              <bitWidth>12</bitWidth>
            </field>
            <field>
              <name>DACC2DHR</name>
              <bitOffset>16</bitOffset>
              <bitWidth>12</bitWidth>
            </field>
          </fields>
        </register>
        <register>
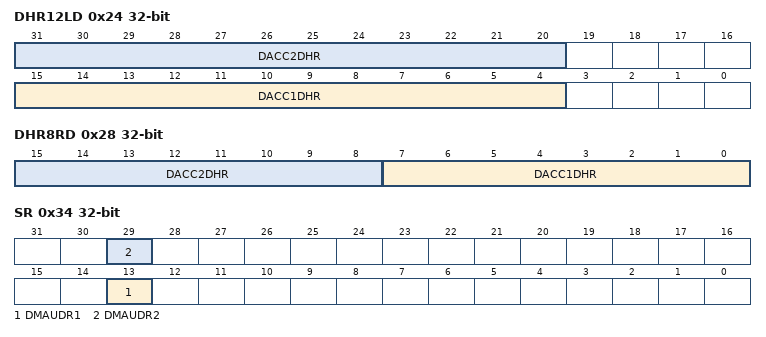
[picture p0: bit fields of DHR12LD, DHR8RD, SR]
          <name>DHR12LD</name>
          <addressOffset>0x24</addressOffset>
          <size>0x20</size>
          <fields>
            <field>
              <name>DACC1DHR</name>
              <bitOffset>4</bitOffset>
              <bitWidth>12</bitWidth>
            </field>
            <field>
              <name>DACC2DHR</name>
              <bitOffset>20</bitOffset>
              <bitWidth>12</bitWidth>
            </field>
          </fields>
        </register>
        <register>
          <name>DHR8RD</name>
          <addressOffset>0x28</addressOffset>
          <size>0x20</size>
          <fields>
            <field>
              <name>DACC1DHR</name>
              <bitOffset>0</bitOffset>
              <bitWidth>8</bitWidth>
            </field>
            <field>
              <name>DACC2DHR</name>
              <bitOffset>8</bitOffset>
              <bitWidth>8</bitWidth>
            </field>
          </fields>
        </register>
        <register>
          <name>DOR1</name>
          <addressOffset>0x2c</addressOffset>
          <size>0x20</size>
          <fields>
            <field>
              <name>DACC1DOR</name>
              <bitOffset>0</bitOffset>
              <bitWidth>12</bitWidth>
            </field>
          </fields>
        </register>
        <register>
          <name>DOR2</name>
          <addressOffset>0x30</addressOffset>
          <size>0x20</size>
          <fields>
            <field>
              <name>DACC2DOR</name>
              <bitOffset>0</bitOffset>
              <bitWidth>12</bitWidth>
            </field>
          </fields>
        </register>
        <register>
          <name>SR</name>
          <addressOffset>0x34</addressOffset>
          <size>0x20</size>
          <fields>
            <field>
              <name>DMAUDR1</name>
              <bitOffset>13</bitOffset>
              <bitWidth>1</bitWidth>
            </field>
            <field>
              <name>DMAUDR2</name>
              <bitOffset>29</bitOffset>
              <bitWidth>1</bitWidth>
            </field>
          </fields>
        </register>
      </registers>
    </peripheral>
    <peripheral>
      <name>UART7</name>
      <baseAddress>0x40007800</baseAddress>
      <registers>
        <register>
          <name>CR1</name>
          <addressOffset>0x0</addressOffset>
          <size>0x20</size>
          <fields>
            <field>
              <name>UE</name>
              <bitOffset>0</bitOffset>
              <bitWidth>1</bitWidth>
            </field>
            <field>
              <name>UESM</name>
              <bitOffset>1</bitOffset>
              <bitWidth>1</bitWidth>
            </field>
            <field>
              <name>RE</name>
              <bitOffset>2</bitOffset>
              <bitWidth>1</bitWidth>
            </field>
            <field>
              <name>TE</name>
              <bitOffset>3</bitOffset>
              <bitWidth>1</bitWidth>
            </field>
            <field>
              <name>IDLEIE</name>
              <bitOffset>4</bitOffset>
              <bitWidth>1</bitWidth>
            </field>
            <field>
              <name>RXNEIE</name>
              <bitOffset>5</bitOffset>
              <bitWidth>1</bitWidth>
            </field>
            <field>
              <name>TCIE</name>
              <bitOffset>6</bitOffset>
              <bitWidth>1</bitWidth>
            </field>
            <field>
              <name>TXEIE</name>
              <bitOffset>7</bitOffset>
              <bitWidth>1</bitWidth>
            </field>
            <field>
              <name>PEIE</name>
              <bitOffset>8</bitOffset>
              <bitWidth>1</bitWidth>
            </field>
            <field>
              <name>PS</name>
              <bitOffset>9</bitOffset>
              <bitWidth>1</bitWidth>
            </field>
            <field>
              <name>PCE</name>
              <bitOffset>10</bitOffset>
              <bitWidth>1</bitWidth>
            </field>
            <field>
              <name>WAKE</name>
              <bitOffset>11</bitOffset>
              <bitWidth>1</bitWidth>
            </field>
            <field>
              <name>M</name>
              <bitOffset>12</bitOffset>
              <bitWidth>17</bitWidth>
            </field>
            <field>
              <name>MME</name>
              <bitOffset>13</bitOffset>
              <bitWidth>1</bitWidth>
            </field>
            <field>
              <name>CMIE</name>
              <bitOffset>14</bitOffset>
              <bitWidth>1</bitWidth>
            </field>
            <field>
              <name>OVER8</name>
              <bitOffset>15</bitOffset>
              <bitWidth>1</bitWidth>
            </field>
            <field>
              <name>DEDT</name>
              <bitOffset>16</bitOffset>
              <bitWidth>5</bitWidth>
            </field>
            <field>
              <name>DEAT</name>
              <bitOffset>21</bitOffset>
              <bitWidth>5</bitWidth>
            </field>
            <field>
              <name>RTOIE</name>
              <bitOffset>26</bitOffset>
              <bitWidth>1</bitWidth>
            </field>
            <field>
              <name>EOBIE</name>
              <bitOffset>27</bitOffset>
              <bitWidth>1</bitWidth>
            </field>
          </fields>
        </register>
        <register>
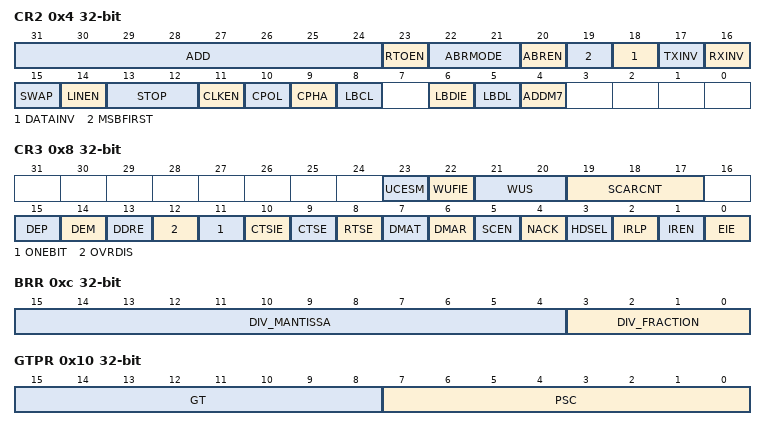
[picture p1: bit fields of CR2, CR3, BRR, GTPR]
          <name>CR2</name>
          <addressOffset>0x4</addressOffset>
          <size>0x20</size>
          <fields>
            <field>
              <name>ADDM7</name>
              <bitOffset>4</bitOffset>
              <bitWidth>1</bitWidth>
            </field>
            <field>
              <name>LBDL</name>
              <bitOffset>5</bitOffset>
              <bitWidth>1</bitWidth>
            </field>
            <field>
              <name>LBDIE</name>
              <bitOffset>6</bitOffset>
              <bitWidth>1</bitWidth>
            </field>
            <field>
              <name>LBCL</name>
              <bitOffset>8</bitOffset>
              <bitWidth>1</bitWidth>
            </field>
            <field>
              <name>CPHA</name>
              <bitOffset>9</bitOffset>
              <bitWidth>1</bitWidth>
            </field>
            <field>
              <name>CPOL</name>
              <bitOffset>10</bitOffset>
              <bitWidth>1</bitWidth>
            </field>
            <field>
              <name>CLKEN</name>
              <bitOffset>11</bitOffset>
              <bitWidth>1</bitWidth>
            </field>
            <field>
              <name>STOP</name>
              <bitOffset>12</bitOffset>
              <bitWidth>2</bitWidth>
            </field>
            <field>
              <name>LINEN</name>
              <bitOffset>14</bitOffset>
              <bitWidth>1</bitWidth>
            </field>
            <field>
              <name>SWAP</name>
              <bitOffset>15</bitOffset>
              <bitWidth>1</bitWidth>
            </field>
            <field>
              <name>RXINV</name>
              <bitOffset>16</bitOffset>
              <bitWidth>1</bitWidth>
            </field>
            <field>
              <name>TXINV</name>
              <bitOffset>17</bitOffset>
              <bitWidth>1</bitWidth>
            </field>
            <field>
              <name>DATAINV</name>
              <bitOffset>18</bitOffset>
              <bitWidth>1</bitWidth>
            </field>
            <field>
              <name>MSBFIRST</name>
              <bitOffset>19</bitOffset>
              <bitWidth>1</bitWidth>
            </field>
            <field>
              <name>ABREN</name>
              <bitOffset>20</bitOffset>
              <bitWidth>1</bitWidth>
            </field>
            <field>
              <name>ABRMODE</name>
              <bitOffset>21</bitOffset>
              <bitWidth>2</bitWidth>
            </field>
            <field>
              <name>RTOEN</name>
              <bitOffset>23</bitOffset>
              <bitWidth>1</bitWidth>
            </field>
            <field>
              <name>ADD</name>
              <bitOffset>24</bitOffset>
              <bitWidth>8</bitWidth>
            </field>
          </fields>
        </register>
        <register>
          <name>CR3</name>
          <addressOffset>0x8</addressOffset>
          <size>0x20</size>
          <fields>
            <field>
              <name>EIE</name>
              <bitOffset>0</bitOffset>
              <bitWidth>1</bitWidth>
            </field>
            <field>
              <name>IREN</name>
              <bitOffset>1</bitOffset>
              <bitWidth>1</bitWidth>
            </field>
            <field>
              <name>IRLP</name>
              <bitOffset>2</bitOffset>
              <bitWidth>1</bitWidth>
            </field>
            <field>
              <name>HDSEL</name>
              <bitOffset>3</bitOffset>
              <bitWidth>1</bitWidth>
            </field>
            <field>
              <name>NACK</name>
              <bitOffset>4</bitOffset>
              <bitWidth>1</bitWidth>
            </field>
            <field>
              <name>SCEN</name>
              <bitOffset>5</bitOffset>
              <bitWidth>1</bitWidth>
            </field>
            <field>
              <name>DMAR</name>
              <bitOffset>6</bitOffset>
              <bitWidth>1</bitWidth>
            </field>
            <field>
              <name>DMAT</name>
              <bitOffset>7</bitOffset>
              <bitWidth>1</bitWidth>
            </field>
            <field>
              <name>RTSE</name>
              <bitOffset>8</bitOffset>
              <bitWidth>1</bitWidth>
            </field>
            <field>
              <name>CTSE</name>
              <bitOffset>9</bitOffset>
              <bitWidth>1</bitWidth>
            </field>
            <field>
              <name>CTSIE</name>
              <bitOffset>10</bitOffset>
              <bitWidth>1</bitWidth>
            </field>
            <field>
              <name>ONEBIT</name>
              <bitOffset>11</bitOffset>
              <bitWidth>1</bitWidth>
            </field>
            <field>
              <name>OVRDIS</name>
              <bitOffset>12</bitOffset>
              <bitWidth>1</bitWidth>
            </field>
            <field>
              <name>DDRE</name>
              <bitOffset>13</bitOffset>
              <bitWidth>1</bitWidth>
            </field>
            <field>
              <name>DEM</name>
              <bitOffset>14</bitOffset>
              <bitWidth>1</bitWidth>
            </field>
            <field>
              <name>DEP</name>
              <bitOffset>15</bitOffset>
              <bitWidth>1</bitWidth>
            </field>
            <field>
              <name>SCARCNT</name>
              <bitOffset>17</bitOffset>
              <bitWidth>3</bitWidth>
            </field>
            <field>
              <name>WUS</name>
              <bitOffset>20</bitOffset>
              <bitWidth>2</bitWidth>
            </field>
            <field>
              <name>WUFIE</name>
              <bitOffset>22</bitOffset>
              <bitWidth>1</bitWidth>
            </field>
            <field>
              <name>UCESM</name>
              <bitOffset>23</bitOffset>
              <bitWidth>1</bitWidth>
            </field>
          </fields>
        </register>
        <register>
          <name>BRR</name>
          <addressOffset>0xc</addressOffset>
          <size>0x20</size>
          <fields>
            <field>
              <name>DIV_FRACTION</name>
              <bitOffset>0</bitOffset>
              <bitWidth>4</bitWidth>
            </field>
            <field>
              <name>DIV_MANTISSA</name>
              <bitOffset>4</bitOffset>
              <bitWidth>12</bitWidth>
            </field>
          </fields>
        </register>
        <register>
          <name>GTPR</name>
          <addressOffset>0x10</addressOffset>
          <size>0x20</size>
          <fields>
            <field>
              <name>PSC</name>
              <bitOffset>0</bitOffset>
              <bitWidth>8</bitWidth>
            </field>
            <field>
              <name>GT</name>
              <bitOffset>8</bitOffset>
              <bitWidth>8</bitWidth>
            </field>
          </fields>
        </register>
        <register>
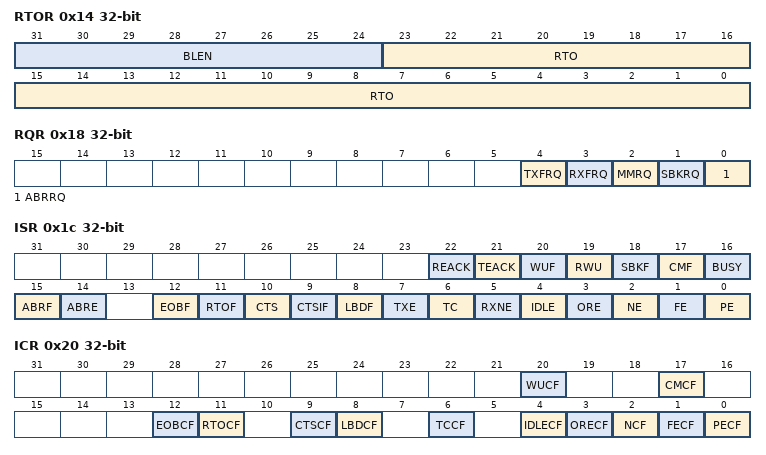
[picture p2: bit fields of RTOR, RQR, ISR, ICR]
          <name>RTOR</name>
          <addressOffset>0x14</addressOffset>
          <size>0x20</size>
          <fields>
            <field>
              <name>RTO</name>
              <bitOffset>0</bitOffset>
              <bitWidth>24</bitWidth>
            </field>
            <field>
              <name>BLEN</name>
              <bitOffset>24</bitOffset>
              <bitWidth>8</bitWidth>
            </field>
          </fields>
        </register>
        <register>
          <name>RQR</name>
          <addressOffset>0x18</addressOffset>
          <size>0x20</size>
          <fields>
            <field>
              <name>ABRRQ</name>
              <bitOffset>0</bitOffset>
              <bitWidth>1</bitWidth>
            </field>
            <field>
              <name>SBKRQ</name>
              <bitOffset>1</bitOffset>
              <bitWidth>1</bitWidth>
            </field>
            <field>
              <name>MMRQ</name>
              <bitOffset>2</bitOffset>
              <bitWidth>1</bitWidth>
            </field>
            <field>
              <name>RXFRQ</name>
              <bitOffset>3</bitOffset>
              <bitWidth>1</bitWidth>
            </field>
            <field>
              <name>TXFRQ</name>
              <bitOffset>4</bitOffset>
              <bitWidth>1</bitWidth>
            </field>
          </fields>
        </register>
        <register>
          <name>ISR</name>
          <addressOffset>0x1c</addressOffset>
          <size>0x20</size>
          <fields>
            <field>
              <name>PE</name>
              <bitOffset>0</bitOffset>
              <bitWidth>1</bitWidth>
            </field>
            <field>
              <name>FE</name>
              <bitOffset>1</bitOffset>
              <bitWidth>1</bitWidth>
            </field>
            <field>
              <name>NE</name>
              <bitOffset>2</bitOffset>
              <bitWidth>1</bitWidth>
            </field>
            <field>
              <name>ORE</name>
              <bitOffset>3</bitOffset>
              <bitWidth>1</bitWidth>
            </field>
            <field>
              <name>IDLE</name>
              <bitOffset>4</bitOffset>
              <bitWidth>1</bitWidth>
            </field>
            <field>
              <name>RXNE</name>
              <bitOffset>5</bitOffset>
              <bitWidth>1</bitWidth>
            </field>
            <field>
              <name>TC</name>
              <bitOffset>6</bitOffset>
              <bitWidth>1</bitWidth>
            </field>
            <field>
              <name>TXE</name>
              <bitOffset>7</bitOffset>
              <bitWidth>1</bitWidth>
            </field>
            <field>
              <name>LBDF</name>
              <bitOffset>8</bitOffset>
              <bitWidth>1</bitWidth>
            </field>
            <field>
              <name>CTSIF</name>
              <bitOffset>9</bitOffset>
              <bitWidth>1</bitWidth>
            </field>
            <field>
              <name>CTS</name>
              <bitOffset>10</bitOffset>
              <bitWidth>1</bitWidth>
            </field>
            <field>
              <name>RTOF</name>
              <bitOffset>11</bitOffset>
              <bitWidth>1</bitWidth>
            </field>
            <field>
              <name>EOBF</name>
              <bitOffset>12</bitOffset>
              <bitWidth>1</bitWidth>
            </field>
            <field>
              <name>ABRE</name>
              <bitOffset>14</bitOffset>
              <bitWidth>1</bitWidth>
            </field>
            <field>
              <name>ABRF</name>
              <bitOffset>15</bitOffset>
              <bitWidth>1</bitWidth>
            </field>
            <field>
              <name>BUSY</name>
              <bitOffset>16</bitOffset>
              <bitWidth>1</bitWidth>
            </field>
            <field>
              <name>CMF</name>
              <bitOffset>17</bitOffset>
              <bitWidth>1</bitWidth>
            </field>
            <field>
              <name>SBKF</name>
              <bitOffset>18</bitOffset>
              <bitWidth>1</bitWidth>
            </field>
            <field>
              <name>RWU</name>
              <bitOffset>19</bitOffset>
              <bitWidth>1</bitWidth>
            </field>
            <field>
              <name>WUF</name>
              <bitOffset>20</bitOffset>
              <bitWidth>1</bitWidth>
            </field>
            <field>
              <name>TEACK</name>
              <bitOffset>21</bitOffset>
              <bitWidth>1</bitWidth>
            </field>
            <field>
              <name>REACK</name>
              <bitOffset>22</bitOffset>
              <bitWidth>1</bitWidth>
            </field>
          </fields>
        </register>
        <register>
          <name>ICR</name>
          <addressOffset>0x20</addressOffset>
          <size>0x20</size>
          <fields>
            <field>
              <name>PECF</name>
              <bitOffset>0</bitOffset>
              <bitWidth>1</bitWidth>
            </field>
            <field>
              <name>FECF</name>
              <bitOffset>1</bitOffset>
              <bitWidth>1</bitWidth>
            </field>
            <field>
              <name>NCF</name>
              <bitOffset>2</bitOffset>
              <bitWidth>1</bitWidth>
            </field>
            <field>
              <name>ORECF</name>
              <bitOffset>3</bitOffset>
              <bitWidth>1</bitWidth>
            </field>
            <field>
              <name>IDLECF</name>
              <bitOffset>4</bitOffset>
              <bitWidth>1</bitWidth>
            </field>
            <field>
              <name>TCCF</name>
              <bitOffset>6</bitOffset>
              <bitWidth>1</bitWidth>
            </field>
            <field>
              <name>LBDCF</name>
              <bitOffset>8</bitOffset>
              <bitWidth>1</bitWidth>
            </field>
            <field>
              <name>CTSCF</name>
              <bitOffset>9</bitOffset>
              <bitWidth>1</bitWidth>
            </field>
            <field>
              <name>RTOCF</name>
              <bitOffset>11</bitOffset>
              <bitWidth>1</bitWidth>
            </field>
            <field>
              <name>EOBCF</name>
              <bitOffset>12</bitOffset>
              <bitWidth>1</bitWidth>
            </field>
            <field>
              <name>CMCF</name>
              <bitOffset>17</bitOffset>
              <bitWidth>1</bitWidth>
            </field>
            <field>
              <name>WUCF</name>
              <bitOffset>20</bitOffset>
              <bitWidth>1</bitWidth>
            </field>
          </fields>
        </register>
        <register>
          <name>RDR</name>
          <addressOffset>0x24</addressOffset>
          <size>0x20</size>
          <fields>
            <field>
              <name>RDR</name>
              <bitOffset>0</bitOffset>
              <bitWidth>9</bitWidth>
            </field>
          </fields>
        </register>
        <register>
          <name>TDR</name>
          <addressOffset>0x28</addressOffset>
          <size>0x20</size>
          <fields>
            <field>
              <name>TDR</name>
              <bitOffset>0</bitOffset>
              <bitWidth>9</bitWidth>
            </field>
          </fields>
        </register>
      </registers>
    </peripheral>
    <peripheral>
      <name>UART8</name>
      <baseAddress>0x40007c00</baseAddress>
      <registers>
        <register>
          <name>CR1</name>
          <addressOffset>0x0</addressOffset>
          <size>0x20</size>
          <fields>
            <field>
              <name>UE</name>
              <bitOffset>0</bitOffset>
              <bitWidth>1</bitWidth>
            </field>
            <field>
              <name>UESM</name>
              <bitOffset>1</bitOffset>
              <bitWidth>1</bitWidth>
            </field>
            <field>
              <name>RE</name>
              <bitOffset>2</bitOffset>
              <bitWidth>1</bitWidth>
            </field>
            <field>
              <name>TE</name>
              <bitOffset>3</bitOffset>
              <bitWidth>1</bitWidth>
            </field>
            <field>
              <name>IDLEIE</name>
              <bitOffset>4</bitOffset>
              <bitWidth>1</bitWidth>
            </field>
            <field>
              <name>RXNEIE</name>
              <bitOffset>5</bitOffset>
              <bitWidth>1</bitWidth>
            </field>
            <field>
              <name>TCIE</name>
              <bitOffset>6</bitOffset>
              <bitWidth>1</bitWidth>
            </field>
            <field>
              <name>TXEIE</name>
              <bitOffset>7</bitOffset>
              <bitWidth>1</bitWidth>
            </field>
            <field>
              <name>PEIE</name>
              <bitOffset>8</bitOffset>
              <bitWidth>1</bitWidth>
            </field>
            <field>
              <name>PS</name>
              <bitOffset>9</bitOffset>
              <bitWidth>1</bitWidth>
            </field>
            <field>
              <name>PCE</name>
              <bitOffset>10</bitOffset>
              <bitWidth>1</bitWidth>
            </field>
            <field>
              <name>WAKE</name>
              <bitOffset>11</bitOffset>
              <bitWidth>1</bitWidth>
            </field>
            <field>
              <name>M</name>
              <bitOffset>12</bitOffset>
              <bitWidth>17</bitWidth>
            </field>
            <field>
              <name>MME</name>
              <bitOffset>13</bitOffset>
              <bitWidth>1</bitWidth>
            </field>
            <field>
              <name>CMIE</name>
              <bitOffset>14</bitOffset>
              <bitWidth>1</bitWidth>
            </field>
            <field>
              <name>OVER8</name>
              <bitOffset>15</bitOffset>
              <bitWidth>1</bitWidth>
            </field>
            <field>
              <name>DEDT</name>
              <bitOffset>16</bitOffset>
              <bitWidth>5</bitWidth>
            </field>
            <field>
              <name>DEAT</name>
              <bitOffset>21</bitOffset>
              <bitWidth>5</bitWidth>
            </field>
            <field>
              <name>RTOIE</name>
              <bitOffset>26</bitOffset>
              <bitWidth>1</bitWidth>
            </field>
            <field>
              <name>EOBIE</name>
              <bitOffset>27</bitOffset>
              <bitWidth>1</bitWidth>
            </field>
          </fields>
        </register>
        <register>
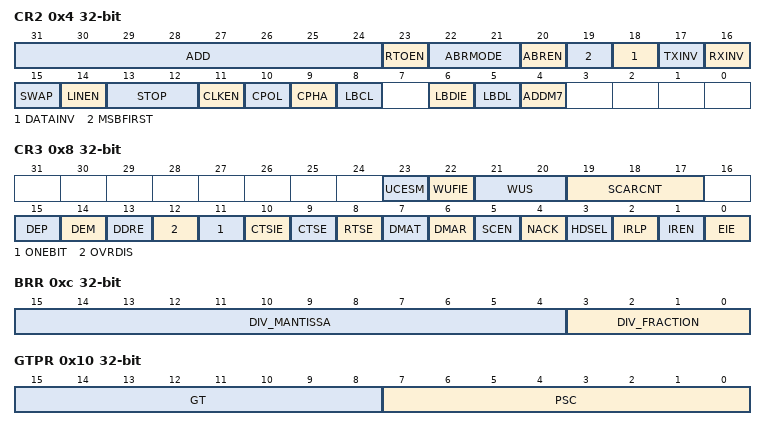
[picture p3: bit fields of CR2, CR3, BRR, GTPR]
          <name>CR2</name>
          <addressOffset>0x4</addressOffset>
          <size>0x20</size>
          <fields>
            <field>
              <name>ADDM7</name>
              <bitOffset>4</bitOffset>
              <bitWidth>1</bitWidth>
            </field>
            <field>
              <name>LBDL</name>
              <bitOffset>5</bitOffset>
              <bitWidth>1</bitWidth>
            </field>
            <field>
              <name>LBDIE</name>
              <bitOffset>6</bitOffset>
              <bitWidth>1</bitWidth>
            </field>
            <field>
              <name>LBCL</name>
              <bitOffset>8</bitOffset>
              <bitWidth>1</bitWidth>
            </field>
            <field>
              <name>CPHA</name>
              <bitOffset>9</bitOffset>
              <bitWidth>1</bitWidth>
            </field>
            <field>
              <name>CPOL</name>
              <bitOffset>10</bitOffset>
              <bitWidth>1</bitWidth>
            </field>
            <field>
              <name>CLKEN</name>
              <bitOffset>11</bitOffset>
              <bitWidth>1</bitWidth>
            </field>
            <field>
              <name>STOP</name>
              <bitOffset>12</bitOffset>
              <bitWidth>2</bitWidth>
            </field>
            <field>
              <name>LINEN</name>
              <bitOffset>14</bitOffset>
              <bitWidth>1</bitWidth>
            </field>
            <field>
              <name>SWAP</name>
              <bitOffset>15</bitOffset>
              <bitWidth>1</bitWidth>
            </field>
            <field>
              <name>RXINV</name>
              <bitOffset>16</bitOffset>
              <bitWidth>1</bitWidth>
            </field>
            <field>
              <name>TXINV</name>
              <bitOffset>17</bitOffset>
              <bitWidth>1</bitWidth>
            </field>
            <field>
              <name>DATAINV</name>
              <bitOffset>18</bitOffset>
              <bitWidth>1</bitWidth>
            </field>
            <field>
              <name>MSBFIRST</name>
              <bitOffset>19</bitOffset>
              <bitWidth>1</bitWidth>
            </field>
            <field>
              <name>ABREN</name>
              <bitOffset>20</bitOffset>
              <bitWidth>1</bitWidth>
            </field>
            <field>
              <name>ABRMODE</name>
              <bitOffset>21</bitOffset>
              <bitWidth>2</bitWidth>
            </field>
            <field>
              <name>RTOEN</name>
              <bitOffset>23</bitOffset>
              <bitWidth>1</bitWidth>
            </field>
            <field>
              <name>ADD</name>
              <bitOffset>24</bitOffset>
              <bitWidth>8</bitWidth>
            </field>
          </fields>
        </register>
        <register>
          <name>CR3</name>
          <addressOffset>0x8</addressOffset>
          <size>0x20</size>
          <fields>
            <field>
              <name>EIE</name>
              <bitOffset>0</bitOffset>
              <bitWidth>1</bitWidth>
            </field>
            <field>
              <name>IREN</name>
              <bitOffset>1</bitOffset>
              <bitWidth>1</bitWidth>
            </field>
            <field>
              <name>IRLP</name>
              <bitOffset>2</bitOffset>
              <bitWidth>1</bitWidth>
            </field>
            <field>
              <name>HDSEL</name>
              <bitOffset>3</bitOffset>
              <bitWidth>1</bitWidth>
            </field>
            <field>
              <name>NACK</name>
              <bitOffset>4</bitOffset>
              <bitWidth>1</bitWidth>
            </field>
            <field>
              <name>SCEN</name>
              <bitOffset>5</bitOffset>
              <bitWidth>1</bitWidth>
            </field>
            <field>
              <name>DMAR</name>
              <bitOffset>6</bitOffset>
              <bitWidth>1</bitWidth>
            </field>
            <field>
              <name>DMAT</name>
              <bitOffset>7</bitOffset>
              <bitWidth>1</bitWidth>
            </field>
            <field>
              <name>RTSE</name>
              <bitOffset>8</bitOffset>
              <bitWidth>1</bitWidth>
            </field>
            <field>
              <name>CTSE</name>
              <bitOffset>9</bitOffset>
              <bitWidth>1</bitWidth>
            </field>
            <field>
              <name>CTSIE</name>
              <bitOffset>10</bitOffset>
              <bitWidth>1</bitWidth>
            </field>
            <field>
              <name>ONEBIT</name>
              <bitOffset>11</bitOffset>
              <bitWidth>1</bitWidth>
            </field>
            <field>
              <name>OVRDIS</name>
              <bitOffset>12</bitOffset>
              <bitWidth>1</bitWidth>
            </field>
            <field>
              <name>DDRE</name>
              <bitOffset>13</bitOffset>
              <bitWidth>1</bitWidth>
            </field>
            <field>
              <name>DEM</name>
              <bitOffset>14</bitOffset>
              <bitWidth>1</bitWidth>
            </field>
            <field>
              <name>DEP</name>
              <bitOffset>15</bitOffset>
              <bitWidth>1</bitWidth>
            </field>
            <field>
              <name>SCARCNT</name>
              <bitOffset>17</bitOffset>
              <bitWidth>3</bitWidth>
            </field>
            <field>
              <name>WUS</name>
              <bitOffset>20</bitOffset>
              <bitWidth>2</bitWidth>
            </field>
            <field>
              <name>WUFIE</name>
              <bitOffset>22</bitOffset>
              <bitWidth>1</bitWidth>
            </field>
            <field>
              <name>UCESM</name>
              <bitOffset>23</bitOffset>
              <bitWidth>1</bitWidth>
            </field>
          </fields>
        </register>
        <register>
          <name>BRR</name>
          <addressOffset>0xc</addressOffset>
          <size>0x20</size>
          <fields>
            <field>
              <name>DIV_FRACTION</name>
              <bitOffset>0</bitOffset>
              <bitWidth>4</bitWidth>
            </field>
            <field>
              <name>DIV_MANTISSA</name>
              <bitOffset>4</bitOffset>
              <bitWidth>12</bitWidth>
            </field>
          </fields>
        </register>
        <register>
          <name>GTPR</name>
          <addressOffset>0x10</addressOffset>
          <size>0x20</size>
          <fields>
            <field>
              <name>PSC</name>
              <bitOffset>0</bitOffset>
              <bitWidth>8</bitWidth>
            </field>
            <field>
              <name>GT</name>
              <bitOffset>8</bitOffset>
              <bitWidth>8</bitWidth>
            </field>
          </fields>
        </register>
        <register>
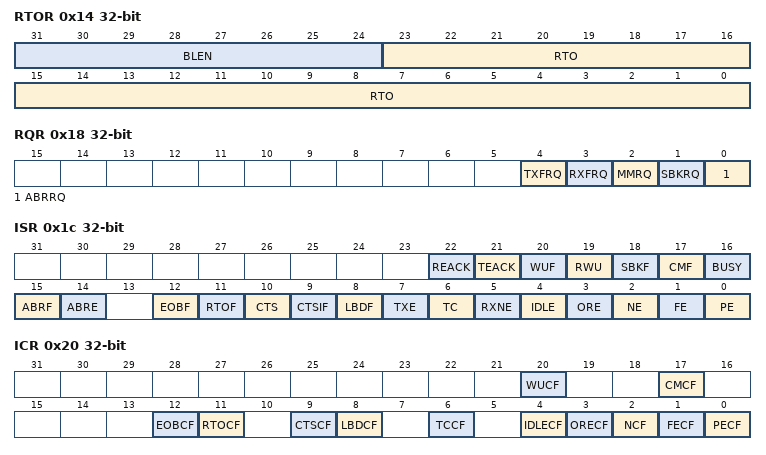
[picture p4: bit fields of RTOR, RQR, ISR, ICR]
          <name>RTOR</name>
          <addressOffset>0x14</addressOffset>
          <size>0x20</size>
          <fields>
            <field>
              <name>RTO</name>
              <bitOffset>0</bitOffset>
              <bitWidth>24</bitWidth>
            </field>
            <field>
              <name>BLEN</name>
              <bitOffset>24</bitOffset>
              <bitWidth>8</bitWidth>
            </field>
          </fields>
        </register>
        <register>
          <name>RQR</name>
          <addressOffset>0x18</addressOffset>
          <size>0x20</size>
          <fields>
            <field>
              <name>ABRRQ</name>
              <bitOffset>0</bitOffset>
              <bitWidth>1</bitWidth>
            </field>
            <field>
              <name>SBKRQ</name>
              <bitOffset>1</bitOffset>
              <bitWidth>1</bitWidth>
            </field>
            <field>
              <name>MMRQ</name>
              <bitOffset>2</bitOffset>
              <bitWidth>1</bitWidth>
            </field>
            <field>
              <name>RXFRQ</name>
              <bitOffset>3</bitOffset>
              <bitWidth>1</bitWidth>
            </field>
            <field>
              <name>TXFRQ</name>
              <bitOffset>4</bitOffset>
              <bitWidth>1</bitWidth>
            </field>
          </fields>
        </register>
        <register>
          <name>ISR</name>
          <addressOffset>0x1c</addressOffset>
          <size>0x20</size>
          <fields>
            <field>
              <name>PE</name>
              <bitOffset>0</bitOffset>
              <bitWidth>1</bitWidth>
            </field>
            <field>
              <name>FE</name>
              <bitOffset>1</bitOffset>
              <bitWidth>1</bitWidth>
            </field>
            <field>
              <name>NE</name>
              <bitOffset>2</bitOffset>
              <bitWidth>1</bitWidth>
            </field>
            <field>
              <name>ORE</name>
              <bitOffset>3</bitOffset>
              <bitWidth>1</bitWidth>
            </field>
            <field>
              <name>IDLE</name>
              <bitOffset>4</bitOffset>
              <bitWidth>1</bitWidth>
            </field>
            <field>
              <name>RXNE</name>
              <bitOffset>5</bitOffset>
              <bitWidth>1</bitWidth>
            </field>
            <field>
              <name>TC</name>
              <bitOffset>6</bitOffset>
              <bitWidth>1</bitWidth>
            </field>
            <field>
              <name>TXE</name>
              <bitOffset>7</bitOffset>
              <bitWidth>1</bitWidth>
            </field>
            <field>
              <name>LBDF</name>
              <bitOffset>8</bitOffset>
              <bitWidth>1</bitWidth>
            </field>
            <field>
              <name>CTSIF</name>
              <bitOffset>9</bitOffset>
              <bitWidth>1</bitWidth>
            </field>
            <field>
              <name>CTS</name>
              <bitOffset>10</bitOffset>
              <bitWidth>1</bitWidth>
            </field>
            <field>
              <name>RTOF</name>
              <bitOffset>11</bitOffset>
              <bitWidth>1</bitWidth>
            </field>
            <field>
              <name>EOBF</name>
              <bitOffset>12</bitOffset>
              <bitWidth>1</bitWidth>
            </field>
            <field>
              <name>ABRE</name>
              <bitOffset>14</bitOffset>
              <bitWidth>1</bitWidth>
            </field>
            <field>
              <name>ABRF</name>
              <bitOffset>15</bitOffset>
              <bitWidth>1</bitWidth>
            </field>
            <field>
              <name>BUSY</name>
              <bitOffset>16</bitOffset>
              <bitWidth>1</bitWidth>
            </field>
            <field>
              <name>CMF</name>
              <bitOffset>17</bitOffset>
              <bitWidth>1</bitWidth>
            </field>
            <field>
              <name>SBKF</name>
              <bitOffset>18</bitOffset>
              <bitWidth>1</bitWidth>
            </field>
            <field>
              <name>RWU</name>
              <bitOffset>19</bitOffset>
              <bitWidth>1</bitWidth>
            </field>
            <field>
              <name>WUF</name>
              <bitOffset>20</bitOffset>
              <bitWidth>1</bitWidth>
            </field>
            <field>
              <name>TEACK</name>
              <bitOffset>21</bitOffset>
              <bitWidth>1</bitWidth>
            </field>
            <field>
              <name>REACK</name>
              <bitOffset>22</bitOffset>
              <bitWidth>1</bitWidth>
            </field>
          </fields>
        </register>
        <register>
          <name>ICR</name>
          <addressOffset>0x20</addressOffset>
          <size>0x20</size>
          <fields>
            <field>
              <name>PECF</name>
              <bitOffset>0</bitOffset>
              <bitWidth>1</bitWidth>
            </field>
            <field>
              <name>FECF</name>
              <bitOffset>1</bitOffset>
              <bitWidth>1</bitWidth>
            </field>
            <field>
              <name>NCF</name>
              <bitOffset>2</bitOffset>
              <bitWidth>1</bitWidth>
            </field>
            <field>
              <name>ORECF</name>
              <bitOffset>3</bitOffset>
              <bitWidth>1</bitWidth>
            </field>
            <field>
              <name>IDLECF</name>
              <bitOffset>4</bitOffset>
              <bitWidth>1</bitWidth>
            </field>
            <field>
              <name>TCCF</name>
              <bitOffset>6</bitOffset>
              <bitWidth>1</bitWidth>
            </field>
            <field>
              <name>LBDCF</name>
              <bitOffset>8</bitOffset>
              <bitWidth>1</bitWidth>
            </field>
            <field>
              <name>CTSCF</name>
              <bitOffset>9</bitOffset>
              <bitWidth>1</bitWidth>
            </field>
            <field>
              <name>RTOCF</name>
              <bitOffset>11</bitOffset>
              <bitWidth>1</bitWidth>
            </field>
            <field>
              <name>EOBCF</name>
              <bitOffset>12</bitOffset>
              <bitWidth>1</bitWidth>
            </field>
            <field>
              <name>CMCF</name>
              <bitOffset>17</bitOffset>
              <bitWidth>1</bitWidth>
            </field>
            <field>
              <name>WUCF</name>
              <bitOffset>20</bitOffset>
              <bitWidth>1</bitWidth>
            </field>
          </fields>
        </register>
        <register>
          <name>RDR</name>
          <addressOffset>0x24</addressOffset>
          <size>0x20</size>
          <fields>
            <field>
              <name>RDR</name>
              <bitOffset>0</bitOffset>
              <bitWidth>9</bitWidth>
            </field>
          </fields>
        </register>
        <register>
          <name>TDR</name>
          <addressOffset>0x28</addressOffset>
          <size>0x20</size>
          <fields>
            <field>
              <name>TDR</name>
              <bitOffset>0</bitOffset>
              <bitWidth>9</bitWidth>
            </field>
          </fields>
        </register>
      </registers>
    </peripheral>
    <peripheral>
      <name>TIM1</name>
      <baseAddress>0x40010000</baseAddress>
      <registers>
        <register>
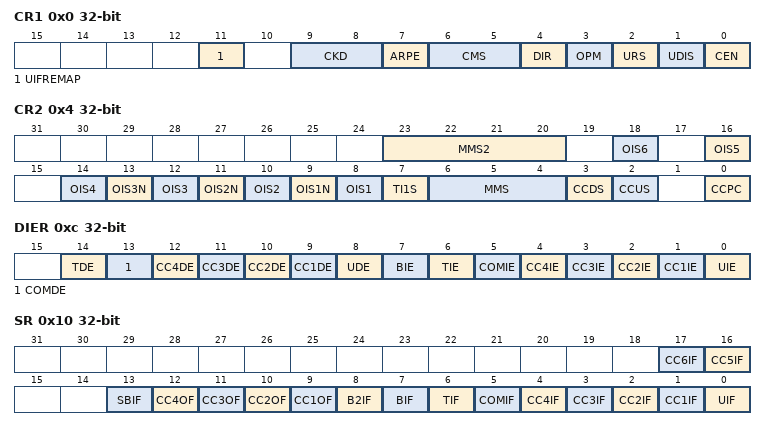
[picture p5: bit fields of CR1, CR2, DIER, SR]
          <name>CR1</name>
          <addressOffset>0x0</addressOffset>
          <size>0x20</size>
          <fields>
            <field>
              <name>CEN</name>
              <bitOffset>0</bitOffset>
              <bitWidth>1</bitWidth>
            </field>
            <field>
              <name>UDIS</name>
              <bitOffset>1</bitOffset>
              <bitWidth>1</bitWidth>
            </field>
            <field>
              <name>URS</name>
              <bitOffset>2</bitOffset>
              <bitWidth>1</bitWidth>
            </field>
            <field>
              <name>OPM</name>
              <bitOffset>3</bitOffset>
              <bitWidth>1</bitWidth>
            </field>
            <field>
              <name>DIR</name>
              <bitOffset>4</bitOffset>
              <bitWidth>1</bitWidth>
            </field>
            <field>
              <name>CMS</name>
              <bitOffset>5</bitOffset>
              <bitWidth>2</bitWidth>
            </field>
            <field>
              <name>ARPE</name>
              <bitOffset>7</bitOffset>
              <bitWidth>1</bitWidth>
            </field>
            <field>
              <name>CKD</name>
              <bitOffset>8</bitOffset>
              <bitWidth>2</bitWidth>
            </field>
            <field>
              <name>UIFREMAP</name>
              <bitOffset>11</bitOffset>
              <bitWidth>1</bitWidth>
            </field>
          </fields>
        </register>
        <register>
          <name>CR2</name>
          <addressOffset>0x4</addressOffset>
          <size>0x20</size>
          <fields>
            <field>
              <name>CCPC</name>
              <bitOffset>0</bitOffset>
              <bitWidth>1</bitWidth>
            </field>
            <field>
              <name>CCUS</name>
              <bitOffset>2</bitOffset>
              <bitWidth>1</bitWidth>
            </field>
            <field>
              <name>CCDS</name>
              <bitOffset>3</bitOffset>
              <bitWidth>1</bitWidth>
            </field>
            <field>
              <name>MMS</name>
              <bitOffset>4</bitOffset>
              <bitWidth>3</bitWidth>
            </field>
            <field>
              <name>TI1S</name>
              <bitOffset>7</bitOffset>
              <bitWidth>1</bitWidth>
            </field>
            <field>
              <name>OIS1</name>
              <bitOffset>8</bitOffset>
              <bitWidth>1</bitWidth>
            </field>
            <field>
              <name>OIS1N</name>
              <bitOffset>9</bitOffset>
              <bitWidth>1</bitWidth>
            </field>
            <field>
              <name>OIS2</name>
              <bitOffset>10</bitOffset>
              <bitWidth>1</bitWidth>
            </field>
            <field>
              <name>OIS2N</name>
              <bitOffset>11</bitOffset>
              <bitWidth>1</bitWidth>
            </field>
            <field>
              <name>OIS3</name>
              <bitOffset>12</bitOffset>
              <bitWidth>1</bitWidth>
            </field>
            <field>
              <name>OIS3N</name>
              <bitOffset>13</bitOffset>
              <bitWidth>1</bitWidth>
            </field>
            <field>
              <name>OIS4</name>
              <bitOffset>14</bitOffset>
              <bitWidth>1</bitWidth>
            </field>
            <field>
              <name>OIS5</name>
              <bitOffset>16</bitOffset>
              <bitWidth>1</bitWidth>
            </field>
            <field>
              <name>OIS6</name>
              <bitOffset>18</bitOffset>
              <bitWidth>1</bitWidth>
            </field>
            <field>
              <name>MMS2</name>
              <bitOffset>20</bitOffset>
              <bitWidth>4</bitWidth>
            </field>
          </fields>
        </register>
        <register>
          <name>SMCR</name>
          <addressOffset>0x8</addressOffset>
          <size>0x20</size>
          <fields>
            <field>
              <name>SMS</name>
              <bitOffset>0</bitOffset>
              <bitWidth>17</bitWidth>
            </field>
            <field>
              <name>TS</name>
              <bitOffset>4</bitOffset>
              <bitWidth>3</bitWidth>
            </field>
            <field>
              <name>MSM</name>
              <bitOffset>7</bitOffset>
              <bitWidth>1</bitWidth>
            </field>
            <field>
              <name>ETF</name>
              <bitOffset>8</bitOffset>
              <bitWidth>4</bitWidth>
            </field>
            <field>
              <name>ETPS</name>
              <bitOffset>12</bitOffset>
              <bitWidth>2</bitWidth>
            </field>
            <field>
              <name>ECE</name>
              <bitOffset>14</bitOffset>
              <bitWidth>1</bitWidth>
            </field>
            <field>
              <name>ETP</name>
              <bitOffset>15</bitOffset>
              <bitWidth>1</bitWidth>
            </field>
          </fields>
        </register>
        <register>
          <name>DIER</name>
          <addressOffset>0xc</addressOffset>
          <size>0x20</size>
          <fields>
            <field>
              <name>UIE</name>
              <bitOffset>0</bitOffset>
              <bitWidth>1</bitWidth>
            </field>
            <field>
              <name>CC1IE</name>
              <bitOffset>1</bitOffset>
              <bitWidth>1</bitWidth>
            </field>
            <field>
              <name>CC2IE</name>
              <bitOffset>2</bitOffset>
              <bitWidth>1</bitWidth>
            </field>
            <field>
              <name>CC3IE</name>
              <bitOffset>3</bitOffset>
              <bitWidth>1</bitWidth>
            </field>
            <field>
              <name>CC4IE</name>
              <bitOffset>4</bitOffset>
              <bitWidth>1</bitWidth>
            </field>
            <field>
              <name>COMIE</name>
              <bitOffset>5</bitOffset>
              <bitWidth>1</bitWidth>
            </field>
            <field>
              <name>TIE</name>
              <bitOffset>6</bitOffset>
              <bitWidth>1</bitWidth>
            </field>
            <field>
              <name>BIE</name>
              <bitOffset>7</bitOffset>
              <bitWidth>1</bitWidth>
            </field>
            <field>
              <name>UDE</name>
              <bitOffset>8</bitOffset>
              <bitWidth>1</bitWidth>
            </field>
            <field>
              <name>CC1DE</name>
              <bitOffset>9</bitOffset>
              <bitWidth>1</bitWidth>
            </field>
            <field>
              <name>CC2DE</name>
              <bitOffset>10</bitOffset>
              <bitWidth>1</bitWidth>
            </field>
            <field>
              <name>CC3DE</name>
              <bitOffset>11</bitOffset>
              <bitWidth>1</bitWidth>
            </field>
            <field>
              <name>CC4DE</name>
              <bitOffset>12</bitOffset>
              <bitWidth>1</bitWidth>
            </field>
            <field>
              <name>COMDE</name>
              <bitOffset>13</bitOffset>
              <bitWidth>1</bitWidth>
            </field>
            <field>
              <name>TDE</name>
              <bitOffset>14</bitOffset>
              <bitWidth>1</bitWidth>
            </field>
          </fields>
        </register>
        <register>
          <name>SR</name>
          <addressOffset>0x10</addressOffset>
          <size>0x20</size>
          <fields>
            <field>
              <name>UIF</name>
              <bitOffset>0</bitOffset>
              <bitWidth>1</bitWidth>
            </field>
            <field>
              <name>CC1IF</name>
              <bitOffset>1</bitOffset>
              <bitWidth>1</bitWidth>
            </field>
            <field>
              <name>CC2IF</name>
              <bitOffset>2</bitOffset>
              <bitWidth>1</bitWidth>
            </field>
            <field>
              <name>CC3IF</name>
              <bitOffset>3</bitOffset>
              <bitWidth>1</bitWidth>
            </field>
            <field>
              <name>CC4IF</name>
              <bitOffset>4</bitOffset>
              <bitWidth>1</bitWidth>
            </field>
            <field>
              <name>COMIF</name>
              <bitOffset>5</bitOffset>
              <bitWidth>1</bitWidth>
            </field>
            <field>
              <name>TIF</name>
              <bitOffset>6</bitOffset>
              <bitWidth>1</bitWidth>
            </field>
            <field>
              <name>BIF</name>
              <bitOffset>7</bitOffset>
              <bitWidth>1</bitWidth>
            </field>
            <field>
              <name>B2IF</name>
              <bitOffset>8</bitOffset>
              <bitWidth>1</bitWidth>
            </field>
            <field>
              <name>CC1OF</name>
              <bitOffset>9</bitOffset>
              <bitWidth>1</bitWidth>
            </field>
            <field>
              <name>CC2OF</name>
              <bitOffset>10</bitOffset>
              <bitWidth>1</bitWidth>
            </field>
            <field>
              <name>CC3OF</name>
              <bitOffset>11</bitOffset>
              <bitWidth>1</bitWidth>
            </field>
            <field>
              <name>CC4OF</name>
              <bitOffset>12</bitOffset>
              <bitWidth>1</bitWidth>
            </field>
            <field>
              <name>SBIF</name>
              <bitOffset>13</bitOffset>
              <bitWidth>1</bitWidth>
            </field>
            <field>
              <name>CC5IF</name>
              <bitOffset>16</bitOffset>
              <bitWidth>1</bitWidth>
            </field>
            <field>
              <name>CC6IF</name>
              <bitOffset>17</bitOffset>
              <bitWidth>1</bitWidth>
            </field>
          </fields>
        </register>
        <register>
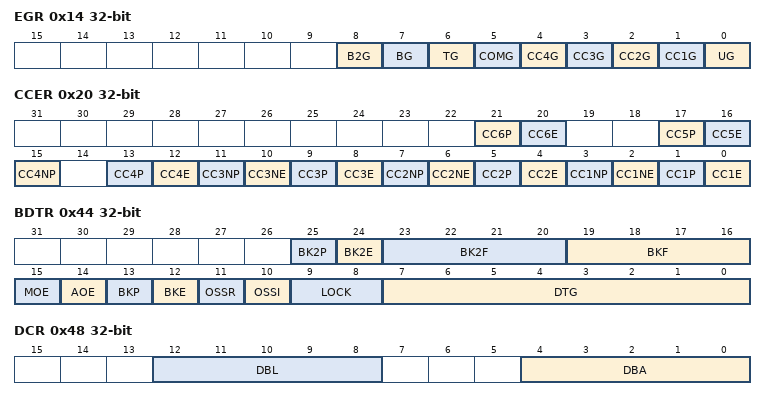
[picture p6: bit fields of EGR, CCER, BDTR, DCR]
          <name>EGR</name>
          <addressOffset>0x14</addressOffset>
          <size>0x20</size>
          <fields>
            <field>
              <name>UG</name>
              <bitOffset>0</bitOffset>
              <bitWidth>1</bitWidth>
            </field>
            <field>
              <name>CC1G</name>
              <bitOffset>1</bitOffset>
              <bitWidth>1</bitWidth>
            </field>
            <field>
              <name>CC2G</name>
              <bitOffset>2</bitOffset>
              <bitWidth>1</bitWidth>
            </field>
            <field>
              <name>CC3G</name>
              <bitOffset>3</bitOffset>
              <bitWidth>1</bitWidth>
            </field>
            <field>
              <name>CC4G</name>
              <bitOffset>4</bitOffset>
              <bitWidth>1</bitWidth>
            </field>
            <field>
              <name>COMG</name>
              <bitOffset>5</bitOffset>
              <bitWidth>1</bitWidth>
            </field>
            <field>
              <name>TG</name>
              <bitOffset>6</bitOffset>
              <bitWidth>1</bitWidth>
            </field>
            <field>
              <name>BG</name>
              <bitOffset>7</bitOffset>
              <bitWidth>1</bitWidth>
            </field>
            <field>
              <name>B2G</name>
              <bitOffset>8</bitOffset>
              <bitWidth>1</bitWidth>
            </field>
          </fields>
        </register>
        <register>
          <name>CCMR1</name>
          <addressOffset>0x18</addressOffset>
          <size>0x20</size>
          <fields>
            <field>
              <name>CC1S</name>
              <bitOffset>0</bitOffset>
              <bitWidth>2</bitWidth>
            </field>
            <field>
              <name>OC1FE</name>
              <bitOffset>2</bitOffset>
              <bitWidth>1</bitWidth>
            </field>
            <field>
              <name>OC1PE</name>
              <bitOffset>3</bitOffset>
              <bitWidth>1</bitWidth>
            </field>
            <field>
              <name>OC1M</name>
              <bitOffset>4</bitOffset>
              <bitWidth>13</bitWidth>
            </field>
            <field>
              <name>OC1CE</name>
              <bitOffset>7</bitOffset>
              <bitWidth>1</bitWidth>
            </field>
            <field>
              <name>CC2S</name>
              <bitOffset>8</bitOffset>
              <bitWidth>2</bitWidth>
            </field>
            <field>
              <name>OC2FE</name>
              <bitOffset>10</bitOffset>
              <bitWidth>1</bitWidth>
            </field>
            <field>
              <name>OC2PE</name>
              <bitOffset>11</bitOffset>
              <bitWidth>1</bitWidth>
            </field>
            <field>
              <name>OC2M</name>
              <bitOffset>12</bitOffset>
              <bitWidth>13</bitWidth>
            </field>
            <field>
              <name>OC2CE</name>
              <bitOffset>15</bitOffset>
              <bitWidth>1</bitWidth>
            </field>
          </fields>
        </register>
        <register>
          <name>CCMR2</name>
          <addressOffset>0x1c</addressOffset>
          <size>0x20</size>
          <fields>
            <field>
              <name>CC3S</name>
              <bitOffset>0</bitOffset>
              <bitWidth>2</bitWidth>
            </field>
            <field>
              <name>OC3FE</name>
              <bitOffset>2</bitOffset>
              <bitWidth>1</bitWidth>
            </field>
            <field>
              <name>OC3PE</name>
              <bitOffset>3</bitOffset>
              <bitWidth>1</bitWidth>
            </field>
            <field>
              <name>OC3M</name>
              <bitOffset>4</bitOffset>
              <bitWidth>13</bitWidth>
            </field>
            <field>
              <name>OC3CE</name>
              <bitOffset>7</bitOffset>
              <bitWidth>1</bitWidth>
            </field>
            <field>
              <name>CC4S</name>
              <bitOffset>8</bitOffset>
              <bitWidth>2</bitWidth>
            </field>
            <field>
              <name>OC4FE</name>
              <bitOffset>10</bitOffset>
              <bitWidth>1</bitWidth>
            </field>
            <field>
              <name>OC4PE</name>
              <bitOffset>11</bitOffset>
              <bitWidth>1</bitWidth>
            </field>
            <field>
              <name>OC4M</name>
              <bitOffset>12</bitOffset>
              <bitWidth>13</bitWidth>
            </field>
            <field>
              <name>OC4CE</name>
              <bitOffset>15</bitOffset>
              <bitWidth>1</bitWidth>
            </field>
          </fields>
        </register>
        <register>
          <name>CCER</name>
          <addressOffset>0x20</addressOffset>
          <size>0x20</size>
          <fields>
            <field>
              <name>CC1E</name>
              <bitOffset>0</bitOffset>
              <bitWidth>1</bitWidth>
            </field>
            <field>
              <name>CC1P</name>
              <bitOffset>1</bitOffset>
              <bitWidth>1</bitWidth>
            </field>
            <field>
              <name>CC1NE</name>
              <bitOffset>2</bitOffset>
              <bitWidth>1</bitWidth>
            </field>
            <field>
              <name>CC1NP</name>
              <bitOffset>3</bitOffset>
              <bitWidth>1</bitWidth>
            </field>
            <field>
              <name>CC2E</name>
              <bitOffset>4</bitOffset>
              <bitWidth>1</bitWidth>
            </field>
            <field>
              <name>CC2P</name>
              <bitOffset>5</bitOffset>
              <bitWidth>1</bitWidth>
            </field>
            <field>
              <name>CC2NE</name>
              <bitOffset>6</bitOffset>
              <bitWidth>1</bitWidth>
            </field>
            <field>
              <name>CC2NP</name>
              <bitOffset>7</bitOffset>
              <bitWidth>1</bitWidth>
            </field>
            <field>
              <name>CC3E</name>
              <bitOffset>8</bitOffset>
              <bitWidth>1</bitWidth>
            </field>
            <field>
              <name>CC3P</name>
              <bitOffset>9</bitOffset>
              <bitWidth>1</bitWidth>
            </field>
            <field>
              <name>CC3NE</name>
              <bitOffset>10</bitOffset>
              <bitWidth>1</bitWidth>
            </field>
            <field>
              <name>CC3NP</name>
              <bitOffset>11</bitOffset>
              <bitWidth>1</bitWidth>
            </field>
            <field>
              <name>CC4E</name>
              <bitOffset>12</bitOffset>
              <bitWidth>1</bitWidth>
            </field>
            <field>
              <name>CC4P</name>
              <bitOffset>13</bitOffset>
              <bitWidth>1</bitWidth>
            </field>
            <field>
              <name>CC4NP</name>
              <bitOffset>15</bitOffset>
              <bitWidth>1</bitWidth>
            </field>
            <field>
              <name>CC5E</name>
              <bitOffset>16</bitOffset>
              <bitWidth>1</bitWidth>
            </field>
            <field>
              <name>CC5P</name>
              <bitOffset>17</bitOffset>
              <bitWidth>1</bitWidth>
            </field>
            <field>
              <name>CC6E</name>
              <bitOffset>20</bitOffset>
              <bitWidth>1</bitWidth>
            </field>
            <field>
              <name>CC6P</name>
              <bitOffset>21</bitOffset>
              <bitWidth>1</bitWidth>
            </field>
          </fields>
        </register>
        <register>
          <name>CNT</name>
          <addressOffset>0x24</addressOffset>
          <size>0x20</size>
          <fields>
            <field>
              <name>CNT</name>
              <bitOffset>0</bitOffset>
              <bitWidth>32</bitWidth>
            </field>
            <field>
              <name>UIFCPY</name>
              <bitOffset>31</bitOffset>
              <bitWidth>1</bitWidth>
            </field>
          </fields>
        </register>
        <register>
          <name>PSC</name>
          <addressOffset>0x28</addressOffset>
          <size>0x20</size>
          <fields>
            <field>
              <name>PSC</name>
              <bitOffset>0</bitOffset>
              <bitWidth>16</bitWidth>
            </field>
          </fields>
        </register>
        <register>
          <name>ARR</name>
          <addressOffset>0x2c</addressOffset>
          <size>0x20</size>
          <fields>
            <field>
              <name>ARR</name>
              <bitOffset>0</bitOffset>
              <bitWidth>32</bitWidth>
            </field>
          </fields>
        </register>
        <register>
          <name>RCR</name>
          <addressOffset>0x30</addressOffset>
          <size>0x20</size>
          <fields>
            <field>
              <name>REP</name>
              <bitOffset>0</bitOffset>
              <bitWidth>16</bitWidth>
            </field>
          </fields>
        </register>
        <register>
          <name>CCR1</name>
          <addressOffset>0x34</addressOffset>
          <size>0x20</size>
          <fields>
            <field>
              <name>CCR1</name>
              <bitOffset>0</bitOffset>
              <bitWidth>16</bitWidth>
            </field>
          </fields>
        </register>
        <register>
          <name>CCR2</name>
          <addressOffset>0x38</addressOffset>
          <size>0x20</size>
          <fields>
            <field>
              <name>CCR2</name>
              <bitOffset>0</bitOffset>
              <bitWidth>16</bitWidth>
            </field>
          </fields>
        </register>
        <register>
          <name>CCR3</name>
          <addressOffset>0x3c</addressOffset>
          <size>0x20</size>
          <fields>
            <field>
              <name>CCR3</name>
              <bitOffset>0</bitOffset>
              <bitWidth>16</bitWidth>
            </field>
          </fields>
        </register>
        <register>
          <name>CCR4</name>
          <addressOffset>0x40</addressOffset>
          <size>0x20</size>
          <fields>
            <field>
              <name>CCR4</name>
              <bitOffset>0</bitOffset>
              <bitWidth>16</bitWidth>
            </field>
          </fields>
        </register>
        <register>
          <name>BDTR</name>
          <addressOffset>0x44</addressOffset>
          <size>0x20</size>
          <fields>
            <field>
              <name>DTG</name>
              <bitOffset>0</bitOffset>
              <bitWidth>8</bitWidth>
            </field>
            <field>
              <name>LOCK</name>
              <bitOffset>8</bitOffset>
              <bitWidth>2</bitWidth>
            </field>
            <field>
              <name>OSSI</name>
              <bitOffset>10</bitOffset>
              <bitWidth>1</bitWidth>
            </field>
            <field>
              <name>OSSR</name>
              <bitOffset>11</bitOffset>
              <bitWidth>1</bitWidth>
            </field>
            <field>
              <name>BKE</name>
              <bitOffset>12</bitOffset>
              <bitWidth>1</bitWidth>
            </field>
            <field>
              <name>BKP</name>
              <bitOffset>13</bitOffset>
              <bitWidth>1</bitWidth>
            </field>
            <field>
              <name>AOE</name>
              <bitOffset>14</bitOffset>
              <bitWidth>1</bitWidth>
            </field>
            <field>
              <name>MOE</name>
              <bitOffset>15</bitOffset>
              <bitWidth>1</bitWidth>
            </field>
            <field>
              <name>BKF</name>
              <bitOffset>16</bitOffset>
              <bitWidth>4</bitWidth>
            </field>
            <field>
              <name>BK2F</name>
              <bitOffset>20</bitOffset>
              <bitWidth>4</bitWidth>
            </field>
            <field>
              <name>BK2E</name>
              <bitOffset>24</bitOffset>
              <bitWidth>1</bitWidth>
            </field>
            <field>
              <name>BK2P</name>
              <bitOffset>25</bitOffset>
              <bitWidth>1</bitWidth>
            </field>
          </fields>
        </register>
        <register>
          <name>DCR</name>
          <addressOffset>0x48</addressOffset>
          <size>0x20</size>
          <fields>
            <field>
              <name>DBA</name>
              <bitOffset>0</bitOffset>
              <bitWidth>5</bitWidth>
            </field>
            <field>
              <name>DBL</name>
              <bitOffset>8</bitOffset>
              <bitWidth>5</bitWidth>
            </field>
          </fields>
        </register>
        <register>
          <name>DMAR</name>
          <addressOffset>0x4c</addressOffset>
          <size>0x20</size>
          <fields>
            <field>
              <name>DMAB</name>
              <bitOffset>0</bitOffset>
              <bitWidth>16</bitWidth>
            </field>
          </fields>
        </register>
        <register>
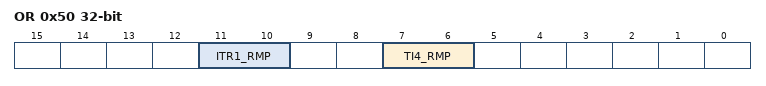
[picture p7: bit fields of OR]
          <name>OR</name>
          <addressOffset>0x50</addressOffset>
          <size>0x20</size>
          <fields>
            <field>
              <name>TI4_RMP</name>
              <bitOffset>6</bitOffset>
              <bitWidth>2</bitWidth>
            </field>
            <field>
              <name>ITR1_RMP</name>
              <bitOffset>10</bitOffset>
              <bitWidth>2</bitWidth>
            </field>
          </fields>
        </register>
        <register>
          <name>CCMR3</name>
          <addressOffset>0x54</addressOffset>
          <size>0x20</size>
          <fields>
            <field>
              <name>OC5FE</name>
              <bitOffset>2</bitOffset>
              <bitWidth>1</bitWidth>
            </field>
            <field>
              <name>OC5PE</name>
              <bitOffset>3</bitOffset>
              <bitWidth>1</bitWidth>
            </field>
            <field>
              <name>OC5M</name>
              <bitOffset>4</bitOffset>
              <bitWidth>13</bitWidth>
            </field>
            <field>
              <name>OC5CE</name>
              <bitOffset>7</bitOffset>
              <bitWidth>1</bitWidth>
            </field>
            <field>
              <name>OC6FE</name>
              <bitOffset>10</bitOffset>
              <bitWidth>1</bitWidth>
            </field>
            <field>
              <name>OC6PE</name>
              <bitOffset>11</bitOffset>
              <bitWidth>1</bitWidth>
            </field>
            <field>
              <name>OC6M</name>
              <bitOffset>12</bitOffset>
              <bitWidth>13</bitWidth>
            </field>
            <field>
              <name>OC6CE</name>
              <bitOffset>15</bitOffset>
              <bitWidth>1</bitWidth>
            </field>
          </fields>
        </register>
        <register>
          <name>CCR5</name>
          <addressOffset>0x58</addressOffset>
          <size>0x20</size>
          <fields>
            <field>
              <name>CCR5</name>
              <bitOffset>0</bitOffset>
              <bitWidth>32</bitWidth>
            </field>
            <field>
              <name>GC5C1</name>
              <bitOffset>29</bitOffset>
              <bitWidth>1</bitWidth>
            </field>
            <field>
              <name>GC5C2</name>
              <bitOffset>30</bitOffset>
              <bitWidth>1</bitWidth>
            </field>
            <field>
              <name>GC5C3</name>
              <bitOffset>31</bitOffset>
              <bitWidth>1</bitWidth>
            </field>
          </fields>
        </register>
        <register>
          <name>CCR6</name>
          <addressOffset>0x5c</addressOffset>
          <size>0x20</size>
        </register>
        <register>
          <name>AF1</name>
          <addressOffset>0x60</addressOffset>
          <size>0x20</size>
        </register>
        <register>
          <name>AF2</name>
          <addressOffset>0x64</addressOffset>
          <size>0x20</size>
        </register>
      </registers>
    </peripheral>
    <peripheral>
      <name>TIM8</name>
      <baseAddress>0x40010400</baseAddress>
      <registers>
        <register>
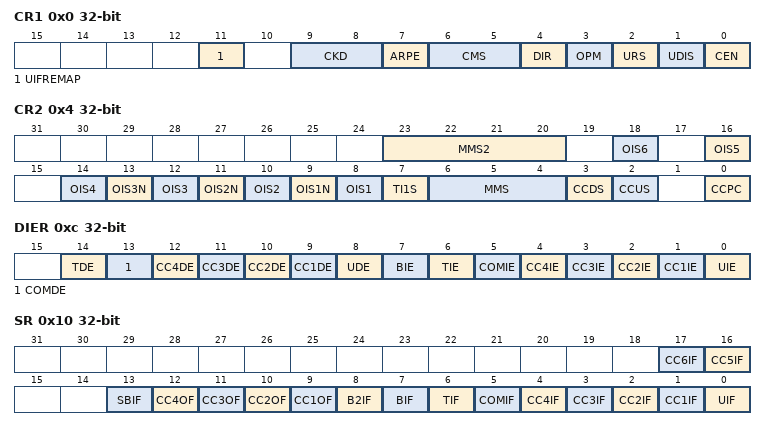
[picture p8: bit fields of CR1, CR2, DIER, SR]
          <name>CR1</name>
          <addressOffset>0x0</addressOffset>
          <size>0x20</size>
          <fields>
            <field>
              <name>CEN</name>
              <bitOffset>0</bitOffset>
              <bitWidth>1</bitWidth>
            </field>
            <field>
              <name>UDIS</name>
              <bitOffset>1</bitOffset>
              <bitWidth>1</bitWidth>
            </field>
            <field>
              <name>URS</name>
              <bitOffset>2</bitOffset>
              <bitWidth>1</bitWidth>
            </field>
            <field>
              <name>OPM</name>
              <bitOffset>3</bitOffset>
              <bitWidth>1</bitWidth>
            </field>
            <field>
              <name>DIR</name>
              <bitOffset>4</bitOffset>
              <bitWidth>1</bitWidth>
            </field>
            <field>
              <name>CMS</name>
              <bitOffset>5</bitOffset>
              <bitWidth>2</bitWidth>
            </field>
            <field>
              <name>ARPE</name>
              <bitOffset>7</bitOffset>
              <bitWidth>1</bitWidth>
            </field>
            <field>
              <name>CKD</name>
              <bitOffset>8</bitOffset>
              <bitWidth>2</bitWidth>
            </field>
            <field>
              <name>UIFREMAP</name>
              <bitOffset>11</bitOffset>
              <bitWidth>1</bitWidth>
            </field>
          </fields>
        </register>
        <register>
          <name>CR2</name>
          <addressOffset>0x4</addressOffset>
          <size>0x20</size>
          <fields>
            <field>
              <name>CCPC</name>
              <bitOffset>0</bitOffset>
              <bitWidth>1</bitWidth>
            </field>
            <field>
              <name>CCUS</name>
              <bitOffset>2</bitOffset>
              <bitWidth>1</bitWidth>
            </field>
            <field>
              <name>CCDS</name>
              <bitOffset>3</bitOffset>
              <bitWidth>1</bitWidth>
            </field>
            <field>
              <name>MMS</name>
              <bitOffset>4</bitOffset>
              <bitWidth>3</bitWidth>
            </field>
            <field>
              <name>TI1S</name>
              <bitOffset>7</bitOffset>
              <bitWidth>1</bitWidth>
            </field>
            <field>
              <name>OIS1</name>
              <bitOffset>8</bitOffset>
              <bitWidth>1</bitWidth>
            </field>
            <field>
              <name>OIS1N</name>
              <bitOffset>9</bitOffset>
              <bitWidth>1</bitWidth>
            </field>
            <field>
              <name>OIS2</name>
              <bitOffset>10</bitOffset>
              <bitWidth>1</bitWidth>
            </field>
            <field>
              <name>OIS2N</name>
              <bitOffset>11</bitOffset>
              <bitWidth>1</bitWidth>
            </field>
            <field>
              <name>OIS3</name>
              <bitOffset>12</bitOffset>
              <bitWidth>1</bitWidth>
            </field>
            <field>
              <name>OIS3N</name>
              <bitOffset>13</bitOffset>
              <bitWidth>1</bitWidth>
            </field>
            <field>
              <name>OIS4</name>
              <bitOffset>14</bitOffset>
              <bitWidth>1</bitWidth>
            </field>
            <field>
              <name>OIS5</name>
              <bitOffset>16</bitOffset>
              <bitWidth>1</bitWidth>
            </field>
            <field>
              <name>OIS6</name>
              <bitOffset>18</bitOffset>
              <bitWidth>1</bitWidth>
            </field>
            <field>
              <name>MMS2</name>
              <bitOffset>20</bitOffset>
              <bitWidth>4</bitWidth>
            </field>
          </fields>
        </register>
        <register>
          <name>SMCR</name>
          <addressOffset>0x8</addressOffset>
          <size>0x20</size>
          <fields>
            <field>
              <name>SMS</name>
              <bitOffset>0</bitOffset>
              <bitWidth>17</bitWidth>
            </field>
            <field>
              <name>TS</name>
              <bitOffset>4</bitOffset>
              <bitWidth>3</bitWidth>
            </field>
            <field>
              <name>MSM</name>
              <bitOffset>7</bitOffset>
              <bitWidth>1</bitWidth>
            </field>
            <field>
              <name>ETF</name>
              <bitOffset>8</bitOffset>
              <bitWidth>4</bitWidth>
            </field>
            <field>
              <name>ETPS</name>
              <bitOffset>12</bitOffset>
              <bitWidth>2</bitWidth>
            </field>
            <field>
              <name>ECE</name>
              <bitOffset>14</bitOffset>
              <bitWidth>1</bitWidth>
            </field>
            <field>
              <name>ETP</name>
              <bitOffset>15</bitOffset>
              <bitWidth>1</bitWidth>
            </field>
          </fields>
        </register>
        <register>
          <name>DIER</name>
          <addressOffset>0xc</addressOffset>
          <size>0x20</size>
          <fields>
            <field>
              <name>UIE</name>
              <bitOffset>0</bitOffset>
              <bitWidth>1</bitWidth>
            </field>
            <field>
              <name>CC1IE</name>
              <bitOffset>1</bitOffset>
              <bitWidth>1</bitWidth>
            </field>
            <field>
              <name>CC2IE</name>
              <bitOffset>2</bitOffset>
              <bitWidth>1</bitWidth>
            </field>
            <field>
              <name>CC3IE</name>
              <bitOffset>3</bitOffset>
              <bitWidth>1</bitWidth>
            </field>
            <field>
              <name>CC4IE</name>
              <bitOffset>4</bitOffset>
              <bitWidth>1</bitWidth>
            </field>
            <field>
              <name>COMIE</name>
              <bitOffset>5</bitOffset>
              <bitWidth>1</bitWidth>
            </field>
            <field>
              <name>TIE</name>
              <bitOffset>6</bitOffset>
              <bitWidth>1</bitWidth>
            </field>
            <field>
              <name>BIE</name>
              <bitOffset>7</bitOffset>
              <bitWidth>1</bitWidth>
            </field>
            <field>
              <name>UDE</name>
              <bitOffset>8</bitOffset>
              <bitWidth>1</bitWidth>
            </field>
            <field>
              <name>CC1DE</name>
              <bitOffset>9</bitOffset>
              <bitWidth>1</bitWidth>
            </field>
            <field>
              <name>CC2DE</name>
              <bitOffset>10</bitOffset>
              <bitWidth>1</bitWidth>
            </field>
            <field>
              <name>CC3DE</name>
              <bitOffset>11</bitOffset>
              <bitWidth>1</bitWidth>
            </field>
            <field>
              <name>CC4DE</name>
              <bitOffset>12</bitOffset>
              <bitWidth>1</bitWidth>
            </field>
            <field>
              <name>COMDE</name>
              <bitOffset>13</bitOffset>
              <bitWidth>1</bitWidth>
            </field>
            <field>
              <name>TDE</name>
              <bitOffset>14</bitOffset>
              <bitWidth>1</bitWidth>
            </field>
          </fields>
        </register>
        <register>
          <name>SR</name>
          <addressOffset>0x10</addressOffset>
          <size>0x20</size>
          <fields>
            <field>
              <name>UIF</name>
              <bitOffset>0</bitOffset>
              <bitWidth>1</bitWidth>
            </field>
            <field>
              <name>CC1IF</name>
              <bitOffset>1</bitOffset>
              <bitWidth>1</bitWidth>
            </field>
            <field>
              <name>CC2IF</name>
              <bitOffset>2</bitOffset>
              <bitWidth>1</bitWidth>
            </field>
            <field>
              <name>CC3IF</name>
              <bitOffset>3</bitOffset>
              <bitWidth>1</bitWidth>
            </field>
            <field>
              <name>CC4IF</name>
              <bitOffset>4</bitOffset>
              <bitWidth>1</bitWidth>
            </field>
            <field>
              <name>COMIF</name>
              <bitOffset>5</bitOffset>
              <bitWidth>1</bitWidth>
            </field>
            <field>
              <name>TIF</name>
              <bitOffset>6</bitOffset>
              <bitWidth>1</bitWidth>
            </field>
            <field>
              <name>BIF</name>
              <bitOffset>7</bitOffset>
              <bitWidth>1</bitWidth>
            </field>
            <field>
              <name>B2IF</name>
              <bitOffset>8</bitOffset>
              <bitWidth>1</bitWidth>
            </field>
            <field>
              <name>CC1OF</name>
              <bitOffset>9</bitOffset>
              <bitWidth>1</bitWidth>
            </field>
            <field>
              <name>CC2OF</name>
              <bitOffset>10</bitOffset>
              <bitWidth>1</bitWidth>
            </field>
            <field>
              <name>CC3OF</name>
              <bitOffset>11</bitOffset>
              <bitWidth>1</bitWidth>
            </field>
            <field>
              <name>CC4OF</name>
              <bitOffset>12</bitOffset>
              <bitWidth>1</bitWidth>
            </field>
            <field>
              <name>SBIF</name>
              <bitOffset>13</bitOffset>
              <bitWidth>1</bitWidth>
            </field>
            <field>
              <name>CC5IF</name>
              <bitOffset>16</bitOffset>
              <bitWidth>1</bitWidth>
            </field>
            <field>
              <name>CC6IF</name>
              <bitOffset>17</bitOffset>
              <bitWidth>1</bitWidth>
            </field>
          </fields>
        </register>
        <register>
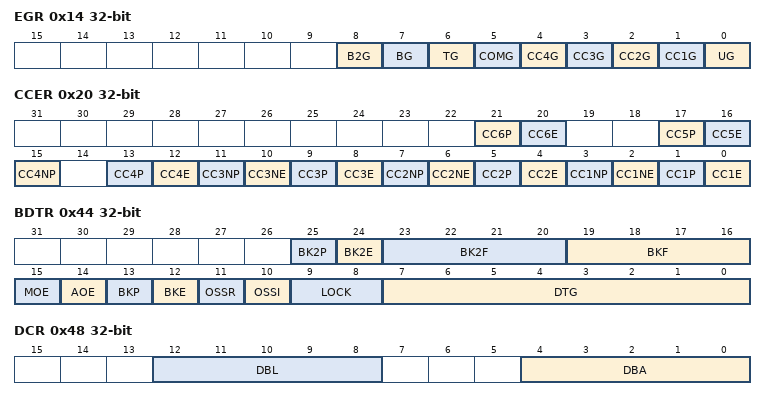
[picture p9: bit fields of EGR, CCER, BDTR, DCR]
          <name>EGR</name>
          <addressOffset>0x14</addressOffset>
          <size>0x20</size>
          <fields>
            <field>
              <name>UG</name>
              <bitOffset>0</bitOffset>
              <bitWidth>1</bitWidth>
            </field>
            <field>
              <name>CC1G</name>
              <bitOffset>1</bitOffset>
              <bitWidth>1</bitWidth>
            </field>
            <field>
              <name>CC2G</name>
              <bitOffset>2</bitOffset>
              <bitWidth>1</bitWidth>
            </field>
            <field>
              <name>CC3G</name>
              <bitOffset>3</bitOffset>
              <bitWidth>1</bitWidth>
            </field>
            <field>
              <name>CC4G</name>
              <bitOffset>4</bitOffset>
              <bitWidth>1</bitWidth>
            </field>
            <field>
              <name>COMG</name>
              <bitOffset>5</bitOffset>
              <bitWidth>1</bitWidth>
            </field>
            <field>
              <name>TG</name>
              <bitOffset>6</bitOffset>
              <bitWidth>1</bitWidth>
            </field>
            <field>
              <name>BG</name>
              <bitOffset>7</bitOffset>
              <bitWidth>1</bitWidth>
            </field>
            <field>
              <name>B2G</name>
              <bitOffset>8</bitOffset>
              <bitWidth>1</bitWidth>
            </field>
          </fields>
        </register>
        <register>
          <name>CCMR1</name>
          <addressOffset>0x18</addressOffset>
          <size>0x20</size>
          <fields>
            <field>
              <name>CC1S</name>
              <bitOffset>0</bitOffset>
              <bitWidth>2</bitWidth>
            </field>
            <field>
              <name>OC1FE</name>
              <bitOffset>2</bitOffset>
              <bitWidth>1</bitWidth>
            </field>
            <field>
              <name>OC1PE</name>
              <bitOffset>3</bitOffset>
              <bitWidth>1</bitWidth>
            </field>
            <field>
              <name>OC1M</name>
              <bitOffset>4</bitOffset>
              <bitWidth>13</bitWidth>
            </field>
            <field>
              <name>OC1CE</name>
              <bitOffset>7</bitOffset>
              <bitWidth>1</bitWidth>
            </field>
            <field>
              <name>CC2S</name>
              <bitOffset>8</bitOffset>
              <bitWidth>2</bitWidth>
            </field>
            <field>
              <name>OC2FE</name>
              <bitOffset>10</bitOffset>
              <bitWidth>1</bitWidth>
            </field>
            <field>
              <name>OC2PE</name>
              <bitOffset>11</bitOffset>
              <bitWidth>1</bitWidth>
            </field>
            <field>
              <name>OC2M</name>
              <bitOffset>12</bitOffset>
              <bitWidth>13</bitWidth>
            </field>
            <field>
              <name>OC2CE</name>
              <bitOffset>15</bitOffset>
              <bitWidth>1</bitWidth>
            </field>
          </fields>
        </register>
        <register>
          <name>CCMR2</name>
          <addressOffset>0x1c</addressOffset>
          <size>0x20</size>
          <fields>
            <field>
              <name>CC3S</name>
              <bitOffset>0</bitOffset>
              <bitWidth>2</bitWidth>
            </field>
            <field>
              <name>OC3FE</name>
              <bitOffset>2</bitOffset>
              <bitWidth>1</bitWidth>
            </field>
            <field>
              <name>OC3PE</name>
              <bitOffset>3</bitOffset>
              <bitWidth>1</bitWidth>
            </field>
            <field>
              <name>OC3M</name>
              <bitOffset>4</bitOffset>
              <bitWidth>13</bitWidth>
            </field>
            <field>
              <name>OC3CE</name>
              <bitOffset>7</bitOffset>
              <bitWidth>1</bitWidth>
            </field>
            <field>
              <name>CC4S</name>
              <bitOffset>8</bitOffset>
              <bitWidth>2</bitWidth>
            </field>
            <field>
              <name>OC4FE</name>
              <bitOffset>10</bitOffset>
              <bitWidth>1</bitWidth>
            </field>
            <field>
              <name>OC4PE</name>
              <bitOffset>11</bitOffset>
              <bitWidth>1</bitWidth>
            </field>
            <field>
              <name>OC4M</name>
              <bitOffset>12</bitOffset>
              <bitWidth>13</bitWidth>
            </field>
            <field>
              <name>OC4CE</name>
              <bitOffset>15</bitOffset>
              <bitWidth>1</bitWidth>
            </field>
          </fields>
        </register>
        <register>
          <name>CCER</name>
          <addressOffset>0x20</addressOffset>
          <size>0x20</size>
          <fields>
            <field>
              <name>CC1E</name>
              <bitOffset>0</bitOffset>
              <bitWidth>1</bitWidth>
            </field>
            <field>
              <name>CC1P</name>
              <bitOffset>1</bitOffset>
              <bitWidth>1</bitWidth>
            </field>
            <field>
              <name>CC1NE</name>
              <bitOffset>2</bitOffset>
              <bitWidth>1</bitWidth>
            </field>
            <field>
              <name>CC1NP</name>
              <bitOffset>3</bitOffset>
              <bitWidth>1</bitWidth>
            </field>
            <field>
              <name>CC2E</name>
              <bitOffset>4</bitOffset>
              <bitWidth>1</bitWidth>
            </field>
            <field>
              <name>CC2P</name>
              <bitOffset>5</bitOffset>
              <bitWidth>1</bitWidth>
            </field>
            <field>
              <name>CC2NE</name>
              <bitOffset>6</bitOffset>
              <bitWidth>1</bitWidth>
            </field>
            <field>
              <name>CC2NP</name>
              <bitOffset>7</bitOffset>
              <bitWidth>1</bitWidth>
            </field>
            <field>
              <name>CC3E</name>
              <bitOffset>8</bitOffset>
              <bitWidth>1</bitWidth>
            </field>
            <field>
              <name>CC3P</name>
              <bitOffset>9</bitOffset>
              <bitWidth>1</bitWidth>
            </field>
            <field>
              <name>CC3NE</name>
              <bitOffset>10</bitOffset>
              <bitWidth>1</bitWidth>
            </field>
            <field>
              <name>CC3NP</name>
              <bitOffset>11</bitOffset>
              <bitWidth>1</bitWidth>
            </field>
            <field>
              <name>CC4E</name>
              <bitOffset>12</bitOffset>
              <bitWidth>1</bitWidth>
            </field>
            <field>
              <name>CC4P</name>
              <bitOffset>13</bitOffset>
              <bitWidth>1</bitWidth>
            </field>
            <field>
              <name>CC4NP</name>
              <bitOffset>15</bitOffset>
              <bitWidth>1</bitWidth>
            </field>
            <field>
              <name>CC5E</name>
              <bitOffset>16</bitOffset>
              <bitWidth>1</bitWidth>
            </field>
            <field>
              <name>CC5P</name>
              <bitOffset>17</bitOffset>
              <bitWidth>1</bitWidth>
            </field>
            <field>
              <name>CC6E</name>
              <bitOffset>20</bitOffset>
              <bitWidth>1</bitWidth>
            </field>
            <field>
              <name>CC6P</name>
              <bitOffset>21</bitOffset>
              <bitWidth>1</bitWidth>
            </field>
          </fields>
        </register>
        <register>
          <name>CNT</name>
          <addressOffset>0x24</addressOffset>
          <size>0x20</size>
          <fields>
            <field>
              <name>CNT</name>
              <bitOffset>0</bitOffset>
              <bitWidth>32</bitWidth>
            </field>
            <field>
              <name>UIFCPY</name>
              <bitOffset>31</bitOffset>
              <bitWidth>1</bitWidth>
            </field>
          </fields>
        </register>
        <register>
          <name>PSC</name>
          <addressOffset>0x28</addressOffset>
          <size>0x20</size>
          <fields>
            <field>
              <name>PSC</name>
              <bitOffset>0</bitOffset>
              <bitWidth>16</bitWidth>
            </field>
          </fields>
        </register>
        <register>
          <name>ARR</name>
          <addressOffset>0x2c</addressOffset>
          <size>0x20</size>
          <fields>
            <field>
              <name>ARR</name>
              <bitOffset>0</bitOffset>
              <bitWidth>32</bitWidth>
            </field>
          </fields>
        </register>
        <register>
          <name>RCR</name>
          <addressOffset>0x30</addressOffset>
          <size>0x20</size>
          <fields>
            <field>
              <name>REP</name>
              <bitOffset>0</bitOffset>
              <bitWidth>16</bitWidth>
            </field>
          </fields>
        </register>
        <register>
          <name>CCR1</name>
          <addressOffset>0x34</addressOffset>
          <size>0x20</size>
          <fields>
            <field>
              <name>CCR1</name>
              <bitOffset>0</bitOffset>
              <bitWidth>16</bitWidth>
            </field>
          </fields>
        </register>
        <register>
          <name>CCR2</name>
          <addressOffset>0x38</addressOffset>
          <size>0x20</size>
          <fields>
            <field>
              <name>CCR2</name>
              <bitOffset>0</bitOffset>
              <bitWidth>16</bitWidth>
            </field>
          </fields>
        </register>
        <register>
          <name>CCR3</name>
          <addressOffset>0x3c</addressOffset>
          <size>0x20</size>
          <fields>
            <field>
              <name>CCR3</name>
              <bitOffset>0</bitOffset>
              <bitWidth>16</bitWidth>
            </field>
          </fields>
        </register>
        <register>
          <name>CCR4</name>
          <addressOffset>0x40</addressOffset>
          <size>0x20</size>
          <fields>
            <field>
              <name>CCR4</name>
              <bitOffset>0</bitOffset>
              <bitWidth>16</bitWidth>
            </field>
          </fields>
        </register>
        <register>
          <name>BDTR</name>
          <addressOffset>0x44</addressOffset>
          <size>0x20</size>
          <fields>
            <field>
              <name>DTG</name>
              <bitOffset>0</bitOffset>
              <bitWidth>8</bitWidth>
            </field>
            <field>
              <name>LOCK</name>
              <bitOffset>8</bitOffset>
              <bitWidth>2</bitWidth>
            </field>
            <field>
              <name>OSSI</name>
              <bitOffset>10</bitOffset>
              <bitWidth>1</bitWidth>
            </field>
            <field>
              <name>OSSR</name>
              <bitOffset>11</bitOffset>
              <bitWidth>1</bitWidth>
            </field>
            <field>
              <name>BKE</name>
              <bitOffset>12</bitOffset>
              <bitWidth>1</bitWidth>
            </field>
            <field>
              <name>BKP</name>
              <bitOffset>13</bitOffset>
              <bitWidth>1</bitWidth>
            </field>
            <field>
              <name>AOE</name>
              <bitOffset>14</bitOffset>
              <bitWidth>1</bitWidth>
            </field>
            <field>
              <name>MOE</name>
              <bitOffset>15</bitOffset>
              <bitWidth>1</bitWidth>
            </field>
            <field>
              <name>BKF</name>
              <bitOffset>16</bitOffset>
              <bitWidth>4</bitWidth>
            </field>
            <field>
              <name>BK2F</name>
              <bitOffset>20</bitOffset>
              <bitWidth>4</bitWidth>
            </field>
            <field>
              <name>BK2E</name>
              <bitOffset>24</bitOffset>
              <bitWidth>1</bitWidth>
            </field>
            <field>
              <name>BK2P</name>
              <bitOffset>25</bitOffset>
              <bitWidth>1</bitWidth>
            </field>
          </fields>
        </register>
        <register>
          <name>DCR</name>
          <addressOffset>0x48</addressOffset>
          <size>0x20</size>
          <fields>
            <field>
              <name>DBA</name>
              <bitOffset>0</bitOffset>
              <bitWidth>5</bitWidth>
            </field>
            <field>
              <name>DBL</name>
              <bitOffset>8</bitOffset>
              <bitWidth>5</bitWidth>
            </field>
          </fields>
        </register>
        <register>
          <name>DMAR</name>
          <addressOffset>0x4c</addressOffset>
          <size>0x20</size>
          <fields>
            <field>
              <name>DMAB</name>
              <bitOffset>0</bitOffset>
              <bitWidth>16</bitWidth>
            </field>
          </fields>
        </register>
        <register>
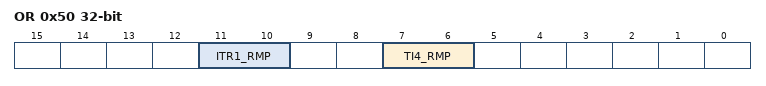
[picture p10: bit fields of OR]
          <name>OR</name>
          <addressOffset>0x50</addressOffset>
          <size>0x20</size>
          <fields>
            <field>
              <name>TI4_RMP</name>
              <bitOffset>6</bitOffset>
              <bitWidth>2</bitWidth>
            </field>
            <field>
              <name>ITR1_RMP</name>
              <bitOffset>10</bitOffset>
              <bitWidth>2</bitWidth>
            </field>
          </fields>
        </register>
        <register>
          <name>CCMR3</name>
          <addressOffset>0x54</addressOffset>
          <size>0x20</size>
          <fields>
            <field>
              <name>OC5FE</name>
              <bitOffset>2</bitOffset>
              <bitWidth>1</bitWidth>
            </field>
            <field>
              <name>OC5PE</name>
              <bitOffset>3</bitOffset>
              <bitWidth>1</bitWidth>
            </field>
            <field>
              <name>OC5M</name>
              <bitOffset>4</bitOffset>
              <bitWidth>13</bitWidth>
            </field>
            <field>
              <name>OC5CE</name>
              <bitOffset>7</bitOffset>
              <bitWidth>1</bitWidth>
            </field>
            <field>
              <name>OC6FE</name>
              <bitOffset>10</bitOffset>
              <bitWidth>1</bitWidth>
            </field>
            <field>
              <name>OC6PE</name>
              <bitOffset>11</bitOffset>
              <bitWidth>1</bitWidth>
            </field>
            <field>
              <name>OC6M</name>
              <bitOffset>12</bitOffset>
              <bitWidth>13</bitWidth>
            </field>
            <field>
              <name>OC6CE</name>
              <bitOffset>15</bitOffset>
              <bitWidth>1</bitWidth>
            </field>
          </fields>
        </register>
        <register>
          <name>CCR5</name>
          <addressOffset>0x58</addressOffset>
          <size>0x20</size>
          <fields>
            <field>
              <name>CCR5</name>
              <bitOffset>0</bitOffset>
              <bitWidth>32</bitWidth>
            </field>
            <field>
              <name>GC5C1</name>
              <bitOffset>29</bitOffset>
              <bitWidth>1</bitWidth>
            </field>
            <field>
              <name>GC5C2</name>
              <bitOffset>30</bitOffset>
              <bitWidth>1</bitWidth>
            </field>
            <field>
              <name>GC5C3</name>
              <bitOffset>31</bitOffset>
              <bitWidth>1</bitWidth>
            </field>
          </fields>
        </register>
        <register>
          <name>CCR6</name>
          <addressOffset>0x5c</addressOffset>
          <size>0x20</size>
        </register>
        <register>
          <name>AF1</name>
          <addressOffset>0x60</addressOffset>
          <size>0x20</size>
        </register>
        <register>
          <name>AF2</name>
          <addressOffset>0x64</addressOffset>
          <size>0x20</size>
        </register>
      </registers>
    </peripheral>
    <peripheral>
      <name>USART1</name>
      <baseAddress>0x40011000</baseAddress>
      <registers>
        <register>
          <name>CR1</name>
          <addressOffset>0x0</addressOffset>
          <size>0x20</size>
          <fields>
            <field>
              <name>UE</name>
              <bitOffset>0</bitOffset>
              <bitWidth>1</bitWidth>
            </field>
            <field>
              <name>UESM</name>
              <bitOffset>1</bitOffset>
              <bitWidth>1</bitWidth>
            </field>
            <field>
              <name>RE</name>
              <bitOffset>2</bitOffset>
              <bitWidth>1</bitWidth>
            </field>
            <field>
              <name>TE</name>
              <bitOffset>3</bitOffset>
              <bitWidth>1</bitWidth>
            </field>
            <field>
              <name>IDLEIE</name>
              <bitOffset>4</bitOffset>
              <bitWidth>1</bitWidth>
            </field>
            <field>
              <name>RXNEIE</name>
              <bitOffset>5</bitOffset>
              <bitWidth>1</bitWidth>
            </field>
            <field>
              <name>TCIE</name>
              <bitOffset>6</bitOffset>
              <bitWidth>1</bitWidth>
            </field>
            <field>
              <name>TXEIE</name>
              <bitOffset>7</bitOffset>
              <bitWidth>1</bitWidth>
            </field>
            <field>
              <name>PEIE</name>
              <bitOffset>8</bitOffset>
              <bitWidth>1</bitWidth>
            </field>
            <field>
              <name>PS</name>
              <bitOffset>9</bitOffset>
              <bitWidth>1</bitWidth>
            </field>
            <field>
              <name>PCE</name>
              <bitOffset>10</bitOffset>
              <bitWidth>1</bitWidth>
            </field>
            <field>
              <name>WAKE</name>
              <bitOffset>11</bitOffset>
              <bitWidth>1</bitWidth>
            </field>
            <field>
              <name>M</name>
              <bitOffset>12</bitOffset>
              <bitWidth>17</bitWidth>
            </field>
            <field>
              <name>MME</name>
              <bitOffset>13</bitOffset>
              <bitWidth>1</bitWidth>
            </field>
            <field>
              <name>CMIE</name>
              <bitOffset>14</bitOffset>
              <bitWidth>1</bitWidth>
            </field>
            <field>
              <name>OVER8</name>
              <bitOffset>15</bitOffset>
              <bitWidth>1</bitWidth>
            </field>
            <field>
              <name>DEDT</name>
              <bitOffset>16</bitOffset>
              <bitWidth>5</bitWidth>
            </field>
            <field>
              <name>DEAT</name>
              <bitOffset>21</bitOffset>
              <bitWidth>5</bitWidth>
            </field>
            <field>
              <name>RTOIE</name>
              <bitOffset>26</bitOffset>
              <bitWidth>1</bitWidth>
            </field>
            <field>
              <name>EOBIE</name>
              <bitOffset>27</bitOffset>
              <bitWidth>1</bitWidth>
            </field>
          </fields>
        </register>
        <register>
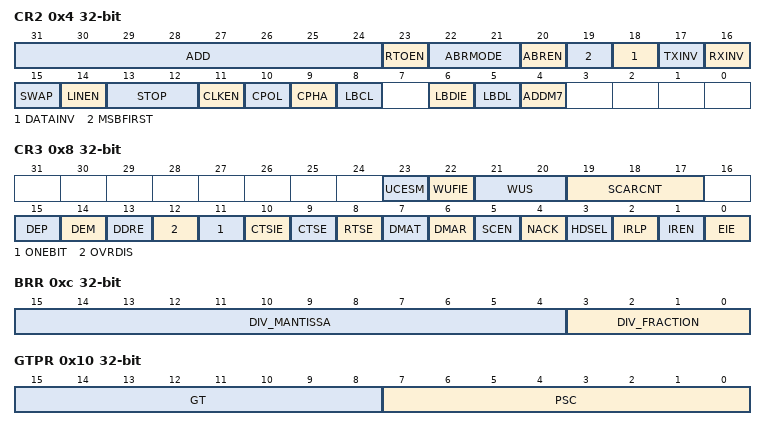
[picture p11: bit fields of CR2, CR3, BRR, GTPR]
          <name>CR2</name>
          <addressOffset>0x4</addressOffset>
          <size>0x20</size>
          <fields>
            <field>
              <name>ADDM7</name>
              <bitOffset>4</bitOffset>
              <bitWidth>1</bitWidth>
            </field>
            <field>
              <name>LBDL</name>
              <bitOffset>5</bitOffset>
              <bitWidth>1</bitWidth>
            </field>
            <field>
              <name>LBDIE</name>
              <bitOffset>6</bitOffset>
              <bitWidth>1</bitWidth>
            </field>
            <field>
              <name>LBCL</name>
              <bitOffset>8</bitOffset>
              <bitWidth>1</bitWidth>
            </field>
            <field>
              <name>CPHA</name>
              <bitOffset>9</bitOffset>
              <bitWidth>1</bitWidth>
            </field>
            <field>
              <name>CPOL</name>
              <bitOffset>10</bitOffset>
              <bitWidth>1</bitWidth>
            </field>
            <field>
              <name>CLKEN</name>
              <bitOffset>11</bitOffset>
              <bitWidth>1</bitWidth>
            </field>
            <field>
              <name>STOP</name>
              <bitOffset>12</bitOffset>
              <bitWidth>2</bitWidth>
            </field>
            <field>
              <name>LINEN</name>
              <bitOffset>14</bitOffset>
              <bitWidth>1</bitWidth>
            </field>
            <field>
              <name>SWAP</name>
              <bitOffset>15</bitOffset>
              <bitWidth>1</bitWidth>
            </field>
            <field>
              <name>RXINV</name>
              <bitOffset>16</bitOffset>
              <bitWidth>1</bitWidth>
            </field>
            <field>
              <name>TXINV</name>
              <bitOffset>17</bitOffset>
              <bitWidth>1</bitWidth>
            </field>
            <field>
              <name>DATAINV</name>
              <bitOffset>18</bitOffset>
              <bitWidth>1</bitWidth>
            </field>
            <field>
              <name>MSBFIRST</name>
              <bitOffset>19</bitOffset>
              <bitWidth>1</bitWidth>
            </field>
            <field>
              <name>ABREN</name>
              <bitOffset>20</bitOffset>
              <bitWidth>1</bitWidth>
            </field>
            <field>
              <name>ABRMODE</name>
              <bitOffset>21</bitOffset>
              <bitWidth>2</bitWidth>
            </field>
            <field>
              <name>RTOEN</name>
              <bitOffset>23</bitOffset>
              <bitWidth>1</bitWidth>
            </field>
            <field>
              <name>ADD</name>
              <bitOffset>24</bitOffset>
              <bitWidth>8</bitWidth>
            </field>
          </fields>
        </register>
        <register>
          <name>CR3</name>
          <addressOffset>0x8</addressOffset>
          <size>0x20</size>
          <fields>
            <field>
              <name>EIE</name>
              <bitOffset>0</bitOffset>
              <bitWidth>1</bitWidth>
            </field>
            <field>
              <name>IREN</name>
              <bitOffset>1</bitOffset>
              <bitWidth>1</bitWidth>
            </field>
            <field>
              <name>IRLP</name>
              <bitOffset>2</bitOffset>
              <bitWidth>1</bitWidth>
            </field>
            <field>
              <name>HDSEL</name>
              <bitOffset>3</bitOffset>
              <bitWidth>1</bitWidth>
            </field>
            <field>
              <name>NACK</name>
              <bitOffset>4</bitOffset>
              <bitWidth>1</bitWidth>
            </field>
            <field>
              <name>SCEN</name>
              <bitOffset>5</bitOffset>
              <bitWidth>1</bitWidth>
            </field>
            <field>
              <name>DMAR</name>
              <bitOffset>6</bitOffset>
              <bitWidth>1</bitWidth>
            </field>
            <field>
              <name>DMAT</name>
              <bitOffset>7</bitOffset>
              <bitWidth>1</bitWidth>
            </field>
            <field>
              <name>RTSE</name>
              <bitOffset>8</bitOffset>
              <bitWidth>1</bitWidth>
            </field>
            <field>
              <name>CTSE</name>
              <bitOffset>9</bitOffset>
              <bitWidth>1</bitWidth>
            </field>
            <field>
              <name>CTSIE</name>
              <bitOffset>10</bitOffset>
              <bitWidth>1</bitWidth>
            </field>
            <field>
              <name>ONEBIT</name>
              <bitOffset>11</bitOffset>
              <bitWidth>1</bitWidth>
            </field>
            <field>
              <name>OVRDIS</name>
              <bitOffset>12</bitOffset>
              <bitWidth>1</bitWidth>
            </field>
            <field>
              <name>DDRE</name>
              <bitOffset>13</bitOffset>
              <bitWidth>1</bitWidth>
            </field>
            <field>
              <name>DEM</name>
              <bitOffset>14</bitOffset>
              <bitWidth>1</bitWidth>
            </field>
            <field>
              <name>DEP</name>
              <bitOffset>15</bitOffset>
              <bitWidth>1</bitWidth>
            </field>
            <field>
              <name>SCARCNT</name>
              <bitOffset>17</bitOffset>
              <bitWidth>3</bitWidth>
            </field>
            <field>
              <name>WUS</name>
              <bitOffset>20</bitOffset>
              <bitWidth>2</bitWidth>
            </field>
            <field>
              <name>WUFIE</name>
              <bitOffset>22</bitOffset>
              <bitWidth>1</bitWidth>
            </field>
            <field>
              <name>UCESM</name>
              <bitOffset>23</bitOffset>
              <bitWidth>1</bitWidth>
            </field>
          </fields>
        </register>
        <register>
          <name>BRR</name>
          <addressOffset>0xc</addressOffset>
          <size>0x20</size>
          <fields>
            <field>
              <name>DIV_FRACTION</name>
              <bitOffset>0</bitOffset>
              <bitWidth>4</bitWidth>
            </field>
            <field>
              <name>DIV_MANTISSA</name>
              <bitOffset>4</bitOffset>
              <bitWidth>12</bitWidth>
            </field>
          </fields>
        </register>
        <register>
          <name>GTPR</name>
          <addressOffset>0x10</addressOffset>
          <size>0x20</size>
          <fields>
            <field>
              <name>PSC</name>
              <bitOffset>0</bitOffset>
              <bitWidth>8</bitWidth>
            </field>
            <field>
              <name>GT</name>
              <bitOffset>8</bitOffset>
              <bitWidth>8</bitWidth>
            </field>
          </fields>
        </register>
        <register>
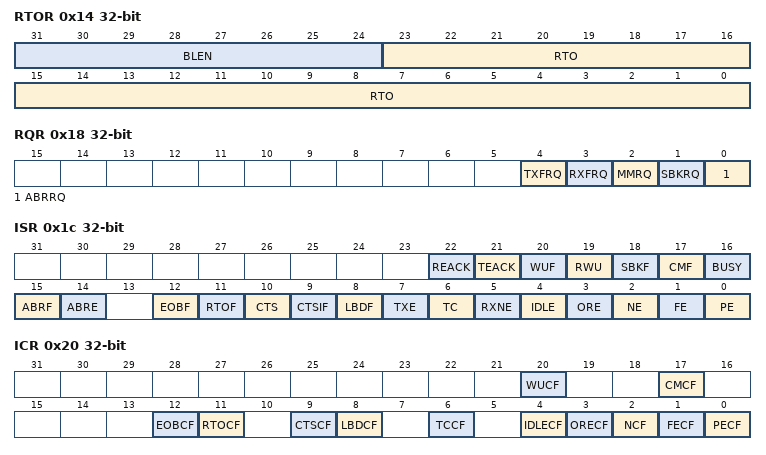
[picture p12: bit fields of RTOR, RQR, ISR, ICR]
          <name>RTOR</name>
          <addressOffset>0x14</addressOffset>
          <size>0x20</size>
          <fields>
            <field>
              <name>RTO</name>
              <bitOffset>0</bitOffset>
              <bitWidth>24</bitWidth>
            </field>
            <field>
              <name>BLEN</name>
              <bitOffset>24</bitOffset>
              <bitWidth>8</bitWidth>
            </field>
          </fields>
        </register>
        <register>
          <name>RQR</name>
          <addressOffset>0x18</addressOffset>
          <size>0x20</size>
          <fields>
            <field>
              <name>ABRRQ</name>
              <bitOffset>0</bitOffset>
              <bitWidth>1</bitWidth>
            </field>
            <field>
              <name>SBKRQ</name>
              <bitOffset>1</bitOffset>
              <bitWidth>1</bitWidth>
            </field>
            <field>
              <name>MMRQ</name>
              <bitOffset>2</bitOffset>
              <bitWidth>1</bitWidth>
            </field>
            <field>
              <name>RXFRQ</name>
              <bitOffset>3</bitOffset>
              <bitWidth>1</bitWidth>
            </field>
            <field>
              <name>TXFRQ</name>
              <bitOffset>4</bitOffset>
              <bitWidth>1</bitWidth>
            </field>
          </fields>
        </register>
        <register>
          <name>ISR</name>
          <addressOffset>0x1c</addressOffset>
          <size>0x20</size>
          <fields>
            <field>
              <name>PE</name>
              <bitOffset>0</bitOffset>
              <bitWidth>1</bitWidth>
            </field>
            <field>
              <name>FE</name>
              <bitOffset>1</bitOffset>
              <bitWidth>1</bitWidth>
            </field>
            <field>
              <name>NE</name>
              <bitOffset>2</bitOffset>
              <bitWidth>1</bitWidth>
            </field>
            <field>
              <name>ORE</name>
              <bitOffset>3</bitOffset>
              <bitWidth>1</bitWidth>
            </field>
            <field>
              <name>IDLE</name>
              <bitOffset>4</bitOffset>
              <bitWidth>1</bitWidth>
            </field>
            <field>
              <name>RXNE</name>
              <bitOffset>5</bitOffset>
              <bitWidth>1</bitWidth>
            </field>
            <field>
              <name>TC</name>
              <bitOffset>6</bitOffset>
              <bitWidth>1</bitWidth>
            </field>
            <field>
              <name>TXE</name>
              <bitOffset>7</bitOffset>
              <bitWidth>1</bitWidth>
            </field>
            <field>
              <name>LBDF</name>
              <bitOffset>8</bitOffset>
              <bitWidth>1</bitWidth>
            </field>
            <field>
              <name>CTSIF</name>
              <bitOffset>9</bitOffset>
              <bitWidth>1</bitWidth>
            </field>
            <field>
              <name>CTS</name>
              <bitOffset>10</bitOffset>
              <bitWidth>1</bitWidth>
            </field>
            <field>
              <name>RTOF</name>
              <bitOffset>11</bitOffset>
              <bitWidth>1</bitWidth>
            </field>
            <field>
              <name>EOBF</name>
              <bitOffset>12</bitOffset>
              <bitWidth>1</bitWidth>
            </field>
            <field>
              <name>ABRE</name>
              <bitOffset>14</bitOffset>
              <bitWidth>1</bitWidth>
            </field>
            <field>
              <name>ABRF</name>
              <bitOffset>15</bitOffset>
              <bitWidth>1</bitWidth>
            </field>
            <field>
              <name>BUSY</name>
              <bitOffset>16</bitOffset>
              <bitWidth>1</bitWidth>
            </field>
            <field>
              <name>CMF</name>
              <bitOffset>17</bitOffset>
              <bitWidth>1</bitWidth>
            </field>
            <field>
              <name>SBKF</name>
              <bitOffset>18</bitOffset>
              <bitWidth>1</bitWidth>
            </field>
            <field>
              <name>RWU</name>
              <bitOffset>19</bitOffset>
              <bitWidth>1</bitWidth>
            </field>
            <field>
              <name>WUF</name>
              <bitOffset>20</bitOffset>
              <bitWidth>1</bitWidth>
            </field>
            <field>
              <name>TEACK</name>
              <bitOffset>21</bitOffset>
              <bitWidth>1</bitWidth>
            </field>
            <field>
              <name>REACK</name>
              <bitOffset>22</bitOffset>
              <bitWidth>1</bitWidth>
            </field>
          </fields>
        </register>
        <register>
          <name>ICR</name>
          <addressOffset>0x20</addressOffset>
          <size>0x20</size>
          <fields>
            <field>
              <name>PECF</name>
              <bitOffset>0</bitOffset>
              <bitWidth>1</bitWidth>
            </field>
            <field>
              <name>FECF</name>
              <bitOffset>1</bitOffset>
              <bitWidth>1</bitWidth>
            </field>
            <field>
              <name>NCF</name>
              <bitOffset>2</bitOffset>
              <bitWidth>1</bitWidth>
            </field>
            <field>
              <name>ORECF</name>
              <bitOffset>3</bitOffset>
              <bitWidth>1</bitWidth>
            </field>
            <field>
              <name>IDLECF</name>
              <bitOffset>4</bitOffset>
              <bitWidth>1</bitWidth>
            </field>
            <field>
              <name>TCCF</name>
              <bitOffset>6</bitOffset>
              <bitWidth>1</bitWidth>
            </field>
            <field>
              <name>LBDCF</name>
              <bitOffset>8</bitOffset>
              <bitWidth>1</bitWidth>
            </field>
            <field>
              <name>CTSCF</name>
              <bitOffset>9</bitOffset>
              <bitWidth>1</bitWidth>
            </field>
            <field>
              <name>RTOCF</name>
              <bitOffset>11</bitOffset>
              <bitWidth>1</bitWidth>
            </field>
            <field>
              <name>EOBCF</name>
              <bitOffset>12</bitOffset>
              <bitWidth>1</bitWidth>
            </field>
            <field>
              <name>CMCF</name>
              <bitOffset>17</bitOffset>
              <bitWidth>1</bitWidth>
            </field>
            <field>
              <name>WUCF</name>
              <bitOffset>20</bitOffset>
              <bitWidth>1</bitWidth>
            </field>
          </fields>
        </register>
        <register>
          <name>RDR</name>
          <addressOffset>0x24</addressOffset>
          <size>0x20</size>
          <fields>
            <field>
              <name>RDR</name>
              <bitOffset>0</bitOffset>
              <bitWidth>9</bitWidth>
            </field>
          </fields>
        </register>
        <register>
          <name>TDR</name>
          <addressOffset>0x28</addressOffset>
          <size>0x20</size>
          <fields>
            <field>
              <name>TDR</name>
              <bitOffset>0</bitOffset>
              <bitWidth>9</bitWidth>
            </field>
          </fields>
        </register>
      </registers>
    </peripheral>
    <peripheral>
      <name>USART6</name>
      <baseAddress>0x40011400</baseAddress>
      <registers>
        <register>
          <name>CR1</name>
          <addressOffset>0x0</addressOffset>
          <size>0x20</size>
          <fields>
            <field>
              <name>UE</name>
              <bitOffset>0</bitOffset>
              <bitWidth>1</bitWidth>
            </field>
            <field>
              <name>UESM</name>
              <bitOffset>1</bitOffset>
              <bitWidth>1</bitWidth>
            </field>
            <field>
              <name>RE</name>
              <bitOffset>2</bitOffset>
              <bitWidth>1</bitWidth>
            </field>
            <field>
              <name>TE</name>
              <bitOffset>3</bitOffset>
              <bitWidth>1</bitWidth>
            </field>
            <field>
              <name>IDLEIE</name>
              <bitOffset>4</bitOffset>
              <bitWidth>1</bitWidth>
            </field>
            <field>
              <name>RXNEIE</name>
              <bitOffset>5</bitOffset>
              <bitWidth>1</bitWidth>
            </field>
            <field>
              <name>TCIE</name>
              <bitOffset>6</bitOffset>
              <bitWidth>1</bitWidth>
            </field>
            <field>
              <name>TXEIE</name>
              <bitOffset>7</bitOffset>
              <bitWidth>1</bitWidth>
            </field>
            <field>
              <name>PEIE</name>
              <bitOffset>8</bitOffset>
              <bitWidth>1</bitWidth>
            </field>
            <field>
              <name>PS</name>
              <bitOffset>9</bitOffset>
              <bitWidth>1</bitWidth>
            </field>
            <field>
              <name>PCE</name>
              <bitOffset>10</bitOffset>
              <bitWidth>1</bitWidth>
            </field>
            <field>
              <name>WAKE</name>
              <bitOffset>11</bitOffset>
              <bitWidth>1</bitWidth>
            </field>
            <field>
              <name>M</name>
              <bitOffset>12</bitOffset>
              <bitWidth>17</bitWidth>
            </field>
            <field>
              <name>MME</name>
              <bitOffset>13</bitOffset>
              <bitWidth>1</bitWidth>
            </field>
            <field>
              <name>CMIE</name>
              <bitOffset>14</bitOffset>
              <bitWidth>1</bitWidth>
            </field>
            <field>
              <name>OVER8</name>
              <bitOffset>15</bitOffset>
              <bitWidth>1</bitWidth>
            </field>
            <field>
              <name>DEDT</name>
              <bitOffset>16</bitOffset>
              <bitWidth>5</bitWidth>
            </field>
            <field>
              <name>DEAT</name>
              <bitOffset>21</bitOffset>
              <bitWidth>5</bitWidth>
            </field>
            <field>
              <name>RTOIE</name>
              <bitOffset>26</bitOffset>
              <bitWidth>1</bitWidth>
            </field>
            <field>
              <name>EOBIE</name>
              <bitOffset>27</bitOffset>
              <bitWidth>1</bitWidth>
            </field>
          </fields>
        </register>
        <register>
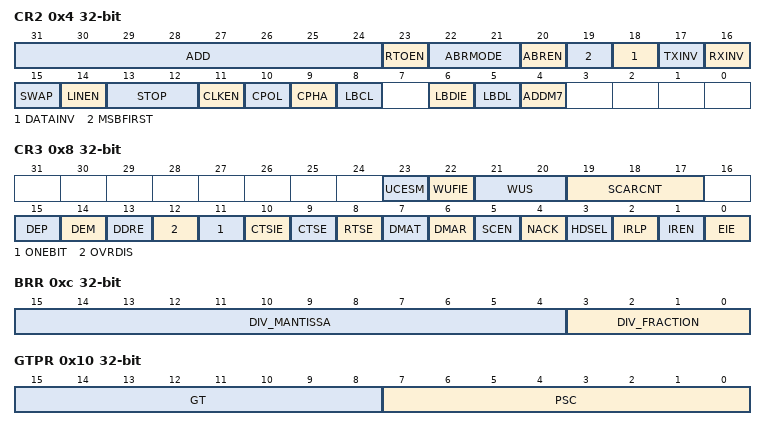
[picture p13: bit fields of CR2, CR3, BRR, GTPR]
          <name>CR2</name>
          <addressOffset>0x4</addressOffset>
          <size>0x20</size>
          <fields>
            <field>
              <name>ADDM7</name>
              <bitOffset>4</bitOffset>
              <bitWidth>1</bitWidth>
            </field>
            <field>
              <name>LBDL</name>
              <bitOffset>5</bitOffset>
              <bitWidth>1</bitWidth>
            </field>
            <field>
              <name>LBDIE</name>
              <bitOffset>6</bitOffset>
              <bitWidth>1</bitWidth>
            </field>
            <field>
              <name>LBCL</name>
              <bitOffset>8</bitOffset>
              <bitWidth>1</bitWidth>
            </field>
            <field>
              <name>CPHA</name>
              <bitOffset>9</bitOffset>
              <bitWidth>1</bitWidth>
            </field>
            <field>
              <name>CPOL</name>
              <bitOffset>10</bitOffset>
              <bitWidth>1</bitWidth>
            </field>
            <field>
              <name>CLKEN</name>
              <bitOffset>11</bitOffset>
              <bitWidth>1</bitWidth>
            </field>
            <field>
              <name>STOP</name>
              <bitOffset>12</bitOffset>
              <bitWidth>2</bitWidth>
            </field>
            <field>
              <name>LINEN</name>
              <bitOffset>14</bitOffset>
              <bitWidth>1</bitWidth>
            </field>
            <field>
              <name>SWAP</name>
              <bitOffset>15</bitOffset>
              <bitWidth>1</bitWidth>
            </field>
            <field>
              <name>RXINV</name>
              <bitOffset>16</bitOffset>
              <bitWidth>1</bitWidth>
            </field>
            <field>
              <name>TXINV</name>
              <bitOffset>17</bitOffset>
              <bitWidth>1</bitWidth>
            </field>
            <field>
              <name>DATAINV</name>
              <bitOffset>18</bitOffset>
              <bitWidth>1</bitWidth>
            </field>
            <field>
              <name>MSBFIRST</name>
              <bitOffset>19</bitOffset>
              <bitWidth>1</bitWidth>
            </field>
            <field>
              <name>ABREN</name>
              <bitOffset>20</bitOffset>
              <bitWidth>1</bitWidth>
            </field>
            <field>
              <name>ABRMODE</name>
              <bitOffset>21</bitOffset>
              <bitWidth>2</bitWidth>
            </field>
            <field>
              <name>RTOEN</name>
              <bitOffset>23</bitOffset>
              <bitWidth>1</bitWidth>
            </field>
            <field>
              <name>ADD</name>
              <bitOffset>24</bitOffset>
              <bitWidth>8</bitWidth>
            </field>
          </fields>
        </register>
        <register>
          <name>CR3</name>
          <addressOffset>0x8</addressOffset>
          <size>0x20</size>
          <fields>
            <field>
              <name>EIE</name>
              <bitOffset>0</bitOffset>
              <bitWidth>1</bitWidth>
            </field>
            <field>
              <name>IREN</name>
              <bitOffset>1</bitOffset>
              <bitWidth>1</bitWidth>
            </field>
            <field>
              <name>IRLP</name>
              <bitOffset>2</bitOffset>
              <bitWidth>1</bitWidth>
            </field>
            <field>
              <name>HDSEL</name>
              <bitOffset>3</bitOffset>
              <bitWidth>1</bitWidth>
            </field>
            <field>
              <name>NACK</name>
              <bitOffset>4</bitOffset>
              <bitWidth>1</bitWidth>
            </field>
            <field>
              <name>SCEN</name>
              <bitOffset>5</bitOffset>
              <bitWidth>1</bitWidth>
            </field>
            <field>
              <name>DMAR</name>
              <bitOffset>6</bitOffset>
              <bitWidth>1</bitWidth>
            </field>
            <field>
              <name>DMAT</name>
              <bitOffset>7</bitOffset>
              <bitWidth>1</bitWidth>
            </field>
            <field>
              <name>RTSE</name>
              <bitOffset>8</bitOffset>
              <bitWidth>1</bitWidth>
            </field>
            <field>
              <name>CTSE</name>
              <bitOffset>9</bitOffset>
              <bitWidth>1</bitWidth>
            </field>
            <field>
              <name>CTSIE</name>
              <bitOffset>10</bitOffset>
              <bitWidth>1</bitWidth>
            </field>
            <field>
              <name>ONEBIT</name>
              <bitOffset>11</bitOffset>
              <bitWidth>1</bitWidth>
            </field>
            <field>
              <name>OVRDIS</name>
              <bitOffset>12</bitOffset>
              <bitWidth>1</bitWidth>
            </field>
            <field>
              <name>DDRE</name>
              <bitOffset>13</bitOffset>
              <bitWidth>1</bitWidth>
            </field>
            <field>
              <name>DEM</name>
              <bitOffset>14</bitOffset>
              <bitWidth>1</bitWidth>
            </field>
            <field>
              <name>DEP</name>
              <bitOffset>15</bitOffset>
              <bitWidth>1</bitWidth>
            </field>
            <field>
              <name>SCARCNT</name>
              <bitOffset>17</bitOffset>
              <bitWidth>3</bitWidth>
            </field>
            <field>
              <name>WUS</name>
              <bitOffset>20</bitOffset>
              <bitWidth>2</bitWidth>
            </field>
            <field>
              <name>WUFIE</name>
              <bitOffset>22</bitOffset>
              <bitWidth>1</bitWidth>
            </field>
            <field>
              <name>UCESM</name>
              <bitOffset>23</bitOffset>
              <bitWidth>1</bitWidth>
            </field>
          </fields>
        </register>
        <register>
          <name>BRR</name>
          <addressOffset>0xc</addressOffset>
          <size>0x20</size>
          <fields>
            <field>
              <name>DIV_FRACTION</name>
              <bitOffset>0</bitOffset>
              <bitWidth>4</bitWidth>
            </field>
            <field>
              <name>DIV_MANTISSA</name>
              <bitOffset>4</bitOffset>
              <bitWidth>12</bitWidth>
            </field>
          </fields>
        </register>
        <register>
          <name>GTPR</name>
          <addressOffset>0x10</addressOffset>
          <size>0x20</size>
          <fields>
            <field>
              <name>PSC</name>
              <bitOffset>0</bitOffset>
              <bitWidth>8</bitWidth>
            </field>
            <field>
              <name>GT</name>
              <bitOffset>8</bitOffset>
              <bitWidth>8</bitWidth>
            </field>
          </fields>
        </register>
        <register>
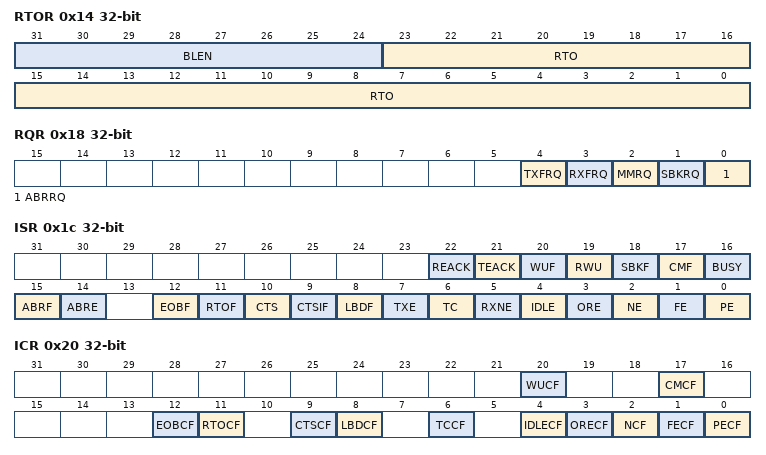
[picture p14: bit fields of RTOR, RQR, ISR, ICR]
          <name>RTOR</name>
          <addressOffset>0x14</addressOffset>
          <size>0x20</size>
          <fields>
            <field>
              <name>RTO</name>
              <bitOffset>0</bitOffset>
              <bitWidth>24</bitWidth>
            </field>
            <field>
              <name>BLEN</name>
              <bitOffset>24</bitOffset>
              <bitWidth>8</bitWidth>
            </field>
          </fields>
        </register>
        <register>
          <name>RQR</name>
          <addressOffset>0x18</addressOffset>
          <size>0x20</size>
          <fields>
            <field>
              <name>ABRRQ</name>
              <bitOffset>0</bitOffset>
              <bitWidth>1</bitWidth>
            </field>
            <field>
              <name>SBKRQ</name>
              <bitOffset>1</bitOffset>
              <bitWidth>1</bitWidth>
            </field>
            <field>
              <name>MMRQ</name>
              <bitOffset>2</bitOffset>
              <bitWidth>1</bitWidth>
            </field>
            <field>
              <name>RXFRQ</name>
              <bitOffset>3</bitOffset>
              <bitWidth>1</bitWidth>
            </field>
            <field>
              <name>TXFRQ</name>
              <bitOffset>4</bitOffset>
              <bitWidth>1</bitWidth>
            </field>
          </fields>
        </register>
        <register>
          <name>ISR</name>
          <addressOffset>0x1c</addressOffset>
          <size>0x20</size>
          <fields>
            <field>
              <name>PE</name>
              <bitOffset>0</bitOffset>
              <bitWidth>1</bitWidth>
            </field>
            <field>
              <name>FE</name>
              <bitOffset>1</bitOffset>
              <bitWidth>1</bitWidth>
            </field>
            <field>
              <name>NE</name>
              <bitOffset>2</bitOffset>
              <bitWidth>1</bitWidth>
            </field>
            <field>
              <name>ORE</name>
              <bitOffset>3</bitOffset>
              <bitWidth>1</bitWidth>
            </field>
            <field>
              <name>IDLE</name>
              <bitOffset>4</bitOffset>
              <bitWidth>1</bitWidth>
            </field>
            <field>
              <name>RXNE</name>
              <bitOffset>5</bitOffset>
              <bitWidth>1</bitWidth>
            </field>
            <field>
              <name>TC</name>
              <bitOffset>6</bitOffset>
              <bitWidth>1</bitWidth>
            </field>
            <field>
              <name>TXE</name>
              <bitOffset>7</bitOffset>
              <bitWidth>1</bitWidth>
            </field>
            <field>
              <name>LBDF</name>
              <bitOffset>8</bitOffset>
              <bitWidth>1</bitWidth>
            </field>
            <field>
              <name>CTSIF</name>
              <bitOffset>9</bitOffset>
              <bitWidth>1</bitWidth>
            </field>
            <field>
              <name>CTS</name>
              <bitOffset>10</bitOffset>
              <bitWidth>1</bitWidth>
            </field>
            <field>
              <name>RTOF</name>
              <bitOffset>11</bitOffset>
              <bitWidth>1</bitWidth>
            </field>
            <field>
              <name>EOBF</name>
              <bitOffset>12</bitOffset>
              <bitWidth>1</bitWidth>
            </field>
            <field>
              <name>ABRE</name>
              <bitOffset>14</bitOffset>
              <bitWidth>1</bitWidth>
            </field>
            <field>
              <name>ABRF</name>
              <bitOffset>15</bitOffset>
              <bitWidth>1</bitWidth>
            </field>
            <field>
              <name>BUSY</name>
              <bitOffset>16</bitOffset>
              <bitWidth>1</bitWidth>
            </field>
            <field>
              <name>CMF</name>
              <bitOffset>17</bitOffset>
              <bitWidth>1</bitWidth>
            </field>
            <field>
              <name>SBKF</name>
              <bitOffset>18</bitOffset>
              <bitWidth>1</bitWidth>
            </field>
            <field>
              <name>RWU</name>
              <bitOffset>19</bitOffset>
              <bitWidth>1</bitWidth>
            </field>
            <field>
              <name>WUF</name>
              <bitOffset>20</bitOffset>
              <bitWidth>1</bitWidth>
            </field>
            <field>
              <name>TEACK</name>
              <bitOffset>21</bitOffset>
              <bitWidth>1</bitWidth>
            </field>
            <field>
              <name>REACK</name>
              <bitOffset>22</bitOffset>
              <bitWidth>1</bitWidth>
            </field>
          </fields>
        </register>
        <register>
          <name>ICR</name>
          <addressOffset>0x20</addressOffset>
          <size>0x20</size>
          <fields>
            <field>
              <name>PECF</name>
              <bitOffset>0</bitOffset>
              <bitWidth>1</bitWidth>
            </field>
            <field>
              <name>FECF</name>
              <bitOffset>1</bitOffset>
              <bitWidth>1</bitWidth>
            </field>
            <field>
              <name>NCF</name>
              <bitOffset>2</bitOffset>
              <bitWidth>1</bitWidth>
            </field>
            <field>
              <name>ORECF</name>
              <bitOffset>3</bitOffset>
              <bitWidth>1</bitWidth>
            </field>
            <field>
              <name>IDLECF</name>
              <bitOffset>4</bitOffset>
              <bitWidth>1</bitWidth>
            </field>
            <field>
              <name>TCCF</name>
              <bitOffset>6</bitOffset>
              <bitWidth>1</bitWidth>
            </field>
            <field>
              <name>LBDCF</name>
              <bitOffset>8</bitOffset>
              <bitWidth>1</bitWidth>
            </field>
            <field>
              <name>CTSCF</name>
              <bitOffset>9</bitOffset>
              <bitWidth>1</bitWidth>
            </field>
            <field>
              <name>RTOCF</name>
              <bitOffset>11</bitOffset>
              <bitWidth>1</bitWidth>
            </field>
            <field>
              <name>EOBCF</name>
              <bitOffset>12</bitOffset>
              <bitWidth>1</bitWidth>
            </field>
            <field>
              <name>CMCF</name>
              <bitOffset>17</bitOffset>
              <bitWidth>1</bitWidth>
            </field>
            <field>
              <name>WUCF</name>
              <bitOffset>20</bitOffset>
              <bitWidth>1</bitWidth>
            </field>
          </fields>
        </register>
        <register>
          <name>RDR</name>
          <addressOffset>0x24</addressOffset>
          <size>0x20</size>
          <fields>
            <field>
              <name>RDR</name>
              <bitOffset>0</bitOffset>
              <bitWidth>9</bitWidth>
            </field>
          </fields>
        </register>
        <register>
          <name>TDR</name>
          <addressOffset>0x28</addressOffset>
          <size>0x20</size>
          <fields>
            <field>
              <name>TDR</name>
              <bitOffset>0</bitOffset>
              <bitWidth>9</bitWidth>
            </field>
          </fields>
        </register>
      </registers>
    </peripheral>
    <peripheral>
      <name>SDMMC2</name>
      <baseAddress>0x40011c00</baseAddress>
      <registers>
        <register>
          <name>POWER</name>
          <addressOffset>0x0</addressOffset>
          <size>0x20</size>
          <fields>
            <field>
              <name>PWRCTRL</name>
              <bitOffset>0</bitOffset>
              <bitWidth>2</bitWidth>
            </field>
          </fields>
        </register>
        <register>
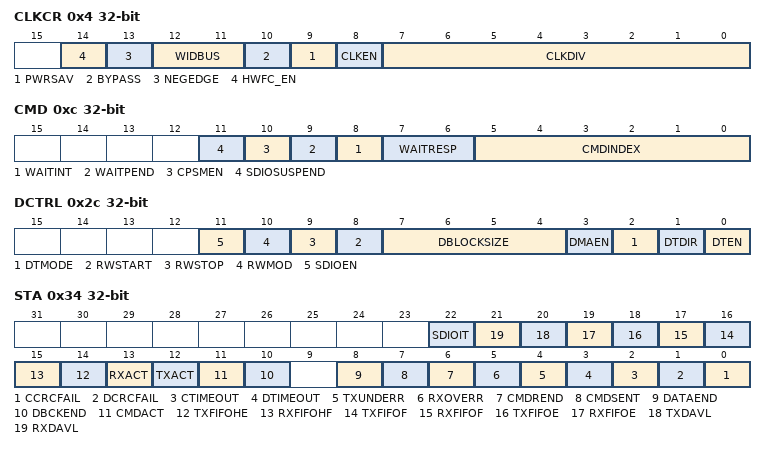
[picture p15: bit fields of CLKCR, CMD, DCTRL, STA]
          <name>CLKCR</name>
          <addressOffset>0x4</addressOffset>
          <size>0x20</size>
          <fields>
            <field>
              <name>CLKDIV</name>
              <bitOffset>0</bitOffset>
              <bitWidth>8</bitWidth>
            </field>
            <field>
              <name>CLKEN</name>
              <bitOffset>8</bitOffset>
              <bitWidth>1</bitWidth>
            </field>
            <field>
              <name>PWRSAV</name>
              <bitOffset>9</bitOffset>
              <bitWidth>1</bitWidth>
            </field>
            <field>
              <name>BYPASS</name>
              <bitOffset>10</bitOffset>
              <bitWidth>1</bitWidth>
            </field>
            <field>
              <name>WIDBUS</name>
              <bitOffset>11</bitOffset>
              <bitWidth>2</bitWidth>
            </field>
            <field>
              <name>NEGEDGE</name>
              <bitOffset>13</bitOffset>
              <bitWidth>1</bitWidth>
            </field>
            <field>
              <name>HWFC_EN</name>
              <bitOffset>14</bitOffset>
              <bitWidth>1</bitWidth>
            </field>
          </fields>
        </register>
        <register>
          <name>ARG</name>
          <addressOffset>0x8</addressOffset>
          <size>0x20</size>
          <fields>
            <field>
              <name>CMDARG</name>
              <bitOffset>0</bitOffset>
              <bitWidth>32</bitWidth>
            </field>
          </fields>
        </register>
        <register>
          <name>CMD</name>
          <addressOffset>0xc</addressOffset>
          <size>0x20</size>
          <fields>
            <field>
              <name>CMDINDEX</name>
              <bitOffset>0</bitOffset>
              <bitWidth>6</bitWidth>
            </field>
            <field>
              <name>WAITRESP</name>
              <bitOffset>6</bitOffset>
              <bitWidth>2</bitWidth>
            </field>
            <field>
              <name>WAITINT</name>
              <bitOffset>8</bitOffset>
              <bitWidth>1</bitWidth>
            </field>
            <field>
              <name>WAITPEND</name>
              <bitOffset>9</bitOffset>
              <bitWidth>1</bitWidth>
            </field>
            <field>
              <name>CPSMEN</name>
              <bitOffset>10</bitOffset>
              <bitWidth>1</bitWidth>
            </field>
            <field>
              <name>SDIOSUSPEND</name>
              <bitOffset>11</bitOffset>
              <bitWidth>1</bitWidth>
            </field>
          </fields>
        </register>
        <register>
          <name>RESPCMD</name>
          <addressOffset>0x10</addressOffset>
          <size>0x20</size>
          <fields>
            <field>
              <name>RESPCMD</name>
              <bitOffset>0</bitOffset>
              <bitWidth>6</bitWidth>
            </field>
          </fields>
        </register>
        <register>
          <name>RESP1</name>
          <addressOffset>0x14</addressOffset>
          <size>0x20</size>
          <fields>
            <field>
              <name>CARDSTATUS1</name>
              <bitOffset>0</bitOffset>
              <bitWidth>32</bitWidth>
            </field>
          </fields>
        </register>
        <register>
          <name>RESP2</name>
          <addressOffset>0x18</addressOffset>
          <size>0x20</size>
          <fields>
            <field>
              <name>CARDSTATUS2</name>
              <bitOffset>0</bitOffset>
              <bitWidth>32</bitWidth>
            </field>
          </fields>
        </register>
        <register>
          <name>RESP3</name>
          <addressOffset>0x1c</addressOffset>
          <size>0x20</size>
          <fields>
            <field>
              <name>CARDSTATUS3</name>
              <bitOffset>0</bitOffset>
              <bitWidth>32</bitWidth>
            </field>
          </fields>
        </register>
        <register>
          <name>RESP4</name>
          <addressOffset>0x20</addressOffset>
          <size>0x20</size>
          <fields>
            <field>
              <name>CARDSTATUS4</name>
              <bitOffset>0</bitOffset>
              <bitWidth>32</bitWidth>
            </field>
          </fields>
        </register>
        <register>
          <name>DTIMER</name>
          <addressOffset>0x24</addressOffset>
          <size>0x20</size>
          <fields>
            <field>
              <name>DATATIME</name>
              <bitOffset>0</bitOffset>
              <bitWidth>32</bitWidth>
            </field>
          </fields>
        </register>
        <register>
          <name>DLEN</name>
          <addressOffset>0x28</addressOffset>
          <size>0x20</size>
          <fields>
            <field>
              <name>DATALENGTH</name>
              <bitOffset>0</bitOffset>
              <bitWidth>25</bitWidth>
            </field>
          </fields>
        </register>
        <register>
          <name>DCTRL</name>
          <addressOffset>0x2c</addressOffset>
          <size>0x20</size>
          <fields>
            <field>
              <name>DTEN</name>
              <bitOffset>0</bitOffset>
              <bitWidth>1</bitWidth>
            </field>
            <field>
              <name>DTDIR</name>
              <bitOffset>1</bitOffset>
              <bitWidth>1</bitWidth>
            </field>
            <field>
              <name>DTMODE</name>
              <bitOffset>2</bitOffset>
              <bitWidth>1</bitWidth>
            </field>
            <field>
              <name>DMAEN</name>
              <bitOffset>3</bitOffset>
              <bitWidth>1</bitWidth>
            </field>
            <field>
              <name>DBLOCKSIZE</name>
              <bitOffset>4</bitOffset>
              <bitWidth>4</bitWidth>
            </field>
            <field>
              <name>RWSTART</name>
              <bitOffset>8</bitOffset>
              <bitWidth>1</bitWidth>
            </field>
            <field>
              <name>RWSTOP</name>
              <bitOffset>9</bitOffset>
              <bitWidth>1</bitWidth>
            </field>
            <field>
              <name>RWMOD</name>
              <bitOffset>10</bitOffset>
              <bitWidth>1</bitWidth>
            </field>
            <field>
              <name>SDIOEN</name>
              <bitOffset>11</bitOffset>
              <bitWidth>1</bitWidth>
            </field>
          </fields>
        </register>
        <register>
          <name>DCOUNT</name>
          <addressOffset>0x30</addressOffset>
          <size>0x20</size>
          <fields>
            <field>
              <name>DATACOUNT</name>
              <bitOffset>0</bitOffset>
              <bitWidth>25</bitWidth>
            </field>
          </fields>
        </register>
        <register>
          <name>STA</name>
          <addressOffset>0x34</addressOffset>
          <size>0x20</size>
          <fields>
            <field>
              <name>CCRCFAIL</name>
              <bitOffset>0</bitOffset>
              <bitWidth>1</bitWidth>
            </field>
            <field>
              <name>DCRCFAIL</name>
              <bitOffset>1</bitOffset>
              <bitWidth>1</bitWidth>
            </field>
            <field>
              <name>CTIMEOUT</name>
              <bitOffset>2</bitOffset>
              <bitWidth>1</bitWidth>
            </field>
            <field>
              <name>DTIMEOUT</name>
              <bitOffset>3</bitOffset>
              <bitWidth>1</bitWidth>
            </field>
            <field>
              <name>TXUNDERR</name>
              <bitOffset>4</bitOffset>
              <bitWidth>1</bitWidth>
            </field>
            <field>
              <name>RXOVERR</name>
              <bitOffset>5</bitOffset>
              <bitWidth>1</bitWidth>
            </field>
            <field>
              <name>CMDREND</name>
              <bitOffset>6</bitOffset>
              <bitWidth>1</bitWidth>
            </field>
            <field>
              <name>CMDSENT</name>
              <bitOffset>7</bitOffset>
              <bitWidth>1</bitWidth>
            </field>
            <field>
              <name>DATAEND</name>
              <bitOffset>8</bitOffset>
              <bitWidth>1</bitWidth>
            </field>
            <field>
              <name>DBCKEND</name>
              <bitOffset>10</bitOffset>
              <bitWidth>1</bitWidth>
            </field>
            <field>
              <name>CMDACT</name>
              <bitOffset>11</bitOffset>
              <bitWidth>1</bitWidth>
            </field>
            <field>
              <name>TXACT</name>
              <bitOffset>12</bitOffset>
              <bitWidth>1</bitWidth>
            </field>
            <field>
              <name>RXACT</name>
              <bitOffset>13</bitOffset>
              <bitWidth>1</bitWidth>
            </field>
            <field>
              <name>TXFIFOHE</name>
              <bitOffset>14</bitOffset>
              <bitWidth>1</bitWidth>
            </field>
            <field>
              <name>RXFIFOHF</name>
              <bitOffset>15</bitOffset>
              <bitWidth>1</bitWidth>
            </field>
            <field>
              <name>TXFIFOF</name>
              <bitOffset>16</bitOffset>
              <bitWidth>1</bitWidth>
            </field>
            <field>
              <name>RXFIFOF</name>
              <bitOffset>17</bitOffset>
              <bitWidth>1</bitWidth>
            </field>
            <field>
              <name>TXFIFOE</name>
              <bitOffset>18</bitOffset>
              <bitWidth>1</bitWidth>
            </field>
            <field>
              <name>RXFIFOE</name>
              <bitOffset>19</bitOffset>
              <bitWidth>1</bitWidth>
            </field>
            <field>
              <name>TXDAVL</name>
              <bitOffset>20</bitOffset>
              <bitWidth>1</bitWidth>
            </field>
            <field>
              <name>RXDAVL</name>
              <bitOffset>21</bitOffset>
              <bitWidth>1</bitWidth>
            </field>
            <field>
              <name>SDIOIT</name>
              <bitOffset>22</bitOffset>
              <bitWidth>1</bitWidth>
            </field>
          </fields>
        </register>
        <register>
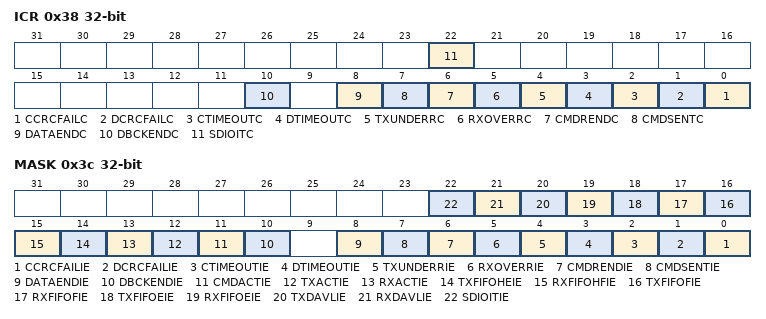
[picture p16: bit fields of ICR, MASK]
          <name>ICR</name>
          <addressOffset>0x38</addressOffset>
          <size>0x20</size>
          <fields>
            <field>
              <name>CCRCFAILC</name>
              <bitOffset>0</bitOffset>
              <bitWidth>1</bitWidth>
            </field>
            <field>
              <name>DCRCFAILC</name>
              <bitOffset>1</bitOffset>
              <bitWidth>1</bitWidth>
            </field>
            <field>
              <name>CTIMEOUTC</name>
              <bitOffset>2</bitOffset>
              <bitWidth>1</bitWidth>
            </field>
            <field>
              <name>DTIMEOUTC</name>
              <bitOffset>3</bitOffset>
              <bitWidth>1</bitWidth>
            </field>
            <field>
              <name>TXUNDERRC</name>
              <bitOffset>4</bitOffset>
              <bitWidth>1</bitWidth>
            </field>
            <field>
              <name>RXOVERRC</name>
              <bitOffset>5</bitOffset>
              <bitWidth>1</bitWidth>
            </field>
            <field>
              <name>CMDRENDC</name>
              <bitOffset>6</bitOffset>
              <bitWidth>1</bitWidth>
            </field>
            <field>
              <name>CMDSENTC</name>
              <bitOffset>7</bitOffset>
              <bitWidth>1</bitWidth>
            </field>
            <field>
              <name>DATAENDC</name>
              <bitOffset>8</bitOffset>
              <bitWidth>1</bitWidth>
            </field>
            <field>
              <name>DBCKENDC</name>
              <bitOffset>10</bitOffset>
              <bitWidth>1</bitWidth>
            </field>
            <field>
              <name>SDIOITC</name>
              <bitOffset>22</bitOffset>
              <bitWidth>1</bitWidth>
            </field>
          </fields>
        </register>
        <register>
          <name>MASK</name>
          <addressOffset>0x3c</addressOffset>
          <size>0x20</size>
          <fields>
            <field>
              <name>CCRCFAILIE</name>
              <bitOffset>0</bitOffset>
              <bitWidth>1</bitWidth>
            </field>
            <field>
              <name>DCRCFAILIE</name>
              <bitOffset>1</bitOffset>
              <bitWidth>1</bitWidth>
            </field>
            <field>
              <name>CTIMEOUTIE</name>
              <bitOffset>2</bitOffset>
              <bitWidth>1</bitWidth>
            </field>
            <field>
              <name>DTIMEOUTIE</name>
              <bitOffset>3</bitOffset>
              <bitWidth>1</bitWidth>
            </field>
            <field>
              <name>TXUNDERRIE</name>
              <bitOffset>4</bitOffset>
              <bitWidth>1</bitWidth>
            </field>
            <field>
              <name>RXOVERRIE</name>
              <bitOffset>5</bitOffset>
              <bitWidth>1</bitWidth>
            </field>
            <field>
              <name>CMDRENDIE</name>
              <bitOffset>6</bitOffset>
              <bitWidth>1</bitWidth>
            </field>
            <field>
              <name>CMDSENTIE</name>
              <bitOffset>7</bitOffset>
              <bitWidth>1</bitWidth>
            </field>
            <field>
              <name>DATAENDIE</name>
              <bitOffset>8</bitOffset>
              <bitWidth>1</bitWidth>
            </field>
            <field>
              <name>DBCKENDIE</name>
              <bitOffset>10</bitOffset>
              <bitWidth>1</bitWidth>
            </field>
            <field>
              <name>CMDACTIE</name>
              <bitOffset>11</bitOffset>
              <bitWidth>1</bitWidth>
            </field>
            <field>
              <name>TXACTIE</name>
              <bitOffset>12</bitOffset>
              <bitWidth>1</bitWidth>
            </field>
            <field>
              <name>RXACTIE</name>
              <bitOffset>13</bitOffset>
              <bitWidth>1</bitWidth>
            </field>
            <field>
              <name>TXFIFOHEIE</name>
              <bitOffset>14</bitOffset>
              <bitWidth>1</bitWidth>
            </field>
            <field>
              <name>RXFIFOHFIE</name>
              <bitOffset>15</bitOffset>
              <bitWidth>1</bitWidth>
            </field>
            <field>
              <name>TXFIFOFIE</name>
              <bitOffset>16</bitOffset>
              <bitWidth>1</bitWidth>
            </field>
            <field>
              <name>RXFIFOFIE</name>
              <bitOffset>17</bitOffset>
              <bitWidth>1</bitWidth>
            </field>
            <field>
              <name>TXFIFOEIE</name>
              <bitOffset>18</bitOffset>
              <bitWidth>1</bitWidth>
            </field>
            <field>
              <name>RXFIFOEIE</name>
              <bitOffset>19</bitOffset>
              <bitWidth>1</bitWidth>
            </field>
            <field>
              <name>TXDAVLIE</name>
              <bitOffset>20</bitOffset>
              <bitWidth>1</bitWidth>
            </field>
            <field>
              <name>RXDAVLIE</name>
              <bitOffset>21</bitOffset>
              <bitWidth>1</bitWidth>
            </field>
            <field>
              <name>SDIOITIE</name>
              <bitOffset>22</bitOffset>
              <bitWidth>1</bitWidth>
            </field>
          </fields>
        </register>
        <register>
          <name>FIFOCNT</name>
          <addressOffset>0x48</addressOffset>
          <size>0x20</size>
          <fields>
            <field>
              <name>FIFOCOUNT</name>
              <bitOffset>0</bitOffset>
              <bitWidth>24</bitWidth>
            </field>
          </fields>
        </register>
        <register>
          <name>FIFO</name>
          <addressOffset>0x80</addressOffset>
          <size>0x20</size>
          <fields>
            <field>
              <name>FIFODATA</name>
              <bitOffset>0</bitOffset>
              <bitWidth>32</bitWidth>
            </field>
          </fields>
        </register>
      </registers>
    </peripheral>
    <peripheral>
      <name>ADC1</name>
      <baseAddress>0x40012000</baseAddress>
      <registers>
        <register>
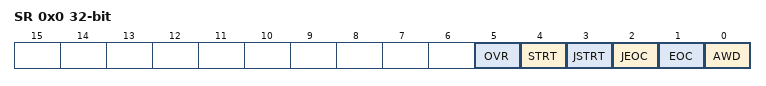
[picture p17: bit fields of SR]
          <name>SR</name>
          <addressOffset>0x0</addressOffset>
          <size>0x20</size>
          <fields>
            <field>
              <name>AWD</name>
              <bitOffset>0</bitOffset>
              <bitWidth>1</bitWidth>
            </field>
            <field>
              <name>EOC</name>
              <bitOffset>1</bitOffset>
              <bitWidth>1</bitWidth>
            </field>
            <field>
              <name>JEOC</name>
              <bitOffset>2</bitOffset>
              <bitWidth>1</bitWidth>
            </field>
            <field>
              <name>JSTRT</name>
              <bitOffset>3</bitOffset>
              <bitWidth>1</bitWidth>
            </field>
            <field>
              <name>STRT</name>
              <bitOffset>4</bitOffset>
              <bitWidth>1</bitWidth>
            </field>
            <field>
              <name>OVR</name>
              <bitOffset>5</bitOffset>
              <bitWidth>1</bitWidth>
            </field>
          </fields>
        </register>
        <register>
          <name>CR1</name>
          <addressOffset>0x4</addressOffset>
          <size>0x20</size>
          <fields>
            <field>
              <name>AWDCH</name>
              <bitOffset>0</bitOffset>
              <bitWidth>5</bitWidth>
            </field>
            <field>
              <name>EOCIE</name>
              <bitOffset>5</bitOffset>
              <bitWidth>1</bitWidth>
            </field>
            <field>
              <name>AWDIE</name>
              <bitOffset>6</bitOffset>
              <bitWidth>1</bitWidth>
            </field>
            <field>
              <name>JEOCIE</name>
              <bitOffset>7</bitOffset>
              <bitWidth>1</bitWidth>
            </field>
            <field>
              <name>SCAN</name>
              <bitOffset>8</bitOffset>
              <bitWidth>1</bitWidth>
            </field>
            <field>
              <name>AWDSGL</name>
              <bitOffset>9</bitOffset>
              <bitWidth>1</bitWidth>
            </field>
            <field>
              <name>JAUTO</name>
              <bitOffset>10</bitOffset>
              <bitWidth>1</bitWidth>
            </field>
            <field>
              <name>DISCEN</name>
              <bitOffset>11</bitOffset>
              <bitWidth>1</bitWidth>
            </field>
            <field>
              <name>JDISCEN</name>
              <bitOffset>12</bitOffset>
              <bitWidth>1</bitWidth>
            </field>
            <field>
              <name>DISCNUM</name>
              <bitOffset>13</bitOffset>
              <bitWidth>3</bitWidth>
            </field>
            <field>
              <name>JAWDEN</name>
              <bitOffset>22</bitOffset>
              <bitWidth>1</bitWidth>
            </field>
            <field>
              <name>AWDEN</name>
              <bitOffset>23</bitOffset>
              <bitWidth>1</bitWidth>
            </field>
            <field>
              <name>RES</name>
              <bitOffset>24</bitOffset>
              <bitWidth>2</bitWidth>
            </field>
            <field>
              <name>OVRIE</name>
              <bitOffset>26</bitOffset>
              <bitWidth>1</bitWidth>
            </field>
          </fields>
        </register>
        <register>
          <name>CR2</name>
          <addressOffset>0x8</addressOffset>
          <size>0x20</size>
          <fields>
            <field>
              <name>ADON</name>
              <bitOffset>0</bitOffset>
              <bitWidth>1</bitWidth>
            </field>
            <field>
              <name>CONT</name>
              <bitOffset>1</bitOffset>
              <bitWidth>1</bitWidth>
            </field>
            <field>
              <name>DMA</name>
              <bitOffset>8</bitOffset>
              <bitWidth>1</bitWidth>
            </field>
            <field>
              <name>DDS</name>
              <bitOffset>9</bitOffset>
              <bitWidth>1</bitWidth>
            </field>
            <field>
              <name>EOCS</name>
              <bitOffset>10</bitOffset>
              <bitWidth>1</bitWidth>
            </field>
            <field>
              <name>ALIGN</name>
              <bitOffset>11</bitOffset>
              <bitWidth>1</bitWidth>
            </field>
            <field>
              <name>JEXTSEL</name>
              <bitOffset>16</bitOffset>
              <bitWidth>4</bitWidth>
            </field>
            <field>
              <name>JEXTEN</name>
              <bitOffset>20</bitOffset>
              <bitWidth>2</bitWidth>
            </field>
            <field>
              <name>JSWSTART</name>
              <bitOffset>22</bitOffset>
              <bitWidth>1</bitWidth>
            </field>
            <field>
              <name>EXTSEL</name>
              <bitOffset>24</bitOffset>
              <bitWidth>4</bitWidth>
            </field>
            <field>
              <name>EXTEN</name>
              <bitOffset>28</bitOffset>
              <bitWidth>2</bitWidth>
            </field>
            <field>
              <name>SWSTART</name>
              <bitOffset>30</bitOffset>
              <bitWidth>1</bitWidth>
            </field>
          </fields>
        </register>
        <register>
          <name>SMPR1</name>
          <addressOffset>0xc</addressOffset>
          <size>0x20</size>
          <fields>
            <field>
              <name>SMP10</name>
              <bitOffset>0</bitOffset>
              <bitWidth>3</bitWidth>
            </field>
            <field>
              <name>SMP11</name>
              <bitOffset>3</bitOffset>
              <bitWidth>3</bitWidth>
            </field>
            <field>
              <name>SMP12</name>
              <bitOffset>6</bitOffset>
              <bitWidth>3</bitWidth>
            </field>
            <field>
              <name>SMP13</name>
              <bitOffset>9</bitOffset>
              <bitWidth>3</bitWidth>
            </field>
            <field>
              <name>SMP14</name>
              <bitOffset>12</bitOffset>
              <bitWidth>3</bitWidth>
            </field>
            <field>
              <name>SMP15</name>
              <bitOffset>15</bitOffset>
              <bitWidth>3</bitWidth>
            </field>
            <field>
              <name>SMP16</name>
              <bitOffset>18</bitOffset>
              <bitWidth>3</bitWidth>
            </field>
            <field>
              <name>SMP17</name>
              <bitOffset>21</bitOffset>
              <bitWidth>3</bitWidth>
            </field>
            <field>
              <name>SMP18</name>
              <bitOffset>24</bitOffset>
              <bitWidth>3</bitWidth>
            </field>
          </fields>
        </register>
        <register>
          <name>SMPR2</name>
          <addressOffset>0x10</addressOffset>
          <size>0x20</size>
          <fields>
            <field>
              <name>SMP0</name>
              <bitOffset>0</bitOffset>
              <bitWidth>3</bitWidth>
            </field>
            <field>
              <name>SMP1</name>
              <bitOffset>3</bitOffset>
              <bitWidth>3</bitWidth>
            </field>
            <field>
              <name>SMP2</name>
              <bitOffset>6</bitOffset>
              <bitWidth>3</bitWidth>
            </field>
            <field>
              <name>SMP3</name>
              <bitOffset>9</bitOffset>
              <bitWidth>3</bitWidth>
            </field>
            <field>
              <name>SMP4</name>
              <bitOffset>12</bitOffset>
              <bitWidth>3</bitWidth>
            </field>
            <field>
              <name>SMP5</name>
              <bitOffset>15</bitOffset>
              <bitWidth>3</bitWidth>
            </field>
            <field>
              <name>SMP6</name>
              <bitOffset>18</bitOffset>
              <bitWidth>3</bitWidth>
            </field>
            <field>
              <name>SMP7</name>
              <bitOffset>21</bitOffset>
              <bitWidth>3</bitWidth>
            </field>
            <field>
              <name>SMP8</name>
              <bitOffset>24</bitOffset>
              <bitWidth>3</bitWidth>
            </field>
            <field>
              <name>SMP9</name>
              <bitOffset>27</bitOffset>
              <bitWidth>3</bitWidth>
            </field>
          </fields>
        </register>
        <register>
          <name>JOFR1</name>
          <addressOffset>0x14</addressOffset>
          <size>0x20</size>
          <fields>
            <field>
              <name>JOFFSET1</name>
              <bitOffset>0</bitOffset>
              <bitWidth>12</bitWidth>
            </field>
          </fields>
        </register>
        <register>
          <name>JOFR2</name>
          <addressOffset>0x18</addressOffset>
          <size>0x20</size>
          <fields>
            <field>
              <name>JOFFSET2</name>
              <bitOffset>0</bitOffset>
              <bitWidth>12</bitWidth>
            </field>
          </fields>
        </register>
        <register>
          <name>JOFR3</name>
          <addressOffset>0x1c</addressOffset>
          <size>0x20</size>
          <fields>
            <field>
              <name>JOFFSET3</name>
              <bitOffset>0</bitOffset>
              <bitWidth>12</bitWidth>
            </field>
          </fields>
        </register>
        <register>
          <name>JOFR4</name>
          <addressOffset>0x20</addressOffset>
          <size>0x20</size>
          <fields>
            <field>
              <name>JOFFSET4</name>
              <bitOffset>0</bitOffset>
              <bitWidth>12</bitWidth>
            </field>
          </fields>
        </register>
        <register>
          <name>HTR</name>
          <addressOffset>0x24</addressOffset>
          <size>0x20</size>
          <fields>
            <field>
              <name>HT</name>
              <bitOffset>0</bitOffset>
              <bitWidth>12</bitWidth>
            </field>
          </fields>
        </register>
        <register>
          <name>LTR</name>
          <addressOffset>0x28</addressOffset>
          <size>0x20</size>
          <fields>
            <field>
              <name>LT</name>
              <bitOffset>0</bitOffset>
              <bitWidth>12</bitWidth>
            </field>
          </fields>
        </register>
        <register>
          <name>SQR1</name>
          <addressOffset>0x2c</addressOffset>
          <size>0x20</size>
          <fields>
            <field>
              <name>SQ13</name>
              <bitOffset>0</bitOffset>
              <bitWidth>5</bitWidth>
            </field>
            <field>
              <name>SQ14</name>
              <bitOffset>5</bitOffset>
              <bitWidth>5</bitWidth>
            </field>
            <field>
              <name>SQ15</name>
              <bitOffset>10</bitOffset>
              <bitWidth>5</bitWidth>
            </field>
            <field>
              <name>SQ16</name>
              <bitOffset>15</bitOffset>
              <bitWidth>5</bitWidth>
            </field>
            <field>
              <name>L</name>
              <bitOffset>20</bitOffset>
              <bitWidth>4</bitWidth>
            </field>
          </fields>
        </register>
        <register>
          <name>SQR2</name>
          <addressOffset>0x30</addressOffset>
          <size>0x20</size>
          <fields>
            <field>
              <name>SQ7</name>
              <bitOffset>0</bitOffset>
              <bitWidth>5</bitWidth>
            </field>
            <field>
              <name>SQ8</name>
              <bitOffset>5</bitOffset>
              <bitWidth>5</bitWidth>
            </field>
            <field>
              <name>SQ9</name>
              <bitOffset>10</bitOffset>
              <bitWidth>5</bitWidth>
            </field>
            <field>
              <name>SQ10</name>
              <bitOffset>15</bitOffset>
              <bitWidth>5</bitWidth>
            </field>
            <field>
              <name>SQ11</name>
              <bitOffset>20</bitOffset>
              <bitWidth>5</bitWidth>
            </field>
            <field>
              <name>SQ12</name>
              <bitOffset>25</bitOffset>
              <bitWidth>5</bitWidth>
            </field>
          </fields>
        </register>
        <register>
          <name>SQR3</name>
          <addressOffset>0x34</addressOffset>
          <size>0x20</size>
          <fields>
            <field>
              <name>SQ1</name>
              <bitOffset>0</bitOffset>
              <bitWidth>5</bitWidth>
            </field>
            <field>
              <name>SQ2</name>
              <bitOffset>5</bitOffset>
              <bitWidth>5</bitWidth>
            </field>
            <field>
              <name>SQ3</name>
              <bitOffset>10</bitOffset>
              <bitWidth>5</bitWidth>
            </field>
            <field>
              <name>SQ4</name>
              <bitOffset>15</bitOffset>
              <bitWidth>5</bitWidth>
            </field>
            <field>
              <name>SQ5</name>
              <bitOffset>20</bitOffset>
              <bitWidth>5</bitWidth>
            </field>
            <field>
              <name>SQ6</name>
              <bitOffset>25</bitOffset>
              <bitWidth>5</bitWidth>
            </field>
          </fields>
        </register>
        <register>
          <name>JSQR</name>
          <addressOffset>0x38</addressOffset>
          <size>0x20</size>
          <fields>
            <field>
              <name>JSQ1</name>
              <bitOffset>0</bitOffset>
              <bitWidth>5</bitWidth>
            </field>
            <field>
              <name>JSQ2</name>
              <bitOffset>5</bitOffset>
              <bitWidth>5</bitWidth>
            </field>
            <field>
              <name>JSQ3</name>
              <bitOffset>10</bitOffset>
              <bitWidth>5</bitWidth>
            </field>
            <field>
              <name>JSQ4</name>
              <bitOffset>15</bitOffset>
              <bitWidth>5</bitWidth>
            </field>
            <field>
              <name>JL</name>
              <bitOffset>20</bitOffset>
              <bitWidth>2</bitWidth>
            </field>
          </fields>
        </register>
        <register>
          <name>JDR1</name>
          <addressOffset>0x3c</addressOffset>
          <size>0x20</size>
        </register>
        <register>
          <name>JDR2</name>
          <addressOffset>0x40</addressOffset>
          <size>0x20</size>
        </register>
        <register>
          <name>JDR3</name>
          <addressOffset>0x44</addressOffset>
          <size>0x20</size>
        </register>
        <register>
          <name>JDR4</name>
          <addressOffset>0x48</addressOffset>
          <size>0x20</size>
        </register>
        <register>
          <name>DR</name>
          <addressOffset>0x4c</addressOffset>
          <size>0x20</size>
          <fields>
            <field>
              <name>DATA</name>
              <bitOffset>0</bitOffset>
              <bitWidth>16</bitWidth>
            </field>
            <field>
              <name>ADC2DATA</name>
              <bitOffset>16</bitOffset>
              <bitWidth>16</bitWidth>
            </field>
          </fields>
        </register>
      </registers>
    </peripheral>
    <peripheral>
      <name>ADC2</name>
      <baseAddress>0x40012100</baseAddress>
      <registers>
        <register>
          <name>SR</name>
          <addressOffset>0x0</addressOffset>
          <size>0x20</size>
          <fields>
            <field>
              <name>AWD</name>
              <bitOffset>0</bitOffset>
              <bitWidth>1</bitWidth>
            </field>
            <field>
              <name>EOC</name>
              <bitOffset>1</bitOffset>
              <bitWidth>1</bitWidth>
            </field>
            <field>
              <name>JEOC</name>
              <bitOffset>2</bitOffset>
              <bitWidth>1</bitWidth>
            </field>
            <field>
              <name>JSTRT</name>
              <bitOffset>3</bitOffset>
              <bitWidth>1</bitWidth>
            </field>
            <field>
              <name>STRT</name>
              <bitOffset>4</bitOffset>
              <bitWidth>1</bitWidth>
            </field>
            <field>
              <name>OVR</name>
              <bitOffset>5</bitOffset>
              <bitWidth>1</bitWidth>
            </field>
          </fields>
        </register>
        <register>
          <name>CR1</name>
          <addressOffset>0x4</addressOffset>
          <size>0x20</size>
          <fields>
            <field>
              <name>AWDCH</name>
              <bitOffset>0</bitOffset>
              <bitWidth>5</bitWidth>
            </field>
            <field>
              <name>EOCIE</name>
              <bitOffset>5</bitOffset>
              <bitWidth>1</bitWidth>
            </field>
            <field>
              <name>AWDIE</name>
              <bitOffset>6</bitOffset>
              <bitWidth>1</bitWidth>
            </field>
            <field>
              <name>JEOCIE</name>
              <bitOffset>7</bitOffset>
              <bitWidth>1</bitWidth>
            </field>
            <field>
              <name>SCAN</name>
              <bitOffset>8</bitOffset>
              <bitWidth>1</bitWidth>
            </field>
            <field>
              <name>AWDSGL</name>
              <bitOffset>9</bitOffset>
              <bitWidth>1</bitWidth>
            </field>
            <field>
              <name>JAUTO</name>
              <bitOffset>10</bitOffset>
              <bitWidth>1</bitWidth>
            </field>
            <field>
              <name>DISCEN</name>
              <bitOffset>11</bitOffset>
              <bitWidth>1</bitWidth>
            </field>
            <field>
              <name>JDISCEN</name>
              <bitOffset>12</bitOffset>
              <bitWidth>1</bitWidth>
            </field>
            <field>
              <name>DISCNUM</name>
              <bitOffset>13</bitOffset>
              <bitWidth>3</bitWidth>
            </field>
            <field>
              <name>JAWDEN</name>
              <bitOffset>22</bitOffset>
              <bitWidth>1</bitWidth>
            </field>
            <field>
              <name>AWDEN</name>
              <bitOffset>23</bitOffset>
              <bitWidth>1</bitWidth>
            </field>
            <field>
              <name>RES</name>
              <bitOffset>24</bitOffset>
              <bitWidth>2</bitWidth>
            </field>
            <field>
              <name>OVRIE</name>
              <bitOffset>26</bitOffset>
              <bitWidth>1</bitWidth>
            </field>
          </fields>
        </register>
        <register>
          <name>CR2</name>
          <addressOffset>0x8</addressOffset>
          <size>0x20</size>
          <fields>
            <field>
              <name>ADON</name>
              <bitOffset>0</bitOffset>
              <bitWidth>1</bitWidth>
            </field>
            <field>
              <name>CONT</name>
              <bitOffset>1</bitOffset>
              <bitWidth>1</bitWidth>
            </field>
            <field>
              <name>DMA</name>
              <bitOffset>8</bitOffset>
              <bitWidth>1</bitWidth>
            </field>
            <field>
              <name>DDS</name>
              <bitOffset>9</bitOffset>
              <bitWidth>1</bitWidth>
            </field>
            <field>
              <name>EOCS</name>
              <bitOffset>10</bitOffset>
              <bitWidth>1</bitWidth>
            </field>
            <field>
              <name>ALIGN</name>
              <bitOffset>11</bitOffset>
              <bitWidth>1</bitWidth>
            </field>
            <field>
              <name>JEXTSEL</name>
              <bitOffset>16</bitOffset>
              <bitWidth>4</bitWidth>
            </field>
            <field>
              <name>JEXTEN</name>
              <bitOffset>20</bitOffset>
              <bitWidth>2</bitWidth>
            </field>
            <field>
              <name>JSWSTART</name>
              <bitOffset>22</bitOffset>
              <bitWidth>1</bitWidth>
            </field>
            <field>
              <name>EXTSEL</name>
              <bitOffset>24</bitOffset>
              <bitWidth>4</bitWidth>
            </field>
            <field>
              <name>EXTEN</name>
              <bitOffset>28</bitOffset>
              <bitWidth>2</bitWidth>
            </field>
            <field>
              <name>SWSTART</name>
              <bitOffset>30</bitOffset>
              <bitWidth>1</bitWidth>
            </field>
          </fields>
        </register>
        <register>
          <name>SMPR1</name>
          <addressOffset>0xc</addressOffset>
          <size>0x20</size>
          <fields>
            <field>
              <name>SMP10</name>
              <bitOffset>0</bitOffset>
              <bitWidth>3</bitWidth>
            </field>
            <field>
              <name>SMP11</name>
              <bitOffset>3</bitOffset>
              <bitWidth>3</bitWidth>
            </field>
            <field>
              <name>SMP12</name>
              <bitOffset>6</bitOffset>
              <bitWidth>3</bitWidth>
            </field>
            <field>
              <name>SMP13</name>
              <bitOffset>9</bitOffset>
              <bitWidth>3</bitWidth>
            </field>
            <field>
              <name>SMP14</name>
              <bitOffset>12</bitOffset>
              <bitWidth>3</bitWidth>
            </field>
            <field>
              <name>SMP15</name>
              <bitOffset>15</bitOffset>
              <bitWidth>3</bitWidth>
            </field>
            <field>
              <name>SMP16</name>
              <bitOffset>18</bitOffset>
              <bitWidth>3</bitWidth>
            </field>
            <field>
              <name>SMP17</name>
              <bitOffset>21</bitOffset>
              <bitWidth>3</bitWidth>
            </field>
            <field>
              <name>SMP18</name>
              <bitOffset>24</bitOffset>
              <bitWidth>3</bitWidth>
            </field>
          </fields>
        </register>
        <register>
          <name>SMPR2</name>
          <addressOffset>0x10</addressOffset>
          <size>0x20</size>
          <fields>
            <field>
              <name>SMP0</name>
              <bitOffset>0</bitOffset>
              <bitWidth>3</bitWidth>
            </field>
            <field>
              <name>SMP1</name>
              <bitOffset>3</bitOffset>
              <bitWidth>3</bitWidth>
            </field>
            <field>
              <name>SMP2</name>
              <bitOffset>6</bitOffset>
              <bitWidth>3</bitWidth>
            </field>
            <field>
              <name>SMP3</name>
              <bitOffset>9</bitOffset>
              <bitWidth>3</bitWidth>
            </field>
            <field>
              <name>SMP4</name>
              <bitOffset>12</bitOffset>
              <bitWidth>3</bitWidth>
            </field>
            <field>
              <name>SMP5</name>
              <bitOffset>15</bitOffset>
              <bitWidth>3</bitWidth>
            </field>
            <field>
              <name>SMP6</name>
              <bitOffset>18</bitOffset>
              <bitWidth>3</bitWidth>
            </field>
            <field>
              <name>SMP7</name>
              <bitOffset>21</bitOffset>
              <bitWidth>3</bitWidth>
            </field>
            <field>
              <name>SMP8</name>
              <bitOffset>24</bitOffset>
              <bitWidth>3</bitWidth>
            </field>
            <field>
              <name>SMP9</name>
              <bitOffset>27</bitOffset>
              <bitWidth>3</bitWidth>
            </field>
          </fields>
        </register>
        <register>
          <name>JOFR1</name>
          <addressOffset>0x14</addressOffset>
          <size>0x20</size>
          <fields>
            <field>
              <name>JOFFSET1</name>
              <bitOffset>0</bitOffset>
              <bitWidth>12</bitWidth>
            </field>
          </fields>
        </register>
        <register>
          <name>JOFR2</name>
          <addressOffset>0x18</addressOffset>
          <size>0x20</size>
          <fields>
            <field>
              <name>JOFFSET2</name>
              <bitOffset>0</bitOffset>
              <bitWidth>12</bitWidth>
            </field>
          </fields>
        </register>
        <register>
          <name>JOFR3</name>
          <addressOffset>0x1c</addressOffset>
          <size>0x20</size>
          <fields>
            <field>
              <name>JOFFSET3</name>
              <bitOffset>0</bitOffset>
              <bitWidth>12</bitWidth>
            </field>
          </fields>
        </register>
        <register>
          <name>JOFR4</name>
          <addressOffset>0x20</addressOffset>
          <size>0x20</size>
          <fields>
            <field>
              <name>JOFFSET4</name>
              <bitOffset>0</bitOffset>
              <bitWidth>12</bitWidth>
            </field>
          </fields>
        </register>
        <register>
          <name>HTR</name>
          <addressOffset>0x24</addressOffset>
          <size>0x20</size>
          <fields>
            <field>
              <name>HT</name>
              <bitOffset>0</bitOffset>
              <bitWidth>12</bitWidth>
            </field>
          </fields>
        </register>
        <register>
          <name>LTR</name>
          <addressOffset>0x28</addressOffset>
          <size>0x20</size>
          <fields>
            <field>
              <name>LT</name>
              <bitOffset>0</bitOffset>
              <bitWidth>12</bitWidth>
            </field>
          </fields>
        </register>
        <register>
          <name>SQR1</name>
          <addressOffset>0x2c</addressOffset>
          <size>0x20</size>
          <fields>
            <field>
              <name>SQ13</name>
              <bitOffset>0</bitOffset>
              <bitWidth>5</bitWidth>
            </field>
            <field>
              <name>SQ14</name>
              <bitOffset>5</bitOffset>
              <bitWidth>5</bitWidth>
            </field>
            <field>
              <name>SQ15</name>
              <bitOffset>10</bitOffset>
              <bitWidth>5</bitWidth>
            </field>
            <field>
              <name>SQ16</name>
              <bitOffset>15</bitOffset>
              <bitWidth>5</bitWidth>
            </field>
            <field>
              <name>L</name>
              <bitOffset>20</bitOffset>
              <bitWidth>4</bitWidth>
            </field>
          </fields>
        </register>
        <register>
          <name>SQR2</name>
          <addressOffset>0x30</addressOffset>
          <size>0x20</size>
          <fields>
            <field>
              <name>SQ7</name>
              <bitOffset>0</bitOffset>
              <bitWidth>5</bitWidth>
            </field>
            <field>
              <name>SQ8</name>
              <bitOffset>5</bitOffset>
              <bitWidth>5</bitWidth>
            </field>
            <field>
              <name>SQ9</name>
              <bitOffset>10</bitOffset>
              <bitWidth>5</bitWidth>
            </field>
            <field>
              <name>SQ10</name>
              <bitOffset>15</bitOffset>
              <bitWidth>5</bitWidth>
            </field>
            <field>
              <name>SQ11</name>
              <bitOffset>20</bitOffset>
              <bitWidth>5</bitWidth>
            </field>
            <field>
              <name>SQ12</name>
              <bitOffset>25</bitOffset>
              <bitWidth>5</bitWidth>
            </field>
          </fields>
        </register>
        <register>
          <name>SQR3</name>
          <addressOffset>0x34</addressOffset>
          <size>0x20</size>
          <fields>
            <field>
              <name>SQ1</name>
              <bitOffset>0</bitOffset>
              <bitWidth>5</bitWidth>
            </field>
            <field>
              <name>SQ2</name>
              <bitOffset>5</bitOffset>
              <bitWidth>5</bitWidth>
            </field>
            <field>
              <name>SQ3</name>
              <bitOffset>10</bitOffset>
              <bitWidth>5</bitWidth>
            </field>
            <field>
              <name>SQ4</name>
              <bitOffset>15</bitOffset>
              <bitWidth>5</bitWidth>
            </field>
            <field>
              <name>SQ5</name>
              <bitOffset>20</bitOffset>
              <bitWidth>5</bitWidth>
            </field>
            <field>
              <name>SQ6</name>
              <bitOffset>25</bitOffset>
              <bitWidth>5</bitWidth>
            </field>
          </fields>
        </register>
        <register>
          <name>JSQR</name>
          <addressOffset>0x38</addressOffset>
          <size>0x20</size>
          <fields>
            <field>
              <name>JSQ1</name>
              <bitOffset>0</bitOffset>
              <bitWidth>5</bitWidth>
            </field>
            <field>
              <name>JSQ2</name>
              <bitOffset>5</bitOffset>
              <bitWidth>5</bitWidth>
            </field>
            <field>
              <name>JSQ3</name>
              <bitOffset>10</bitOffset>
              <bitWidth>5</bitWidth>
            </field>
            <field>
              <name>JSQ4</name>
              <bitOffset>15</bitOffset>
              <bitWidth>5</bitWidth>
            </field>
            <field>
              <name>JL</name>
              <bitOffset>20</bitOffset>
              <bitWidth>2</bitWidth>
            </field>
          </fields>
        </register>
        <register>
          <name>JDR1</name>
          <addressOffset>0x3c</addressOffset>
          <size>0x20</size>
        </register>
        <register>
          <name>JDR2</name>
          <addressOffset>0x40</addressOffset>
          <size>0x20</size>
        </register>
        <register>
          <name>JDR3</name>
          <addressOffset>0x44</addressOffset>
          <size>0x20</size>
        </register>
        <register>
          <name>JDR4</name>
          <addressOffset>0x48</addressOffset>
          <size>0x20</size>
        </register>
        <register>
          <name>DR</name>
          <addressOffset>0x4c</addressOffset>
          <size>0x20</size>
          <fields>
            <field>
              <name>DATA</name>
              <bitOffset>0</bitOffset>
              <bitWidth>16</bitWidth>
            </field>
            <field>
              <name>ADC2DATA</name>
              <bitOffset>16</bitOffset>
              <bitWidth>16</bitWidth>
            </field>
          </fields>
        </register>
      </registers>
    </peripheral>
    <peripheral>
      <name>ADC3</name>
      <baseAddress>0x40012200</baseAddress>
      <registers>
        <register>
          <name>SR</name>
          <addressOffset>0x0</addressOffset>
          <size>0x20</size>
          <fields>
            <field>
              <name>AWD</name>
              <bitOffset>0</bitOffset>
              <bitWidth>1</bitWidth>
            </field>
            <field>
              <name>EOC</name>
              <bitOffset>1</bitOffset>
              <bitWidth>1</bitWidth>
            </field>
            <field>
              <name>JEOC</name>
              <bitOffset>2</bitOffset>
              <bitWidth>1</bitWidth>
            </field>
            <field>
              <name>JSTRT</name>
              <bitOffset>3</bitOffset>
              <bitWidth>1</bitWidth>
            </field>
            <field>
              <name>STRT</name>
              <bitOffset>4</bitOffset>
              <bitWidth>1</bitWidth>
            </field>
            <field>
              <name>OVR</name>
              <bitOffset>5</bitOffset>
              <bitWidth>1</bitWidth>
            </field>
          </fields>
        </register>
        <register>
          <name>CR1</name>
          <addressOffset>0x4</addressOffset>
          <size>0x20</size>
          <fields>
            <field>
              <name>AWDCH</name>
              <bitOffset>0</bitOffset>
              <bitWidth>5</bitWidth>
            </field>
            <field>
              <name>EOCIE</name>
              <bitOffset>5</bitOffset>
              <bitWidth>1</bitWidth>
            </field>
            <field>
              <name>AWDIE</name>
              <bitOffset>6</bitOffset>
              <bitWidth>1</bitWidth>
            </field>
            <field>
              <name>JEOCIE</name>
              <bitOffset>7</bitOffset>
              <bitWidth>1</bitWidth>
            </field>
            <field>
              <name>SCAN</name>
              <bitOffset>8</bitOffset>
              <bitWidth>1</bitWidth>
            </field>
            <field>
              <name>AWDSGL</name>
              <bitOffset>9</bitOffset>
              <bitWidth>1</bitWidth>
            </field>
            <field>
              <name>JAUTO</name>
              <bitOffset>10</bitOffset>
              <bitWidth>1</bitWidth>
            </field>
            <field>
              <name>DISCEN</name>
              <bitOffset>11</bitOffset>
              <bitWidth>1</bitWidth>
            </field>
            <field>
              <name>JDISCEN</name>
              <bitOffset>12</bitOffset>
              <bitWidth>1</bitWidth>
            </field>
            <field>
              <name>DISCNUM</name>
              <bitOffset>13</bitOffset>
              <bitWidth>3</bitWidth>
            </field>
            <field>
              <name>JAWDEN</name>
              <bitOffset>22</bitOffset>
              <bitWidth>1</bitWidth>
            </field>
            <field>
              <name>AWDEN</name>
              <bitOffset>23</bitOffset>
              <bitWidth>1</bitWidth>
            </field>
            <field>
              <name>RES</name>
              <bitOffset>24</bitOffset>
              <bitWidth>2</bitWidth>
            </field>
            <field>
              <name>OVRIE</name>
              <bitOffset>26</bitOffset>
              <bitWidth>1</bitWidth>
            </field>
          </fields>
        </register>
        <register>
          <name>CR2</name>
          <addressOffset>0x8</addressOffset>
          <size>0x20</size>
          <fields>
            <field>
              <name>ADON</name>
              <bitOffset>0</bitOffset>
              <bitWidth>1</bitWidth>
            </field>
            <field>
              <name>CONT</name>
              <bitOffset>1</bitOffset>
              <bitWidth>1</bitWidth>
            </field>
            <field>
              <name>DMA</name>
              <bitOffset>8</bitOffset>
              <bitWidth>1</bitWidth>
            </field>
            <field>
              <name>DDS</name>
              <bitOffset>9</bitOffset>
              <bitWidth>1</bitWidth>
            </field>
            <field>
              <name>EOCS</name>
              <bitOffset>10</bitOffset>
              <bitWidth>1</bitWidth>
            </field>
            <field>
              <name>ALIGN</name>
              <bitOffset>11</bitOffset>
              <bitWidth>1</bitWidth>
            </field>
            <field>
              <name>JEXTSEL</name>
              <bitOffset>16</bitOffset>
              <bitWidth>4</bitWidth>
            </field>
            <field>
              <name>JEXTEN</name>
              <bitOffset>20</bitOffset>
              <bitWidth>2</bitWidth>
            </field>
            <field>
              <name>JSWSTART</name>
              <bitOffset>22</bitOffset>
              <bitWidth>1</bitWidth>
            </field>
            <field>
              <name>EXTSEL</name>
              <bitOffset>24</bitOffset>
              <bitWidth>4</bitWidth>
            </field>
            <field>
              <name>EXTEN</name>
              <bitOffset>28</bitOffset>
              <bitWidth>2</bitWidth>
            </field>
            <field>
              <name>SWSTART</name>
              <bitOffset>30</bitOffset>
              <bitWidth>1</bitWidth>
            </field>
          </fields>
        </register>
        <register>
          <name>SMPR1</name>
          <addressOffset>0xc</addressOffset>
          <size>0x20</size>
          <fields>
            <field>
              <name>SMP10</name>
              <bitOffset>0</bitOffset>
              <bitWidth>3</bitWidth>
            </field>
            <field>
              <name>SMP11</name>
              <bitOffset>3</bitOffset>
              <bitWidth>3</bitWidth>
            </field>
            <field>
              <name>SMP12</name>
              <bitOffset>6</bitOffset>
              <bitWidth>3</bitWidth>
            </field>
            <field>
              <name>SMP13</name>
              <bitOffset>9</bitOffset>
              <bitWidth>3</bitWidth>
            </field>
            <field>
              <name>SMP14</name>
              <bitOffset>12</bitOffset>
              <bitWidth>3</bitWidth>
            </field>
            <field>
              <name>SMP15</name>
              <bitOffset>15</bitOffset>
              <bitWidth>3</bitWidth>
            </field>
            <field>
              <name>SMP16</name>
              <bitOffset>18</bitOffset>
              <bitWidth>3</bitWidth>
            </field>
            <field>
              <name>SMP17</name>
              <bitOffset>21</bitOffset>
              <bitWidth>3</bitWidth>
            </field>
            <field>
              <name>SMP18</name>
              <bitOffset>24</bitOffset>
              <bitWidth>3</bitWidth>
            </field>
          </fields>
        </register>
        <register>
          <name>SMPR2</name>
          <addressOffset>0x10</addressOffset>
          <size>0x20</size>
          <fields>
            <field>
              <name>SMP0</name>
              <bitOffset>0</bitOffset>
              <bitWidth>3</bitWidth>
            </field>
            <field>
              <name>SMP1</name>
              <bitOffset>3</bitOffset>
              <bitWidth>3</bitWidth>
            </field>
            <field>
              <name>SMP2</name>
              <bitOffset>6</bitOffset>
              <bitWidth>3</bitWidth>
            </field>
            <field>
              <name>SMP3</name>
              <bitOffset>9</bitOffset>
              <bitWidth>3</bitWidth>
            </field>
            <field>
              <name>SMP4</name>
              <bitOffset>12</bitOffset>
              <bitWidth>3</bitWidth>
            </field>
            <field>
              <name>SMP5</name>
              <bitOffset>15</bitOffset>
              <bitWidth>3</bitWidth>
            </field>
            <field>
              <name>SMP6</name>
              <bitOffset>18</bitOffset>
              <bitWidth>3</bitWidth>
            </field>
            <field>
              <name>SMP7</name>
              <bitOffset>21</bitOffset>
              <bitWidth>3</bitWidth>
            </field>
            <field>
              <name>SMP8</name>
              <bitOffset>24</bitOffset>
              <bitWidth>3</bitWidth>
            </field>
            <field>
              <name>SMP9</name>
              <bitOffset>27</bitOffset>
              <bitWidth>3</bitWidth>
            </field>
          </fields>
        </register>
        <register>
          <name>JOFR1</name>
          <addressOffset>0x14</addressOffset>
          <size>0x20</size>
          <fields>
            <field>
              <name>JOFFSET1</name>
              <bitOffset>0</bitOffset>
              <bitWidth>12</bitWidth>
            </field>
          </fields>
        </register>
        <register>
          <name>JOFR2</name>
          <addressOffset>0x18</addressOffset>
          <size>0x20</size>
          <fields>
            <field>
              <name>JOFFSET2</name>
              <bitOffset>0</bitOffset>
              <bitWidth>12</bitWidth>
            </field>
          </fields>
        </register>
        <register>
          <name>JOFR3</name>
          <addressOffset>0x1c</addressOffset>
          <size>0x20</size>
          <fields>
            <field>
              <name>JOFFSET3</name>
              <bitOffset>0</bitOffset>
              <bitWidth>12</bitWidth>
            </field>
          </fields>
        </register>
        <register>
          <name>JOFR4</name>
          <addressOffset>0x20</addressOffset>
          <size>0x20</size>
          <fields>
            <field>
              <name>JOFFSET4</name>
              <bitOffset>0</bitOffset>
              <bitWidth>12</bitWidth>
            </field>
          </fields>
        </register>
        <register>
          <name>HTR</name>
          <addressOffset>0x24</addressOffset>
          <size>0x20</size>
          <fields>
            <field>
              <name>HT</name>
              <bitOffset>0</bitOffset>
              <bitWidth>12</bitWidth>
            </field>
          </fields>
        </register>
        <register>
          <name>LTR</name>
          <addressOffset>0x28</addressOffset>
          <size>0x20</size>
          <fields>
            <field>
              <name>LT</name>
              <bitOffset>0</bitOffset>
              <bitWidth>12</bitWidth>
            </field>
          </fields>
        </register>
        <register>
          <name>SQR1</name>
          <addressOffset>0x2c</addressOffset>
          <size>0x20</size>
          <fields>
            <field>
              <name>SQ13</name>
              <bitOffset>0</bitOffset>
              <bitWidth>5</bitWidth>
            </field>
            <field>
              <name>SQ14</name>
              <bitOffset>5</bitOffset>
              <bitWidth>5</bitWidth>
            </field>
            <field>
              <name>SQ15</name>
              <bitOffset>10</bitOffset>
              <bitWidth>5</bitWidth>
            </field>
            <field>
              <name>SQ16</name>
              <bitOffset>15</bitOffset>
              <bitWidth>5</bitWidth>
            </field>
            <field>
              <name>L</name>
              <bitOffset>20</bitOffset>
              <bitWidth>4</bitWidth>
            </field>
          </fields>
        </register>
        <register>
          <name>SQR2</name>
          <addressOffset>0x30</addressOffset>
          <size>0x20</size>
          <fields>
            <field>
              <name>SQ7</name>
              <bitOffset>0</bitOffset>
              <bitWidth>5</bitWidth>
            </field>
            <field>
              <name>SQ8</name>
              <bitOffset>5</bitOffset>
              <bitWidth>5</bitWidth>
            </field>
            <field>
              <name>SQ9</name>
              <bitOffset>10</bitOffset>
              <bitWidth>5</bitWidth>
            </field>
            <field>
              <name>SQ10</name>
              <bitOffset>15</bitOffset>
              <bitWidth>5</bitWidth>
            </field>
            <field>
              <name>SQ11</name>
              <bitOffset>20</bitOffset>
              <bitWidth>5</bitWidth>
            </field>
            <field>
              <name>SQ12</name>
              <bitOffset>25</bitOffset>
              <bitWidth>5</bitWidth>
            </field>
          </fields>
        </register>
        <register>
          <name>SQR3</name>
          <addressOffset>0x34</addressOffset>
          <size>0x20</size>
          <fields>
            <field>
              <name>SQ1</name>
              <bitOffset>0</bitOffset>
              <bitWidth>5</bitWidth>
            </field>
            <field>
              <name>SQ2</name>
              <bitOffset>5</bitOffset>
              <bitWidth>5</bitWidth>
            </field>
            <field>
              <name>SQ3</name>
              <bitOffset>10</bitOffset>
              <bitWidth>5</bitWidth>
            </field>
            <field>
              <name>SQ4</name>
              <bitOffset>15</bitOffset>
              <bitWidth>5</bitWidth>
            </field>
            <field>
              <name>SQ5</name>
              <bitOffset>20</bitOffset>
              <bitWidth>5</bitWidth>
            </field>
            <field>
              <name>SQ6</name>
              <bitOffset>25</bitOffset>
              <bitWidth>5</bitWidth>
            </field>
          </fields>
        </register>
        <register>
          <name>JSQR</name>
          <addressOffset>0x38</addressOffset>
          <size>0x20</size>
          <fields>
            <field>
              <name>JSQ1</name>
              <bitOffset>0</bitOffset>
              <bitWidth>5</bitWidth>
            </field>
            <field>
              <name>JSQ2</name>
              <bitOffset>5</bitOffset>
              <bitWidth>5</bitWidth>
            </field>
            <field>
              <name>JSQ3</name>
              <bitOffset>10</bitOffset>
              <bitWidth>5</bitWidth>
            </field>
            <field>
              <name>JSQ4</name>
              <bitOffset>15</bitOffset>
              <bitWidth>5</bitWidth>
            </field>
            <field>
              <name>JL</name>
              <bitOffset>20</bitOffset>
              <bitWidth>2</bitWidth>
            </field>
          </fields>
        </register>
        <register>
          <name>JDR1</name>
          <addressOffset>0x3c</addressOffset>
          <size>0x20</size>
        </register>
        <register>
          <name>JDR2</name>
          <addressOffset>0x40</addressOffset>
          <size>0x20</size>
        </register>
        <register>
          <name>JDR3</name>
          <addressOffset>0x44</addressOffset>
          <size>0x20</size>
        </register>
        <register>
          <name>JDR4</name>
          <addressOffset>0x48</addressOffset>
          <size>0x20</size>
        </register>
        <register>
          <name>DR</name>
          <addressOffset>0x4c</addressOffset>
          <size>0x20</size>
          <fields>
            <field>
              <name>DATA</name>
              <bitOffset>0</bitOffset>
              <bitWidth>16</bitWidth>
            </field>
            <field>
              <name>ADC2DATA</name>
              <bitOffset>16</bitOffset>
              <bitWidth>16</bitWidth>
            </field>
          </fields>
        </register>
      </registers>
    </peripheral>
    <peripheral>
      <name>ADC</name>
      <baseAddress>0x40012300</baseAddress>
      <registers>
        <register>
          <name>CSR</name>
          <addressOffset>0x0</addressOffset>
          <size>0x20</size>
          <fields>
            <field>
              <name>AWD1</name>
              <bitOffset>0</bitOffset>
              <bitWidth>1</bitWidth>
            </field>
            <field>
              <name>EOC1</name>
              <bitOffset>1</bitOffset>
              <bitWidth>1</bitWidth>
            </field>
            <field>
              <name>JEOC1</name>
              <bitOffset>2</bitOffset>
              <bitWidth>1</bitWidth>
            </field>
            <field>
              <name>JSTRT1</name>
              <bitOffset>3</bitOffset>
              <bitWidth>1</bitWidth>
            </field>
            <field>
              <name>STRT1</name>
              <bitOffset>4</bitOffset>
              <bitWidth>1</bitWidth>
            </field>
            <field>
              <name>OVR1</name>
              <bitOffset>5</bitOffset>
              <bitWidth>1</bitWidth>
            </field>
            <field>
              <name>AWD2</name>
              <bitOffset>8</bitOffset>
              <bitWidth>1</bitWidth>
            </field>
            <field>
              <name>EOC2</name>
              <bitOffset>9</bitOffset>
              <bitWidth>1</bitWidth>
            </field>
            <field>
              <name>JEOC2</name>
              <bitOffset>10</bitOffset>
              <bitWidth>1</bitWidth>
            </field>
            <field>
              <name>JSTRT2</name>
              <bitOffset>11</bitOffset>
              <bitWidth>1</bitWidth>
            </field>
            <field>
              <name>STRT2</name>
              <bitOffset>12</bitOffset>
              <bitWidth>1</bitWidth>
            </field>
            <field>
              <name>OVR2</name>
              <bitOffset>13</bitOffset>
              <bitWidth>1</bitWidth>
            </field>
            <field>
              <name>AWD3</name>
              <bitOffset>16</bitOffset>
              <bitWidth>1</bitWidth>
            </field>
            <field>
              <name>EOC3</name>
              <bitOffset>17</bitOffset>
              <bitWidth>1</bitWidth>
            </field>
            <field>
              <name>JEOC3</name>
              <bitOffset>18</bitOffset>
              <bitWidth>1</bitWidth>
            </field>
            <field>
              <name>JSTRT3</name>
              <bitOffset>19</bitOffset>
              <bitWidth>1</bitWidth>
            </field>
            <field>
              <name>STRT3</name>
              <bitOffset>20</bitOffset>
              <bitWidth>1</bitWidth>
            </field>
            <field>
              <name>OVR3</name>
              <bitOffset>21</bitOffset>
              <bitWidth>1</bitWidth>
            </field>
          </fields>
        </register>
        <register>
          <name>CCR</name>
          <addressOffset>0x4</addressOffset>
          <size>0x20</size>
          <fields>
            <field>
              <name>MULTI</name>
              <bitOffset>0</bitOffset>
              <bitWidth>5</bitWidth>
            </field>
            <field>
              <name>DELAY</name>
              <bitOffset>8</bitOffset>
              <bitWidth>4</bitWidth>
            </field>
            <field>
              <name>DDS</name>
              <bitOffset>13</bitOffset>
              <bitWidth>1</bitWidth>
            </field>
            <field>
              <name>DMA</name>
              <bitOffset>14</bitOffset>
              <bitWidth>2</bitWidth>
            </field>
            <field>
              <name>ADCPRE</name>
              <bitOffset>16</bitOffset>
              <bitWidth>2</bitWidth>
            </field>
            <field>
              <name>VBATE</name>
              <bitOffset>22</bitOffset>
              <bitWidth>1</bitWidth>
            </field>
            <field>
              <name>TSVREFE</name>
              <bitOffset>23</bitOffset>
              <bitWidth>1</bitWidth>
            </field>
          </fields>
        </register>
        <register>
          <name>CDR</name>
          <addressOffset>0x8</addressOffset>
          <size>0x20</size>
          <fields>
            <field>
              <name>DATA1</name>
              <bitOffset>0</bitOffset>
              <bitWidth>16</bitWidth>
            </field>
            <field>
              <name>DATA2</name>
              <bitOffset>16</bitOffset>
              <bitWidth>16</bitWidth>
            </field>
          </fields>
        </register>
      </registers>
    </peripheral>
    <peripheral>
      <name>ADC123_COMMON</name>
      <baseAddress>0x40012300</baseAddress>
      <registers>
        <register>
          <name>CSR</name>
          <addressOffset>0x0</addressOffset>
          <size>0x20</size>
          <fields>
            <field>
              <name>AWD1</name>
              <bitOffset>0</bitOffset>
              <bitWidth>1</bitWidth>
            </field>
            <field>
              <name>EOC1</name>
              <bitOffset>1</bitOffset>
              <bitWidth>1</bitWidth>
            </field>
            <field>
              <name>JEOC1</name>
              <bitOffset>2</bitOffset>
              <bitWidth>1</bitWidth>
            </field>
            <field>
              <name>JSTRT1</name>
              <bitOffset>3</bitOffset>
              <bitWidth>1</bitWidth>
            </field>
            <field>
              <name>STRT1</name>
              <bitOffset>4</bitOffset>
              <bitWidth>1</bitWidth>
            </field>
            <field>
              <name>OVR1</name>
              <bitOffset>5</bitOffset>
              <bitWidth>1</bitWidth>
            </field>
            <field>
              <name>AWD2</name>
              <bitOffset>8</bitOffset>
              <bitWidth>1</bitWidth>
            </field>
            <field>
              <name>EOC2</name>
              <bitOffset>9</bitOffset>
              <bitWidth>1</bitWidth>
            </field>
            <field>
              <name>JEOC2</name>
              <bitOffset>10</bitOffset>
              <bitWidth>1</bitWidth>
            </field>
            <field>
              <name>JSTRT2</name>
              <bitOffset>11</bitOffset>
              <bitWidth>1</bitWidth>
            </field>
            <field>
              <name>STRT2</name>
              <bitOffset>12</bitOffset>
              <bitWidth>1</bitWidth>
            </field>
            <field>
              <name>OVR2</name>
              <bitOffset>13</bitOffset>
              <bitWidth>1</bitWidth>
            </field>
            <field>
              <name>AWD3</name>
              <bitOffset>16</bitOffset>
              <bitWidth>1</bitWidth>
            </field>
            <field>
              <name>EOC3</name>
              <bitOffset>17</bitOffset>
              <bitWidth>1</bitWidth>
            </field>
            <field>
              <name>JEOC3</name>
              <bitOffset>18</bitOffset>
              <bitWidth>1</bitWidth>
            </field>
            <field>
              <name>JSTRT3</name>
              <bitOffset>19</bitOffset>
              <bitWidth>1</bitWidth>
            </field>
            <field>
              <name>STRT3</name>
              <bitOffset>20</bitOffset>
              <bitWidth>1</bitWidth>
            </field>
            <field>
              <name>OVR3</name>
              <bitOffset>21</bitOffset>
              <bitWidth>1</bitWidth>
            </field>
          </fields>
        </register>
        <register>
          <name>CCR</name>
          <addressOffset>0x4</addressOffset>
          <size>0x20</size>
          <fields>
            <field>
              <name>MULTI</name>
              <bitOffset>0</bitOffset>
              <bitWidth>5</bitWidth>
            </field>
            <field>
              <name>DELAY</name>
              <bitOffset>8</bitOffset>
              <bitWidth>4</bitWidth>
            </field>
            <field>
              <name>DDS</name>
              <bitOffset>13</bitOffset>
              <bitWidth>1</bitWidth>
            </field>
            <field>
              <name>DMA</name>
              <bitOffset>14</bitOffset>
              <bitWidth>2</bitWidth>
            </field>
            <field>
              <name>ADCPRE</name>
              <bitOffset>16</bitOffset>
              <bitWidth>2</bitWidth>
            </field>
            <field>
              <name>VBATE</name>
              <bitOffset>22</bitOffset>
              <bitWidth>1</bitWidth>
            </field>
            <field>
              <name>TSVREFE</name>
              <bitOffset>23</bitOffset>
              <bitWidth>1</bitWidth>
            </field>
          </fields>
        </register>
        <register>
          <name>CDR</name>
          <addressOffset>0x8</addressOffset>
          <size>0x20</size>
          <fields>
            <field>
              <name>DATA1</name>
              <bitOffset>0</bitOffset>
              <bitWidth>16</bitWidth>
            </field>
            <field>
              <name>DATA2</name>
              <bitOffset>16</bitOffset>
              <bitWidth>16</bitWidth>
            </field>
          </fields>
        </register>
      </registers>
    </peripheral>
    <peripheral>
      <name>SDMMC1</name>
      <baseAddress>0x40012c00</baseAddress>
      <registers>
        <register>
          <name>POWER</name>
          <addressOffset>0x0</addressOffset>
          <size>0x20</size>
          <fields>
            <field>
              <name>PWRCTRL</name>
              <bitOffset>0</bitOffset>
              <bitWidth>2</bitWidth>
            </field>
          </fields>
        </register>
        <register>
          <name>CLKCR</name>
          <addressOffset>0x4</addressOffset>
          <size>0x20</size>
          <fields>
            <field>
              <name>CLKDIV</name>
              <bitOffset>0</bitOffset>
              <bitWidth>8</bitWidth>
            </field>
            <field>
              <name>CLKEN</name>
              <bitOffset>8</bitOffset>
              <bitWidth>1</bitWidth>
            </field>
            <field>
              <name>PWRSAV</name>
              <bitOffset>9</bitOffset>
              <bitWidth>1</bitWidth>
            </field>
            <field>
              <name>BYPASS</name>
              <bitOffset>10</bitOffset>
              <bitWidth>1</bitWidth>
            </field>
            <field>
              <name>WIDBUS</name>
              <bitOffset>11</bitOffset>
              <bitWidth>2</bitWidth>
            </field>
            <field>
              <name>NEGEDGE</name>
              <bitOffset>13</bitOffset>
              <bitWidth>1</bitWidth>
            </field>
            <field>
              <name>HWFC_EN</name>
              <bitOffset>14</bitOffset>
              <bitWidth>1</bitWidth>
            </field>
          </fields>
        </register>
        <register>
          <name>ARG</name>
          <addressOffset>0x8</addressOffset>
          <size>0x20</size>
          <fields>
            <field>
              <name>CMDARG</name>
              <bitOffset>0</bitOffset>
              <bitWidth>32</bitWidth>
            </field>
          </fields>
        </register>
        <register>
          <name>CMD</name>
          <addressOffset>0xc</addressOffset>
          <size>0x20</size>
          <fields>
            <field>
              <name>CMDINDEX</name>
              <bitOffset>0</bitOffset>
              <bitWidth>6</bitWidth>
            </field>
            <field>
              <name>WAITRESP</name>
              <bitOffset>6</bitOffset>
              <bitWidth>2</bitWidth>
            </field>
            <field>
              <name>WAITINT</name>
              <bitOffset>8</bitOffset>
              <bitWidth>1</bitWidth>
            </field>
            <field>
              <name>WAITPEND</name>
              <bitOffset>9</bitOffset>
              <bitWidth>1</bitWidth>
            </field>
            <field>
              <name>CPSMEN</name>
              <bitOffset>10</bitOffset>
              <bitWidth>1</bitWidth>
            </field>
            <field>
              <name>SDIOSUSPEND</name>
              <bitOffset>11</bitOffset>
              <bitWidth>1</bitWidth>
            </field>
          </fields>
        </register>
        <register>
          <name>RESPCMD</name>
          <addressOffset>0x10</addressOffset>
          <size>0x20</size>
          <fields>
            <field>
              <name>RESPCMD</name>
              <bitOffset>0</bitOffset>
              <bitWidth>6</bitWidth>
            </field>
          </fields>
        </register>
        <register>
          <name>RESP1</name>
          <addressOffset>0x14</addressOffset>
          <size>0x20</size>
          <fields>
            <field>
              <name>CARDSTATUS1</name>
              <bitOffset>0</bitOffset>
              <bitWidth>32</bitWidth>
            </field>
          </fields>
        </register>
        <register>
          <name>RESP2</name>
          <addressOffset>0x18</addressOffset>
          <size>0x20</size>
          <fields>
            <field>
              <name>CARDSTATUS2</name>
              <bitOffset>0</bitOffset>
              <bitWidth>32</bitWidth>
            </field>
          </fields>
        </register>
        <register>
          <name>RESP3</name>
          <addressOffset>0x1c</addressOffset>
          <size>0x20</size>
          <fields>
            <field>
              <name>CARDSTATUS3</name>
              <bitOffset>0</bitOffset>
              <bitWidth>32</bitWidth>
            </field>
          </fields>
        </register>
        <register>
          <name>RESP4</name>
          <addressOffset>0x20</addressOffset>
          <size>0x20</size>
          <fields>
            <field>
              <name>CARDSTATUS4</name>
              <bitOffset>0</bitOffset>
              <bitWidth>32</bitWidth>
            </field>
          </fields>
        </register>
        <register>
          <name>DTIMER</name>
          <addressOffset>0x24</addressOffset>
          <size>0x20</size>
          <fields>
            <field>
              <name>DATATIME</name>
              <bitOffset>0</bitOffset>
              <bitWidth>32</bitWidth>
            </field>
          </fields>
        </register>
        <register>
          <name>DLEN</name>
          <addressOffset>0x28</addressOffset>
          <size>0x20</size>
          <fields>
            <field>
              <name>DATALENGTH</name>
              <bitOffset>0</bitOffset>
              <bitWidth>25</bitWidth>
            </field>
          </fields>
        </register>
        <register>
          <name>DCTRL</name>
          <addressOffset>0x2c</addressOffset>
          <size>0x20</size>
          <fields>
            <field>
              <name>DTEN</name>
              <bitOffset>0</bitOffset>
              <bitWidth>1</bitWidth>
            </field>
            <field>
              <name>DTDIR</name>
              <bitOffset>1</bitOffset>
              <bitWidth>1</bitWidth>
            </field>
            <field>
              <name>DTMODE</name>
              <bitOffset>2</bitOffset>
              <bitWidth>1</bitWidth>
            </field>
            <field>
              <name>DMAEN</name>
              <bitOffset>3</bitOffset>
              <bitWidth>1</bitWidth>
            </field>
            <field>
              <name>DBLOCKSIZE</name>
              <bitOffset>4</bitOffset>
              <bitWidth>4</bitWidth>
            </field>
            <field>
              <name>RWSTART</name>
              <bitOffset>8</bitOffset>
              <bitWidth>1</bitWidth>
            </field>
            <field>
              <name>RWSTOP</name>
              <bitOffset>9</bitOffset>
              <bitWidth>1</bitWidth>
            </field>
            <field>
              <name>RWMOD</name>
              <bitOffset>10</bitOffset>
              <bitWidth>1</bitWidth>
            </field>
            <field>
              <name>SDIOEN</name>
              <bitOffset>11</bitOffset>
              <bitWidth>1</bitWidth>
            </field>
          </fields>
        </register>
        <register>
          <name>DCOUNT</name>
          <addressOffset>0x30</addressOffset>
          <size>0x20</size>
          <fields>
            <field>
              <name>DATACOUNT</name>
              <bitOffset>0</bitOffset>
              <bitWidth>25</bitWidth>
            </field>
          </fields>
        </register>
        <register>
          <name>STA</name>
          <addressOffset>0x34</addressOffset>
          <size>0x20</size>
          <fields>
            <field>
              <name>CCRCFAIL</name>
              <bitOffset>0</bitOffset>
              <bitWidth>1</bitWidth>
            </field>
            <field>
              <name>DCRCFAIL</name>
              <bitOffset>1</bitOffset>
              <bitWidth>1</bitWidth>
            </field>
            <field>
              <name>CTIMEOUT</name>
              <bitOffset>2</bitOffset>
              <bitWidth>1</bitWidth>
            </field>
            <field>
              <name>DTIMEOUT</name>
              <bitOffset>3</bitOffset>
              <bitWidth>1</bitWidth>
            </field>
            <field>
              <name>TXUNDERR</name>
              <bitOffset>4</bitOffset>
              <bitWidth>1</bitWidth>
            </field>
            <field>
              <name>RXOVERR</name>
              <bitOffset>5</bitOffset>
              <bitWidth>1</bitWidth>
            </field>
            <field>
              <name>CMDREND</name>
              <bitOffset>6</bitOffset>
              <bitWidth>1</bitWidth>
            </field>
            <field>
              <name>CMDSENT</name>
              <bitOffset>7</bitOffset>
              <bitWidth>1</bitWidth>
            </field>
            <field>
              <name>DATAEND</name>
              <bitOffset>8</bitOffset>
              <bitWidth>1</bitWidth>
            </field>
            <field>
              <name>DBCKEND</name>
              <bitOffset>10</bitOffset>
              <bitWidth>1</bitWidth>
            </field>
            <field>
              <name>CMDACT</name>
              <bitOffset>11</bitOffset>
              <bitWidth>1</bitWidth>
            </field>
            <field>
              <name>TXACT</name>
              <bitOffset>12</bitOffset>
              <bitWidth>1</bitWidth>
            </field>
            <field>
              <name>RXACT</name>
              <bitOffset>13</bitOffset>
              <bitWidth>1</bitWidth>
            </field>
            <field>
              <name>TXFIFOHE</name>
              <bitOffset>14</bitOffset>
              <bitWidth>1</bitWidth>
            </field>
            <field>
              <name>RXFIFOHF</name>
              <bitOffset>15</bitOffset>
              <bitWidth>1</bitWidth>
            </field>
            <field>
              <name>TXFIFOF</name>
              <bitOffset>16</bitOffset>
              <bitWidth>1</bitWidth>
            </field>
            <field>
              <name>RXFIFOF</name>
              <bitOffset>17</bitOffset>
              <bitWidth>1</bitWidth>
            </field>
            <field>
              <name>TXFIFOE</name>
              <bitOffset>18</bitOffset>
              <bitWidth>1</bitWidth>
            </field>
            <field>
              <name>RXFIFOE</name>
              <bitOffset>19</bitOffset>
              <bitWidth>1</bitWidth>
            </field>
            <field>
              <name>TXDAVL</name>
              <bitOffset>20</bitOffset>
              <bitWidth>1</bitWidth>
            </field>
            <field>
              <name>RXDAVL</name>
              <bitOffset>21</bitOffset>
              <bitWidth>1</bitWidth>
            </field>
            <field>
              <name>SDIOIT</name>
              <bitOffset>22</bitOffset>
              <bitWidth>1</bitWidth>
            </field>
          </fields>
        </register>
        <register>
          <name>ICR</name>
          <addressOffset>0x38</addressOffset>
          <size>0x20</size>
          <fields>
            <field>
              <name>CCRCFAILC</name>
              <bitOffset>0</bitOffset>
              <bitWidth>1</bitWidth>
            </field>
            <field>
              <name>DCRCFAILC</name>
              <bitOffset>1</bitOffset>
              <bitWidth>1</bitWidth>
            </field>
            <field>
              <name>CTIMEOUTC</name>
              <bitOffset>2</bitOffset>
              <bitWidth>1</bitWidth>
            </field>
            <field>
              <name>DTIMEOUTC</name>
              <bitOffset>3</bitOffset>
              <bitWidth>1</bitWidth>
            </field>
            <field>
              <name>TXUNDERRC</name>
              <bitOffset>4</bitOffset>
              <bitWidth>1</bitWidth>
            </field>
            <field>
              <name>RXOVERRC</name>
              <bitOffset>5</bitOffset>
              <bitWidth>1</bitWidth>
            </field>
            <field>
              <name>CMDRENDC</name>
              <bitOffset>6</bitOffset>
              <bitWidth>1</bitWidth>
            </field>
            <field>
              <name>CMDSENTC</name>
              <bitOffset>7</bitOffset>
              <bitWidth>1</bitWidth>
            </field>
            <field>
              <name>DATAENDC</name>
              <bitOffset>8</bitOffset>
              <bitWidth>1</bitWidth>
            </field>
            <field>
              <name>DBCKENDC</name>
              <bitOffset>10</bitOffset>
              <bitWidth>1</bitWidth>
            </field>
            <field>
              <name>SDIOITC</name>
              <bitOffset>22</bitOffset>
              <bitWidth>1</bitWidth>
            </field>
          </fields>
        </register>
        <register>
          <name>MASK</name>
          <addressOffset>0x3c</addressOffset>
          <size>0x20</size>
          <fields>
            <field>
              <name>CCRCFAILIE</name>
              <bitOffset>0</bitOffset>
              <bitWidth>1</bitWidth>
            </field>
            <field>
              <name>DCRCFAILIE</name>
              <bitOffset>1</bitOffset>
              <bitWidth>1</bitWidth>
            </field>
            <field>
              <name>CTIMEOUTIE</name>
              <bitOffset>2</bitOffset>
              <bitWidth>1</bitWidth>
            </field>
            <field>
              <name>DTIMEOUTIE</name>
              <bitOffset>3</bitOffset>
              <bitWidth>1</bitWidth>
            </field>
            <field>
              <name>TXUNDERRIE</name>
              <bitOffset>4</bitOffset>
              <bitWidth>1</bitWidth>
            </field>
            <field>
              <name>RXOVERRIE</name>
              <bitOffset>5</bitOffset>
              <bitWidth>1</bitWidth>
            </field>
            <field>
              <name>CMDRENDIE</name>
              <bitOffset>6</bitOffset>
              <bitWidth>1</bitWidth>
            </field>
            <field>
              <name>CMDSENTIE</name>
              <bitOffset>7</bitOffset>
              <bitWidth>1</bitWidth>
            </field>
            <field>
              <name>DATAENDIE</name>
              <bitOffset>8</bitOffset>
              <bitWidth>1</bitWidth>
            </field>
            <field>
              <name>DBCKENDIE</name>
              <bitOffset>10</bitOffset>
              <bitWidth>1</bitWidth>
            </field>
            <field>
              <name>CMDACTIE</name>
              <bitOffset>11</bitOffset>
              <bitWidth>1</bitWidth>
            </field>
            <field>
              <name>TXACTIE</name>
              <bitOffset>12</bitOffset>
              <bitWidth>1</bitWidth>
            </field>
            <field>
              <name>RXACTIE</name>
              <bitOffset>13</bitOffset>
              <bitWidth>1</bitWidth>
            </field>
            <field>
              <name>TXFIFOHEIE</name>
              <bitOffset>14</bitOffset>
              <bitWidth>1</bitWidth>
            </field>
            <field>
              <name>RXFIFOHFIE</name>
              <bitOffset>15</bitOffset>
              <bitWidth>1</bitWidth>
            </field>
            <field>
              <name>TXFIFOFIE</name>
              <bitOffset>16</bitOffset>
              <bitWidth>1</bitWidth>
            </field>
            <field>
              <name>RXFIFOFIE</name>
              <bitOffset>17</bitOffset>
              <bitWidth>1</bitWidth>
            </field>
            <field>
              <name>TXFIFOEIE</name>
              <bitOffset>18</bitOffset>
              <bitWidth>1</bitWidth>
            </field>
            <field>
              <name>RXFIFOEIE</name>
              <bitOffset>19</bitOffset>
              <bitWidth>1</bitWidth>
            </field>
            <field>
              <name>TXDAVLIE</name>
              <bitOffset>20</bitOffset>
              <bitWidth>1</bitWidth>
            </field>
            <field>
              <name>RXDAVLIE</name>
              <bitOffset>21</bitOffset>
              <bitWidth>1</bitWidth>
            </field>
            <field>
              <name>SDIOITIE</name>
              <bitOffset>22</bitOffset>
              <bitWidth>1</bitWidth>
            </field>
          </fields>
        </register>
        <register>
          <name>FIFOCNT</name>
          <addressOffset>0x48</addressOffset>
          <size>0x20</size>
          <fields>
            <field>
              <name>FIFOCOUNT</name>
              <bitOffset>0</bitOffset>
              <bitWidth>24</bitWidth>
            </field>
          </fields>
        </register>
        <register>
          <name>FIFO</name>
          <addressOffset>0x80</addressOffset>
          <size>0x20</size>
          <fields>
            <field>
              <name>FIFODATA</name>
              <bitOffset>0</bitOffset>
              <bitWidth>32</bitWidth>
            </field>
          </fields>
        </register>
      </registers>
    </peripheral>
    <peripheral>
      <name>SPI1</name>
      <baseAddress>0x40013000</baseAddress>
      <registers>
        <register>
          <name>CR1</name>
          <addressOffset>0x0</addressOffset>
          <size>0x20</size>
          <fields>
            <field>
              <name>CPHA</name>
              <bitOffset>0</bitOffset>
              <bitWidth>1</bitWidth>
            </field>
            <field>
              <name>CPOL</name>
              <bitOffset>1</bitOffset>
              <bitWidth>1</bitWidth>
            </field>
            <field>
              <name>MSTR</name>
              <bitOffset>2</bitOffset>
              <bitWidth>1</bitWidth>
            </field>
            <field>
              <name>BR</name>
              <bitOffset>3</bitOffset>
              <bitWidth>3</bitWidth>
            </field>
            <field>
              <name>SPE</name>
              <bitOffset>6</bitOffset>
              <bitWidth>1</bitWidth>
            </field>
            <field>
              <name>LSBFIRST</name>
              <bitOffset>7</bitOffset>
              <bitWidth>1</bitWidth>
            </field>
            <field>
              <name>SSI</name>
              <bitOffset>8</bitOffset>
              <bitWidth>1</bitWidth>
            </field>
            <field>
              <name>SSM</name>
              <bitOffset>9</bitOffset>
              <bitWidth>1</bitWidth>
            </field>
            <field>
              <name>RXONLY</name>
              <bitOffset>10</bitOffset>
              <bitWidth>1</bitWidth>
            </field>
            <field>
              <name>CRCL</name>
              <bitOffset>11</bitOffset>
              <bitWidth>1</bitWidth>
            </field>
            <field>
              <name>CRCNEXT</name>
              <bitOffset>12</bitOffset>
              <bitWidth>1</bitWidth>
            </field>
            <field>
              <name>CRCEN</name>
              <bitOffset>13</bitOffset>
              <bitWidth>1</bitWidth>
            </field>
            <field>
              <name>BIDIOE</name>
              <bitOffset>14</bitOffset>
              <bitWidth>1</bitWidth>
            </field>
            <field>
              <name>BIDIMODE</name>
              <bitOffset>15</bitOffset>
              <bitWidth>1</bitWidth>
            </field>
          </fields>
        </register>
        <register>
          <name>CR2</name>
          <addressOffset>0x4</addressOffset>
          <size>0x20</size>
          <fields>
            <field>
              <name>RXDMAEN</name>
              <bitOffset>0</bitOffset>
              <bitWidth>1</bitWidth>
            </field>
            <field>
              <name>TXDMAEN</name>
              <bitOffset>1</bitOffset>
              <bitWidth>1</bitWidth>
            </field>
            <field>
              <name>SSOE</name>
              <bitOffset>2</bitOffset>
              <bitWidth>1</bitWidth>
            </field>
            <field>
              <name>NSSP</name>
              <bitOffset>3</bitOffset>
              <bitWidth>1</bitWidth>
            </field>
            <field>
              <name>FRF</name>
              <bitOffset>4</bitOffset>
              <bitWidth>1</bitWidth>
            </field>
            <field>
              <name>ERRIE</name>
              <bitOffset>5</bitOffset>
              <bitWidth>1</bitWidth>
            </field>
            <field>
              <name>RXNEIE</name>
              <bitOffset>6</bitOffset>
              <bitWidth>1</bitWidth>
            </field>
            <field>
              <name>TXEIE</name>
              <bitOffset>7</bitOffset>
              <bitWidth>1</bitWidth>
            </field>
            <field>
              <name>DS</name>
              <bitOffset>8</bitOffset>
              <bitWidth>4</bitWidth>
            </field>
            <field>
              <name>FRXTH</name>
              <bitOffset>12</bitOffset>
              <bitWidth>1</bitWidth>
            </field>
            <field>
              <name>LDMARX</name>
              <bitOffset>13</bitOffset>
              <bitWidth>1</bitWidth>
            </field>
            <field>
              <name>LDMATX</name>
              <bitOffset>14</bitOffset>
              <bitWidth>1</bitWidth>
            </field>
          </fields>
        </register>
        <register>
          <name>SR</name>
          <addressOffset>0x8</addressOffset>
          <size>0x20</size>
          <fields>
            <field>
              <name>RXNE</name>
              <bitOffset>0</bitOffset>
              <bitWidth>1</bitWidth>
            </field>
            <field>
              <name>TXE</name>
              <bitOffset>1</bitOffset>
              <bitWidth>1</bitWidth>
            </field>
            <field>
              <name>CHSIDE</name>
              <bitOffset>2</bitOffset>
              <bitWidth>1</bitWidth>
            </field>
            <field>
              <name>UDR</name>
              <bitOffset>3</bitOffset>
              <bitWidth>1</bitWidth>
            </field>
            <field>
              <name>CRCERR</name>
              <bitOffset>4</bitOffset>
              <bitWidth>1</bitWidth>
            </field>
            <field>
              <name>MODF</name>
              <bitOffset>5</bitOffset>
              <bitWidth>1</bitWidth>
            </field>
            <field>
              <name>OVR</name>
              <bitOffset>6</bitOffset>
              <bitWidth>1</bitWidth>
            </field>
            <field>
              <name>BSY</name>
              <bitOffset>7</bitOffset>
              <bitWidth>1</bitWidth>
            </field>
            <field>
              <name>FRE</name>
              <bitOffset>8</bitOffset>
              <bitWidth>1</bitWidth>
            </field>
            <field>
              <name>FRLVL</name>
              <bitOffset>9</bitOffset>
              <bitWidth>2</bitWidth>
            </field>
            <field>
              <name>FTLVL</name>
              <bitOffset>11</bitOffset>
              <bitWidth>2</bitWidth>
            </field>
          </fields>
        </register>
        <register>
          <name>DR</name>
          <addressOffset>0xc</addressOffset>
          <size>0x20</size>
          <fields>
            <field>
              <name>DR</name>
              <bitOffset>0</bitOffset>
              <bitWidth>16</bitWidth>
            </field>
          </fields>
        </register>
        <register>
          <name>CRCPR</name>
          <addressOffset>0x10</addressOffset>
          <size>0x20</size>
          <fields>
            <field>
              <name>CRCPOLY</name>
              <bitOffset>0</bitOffset>
              <bitWidth>16</bitWidth>
            </field>
          </fields>
        </register>
        <register>
          <name>RXCRCR</name>
          <addressOffset>0x14</addressOffset>
          <size>0x20</size>
          <fields>
            <field>
              <name>RXCRC</name>
              <bitOffset>0</bitOffset>
              <bitWidth>16</bitWidth>
            </field>
          </fields>
        </register>
        <register>
          <name>TXCRCR</name>
          <addressOffset>0x18</addressOffset>
          <size>0x20</size>
          <fields>
            <field>
              <name>TXCRC</name>
              <bitOffset>0</bitOffset>
              <bitWidth>16</bitWidth>
            </field>
          </fields>
        </register>
        <register>
          <name>I2SCFGR</name>
          <addressOffset>0x1c</addressOffset>
          <size>0x20</size>
          <fields>
            <field>
              <name>CHLEN</name>
              <bitOffset>0</bitOffset>
              <bitWidth>1</bitWidth>
            </field>
            <field>
              <name>DATLEN</name>
              <bitOffset>1</bitOffset>
              <bitWidth>2</bitWidth>
            </field>
            <field>
              <name>CKPOL</name>
              <bitOffset>3</bitOffset>
              <bitWidth>1</bitWidth>
            </field>
            <field>
              <name>I2SSTD</name>
              <bitOffset>4</bitOffset>
              <bitWidth>2</bitWidth>
            </field>
            <field>
              <name>PCMSYNC</name>
              <bitOffset>7</bitOffset>
              <bitWidth>1</bitWidth>
            </field>
            <field>
              <name>I2SCFG</name>
              <bitOffset>8</bitOffset>
              <bitWidth>2</bitWidth>
            </field>
            <field>
              <name>I2SE</name>
              <bitOffset>10</bitOffset>
              <bitWidth>1</bitWidth>
            </field>
            <field>
              <name>I2SMOD</name>
              <bitOffset>11</bitOffset>
              <bitWidth>1</bitWidth>
            </field>
            <field>
              <name>ASTRTEN</name>
              <bitOffset>12</bitOffset>
              <bitWidth>1</bitWidth>
            </field>
          </fields>
        </register>
        <register>
          <name>I2SPR</name>
          <addressOffset>0x20</addressOffset>
          <size>0x20</size>
          <fields>
            <field>
              <name>I2SDIV</name>
              <bitOffset>0</bitOffset>
              <bitWidth>8</bitWidth>
            </field>
            <field>
              <name>ODD</name>
              <bitOffset>8</bitOffset>
              <bitWidth>1</bitWidth>
            </field>
            <field>
              <name>MCKOE</name>
              <bitOffset>9</bitOffset>
              <bitWidth>1</bitWidth>
            </field>
          </fields>
        </register>
      </registers>
    </peripheral>
    <peripheral>
      <name>SPI4</name>
      <baseAddress>0x40013400</baseAddress>
      <registers>
        <register>
          <name>CR1</name>
          <addressOffset>0x0</addressOffset>
          <size>0x20</size>
          <fields>
            <field>
              <name>CPHA</name>
              <bitOffset>0</bitOffset>
              <bitWidth>1</bitWidth>
            </field>
            <field>
              <name>CPOL</name>
              <bitOffset>1</bitOffset>
              <bitWidth>1</bitWidth>
            </field>
            <field>
              <name>MSTR</name>
              <bitOffset>2</bitOffset>
              <bitWidth>1</bitWidth>
            </field>
            <field>
              <name>BR</name>
              <bitOffset>3</bitOffset>
              <bitWidth>3</bitWidth>
            </field>
            <field>
              <name>SPE</name>
              <bitOffset>6</bitOffset>
              <bitWidth>1</bitWidth>
            </field>
            <field>
              <name>LSBFIRST</name>
              <bitOffset>7</bitOffset>
              <bitWidth>1</bitWidth>
            </field>
            <field>
              <name>SSI</name>
              <bitOffset>8</bitOffset>
              <bitWidth>1</bitWidth>
            </field>
            <field>
              <name>SSM</name>
              <bitOffset>9</bitOffset>
              <bitWidth>1</bitWidth>
            </field>
            <field>
              <name>RXONLY</name>
              <bitOffset>10</bitOffset>
              <bitWidth>1</bitWidth>
            </field>
            <field>
              <name>CRCL</name>
              <bitOffset>11</bitOffset>
              <bitWidth>1</bitWidth>
            </field>
            <field>
              <name>CRCNEXT</name>
              <bitOffset>12</bitOffset>
              <bitWidth>1</bitWidth>
            </field>
            <field>
              <name>CRCEN</name>
              <bitOffset>13</bitOffset>
              <bitWidth>1</bitWidth>
            </field>
            <field>
              <name>BIDIOE</name>
              <bitOffset>14</bitOffset>
              <bitWidth>1</bitWidth>
            </field>
            <field>
              <name>BIDIMODE</name>
              <bitOffset>15</bitOffset>
              <bitWidth>1</bitWidth>
            </field>
          </fields>
        </register>
        <register>
          <name>CR2</name>
          <addressOffset>0x4</addressOffset>
          <size>0x20</size>
          <fields>
            <field>
              <name>RXDMAEN</name>
              <bitOffset>0</bitOffset>
              <bitWidth>1</bitWidth>
            </field>
            <field>
              <name>TXDMAEN</name>
              <bitOffset>1</bitOffset>
              <bitWidth>1</bitWidth>
            </field>
            <field>
              <name>SSOE</name>
              <bitOffset>2</bitOffset>
              <bitWidth>1</bitWidth>
            </field>
            <field>
              <name>NSSP</name>
              <bitOffset>3</bitOffset>
              <bitWidth>1</bitWidth>
            </field>
            <field>
              <name>FRF</name>
              <bitOffset>4</bitOffset>
              <bitWidth>1</bitWidth>
            </field>
            <field>
              <name>ERRIE</name>
              <bitOffset>5</bitOffset>
              <bitWidth>1</bitWidth>
            </field>
            <field>
              <name>RXNEIE</name>
              <bitOffset>6</bitOffset>
              <bitWidth>1</bitWidth>
            </field>
            <field>
              <name>TXEIE</name>
              <bitOffset>7</bitOffset>
              <bitWidth>1</bitWidth>
            </field>
            <field>
              <name>DS</name>
              <bitOffset>8</bitOffset>
              <bitWidth>4</bitWidth>
            </field>
            <field>
              <name>FRXTH</name>
              <bitOffset>12</bitOffset>
              <bitWidth>1</bitWidth>
            </field>
            <field>
              <name>LDMARX</name>
              <bitOffset>13</bitOffset>
              <bitWidth>1</bitWidth>
            </field>
            <field>
              <name>LDMATX</name>
              <bitOffset>14</bitOffset>
              <bitWidth>1</bitWidth>
            </field>
          </fields>
        </register>
        <register>
          <name>SR</name>
          <addressOffset>0x8</addressOffset>
          <size>0x20</size>
          <fields>
            <field>
              <name>RXNE</name>
              <bitOffset>0</bitOffset>
              <bitWidth>1</bitWidth>
            </field>
            <field>
              <name>TXE</name>
              <bitOffset>1</bitOffset>
              <bitWidth>1</bitWidth>
            </field>
            <field>
              <name>CHSIDE</name>
              <bitOffset>2</bitOffset>
              <bitWidth>1</bitWidth>
            </field>
            <field>
              <name>UDR</name>
              <bitOffset>3</bitOffset>
              <bitWidth>1</bitWidth>
            </field>
            <field>
              <name>CRCERR</name>
              <bitOffset>4</bitOffset>
              <bitWidth>1</bitWidth>
            </field>
            <field>
              <name>MODF</name>
              <bitOffset>5</bitOffset>
              <bitWidth>1</bitWidth>
            </field>
            <field>
              <name>OVR</name>
              <bitOffset>6</bitOffset>
              <bitWidth>1</bitWidth>
            </field>
            <field>
              <name>BSY</name>
              <bitOffset>7</bitOffset>
              <bitWidth>1</bitWidth>
            </field>
            <field>
              <name>FRE</name>
              <bitOffset>8</bitOffset>
              <bitWidth>1</bitWidth>
            </field>
            <field>
              <name>FRLVL</name>
              <bitOffset>9</bitOffset>
              <bitWidth>2</bitWidth>
            </field>
            <field>
              <name>FTLVL</name>
              <bitOffset>11</bitOffset>
              <bitWidth>2</bitWidth>
            </field>
          </fields>
        </register>
        <register>
          <name>DR</name>
          <addressOffset>0xc</addressOffset>
          <size>0x20</size>
          <fields>
            <field>
              <name>DR</name>
              <bitOffset>0</bitOffset>
              <bitWidth>16</bitWidth>
            </field>
          </fields>
        </register>
        <register>
          <name>CRCPR</name>
          <addressOffset>0x10</addressOffset>
          <size>0x20</size>
          <fields>
            <field>
              <name>CRCPOLY</name>
              <bitOffset>0</bitOffset>
              <bitWidth>16</bitWidth>
            </field>
          </fields>
        </register>
        <register>
          <name>RXCRCR</name>
          <addressOffset>0x14</addressOffset>
          <size>0x20</size>
          <fields>
            <field>
              <name>RXCRC</name>
              <bitOffset>0</bitOffset>
              <bitWidth>16</bitWidth>
            </field>
          </fields>
        </register>
        <register>
          <name>TXCRCR</name>
          <addressOffset>0x18</addressOffset>
          <size>0x20</size>
          <fields>
            <field>
              <name>TXCRC</name>
              <bitOffset>0</bitOffset>
              <bitWidth>16</bitWidth>
            </field>
          </fields>
        </register>
        <register>
          <name>I2SCFGR</name>
          <addressOffset>0x1c</addressOffset>
          <size>0x20</size>
          <fields>
            <field>
              <name>CHLEN</name>
              <bitOffset>0</bitOffset>
              <bitWidth>1</bitWidth>
            </field>
            <field>
              <name>DATLEN</name>
              <bitOffset>1</bitOffset>
              <bitWidth>2</bitWidth>
            </field>
            <field>
              <name>CKPOL</name>
              <bitOffset>3</bitOffset>
              <bitWidth>1</bitWidth>
            </field>
            <field>
              <name>I2SSTD</name>
              <bitOffset>4</bitOffset>
              <bitWidth>2</bitWidth>
            </field>
            <field>
              <name>PCMSYNC</name>
              <bitOffset>7</bitOffset>
              <bitWidth>1</bitWidth>
            </field>
            <field>
              <name>I2SCFG</name>
              <bitOffset>8</bitOffset>
              <bitWidth>2</bitWidth>
            </field>
            <field>
              <name>I2SE</name>
              <bitOffset>10</bitOffset>
              <bitWidth>1</bitWidth>
            </field>
            <field>
              <name>I2SMOD</name>
              <bitOffset>11</bitOffset>
              <bitWidth>1</bitWidth>
            </field>
            <field>
              <name>ASTRTEN</name>
              <bitOffset>12</bitOffset>
              <bitWidth>1</bitWidth>
            </field>
          </fields>
        </register>
        <register>
          <name>I2SPR</name>
          <addressOffset>0x20</addressOffset>
          <size>0x20</size>
          <fields>
            <field>
              <name>I2SDIV</name>
              <bitOffset>0</bitOffset>
              <bitWidth>8</bitWidth>
            </field>
            <field>
              <name>ODD</name>
              <bitOffset>8</bitOffset>
              <bitWidth>1</bitWidth>
            </field>
            <field>
              <name>MCKOE</name>
              <bitOffset>9</bitOffset>
              <bitWidth>1</bitWidth>
            </field>
          </fields>
        </register>
      </registers>
    </peripheral>
    <peripheral>
      <name>SYSCFG</name>
      <baseAddress>0x40013800</baseAddress>
      <registers>
        <register>
          <name>MEMRMP</name>
          <addressOffset>0x0</addressOffset>
          <size>0x20</size>
          <fields>
            <field>
              <name>MEM_BOOT</name>
              <bitOffset>0</bitOffset>
              <bitWidth>1</bitWidth>
            </field>
            <field>
              <name>SWP_FB</name>
              <bitOffset>8</bitOffset>
              <bitWidth>1</bitWidth>
            </field>
            <field>
              <name>SWP_FMC</name>
              <bitOffset>10</bitOffset>
              <bitWidth>2</bitWidth>
            </field>
          </fields>
        </register>
        <register>
          <name>PMC</name>
          <addressOffset>0x4</addressOffset>
          <size>0x20</size>
          <fields>
            <field>
              <name>I2C1_FMP</name>
              <bitOffset>0</bitOffset>
              <bitWidth>1</bitWidth>
            </field>
            <field>
              <name>I2C2_FMP</name>
              <bitOffset>1</bitOffset>
              <bitWidth>1</bitWidth>
            </field>
            <field>
              <name>I2C3_FMP</name>
              <bitOffset>2</bitOffset>
              <bitWidth>1</bitWidth>
            </field>
            <field>
              <name>I2C4_FMP</name>
              <bitOffset>3</bitOffset>
              <bitWidth>1</bitWidth>
            </field>
            <field>
              <name>I2C_PB6_FMP</name>
              <bitOffset>4</bitOffset>
              <bitWidth>1</bitWidth>
            </field>
            <field>
              <name>I2C_PB7_FMP</name>
              <bitOffset>5</bitOffset>
              <bitWidth>1</bitWidth>
            </field>
            <field>
              <name>I2C_PB8_FMP</name>
              <bitOffset>6</bitOffset>
              <bitWidth>1</bitWidth>
            </field>
            <field>
              <name>I2C_PB9_FMP</name>
              <bitOffset>7</bitOffset>
              <bitWidth>1</bitWidth>
            </field>
            <field>
              <name>ADCxDC2</name>
              <bitOffset>16</bitOffset>
              <bitWidth>3</bitWidth>
            </field>
            <field>
              <name>ADC2DC2</name>
              <bitOffset>17</bitOffset>
              <bitWidth>1</bitWidth>
            </field>
            <field>
              <name>ADC3DC2</name>
              <bitOffset>18</bitOffset>
              <bitWidth>1</bitWidth>
            </field>
            <field>
              <name>MII_RMII_SEL</name>
              <bitOffset>23</bitOffset>
              <bitWidth>1</bitWidth>
            </field>
          </fields>
        </register>
        <register>
          <name>EXTICR.0</name>
          <addressOffset>0x8</addressOffset>
          <size>0x20</size>
          <fields>
            <field>
              <name>EXTI0</name>
              <bitOffset>0</bitOffset>
              <bitWidth>4</bitWidth>
            </field>
            <field>
              <name>EXTI1</name>
              <bitOffset>4</bitOffset>
              <bitWidth>4</bitWidth>
            </field>
            <field>
              <name>EXTI2</name>
              <bitOffset>8</bitOffset>
              <bitWidth>4</bitWidth>
            </field>
            <field>
              <name>EXTI3</name>
              <bitOffset>12</bitOffset>
              <bitWidth>4</bitWidth>
            </field>
          </fields>
        </register>
        <register>
          <name>EXTICR.1</name>
          <addressOffset>0xc</addressOffset>
          <size>0x20</size>
          <fields>
            <field>
              <name>EXTI4</name>
              <bitOffset>0</bitOffset>
              <bitWidth>4</bitWidth>
            </field>
            <field>
              <name>EXTI5</name>
              <bitOffset>4</bitOffset>
              <bitWidth>4</bitWidth>
            </field>
            <field>
              <name>EXTI6</name>
              <bitOffset>8</bitOffset>
              <bitWidth>4</bitWidth>
            </field>
            <field>
              <name>EXTI7</name>
              <bitOffset>12</bitOffset>
              <bitWidth>4</bitWidth>
            </field>
          </fields>
        </register>
        <register>
          <name>EXTICR.2</name>
          <addressOffset>0x10</addressOffset>
          <size>0x20</size>
          <fields>
            <field>
              <name>EXTI8</name>
              <bitOffset>0</bitOffset>
              <bitWidth>4</bitWidth>
            </field>
            <field>
              <name>EXTI9</name>
              <bitOffset>4</bitOffset>
              <bitWidth>4</bitWidth>
            </field>
            <field>
              <name>EXTI10</name>
              <bitOffset>8</bitOffset>
              <bitWidth>4</bitWidth>
            </field>
            <field>
              <name>EXTI11</name>
              <bitOffset>12</bitOffset>
              <bitWidth>4</bitWidth>
            </field>
          </fields>
        </register>
        <register>
          <name>EXTICR.3</name>
          <addressOffset>0x14</addressOffset>
          <size>0x20</size>
          <fields>
            <field>
              <name>EXTI12</name>
              <bitOffset>0</bitOffset>
              <bitWidth>4</bitWidth>
            </field>
            <field>
              <name>EXTI13</name>
              <bitOffset>4</bitOffset>
              <bitWidth>4</bitWidth>
            </field>
            <field>
              <name>EXTI14</name>
              <bitOffset>8</bitOffset>
              <bitWidth>4</bitWidth>
            </field>
            <field>
              <name>EXTI15</name>
              <bitOffset>12</bitOffset>
              <bitWidth>4</bitWidth>
            </field>
          </fields>
        </register>
        <register>
          <name>CBR</name>
          <addressOffset>0x1c</addressOffset>
          <size>0x20</size>
          <fields>
            <field>
              <name>CLL</name>
              <bitOffset>0</bitOffset>
              <bitWidth>1</bitWidth>
            </field>
            <field>
              <name>PVDL</name>
              <bitOffset>2</bitOffset>
              <bitWidth>1</bitWidth>
            </field>
          </fields>
        </register>
        <register>
          <name>CMPCR</name>
          <addressOffset>0x20</addressOffset>
          <size>0x20</size>
          <fields>
            <field>
              <name>CMP_PD</name>
              <bitOffset>0</bitOffset>
              <bitWidth>1</bitWidth>
            </field>
            <field>
              <name>READY</name>
              <bitOffset>8</bitOffset>
              <bitWidth>1</bitWidth>
            </field>
          </fields>
        </register>
      </registers>
    </peripheral>
    <peripheral>
      <name>EXTI</name>
      <baseAddress>0x40013c00</baseAddress>
      <registers>
        <register>
          <name>IMR</name>
          <addressOffset>0x0</addressOffset>
          <size>0x20</size>
          <fields>
            <field>
              <name>MR0</name>
              <bitOffset>0</bitOffset>
              <bitWidth>1</bitWidth>
            </field>
            <field>
              <name>MR1</name>
              <bitOffset>1</bitOffset>
              <bitWidth>1</bitWidth>
            </field>
            <field>
              <name>MR2</name>
              <bitOffset>2</bitOffset>
              <bitWidth>1</bitWidth>
            </field>
            <field>
              <name>MR3</name>
              <bitOffset>3</bitOffset>
              <bitWidth>1</bitWidth>
            </field>
            <field>
              <name>MR4</name>
              <bitOffset>4</bitOffset>
              <bitWidth>1</bitWidth>
            </field>
            <field>
              <name>MR5</name>
              <bitOffset>5</bitOffset>
              <bitWidth>1</bitWidth>
            </field>
            <field>
              <name>MR6</name>
              <bitOffset>6</bitOffset>
              <bitWidth>1</bitWidth>
            </field>
            <field>
              <name>MR7</name>
              <bitOffset>7</bitOffset>
              <bitWidth>1</bitWidth>
            </field>
            <field>
              <name>MR8</name>
              <bitOffset>8</bitOffset>
              <bitWidth>1</bitWidth>
            </field>
            <field>
              <name>MR9</name>
              <bitOffset>9</bitOffset>
              <bitWidth>1</bitWidth>
            </field>
            <field>
              <name>MR10</name>
              <bitOffset>10</bitOffset>
              <bitWidth>1</bitWidth>
            </field>
            <field>
              <name>MR11</name>
              <bitOffset>11</bitOffset>
              <bitWidth>1</bitWidth>
            </field>
            <field>
              <name>MR12</name>
              <bitOffset>12</bitOffset>
              <bitWidth>1</bitWidth>
            </field>
            <field>
              <name>MR13</name>
              <bitOffset>13</bitOffset>
              <bitWidth>1</bitWidth>
            </field>
            <field>
              <name>MR14</name>
              <bitOffset>14</bitOffset>
              <bitWidth>1</bitWidth>
            </field>
            <field>
              <name>MR15</name>
              <bitOffset>15</bitOffset>
              <bitWidth>1</bitWidth>
            </field>
            <field>
              <name>MR16</name>
              <bitOffset>16</bitOffset>
              <bitWidth>1</bitWidth>
            </field>
            <field>
              <name>MR17</name>
              <bitOffset>17</bitOffset>
              <bitWidth>1</bitWidth>
            </field>
            <field>
              <name>MR18</name>
              <bitOffset>18</bitOffset>
              <bitWidth>1</bitWidth>
            </field>
            <field>
              <name>MR19</name>
              <bitOffset>19</bitOffset>
              <bitWidth>1</bitWidth>
            </field>
            <field>
              <name>MR20</name>
              <bitOffset>20</bitOffset>
              <bitWidth>1</bitWidth>
            </field>
            <field>
              <name>MR21</name>
              <bitOffset>21</bitOffset>
              <bitWidth>1</bitWidth>
            </field>
            <field>
              <name>MR22</name>
              <bitOffset>22</bitOffset>
              <bitWidth>1</bitWidth>
            </field>
            <field>
              <name>MR23</name>
              <bitOffset>23</bitOffset>
              <bitWidth>1</bitWidth>
            </field>
            <field>
              <name>MR24</name>
              <bitOffset>24</bitOffset>
              <bitWidth>1</bitWidth>
            </field>
          </fields>
        </register>
        <register>
          <name>EMR</name>
          <addressOffset>0x4</addressOffset>
          <size>0x20</size>
          <fields>
            <field>
              <name>MR0</name>
              <bitOffset>0</bitOffset>
              <bitWidth>1</bitWidth>
            </field>
            <field>
              <name>MR1</name>
              <bitOffset>1</bitOffset>
              <bitWidth>1</bitWidth>
            </field>
            <field>
              <name>MR2</name>
              <bitOffset>2</bitOffset>
              <bitWidth>1</bitWidth>
            </field>
            <field>
              <name>MR3</name>
              <bitOffset>3</bitOffset>
              <bitWidth>1</bitWidth>
            </field>
            <field>
              <name>MR4</name>
              <bitOffset>4</bitOffset>
              <bitWidth>1</bitWidth>
            </field>
            <field>
              <name>MR5</name>
              <bitOffset>5</bitOffset>
              <bitWidth>1</bitWidth>
            </field>
            <field>
              <name>MR6</name>
              <bitOffset>6</bitOffset>
              <bitWidth>1</bitWidth>
            </field>
            <field>
              <name>MR7</name>
              <bitOffset>7</bitOffset>
              <bitWidth>1</bitWidth>
            </field>
            <field>
              <name>MR8</name>
              <bitOffset>8</bitOffset>
              <bitWidth>1</bitWidth>
            </field>
            <field>
              <name>MR9</name>
              <bitOffset>9</bitOffset>
              <bitWidth>1</bitWidth>
            </field>
            <field>
              <name>MR10</name>
              <bitOffset>10</bitOffset>
              <bitWidth>1</bitWidth>
            </field>
            <field>
              <name>MR11</name>
              <bitOffset>11</bitOffset>
              <bitWidth>1</bitWidth>
            </field>
            <field>
              <name>MR12</name>
              <bitOffset>12</bitOffset>
              <bitWidth>1</bitWidth>
            </field>
            <field>
              <name>MR13</name>
              <bitOffset>13</bitOffset>
              <bitWidth>1</bitWidth>
            </field>
            <field>
              <name>MR14</name>
              <bitOffset>14</bitOffset>
              <bitWidth>1</bitWidth>
            </field>
            <field>
              <name>MR15</name>
              <bitOffset>15</bitOffset>
              <bitWidth>1</bitWidth>
            </field>
            <field>
              <name>MR16</name>
              <bitOffset>16</bitOffset>
              <bitWidth>1</bitWidth>
            </field>
            <field>
              <name>MR17</name>
              <bitOffset>17</bitOffset>
              <bitWidth>1</bitWidth>
            </field>
            <field>
              <name>MR18</name>
              <bitOffset>18</bitOffset>
              <bitWidth>1</bitWidth>
            </field>
            <field>
              <name>MR19</name>
              <bitOffset>19</bitOffset>
              <bitWidth>1</bitWidth>
            </field>
            <field>
              <name>MR20</name>
              <bitOffset>20</bitOffset>
              <bitWidth>1</bitWidth>
            </field>
            <field>
              <name>MR21</name>
              <bitOffset>21</bitOffset>
              <bitWidth>1</bitWidth>
            </field>
            <field>
              <name>MR22</name>
              <bitOffset>22</bitOffset>
              <bitWidth>1</bitWidth>
            </field>
            <field>
              <name>MR23</name>
              <bitOffset>23</bitOffset>
              <bitWidth>1</bitWidth>
            </field>
            <field>
              <name>MR24</name>
              <bitOffset>24</bitOffset>
              <bitWidth>1</bitWidth>
            </field>
          </fields>
        </register>
        <register>
          <name>RTSR</name>
          <addressOffset>0x8</addressOffset>
          <size>0x20</size>
          <fields>
            <field>
              <name>TR0</name>
              <bitOffset>0</bitOffset>
              <bitWidth>1</bitWidth>
            </field>
            <field>
              <name>TR1</name>
              <bitOffset>1</bitOffset>
              <bitWidth>1</bitWidth>
            </field>
            <field>
              <name>TR2</name>
              <bitOffset>2</bitOffset>
              <bitWidth>1</bitWidth>
            </field>
            <field>
              <name>TR3</name>
              <bitOffset>3</bitOffset>
              <bitWidth>1</bitWidth>
            </field>
            <field>
              <name>TR4</name>
              <bitOffset>4</bitOffset>
              <bitWidth>1</bitWidth>
            </field>
            <field>
              <name>TR5</name>
              <bitOffset>5</bitOffset>
              <bitWidth>1</bitWidth>
            </field>
            <field>
              <name>TR6</name>
              <bitOffset>6</bitOffset>
              <bitWidth>1</bitWidth>
            </field>
            <field>
              <name>TR7</name>
              <bitOffset>7</bitOffset>
              <bitWidth>1</bitWidth>
            </field>
            <field>
              <name>TR8</name>
              <bitOffset>8</bitOffset>
              <bitWidth>1</bitWidth>
            </field>
            <field>
              <name>TR9</name>
              <bitOffset>9</bitOffset>
              <bitWidth>1</bitWidth>
            </field>
            <field>
              <name>TR10</name>
              <bitOffset>10</bitOffset>
              <bitWidth>1</bitWidth>
            </field>
            <field>
              <name>TR11</name>
              <bitOffset>11</bitOffset>
              <bitWidth>1</bitWidth>
            </field>
            <field>
              <name>TR12</name>
              <bitOffset>12</bitOffset>
              <bitWidth>1</bitWidth>
            </field>
            <field>
              <name>TR13</name>
              <bitOffset>13</bitOffset>
              <bitWidth>1</bitWidth>
            </field>
            <field>
              <name>TR14</name>
              <bitOffset>14</bitOffset>
              <bitWidth>1</bitWidth>
            </field>
            <field>
              <name>TR15</name>
              <bitOffset>15</bitOffset>
              <bitWidth>1</bitWidth>
            </field>
            <field>
              <name>TR16</name>
              <bitOffset>16</bitOffset>
              <bitWidth>1</bitWidth>
            </field>
            <field>
              <name>TR17</name>
              <bitOffset>17</bitOffset>
              <bitWidth>1</bitWidth>
            </field>
            <field>
              <name>TR18</name>
              <bitOffset>18</bitOffset>
              <bitWidth>1</bitWidth>
            </field>
            <field>
              <name>TR19</name>
              <bitOffset>19</bitOffset>
              <bitWidth>1</bitWidth>
            </field>
            <field>
              <name>TR20</name>
              <bitOffset>20</bitOffset>
              <bitWidth>1</bitWidth>
            </field>
            <field>
              <name>TR21</name>
              <bitOffset>21</bitOffset>
              <bitWidth>1</bitWidth>
            </field>
            <field>
              <name>TR22</name>
              <bitOffset>22</bitOffset>
              <bitWidth>1</bitWidth>
            </field>
            <field>
              <name>TR23</name>
              <bitOffset>23</bitOffset>
              <bitWidth>1</bitWidth>
            </field>
            <field>
              <name>TR24</name>
              <bitOffset>24</bitOffset>
              <bitWidth>1</bitWidth>
            </field>
          </fields>
        </register>
        <register>
          <name>FTSR</name>
          <addressOffset>0xc</addressOffset>
          <size>0x20</size>
          <fields>
            <field>
              <name>TR0</name>
              <bitOffset>0</bitOffset>
              <bitWidth>1</bitWidth>
            </field>
            <field>
              <name>TR1</name>
              <bitOffset>1</bitOffset>
              <bitWidth>1</bitWidth>
            </field>
            <field>
              <name>TR2</name>
              <bitOffset>2</bitOffset>
              <bitWidth>1</bitWidth>
            </field>
            <field>
              <name>TR3</name>
              <bitOffset>3</bitOffset>
              <bitWidth>1</bitWidth>
            </field>
            <field>
              <name>TR4</name>
              <bitOffset>4</bitOffset>
              <bitWidth>1</bitWidth>
            </field>
            <field>
              <name>TR5</name>
              <bitOffset>5</bitOffset>
              <bitWidth>1</bitWidth>
            </field>
            <field>
              <name>TR6</name>
              <bitOffset>6</bitOffset>
              <bitWidth>1</bitWidth>
            </field>
            <field>
              <name>TR7</name>
              <bitOffset>7</bitOffset>
              <bitWidth>1</bitWidth>
            </field>
            <field>
              <name>TR8</name>
              <bitOffset>8</bitOffset>
              <bitWidth>1</bitWidth>
            </field>
            <field>
              <name>TR9</name>
              <bitOffset>9</bitOffset>
              <bitWidth>1</bitWidth>
            </field>
            <field>
              <name>TR10</name>
              <bitOffset>10</bitOffset>
              <bitWidth>1</bitWidth>
            </field>
            <field>
              <name>TR11</name>
              <bitOffset>11</bitOffset>
              <bitWidth>1</bitWidth>
            </field>
            <field>
              <name>TR12</name>
              <bitOffset>12</bitOffset>
              <bitWidth>1</bitWidth>
            </field>
            <field>
              <name>TR13</name>
              <bitOffset>13</bitOffset>
              <bitWidth>1</bitWidth>
            </field>
            <field>
              <name>TR14</name>
              <bitOffset>14</bitOffset>
              <bitWidth>1</bitWidth>
            </field>
            <field>
              <name>TR15</name>
              <bitOffset>15</bitOffset>
              <bitWidth>1</bitWidth>
            </field>
            <field>
              <name>TR16</name>
              <bitOffset>16</bitOffset>
              <bitWidth>1</bitWidth>
            </field>
            <field>
              <name>TR17</name>
              <bitOffset>17</bitOffset>
              <bitWidth>1</bitWidth>
            </field>
            <field>
              <name>TR18</name>
              <bitOffset>18</bitOffset>
              <bitWidth>1</bitWidth>
            </field>
            <field>
              <name>TR19</name>
              <bitOffset>19</bitOffset>
              <bitWidth>1</bitWidth>
            </field>
            <field>
              <name>TR20</name>
              <bitOffset>20</bitOffset>
              <bitWidth>1</bitWidth>
            </field>
            <field>
              <name>TR21</name>
              <bitOffset>21</bitOffset>
              <bitWidth>1</bitWidth>
            </field>
            <field>
              <name>TR22</name>
              <bitOffset>22</bitOffset>
              <bitWidth>1</bitWidth>
            </field>
            <field>
              <name>TR23</name>
              <bitOffset>23</bitOffset>
              <bitWidth>1</bitWidth>
            </field>
            <field>
              <name>TR24</name>
              <bitOffset>24</bitOffset>
              <bitWidth>1</bitWidth>
            </field>
          </fields>
        </register>
        <register>
          <name>SWIER</name>
          <addressOffset>0x10</addressOffset>
          <size>0x20</size>
          <fields>
            <field>
              <name>SWIER0</name>
              <bitOffset>0</bitOffset>
              <bitWidth>1</bitWidth>
            </field>
            <field>
              <name>SWIER1</name>
              <bitOffset>1</bitOffset>
              <bitWidth>1</bitWidth>
            </field>
            <field>
              <name>SWIER2</name>
              <bitOffset>2</bitOffset>
              <bitWidth>1</bitWidth>
            </field>
            <field>
              <name>SWIER3</name>
              <bitOffset>3</bitOffset>
              <bitWidth>1</bitWidth>
            </field>
            <field>
              <name>SWIER4</name>
              <bitOffset>4</bitOffset>
              <bitWidth>1</bitWidth>
            </field>
            <field>
              <name>SWIER5</name>
              <bitOffset>5</bitOffset>
              <bitWidth>1</bitWidth>
            </field>
            <field>
              <name>SWIER6</name>
              <bitOffset>6</bitOffset>
              <bitWidth>1</bitWidth>
            </field>
            <field>
              <name>SWIER7</name>
              <bitOffset>7</bitOffset>
              <bitWidth>1</bitWidth>
            </field>
            <field>
              <name>SWIER8</name>
              <bitOffset>8</bitOffset>
              <bitWidth>1</bitWidth>
            </field>
            <field>
              <name>SWIER9</name>
              <bitOffset>9</bitOffset>
              <bitWidth>1</bitWidth>
            </field>
            <field>
              <name>SWIER10</name>
              <bitOffset>10</bitOffset>
              <bitWidth>1</bitWidth>
            </field>
            <field>
              <name>SWIER11</name>
              <bitOffset>11</bitOffset>
              <bitWidth>1</bitWidth>
            </field>
            <field>
              <name>SWIER12</name>
              <bitOffset>12</bitOffset>
              <bitWidth>1</bitWidth>
            </field>
            <field>
              <name>SWIER13</name>
              <bitOffset>13</bitOffset>
              <bitWidth>1</bitWidth>
            </field>
            <field>
              <name>SWIER14</name>
              <bitOffset>14</bitOffset>
              <bitWidth>1</bitWidth>
            </field>
            <field>
              <name>SWIER15</name>
              <bitOffset>15</bitOffset>
              <bitWidth>1</bitWidth>
            </field>
            <field>
              <name>SWIER16</name>
              <bitOffset>16</bitOffset>
              <bitWidth>1</bitWidth>
            </field>
            <field>
              <name>SWIER17</name>
              <bitOffset>17</bitOffset>
              <bitWidth>1</bitWidth>
            </field>
            <field>
              <name>SWIER18</name>
              <bitOffset>18</bitOffset>
              <bitWidth>1</bitWidth>
            </field>
            <field>
              <name>SWIER19</name>
              <bitOffset>19</bitOffset>
              <bitWidth>1</bitWidth>
            </field>
            <field>
              <name>SWIER20</name>
              <bitOffset>20</bitOffset>
              <bitWidth>1</bitWidth>
            </field>
            <field>
              <name>SWIER21</name>
              <bitOffset>21</bitOffset>
              <bitWidth>1</bitWidth>
            </field>
            <field>
              <name>SWIER22</name>
              <bitOffset>22</bitOffset>
              <bitWidth>1</bitWidth>
            </field>
            <field>
              <name>SWIER23</name>
              <bitOffset>23</bitOffset>
              <bitWidth>1</bitWidth>
            </field>
            <field>
              <name>SWIER24</name>
              <bitOffset>24</bitOffset>
              <bitWidth>1</bitWidth>
            </field>
          </fields>
        </register>
        <register>
          <name>PR</name>
          <addressOffset>0x14</addressOffset>
          <size>0x20</size>
          <fields>
            <field>
              <name>PR0</name>
              <bitOffset>0</bitOffset>
              <bitWidth>1</bitWidth>
            </field>
            <field>
              <name>PR1</name>
              <bitOffset>1</bitOffset>
              <bitWidth>1</bitWidth>
            </field>
            <field>
              <name>PR2</name>
              <bitOffset>2</bitOffset>
              <bitWidth>1</bitWidth>
            </field>
            <field>
              <name>PR3</name>
              <bitOffset>3</bitOffset>
              <bitWidth>1</bitWidth>
            </field>
            <field>
              <name>PR4</name>
              <bitOffset>4</bitOffset>
              <bitWidth>1</bitWidth>
            </field>
            <field>
              <name>PR5</name>
              <bitOffset>5</bitOffset>
              <bitWidth>1</bitWidth>
            </field>
            <field>
              <name>PR6</name>
              <bitOffset>6</bitOffset>
              <bitWidth>1</bitWidth>
            </field>
            <field>
              <name>PR7</name>
              <bitOffset>7</bitOffset>
              <bitWidth>1</bitWidth>
            </field>
            <field>
              <name>PR8</name>
              <bitOffset>8</bitOffset>
              <bitWidth>1</bitWidth>
            </field>
            <field>
              <name>PR9</name>
              <bitOffset>9</bitOffset>
              <bitWidth>1</bitWidth>
            </field>
            <field>
              <name>PR10</name>
              <bitOffset>10</bitOffset>
              <bitWidth>1</bitWidth>
            </field>
            <field>
              <name>PR11</name>
              <bitOffset>11</bitOffset>
              <bitWidth>1</bitWidth>
            </field>
            <field>
              <name>PR12</name>
              <bitOffset>12</bitOffset>
              <bitWidth>1</bitWidth>
            </field>
            <field>
              <name>PR13</name>
              <bitOffset>13</bitOffset>
              <bitWidth>1</bitWidth>
            </field>
            <field>
              <name>PR14</name>
              <bitOffset>14</bitOffset>
              <bitWidth>1</bitWidth>
            </field>
            <field>
              <name>PR15</name>
              <bitOffset>15</bitOffset>
              <bitWidth>1</bitWidth>
            </field>
            <field>
              <name>PR16</name>
              <bitOffset>16</bitOffset>
              <bitWidth>1</bitWidth>
            </field>
            <field>
              <name>PR17</name>
              <bitOffset>17</bitOffset>
              <bitWidth>1</bitWidth>
            </field>
            <field>
              <name>PR18</name>
              <bitOffset>18</bitOffset>
              <bitWidth>1</bitWidth>
            </field>
            <field>
              <name>PR19</name>
              <bitOffset>19</bitOffset>
              <bitWidth>1</bitWidth>
            </field>
            <field>
              <name>PR20</name>
              <bitOffset>20</bitOffset>
              <bitWidth>1</bitWidth>
            </field>
            <field>
              <name>PR21</name>
              <bitOffset>21</bitOffset>
              <bitWidth>1</bitWidth>
            </field>
            <field>
              <name>PR22</name>
              <bitOffset>22</bitOffset>
              <bitWidth>1</bitWidth>
            </field>
            <field>
              <name>PR23</name>
              <bitOffset>23</bitOffset>
              <bitWidth>1</bitWidth>
            </field>
            <field>
              <name>PR24</name>
              <bitOffset>24</bitOffset>
              <bitWidth>1</bitWidth>
            </field>
          </fields>
        </register>
      </registers>
    </peripheral>
    <peripheral>
      <name>TIM9</name>
      <baseAddress>0x40014000</baseAddress>
      <registers>
        <register>
          <name>CR1</name>
          <addressOffset>0x0</addressOffset>
          <size>0x20</size>
          <fields>
            <field>
              <name>CEN</name>
              <bitOffset>0</bitOffset>
              <bitWidth>1</bitWidth>
            </field>
            <field>
              <name>UDIS</name>
              <bitOffset>1</bitOffset>
              <bitWidth>1</bitWidth>
            </field>
            <field>
              <name>URS</name>
              <bitOffset>2</bitOffset>
              <bitWidth>1</bitWidth>
            </field>
            <field>
              <name>OPM</name>
              <bitOffset>3</bitOffset>
              <bitWidth>1</bitWidth>
            </field>
            <field>
              <name>DIR</name>
              <bitOffset>4</bitOffset>
              <bitWidth>1</bitWidth>
            </field>
            <field>
              <name>CMS</name>
              <bitOffset>5</bitOffset>
              <bitWidth>2</bitWidth>
            </field>
            <field>
              <name>ARPE</name>
              <bitOffset>7</bitOffset>
              <bitWidth>1</bitWidth>
            </field>
            <field>
              <name>CKD</name>
              <bitOffset>8</bitOffset>
              <bitWidth>2</bitWidth>
            </field>
            <field>
              <name>UIFREMAP</name>
              <bitOffset>11</bitOffset>
              <bitWidth>1</bitWidth>
            </field>
          </fields>
        </register>
        <register>
          <name>CR2</name>
          <addressOffset>0x4</addressOffset>
          <size>0x20</size>
          <fields>
            <field>
              <name>CCPC</name>
              <bitOffset>0</bitOffset>
              <bitWidth>1</bitWidth>
            </field>
            <field>
              <name>CCUS</name>
              <bitOffset>2</bitOffset>
              <bitWidth>1</bitWidth>
            </field>
            <field>
              <name>CCDS</name>
              <bitOffset>3</bitOffset>
              <bitWidth>1</bitWidth>
            </field>
            <field>
              <name>MMS</name>
              <bitOffset>4</bitOffset>
              <bitWidth>3</bitWidth>
            </field>
            <field>
              <name>TI1S</name>
              <bitOffset>7</bitOffset>
              <bitWidth>1</bitWidth>
            </field>
            <field>
              <name>OIS1</name>
              <bitOffset>8</bitOffset>
              <bitWidth>1</bitWidth>
            </field>
            <field>
              <name>OIS1N</name>
              <bitOffset>9</bitOffset>
              <bitWidth>1</bitWidth>
            </field>
            <field>
              <name>OIS2</name>
              <bitOffset>10</bitOffset>
              <bitWidth>1</bitWidth>
            </field>
            <field>
              <name>OIS2N</name>
              <bitOffset>11</bitOffset>
              <bitWidth>1</bitWidth>
            </field>
            <field>
              <name>OIS3</name>
              <bitOffset>12</bitOffset>
              <bitWidth>1</bitWidth>
            </field>
            <field>
              <name>OIS3N</name>
              <bitOffset>13</bitOffset>
              <bitWidth>1</bitWidth>
            </field>
            <field>
              <name>OIS4</name>
              <bitOffset>14</bitOffset>
              <bitWidth>1</bitWidth>
            </field>
            <field>
              <name>OIS5</name>
              <bitOffset>16</bitOffset>
              <bitWidth>1</bitWidth>
            </field>
            <field>
              <name>OIS6</name>
              <bitOffset>18</bitOffset>
              <bitWidth>1</bitWidth>
            </field>
            <field>
              <name>MMS2</name>
              <bitOffset>20</bitOffset>
              <bitWidth>4</bitWidth>
            </field>
          </fields>
        </register>
        <register>
          <name>SMCR</name>
          <addressOffset>0x8</addressOffset>
          <size>0x20</size>
          <fields>
            <field>
              <name>SMS</name>
              <bitOffset>0</bitOffset>
              <bitWidth>17</bitWidth>
            </field>
            <field>
              <name>TS</name>
              <bitOffset>4</bitOffset>
              <bitWidth>3</bitWidth>
            </field>
            <field>
              <name>MSM</name>
              <bitOffset>7</bitOffset>
              <bitWidth>1</bitWidth>
            </field>
            <field>
              <name>ETF</name>
              <bitOffset>8</bitOffset>
              <bitWidth>4</bitWidth>
            </field>
            <field>
              <name>ETPS</name>
              <bitOffset>12</bitOffset>
              <bitWidth>2</bitWidth>
            </field>
            <field>
              <name>ECE</name>
              <bitOffset>14</bitOffset>
              <bitWidth>1</bitWidth>
            </field>
            <field>
              <name>ETP</name>
              <bitOffset>15</bitOffset>
              <bitWidth>1</bitWidth>
            </field>
          </fields>
        </register>
        <register>
          <name>DIER</name>
          <addressOffset>0xc</addressOffset>
          <size>0x20</size>
          <fields>
            <field>
              <name>UIE</name>
              <bitOffset>0</bitOffset>
              <bitWidth>1</bitWidth>
            </field>
            <field>
              <name>CC1IE</name>
              <bitOffset>1</bitOffset>
              <bitWidth>1</bitWidth>
            </field>
            <field>
              <name>CC2IE</name>
              <bitOffset>2</bitOffset>
              <bitWidth>1</bitWidth>
            </field>
            <field>
              <name>CC3IE</name>
              <bitOffset>3</bitOffset>
              <bitWidth>1</bitWidth>
            </field>
            <field>
              <name>CC4IE</name>
              <bitOffset>4</bitOffset>
              <bitWidth>1</bitWidth>
            </field>
            <field>
              <name>COMIE</name>
              <bitOffset>5</bitOffset>
              <bitWidth>1</bitWidth>
            </field>
            <field>
              <name>TIE</name>
              <bitOffset>6</bitOffset>
              <bitWidth>1</bitWidth>
            </field>
            <field>
              <name>BIE</name>
              <bitOffset>7</bitOffset>
              <bitWidth>1</bitWidth>
            </field>
            <field>
              <name>UDE</name>
              <bitOffset>8</bitOffset>
              <bitWidth>1</bitWidth>
            </field>
            <field>
              <name>CC1DE</name>
              <bitOffset>9</bitOffset>
              <bitWidth>1</bitWidth>
            </field>
            <field>
              <name>CC2DE</name>
              <bitOffset>10</bitOffset>
              <bitWidth>1</bitWidth>
            </field>
            <field>
              <name>CC3DE</name>
              <bitOffset>11</bitOffset>
              <bitWidth>1</bitWidth>
            </field>
            <field>
              <name>CC4DE</name>
              <bitOffset>12</bitOffset>
              <bitWidth>1</bitWidth>
            </field>
            <field>
              <name>COMDE</name>
              <bitOffset>13</bitOffset>
              <bitWidth>1</bitWidth>
            </field>
            <field>
              <name>TDE</name>
              <bitOffset>14</bitOffset>
              <bitWidth>1</bitWidth>
            </field>
          </fields>
        </register>
        <register>
          <name>SR</name>
          <addressOffset>0x10</addressOffset>
          <size>0x20</size>
          <fields>
            <field>
              <name>UIF</name>
              <bitOffset>0</bitOffset>
              <bitWidth>1</bitWidth>
            </field>
            <field>
              <name>CC1IF</name>
              <bitOffset>1</bitOffset>
              <bitWidth>1</bitWidth>
            </field>
            <field>
              <name>CC2IF</name>
              <bitOffset>2</bitOffset>
              <bitWidth>1</bitWidth>
            </field>
            <field>
              <name>CC3IF</name>
              <bitOffset>3</bitOffset>
              <bitWidth>1</bitWidth>
            </field>
            <field>
              <name>CC4IF</name>
              <bitOffset>4</bitOffset>
              <bitWidth>1</bitWidth>
            </field>
            <field>
              <name>COMIF</name>
              <bitOffset>5</bitOffset>
              <bitWidth>1</bitWidth>
            </field>
            <field>
              <name>TIF</name>
              <bitOffset>6</bitOffset>
              <bitWidth>1</bitWidth>
            </field>
            <field>
              <name>BIF</name>
              <bitOffset>7</bitOffset>
              <bitWidth>1</bitWidth>
            </field>
            <field>
              <name>B2IF</name>
              <bitOffset>8</bitOffset>
              <bitWidth>1</bitWidth>
            </field>
            <field>
              <name>CC1OF</name>
              <bitOffset>9</bitOffset>
              <bitWidth>1</bitWidth>
            </field>
            <field>
              <name>CC2OF</name>
              <bitOffset>10</bitOffset>
              <bitWidth>1</bitWidth>
            </field>
            <field>
              <name>CC3OF</name>
              <bitOffset>11</bitOffset>
              <bitWidth>1</bitWidth>
            </field>
            <field>
              <name>CC4OF</name>
              <bitOffset>12</bitOffset>
              <bitWidth>1</bitWidth>
            </field>
            <field>
              <name>SBIF</name>
              <bitOffset>13</bitOffset>
              <bitWidth>1</bitWidth>
            </field>
            <field>
              <name>CC5IF</name>
              <bitOffset>16</bitOffset>
              <bitWidth>1</bitWidth>
            </field>
            <field>
              <name>CC6IF</name>
              <bitOffset>17</bitOffset>
              <bitWidth>1</bitWidth>
            </field>
          </fields>
        </register>
        <register>
          <name>EGR</name>
          <addressOffset>0x14</addressOffset>
          <size>0x20</size>
          <fields>
            <field>
              <name>UG</name>
              <bitOffset>0</bitOffset>
              <bitWidth>1</bitWidth>
            </field>
            <field>
              <name>CC1G</name>
              <bitOffset>1</bitOffset>
              <bitWidth>1</bitWidth>
            </field>
            <field>
              <name>CC2G</name>
              <bitOffset>2</bitOffset>
              <bitWidth>1</bitWidth>
            </field>
            <field>
              <name>CC3G</name>
              <bitOffset>3</bitOffset>
              <bitWidth>1</bitWidth>
            </field>
            <field>
              <name>CC4G</name>
              <bitOffset>4</bitOffset>
              <bitWidth>1</bitWidth>
            </field>
            <field>
              <name>COMG</name>
              <bitOffset>5</bitOffset>
              <bitWidth>1</bitWidth>
            </field>
            <field>
              <name>TG</name>
              <bitOffset>6</bitOffset>
              <bitWidth>1</bitWidth>
            </field>
            <field>
              <name>BG</name>
              <bitOffset>7</bitOffset>
              <bitWidth>1</bitWidth>
            </field>
            <field>
              <name>B2G</name>
              <bitOffset>8</bitOffset>
              <bitWidth>1</bitWidth>
            </field>
          </fields>
        </register>
        <register>
          <name>CCMR1</name>
          <addressOffset>0x18</addressOffset>
          <size>0x20</size>
          <fields>
            <field>
              <name>CC1S</name>
              <bitOffset>0</bitOffset>
              <bitWidth>2</bitWidth>
            </field>
            <field>
              <name>OC1FE</name>
              <bitOffset>2</bitOffset>
              <bitWidth>1</bitWidth>
            </field>
            <field>
              <name>OC1PE</name>
              <bitOffset>3</bitOffset>
              <bitWidth>1</bitWidth>
            </field>
            <field>
              <name>OC1M</name>
              <bitOffset>4</bitOffset>
              <bitWidth>13</bitWidth>
            </field>
            <field>
              <name>OC1CE</name>
              <bitOffset>7</bitOffset>
              <bitWidth>1</bitWidth>
            </field>
            <field>
              <name>CC2S</name>
              <bitOffset>8</bitOffset>
              <bitWidth>2</bitWidth>
            </field>
            <field>
              <name>OC2FE</name>
              <bitOffset>10</bitOffset>
              <bitWidth>1</bitWidth>
            </field>
            <field>
              <name>OC2PE</name>
              <bitOffset>11</bitOffset>
              <bitWidth>1</bitWidth>
            </field>
            <field>
              <name>OC2M</name>
              <bitOffset>12</bitOffset>
              <bitWidth>13</bitWidth>
            </field>
            <field>
              <name>OC2CE</name>
              <bitOffset>15</bitOffset>
              <bitWidth>1</bitWidth>
            </field>
          </fields>
        </register>
        <register>
          <name>CCMR2</name>
          <addressOffset>0x1c</addressOffset>
          <size>0x20</size>
          <fields>
            <field>
              <name>CC3S</name>
              <bitOffset>0</bitOffset>
              <bitWidth>2</bitWidth>
            </field>
            <field>
              <name>OC3FE</name>
              <bitOffset>2</bitOffset>
              <bitWidth>1</bitWidth>
            </field>
            <field>
              <name>OC3PE</name>
              <bitOffset>3</bitOffset>
              <bitWidth>1</bitWidth>
            </field>
            <field>
              <name>OC3M</name>
              <bitOffset>4</bitOffset>
              <bitWidth>13</bitWidth>
            </field>
            <field>
              <name>OC3CE</name>
              <bitOffset>7</bitOffset>
              <bitWidth>1</bitWidth>
            </field>
            <field>
              <name>CC4S</name>
              <bitOffset>8</bitOffset>
              <bitWidth>2</bitWidth>
            </field>
            <field>
              <name>OC4FE</name>
              <bitOffset>10</bitOffset>
              <bitWidth>1</bitWidth>
            </field>
            <field>
              <name>OC4PE</name>
              <bitOffset>11</bitOffset>
              <bitWidth>1</bitWidth>
            </field>
            <field>
              <name>OC4M</name>
              <bitOffset>12</bitOffset>
              <bitWidth>13</bitWidth>
            </field>
            <field>
              <name>OC4CE</name>
              <bitOffset>15</bitOffset>
              <bitWidth>1</bitWidth>
            </field>
          </fields>
        </register>
        <register>
          <name>CCER</name>
          <addressOffset>0x20</addressOffset>
          <size>0x20</size>
          <fields>
            <field>
              <name>CC1E</name>
              <bitOffset>0</bitOffset>
              <bitWidth>1</bitWidth>
            </field>
            <field>
              <name>CC1P</name>
              <bitOffset>1</bitOffset>
              <bitWidth>1</bitWidth>
            </field>
            <field>
              <name>CC1NE</name>
              <bitOffset>2</bitOffset>
              <bitWidth>1</bitWidth>
            </field>
            <field>
              <name>CC1NP</name>
              <bitOffset>3</bitOffset>
              <bitWidth>1</bitWidth>
            </field>
            <field>
              <name>CC2E</name>
              <bitOffset>4</bitOffset>
              <bitWidth>1</bitWidth>
            </field>
            <field>
              <name>CC2P</name>
              <bitOffset>5</bitOffset>
              <bitWidth>1</bitWidth>
            </field>
            <field>
              <name>CC2NE</name>
              <bitOffset>6</bitOffset>
              <bitWidth>1</bitWidth>
            </field>
            <field>
              <name>CC2NP</name>
              <bitOffset>7</bitOffset>
              <bitWidth>1</bitWidth>
            </field>
            <field>
              <name>CC3E</name>
              <bitOffset>8</bitOffset>
              <bitWidth>1</bitWidth>
            </field>
            <field>
              <name>CC3P</name>
              <bitOffset>9</bitOffset>
              <bitWidth>1</bitWidth>
            </field>
            <field>
              <name>CC3NE</name>
              <bitOffset>10</bitOffset>
              <bitWidth>1</bitWidth>
            </field>
            <field>
              <name>CC3NP</name>
              <bitOffset>11</bitOffset>
              <bitWidth>1</bitWidth>
            </field>
            <field>
              <name>CC4E</name>
              <bitOffset>12</bitOffset>
              <bitWidth>1</bitWidth>
            </field>
            <field>
              <name>CC4P</name>
              <bitOffset>13</bitOffset>
              <bitWidth>1</bitWidth>
            </field>
            <field>
              <name>CC4NP</name>
              <bitOffset>15</bitOffset>
              <bitWidth>1</bitWidth>
            </field>
            <field>
              <name>CC5E</name>
              <bitOffset>16</bitOffset>
              <bitWidth>1</bitWidth>
            </field>
            <field>
              <name>CC5P</name>
              <bitOffset>17</bitOffset>
              <bitWidth>1</bitWidth>
            </field>
            <field>
              <name>CC6E</name>
              <bitOffset>20</bitOffset>
              <bitWidth>1</bitWidth>
            </field>
            <field>
              <name>CC6P</name>
              <bitOffset>21</bitOffset>
              <bitWidth>1</bitWidth>
            </field>
          </fields>
        </register>
        <register>
          <name>CNT</name>
          <addressOffset>0x24</addressOffset>
          <size>0x20</size>
          <fields>
            <field>
              <name>CNT</name>
              <bitOffset>0</bitOffset>
              <bitWidth>32</bitWidth>
            </field>
            <field>
              <name>UIFCPY</name>
              <bitOffset>31</bitOffset>
              <bitWidth>1</bitWidth>
            </field>
          </fields>
        </register>
        <register>
          <name>PSC</name>
          <addressOffset>0x28</addressOffset>
          <size>0x20</size>
          <fields>
            <field>
              <name>PSC</name>
              <bitOffset>0</bitOffset>
              <bitWidth>16</bitWidth>
            </field>
          </fields>
        </register>
        <register>
          <name>ARR</name>
          <addressOffset>0x2c</addressOffset>
          <size>0x20</size>
          <fields>
            <field>
              <name>ARR</name>
              <bitOffset>0</bitOffset>
              <bitWidth>32</bitWidth>
            </field>
          </fields>
        </register>
        <register>
          <name>RCR</name>
          <addressOffset>0x30</addressOffset>
          <size>0x20</size>
          <fields>
            <field>
              <name>REP</name>
              <bitOffset>0</bitOffset>
              <bitWidth>16</bitWidth>
            </field>
          </fields>
        </register>
        <register>
          <name>CCR1</name>
          <addressOffset>0x34</addressOffset>
          <size>0x20</size>
          <fields>
            <field>
              <name>CCR1</name>
              <bitOffset>0</bitOffset>
              <bitWidth>16</bitWidth>
            </field>
          </fields>
        </register>
        <register>
          <name>CCR2</name>
          <addressOffset>0x38</addressOffset>
          <size>0x20</size>
          <fields>
            <field>
              <name>CCR2</name>
              <bitOffset>0</bitOffset>
              <bitWidth>16</bitWidth>
            </field>
          </fields>
        </register>
        <register>
          <name>CCR3</name>
          <addressOffset>0x3c</addressOffset>
          <size>0x20</size>
          <fields>
            <field>
              <name>CCR3</name>
              <bitOffset>0</bitOffset>
              <bitWidth>16</bitWidth>
            </field>
          </fields>
        </register>
        <register>
          <name>CCR4</name>
          <addressOffset>0x40</addressOffset>
          <size>0x20</size>
          <fields>
            <field>
              <name>CCR4</name>
              <bitOffset>0</bitOffset>
              <bitWidth>16</bitWidth>
            </field>
          </fields>
        </register>
        <register>
          <name>BDTR</name>
          <addressOffset>0x44</addressOffset>
          <size>0x20</size>
          <fields>
            <field>
              <name>DTG</name>
              <bitOffset>0</bitOffset>
              <bitWidth>8</bitWidth>
            </field>
            <field>
              <name>LOCK</name>
              <bitOffset>8</bitOffset>
              <bitWidth>2</bitWidth>
            </field>
            <field>
              <name>OSSI</name>
              <bitOffset>10</bitOffset>
              <bitWidth>1</bitWidth>
            </field>
            <field>
              <name>OSSR</name>
              <bitOffset>11</bitOffset>
              <bitWidth>1</bitWidth>
            </field>
            <field>
              <name>BKE</name>
              <bitOffset>12</bitOffset>
              <bitWidth>1</bitWidth>
            </field>
            <field>
              <name>BKP</name>
              <bitOffset>13</bitOffset>
              <bitWidth>1</bitWidth>
            </field>
            <field>
              <name>AOE</name>
              <bitOffset>14</bitOffset>
              <bitWidth>1</bitWidth>
            </field>
            <field>
              <name>MOE</name>
              <bitOffset>15</bitOffset>
              <bitWidth>1</bitWidth>
            </field>
            <field>
              <name>BKF</name>
              <bitOffset>16</bitOffset>
              <bitWidth>4</bitWidth>
            </field>
            <field>
              <name>BK2F</name>
              <bitOffset>20</bitOffset>
              <bitWidth>4</bitWidth>
            </field>
            <field>
              <name>BK2E</name>
              <bitOffset>24</bitOffset>
              <bitWidth>1</bitWidth>
            </field>
            <field>
              <name>BK2P</name>
              <bitOffset>25</bitOffset>
              <bitWidth>1</bitWidth>
            </field>
          </fields>
        </register>
        <register>
          <name>DCR</name>
          <addressOffset>0x48</addressOffset>
          <size>0x20</size>
          <fields>
            <field>
              <name>DBA</name>
              <bitOffset>0</bitOffset>
              <bitWidth>5</bitWidth>
            </field>
            <field>
              <name>DBL</name>
              <bitOffset>8</bitOffset>
              <bitWidth>5</bitWidth>
            </field>
          </fields>
        </register>
        <register>
          <name>DMAR</name>
          <addressOffset>0x4c</addressOffset>
          <size>0x20</size>
          <fields>
            <field>
              <name>DMAB</name>
              <bitOffset>0</bitOffset>
              <bitWidth>16</bitWidth>
            </field>
          </fields>
        </register>
        <register>
          <name>OR</name>
          <addressOffset>0x50</addressOffset>
          <size>0x20</size>
          <fields>
            <field>
              <name>TI4_RMP</name>
              <bitOffset>6</bitOffset>
              <bitWidth>2</bitWidth>
            </field>
            <field>
              <name>ITR1_RMP</name>
              <bitOffset>10</bitOffset>
              <bitWidth>2</bitWidth>
            </field>
          </fields>
        </register>
        <register>
          <name>CCMR3</name>
          <addressOffset>0x54</addressOffset>
          <size>0x20</size>
          <fields>
            <field>
              <name>OC5FE</name>
              <bitOffset>2</bitOffset>
              <bitWidth>1</bitWidth>
            </field>
            <field>
              <name>OC5PE</name>
              <bitOffset>3</bitOffset>
              <bitWidth>1</bitWidth>
            </field>
            <field>
              <name>OC5M</name>
              <bitOffset>4</bitOffset>
              <bitWidth>13</bitWidth>
            </field>
            <field>
              <name>OC5CE</name>
              <bitOffset>7</bitOffset>
              <bitWidth>1</bitWidth>
            </field>
            <field>
              <name>OC6FE</name>
              <bitOffset>10</bitOffset>
              <bitWidth>1</bitWidth>
            </field>
            <field>
              <name>OC6PE</name>
              <bitOffset>11</bitOffset>
              <bitWidth>1</bitWidth>
            </field>
            <field>
              <name>OC6M</name>
              <bitOffset>12</bitOffset>
              <bitWidth>13</bitWidth>
            </field>
            <field>
              <name>OC6CE</name>
              <bitOffset>15</bitOffset>
              <bitWidth>1</bitWidth>
            </field>
          </fields>
        </register>
        <register>
          <name>CCR5</name>
          <addressOffset>0x58</addressOffset>
          <size>0x20</size>
          <fields>
            <field>
              <name>CCR5</name>
              <bitOffset>0</bitOffset>
              <bitWidth>32</bitWidth>
            </field>
            <field>
              <name>GC5C1</name>
              <bitOffset>29</bitOffset>
              <bitWidth>1</bitWidth>
            </field>
            <field>
              <name>GC5C2</name>
              <bitOffset>30</bitOffset>
              <bitWidth>1</bitWidth>
            </field>
            <field>
              <name>GC5C3</name>
              <bitOffset>31</bitOffset>
              <bitWidth>1</bitWidth>
            </field>
          </fields>
        </register>
        <register>
          <name>CCR6</name>
          <addressOffset>0x5c</addressOffset>
          <size>0x20</size>
        </register>
        <register>
          <name>AF1</name>
          <addressOffset>0x60</addressOffset>
          <size>0x20</size>
        </register>
        <register>
          <name>AF2</name>
          <addressOffset>0x64</addressOffset>
          <size>0x20</size>
        </register>
      </registers>
    </peripheral>
    <peripheral>
      <name>TIM10</name>
      <baseAddress>0x40014400</baseAddress>
      <registers>
        <register>
          <name>CR1</name>
          <addressOffset>0x0</addressOffset>
          <size>0x20</size>
          <fields>
            <field>
              <name>CEN</name>
              <bitOffset>0</bitOffset>
              <bitWidth>1</bitWidth>
            </field>
            <field>
              <name>UDIS</name>
              <bitOffset>1</bitOffset>
              <bitWidth>1</bitWidth>
            </field>
            <field>
              <name>URS</name>
              <bitOffset>2</bitOffset>
              <bitWidth>1</bitWidth>
            </field>
            <field>
              <name>OPM</name>
              <bitOffset>3</bitOffset>
              <bitWidth>1</bitWidth>
            </field>
            <field>
              <name>DIR</name>
              <bitOffset>4</bitOffset>
              <bitWidth>1</bitWidth>
            </field>
            <field>
              <name>CMS</name>
              <bitOffset>5</bitOffset>
              <bitWidth>2</bitWidth>
            </field>
            <field>
              <name>ARPE</name>
              <bitOffset>7</bitOffset>
              <bitWidth>1</bitWidth>
            </field>
            <field>
              <name>CKD</name>
              <bitOffset>8</bitOffset>
              <bitWidth>2</bitWidth>
            </field>
            <field>
              <name>UIFREMAP</name>
              <bitOffset>11</bitOffset>
              <bitWidth>1</bitWidth>
            </field>
          </fields>
        </register>
        <register>
          <name>CR2</name>
          <addressOffset>0x4</addressOffset>
          <size>0x20</size>
          <fields>
            <field>
              <name>CCPC</name>
              <bitOffset>0</bitOffset>
              <bitWidth>1</bitWidth>
            </field>
            <field>
              <name>CCUS</name>
              <bitOffset>2</bitOffset>
              <bitWidth>1</bitWidth>
            </field>
            <field>
              <name>CCDS</name>
              <bitOffset>3</bitOffset>
              <bitWidth>1</bitWidth>
            </field>
            <field>
              <name>MMS</name>
              <bitOffset>4</bitOffset>
              <bitWidth>3</bitWidth>
            </field>
            <field>
              <name>TI1S</name>
              <bitOffset>7</bitOffset>
              <bitWidth>1</bitWidth>
            </field>
            <field>
              <name>OIS1</name>
              <bitOffset>8</bitOffset>
              <bitWidth>1</bitWidth>
            </field>
            <field>
              <name>OIS1N</name>
              <bitOffset>9</bitOffset>
              <bitWidth>1</bitWidth>
            </field>
            <field>
              <name>OIS2</name>
              <bitOffset>10</bitOffset>
              <bitWidth>1</bitWidth>
            </field>
            <field>
              <name>OIS2N</name>
              <bitOffset>11</bitOffset>
              <bitWidth>1</bitWidth>
            </field>
            <field>
              <name>OIS3</name>
              <bitOffset>12</bitOffset>
              <bitWidth>1</bitWidth>
            </field>
            <field>
              <name>OIS3N</name>
              <bitOffset>13</bitOffset>
              <bitWidth>1</bitWidth>
            </field>
            <field>
              <name>OIS4</name>
              <bitOffset>14</bitOffset>
              <bitWidth>1</bitWidth>
            </field>
            <field>
              <name>OIS5</name>
              <bitOffset>16</bitOffset>
              <bitWidth>1</bitWidth>
            </field>
            <field>
              <name>OIS6</name>
              <bitOffset>18</bitOffset>
              <bitWidth>1</bitWidth>
            </field>
            <field>
              <name>MMS2</name>
              <bitOffset>20</bitOffset>
              <bitWidth>4</bitWidth>
            </field>
          </fields>
        </register>
        <register>
          <name>SMCR</name>
          <addressOffset>0x8</addressOffset>
          <size>0x20</size>
          <fields>
            <field>
              <name>SMS</name>
              <bitOffset>0</bitOffset>
              <bitWidth>17</bitWidth>
            </field>
            <field>
              <name>TS</name>
              <bitOffset>4</bitOffset>
              <bitWidth>3</bitWidth>
            </field>
            <field>
              <name>MSM</name>
              <bitOffset>7</bitOffset>
              <bitWidth>1</bitWidth>
            </field>
            <field>
              <name>ETF</name>
              <bitOffset>8</bitOffset>
              <bitWidth>4</bitWidth>
            </field>
            <field>
              <name>ETPS</name>
              <bitOffset>12</bitOffset>
              <bitWidth>2</bitWidth>
            </field>
            <field>
              <name>ECE</name>
              <bitOffset>14</bitOffset>
              <bitWidth>1</bitWidth>
            </field>
            <field>
              <name>ETP</name>
              <bitOffset>15</bitOffset>
              <bitWidth>1</bitWidth>
            </field>
          </fields>
        </register>
        <register>
          <name>DIER</name>
          <addressOffset>0xc</addressOffset>
          <size>0x20</size>
          <fields>
            <field>
              <name>UIE</name>
              <bitOffset>0</bitOffset>
              <bitWidth>1</bitWidth>
            </field>
            <field>
              <name>CC1IE</name>
              <bitOffset>1</bitOffset>
              <bitWidth>1</bitWidth>
            </field>
            <field>
              <name>CC2IE</name>
              <bitOffset>2</bitOffset>
              <bitWidth>1</bitWidth>
            </field>
            <field>
              <name>CC3IE</name>
              <bitOffset>3</bitOffset>
              <bitWidth>1</bitWidth>
            </field>
            <field>
              <name>CC4IE</name>
              <bitOffset>4</bitOffset>
              <bitWidth>1</bitWidth>
            </field>
            <field>
              <name>COMIE</name>
              <bitOffset>5</bitOffset>
              <bitWidth>1</bitWidth>
            </field>
            <field>
              <name>TIE</name>
              <bitOffset>6</bitOffset>
              <bitWidth>1</bitWidth>
            </field>
            <field>
              <name>BIE</name>
              <bitOffset>7</bitOffset>
              <bitWidth>1</bitWidth>
            </field>
            <field>
              <name>UDE</name>
              <bitOffset>8</bitOffset>
              <bitWidth>1</bitWidth>
            </field>
            <field>
              <name>CC1DE</name>
              <bitOffset>9</bitOffset>
              <bitWidth>1</bitWidth>
            </field>
            <field>
              <name>CC2DE</name>
              <bitOffset>10</bitOffset>
              <bitWidth>1</bitWidth>
            </field>
            <field>
              <name>CC3DE</name>
              <bitOffset>11</bitOffset>
              <bitWidth>1</bitWidth>
            </field>
            <field>
              <name>CC4DE</name>
              <bitOffset>12</bitOffset>
              <bitWidth>1</bitWidth>
            </field>
            <field>
              <name>COMDE</name>
              <bitOffset>13</bitOffset>
              <bitWidth>1</bitWidth>
            </field>
            <field>
              <name>TDE</name>
              <bitOffset>14</bitOffset>
              <bitWidth>1</bitWidth>
            </field>
          </fields>
        </register>
        <register>
          <name>SR</name>
          <addressOffset>0x10</addressOffset>
          <size>0x20</size>
          <fields>
            <field>
              <name>UIF</name>
              <bitOffset>0</bitOffset>
              <bitWidth>1</bitWidth>
            </field>
            <field>
              <name>CC1IF</name>
              <bitOffset>1</bitOffset>
              <bitWidth>1</bitWidth>
            </field>
            <field>
              <name>CC2IF</name>
              <bitOffset>2</bitOffset>
              <bitWidth>1</bitWidth>
            </field>
            <field>
              <name>CC3IF</name>
              <bitOffset>3</bitOffset>
              <bitWidth>1</bitWidth>
            </field>
            <field>
              <name>CC4IF</name>
              <bitOffset>4</bitOffset>
              <bitWidth>1</bitWidth>
            </field>
            <field>
              <name>COMIF</name>
              <bitOffset>5</bitOffset>
              <bitWidth>1</bitWidth>
            </field>
            <field>
              <name>TIF</name>
              <bitOffset>6</bitOffset>
              <bitWidth>1</bitWidth>
            </field>
            <field>
              <name>BIF</name>
              <bitOffset>7</bitOffset>
              <bitWidth>1</bitWidth>
            </field>
            <field>
              <name>B2IF</name>
              <bitOffset>8</bitOffset>
              <bitWidth>1</bitWidth>
            </field>
            <field>
              <name>CC1OF</name>
              <bitOffset>9</bitOffset>
              <bitWidth>1</bitWidth>
            </field>
            <field>
              <name>CC2OF</name>
              <bitOffset>10</bitOffset>
              <bitWidth>1</bitWidth>
            </field>
            <field>
              <name>CC3OF</name>
              <bitOffset>11</bitOffset>
              <bitWidth>1</bitWidth>
            </field>
            <field>
              <name>CC4OF</name>
              <bitOffset>12</bitOffset>
              <bitWidth>1</bitWidth>
            </field>
            <field>
              <name>SBIF</name>
              <bitOffset>13</bitOffset>
              <bitWidth>1</bitWidth>
            </field>
            <field>
              <name>CC5IF</name>
              <bitOffset>16</bitOffset>
              <bitWidth>1</bitWidth>
            </field>
            <field>
              <name>CC6IF</name>
              <bitOffset>17</bitOffset>
              <bitWidth>1</bitWidth>
            </field>
          </fields>
        </register>
        <register>
          <name>EGR</name>
          <addressOffset>0x14</addressOffset>
          <size>0x20</size>
          <fields>
            <field>
              <name>UG</name>
              <bitOffset>0</bitOffset>
              <bitWidth>1</bitWidth>
            </field>
            <field>
              <name>CC1G</name>
              <bitOffset>1</bitOffset>
              <bitWidth>1</bitWidth>
            </field>
            <field>
              <name>CC2G</name>
              <bitOffset>2</bitOffset>
              <bitWidth>1</bitWidth>
            </field>
            <field>
              <name>CC3G</name>
              <bitOffset>3</bitOffset>
              <bitWidth>1</bitWidth>
            </field>
            <field>
              <name>CC4G</name>
              <bitOffset>4</bitOffset>
              <bitWidth>1</bitWidth>
            </field>
            <field>
              <name>COMG</name>
              <bitOffset>5</bitOffset>
              <bitWidth>1</bitWidth>
            </field>
            <field>
              <name>TG</name>
              <bitOffset>6</bitOffset>
              <bitWidth>1</bitWidth>
            </field>
            <field>
              <name>BG</name>
              <bitOffset>7</bitOffset>
              <bitWidth>1</bitWidth>
            </field>
            <field>
              <name>B2G</name>
              <bitOffset>8</bitOffset>
              <bitWidth>1</bitWidth>
            </field>
          </fields>
        </register>
        <register>
          <name>CCMR1</name>
          <addressOffset>0x18</addressOffset>
          <size>0x20</size>
          <fields>
            <field>
              <name>CC1S</name>
              <bitOffset>0</bitOffset>
              <bitWidth>2</bitWidth>
            </field>
            <field>
              <name>OC1FE</name>
              <bitOffset>2</bitOffset>
              <bitWidth>1</bitWidth>
            </field>
            <field>
              <name>OC1PE</name>
              <bitOffset>3</bitOffset>
              <bitWidth>1</bitWidth>
            </field>
            <field>
              <name>OC1M</name>
              <bitOffset>4</bitOffset>
              <bitWidth>13</bitWidth>
            </field>
            <field>
              <name>OC1CE</name>
              <bitOffset>7</bitOffset>
              <bitWidth>1</bitWidth>
            </field>
            <field>
              <name>CC2S</name>
              <bitOffset>8</bitOffset>
              <bitWidth>2</bitWidth>
            </field>
            <field>
              <name>OC2FE</name>
              <bitOffset>10</bitOffset>
              <bitWidth>1</bitWidth>
            </field>
            <field>
              <name>OC2PE</name>
              <bitOffset>11</bitOffset>
              <bitWidth>1</bitWidth>
            </field>
            <field>
              <name>OC2M</name>
              <bitOffset>12</bitOffset>
              <bitWidth>13</bitWidth>
            </field>
            <field>
              <name>OC2CE</name>
              <bitOffset>15</bitOffset>
              <bitWidth>1</bitWidth>
            </field>
          </fields>
        </register>
        <register>
          <name>CCMR2</name>
          <addressOffset>0x1c</addressOffset>
          <size>0x20</size>
          <fields>
            <field>
              <name>CC3S</name>
              <bitOffset>0</bitOffset>
              <bitWidth>2</bitWidth>
            </field>
            <field>
              <name>OC3FE</name>
              <bitOffset>2</bitOffset>
              <bitWidth>1</bitWidth>
            </field>
            <field>
              <name>OC3PE</name>
              <bitOffset>3</bitOffset>
              <bitWidth>1</bitWidth>
            </field>
            <field>
              <name>OC3M</name>
              <bitOffset>4</bitOffset>
              <bitWidth>13</bitWidth>
            </field>
            <field>
              <name>OC3CE</name>
              <bitOffset>7</bitOffset>
              <bitWidth>1</bitWidth>
            </field>
            <field>
              <name>CC4S</name>
              <bitOffset>8</bitOffset>
              <bitWidth>2</bitWidth>
            </field>
            <field>
              <name>OC4FE</name>
              <bitOffset>10</bitOffset>
              <bitWidth>1</bitWidth>
            </field>
            <field>
              <name>OC4PE</name>
              <bitOffset>11</bitOffset>
              <bitWidth>1</bitWidth>
            </field>
            <field>
              <name>OC4M</name>
              <bitOffset>12</bitOffset>
              <bitWidth>13</bitWidth>
            </field>
            <field>
              <name>OC4CE</name>
              <bitOffset>15</bitOffset>
              <bitWidth>1</bitWidth>
            </field>
          </fields>
        </register>
        <register>
          <name>CCER</name>
          <addressOffset>0x20</addressOffset>
          <size>0x20</size>
          <fields>
            <field>
              <name>CC1E</name>
              <bitOffset>0</bitOffset>
              <bitWidth>1</bitWidth>
            </field>
            <field>
              <name>CC1P</name>
              <bitOffset>1</bitOffset>
              <bitWidth>1</bitWidth>
            </field>
            <field>
              <name>CC1NE</name>
              <bitOffset>2</bitOffset>
              <bitWidth>1</bitWidth>
            </field>
            <field>
              <name>CC1NP</name>
              <bitOffset>3</bitOffset>
              <bitWidth>1</bitWidth>
            </field>
            <field>
              <name>CC2E</name>
              <bitOffset>4</bitOffset>
              <bitWidth>1</bitWidth>
            </field>
            <field>
              <name>CC2P</name>
              <bitOffset>5</bitOffset>
              <bitWidth>1</bitWidth>
            </field>
            <field>
              <name>CC2NE</name>
              <bitOffset>6</bitOffset>
              <bitWidth>1</bitWidth>
            </field>
            <field>
              <name>CC2NP</name>
              <bitOffset>7</bitOffset>
              <bitWidth>1</bitWidth>
            </field>
            <field>
              <name>CC3E</name>
              <bitOffset>8</bitOffset>
              <bitWidth>1</bitWidth>
            </field>
            <field>
              <name>CC3P</name>
              <bitOffset>9</bitOffset>
              <bitWidth>1</bitWidth>
            </field>
            <field>
              <name>CC3NE</name>
              <bitOffset>10</bitOffset>
              <bitWidth>1</bitWidth>
            </field>
            <field>
              <name>CC3NP</name>
              <bitOffset>11</bitOffset>
              <bitWidth>1</bitWidth>
            </field>
            <field>
              <name>CC4E</name>
              <bitOffset>12</bitOffset>
              <bitWidth>1</bitWidth>
            </field>
            <field>
              <name>CC4P</name>
              <bitOffset>13</bitOffset>
              <bitWidth>1</bitWidth>
            </field>
            <field>
              <name>CC4NP</name>
              <bitOffset>15</bitOffset>
              <bitWidth>1</bitWidth>
            </field>
            <field>
              <name>CC5E</name>
              <bitOffset>16</bitOffset>
              <bitWidth>1</bitWidth>
            </field>
            <field>
              <name>CC5P</name>
              <bitOffset>17</bitOffset>
              <bitWidth>1</bitWidth>
            </field>
            <field>
              <name>CC6E</name>
              <bitOffset>20</bitOffset>
              <bitWidth>1</bitWidth>
            </field>
            <field>
              <name>CC6P</name>
              <bitOffset>21</bitOffset>
              <bitWidth>1</bitWidth>
            </field>
          </fields>
        </register>
        <register>
          <name>CNT</name>
          <addressOffset>0x24</addressOffset>
          <size>0x20</size>
          <fields>
            <field>
              <name>CNT</name>
              <bitOffset>0</bitOffset>
              <bitWidth>32</bitWidth>
            </field>
            <field>
              <name>UIFCPY</name>
              <bitOffset>31</bitOffset>
              <bitWidth>1</bitWidth>
            </field>
          </fields>
        </register>
        <register>
          <name>PSC</name>
          <addressOffset>0x28</addressOffset>
          <size>0x20</size>
          <fields>
            <field>
              <name>PSC</name>
              <bitOffset>0</bitOffset>
              <bitWidth>16</bitWidth>
            </field>
          </fields>
        </register>
        <register>
          <name>ARR</name>
          <addressOffset>0x2c</addressOffset>
          <size>0x20</size>
          <fields>
            <field>
              <name>ARR</name>
              <bitOffset>0</bitOffset>
              <bitWidth>32</bitWidth>
            </field>
          </fields>
        </register>
        <register>
          <name>RCR</name>
          <addressOffset>0x30</addressOffset>
          <size>0x20</size>
          <fields>
            <field>
              <name>REP</name>
              <bitOffset>0</bitOffset>
              <bitWidth>16</bitWidth>
            </field>
          </fields>
        </register>
        <register>
          <name>CCR1</name>
          <addressOffset>0x34</addressOffset>
          <size>0x20</size>
          <fields>
            <field>
              <name>CCR1</name>
              <bitOffset>0</bitOffset>
              <bitWidth>16</bitWidth>
            </field>
          </fields>
        </register>
        <register>
          <name>CCR2</name>
          <addressOffset>0x38</addressOffset>
          <size>0x20</size>
          <fields>
            <field>
              <name>CCR2</name>
              <bitOffset>0</bitOffset>
              <bitWidth>16</bitWidth>
            </field>
          </fields>
        </register>
        <register>
          <name>CCR3</name>
          <addressOffset>0x3c</addressOffset>
          <size>0x20</size>
          <fields>
            <field>
              <name>CCR3</name>
              <bitOffset>0</bitOffset>
              <bitWidth>16</bitWidth>
            </field>
          </fields>
        </register>
        <register>
          <name>CCR4</name>
          <addressOffset>0x40</addressOffset>
          <size>0x20</size>
          <fields>
            <field>
              <name>CCR4</name>
              <bitOffset>0</bitOffset>
              <bitWidth>16</bitWidth>
            </field>
          </fields>
        </register>
        <register>
          <name>BDTR</name>
          <addressOffset>0x44</addressOffset>
          <size>0x20</size>
          <fields>
            <field>
              <name>DTG</name>
              <bitOffset>0</bitOffset>
              <bitWidth>8</bitWidth>
            </field>
            <field>
              <name>LOCK</name>
              <bitOffset>8</bitOffset>
              <bitWidth>2</bitWidth>
            </field>
            <field>
              <name>OSSI</name>
              <bitOffset>10</bitOffset>
              <bitWidth>1</bitWidth>
            </field>
            <field>
              <name>OSSR</name>
              <bitOffset>11</bitOffset>
              <bitWidth>1</bitWidth>
            </field>
            <field>
              <name>BKE</name>
              <bitOffset>12</bitOffset>
              <bitWidth>1</bitWidth>
            </field>
            <field>
              <name>BKP</name>
              <bitOffset>13</bitOffset>
              <bitWidth>1</bitWidth>
            </field>
            <field>
              <name>AOE</name>
              <bitOffset>14</bitOffset>
              <bitWidth>1</bitWidth>
            </field>
            <field>
              <name>MOE</name>
              <bitOffset>15</bitOffset>
              <bitWidth>1</bitWidth>
            </field>
            <field>
              <name>BKF</name>
              <bitOffset>16</bitOffset>
              <bitWidth>4</bitWidth>
            </field>
            <field>
              <name>BK2F</name>
              <bitOffset>20</bitOffset>
              <bitWidth>4</bitWidth>
            </field>
            <field>
              <name>BK2E</name>
              <bitOffset>24</bitOffset>
              <bitWidth>1</bitWidth>
            </field>
            <field>
              <name>BK2P</name>
              <bitOffset>25</bitOffset>
              <bitWidth>1</bitWidth>
            </field>
          </fields>
        </register>
        <register>
          <name>DCR</name>
          <addressOffset>0x48</addressOffset>
          <size>0x20</size>
          <fields>
            <field>
              <name>DBA</name>
              <bitOffset>0</bitOffset>
              <bitWidth>5</bitWidth>
            </field>
            <field>
              <name>DBL</name>
              <bitOffset>8</bitOffset>
              <bitWidth>5</bitWidth>
            </field>
          </fields>
        </register>
        <register>
          <name>DMAR</name>
          <addressOffset>0x4c</addressOffset>
          <size>0x20</size>
          <fields>
            <field>
              <name>DMAB</name>
              <bitOffset>0</bitOffset>
              <bitWidth>16</bitWidth>
            </field>
          </fields>
        </register>
        <register>
          <name>OR</name>
          <addressOffset>0x50</addressOffset>
          <size>0x20</size>
          <fields>
            <field>
              <name>TI4_RMP</name>
              <bitOffset>6</bitOffset>
              <bitWidth>2</bitWidth>
            </field>
            <field>
              <name>ITR1_RMP</name>
              <bitOffset>10</bitOffset>
              <bitWidth>2</bitWidth>
            </field>
          </fields>
        </register>
        <register>
          <name>CCMR3</name>
          <addressOffset>0x54</addressOffset>
          <size>0x20</size>
          <fields>
            <field>
              <name>OC5FE</name>
              <bitOffset>2</bitOffset>
              <bitWidth>1</bitWidth>
            </field>
            <field>
              <name>OC5PE</name>
              <bitOffset>3</bitOffset>
              <bitWidth>1</bitWidth>
            </field>
            <field>
              <name>OC5M</name>
              <bitOffset>4</bitOffset>
              <bitWidth>13</bitWidth>
            </field>
            <field>
              <name>OC5CE</name>
              <bitOffset>7</bitOffset>
              <bitWidth>1</bitWidth>
            </field>
            <field>
              <name>OC6FE</name>
              <bitOffset>10</bitOffset>
              <bitWidth>1</bitWidth>
            </field>
            <field>
              <name>OC6PE</name>
              <bitOffset>11</bitOffset>
              <bitWidth>1</bitWidth>
            </field>
            <field>
              <name>OC6M</name>
              <bitOffset>12</bitOffset>
              <bitWidth>13</bitWidth>
            </field>
            <field>
              <name>OC6CE</name>
              <bitOffset>15</bitOffset>
              <bitWidth>1</bitWidth>
            </field>
          </fields>
        </register>
        <register>
          <name>CCR5</name>
          <addressOffset>0x58</addressOffset>
          <size>0x20</size>
          <fields>
            <field>
              <name>CCR5</name>
              <bitOffset>0</bitOffset>
              <bitWidth>32</bitWidth>
            </field>
            <field>
              <name>GC5C1</name>
              <bitOffset>29</bitOffset>
              <bitWidth>1</bitWidth>
            </field>
            <field>
              <name>GC5C2</name>
              <bitOffset>30</bitOffset>
              <bitWidth>1</bitWidth>
            </field>
            <field>
              <name>GC5C3</name>
              <bitOffset>31</bitOffset>
              <bitWidth>1</bitWidth>
            </field>
          </fields>
        </register>
        <register>
          <name>CCR6</name>
          <addressOffset>0x5c</addressOffset>
          <size>0x20</size>
        </register>
        <register>
          <name>AF1</name>
          <addressOffset>0x60</addressOffset>
          <size>0x20</size>
        </register>
        <register>
          <name>AF2</name>
          <addressOffset>0x64</addressOffset>
          <size>0x20</size>
        </register>
      </registers>
    </peripheral>
    <peripheral>
      <name>TIM11</name>
      <baseAddress>0x40014800</baseAddress>
      <registers>
        <register>
          <name>CR1</name>
          <addressOffset>0x0</addressOffset>
          <size>0x20</size>
          <fields>
            <field>
              <name>CEN</name>
              <bitOffset>0</bitOffset>
              <bitWidth>1</bitWidth>
            </field>
            <field>
              <name>UDIS</name>
              <bitOffset>1</bitOffset>
              <bitWidth>1</bitWidth>
            </field>
            <field>
              <name>URS</name>
              <bitOffset>2</bitOffset>
              <bitWidth>1</bitWidth>
            </field>
            <field>
              <name>OPM</name>
              <bitOffset>3</bitOffset>
              <bitWidth>1</bitWidth>
            </field>
            <field>
              <name>DIR</name>
              <bitOffset>4</bitOffset>
              <bitWidth>1</bitWidth>
            </field>
            <field>
              <name>CMS</name>
              <bitOffset>5</bitOffset>
              <bitWidth>2</bitWidth>
            </field>
            <field>
              <name>ARPE</name>
              <bitOffset>7</bitOffset>
              <bitWidth>1</bitWidth>
            </field>
            <field>
              <name>CKD</name>
              <bitOffset>8</bitOffset>
              <bitWidth>2</bitWidth>
            </field>
            <field>
              <name>UIFREMAP</name>
              <bitOffset>11</bitOffset>
              <bitWidth>1</bitWidth>
            </field>
          </fields>
        </register>
        <register>
          <name>CR2</name>
          <addressOffset>0x4</addressOffset>
          <size>0x20</size>
          <fields>
            <field>
              <name>CCPC</name>
              <bitOffset>0</bitOffset>
              <bitWidth>1</bitWidth>
            </field>
            <field>
              <name>CCUS</name>
              <bitOffset>2</bitOffset>
              <bitWidth>1</bitWidth>
            </field>
            <field>
              <name>CCDS</name>
              <bitOffset>3</bitOffset>
              <bitWidth>1</bitWidth>
            </field>
            <field>
              <name>MMS</name>
              <bitOffset>4</bitOffset>
              <bitWidth>3</bitWidth>
            </field>
            <field>
              <name>TI1S</name>
              <bitOffset>7</bitOffset>
              <bitWidth>1</bitWidth>
            </field>
            <field>
              <name>OIS1</name>
              <bitOffset>8</bitOffset>
              <bitWidth>1</bitWidth>
            </field>
            <field>
              <name>OIS1N</name>
              <bitOffset>9</bitOffset>
              <bitWidth>1</bitWidth>
            </field>
            <field>
              <name>OIS2</name>
              <bitOffset>10</bitOffset>
              <bitWidth>1</bitWidth>
            </field>
            <field>
              <name>OIS2N</name>
              <bitOffset>11</bitOffset>
              <bitWidth>1</bitWidth>
            </field>
            <field>
              <name>OIS3</name>
              <bitOffset>12</bitOffset>
              <bitWidth>1</bitWidth>
            </field>
            <field>
              <name>OIS3N</name>
              <bitOffset>13</bitOffset>
              <bitWidth>1</bitWidth>
            </field>
            <field>
              <name>OIS4</name>
              <bitOffset>14</bitOffset>
              <bitWidth>1</bitWidth>
            </field>
            <field>
              <name>OIS5</name>
              <bitOffset>16</bitOffset>
              <bitWidth>1</bitWidth>
            </field>
            <field>
              <name>OIS6</name>
              <bitOffset>18</bitOffset>
              <bitWidth>1</bitWidth>
            </field>
            <field>
              <name>MMS2</name>
              <bitOffset>20</bitOffset>
              <bitWidth>4</bitWidth>
            </field>
          </fields>
        </register>
        <register>
          <name>SMCR</name>
          <addressOffset>0x8</addressOffset>
          <size>0x20</size>
          <fields>
            <field>
              <name>SMS</name>
              <bitOffset>0</bitOffset>
              <bitWidth>17</bitWidth>
            </field>
            <field>
              <name>TS</name>
              <bitOffset>4</bitOffset>
              <bitWidth>3</bitWidth>
            </field>
            <field>
              <name>MSM</name>
              <bitOffset>7</bitOffset>
              <bitWidth>1</bitWidth>
            </field>
            <field>
              <name>ETF</name>
              <bitOffset>8</bitOffset>
              <bitWidth>4</bitWidth>
            </field>
            <field>
              <name>ETPS</name>
              <bitOffset>12</bitOffset>
              <bitWidth>2</bitWidth>
            </field>
            <field>
              <name>ECE</name>
              <bitOffset>14</bitOffset>
              <bitWidth>1</bitWidth>
            </field>
            <field>
              <name>ETP</name>
              <bitOffset>15</bitOffset>
              <bitWidth>1</bitWidth>
            </field>
          </fields>
        </register>
        <register>
          <name>DIER</name>
          <addressOffset>0xc</addressOffset>
          <size>0x20</size>
          <fields>
            <field>
              <name>UIE</name>
              <bitOffset>0</bitOffset>
              <bitWidth>1</bitWidth>
            </field>
            <field>
              <name>CC1IE</name>
              <bitOffset>1</bitOffset>
              <bitWidth>1</bitWidth>
            </field>
            <field>
              <name>CC2IE</name>
              <bitOffset>2</bitOffset>
              <bitWidth>1</bitWidth>
            </field>
            <field>
              <name>CC3IE</name>
              <bitOffset>3</bitOffset>
              <bitWidth>1</bitWidth>
            </field>
            <field>
              <name>CC4IE</name>
              <bitOffset>4</bitOffset>
              <bitWidth>1</bitWidth>
            </field>
            <field>
              <name>COMIE</name>
              <bitOffset>5</bitOffset>
              <bitWidth>1</bitWidth>
            </field>
            <field>
              <name>TIE</name>
              <bitOffset>6</bitOffset>
              <bitWidth>1</bitWidth>
            </field>
            <field>
              <name>BIE</name>
              <bitOffset>7</bitOffset>
              <bitWidth>1</bitWidth>
            </field>
            <field>
              <name>UDE</name>
              <bitOffset>8</bitOffset>
              <bitWidth>1</bitWidth>
            </field>
            <field>
              <name>CC1DE</name>
              <bitOffset>9</bitOffset>
              <bitWidth>1</bitWidth>
            </field>
            <field>
              <name>CC2DE</name>
              <bitOffset>10</bitOffset>
              <bitWidth>1</bitWidth>
            </field>
            <field>
              <name>CC3DE</name>
              <bitOffset>11</bitOffset>
              <bitWidth>1</bitWidth>
            </field>
            <field>
              <name>CC4DE</name>
              <bitOffset>12</bitOffset>
              <bitWidth>1</bitWidth>
            </field>
            <field>
              <name>COMDE</name>
              <bitOffset>13</bitOffset>
              <bitWidth>1</bitWidth>
            </field>
            <field>
              <name>TDE</name>
              <bitOffset>14</bitOffset>
              <bitWidth>1</bitWidth>
            </field>
          </fields>
        </register>
        <register>
          <name>SR</name>
          <addressOffset>0x10</addressOffset>
          <size>0x20</size>
          <fields>
            <field>
              <name>UIF</name>
              <bitOffset>0</bitOffset>
              <bitWidth>1</bitWidth>
            </field>
            <field>
              <name>CC1IF</name>
              <bitOffset>1</bitOffset>
              <bitWidth>1</bitWidth>
            </field>
            <field>
              <name>CC2IF</name>
              <bitOffset>2</bitOffset>
              <bitWidth>1</bitWidth>
            </field>
            <field>
              <name>CC3IF</name>
              <bitOffset>3</bitOffset>
              <bitWidth>1</bitWidth>
            </field>
            <field>
              <name>CC4IF</name>
              <bitOffset>4</bitOffset>
              <bitWidth>1</bitWidth>
            </field>
            <field>
              <name>COMIF</name>
              <bitOffset>5</bitOffset>
              <bitWidth>1</bitWidth>
            </field>
            <field>
              <name>TIF</name>
              <bitOffset>6</bitOffset>
              <bitWidth>1</bitWidth>
            </field>
            <field>
              <name>BIF</name>
              <bitOffset>7</bitOffset>
              <bitWidth>1</bitWidth>
            </field>
            <field>
              <name>B2IF</name>
              <bitOffset>8</bitOffset>
              <bitWidth>1</bitWidth>
            </field>
            <field>
              <name>CC1OF</name>
              <bitOffset>9</bitOffset>
              <bitWidth>1</bitWidth>
            </field>
            <field>
              <name>CC2OF</name>
              <bitOffset>10</bitOffset>
              <bitWidth>1</bitWidth>
            </field>
            <field>
              <name>CC3OF</name>
              <bitOffset>11</bitOffset>
              <bitWidth>1</bitWidth>
            </field>
            <field>
              <name>CC4OF</name>
              <bitOffset>12</bitOffset>
              <bitWidth>1</bitWidth>
            </field>
            <field>
              <name>SBIF</name>
              <bitOffset>13</bitOffset>
              <bitWidth>1</bitWidth>
            </field>
            <field>
              <name>CC5IF</name>
              <bitOffset>16</bitOffset>
              <bitWidth>1</bitWidth>
            </field>
            <field>
              <name>CC6IF</name>
              <bitOffset>17</bitOffset>
              <bitWidth>1</bitWidth>
            </field>
          </fields>
        </register>
        <register>
          <name>EGR</name>
          <addressOffset>0x14</addressOffset>
          <size>0x20</size>
          <fields>
            <field>
              <name>UG</name>
              <bitOffset>0</bitOffset>
              <bitWidth>1</bitWidth>
            </field>
            <field>
              <name>CC1G</name>
              <bitOffset>1</bitOffset>
              <bitWidth>1</bitWidth>
            </field>
            <field>
              <name>CC2G</name>
              <bitOffset>2</bitOffset>
              <bitWidth>1</bitWidth>
            </field>
            <field>
              <name>CC3G</name>
              <bitOffset>3</bitOffset>
              <bitWidth>1</bitWidth>
            </field>
            <field>
              <name>CC4G</name>
              <bitOffset>4</bitOffset>
              <bitWidth>1</bitWidth>
            </field>
            <field>
              <name>COMG</name>
              <bitOffset>5</bitOffset>
              <bitWidth>1</bitWidth>
            </field>
            <field>
              <name>TG</name>
              <bitOffset>6</bitOffset>
              <bitWidth>1</bitWidth>
            </field>
            <field>
              <name>BG</name>
              <bitOffset>7</bitOffset>
              <bitWidth>1</bitWidth>
            </field>
            <field>
              <name>B2G</name>
              <bitOffset>8</bitOffset>
              <bitWidth>1</bitWidth>
            </field>
          </fields>
        </register>
        <register>
          <name>CCMR1</name>
          <addressOffset>0x18</addressOffset>
          <size>0x20</size>
          <fields>
            <field>
              <name>CC1S</name>
              <bitOffset>0</bitOffset>
              <bitWidth>2</bitWidth>
            </field>
            <field>
              <name>OC1FE</name>
              <bitOffset>2</bitOffset>
              <bitWidth>1</bitWidth>
            </field>
            <field>
              <name>OC1PE</name>
              <bitOffset>3</bitOffset>
              <bitWidth>1</bitWidth>
            </field>
            <field>
              <name>OC1M</name>
              <bitOffset>4</bitOffset>
              <bitWidth>13</bitWidth>
            </field>
            <field>
              <name>OC1CE</name>
              <bitOffset>7</bitOffset>
              <bitWidth>1</bitWidth>
            </field>
            <field>
              <name>CC2S</name>
              <bitOffset>8</bitOffset>
              <bitWidth>2</bitWidth>
            </field>
            <field>
              <name>OC2FE</name>
              <bitOffset>10</bitOffset>
              <bitWidth>1</bitWidth>
            </field>
            <field>
              <name>OC2PE</name>
              <bitOffset>11</bitOffset>
              <bitWidth>1</bitWidth>
            </field>
            <field>
              <name>OC2M</name>
              <bitOffset>12</bitOffset>
              <bitWidth>13</bitWidth>
            </field>
            <field>
              <name>OC2CE</name>
              <bitOffset>15</bitOffset>
              <bitWidth>1</bitWidth>
            </field>
          </fields>
        </register>
        <register>
          <name>CCMR2</name>
          <addressOffset>0x1c</addressOffset>
          <size>0x20</size>
          <fields>
            <field>
              <name>CC3S</name>
              <bitOffset>0</bitOffset>
              <bitWidth>2</bitWidth>
            </field>
            <field>
              <name>OC3FE</name>
              <bitOffset>2</bitOffset>
              <bitWidth>1</bitWidth>
            </field>
            <field>
              <name>OC3PE</name>
              <bitOffset>3</bitOffset>
              <bitWidth>1</bitWidth>
            </field>
            <field>
              <name>OC3M</name>
              <bitOffset>4</bitOffset>
              <bitWidth>13</bitWidth>
            </field>
            <field>
              <name>OC3CE</name>
              <bitOffset>7</bitOffset>
              <bitWidth>1</bitWidth>
            </field>
            <field>
              <name>CC4S</name>
              <bitOffset>8</bitOffset>
              <bitWidth>2</bitWidth>
            </field>
            <field>
              <name>OC4FE</name>
              <bitOffset>10</bitOffset>
              <bitWidth>1</bitWidth>
            </field>
            <field>
              <name>OC4PE</name>
              <bitOffset>11</bitOffset>
              <bitWidth>1</bitWidth>
            </field>
            <field>
              <name>OC4M</name>
              <bitOffset>12</bitOffset>
              <bitWidth>13</bitWidth>
            </field>
            <field>
              <name>OC4CE</name>
              <bitOffset>15</bitOffset>
              <bitWidth>1</bitWidth>
            </field>
          </fields>
        </register>
        <register>
          <name>CCER</name>
          <addressOffset>0x20</addressOffset>
          <size>0x20</size>
          <fields>
            <field>
              <name>CC1E</name>
              <bitOffset>0</bitOffset>
              <bitWidth>1</bitWidth>
            </field>
            <field>
              <name>CC1P</name>
              <bitOffset>1</bitOffset>
              <bitWidth>1</bitWidth>
            </field>
            <field>
              <name>CC1NE</name>
              <bitOffset>2</bitOffset>
              <bitWidth>1</bitWidth>
            </field>
            <field>
              <name>CC1NP</name>
              <bitOffset>3</bitOffset>
              <bitWidth>1</bitWidth>
            </field>
            <field>
              <name>CC2E</name>
              <bitOffset>4</bitOffset>
              <bitWidth>1</bitWidth>
            </field>
            <field>
              <name>CC2P</name>
              <bitOffset>5</bitOffset>
              <bitWidth>1</bitWidth>
            </field>
            <field>
              <name>CC2NE</name>
              <bitOffset>6</bitOffset>
              <bitWidth>1</bitWidth>
            </field>
            <field>
              <name>CC2NP</name>
              <bitOffset>7</bitOffset>
              <bitWidth>1</bitWidth>
            </field>
            <field>
              <name>CC3E</name>
              <bitOffset>8</bitOffset>
              <bitWidth>1</bitWidth>
            </field>
            <field>
              <name>CC3P</name>
              <bitOffset>9</bitOffset>
              <bitWidth>1</bitWidth>
            </field>
            <field>
              <name>CC3NE</name>
              <bitOffset>10</bitOffset>
              <bitWidth>1</bitWidth>
            </field>
            <field>
              <name>CC3NP</name>
              <bitOffset>11</bitOffset>
              <bitWidth>1</bitWidth>
            </field>
            <field>
              <name>CC4E</name>
              <bitOffset>12</bitOffset>
              <bitWidth>1</bitWidth>
            </field>
            <field>
              <name>CC4P</name>
              <bitOffset>13</bitOffset>
              <bitWidth>1</bitWidth>
            </field>
            <field>
              <name>CC4NP</name>
              <bitOffset>15</bitOffset>
              <bitWidth>1</bitWidth>
            </field>
            <field>
              <name>CC5E</name>
              <bitOffset>16</bitOffset>
              <bitWidth>1</bitWidth>
            </field>
            <field>
              <name>CC5P</name>
              <bitOffset>17</bitOffset>
              <bitWidth>1</bitWidth>
            </field>
            <field>
              <name>CC6E</name>
              <bitOffset>20</bitOffset>
              <bitWidth>1</bitWidth>
            </field>
            <field>
              <name>CC6P</name>
              <bitOffset>21</bitOffset>
              <bitWidth>1</bitWidth>
            </field>
          </fields>
        </register>
        <register>
          <name>CNT</name>
          <addressOffset>0x24</addressOffset>
          <size>0x20</size>
          <fields>
            <field>
              <name>CNT</name>
              <bitOffset>0</bitOffset>
              <bitWidth>32</bitWidth>
            </field>
            <field>
              <name>UIFCPY</name>
              <bitOffset>31</bitOffset>
              <bitWidth>1</bitWidth>
            </field>
          </fields>
        </register>
        <register>
          <name>PSC</name>
          <addressOffset>0x28</addressOffset>
          <size>0x20</size>
          <fields>
            <field>
              <name>PSC</name>
              <bitOffset>0</bitOffset>
              <bitWidth>16</bitWidth>
            </field>
          </fields>
        </register>
        <register>
          <name>ARR</name>
          <addressOffset>0x2c</addressOffset>
          <size>0x20</size>
          <fields>
            <field>
              <name>ARR</name>
              <bitOffset>0</bitOffset>
              <bitWidth>32</bitWidth>
            </field>
          </fields>
        </register>
        <register>
          <name>RCR</name>
          <addressOffset>0x30</addressOffset>
          <size>0x20</size>
          <fields>
            <field>
              <name>REP</name>
              <bitOffset>0</bitOffset>
              <bitWidth>16</bitWidth>
            </field>
          </fields>
        </register>
        <register>
          <name>CCR1</name>
          <addressOffset>0x34</addressOffset>
          <size>0x20</size>
          <fields>
            <field>
              <name>CCR1</name>
              <bitOffset>0</bitOffset>
              <bitWidth>16</bitWidth>
            </field>
          </fields>
        </register>
        <register>
          <name>CCR2</name>
          <addressOffset>0x38</addressOffset>
          <size>0x20</size>
          <fields>
            <field>
              <name>CCR2</name>
              <bitOffset>0</bitOffset>
              <bitWidth>16</bitWidth>
            </field>
          </fields>
        </register>
        <register>
          <name>CCR3</name>
          <addressOffset>0x3c</addressOffset>
          <size>0x20</size>
          <fields>
            <field>
              <name>CCR3</name>
              <bitOffset>0</bitOffset>
              <bitWidth>16</bitWidth>
            </field>
          </fields>
        </register>
        <register>
          <name>CCR4</name>
          <addressOffset>0x40</addressOffset>
          <size>0x20</size>
          <fields>
            <field>
              <name>CCR4</name>
              <bitOffset>0</bitOffset>
              <bitWidth>16</bitWidth>
            </field>
          </fields>
        </register>
        <register>
          <name>BDTR</name>
          <addressOffset>0x44</addressOffset>
          <size>0x20</size>
          <fields>
            <field>
              <name>DTG</name>
              <bitOffset>0</bitOffset>
              <bitWidth>8</bitWidth>
            </field>
            <field>
              <name>LOCK</name>
              <bitOffset>8</bitOffset>
              <bitWidth>2</bitWidth>
            </field>
            <field>
              <name>OSSI</name>
              <bitOffset>10</bitOffset>
              <bitWidth>1</bitWidth>
            </field>
            <field>
              <name>OSSR</name>
              <bitOffset>11</bitOffset>
              <bitWidth>1</bitWidth>
            </field>
            <field>
              <name>BKE</name>
              <bitOffset>12</bitOffset>
              <bitWidth>1</bitWidth>
            </field>
            <field>
              <name>BKP</name>
              <bitOffset>13</bitOffset>
              <bitWidth>1</bitWidth>
            </field>
            <field>
              <name>AOE</name>
              <bitOffset>14</bitOffset>
              <bitWidth>1</bitWidth>
            </field>
            <field>
              <name>MOE</name>
              <bitOffset>15</bitOffset>
              <bitWidth>1</bitWidth>
            </field>
            <field>
              <name>BKF</name>
              <bitOffset>16</bitOffset>
              <bitWidth>4</bitWidth>
            </field>
            <field>
              <name>BK2F</name>
              <bitOffset>20</bitOffset>
              <bitWidth>4</bitWidth>
            </field>
            <field>
              <name>BK2E</name>
              <bitOffset>24</bitOffset>
              <bitWidth>1</bitWidth>
            </field>
            <field>
              <name>BK2P</name>
              <bitOffset>25</bitOffset>
              <bitWidth>1</bitWidth>
            </field>
          </fields>
        </register>
        <register>
          <name>DCR</name>
          <addressOffset>0x48</addressOffset>
          <size>0x20</size>
          <fields>
            <field>
              <name>DBA</name>
              <bitOffset>0</bitOffset>
              <bitWidth>5</bitWidth>
            </field>
            <field>
              <name>DBL</name>
              <bitOffset>8</bitOffset>
              <bitWidth>5</bitWidth>
            </field>
          </fields>
        </register>
        <register>
          <name>DMAR</name>
          <addressOffset>0x4c</addressOffset>
          <size>0x20</size>
          <fields>
            <field>
              <name>DMAB</name>
              <bitOffset>0</bitOffset>
              <bitWidth>16</bitWidth>
            </field>
          </fields>
        </register>
        <register>
          <name>OR</name>
          <addressOffset>0x50</addressOffset>
          <size>0x20</size>
          <fields>
            <field>
              <name>TI4_RMP</name>
              <bitOffset>6</bitOffset>
              <bitWidth>2</bitWidth>
            </field>
            <field>
              <name>ITR1_RMP</name>
              <bitOffset>10</bitOffset>
              <bitWidth>2</bitWidth>
            </field>
          </fields>
        </register>
        <register>
          <name>CCMR3</name>
          <addressOffset>0x54</addressOffset>
          <size>0x20</size>
          <fields>
            <field>
              <name>OC5FE</name>
              <bitOffset>2</bitOffset>
              <bitWidth>1</bitWidth>
            </field>
            <field>
              <name>OC5PE</name>
              <bitOffset>3</bitOffset>
              <bitWidth>1</bitWidth>
            </field>
            <field>
              <name>OC5M</name>
              <bitOffset>4</bitOffset>
              <bitWidth>13</bitWidth>
            </field>
            <field>
              <name>OC5CE</name>
              <bitOffset>7</bitOffset>
              <bitWidth>1</bitWidth>
            </field>
            <field>
              <name>OC6FE</name>
              <bitOffset>10</bitOffset>
              <bitWidth>1</bitWidth>
            </field>
            <field>
              <name>OC6PE</name>
              <bitOffset>11</bitOffset>
              <bitWidth>1</bitWidth>
            </field>
            <field>
              <name>OC6M</name>
              <bitOffset>12</bitOffset>
              <bitWidth>13</bitWidth>
            </field>
            <field>
              <name>OC6CE</name>
              <bitOffset>15</bitOffset>
              <bitWidth>1</bitWidth>
            </field>
          </fields>
        </register>
        <register>
          <name>CCR5</name>
          <addressOffset>0x58</addressOffset>
          <size>0x20</size>
          <fields>
            <field>
              <name>CCR5</name>
              <bitOffset>0</bitOffset>
              <bitWidth>32</bitWidth>
            </field>
            <field>
              <name>GC5C1</name>
              <bitOffset>29</bitOffset>
              <bitWidth>1</bitWidth>
            </field>
            <field>
              <name>GC5C2</name>
              <bitOffset>30</bitOffset>
              <bitWidth>1</bitWidth>
            </field>
            <field>
              <name>GC5C3</name>
              <bitOffset>31</bitOffset>
              <bitWidth>1</bitWidth>
            </field>
          </fields>
        </register>
        <register>
          <name>CCR6</name>
          <addressOffset>0x5c</addressOffset>
          <size>0x20</size>
        </register>
        <register>
          <name>AF1</name>
          <addressOffset>0x60</addressOffset>
          <size>0x20</size>
        </register>
        <register>
          <name>AF2</name>
          <addressOffset>0x64</addressOffset>
          <size>0x20</size>
        </register>
      </registers>
    </peripheral>
    <peripheral>
      <name>SPI5</name>
      <baseAddress>0x40015000</baseAddress>
      <registers>
        <register>
          <name>CR1</name>
          <addressOffset>0x0</addressOffset>
          <size>0x20</size>
          <fields>
            <field>
              <name>CPHA</name>
              <bitOffset>0</bitOffset>
              <bitWidth>1</bitWidth>
            </field>
            <field>
              <name>CPOL</name>
              <bitOffset>1</bitOffset>
              <bitWidth>1</bitWidth>
            </field>
            <field>
              <name>MSTR</name>
              <bitOffset>2</bitOffset>
              <bitWidth>1</bitWidth>
            </field>
            <field>
              <name>BR</name>
              <bitOffset>3</bitOffset>
              <bitWidth>3</bitWidth>
            </field>
            <field>
              <name>SPE</name>
              <bitOffset>6</bitOffset>
              <bitWidth>1</bitWidth>
            </field>
            <field>
              <name>LSBFIRST</name>
              <bitOffset>7</bitOffset>
              <bitWidth>1</bitWidth>
            </field>
            <field>
              <name>SSI</name>
              <bitOffset>8</bitOffset>
              <bitWidth>1</bitWidth>
            </field>
            <field>
              <name>SSM</name>
              <bitOffset>9</bitOffset>
              <bitWidth>1</bitWidth>
            </field>
            <field>
              <name>RXONLY</name>
              <bitOffset>10</bitOffset>
              <bitWidth>1</bitWidth>
            </field>
            <field>
              <name>CRCL</name>
              <bitOffset>11</bitOffset>
              <bitWidth>1</bitWidth>
            </field>
            <field>
              <name>CRCNEXT</name>
              <bitOffset>12</bitOffset>
              <bitWidth>1</bitWidth>
            </field>
            <field>
              <name>CRCEN</name>
              <bitOffset>13</bitOffset>
              <bitWidth>1</bitWidth>
            </field>
            <field>
              <name>BIDIOE</name>
              <bitOffset>14</bitOffset>
              <bitWidth>1</bitWidth>
            </field>
            <field>
              <name>BIDIMODE</name>
              <bitOffset>15</bitOffset>
              <bitWidth>1</bitWidth>
            </field>
          </fields>
        </register>
        <register>
          <name>CR2</name>
          <addressOffset>0x4</addressOffset>
          <size>0x20</size>
          <fields>
            <field>
              <name>RXDMAEN</name>
              <bitOffset>0</bitOffset>
              <bitWidth>1</bitWidth>
            </field>
            <field>
              <name>TXDMAEN</name>
              <bitOffset>1</bitOffset>
              <bitWidth>1</bitWidth>
            </field>
            <field>
              <name>SSOE</name>
              <bitOffset>2</bitOffset>
              <bitWidth>1</bitWidth>
            </field>
            <field>
              <name>NSSP</name>
              <bitOffset>3</bitOffset>
              <bitWidth>1</bitWidth>
            </field>
            <field>
              <name>FRF</name>
              <bitOffset>4</bitOffset>
              <bitWidth>1</bitWidth>
            </field>
            <field>
              <name>ERRIE</name>
              <bitOffset>5</bitOffset>
              <bitWidth>1</bitWidth>
            </field>
            <field>
              <name>RXNEIE</name>
              <bitOffset>6</bitOffset>
              <bitWidth>1</bitWidth>
            </field>
            <field>
              <name>TXEIE</name>
              <bitOffset>7</bitOffset>
              <bitWidth>1</bitWidth>
            </field>
            <field>
              <name>DS</name>
              <bitOffset>8</bitOffset>
              <bitWidth>4</bitWidth>
            </field>
            <field>
              <name>FRXTH</name>
              <bitOffset>12</bitOffset>
              <bitWidth>1</bitWidth>
            </field>
            <field>
              <name>LDMARX</name>
              <bitOffset>13</bitOffset>
              <bitWidth>1</bitWidth>
            </field>
            <field>
              <name>LDMATX</name>
              <bitOffset>14</bitOffset>
              <bitWidth>1</bitWidth>
            </field>
          </fields>
        </register>
        <register>
          <name>SR</name>
          <addressOffset>0x8</addressOffset>
          <size>0x20</size>
          <fields>
            <field>
              <name>RXNE</name>
              <bitOffset>0</bitOffset>
              <bitWidth>1</bitWidth>
            </field>
            <field>
              <name>TXE</name>
              <bitOffset>1</bitOffset>
              <bitWidth>1</bitWidth>
            </field>
            <field>
              <name>CHSIDE</name>
              <bitOffset>2</bitOffset>
              <bitWidth>1</bitWidth>
            </field>
            <field>
              <name>UDR</name>
              <bitOffset>3</bitOffset>
              <bitWidth>1</bitWidth>
            </field>
            <field>
              <name>CRCERR</name>
              <bitOffset>4</bitOffset>
              <bitWidth>1</bitWidth>
            </field>
            <field>
              <name>MODF</name>
              <bitOffset>5</bitOffset>
              <bitWidth>1</bitWidth>
            </field>
            <field>
              <name>OVR</name>
              <bitOffset>6</bitOffset>
              <bitWidth>1</bitWidth>
            </field>
            <field>
              <name>BSY</name>
              <bitOffset>7</bitOffset>
              <bitWidth>1</bitWidth>
            </field>
            <field>
              <name>FRE</name>
              <bitOffset>8</bitOffset>
              <bitWidth>1</bitWidth>
            </field>
            <field>
              <name>FRLVL</name>
              <bitOffset>9</bitOffset>
              <bitWidth>2</bitWidth>
            </field>
            <field>
              <name>FTLVL</name>
              <bitOffset>11</bitOffset>
              <bitWidth>2</bitWidth>
            </field>
          </fields>
        </register>
        <register>
          <name>DR</name>
          <addressOffset>0xc</addressOffset>
          <size>0x20</size>
          <fields>
            <field>
              <name>DR</name>
              <bitOffset>0</bitOffset>
              <bitWidth>16</bitWidth>
            </field>
          </fields>
        </register>
        <register>
          <name>CRCPR</name>
          <addressOffset>0x10</addressOffset>
          <size>0x20</size>
          <fields>
            <field>
              <name>CRCPOLY</name>
              <bitOffset>0</bitOffset>
              <bitWidth>16</bitWidth>
            </field>
          </fields>
        </register>
        <register>
          <name>RXCRCR</name>
          <addressOffset>0x14</addressOffset>
          <size>0x20</size>
          <fields>
            <field>
              <name>RXCRC</name>
              <bitOffset>0</bitOffset>
              <bitWidth>16</bitWidth>
            </field>
          </fields>
        </register>
        <register>
          <name>TXCRCR</name>
          <addressOffset>0x18</addressOffset>
          <size>0x20</size>
          <fields>
            <field>
              <name>TXCRC</name>
              <bitOffset>0</bitOffset>
              <bitWidth>16</bitWidth>
            </field>
          </fields>
        </register>
        <register>
          <name>I2SCFGR</name>
          <addressOffset>0x1c</addressOffset>
          <size>0x20</size>
          <fields>
            <field>
              <name>CHLEN</name>
              <bitOffset>0</bitOffset>
              <bitWidth>1</bitWidth>
            </field>
            <field>
              <name>DATLEN</name>
              <bitOffset>1</bitOffset>
              <bitWidth>2</bitWidth>
            </field>
            <field>
              <name>CKPOL</name>
              <bitOffset>3</bitOffset>
              <bitWidth>1</bitWidth>
            </field>
            <field>
              <name>I2SSTD</name>
              <bitOffset>4</bitOffset>
              <bitWidth>2</bitWidth>
            </field>
            <field>
              <name>PCMSYNC</name>
              <bitOffset>7</bitOffset>
              <bitWidth>1</bitWidth>
            </field>
            <field>
              <name>I2SCFG</name>
              <bitOffset>8</bitOffset>
              <bitWidth>2</bitWidth>
            </field>
            <field>
              <name>I2SE</name>
              <bitOffset>10</bitOffset>
              <bitWidth>1</bitWidth>
            </field>
            <field>
              <name>I2SMOD</name>
              <bitOffset>11</bitOffset>
              <bitWidth>1</bitWidth>
            </field>
            <field>
              <name>ASTRTEN</name>
              <bitOffset>12</bitOffset>
              <bitWidth>1</bitWidth>
            </field>
          </fields>
        </register>
        <register>
          <name>I2SPR</name>
          <addressOffset>0x20</addressOffset>
          <size>0x20</size>
          <fields>
            <field>
              <name>I2SDIV</name>
              <bitOffset>0</bitOffset>
              <bitWidth>8</bitWidth>
            </field>
            <field>
              <name>ODD</name>
              <bitOffset>8</bitOffset>
              <bitWidth>1</bitWidth>
            </field>
            <field>
              <name>MCKOE</name>
              <bitOffset>9</bitOffset>
              <bitWidth>1</bitWidth>
            </field>
          </fields>
        </register>
      </registers>
    </peripheral>
    <peripheral>
      <name>SPI6</name>
      <baseAddress>0x40015400</baseAddress>
      <registers>
        <register>
          <name>CR1</name>
          <addressOffset>0x0</addressOffset>
          <size>0x20</size>
          <fields>
            <field>
              <name>CPHA</name>
              <bitOffset>0</bitOffset>
              <bitWidth>1</bitWidth>
            </field>
            <field>
              <name>CPOL</name>
              <bitOffset>1</bitOffset>
              <bitWidth>1</bitWidth>
            </field>
            <field>
              <name>MSTR</name>
              <bitOffset>2</bitOffset>
              <bitWidth>1</bitWidth>
            </field>
            <field>
              <name>BR</name>
              <bitOffset>3</bitOffset>
              <bitWidth>3</bitWidth>
            </field>
            <field>
              <name>SPE</name>
              <bitOffset>6</bitOffset>
              <bitWidth>1</bitWidth>
            </field>
            <field>
              <name>LSBFIRST</name>
              <bitOffset>7</bitOffset>
              <bitWidth>1</bitWidth>
            </field>
            <field>
              <name>SSI</name>
              <bitOffset>8</bitOffset>
              <bitWidth>1</bitWidth>
            </field>
            <field>
              <name>SSM</name>
              <bitOffset>9</bitOffset>
              <bitWidth>1</bitWidth>
            </field>
            <field>
              <name>RXONLY</name>
              <bitOffset>10</bitOffset>
              <bitWidth>1</bitWidth>
            </field>
            <field>
              <name>CRCL</name>
              <bitOffset>11</bitOffset>
              <bitWidth>1</bitWidth>
            </field>
            <field>
              <name>CRCNEXT</name>
              <bitOffset>12</bitOffset>
              <bitWidth>1</bitWidth>
            </field>
            <field>
              <name>CRCEN</name>
              <bitOffset>13</bitOffset>
              <bitWidth>1</bitWidth>
            </field>
            <field>
              <name>BIDIOE</name>
              <bitOffset>14</bitOffset>
              <bitWidth>1</bitWidth>
            </field>
            <field>
              <name>BIDIMODE</name>
              <bitOffset>15</bitOffset>
              <bitWidth>1</bitWidth>
            </field>
          </fields>
        </register>
        <register>
          <name>CR2</name>
          <addressOffset>0x4</addressOffset>
          <size>0x20</size>
          <fields>
            <field>
              <name>RXDMAEN</name>
              <bitOffset>0</bitOffset>
              <bitWidth>1</bitWidth>
            </field>
            <field>
              <name>TXDMAEN</name>
              <bitOffset>1</bitOffset>
              <bitWidth>1</bitWidth>
            </field>
            <field>
              <name>SSOE</name>
              <bitOffset>2</bitOffset>
              <bitWidth>1</bitWidth>
            </field>
            <field>
              <name>NSSP</name>
              <bitOffset>3</bitOffset>
              <bitWidth>1</bitWidth>
            </field>
            <field>
              <name>FRF</name>
              <bitOffset>4</bitOffset>
              <bitWidth>1</bitWidth>
            </field>
            <field>
              <name>ERRIE</name>
              <bitOffset>5</bitOffset>
              <bitWidth>1</bitWidth>
            </field>
            <field>
              <name>RXNEIE</name>
              <bitOffset>6</bitOffset>
              <bitWidth>1</bitWidth>
            </field>
            <field>
              <name>TXEIE</name>
              <bitOffset>7</bitOffset>
              <bitWidth>1</bitWidth>
            </field>
            <field>
              <name>DS</name>
              <bitOffset>8</bitOffset>
              <bitWidth>4</bitWidth>
            </field>
            <field>
              <name>FRXTH</name>
              <bitOffset>12</bitOffset>
              <bitWidth>1</bitWidth>
            </field>
            <field>
              <name>LDMARX</name>
              <bitOffset>13</bitOffset>
              <bitWidth>1</bitWidth>
            </field>
            <field>
              <name>LDMATX</name>
              <bitOffset>14</bitOffset>
              <bitWidth>1</bitWidth>
            </field>
          </fields>
        </register>
        <register>
          <name>SR</name>
          <addressOffset>0x8</addressOffset>
          <size>0x20</size>
          <fields>
            <field>
              <name>RXNE</name>
              <bitOffset>0</bitOffset>
              <bitWidth>1</bitWidth>
            </field>
            <field>
              <name>TXE</name>
              <bitOffset>1</bitOffset>
              <bitWidth>1</bitWidth>
            </field>
            <field>
              <name>CHSIDE</name>
              <bitOffset>2</bitOffset>
              <bitWidth>1</bitWidth>
            </field>
            <field>
              <name>UDR</name>
              <bitOffset>3</bitOffset>
              <bitWidth>1</bitWidth>
            </field>
            <field>
              <name>CRCERR</name>
              <bitOffset>4</bitOffset>
              <bitWidth>1</bitWidth>
            </field>
            <field>
              <name>MODF</name>
              <bitOffset>5</bitOffset>
              <bitWidth>1</bitWidth>
            </field>
            <field>
              <name>OVR</name>
              <bitOffset>6</bitOffset>
              <bitWidth>1</bitWidth>
            </field>
            <field>
              <name>BSY</name>
              <bitOffset>7</bitOffset>
              <bitWidth>1</bitWidth>
            </field>
            <field>
              <name>FRE</name>
              <bitOffset>8</bitOffset>
              <bitWidth>1</bitWidth>
            </field>
            <field>
              <name>FRLVL</name>
              <bitOffset>9</bitOffset>
              <bitWidth>2</bitWidth>
            </field>
            <field>
              <name>FTLVL</name>
              <bitOffset>11</bitOffset>
              <bitWidth>2</bitWidth>
            </field>
          </fields>
        </register>
        <register>
          <name>DR</name>
          <addressOffset>0xc</addressOffset>
          <size>0x20</size>
          <fields>
            <field>
              <name>DR</name>
              <bitOffset>0</bitOffset>
              <bitWidth>16</bitWidth>
            </field>
          </fields>
        </register>
        <register>
          <name>CRCPR</name>
          <addressOffset>0x10</addressOffset>
          <size>0x20</size>
          <fields>
            <field>
              <name>CRCPOLY</name>
              <bitOffset>0</bitOffset>
              <bitWidth>16</bitWidth>
            </field>
          </fields>
        </register>
        <register>
          <name>RXCRCR</name>
          <addressOffset>0x14</addressOffset>
          <size>0x20</size>
          <fields>
            <field>
              <name>RXCRC</name>
              <bitOffset>0</bitOffset>
              <bitWidth>16</bitWidth>
            </field>
          </fields>
        </register>
        <register>
          <name>TXCRCR</name>
          <addressOffset>0x18</addressOffset>
          <size>0x20</size>
          <fields>
            <field>
              <name>TXCRC</name>
              <bitOffset>0</bitOffset>
              <bitWidth>16</bitWidth>
            </field>
          </fields>
        </register>
        <register>
          <name>I2SCFGR</name>
          <addressOffset>0x1c</addressOffset>
          <size>0x20</size>
          <fields>
            <field>
              <name>CHLEN</name>
              <bitOffset>0</bitOffset>
              <bitWidth>1</bitWidth>
            </field>
            <field>
              <name>DATLEN</name>
              <bitOffset>1</bitOffset>
              <bitWidth>2</bitWidth>
            </field>
            <field>
              <name>CKPOL</name>
              <bitOffset>3</bitOffset>
              <bitWidth>1</bitWidth>
            </field>
            <field>
              <name>I2SSTD</name>
              <bitOffset>4</bitOffset>
              <bitWidth>2</bitWidth>
            </field>
            <field>
              <name>PCMSYNC</name>
              <bitOffset>7</bitOffset>
              <bitWidth>1</bitWidth>
            </field>
            <field>
              <name>I2SCFG</name>
              <bitOffset>8</bitOffset>
              <bitWidth>2</bitWidth>
            </field>
            <field>
              <name>I2SE</name>
              <bitOffset>10</bitOffset>
              <bitWidth>1</bitWidth>
            </field>
            <field>
              <name>I2SMOD</name>
              <bitOffset>11</bitOffset>
              <bitWidth>1</bitWidth>
            </field>
            <field>
              <name>ASTRTEN</name>
              <bitOffset>12</bitOffset>
              <bitWidth>1</bitWidth>
            </field>
          </fields>
        </register>
        <register>
          <name>I2SPR</name>
          <addressOffset>0x20</addressOffset>
          <size>0x20</size>
          <fields>
            <field>
              <name>I2SDIV</name>
              <bitOffset>0</bitOffset>
              <bitWidth>8</bitWidth>
            </field>
            <field>
              <name>ODD</name>
              <bitOffset>8</bitOffset>
              <bitWidth>1</bitWidth>
            </field>
            <field>
              <name>MCKOE</name>
              <bitOffset>9</bitOffset>
              <bitWidth>1</bitWidth>
            </field>
          </fields>
        </register>
      </registers>
    </peripheral>
    <peripheral>
      <name>SAI1</name>
      <baseAddress>0x40015800</baseAddress>
      <registers>
        <register>
          <name>GCR</name>
          <addressOffset>0x0</addressOffset>
          <size>0x20</size>
          <fields>
            <field>
              <name>SYNCIN</name>
              <bitOffset>0</bitOffset>
              <bitWidth>2</bitWidth>
            </field>
            <field>
              <name>SYNCOUT</name>
              <bitOffset>4</bitOffset>
              <bitWidth>2</bitWidth>
            </field>
          </fields>
        </register>
        <register>
          <name>CR1A</name>
          <addressOffset>0x4</addressOffset>
          <size>0x20</size>
          <fields>
            <field>
              <name>MODE</name>
              <bitOffset>0</bitOffset>
              <bitWidth>2</bitWidth>
            </field>
            <field>
              <name>PRTCFG</name>
              <bitOffset>2</bitOffset>
              <bitWidth>2</bitWidth>
            </field>
            <field>
              <name>DS</name>
              <bitOffset>5</bitOffset>
              <bitWidth>3</bitWidth>
            </field>
            <field>
              <name>LSBFIRST</name>
              <bitOffset>8</bitOffset>
              <bitWidth>1</bitWidth>
            </field>
            <field>
              <name>CKSTR</name>
              <bitOffset>9</bitOffset>
              <bitWidth>1</bitWidth>
            </field>
            <field>
              <name>SYNCEN</name>
              <bitOffset>10</bitOffset>
              <bitWidth>2</bitWidth>
            </field>
            <field>
              <name>MONO</name>
              <bitOffset>12</bitOffset>
              <bitWidth>1</bitWidth>
            </field>
            <field>
              <name>OUTDRIV</name>
              <bitOffset>13</bitOffset>
              <bitWidth>1</bitWidth>
            </field>
            <field>
              <name>SAIEN</name>
              <bitOffset>16</bitOffset>
              <bitWidth>1</bitWidth>
            </field>
            <field>
              <name>DMAEN</name>
              <bitOffset>17</bitOffset>
              <bitWidth>1</bitWidth>
            </field>
            <field>
              <name>NODIV</name>
              <bitOffset>19</bitOffset>
              <bitWidth>1</bitWidth>
            </field>
            <field>
              <name>MCKDIV</name>
              <bitOffset>20</bitOffset>
              <bitWidth>4</bitWidth>
            </field>
          </fields>
        </register>
        <register>
          <name>CR1A</name>
          <addressOffset>0x4</addressOffset>
          <size>0x20</size>
          <fields>
            <field>
              <name>MODE</name>
              <bitOffset>0</bitOffset>
              <bitWidth>2</bitWidth>
            </field>
            <field>
              <name>PRTCFG</name>
              <bitOffset>2</bitOffset>
              <bitWidth>2</bitWidth>
            </field>
            <field>
              <name>DS</name>
              <bitOffset>5</bitOffset>
              <bitWidth>3</bitWidth>
            </field>
            <field>
              <name>LSBFIRST</name>
              <bitOffset>8</bitOffset>
              <bitWidth>1</bitWidth>
            </field>
            <field>
              <name>CKSTR</name>
              <bitOffset>9</bitOffset>
              <bitWidth>1</bitWidth>
            </field>
            <field>
              <name>SYNCEN</name>
              <bitOffset>10</bitOffset>
              <bitWidth>2</bitWidth>
            </field>
            <field>
              <name>MONO</name>
              <bitOffset>12</bitOffset>
              <bitWidth>1</bitWidth>
            </field>
            <field>
              <name>OUTDRIV</name>
              <bitOffset>13</bitOffset>
              <bitWidth>1</bitWidth>
            </field>
            <field>
              <name>SAIEN</name>
              <bitOffset>16</bitOffset>
              <bitWidth>1</bitWidth>
            </field>
            <field>
              <name>DMAEN</name>
              <bitOffset>17</bitOffset>
              <bitWidth>1</bitWidth>
            </field>
            <field>
              <name>NODIV</name>
              <bitOffset>19</bitOffset>
              <bitWidth>1</bitWidth>
            </field>
            <field>
              <name>MCKDIV</name>
              <bitOffset>20</bitOffset>
              <bitWidth>4</bitWidth>
            </field>
          </fields>
        </register>
        <register>
          <name>CR2A</name>
          <addressOffset>0x8</addressOffset>
          <size>0x20</size>
          <fields>
            <field>
              <name>FTH</name>
              <bitOffset>0</bitOffset>
              <bitWidth>3</bitWidth>
            </field>
            <field>
              <name>FFLUSH</name>
              <bitOffset>3</bitOffset>
              <bitWidth>1</bitWidth>
            </field>
            <field>
              <name>TRIS</name>
              <bitOffset>4</bitOffset>
              <bitWidth>1</bitWidth>
            </field>
            <field>
              <name>MUTE</name>
              <bitOffset>5</bitOffset>
              <bitWidth>1</bitWidth>
            </field>
            <field>
              <name>MUTEVAL</name>
              <bitOffset>6</bitOffset>
              <bitWidth>1</bitWidth>
            </field>
            <field>
              <name>MUTECNT</name>
              <bitOffset>7</bitOffset>
              <bitWidth>6</bitWidth>
            </field>
            <field>
              <name>CPL</name>
              <bitOffset>13</bitOffset>
              <bitWidth>1</bitWidth>
            </field>
            <field>
              <name>COMP</name>
              <bitOffset>14</bitOffset>
              <bitWidth>2</bitWidth>
            </field>
          </fields>
        </register>
        <register>
          <name>CR2A</name>
          <addressOffset>0x8</addressOffset>
          <size>0x20</size>
          <fields>
            <field>
              <name>FTH</name>
              <bitOffset>0</bitOffset>
              <bitWidth>3</bitWidth>
            </field>
            <field>
              <name>FFLUSH</name>
              <bitOffset>3</bitOffset>
              <bitWidth>1</bitWidth>
            </field>
            <field>
              <name>TRIS</name>
              <bitOffset>4</bitOffset>
              <bitWidth>1</bitWidth>
            </field>
            <field>
              <name>MUTE</name>
              <bitOffset>5</bitOffset>
              <bitWidth>1</bitWidth>
            </field>
            <field>
              <name>MUTEVAL</name>
              <bitOffset>6</bitOffset>
              <bitWidth>1</bitWidth>
            </field>
            <field>
              <name>MUTECNT</name>
              <bitOffset>7</bitOffset>
              <bitWidth>6</bitWidth>
            </field>
            <field>
              <name>CPL</name>
              <bitOffset>13</bitOffset>
              <bitWidth>1</bitWidth>
            </field>
            <field>
              <name>COMP</name>
              <bitOffset>14</bitOffset>
              <bitWidth>2</bitWidth>
            </field>
          </fields>
        </register>
        <register>
          <name>FRCRA</name>
          <addressOffset>0xc</addressOffset>
          <size>0x20</size>
          <fields>
            <field>
              <name>FRL</name>
              <bitOffset>0</bitOffset>
              <bitWidth>8</bitWidth>
            </field>
            <field>
              <name>FSALL</name>
              <bitOffset>8</bitOffset>
              <bitWidth>7</bitWidth>
            </field>
            <field>
              <name>FSDEF</name>
              <bitOffset>16</bitOffset>
              <bitWidth>1</bitWidth>
            </field>
            <field>
              <name>FSPOL</name>
              <bitOffset>17</bitOffset>
              <bitWidth>1</bitWidth>
            </field>
            <field>
              <name>FSOFF</name>
              <bitOffset>18</bitOffset>
              <bitWidth>1</bitWidth>
            </field>
          </fields>
        </register>
        <register>
          <name>FRCRA</name>
          <addressOffset>0xc</addressOffset>
          <size>0x20</size>
          <fields>
            <field>
              <name>FRL</name>
              <bitOffset>0</bitOffset>
              <bitWidth>8</bitWidth>
            </field>
            <field>
              <name>FSALL</name>
              <bitOffset>8</bitOffset>
              <bitWidth>7</bitWidth>
            </field>
            <field>
              <name>FSDEF</name>
              <bitOffset>16</bitOffset>
              <bitWidth>1</bitWidth>
            </field>
            <field>
              <name>FSPOL</name>
              <bitOffset>17</bitOffset>
              <bitWidth>1</bitWidth>
            </field>
            <field>
              <name>FSOFF</name>
              <bitOffset>18</bitOffset>
              <bitWidth>1</bitWidth>
            </field>
          </fields>
        </register>
        <register>
          <name>SLOTRA</name>
          <addressOffset>0x10</addressOffset>
          <size>0x20</size>
          <fields>
            <field>
              <name>FBOFF</name>
              <bitOffset>0</bitOffset>
              <bitWidth>5</bitWidth>
            </field>
            <field>
              <name>SLOTSZ</name>
              <bitOffset>6</bitOffset>
              <bitWidth>2</bitWidth>
            </field>
            <field>
              <name>NBSLOT</name>
              <bitOffset>8</bitOffset>
              <bitWidth>4</bitWidth>
            </field>
            <field>
              <name>SLOTEN</name>
              <bitOffset>16</bitOffset>
              <bitWidth>16</bitWidth>
            </field>
          </fields>
        </register>
        <register>
          <name>SLOTRA</name>
          <addressOffset>0x10</addressOffset>
          <size>0x20</size>
          <fields>
            <field>
              <name>FBOFF</name>
              <bitOffset>0</bitOffset>
              <bitWidth>5</bitWidth>
            </field>
            <field>
              <name>SLOTSZ</name>
              <bitOffset>6</bitOffset>
              <bitWidth>2</bitWidth>
            </field>
            <field>
              <name>NBSLOT</name>
              <bitOffset>8</bitOffset>
              <bitWidth>4</bitWidth>
            </field>
            <field>
              <name>SLOTEN</name>
              <bitOffset>16</bitOffset>
              <bitWidth>16</bitWidth>
            </field>
          </fields>
        </register>
        <register>
          <name>IMRA</name>
          <addressOffset>0x14</addressOffset>
          <size>0x20</size>
          <fields>
            <field>
              <name>OVRUDRIE</name>
              <bitOffset>0</bitOffset>
              <bitWidth>1</bitWidth>
            </field>
            <field>
              <name>MUTEDETIE</name>
              <bitOffset>1</bitOffset>
              <bitWidth>1</bitWidth>
            </field>
            <field>
              <name>WCKCFGIE</name>
              <bitOffset>2</bitOffset>
              <bitWidth>1</bitWidth>
            </field>
            <field>
              <name>FREQIE</name>
              <bitOffset>3</bitOffset>
              <bitWidth>1</bitWidth>
            </field>
            <field>
              <name>CNRDYIE</name>
              <bitOffset>4</bitOffset>
              <bitWidth>1</bitWidth>
            </field>
            <field>
              <name>AFSDETIE</name>
              <bitOffset>5</bitOffset>
              <bitWidth>1</bitWidth>
            </field>
            <field>
              <name>LFSDETIE</name>
              <bitOffset>6</bitOffset>
              <bitWidth>1</bitWidth>
            </field>
          </fields>
        </register>
        <register>
          <name>IMRA</name>
          <addressOffset>0x14</addressOffset>
          <size>0x20</size>
          <fields>
            <field>
              <name>OVRUDRIE</name>
              <bitOffset>0</bitOffset>
              <bitWidth>1</bitWidth>
            </field>
            <field>
              <name>MUTEDETIE</name>
              <bitOffset>1</bitOffset>
              <bitWidth>1</bitWidth>
            </field>
            <field>
              <name>WCKCFGIE</name>
              <bitOffset>2</bitOffset>
              <bitWidth>1</bitWidth>
            </field>
            <field>
              <name>FREQIE</name>
              <bitOffset>3</bitOffset>
              <bitWidth>1</bitWidth>
            </field>
            <field>
              <name>CNRDYIE</name>
              <bitOffset>4</bitOffset>
              <bitWidth>1</bitWidth>
            </field>
            <field>
              <name>AFSDETIE</name>
              <bitOffset>5</bitOffset>
              <bitWidth>1</bitWidth>
            </field>
            <field>
              <name>LFSDETIE</name>
              <bitOffset>6</bitOffset>
              <bitWidth>1</bitWidth>
            </field>
          </fields>
        </register>
        <register>
          <name>SRA</name>
          <addressOffset>0x18</addressOffset>
          <size>0x20</size>
          <fields>
            <field>
              <name>OVRUDR</name>
              <bitOffset>0</bitOffset>
              <bitWidth>1</bitWidth>
            </field>
            <field>
              <name>MUTEDET</name>
              <bitOffset>1</bitOffset>
              <bitWidth>1</bitWidth>
            </field>
            <field>
              <name>WCKCFG</name>
              <bitOffset>2</bitOffset>
              <bitWidth>1</bitWidth>
            </field>
            <field>
              <name>FREQ</name>
              <bitOffset>3</bitOffset>
              <bitWidth>1</bitWidth>
            </field>
            <field>
              <name>CNRDY</name>
              <bitOffset>4</bitOffset>
              <bitWidth>1</bitWidth>
            </field>
            <field>
              <name>AFSDET</name>
              <bitOffset>5</bitOffset>
              <bitWidth>1</bitWidth>
            </field>
            <field>
              <name>LFSDET</name>
              <bitOffset>6</bitOffset>
              <bitWidth>1</bitWidth>
            </field>
            <field>
              <name>FLVL</name>
              <bitOffset>16</bitOffset>
              <bitWidth>3</bitWidth>
            </field>
          </fields>
        </register>
        <register>
          <name>SRA</name>
          <addressOffset>0x18</addressOffset>
          <size>0x20</size>
          <fields>
            <field>
              <name>OVRUDR</name>
              <bitOffset>0</bitOffset>
              <bitWidth>1</bitWidth>
            </field>
            <field>
              <name>MUTEDET</name>
              <bitOffset>1</bitOffset>
              <bitWidth>1</bitWidth>
            </field>
            <field>
              <name>WCKCFG</name>
              <bitOffset>2</bitOffset>
              <bitWidth>1</bitWidth>
            </field>
            <field>
              <name>FREQ</name>
              <bitOffset>3</bitOffset>
              <bitWidth>1</bitWidth>
            </field>
            <field>
              <name>CNRDY</name>
              <bitOffset>4</bitOffset>
              <bitWidth>1</bitWidth>
            </field>
            <field>
              <name>AFSDET</name>
              <bitOffset>5</bitOffset>
              <bitWidth>1</bitWidth>
            </field>
            <field>
              <name>LFSDET</name>
              <bitOffset>6</bitOffset>
              <bitWidth>1</bitWidth>
            </field>
            <field>
              <name>FLVL</name>
              <bitOffset>16</bitOffset>
              <bitWidth>3</bitWidth>
            </field>
          </fields>
        </register>
        <register>
          <name>CLRFRA</name>
          <addressOffset>0x1c</addressOffset>
          <size>0x20</size>
          <fields>
            <field>
              <name>COVRUDR</name>
              <bitOffset>0</bitOffset>
              <bitWidth>1</bitWidth>
            </field>
            <field>
              <name>CMUTEDET</name>
              <bitOffset>1</bitOffset>
              <bitWidth>1</bitWidth>
            </field>
            <field>
              <name>CWCKCFG</name>
              <bitOffset>2</bitOffset>
              <bitWidth>1</bitWidth>
            </field>
            <field>
              <name>CFREQ</name>
              <bitOffset>3</bitOffset>
              <bitWidth>1</bitWidth>
            </field>
            <field>
              <name>CCNRDY</name>
              <bitOffset>4</bitOffset>
              <bitWidth>1</bitWidth>
            </field>
            <field>
              <name>CAFSDET</name>
              <bitOffset>5</bitOffset>
              <bitWidth>1</bitWidth>
            </field>
            <field>
              <name>CLFSDET</name>
              <bitOffset>6</bitOffset>
              <bitWidth>1</bitWidth>
            </field>
          </fields>
        </register>
        <register>
          <name>CLRFRA</name>
          <addressOffset>0x1c</addressOffset>
          <size>0x20</size>
          <fields>
            <field>
              <name>COVRUDR</name>
              <bitOffset>0</bitOffset>
              <bitWidth>1</bitWidth>
            </field>
            <field>
              <name>CMUTEDET</name>
              <bitOffset>1</bitOffset>
              <bitWidth>1</bitWidth>
            </field>
            <field>
              <name>CWCKCFG</name>
              <bitOffset>2</bitOffset>
              <bitWidth>1</bitWidth>
            </field>
            <field>
              <name>CFREQ</name>
              <bitOffset>3</bitOffset>
              <bitWidth>1</bitWidth>
            </field>
            <field>
              <name>CCNRDY</name>
              <bitOffset>4</bitOffset>
              <bitWidth>1</bitWidth>
            </field>
            <field>
              <name>CAFSDET</name>
              <bitOffset>5</bitOffset>
              <bitWidth>1</bitWidth>
            </field>
            <field>
              <name>CLFSDET</name>
              <bitOffset>6</bitOffset>
              <bitWidth>1</bitWidth>
            </field>
          </fields>
        </register>
        <register>
          <name>DRA</name>
          <addressOffset>0x20</addressOffset>
          <size>0x20</size>
          <fields>
            <field>
              <name>DATA</name>
              <bitOffset>0</bitOffset>
              <bitWidth>32</bitWidth>
            </field>
          </fields>
        </register>
        <register>
          <name>DRA</name>
          <addressOffset>0x20</addressOffset>
          <size>0x20</size>
          <fields>
            <field>
              <name>DATA</name>
              <bitOffset>0</bitOffset>
              <bitWidth>32</bitWidth>
            </field>
          </fields>
        </register>
        <register>
          <name>CR1B</name>
          <addressOffset>0x24</addressOffset>
          <size>0x20</size>
          <fields>
            <field>
              <name>MODE</name>
              <bitOffset>0</bitOffset>
              <bitWidth>2</bitWidth>
            </field>
            <field>
              <name>PRTCFG</name>
              <bitOffset>2</bitOffset>
              <bitWidth>2</bitWidth>
            </field>
            <field>
              <name>DS</name>
              <bitOffset>5</bitOffset>
              <bitWidth>3</bitWidth>
            </field>
            <field>
              <name>LSBFIRST</name>
              <bitOffset>8</bitOffset>
              <bitWidth>1</bitWidth>
            </field>
            <field>
              <name>CKSTR</name>
              <bitOffset>9</bitOffset>
              <bitWidth>1</bitWidth>
            </field>
            <field>
              <name>SYNCEN</name>
              <bitOffset>10</bitOffset>
              <bitWidth>2</bitWidth>
            </field>
            <field>
              <name>MONO</name>
              <bitOffset>12</bitOffset>
              <bitWidth>1</bitWidth>
            </field>
            <field>
              <name>OUTDRIV</name>
              <bitOffset>13</bitOffset>
              <bitWidth>1</bitWidth>
            </field>
            <field>
              <name>SAIEN</name>
              <bitOffset>16</bitOffset>
              <bitWidth>1</bitWidth>
            </field>
            <field>
              <name>DMAEN</name>
              <bitOffset>17</bitOffset>
              <bitWidth>1</bitWidth>
            </field>
            <field>
              <name>NODIV</name>
              <bitOffset>19</bitOffset>
              <bitWidth>1</bitWidth>
            </field>
            <field>
              <name>MCKDIV</name>
              <bitOffset>20</bitOffset>
              <bitWidth>4</bitWidth>
            </field>
          </fields>
        </register>
        <register>
          <name>CR1B</name>
          <addressOffset>0x24</addressOffset>
          <size>0x20</size>
          <fields>
            <field>
              <name>MODE</name>
              <bitOffset>0</bitOffset>
              <bitWidth>2</bitWidth>
            </field>
            <field>
              <name>PRTCFG</name>
              <bitOffset>2</bitOffset>
              <bitWidth>2</bitWidth>
            </field>
            <field>
              <name>DS</name>
              <bitOffset>5</bitOffset>
              <bitWidth>3</bitWidth>
            </field>
            <field>
              <name>LSBFIRST</name>
              <bitOffset>8</bitOffset>
              <bitWidth>1</bitWidth>
            </field>
            <field>
              <name>CKSTR</name>
              <bitOffset>9</bitOffset>
              <bitWidth>1</bitWidth>
            </field>
            <field>
              <name>SYNCEN</name>
              <bitOffset>10</bitOffset>
              <bitWidth>2</bitWidth>
            </field>
            <field>
              <name>MONO</name>
              <bitOffset>12</bitOffset>
              <bitWidth>1</bitWidth>
            </field>
            <field>
              <name>OUTDRIV</name>
              <bitOffset>13</bitOffset>
              <bitWidth>1</bitWidth>
            </field>
            <field>
              <name>SAIEN</name>
              <bitOffset>16</bitOffset>
              <bitWidth>1</bitWidth>
            </field>
            <field>
              <name>DMAEN</name>
              <bitOffset>17</bitOffset>
              <bitWidth>1</bitWidth>
            </field>
            <field>
              <name>NODIV</name>
              <bitOffset>19</bitOffset>
              <bitWidth>1</bitWidth>
            </field>
            <field>
              <name>MCKDIV</name>
              <bitOffset>20</bitOffset>
              <bitWidth>4</bitWidth>
            </field>
          </fields>
        </register>
        <register>
          <name>CR2B</name>
          <addressOffset>0x28</addressOffset>
          <size>0x20</size>
          <fields>
            <field>
              <name>FTH</name>
              <bitOffset>0</bitOffset>
              <bitWidth>3</bitWidth>
            </field>
            <field>
              <name>FFLUSH</name>
              <bitOffset>3</bitOffset>
              <bitWidth>1</bitWidth>
            </field>
            <field>
              <name>TRIS</name>
              <bitOffset>4</bitOffset>
              <bitWidth>1</bitWidth>
            </field>
            <field>
              <name>MUTE</name>
              <bitOffset>5</bitOffset>
              <bitWidth>1</bitWidth>
            </field>
            <field>
              <name>MUTEVAL</name>
              <bitOffset>6</bitOffset>
              <bitWidth>1</bitWidth>
            </field>
            <field>
              <name>MUTECNT</name>
              <bitOffset>7</bitOffset>
              <bitWidth>6</bitWidth>
            </field>
            <field>
              <name>CPL</name>
              <bitOffset>13</bitOffset>
              <bitWidth>1</bitWidth>
            </field>
            <field>
              <name>COMP</name>
              <bitOffset>14</bitOffset>
              <bitWidth>2</bitWidth>
            </field>
          </fields>
        </register>
        <register>
          <name>CR2B</name>
          <addressOffset>0x28</addressOffset>
          <size>0x20</size>
          <fields>
            <field>
              <name>FTH</name>
              <bitOffset>0</bitOffset>
              <bitWidth>3</bitWidth>
            </field>
            <field>
              <name>FFLUSH</name>
              <bitOffset>3</bitOffset>
              <bitWidth>1</bitWidth>
            </field>
            <field>
              <name>TRIS</name>
              <bitOffset>4</bitOffset>
              <bitWidth>1</bitWidth>
            </field>
            <field>
              <name>MUTE</name>
              <bitOffset>5</bitOffset>
              <bitWidth>1</bitWidth>
            </field>
            <field>
              <name>MUTEVAL</name>
              <bitOffset>6</bitOffset>
              <bitWidth>1</bitWidth>
            </field>
            <field>
              <name>MUTECNT</name>
              <bitOffset>7</bitOffset>
              <bitWidth>6</bitWidth>
            </field>
            <field>
              <name>CPL</name>
              <bitOffset>13</bitOffset>
              <bitWidth>1</bitWidth>
            </field>
            <field>
              <name>COMP</name>
              <bitOffset>14</bitOffset>
              <bitWidth>2</bitWidth>
            </field>
          </fields>
        </register>
        <register>
          <name>FRCRB</name>
          <addressOffset>0x2c</addressOffset>
          <size>0x20</size>
          <fields>
            <field>
              <name>FRL</name>
              <bitOffset>0</bitOffset>
              <bitWidth>8</bitWidth>
            </field>
            <field>
              <name>FSALL</name>
              <bitOffset>8</bitOffset>
              <bitWidth>7</bitWidth>
            </field>
            <field>
              <name>FSDEF</name>
              <bitOffset>16</bitOffset>
              <bitWidth>1</bitWidth>
            </field>
            <field>
              <name>FSPOL</name>
              <bitOffset>17</bitOffset>
              <bitWidth>1</bitWidth>
            </field>
            <field>
              <name>FSOFF</name>
              <bitOffset>18</bitOffset>
              <bitWidth>1</bitWidth>
            </field>
          </fields>
        </register>
        <register>
          <name>FRCRB</name>
          <addressOffset>0x2c</addressOffset>
          <size>0x20</size>
          <fields>
            <field>
              <name>FRL</name>
              <bitOffset>0</bitOffset>
              <bitWidth>8</bitWidth>
            </field>
            <field>
              <name>FSALL</name>
              <bitOffset>8</bitOffset>
              <bitWidth>7</bitWidth>
            </field>
            <field>
              <name>FSDEF</name>
              <bitOffset>16</bitOffset>
              <bitWidth>1</bitWidth>
            </field>
            <field>
              <name>FSPOL</name>
              <bitOffset>17</bitOffset>
              <bitWidth>1</bitWidth>
            </field>
            <field>
              <name>FSOFF</name>
              <bitOffset>18</bitOffset>
              <bitWidth>1</bitWidth>
            </field>
          </fields>
        </register>
        <register>
          <name>SLOTRB</name>
          <addressOffset>0x30</addressOffset>
          <size>0x20</size>
          <fields>
            <field>
              <name>FBOFF</name>
              <bitOffset>0</bitOffset>
              <bitWidth>5</bitWidth>
            </field>
            <field>
              <name>SLOTSZ</name>
              <bitOffset>6</bitOffset>
              <bitWidth>2</bitWidth>
            </field>
            <field>
              <name>NBSLOT</name>
              <bitOffset>8</bitOffset>
              <bitWidth>4</bitWidth>
            </field>
            <field>
              <name>SLOTEN</name>
              <bitOffset>16</bitOffset>
              <bitWidth>16</bitWidth>
            </field>
          </fields>
        </register>
        <register>
          <name>SLOTRB</name>
          <addressOffset>0x30</addressOffset>
          <size>0x20</size>
          <fields>
            <field>
              <name>FBOFF</name>
              <bitOffset>0</bitOffset>
              <bitWidth>5</bitWidth>
            </field>
            <field>
              <name>SLOTSZ</name>
              <bitOffset>6</bitOffset>
              <bitWidth>2</bitWidth>
            </field>
            <field>
              <name>NBSLOT</name>
              <bitOffset>8</bitOffset>
              <bitWidth>4</bitWidth>
            </field>
            <field>
              <name>SLOTEN</name>
              <bitOffset>16</bitOffset>
              <bitWidth>16</bitWidth>
            </field>
          </fields>
        </register>
        <register>
          <name>IMRB</name>
          <addressOffset>0x34</addressOffset>
          <size>0x20</size>
          <fields>
            <field>
              <name>OVRUDRIE</name>
              <bitOffset>0</bitOffset>
              <bitWidth>1</bitWidth>
            </field>
            <field>
              <name>MUTEDETIE</name>
              <bitOffset>1</bitOffset>
              <bitWidth>1</bitWidth>
            </field>
            <field>
              <name>WCKCFGIE</name>
              <bitOffset>2</bitOffset>
              <bitWidth>1</bitWidth>
            </field>
            <field>
              <name>FREQIE</name>
              <bitOffset>3</bitOffset>
              <bitWidth>1</bitWidth>
            </field>
            <field>
              <name>CNRDYIE</name>
              <bitOffset>4</bitOffset>
              <bitWidth>1</bitWidth>
            </field>
            <field>
              <name>AFSDETIE</name>
              <bitOffset>5</bitOffset>
              <bitWidth>1</bitWidth>
            </field>
            <field>
              <name>LFSDETIE</name>
              <bitOffset>6</bitOffset>
              <bitWidth>1</bitWidth>
            </field>
          </fields>
        </register>
        <register>
          <name>IMRB</name>
          <addressOffset>0x34</addressOffset>
          <size>0x20</size>
          <fields>
            <field>
              <name>OVRUDRIE</name>
              <bitOffset>0</bitOffset>
              <bitWidth>1</bitWidth>
            </field>
            <field>
              <name>MUTEDETIE</name>
              <bitOffset>1</bitOffset>
              <bitWidth>1</bitWidth>
            </field>
            <field>
              <name>WCKCFGIE</name>
              <bitOffset>2</bitOffset>
              <bitWidth>1</bitWidth>
            </field>
            <field>
              <name>FREQIE</name>
              <bitOffset>3</bitOffset>
              <bitWidth>1</bitWidth>
            </field>
            <field>
              <name>CNRDYIE</name>
              <bitOffset>4</bitOffset>
              <bitWidth>1</bitWidth>
            </field>
            <field>
              <name>AFSDETIE</name>
              <bitOffset>5</bitOffset>
              <bitWidth>1</bitWidth>
            </field>
            <field>
              <name>LFSDETIE</name>
              <bitOffset>6</bitOffset>
              <bitWidth>1</bitWidth>
            </field>
          </fields>
        </register>
        <register>
          <name>SRB</name>
          <addressOffset>0x38</addressOffset>
          <size>0x20</size>
          <fields>
            <field>
              <name>OVRUDR</name>
              <bitOffset>0</bitOffset>
              <bitWidth>1</bitWidth>
            </field>
            <field>
              <name>MUTEDET</name>
              <bitOffset>1</bitOffset>
              <bitWidth>1</bitWidth>
            </field>
            <field>
              <name>WCKCFG</name>
              <bitOffset>2</bitOffset>
              <bitWidth>1</bitWidth>
            </field>
            <field>
              <name>FREQ</name>
              <bitOffset>3</bitOffset>
              <bitWidth>1</bitWidth>
            </field>
            <field>
              <name>CNRDY</name>
              <bitOffset>4</bitOffset>
              <bitWidth>1</bitWidth>
            </field>
            <field>
              <name>AFSDET</name>
              <bitOffset>5</bitOffset>
              <bitWidth>1</bitWidth>
            </field>
            <field>
              <name>LFSDET</name>
              <bitOffset>6</bitOffset>
              <bitWidth>1</bitWidth>
            </field>
            <field>
              <name>FLVL</name>
              <bitOffset>16</bitOffset>
              <bitWidth>3</bitWidth>
            </field>
          </fields>
        </register>
        <register>
          <name>SRB</name>
          <addressOffset>0x38</addressOffset>
          <size>0x20</size>
          <fields>
            <field>
              <name>OVRUDR</name>
              <bitOffset>0</bitOffset>
              <bitWidth>1</bitWidth>
            </field>
            <field>
              <name>MUTEDET</name>
              <bitOffset>1</bitOffset>
              <bitWidth>1</bitWidth>
            </field>
            <field>
              <name>WCKCFG</name>
              <bitOffset>2</bitOffset>
              <bitWidth>1</bitWidth>
            </field>
            <field>
              <name>FREQ</name>
              <bitOffset>3</bitOffset>
              <bitWidth>1</bitWidth>
            </field>
            <field>
              <name>CNRDY</name>
              <bitOffset>4</bitOffset>
              <bitWidth>1</bitWidth>
            </field>
            <field>
              <name>AFSDET</name>
              <bitOffset>5</bitOffset>
              <bitWidth>1</bitWidth>
            </field>
            <field>
              <name>LFSDET</name>
              <bitOffset>6</bitOffset>
              <bitWidth>1</bitWidth>
            </field>
            <field>
              <name>FLVL</name>
              <bitOffset>16</bitOffset>
              <bitWidth>3</bitWidth>
            </field>
          </fields>
        </register>
        <register>
          <name>CLRFRB</name>
          <addressOffset>0x3c</addressOffset>
          <size>0x20</size>
          <fields>
            <field>
              <name>COVRUDR</name>
              <bitOffset>0</bitOffset>
              <bitWidth>1</bitWidth>
            </field>
            <field>
              <name>CMUTEDET</name>
              <bitOffset>1</bitOffset>
              <bitWidth>1</bitWidth>
            </field>
            <field>
              <name>CWCKCFG</name>
              <bitOffset>2</bitOffset>
              <bitWidth>1</bitWidth>
            </field>
            <field>
              <name>CFREQ</name>
              <bitOffset>3</bitOffset>
              <bitWidth>1</bitWidth>
            </field>
            <field>
              <name>CCNRDY</name>
              <bitOffset>4</bitOffset>
              <bitWidth>1</bitWidth>
            </field>
            <field>
              <name>CAFSDET</name>
              <bitOffset>5</bitOffset>
              <bitWidth>1</bitWidth>
            </field>
            <field>
              <name>CLFSDET</name>
              <bitOffset>6</bitOffset>
              <bitWidth>1</bitWidth>
            </field>
          </fields>
        </register>
        <register>
          <name>CLRFRB</name>
          <addressOffset>0x3c</addressOffset>
          <size>0x20</size>
          <fields>
            <field>
              <name>COVRUDR</name>
              <bitOffset>0</bitOffset>
              <bitWidth>1</bitWidth>
            </field>
            <field>
              <name>CMUTEDET</name>
              <bitOffset>1</bitOffset>
              <bitWidth>1</bitWidth>
            </field>
            <field>
              <name>CWCKCFG</name>
              <bitOffset>2</bitOffset>
              <bitWidth>1</bitWidth>
            </field>
            <field>
              <name>CFREQ</name>
              <bitOffset>3</bitOffset>
              <bitWidth>1</bitWidth>
            </field>
            <field>
              <name>CCNRDY</name>
              <bitOffset>4</bitOffset>
              <bitWidth>1</bitWidth>
            </field>
            <field>
              <name>CAFSDET</name>
              <bitOffset>5</bitOffset>
              <bitWidth>1</bitWidth>
            </field>
            <field>
              <name>CLFSDET</name>
              <bitOffset>6</bitOffset>
              <bitWidth>1</bitWidth>
            </field>
          </fields>
        </register>
        <register>
          <name>DRB</name>
          <addressOffset>0x40</addressOffset>
          <size>0x20</size>
          <fields>
            <field>
              <name>DATA</name>
              <bitOffset>0</bitOffset>
              <bitWidth>32</bitWidth>
            </field>
          </fields>
        </register>
        <register>
          <name>DRB</name>
          <addressOffset>0x40</addressOffset>
          <size>0x20</size>
          <fields>
            <field>
              <name>DATA</name>
              <bitOffset>0</bitOffset>
              <bitWidth>32</bitWidth>
            </field>
          </fields>
        </register>
      </registers>
    </peripheral>
    <peripheral>
      <name>SAI2</name>
      <baseAddress>0x40015c00</baseAddress>
      <registers>
        <register>
          <name>GCR</name>
          <addressOffset>0x0</addressOffset>
          <size>0x20</size>
          <fields>
            <field>
              <name>SYNCIN</name>
              <bitOffset>0</bitOffset>
              <bitWidth>2</bitWidth>
            </field>
            <field>
              <name>SYNCOUT</name>
              <bitOffset>4</bitOffset>
              <bitWidth>2</bitWidth>
            </field>
          </fields>
        </register>
        <register>
          <name>CR1A</name>
          <addressOffset>0x4</addressOffset>
          <size>0x20</size>
          <fields>
            <field>
              <name>MODE</name>
              <bitOffset>0</bitOffset>
              <bitWidth>2</bitWidth>
            </field>
            <field>
              <name>PRTCFG</name>
              <bitOffset>2</bitOffset>
              <bitWidth>2</bitWidth>
            </field>
            <field>
              <name>DS</name>
              <bitOffset>5</bitOffset>
              <bitWidth>3</bitWidth>
            </field>
            <field>
              <name>LSBFIRST</name>
              <bitOffset>8</bitOffset>
              <bitWidth>1</bitWidth>
            </field>
            <field>
              <name>CKSTR</name>
              <bitOffset>9</bitOffset>
              <bitWidth>1</bitWidth>
            </field>
            <field>
              <name>SYNCEN</name>
              <bitOffset>10</bitOffset>
              <bitWidth>2</bitWidth>
            </field>
            <field>
              <name>MONO</name>
              <bitOffset>12</bitOffset>
              <bitWidth>1</bitWidth>
            </field>
            <field>
              <name>OUTDRIV</name>
              <bitOffset>13</bitOffset>
              <bitWidth>1</bitWidth>
            </field>
            <field>
              <name>SAIEN</name>
              <bitOffset>16</bitOffset>
              <bitWidth>1</bitWidth>
            </field>
            <field>
              <name>DMAEN</name>
              <bitOffset>17</bitOffset>
              <bitWidth>1</bitWidth>
            </field>
            <field>
              <name>NODIV</name>
              <bitOffset>19</bitOffset>
              <bitWidth>1</bitWidth>
            </field>
            <field>
              <name>MCKDIV</name>
              <bitOffset>20</bitOffset>
              <bitWidth>4</bitWidth>
            </field>
          </fields>
        </register>
        <register>
          <name>CR1A</name>
          <addressOffset>0x4</addressOffset>
          <size>0x20</size>
          <fields>
            <field>
              <name>MODE</name>
              <bitOffset>0</bitOffset>
              <bitWidth>2</bitWidth>
            </field>
            <field>
              <name>PRTCFG</name>
              <bitOffset>2</bitOffset>
              <bitWidth>2</bitWidth>
            </field>
            <field>
              <name>DS</name>
              <bitOffset>5</bitOffset>
              <bitWidth>3</bitWidth>
            </field>
            <field>
              <name>LSBFIRST</name>
              <bitOffset>8</bitOffset>
              <bitWidth>1</bitWidth>
            </field>
            <field>
              <name>CKSTR</name>
              <bitOffset>9</bitOffset>
              <bitWidth>1</bitWidth>
            </field>
            <field>
              <name>SYNCEN</name>
              <bitOffset>10</bitOffset>
              <bitWidth>2</bitWidth>
            </field>
            <field>
              <name>MONO</name>
              <bitOffset>12</bitOffset>
              <bitWidth>1</bitWidth>
            </field>
            <field>
              <name>OUTDRIV</name>
              <bitOffset>13</bitOffset>
              <bitWidth>1</bitWidth>
            </field>
            <field>
              <name>SAIEN</name>
              <bitOffset>16</bitOffset>
              <bitWidth>1</bitWidth>
            </field>
            <field>
              <name>DMAEN</name>
              <bitOffset>17</bitOffset>
              <bitWidth>1</bitWidth>
            </field>
            <field>
              <name>NODIV</name>
              <bitOffset>19</bitOffset>
              <bitWidth>1</bitWidth>
            </field>
            <field>
              <name>MCKDIV</name>
              <bitOffset>20</bitOffset>
              <bitWidth>4</bitWidth>
            </field>
          </fields>
        </register>
        <register>
          <name>CR2A</name>
          <addressOffset>0x8</addressOffset>
          <size>0x20</size>
          <fields>
            <field>
              <name>FTH</name>
              <bitOffset>0</bitOffset>
              <bitWidth>3</bitWidth>
            </field>
            <field>
              <name>FFLUSH</name>
              <bitOffset>3</bitOffset>
              <bitWidth>1</bitWidth>
            </field>
            <field>
              <name>TRIS</name>
              <bitOffset>4</bitOffset>
              <bitWidth>1</bitWidth>
            </field>
            <field>
              <name>MUTE</name>
              <bitOffset>5</bitOffset>
              <bitWidth>1</bitWidth>
            </field>
            <field>
              <name>MUTEVAL</name>
              <bitOffset>6</bitOffset>
              <bitWidth>1</bitWidth>
            </field>
            <field>
              <name>MUTECNT</name>
              <bitOffset>7</bitOffset>
              <bitWidth>6</bitWidth>
            </field>
            <field>
              <name>CPL</name>
              <bitOffset>13</bitOffset>
              <bitWidth>1</bitWidth>
            </field>
            <field>
              <name>COMP</name>
              <bitOffset>14</bitOffset>
              <bitWidth>2</bitWidth>
            </field>
          </fields>
        </register>
        <register>
          <name>CR2A</name>
          <addressOffset>0x8</addressOffset>
          <size>0x20</size>
          <fields>
            <field>
              <name>FTH</name>
              <bitOffset>0</bitOffset>
              <bitWidth>3</bitWidth>
            </field>
            <field>
              <name>FFLUSH</name>
              <bitOffset>3</bitOffset>
              <bitWidth>1</bitWidth>
            </field>
            <field>
              <name>TRIS</name>
              <bitOffset>4</bitOffset>
              <bitWidth>1</bitWidth>
            </field>
            <field>
              <name>MUTE</name>
              <bitOffset>5</bitOffset>
              <bitWidth>1</bitWidth>
            </field>
            <field>
              <name>MUTEVAL</name>
              <bitOffset>6</bitOffset>
              <bitWidth>1</bitWidth>
            </field>
            <field>
              <name>MUTECNT</name>
              <bitOffset>7</bitOffset>
              <bitWidth>6</bitWidth>
            </field>
            <field>
              <name>CPL</name>
              <bitOffset>13</bitOffset>
              <bitWidth>1</bitWidth>
            </field>
            <field>
              <name>COMP</name>
              <bitOffset>14</bitOffset>
              <bitWidth>2</bitWidth>
            </field>
          </fields>
        </register>
        <register>
          <name>FRCRA</name>
          <addressOffset>0xc</addressOffset>
          <size>0x20</size>
          <fields>
            <field>
              <name>FRL</name>
              <bitOffset>0</bitOffset>
              <bitWidth>8</bitWidth>
            </field>
            <field>
              <name>FSALL</name>
              <bitOffset>8</bitOffset>
              <bitWidth>7</bitWidth>
            </field>
            <field>
              <name>FSDEF</name>
              <bitOffset>16</bitOffset>
              <bitWidth>1</bitWidth>
            </field>
            <field>
              <name>FSPOL</name>
              <bitOffset>17</bitOffset>
              <bitWidth>1</bitWidth>
            </field>
            <field>
              <name>FSOFF</name>
              <bitOffset>18</bitOffset>
              <bitWidth>1</bitWidth>
            </field>
          </fields>
        </register>
        <register>
          <name>FRCRA</name>
          <addressOffset>0xc</addressOffset>
          <size>0x20</size>
          <fields>
            <field>
              <name>FRL</name>
              <bitOffset>0</bitOffset>
              <bitWidth>8</bitWidth>
            </field>
            <field>
              <name>FSALL</name>
              <bitOffset>8</bitOffset>
              <bitWidth>7</bitWidth>
            </field>
            <field>
              <name>FSDEF</name>
              <bitOffset>16</bitOffset>
              <bitWidth>1</bitWidth>
            </field>
            <field>
              <name>FSPOL</name>
              <bitOffset>17</bitOffset>
              <bitWidth>1</bitWidth>
            </field>
            <field>
              <name>FSOFF</name>
              <bitOffset>18</bitOffset>
              <bitWidth>1</bitWidth>
            </field>
          </fields>
        </register>
        <register>
          <name>SLOTRA</name>
          <addressOffset>0x10</addressOffset>
          <size>0x20</size>
          <fields>
            <field>
              <name>FBOFF</name>
              <bitOffset>0</bitOffset>
              <bitWidth>5</bitWidth>
            </field>
            <field>
              <name>SLOTSZ</name>
              <bitOffset>6</bitOffset>
              <bitWidth>2</bitWidth>
            </field>
            <field>
              <name>NBSLOT</name>
              <bitOffset>8</bitOffset>
              <bitWidth>4</bitWidth>
            </field>
            <field>
              <name>SLOTEN</name>
              <bitOffset>16</bitOffset>
              <bitWidth>16</bitWidth>
            </field>
          </fields>
        </register>
        <register>
          <name>SLOTRA</name>
          <addressOffset>0x10</addressOffset>
          <size>0x20</size>
          <fields>
            <field>
              <name>FBOFF</name>
              <bitOffset>0</bitOffset>
              <bitWidth>5</bitWidth>
            </field>
            <field>
              <name>SLOTSZ</name>
              <bitOffset>6</bitOffset>
              <bitWidth>2</bitWidth>
            </field>
            <field>
              <name>NBSLOT</name>
              <bitOffset>8</bitOffset>
              <bitWidth>4</bitWidth>
            </field>
            <field>
              <name>SLOTEN</name>
              <bitOffset>16</bitOffset>
              <bitWidth>16</bitWidth>
            </field>
          </fields>
        </register>
        <register>
          <name>IMRA</name>
          <addressOffset>0x14</addressOffset>
          <size>0x20</size>
          <fields>
            <field>
              <name>OVRUDRIE</name>
              <bitOffset>0</bitOffset>
              <bitWidth>1</bitWidth>
            </field>
            <field>
              <name>MUTEDETIE</name>
              <bitOffset>1</bitOffset>
              <bitWidth>1</bitWidth>
            </field>
            <field>
              <name>WCKCFGIE</name>
              <bitOffset>2</bitOffset>
              <bitWidth>1</bitWidth>
            </field>
            <field>
              <name>FREQIE</name>
              <bitOffset>3</bitOffset>
              <bitWidth>1</bitWidth>
            </field>
            <field>
              <name>CNRDYIE</name>
              <bitOffset>4</bitOffset>
              <bitWidth>1</bitWidth>
            </field>
            <field>
              <name>AFSDETIE</name>
              <bitOffset>5</bitOffset>
              <bitWidth>1</bitWidth>
            </field>
            <field>
              <name>LFSDETIE</name>
              <bitOffset>6</bitOffset>
              <bitWidth>1</bitWidth>
            </field>
          </fields>
        </register>
        <register>
          <name>IMRA</name>
          <addressOffset>0x14</addressOffset>
          <size>0x20</size>
          <fields>
            <field>
              <name>OVRUDRIE</name>
              <bitOffset>0</bitOffset>
              <bitWidth>1</bitWidth>
            </field>
            <field>
              <name>MUTEDETIE</name>
              <bitOffset>1</bitOffset>
              <bitWidth>1</bitWidth>
            </field>
            <field>
              <name>WCKCFGIE</name>
              <bitOffset>2</bitOffset>
              <bitWidth>1</bitWidth>
            </field>
            <field>
              <name>FREQIE</name>
              <bitOffset>3</bitOffset>
              <bitWidth>1</bitWidth>
            </field>
            <field>
              <name>CNRDYIE</name>
              <bitOffset>4</bitOffset>
              <bitWidth>1</bitWidth>
            </field>
            <field>
              <name>AFSDETIE</name>
              <bitOffset>5</bitOffset>
              <bitWidth>1</bitWidth>
            </field>
            <field>
              <name>LFSDETIE</name>
              <bitOffset>6</bitOffset>
              <bitWidth>1</bitWidth>
            </field>
          </fields>
        </register>
        <register>
          <name>SRA</name>
          <addressOffset>0x18</addressOffset>
          <size>0x20</size>
          <fields>
            <field>
              <name>OVRUDR</name>
              <bitOffset>0</bitOffset>
              <bitWidth>1</bitWidth>
            </field>
            <field>
              <name>MUTEDET</name>
              <bitOffset>1</bitOffset>
              <bitWidth>1</bitWidth>
            </field>
            <field>
              <name>WCKCFG</name>
              <bitOffset>2</bitOffset>
              <bitWidth>1</bitWidth>
            </field>
            <field>
              <name>FREQ</name>
              <bitOffset>3</bitOffset>
              <bitWidth>1</bitWidth>
            </field>
            <field>
              <name>CNRDY</name>
              <bitOffset>4</bitOffset>
              <bitWidth>1</bitWidth>
            </field>
            <field>
              <name>AFSDET</name>
              <bitOffset>5</bitOffset>
              <bitWidth>1</bitWidth>
            </field>
            <field>
              <name>LFSDET</name>
              <bitOffset>6</bitOffset>
              <bitWidth>1</bitWidth>
            </field>
            <field>
              <name>FLVL</name>
              <bitOffset>16</bitOffset>
              <bitWidth>3</bitWidth>
            </field>
          </fields>
        </register>
        <register>
          <name>SRA</name>
          <addressOffset>0x18</addressOffset>
          <size>0x20</size>
          <fields>
            <field>
              <name>OVRUDR</name>
              <bitOffset>0</bitOffset>
              <bitWidth>1</bitWidth>
            </field>
            <field>
              <name>MUTEDET</name>
              <bitOffset>1</bitOffset>
              <bitWidth>1</bitWidth>
            </field>
            <field>
              <name>WCKCFG</name>
              <bitOffset>2</bitOffset>
              <bitWidth>1</bitWidth>
            </field>
            <field>
              <name>FREQ</name>
              <bitOffset>3</bitOffset>
              <bitWidth>1</bitWidth>
            </field>
            <field>
              <name>CNRDY</name>
              <bitOffset>4</bitOffset>
              <bitWidth>1</bitWidth>
            </field>
            <field>
              <name>AFSDET</name>
              <bitOffset>5</bitOffset>
              <bitWidth>1</bitWidth>
            </field>
            <field>
              <name>LFSDET</name>
              <bitOffset>6</bitOffset>
              <bitWidth>1</bitWidth>
            </field>
            <field>
              <name>FLVL</name>
              <bitOffset>16</bitOffset>
              <bitWidth>3</bitWidth>
            </field>
          </fields>
        </register>
        <register>
          <name>CLRFRA</name>
          <addressOffset>0x1c</addressOffset>
          <size>0x20</size>
          <fields>
            <field>
              <name>COVRUDR</name>
              <bitOffset>0</bitOffset>
              <bitWidth>1</bitWidth>
            </field>
            <field>
              <name>CMUTEDET</name>
              <bitOffset>1</bitOffset>
              <bitWidth>1</bitWidth>
            </field>
            <field>
              <name>CWCKCFG</name>
              <bitOffset>2</bitOffset>
              <bitWidth>1</bitWidth>
            </field>
            <field>
              <name>CFREQ</name>
              <bitOffset>3</bitOffset>
              <bitWidth>1</bitWidth>
            </field>
            <field>
              <name>CCNRDY</name>
              <bitOffset>4</bitOffset>
              <bitWidth>1</bitWidth>
            </field>
            <field>
              <name>CAFSDET</name>
              <bitOffset>5</bitOffset>
              <bitWidth>1</bitWidth>
            </field>
            <field>
              <name>CLFSDET</name>
              <bitOffset>6</bitOffset>
              <bitWidth>1</bitWidth>
            </field>
          </fields>
        </register>
        <register>
          <name>CLRFRA</name>
          <addressOffset>0x1c</addressOffset>
          <size>0x20</size>
          <fields>
            <field>
              <name>COVRUDR</name>
              <bitOffset>0</bitOffset>
              <bitWidth>1</bitWidth>
            </field>
            <field>
              <name>CMUTEDET</name>
              <bitOffset>1</bitOffset>
              <bitWidth>1</bitWidth>
            </field>
            <field>
              <name>CWCKCFG</name>
              <bitOffset>2</bitOffset>
              <bitWidth>1</bitWidth>
            </field>
            <field>
              <name>CFREQ</name>
              <bitOffset>3</bitOffset>
              <bitWidth>1</bitWidth>
            </field>
            <field>
              <name>CCNRDY</name>
              <bitOffset>4</bitOffset>
              <bitWidth>1</bitWidth>
            </field>
            <field>
              <name>CAFSDET</name>
              <bitOffset>5</bitOffset>
              <bitWidth>1</bitWidth>
            </field>
            <field>
              <name>CLFSDET</name>
              <bitOffset>6</bitOffset>
              <bitWidth>1</bitWidth>
            </field>
          </fields>
        </register>
        <register>
          <name>DRA</name>
          <addressOffset>0x20</addressOffset>
          <size>0x20</size>
          <fields>
            <field>
              <name>DATA</name>
              <bitOffset>0</bitOffset>
              <bitWidth>32</bitWidth>
            </field>
          </fields>
        </register>
        <register>
          <name>DRA</name>
          <addressOffset>0x20</addressOffset>
          <size>0x20</size>
          <fields>
            <field>
              <name>DATA</name>
              <bitOffset>0</bitOffset>
              <bitWidth>32</bitWidth>
            </field>
          </fields>
        </register>
        <register>
          <name>CR1B</name>
          <addressOffset>0x24</addressOffset>
          <size>0x20</size>
          <fields>
            <field>
              <name>MODE</name>
              <bitOffset>0</bitOffset>
              <bitWidth>2</bitWidth>
            </field>
            <field>
              <name>PRTCFG</name>
              <bitOffset>2</bitOffset>
              <bitWidth>2</bitWidth>
            </field>
            <field>
              <name>DS</name>
              <bitOffset>5</bitOffset>
              <bitWidth>3</bitWidth>
            </field>
            <field>
              <name>LSBFIRST</name>
              <bitOffset>8</bitOffset>
              <bitWidth>1</bitWidth>
            </field>
            <field>
              <name>CKSTR</name>
              <bitOffset>9</bitOffset>
              <bitWidth>1</bitWidth>
            </field>
            <field>
              <name>SYNCEN</name>
              <bitOffset>10</bitOffset>
              <bitWidth>2</bitWidth>
            </field>
            <field>
              <name>MONO</name>
              <bitOffset>12</bitOffset>
              <bitWidth>1</bitWidth>
            </field>
            <field>
              <name>OUTDRIV</name>
              <bitOffset>13</bitOffset>
              <bitWidth>1</bitWidth>
            </field>
            <field>
              <name>SAIEN</name>
              <bitOffset>16</bitOffset>
              <bitWidth>1</bitWidth>
            </field>
            <field>
              <name>DMAEN</name>
              <bitOffset>17</bitOffset>
              <bitWidth>1</bitWidth>
            </field>
            <field>
              <name>NODIV</name>
              <bitOffset>19</bitOffset>
              <bitWidth>1</bitWidth>
            </field>
            <field>
              <name>MCKDIV</name>
              <bitOffset>20</bitOffset>
              <bitWidth>4</bitWidth>
            </field>
          </fields>
        </register>
        <register>
          <name>CR1B</name>
          <addressOffset>0x24</addressOffset>
          <size>0x20</size>
          <fields>
            <field>
              <name>MODE</name>
              <bitOffset>0</bitOffset>
              <bitWidth>2</bitWidth>
            </field>
            <field>
              <name>PRTCFG</name>
              <bitOffset>2</bitOffset>
              <bitWidth>2</bitWidth>
            </field>
            <field>
              <name>DS</name>
              <bitOffset>5</bitOffset>
              <bitWidth>3</bitWidth>
            </field>
            <field>
              <name>LSBFIRST</name>
              <bitOffset>8</bitOffset>
              <bitWidth>1</bitWidth>
            </field>
            <field>
              <name>CKSTR</name>
              <bitOffset>9</bitOffset>
              <bitWidth>1</bitWidth>
            </field>
            <field>
              <name>SYNCEN</name>
              <bitOffset>10</bitOffset>
              <bitWidth>2</bitWidth>
            </field>
            <field>
              <name>MONO</name>
              <bitOffset>12</bitOffset>
              <bitWidth>1</bitWidth>
            </field>
            <field>
              <name>OUTDRIV</name>
              <bitOffset>13</bitOffset>
              <bitWidth>1</bitWidth>
            </field>
            <field>
              <name>SAIEN</name>
              <bitOffset>16</bitOffset>
              <bitWidth>1</bitWidth>
            </field>
            <field>
              <name>DMAEN</name>
              <bitOffset>17</bitOffset>
              <bitWidth>1</bitWidth>
            </field>
            <field>
              <name>NODIV</name>
              <bitOffset>19</bitOffset>
              <bitWidth>1</bitWidth>
            </field>
            <field>
              <name>MCKDIV</name>
              <bitOffset>20</bitOffset>
              <bitWidth>4</bitWidth>
            </field>
          </fields>
        </register>
        <register>
          <name>CR2B</name>
          <addressOffset>0x28</addressOffset>
          <size>0x20</size>
          <fields>
            <field>
              <name>FTH</name>
              <bitOffset>0</bitOffset>
              <bitWidth>3</bitWidth>
            </field>
            <field>
              <name>FFLUSH</name>
              <bitOffset>3</bitOffset>
              <bitWidth>1</bitWidth>
            </field>
            <field>
              <name>TRIS</name>
              <bitOffset>4</bitOffset>
              <bitWidth>1</bitWidth>
            </field>
            <field>
              <name>MUTE</name>
              <bitOffset>5</bitOffset>
              <bitWidth>1</bitWidth>
            </field>
            <field>
              <name>MUTEVAL</name>
              <bitOffset>6</bitOffset>
              <bitWidth>1</bitWidth>
            </field>
            <field>
              <name>MUTECNT</name>
              <bitOffset>7</bitOffset>
              <bitWidth>6</bitWidth>
            </field>
            <field>
              <name>CPL</name>
              <bitOffset>13</bitOffset>
              <bitWidth>1</bitWidth>
            </field>
            <field>
              <name>COMP</name>
              <bitOffset>14</bitOffset>
              <bitWidth>2</bitWidth>
            </field>
          </fields>
        </register>
        <register>
          <name>CR2B</name>
          <addressOffset>0x28</addressOffset>
          <size>0x20</size>
          <fields>
            <field>
              <name>FTH</name>
              <bitOffset>0</bitOffset>
              <bitWidth>3</bitWidth>
            </field>
            <field>
              <name>FFLUSH</name>
              <bitOffset>3</bitOffset>
              <bitWidth>1</bitWidth>
            </field>
            <field>
              <name>TRIS</name>
              <bitOffset>4</bitOffset>
              <bitWidth>1</bitWidth>
            </field>
            <field>
              <name>MUTE</name>
              <bitOffset>5</bitOffset>
              <bitWidth>1</bitWidth>
            </field>
            <field>
              <name>MUTEVAL</name>
              <bitOffset>6</bitOffset>
              <bitWidth>1</bitWidth>
            </field>
            <field>
              <name>MUTECNT</name>
              <bitOffset>7</bitOffset>
              <bitWidth>6</bitWidth>
            </field>
            <field>
              <name>CPL</name>
              <bitOffset>13</bitOffset>
              <bitWidth>1</bitWidth>
            </field>
            <field>
              <name>COMP</name>
              <bitOffset>14</bitOffset>
              <bitWidth>2</bitWidth>
            </field>
          </fields>
        </register>
        <register>
          <name>FRCRB</name>
          <addressOffset>0x2c</addressOffset>
          <size>0x20</size>
          <fields>
            <field>
              <name>FRL</name>
              <bitOffset>0</bitOffset>
              <bitWidth>8</bitWidth>
            </field>
            <field>
              <name>FSALL</name>
              <bitOffset>8</bitOffset>
              <bitWidth>7</bitWidth>
            </field>
            <field>
              <name>FSDEF</name>
              <bitOffset>16</bitOffset>
              <bitWidth>1</bitWidth>
            </field>
            <field>
              <name>FSPOL</name>
              <bitOffset>17</bitOffset>
              <bitWidth>1</bitWidth>
            </field>
            <field>
              <name>FSOFF</name>
              <bitOffset>18</bitOffset>
              <bitWidth>1</bitWidth>
            </field>
          </fields>
        </register>
        <register>
          <name>FRCRB</name>
          <addressOffset>0x2c</addressOffset>
          <size>0x20</size>
          <fields>
            <field>
              <name>FRL</name>
              <bitOffset>0</bitOffset>
              <bitWidth>8</bitWidth>
            </field>
            <field>
              <name>FSALL</name>
              <bitOffset>8</bitOffset>
              <bitWidth>7</bitWidth>
            </field>
            <field>
              <name>FSDEF</name>
              <bitOffset>16</bitOffset>
              <bitWidth>1</bitWidth>
            </field>
            <field>
              <name>FSPOL</name>
              <bitOffset>17</bitOffset>
              <bitWidth>1</bitWidth>
            </field>
            <field>
              <name>FSOFF</name>
              <bitOffset>18</bitOffset>
              <bitWidth>1</bitWidth>
            </field>
          </fields>
        </register>
        <register>
          <name>SLOTRB</name>
          <addressOffset>0x30</addressOffset>
          <size>0x20</size>
          <fields>
            <field>
              <name>FBOFF</name>
              <bitOffset>0</bitOffset>
              <bitWidth>5</bitWidth>
            </field>
            <field>
              <name>SLOTSZ</name>
              <bitOffset>6</bitOffset>
              <bitWidth>2</bitWidth>
            </field>
            <field>
              <name>NBSLOT</name>
              <bitOffset>8</bitOffset>
              <bitWidth>4</bitWidth>
            </field>
            <field>
              <name>SLOTEN</name>
              <bitOffset>16</bitOffset>
              <bitWidth>16</bitWidth>
            </field>
          </fields>
        </register>
        <register>
          <name>SLOTRB</name>
          <addressOffset>0x30</addressOffset>
          <size>0x20</size>
          <fields>
            <field>
              <name>FBOFF</name>
              <bitOffset>0</bitOffset>
              <bitWidth>5</bitWidth>
            </field>
            <field>
              <name>SLOTSZ</name>
              <bitOffset>6</bitOffset>
              <bitWidth>2</bitWidth>
            </field>
            <field>
              <name>NBSLOT</name>
              <bitOffset>8</bitOffset>
              <bitWidth>4</bitWidth>
            </field>
            <field>
              <name>SLOTEN</name>
              <bitOffset>16</bitOffset>
              <bitWidth>16</bitWidth>
            </field>
          </fields>
        </register>
        <register>
          <name>IMRB</name>
          <addressOffset>0x34</addressOffset>
          <size>0x20</size>
          <fields>
            <field>
              <name>OVRUDRIE</name>
              <bitOffset>0</bitOffset>
              <bitWidth>1</bitWidth>
            </field>
            <field>
              <name>MUTEDETIE</name>
              <bitOffset>1</bitOffset>
              <bitWidth>1</bitWidth>
            </field>
            <field>
              <name>WCKCFGIE</name>
              <bitOffset>2</bitOffset>
              <bitWidth>1</bitWidth>
            </field>
            <field>
              <name>FREQIE</name>
              <bitOffset>3</bitOffset>
              <bitWidth>1</bitWidth>
            </field>
            <field>
              <name>CNRDYIE</name>
              <bitOffset>4</bitOffset>
              <bitWidth>1</bitWidth>
            </field>
            <field>
              <name>AFSDETIE</name>
              <bitOffset>5</bitOffset>
              <bitWidth>1</bitWidth>
            </field>
            <field>
              <name>LFSDETIE</name>
              <bitOffset>6</bitOffset>
              <bitWidth>1</bitWidth>
            </field>
          </fields>
        </register>
        <register>
          <name>IMRB</name>
          <addressOffset>0x34</addressOffset>
          <size>0x20</size>
          <fields>
            <field>
              <name>OVRUDRIE</name>
              <bitOffset>0</bitOffset>
              <bitWidth>1</bitWidth>
            </field>
            <field>
              <name>MUTEDETIE</name>
              <bitOffset>1</bitOffset>
              <bitWidth>1</bitWidth>
            </field>
            <field>
              <name>WCKCFGIE</name>
              <bitOffset>2</bitOffset>
              <bitWidth>1</bitWidth>
            </field>
            <field>
              <name>FREQIE</name>
              <bitOffset>3</bitOffset>
              <bitWidth>1</bitWidth>
            </field>
            <field>
              <name>CNRDYIE</name>
              <bitOffset>4</bitOffset>
              <bitWidth>1</bitWidth>
            </field>
            <field>
              <name>AFSDETIE</name>
              <bitOffset>5</bitOffset>
              <bitWidth>1</bitWidth>
            </field>
            <field>
              <name>LFSDETIE</name>
              <bitOffset>6</bitOffset>
              <bitWidth>1</bitWidth>
            </field>
          </fields>
        </register>
        <register>
          <name>SRB</name>
          <addressOffset>0x38</addressOffset>
          <size>0x20</size>
          <fields>
            <field>
              <name>OVRUDR</name>
              <bitOffset>0</bitOffset>
              <bitWidth>1</bitWidth>
            </field>
            <field>
              <name>MUTEDET</name>
              <bitOffset>1</bitOffset>
              <bitWidth>1</bitWidth>
            </field>
            <field>
              <name>WCKCFG</name>
              <bitOffset>2</bitOffset>
              <bitWidth>1</bitWidth>
            </field>
            <field>
              <name>FREQ</name>
              <bitOffset>3</bitOffset>
              <bitWidth>1</bitWidth>
            </field>
            <field>
              <name>CNRDY</name>
              <bitOffset>4</bitOffset>
              <bitWidth>1</bitWidth>
            </field>
            <field>
              <name>AFSDET</name>
              <bitOffset>5</bitOffset>
              <bitWidth>1</bitWidth>
            </field>
            <field>
              <name>LFSDET</name>
              <bitOffset>6</bitOffset>
              <bitWidth>1</bitWidth>
            </field>
            <field>
              <name>FLVL</name>
              <bitOffset>16</bitOffset>
              <bitWidth>3</bitWidth>
            </field>
          </fields>
        </register>
        <register>
          <name>SRB</name>
          <addressOffset>0x38</addressOffset>
          <size>0x20</size>
          <fields>
            <field>
              <name>OVRUDR</name>
              <bitOffset>0</bitOffset>
              <bitWidth>1</bitWidth>
            </field>
            <field>
              <name>MUTEDET</name>
              <bitOffset>1</bitOffset>
              <bitWidth>1</bitWidth>
            </field>
            <field>
              <name>WCKCFG</name>
              <bitOffset>2</bitOffset>
              <bitWidth>1</bitWidth>
            </field>
            <field>
              <name>FREQ</name>
              <bitOffset>3</bitOffset>
              <bitWidth>1</bitWidth>
            </field>
            <field>
              <name>CNRDY</name>
              <bitOffset>4</bitOffset>
              <bitWidth>1</bitWidth>
            </field>
            <field>
              <name>AFSDET</name>
              <bitOffset>5</bitOffset>
              <bitWidth>1</bitWidth>
            </field>
            <field>
              <name>LFSDET</name>
              <bitOffset>6</bitOffset>
              <bitWidth>1</bitWidth>
            </field>
            <field>
              <name>FLVL</name>
              <bitOffset>16</bitOffset>
              <bitWidth>3</bitWidth>
            </field>
          </fields>
        </register>
        <register>
          <name>CLRFRB</name>
          <addressOffset>0x3c</addressOffset>
          <size>0x20</size>
          <fields>
            <field>
              <name>COVRUDR</name>
              <bitOffset>0</bitOffset>
              <bitWidth>1</bitWidth>
            </field>
            <field>
              <name>CMUTEDET</name>
              <bitOffset>1</bitOffset>
              <bitWidth>1</bitWidth>
            </field>
            <field>
              <name>CWCKCFG</name>
              <bitOffset>2</bitOffset>
              <bitWidth>1</bitWidth>
            </field>
            <field>
              <name>CFREQ</name>
              <bitOffset>3</bitOffset>
              <bitWidth>1</bitWidth>
            </field>
            <field>
              <name>CCNRDY</name>
              <bitOffset>4</bitOffset>
              <bitWidth>1</bitWidth>
            </field>
            <field>
              <name>CAFSDET</name>
              <bitOffset>5</bitOffset>
              <bitWidth>1</bitWidth>
            </field>
            <field>
              <name>CLFSDET</name>
              <bitOffset>6</bitOffset>
              <bitWidth>1</bitWidth>
            </field>
          </fields>
        </register>
        <register>
          <name>CLRFRB</name>
          <addressOffset>0x3c</addressOffset>
          <size>0x20</size>
          <fields>
            <field>
              <name>COVRUDR</name>
              <bitOffset>0</bitOffset>
              <bitWidth>1</bitWidth>
            </field>
            <field>
              <name>CMUTEDET</name>
              <bitOffset>1</bitOffset>
              <bitWidth>1</bitWidth>
            </field>
            <field>
              <name>CWCKCFG</name>
              <bitOffset>2</bitOffset>
              <bitWidth>1</bitWidth>
            </field>
            <field>
              <name>CFREQ</name>
              <bitOffset>3</bitOffset>
              <bitWidth>1</bitWidth>
            </field>
            <field>
              <name>CCNRDY</name>
              <bitOffset>4</bitOffset>
              <bitWidth>1</bitWidth>
            </field>
            <field>
              <name>CAFSDET</name>
              <bitOffset>5</bitOffset>
              <bitWidth>1</bitWidth>
            </field>
            <field>
              <name>CLFSDET</name>
              <bitOffset>6</bitOffset>
              <bitWidth>1</bitWidth>
            </field>
          </fields>
        </register>
        <register>
          <name>DRB</name>
          <addressOffset>0x40</addressOffset>
          <size>0x20</size>
          <fields>
            <field>
              <name>DATA</name>
              <bitOffset>0</bitOffset>
              <bitWidth>32</bitWidth>
            </field>
          </fields>
        </register>
        <register>
          <name>DRB</name>
          <addressOffset>0x40</addressOffset>
          <size>0x20</size>
          <fields>
            <field>
              <name>DATA</name>
              <bitOffset>0</bitOffset>
              <bitWidth>32</bitWidth>
            </field>
          </fields>
        </register>
      </registers>
    </peripheral>
    <peripheral>
      <name>LTDC</name>
      <baseAddress>0x40016800</baseAddress>
      <registers>
        <register>
          <name>SSCR</name>
          <addressOffset>0x8</addressOffset>
          <size>0x20</size>
          <fields>
            <field>
              <name>VSH</name>
              <bitOffset>0</bitOffset>
              <bitWidth>11</bitWidth>
            </field>
            <field>
              <name>HSW</name>
              <bitOffset>16</bitOffset>
              <bitWidth>12</bitWidth>
            </field>
          </fields>
        </register>
        <register>
          <name>BPCR</name>
          <addressOffset>0xc</addressOffset>
          <size>0x20</size>
          <fields>
            <field>
              <name>AVBP</name>
              <bitOffset>0</bitOffset>
              <bitWidth>11</bitWidth>
            </field>
            <field>
              <name>AHBP</name>
              <bitOffset>16</bitOffset>
              <bitWidth>12</bitWidth>
            </field>
          </fields>
        </register>
        <register>
          <name>AWCR</name>
          <addressOffset>0x10</addressOffset>
          <size>0x20</size>
          <fields>
            <field>
              <name>AAH</name>
              <bitOffset>0</bitOffset>
              <bitWidth>11</bitWidth>
            </field>
            <field>
              <name>AAW</name>
              <bitOffset>16</bitOffset>
              <bitWidth>12</bitWidth>
            </field>
          </fields>
        </register>
        <register>
          <name>TWCR</name>
          <addressOffset>0x14</addressOffset>
          <size>0x20</size>
          <fields>
            <field>
              <name>TOTALH</name>
              <bitOffset>0</bitOffset>
              <bitWidth>11</bitWidth>
            </field>
            <field>
              <name>TOTALW</name>
              <bitOffset>16</bitOffset>
              <bitWidth>12</bitWidth>
            </field>
          </fields>
        </register>
        <register>
          <name>GCR</name>
          <addressOffset>0x18</addressOffset>
          <size>0x20</size>
          <fields>
            <field>
              <name>LTDCEN</name>
              <bitOffset>0</bitOffset>
              <bitWidth>1</bitWidth>
            </field>
            <field>
              <name>DBW</name>
              <bitOffset>4</bitOffset>
              <bitWidth>3</bitWidth>
            </field>
            <field>
              <name>DGW</name>
              <bitOffset>8</bitOffset>
              <bitWidth>3</bitWidth>
            </field>
            <field>
              <name>DRW</name>
              <bitOffset>12</bitOffset>
              <bitWidth>3</bitWidth>
            </field>
            <field>
              <name>DEN</name>
              <bitOffset>16</bitOffset>
              <bitWidth>1</bitWidth>
            </field>
            <field>
              <name>PCPOL</name>
              <bitOffset>28</bitOffset>
              <bitWidth>1</bitWidth>
            </field>
            <field>
              <name>DEPOL</name>
              <bitOffset>29</bitOffset>
              <bitWidth>1</bitWidth>
            </field>
            <field>
              <name>VSPOL</name>
              <bitOffset>30</bitOffset>
              <bitWidth>1</bitWidth>
            </field>
            <field>
              <name>HSPOL</name>
              <bitOffset>31</bitOffset>
              <bitWidth>1</bitWidth>
            </field>
          </fields>
        </register>
        <register>
          <name>SRCR</name>
          <addressOffset>0x24</addressOffset>
          <size>0x20</size>
          <fields>
            <field>
              <name>IMR</name>
              <bitOffset>0</bitOffset>
              <bitWidth>1</bitWidth>
            </field>
            <field>
              <name>VBR</name>
              <bitOffset>1</bitOffset>
              <bitWidth>1</bitWidth>
            </field>
          </fields>
        </register>
        <register>
          <name>BCCR</name>
          <addressOffset>0x2c</addressOffset>
          <size>0x20</size>
          <fields>
            <field>
              <name>BCBLUE</name>
              <bitOffset>0</bitOffset>
              <bitWidth>8</bitWidth>
            </field>
            <field>
              <name>BCGREEN</name>
              <bitOffset>8</bitOffset>
              <bitWidth>8</bitWidth>
            </field>
            <field>
              <name>BCRED</name>
              <bitOffset>16</bitOffset>
              <bitWidth>8</bitWidth>
            </field>
          </fields>
        </register>
        <register>
          <name>IER</name>
          <addressOffset>0x34</addressOffset>
          <size>0x20</size>
          <fields>
            <field>
              <name>LIE</name>
              <bitOffset>0</bitOffset>
              <bitWidth>1</bitWidth>
            </field>
            <field>
              <name>FUIE</name>
              <bitOffset>1</bitOffset>
              <bitWidth>1</bitWidth>
            </field>
            <field>
              <name>TERRIE</name>
              <bitOffset>2</bitOffset>
              <bitWidth>1</bitWidth>
            </field>
            <field>
              <name>RRIE</name>
              <bitOffset>3</bitOffset>
              <bitWidth>1</bitWidth>
            </field>
          </fields>
        </register>
        <register>
          <name>ISR</name>
          <addressOffset>0x38</addressOffset>
          <size>0x20</size>
          <fields>
            <field>
              <name>LIF</name>
              <bitOffset>0</bitOffset>
              <bitWidth>1</bitWidth>
            </field>
            <field>
              <name>FUIF</name>
              <bitOffset>1</bitOffset>
              <bitWidth>1</bitWidth>
            </field>
            <field>
              <name>TERRIF</name>
              <bitOffset>2</bitOffset>
              <bitWidth>1</bitWidth>
            </field>
            <field>
              <name>RRIF</name>
              <bitOffset>3</bitOffset>
              <bitWidth>1</bitWidth>
            </field>
          </fields>
        </register>
        <register>
          <name>ICR</name>
          <addressOffset>0x3c</addressOffset>
          <size>0x20</size>
          <fields>
            <field>
              <name>CLIF</name>
              <bitOffset>0</bitOffset>
              <bitWidth>1</bitWidth>
            </field>
            <field>
              <name>CFUIF</name>
              <bitOffset>1</bitOffset>
              <bitWidth>1</bitWidth>
            </field>
            <field>
              <name>CTERRIF</name>
              <bitOffset>2</bitOffset>
              <bitWidth>1</bitWidth>
            </field>
            <field>
              <name>CRRIF</name>
              <bitOffset>3</bitOffset>
              <bitWidth>1</bitWidth>
            </field>
          </fields>
        </register>
        <register>
          <name>LIPCR</name>
          <addressOffset>0x40</addressOffset>
          <size>0x20</size>
          <fields>
            <field>
              <name>LIPOS</name>
              <bitOffset>0</bitOffset>
              <bitWidth>11</bitWidth>
            </field>
          </fields>
        </register>
        <register>
          <name>CPSR</name>
          <addressOffset>0x44</addressOffset>
          <size>0x20</size>
          <fields>
            <field>
              <name>CYPOS</name>
              <bitOffset>0</bitOffset>
              <bitWidth>16</bitWidth>
            </field>
            <field>
              <name>CXPOS</name>
              <bitOffset>16</bitOffset>
              <bitWidth>16</bitWidth>
            </field>
          </fields>
        </register>
        <register>
          <name>CDSR</name>
          <addressOffset>0x48</addressOffset>
          <size>0x20</size>
          <fields>
            <field>
              <name>VDES</name>
              <bitOffset>0</bitOffset>
              <bitWidth>1</bitWidth>
            </field>
            <field>
              <name>HDES</name>
              <bitOffset>1</bitOffset>
              <bitWidth>1</bitWidth>
            </field>
            <field>
              <name>VSYNCS</name>
              <bitOffset>2</bitOffset>
              <bitWidth>1</bitWidth>
            </field>
            <field>
              <name>HSYNCS</name>
              <bitOffset>3</bitOffset>
              <bitWidth>1</bitWidth>
            </field>
          </fields>
        </register>
        <register>
          <name>CR1</name>
          <addressOffset>0x84</addressOffset>
          <size>0x20</size>
        </register>
        <register>
          <name>WHPCR1</name>
          <addressOffset>0x88</addressOffset>
          <size>0x20</size>
        </register>
        <register>
          <name>WVPCR1</name>
          <addressOffset>0x8c</addressOffset>
          <size>0x20</size>
        </register>
        <register>
          <name>CKCR1</name>
          <addressOffset>0x90</addressOffset>
          <size>0x20</size>
        </register>
        <register>
          <name>PFCR1</name>
          <addressOffset>0x94</addressOffset>
          <size>0x20</size>
        </register>
        <register>
          <name>CACR1</name>
          <addressOffset>0x98</addressOffset>
          <size>0x20</size>
        </register>
        <register>
          <name>DCCR1</name>
          <addressOffset>0x9c</addressOffset>
          <size>0x20</size>
        </register>
        <register>
          <name>BFCR1</name>
          <addressOffset>0xa0</addressOffset>
          <size>0x20</size>
        </register>
        <register>
          <name>CFBAR1</name>
          <addressOffset>0xac</addressOffset>
          <size>0x20</size>
        </register>
        <register>
          <name>CFBLR1</name>
          <addressOffset>0xb0</addressOffset>
          <size>0x20</size>
        </register>
        <register>
          <name>CFBLNR1</name>
          <addressOffset>0xb4</addressOffset>
          <size>0x20</size>
        </register>
        <register>
          <name>CLUTWR1</name>
          <addressOffset>0xc4</addressOffset>
          <size>0x20</size>
        </register>
        <register>
          <name>CR2</name>
          <addressOffset>0x104</addressOffset>
          <size>0x20</size>
        </register>
        <register>
          <name>WHPCR2</name>
          <addressOffset>0x108</addressOffset>
          <size>0x20</size>
        </register>
        <register>
          <name>WVPCR2</name>
          <addressOffset>0x10c</addressOffset>
          <size>0x20</size>
        </register>
        <register>
          <name>CKCR2</name>
          <addressOffset>0x110</addressOffset>
          <size>0x20</size>
        </register>
        <register>
          <name>PFCR2</name>
          <addressOffset>0x114</addressOffset>
          <size>0x20</size>
        </register>
        <register>
          <name>CACR2</name>
          <addressOffset>0x118</addressOffset>
          <size>0x20</size>
        </register>
        <register>
          <name>DCCR2</name>
          <addressOffset>0x11c</addressOffset>
          <size>0x20</size>
        </register>
        <register>
          <name>BFCR2</name>
          <addressOffset>0x120</addressOffset>
          <size>0x20</size>
        </register>
        <register>
          <name>CFBAR2</name>
          <addressOffset>0x12c</addressOffset>
          <size>0x20</size>
        </register>
        <register>
          <name>CFBLR2</name>
          <addressOffset>0x130</addressOffset>
          <size>0x20</size>
        </register>
        <register>
          <name>CFBLNR2</name>
          <addressOffset>0x134</addressOffset>
          <size>0x20</size>
        </register>
        <register>
          <name>CLUTWR2</name>
          <addressOffset>0x144</addressOffset>
          <size>0x20</size>
        </register>
      </registers>
    </peripheral>
    <peripheral>
      <name>DFSDM1</name>
      <baseAddress>0x40017400</baseAddress>
      <registers>
        <register>
          <name>CHCFGR10</name>
          <addressOffset>0x0</addressOffset>
          <size>0x20</size>
          <fields>
            <field>
              <name>SITP</name>
              <bitOffset>0</bitOffset>
              <bitWidth>2</bitWidth>
            </field>
            <field>
              <name>SPICKSEL</name>
              <bitOffset>2</bitOffset>
              <bitWidth>2</bitWidth>
            </field>
            <field>
              <name>SCDEN</name>
              <bitOffset>5</bitOffset>
              <bitWidth>1</bitWidth>
            </field>
            <field>
              <name>CKABEN</name>
              <bitOffset>6</bitOffset>
              <bitWidth>1</bitWidth>
            </field>
            <field>
              <name>CHEN</name>
              <bitOffset>7</bitOffset>
              <bitWidth>1</bitWidth>
            </field>
            <field>
              <name>CHINSEL</name>
              <bitOffset>8</bitOffset>
              <bitWidth>1</bitWidth>
            </field>
            <field>
              <name>DATMPX</name>
              <bitOffset>12</bitOffset>
              <bitWidth>2</bitWidth>
            </field>
            <field>
              <name>DATPACK</name>
              <bitOffset>14</bitOffset>
              <bitWidth>2</bitWidth>
            </field>
            <field>
              <name>CKOUTDIV</name>
              <bitOffset>16</bitOffset>
              <bitWidth>8</bitWidth>
            </field>
            <field>
              <name>CKOUTSRC</name>
              <bitOffset>30</bitOffset>
              <bitWidth>1</bitWidth>
            </field>
            <field>
              <name>DFSDMEN</name>
              <bitOffset>31</bitOffset>
              <bitWidth>1</bitWidth>
            </field>
          </fields>
        </register>
        <register>
          <name>CHCFGR20</name>
          <addressOffset>0x4</addressOffset>
          <size>0x20</size>
          <fields>
            <field>
              <name>DTRBS</name>
              <bitOffset>3</bitOffset>
              <bitWidth>5</bitWidth>
            </field>
            <field>
              <name>OFFSET</name>
              <bitOffset>8</bitOffset>
              <bitWidth>24</bitWidth>
            </field>
          </fields>
        </register>
        <register>
          <name>CHAWSCDR0</name>
          <addressOffset>0x8</addressOffset>
          <size>0x20</size>
          <fields>
            <field>
              <name>SCDT</name>
              <bitOffset>0</bitOffset>
              <bitWidth>8</bitWidth>
            </field>
            <field>
              <name>BKSCD</name>
              <bitOffset>12</bitOffset>
              <bitWidth>4</bitWidth>
            </field>
            <field>
              <name>AWFOSR</name>
              <bitOffset>16</bitOffset>
              <bitWidth>5</bitWidth>
            </field>
            <field>
              <name>AWFORD</name>
              <bitOffset>22</bitOffset>
              <bitWidth>2</bitWidth>
            </field>
          </fields>
        </register>
        <register>
          <name>CHWDATAR0</name>
          <addressOffset>0xc</addressOffset>
          <size>0x20</size>
        </register>
        <register>
          <name>CHDATINR0</name>
          <addressOffset>0x10</addressOffset>
          <size>0x20</size>
          <fields>
            <field>
              <name>INDAT0</name>
              <bitOffset>0</bitOffset>
              <bitWidth>16</bitWidth>
            </field>
            <field>
              <name>INDAT1</name>
              <bitOffset>16</bitOffset>
              <bitWidth>16</bitWidth>
            </field>
          </fields>
        </register>
        <register>
          <name>CHCFGR11</name>
          <addressOffset>0x20</addressOffset>
          <size>0x20</size>
          <fields>
            <field>
              <name>SITP</name>
              <bitOffset>0</bitOffset>
              <bitWidth>2</bitWidth>
            </field>
            <field>
              <name>SPICKSEL</name>
              <bitOffset>2</bitOffset>
              <bitWidth>2</bitWidth>
            </field>
            <field>
              <name>SCDEN</name>
              <bitOffset>5</bitOffset>
              <bitWidth>1</bitWidth>
            </field>
            <field>
              <name>CKABEN</name>
              <bitOffset>6</bitOffset>
              <bitWidth>1</bitWidth>
            </field>
            <field>
              <name>CHEN</name>
              <bitOffset>7</bitOffset>
              <bitWidth>1</bitWidth>
            </field>
            <field>
              <name>CHINSEL</name>
              <bitOffset>8</bitOffset>
              <bitWidth>1</bitWidth>
            </field>
            <field>
              <name>DATMPX</name>
              <bitOffset>12</bitOffset>
              <bitWidth>2</bitWidth>
            </field>
            <field>
              <name>DATPACK</name>
              <bitOffset>14</bitOffset>
              <bitWidth>2</bitWidth>
            </field>
            <field>
              <name>CKOUTDIV</name>
              <bitOffset>16</bitOffset>
              <bitWidth>8</bitWidth>
            </field>
            <field>
              <name>CKOUTSRC</name>
              <bitOffset>30</bitOffset>
              <bitWidth>1</bitWidth>
            </field>
            <field>
              <name>DFSDMEN</name>
              <bitOffset>31</bitOffset>
              <bitWidth>1</bitWidth>
            </field>
          </fields>
        </register>
        <register>
          <name>CHCFGR21</name>
          <addressOffset>0x24</addressOffset>
          <size>0x20</size>
          <fields>
            <field>
              <name>DTRBS</name>
              <bitOffset>3</bitOffset>
              <bitWidth>5</bitWidth>
            </field>
            <field>
              <name>OFFSET</name>
              <bitOffset>8</bitOffset>
              <bitWidth>24</bitWidth>
            </field>
          </fields>
        </register>
        <register>
          <name>CHAWSCDR1</name>
          <addressOffset>0x28</addressOffset>
          <size>0x20</size>
          <fields>
            <field>
              <name>SCDT</name>
              <bitOffset>0</bitOffset>
              <bitWidth>8</bitWidth>
            </field>
            <field>
              <name>BKSCD</name>
              <bitOffset>12</bitOffset>
              <bitWidth>4</bitWidth>
            </field>
            <field>
              <name>AWFOSR</name>
              <bitOffset>16</bitOffset>
              <bitWidth>5</bitWidth>
            </field>
            <field>
              <name>AWFORD</name>
              <bitOffset>22</bitOffset>
              <bitWidth>2</bitWidth>
            </field>
          </fields>
        </register>
        <register>
          <name>CHWDATAR1</name>
          <addressOffset>0x2c</addressOffset>
          <size>0x20</size>
        </register>
        <register>
          <name>CHDATINR1</name>
          <addressOffset>0x30</addressOffset>
          <size>0x20</size>
          <fields>
            <field>
              <name>INDAT0</name>
              <bitOffset>0</bitOffset>
              <bitWidth>16</bitWidth>
            </field>
            <field>
              <name>INDAT1</name>
              <bitOffset>16</bitOffset>
              <bitWidth>16</bitWidth>
            </field>
          </fields>
        </register>
        <register>
          <name>CHCFGR12</name>
          <addressOffset>0x40</addressOffset>
          <size>0x20</size>
          <fields>
            <field>
              <name>SITP</name>
              <bitOffset>0</bitOffset>
              <bitWidth>2</bitWidth>
            </field>
            <field>
              <name>SPICKSEL</name>
              <bitOffset>2</bitOffset>
              <bitWidth>2</bitWidth>
            </field>
            <field>
              <name>SCDEN</name>
              <bitOffset>5</bitOffset>
              <bitWidth>1</bitWidth>
            </field>
            <field>
              <name>CKABEN</name>
              <bitOffset>6</bitOffset>
              <bitWidth>1</bitWidth>
            </field>
            <field>
              <name>CHEN</name>
              <bitOffset>7</bitOffset>
              <bitWidth>1</bitWidth>
            </field>
            <field>
              <name>CHINSEL</name>
              <bitOffset>8</bitOffset>
              <bitWidth>1</bitWidth>
            </field>
            <field>
              <name>DATMPX</name>
              <bitOffset>12</bitOffset>
              <bitWidth>2</bitWidth>
            </field>
            <field>
              <name>DATPACK</name>
              <bitOffset>14</bitOffset>
              <bitWidth>2</bitWidth>
            </field>
            <field>
              <name>CKOUTDIV</name>
              <bitOffset>16</bitOffset>
              <bitWidth>8</bitWidth>
            </field>
            <field>
              <name>CKOUTSRC</name>
              <bitOffset>30</bitOffset>
              <bitWidth>1</bitWidth>
            </field>
            <field>
              <name>DFSDMEN</name>
              <bitOffset>31</bitOffset>
              <bitWidth>1</bitWidth>
            </field>
          </fields>
        </register>
        <register>
          <name>CHCFGR22</name>
          <addressOffset>0x44</addressOffset>
          <size>0x20</size>
          <fields>
            <field>
              <name>DTRBS</name>
              <bitOffset>3</bitOffset>
              <bitWidth>5</bitWidth>
            </field>
            <field>
              <name>OFFSET</name>
              <bitOffset>8</bitOffset>
              <bitWidth>24</bitWidth>
            </field>
          </fields>
        </register>
        <register>
          <name>CHAWSCDR2</name>
          <addressOffset>0x48</addressOffset>
          <size>0x20</size>
          <fields>
            <field>
              <name>SCDT</name>
              <bitOffset>0</bitOffset>
              <bitWidth>8</bitWidth>
            </field>
            <field>
              <name>BKSCD</name>
              <bitOffset>12</bitOffset>
              <bitWidth>4</bitWidth>
            </field>
            <field>
              <name>AWFOSR</name>
              <bitOffset>16</bitOffset>
              <bitWidth>5</bitWidth>
            </field>
            <field>
              <name>AWFORD</name>
              <bitOffset>22</bitOffset>
              <bitWidth>2</bitWidth>
            </field>
          </fields>
        </register>
        <register>
          <name>CHWDATAR2</name>
          <addressOffset>0x4c</addressOffset>
          <size>0x20</size>
        </register>
        <register>
          <name>CHDATINR2</name>
          <addressOffset>0x50</addressOffset>
          <size>0x20</size>
          <fields>
            <field>
              <name>INDAT0</name>
              <bitOffset>0</bitOffset>
              <bitWidth>16</bitWidth>
            </field>
            <field>
              <name>INDAT1</name>
              <bitOffset>16</bitOffset>
              <bitWidth>16</bitWidth>
            </field>
          </fields>
        </register>
        <register>
          <name>CHCFGR13</name>
          <addressOffset>0x60</addressOffset>
          <size>0x20</size>
          <fields>
            <field>
              <name>SITP</name>
              <bitOffset>0</bitOffset>
              <bitWidth>2</bitWidth>
            </field>
            <field>
              <name>SPICKSEL</name>
              <bitOffset>2</bitOffset>
              <bitWidth>2</bitWidth>
            </field>
            <field>
              <name>SCDEN</name>
              <bitOffset>5</bitOffset>
              <bitWidth>1</bitWidth>
            </field>
            <field>
              <name>CKABEN</name>
              <bitOffset>6</bitOffset>
              <bitWidth>1</bitWidth>
            </field>
            <field>
              <name>CHEN</name>
              <bitOffset>7</bitOffset>
              <bitWidth>1</bitWidth>
            </field>
            <field>
              <name>CHINSEL</name>
              <bitOffset>8</bitOffset>
              <bitWidth>1</bitWidth>
            </field>
            <field>
              <name>DATMPX</name>
              <bitOffset>12</bitOffset>
              <bitWidth>2</bitWidth>
            </field>
            <field>
              <name>DATPACK</name>
              <bitOffset>14</bitOffset>
              <bitWidth>2</bitWidth>
            </field>
            <field>
              <name>CKOUTDIV</name>
              <bitOffset>16</bitOffset>
              <bitWidth>8</bitWidth>
            </field>
            <field>
              <name>CKOUTSRC</name>
              <bitOffset>30</bitOffset>
              <bitWidth>1</bitWidth>
            </field>
            <field>
              <name>DFSDMEN</name>
              <bitOffset>31</bitOffset>
              <bitWidth>1</bitWidth>
            </field>
          </fields>
        </register>
        <register>
          <name>CHCFGR23</name>
          <addressOffset>0x64</addressOffset>
          <size>0x20</size>
          <fields>
            <field>
              <name>DTRBS</name>
              <bitOffset>3</bitOffset>
              <bitWidth>5</bitWidth>
            </field>
            <field>
              <name>OFFSET</name>
              <bitOffset>8</bitOffset>
              <bitWidth>24</bitWidth>
            </field>
          </fields>
        </register>
        <register>
          <name>CHAWSCDR3</name>
          <addressOffset>0x68</addressOffset>
          <size>0x20</size>
          <fields>
            <field>
              <name>SCDT</name>
              <bitOffset>0</bitOffset>
              <bitWidth>8</bitWidth>
            </field>
            <field>
              <name>BKSCD</name>
              <bitOffset>12</bitOffset>
              <bitWidth>4</bitWidth>
            </field>
            <field>
              <name>AWFOSR</name>
              <bitOffset>16</bitOffset>
              <bitWidth>5</bitWidth>
            </field>
            <field>
              <name>AWFORD</name>
              <bitOffset>22</bitOffset>
              <bitWidth>2</bitWidth>
            </field>
          </fields>
        </register>
        <register>
          <name>CHWDATAR3</name>
          <addressOffset>0x6c</addressOffset>
          <size>0x20</size>
        </register>
        <register>
          <name>CHDATINR3</name>
          <addressOffset>0x70</addressOffset>
          <size>0x20</size>
          <fields>
            <field>
              <name>INDAT0</name>
              <bitOffset>0</bitOffset>
              <bitWidth>16</bitWidth>
            </field>
            <field>
              <name>INDAT1</name>
              <bitOffset>16</bitOffset>
              <bitWidth>16</bitWidth>
            </field>
          </fields>
        </register>
        <register>
          <name>CHCFGR14</name>
          <addressOffset>0x80</addressOffset>
          <size>0x20</size>
          <fields>
            <field>
              <name>SITP</name>
              <bitOffset>0</bitOffset>
              <bitWidth>2</bitWidth>
            </field>
            <field>
              <name>SPICKSEL</name>
              <bitOffset>2</bitOffset>
              <bitWidth>2</bitWidth>
            </field>
            <field>
              <name>SCDEN</name>
              <bitOffset>5</bitOffset>
              <bitWidth>1</bitWidth>
            </field>
            <field>
              <name>CKABEN</name>
              <bitOffset>6</bitOffset>
              <bitWidth>1</bitWidth>
            </field>
            <field>
              <name>CHEN</name>
              <bitOffset>7</bitOffset>
              <bitWidth>1</bitWidth>
            </field>
            <field>
              <name>CHINSEL</name>
              <bitOffset>8</bitOffset>
              <bitWidth>1</bitWidth>
            </field>
            <field>
              <name>DATMPX</name>
              <bitOffset>12</bitOffset>
              <bitWidth>2</bitWidth>
            </field>
            <field>
              <name>DATPACK</name>
              <bitOffset>14</bitOffset>
              <bitWidth>2</bitWidth>
            </field>
            <field>
              <name>CKOUTDIV</name>
              <bitOffset>16</bitOffset>
              <bitWidth>8</bitWidth>
            </field>
            <field>
              <name>CKOUTSRC</name>
              <bitOffset>30</bitOffset>
              <bitWidth>1</bitWidth>
            </field>
            <field>
              <name>DFSDMEN</name>
              <bitOffset>31</bitOffset>
              <bitWidth>1</bitWidth>
            </field>
          </fields>
        </register>
        <register>
          <name>CHCFGR24</name>
          <addressOffset>0x84</addressOffset>
          <size>0x20</size>
          <fields>
            <field>
              <name>DTRBS</name>
              <bitOffset>3</bitOffset>
              <bitWidth>5</bitWidth>
            </field>
            <field>
              <name>OFFSET</name>
              <bitOffset>8</bitOffset>
              <bitWidth>24</bitWidth>
            </field>
          </fields>
        </register>
        <register>
          <name>CHAWSCDR4</name>
          <addressOffset>0x88</addressOffset>
          <size>0x20</size>
          <fields>
            <field>
              <name>SCDT</name>
              <bitOffset>0</bitOffset>
              <bitWidth>8</bitWidth>
            </field>
            <field>
              <name>BKSCD</name>
              <bitOffset>12</bitOffset>
              <bitWidth>4</bitWidth>
            </field>
            <field>
              <name>AWFOSR</name>
              <bitOffset>16</bitOffset>
              <bitWidth>5</bitWidth>
            </field>
            <field>
              <name>AWFORD</name>
              <bitOffset>22</bitOffset>
              <bitWidth>2</bitWidth>
            </field>
          </fields>
        </register>
        <register>
          <name>CHWDATAR4</name>
          <addressOffset>0x8c</addressOffset>
          <size>0x20</size>
        </register>
        <register>
          <name>CHDATINR4</name>
          <addressOffset>0x90</addressOffset>
          <size>0x20</size>
          <fields>
            <field>
              <name>INDAT0</name>
              <bitOffset>0</bitOffset>
              <bitWidth>16</bitWidth>
            </field>
            <field>
              <name>INDAT1</name>
              <bitOffset>16</bitOffset>
              <bitWidth>16</bitWidth>
            </field>
          </fields>
        </register>
        <register>
          <name>CHCFGR15</name>
          <addressOffset>0xa0</addressOffset>
          <size>0x20</size>
          <fields>
            <field>
              <name>SITP</name>
              <bitOffset>0</bitOffset>
              <bitWidth>2</bitWidth>
            </field>
            <field>
              <name>SPICKSEL</name>
              <bitOffset>2</bitOffset>
              <bitWidth>2</bitWidth>
            </field>
            <field>
              <name>SCDEN</name>
              <bitOffset>5</bitOffset>
              <bitWidth>1</bitWidth>
            </field>
            <field>
              <name>CKABEN</name>
              <bitOffset>6</bitOffset>
              <bitWidth>1</bitWidth>
            </field>
            <field>
              <name>CHEN</name>
              <bitOffset>7</bitOffset>
              <bitWidth>1</bitWidth>
            </field>
            <field>
              <name>CHINSEL</name>
              <bitOffset>8</bitOffset>
              <bitWidth>1</bitWidth>
            </field>
            <field>
              <name>DATMPX</name>
              <bitOffset>12</bitOffset>
              <bitWidth>2</bitWidth>
            </field>
            <field>
              <name>DATPACK</name>
              <bitOffset>14</bitOffset>
              <bitWidth>2</bitWidth>
            </field>
            <field>
              <name>CKOUTDIV</name>
              <bitOffset>16</bitOffset>
              <bitWidth>8</bitWidth>
            </field>
            <field>
              <name>CKOUTSRC</name>
              <bitOffset>30</bitOffset>
              <bitWidth>1</bitWidth>
            </field>
            <field>
              <name>DFSDMEN</name>
              <bitOffset>31</bitOffset>
              <bitWidth>1</bitWidth>
            </field>
          </fields>
        </register>
        <register>
          <name>CHCFGR25</name>
          <addressOffset>0xa4</addressOffset>
          <size>0x20</size>
          <fields>
            <field>
              <name>DTRBS</name>
              <bitOffset>3</bitOffset>
              <bitWidth>5</bitWidth>
            </field>
            <field>
              <name>OFFSET</name>
              <bitOffset>8</bitOffset>
              <bitWidth>24</bitWidth>
            </field>
          </fields>
        </register>
        <register>
          <name>CHAWSCDR5</name>
          <addressOffset>0xa8</addressOffset>
          <size>0x20</size>
          <fields>
            <field>
              <name>SCDT</name>
              <bitOffset>0</bitOffset>
              <bitWidth>8</bitWidth>
            </field>
            <field>
              <name>BKSCD</name>
              <bitOffset>12</bitOffset>
              <bitWidth>4</bitWidth>
            </field>
            <field>
              <name>AWFOSR</name>
              <bitOffset>16</bitOffset>
              <bitWidth>5</bitWidth>
            </field>
            <field>
              <name>AWFORD</name>
              <bitOffset>22</bitOffset>
              <bitWidth>2</bitWidth>
            </field>
          </fields>
        </register>
        <register>
          <name>CHWDATAR5</name>
          <addressOffset>0xac</addressOffset>
          <size>0x20</size>
        </register>
        <register>
          <name>CHDATINR5</name>
          <addressOffset>0xb0</addressOffset>
          <size>0x20</size>
          <fields>
            <field>
              <name>INDAT0</name>
              <bitOffset>0</bitOffset>
              <bitWidth>16</bitWidth>
            </field>
            <field>
              <name>INDAT1</name>
              <bitOffset>16</bitOffset>
              <bitWidth>16</bitWidth>
            </field>
          </fields>
        </register>
        <register>
          <name>CHCFGR16</name>
          <addressOffset>0xc0</addressOffset>
          <size>0x20</size>
          <fields>
            <field>
              <name>SITP</name>
              <bitOffset>0</bitOffset>
              <bitWidth>2</bitWidth>
            </field>
            <field>
              <name>SPICKSEL</name>
              <bitOffset>2</bitOffset>
              <bitWidth>2</bitWidth>
            </field>
            <field>
              <name>SCDEN</name>
              <bitOffset>5</bitOffset>
              <bitWidth>1</bitWidth>
            </field>
            <field>
              <name>CKABEN</name>
              <bitOffset>6</bitOffset>
              <bitWidth>1</bitWidth>
            </field>
            <field>
              <name>CHEN</name>
              <bitOffset>7</bitOffset>
              <bitWidth>1</bitWidth>
            </field>
            <field>
              <name>CHINSEL</name>
              <bitOffset>8</bitOffset>
              <bitWidth>1</bitWidth>
            </field>
            <field>
              <name>DATMPX</name>
              <bitOffset>12</bitOffset>
              <bitWidth>2</bitWidth>
            </field>
            <field>
              <name>DATPACK</name>
              <bitOffset>14</bitOffset>
              <bitWidth>2</bitWidth>
            </field>
            <field>
              <name>CKOUTDIV</name>
              <bitOffset>16</bitOffset>
              <bitWidth>8</bitWidth>
            </field>
            <field>
              <name>CKOUTSRC</name>
              <bitOffset>30</bitOffset>
              <bitWidth>1</bitWidth>
            </field>
            <field>
              <name>DFSDMEN</name>
              <bitOffset>31</bitOffset>
              <bitWidth>1</bitWidth>
            </field>
          </fields>
        </register>
        <register>
          <name>CHCFGR26</name>
          <addressOffset>0xc4</addressOffset>
          <size>0x20</size>
          <fields>
            <field>
              <name>DTRBS</name>
              <bitOffset>3</bitOffset>
              <bitWidth>5</bitWidth>
            </field>
            <field>
              <name>OFFSET</name>
              <bitOffset>8</bitOffset>
              <bitWidth>24</bitWidth>
            </field>
          </fields>
        </register>
        <register>
          <name>CHAWSCDR6</name>
          <addressOffset>0xc8</addressOffset>
          <size>0x20</size>
          <fields>
            <field>
              <name>SCDT</name>
              <bitOffset>0</bitOffset>
              <bitWidth>8</bitWidth>
            </field>
            <field>
              <name>BKSCD</name>
              <bitOffset>12</bitOffset>
              <bitWidth>4</bitWidth>
            </field>
            <field>
              <name>AWFOSR</name>
              <bitOffset>16</bitOffset>
              <bitWidth>5</bitWidth>
            </field>
            <field>
              <name>AWFORD</name>
              <bitOffset>22</bitOffset>
              <bitWidth>2</bitWidth>
            </field>
          </fields>
        </register>
        <register>
          <name>CHWDATAR6</name>
          <addressOffset>0xcc</addressOffset>
          <size>0x20</size>
        </register>
        <register>
          <name>CHDATINR6</name>
          <addressOffset>0xd0</addressOffset>
          <size>0x20</size>
          <fields>
            <field>
              <name>INDAT0</name>
              <bitOffset>0</bitOffset>
              <bitWidth>16</bitWidth>
            </field>
            <field>
              <name>INDAT1</name>
              <bitOffset>16</bitOffset>
              <bitWidth>16</bitWidth>
            </field>
          </fields>
        </register>
        <register>
          <name>CHCFGR17</name>
          <addressOffset>0xe0</addressOffset>
          <size>0x20</size>
          <fields>
            <field>
              <name>SITP</name>
              <bitOffset>0</bitOffset>
              <bitWidth>2</bitWidth>
            </field>
            <field>
              <name>SPICKSEL</name>
              <bitOffset>2</bitOffset>
              <bitWidth>2</bitWidth>
            </field>
            <field>
              <name>SCDEN</name>
              <bitOffset>5</bitOffset>
              <bitWidth>1</bitWidth>
            </field>
            <field>
              <name>CKABEN</name>
              <bitOffset>6</bitOffset>
              <bitWidth>1</bitWidth>
            </field>
            <field>
              <name>CHEN</name>
              <bitOffset>7</bitOffset>
              <bitWidth>1</bitWidth>
            </field>
            <field>
              <name>CHINSEL</name>
              <bitOffset>8</bitOffset>
              <bitWidth>1</bitWidth>
            </field>
            <field>
              <name>DATMPX</name>
              <bitOffset>12</bitOffset>
              <bitWidth>2</bitWidth>
            </field>
            <field>
              <name>DATPACK</name>
              <bitOffset>14</bitOffset>
              <bitWidth>2</bitWidth>
            </field>
            <field>
              <name>CKOUTDIV</name>
              <bitOffset>16</bitOffset>
              <bitWidth>8</bitWidth>
            </field>
            <field>
              <name>CKOUTSRC</name>
              <bitOffset>30</bitOffset>
              <bitWidth>1</bitWidth>
            </field>
            <field>
              <name>DFSDMEN</name>
              <bitOffset>31</bitOffset>
              <bitWidth>1</bitWidth>
            </field>
          </fields>
        </register>
        <register>
          <name>CHCFGR27</name>
          <addressOffset>0xe4</addressOffset>
          <size>0x20</size>
          <fields>
            <field>
              <name>DTRBS</name>
              <bitOffset>3</bitOffset>
              <bitWidth>5</bitWidth>
            </field>
            <field>
              <name>OFFSET</name>
              <bitOffset>8</bitOffset>
              <bitWidth>24</bitWidth>
            </field>
          </fields>
        </register>
        <register>
          <name>CHAWSCDR7</name>
          <addressOffset>0xe8</addressOffset>
          <size>0x20</size>
          <fields>
            <field>
              <name>SCDT</name>
              <bitOffset>0</bitOffset>
              <bitWidth>8</bitWidth>
            </field>
            <field>
              <name>BKSCD</name>
              <bitOffset>12</bitOffset>
              <bitWidth>4</bitWidth>
            </field>
            <field>
              <name>AWFOSR</name>
              <bitOffset>16</bitOffset>
              <bitWidth>5</bitWidth>
            </field>
            <field>
              <name>AWFORD</name>
              <bitOffset>22</bitOffset>
              <bitWidth>2</bitWidth>
            </field>
          </fields>
        </register>
        <register>
          <name>CHWDATAR7</name>
          <addressOffset>0xec</addressOffset>
          <size>0x20</size>
        </register>
        <register>
          <name>CHDATINR7</name>
          <addressOffset>0xf0</addressOffset>
          <size>0x20</size>
          <fields>
            <field>
              <name>INDAT0</name>
              <bitOffset>0</bitOffset>
              <bitWidth>16</bitWidth>
            </field>
            <field>
              <name>INDAT1</name>
              <bitOffset>16</bitOffset>
              <bitWidth>16</bitWidth>
            </field>
          </fields>
        </register>
        <register>
          <name>CHCFGR10</name>
          <addressOffset>0x100</addressOffset>
          <size>0x20</size>
          <fields>
            <field>
              <name>SITP</name>
              <bitOffset>0</bitOffset>
              <bitWidth>2</bitWidth>
            </field>
            <field>
              <name>SPICKSEL</name>
              <bitOffset>2</bitOffset>
              <bitWidth>2</bitWidth>
            </field>
            <field>
              <name>SCDEN</name>
              <bitOffset>5</bitOffset>
              <bitWidth>1</bitWidth>
            </field>
            <field>
              <name>CKABEN</name>
              <bitOffset>6</bitOffset>
              <bitWidth>1</bitWidth>
            </field>
            <field>
              <name>CHEN</name>
              <bitOffset>7</bitOffset>
              <bitWidth>1</bitWidth>
            </field>
            <field>
              <name>CHINSEL</name>
              <bitOffset>8</bitOffset>
              <bitWidth>1</bitWidth>
            </field>
            <field>
              <name>DATMPX</name>
              <bitOffset>12</bitOffset>
              <bitWidth>2</bitWidth>
            </field>
            <field>
              <name>DATPACK</name>
              <bitOffset>14</bitOffset>
              <bitWidth>2</bitWidth>
            </field>
            <field>
              <name>CKOUTDIV</name>
              <bitOffset>16</bitOffset>
              <bitWidth>8</bitWidth>
            </field>
            <field>
              <name>CKOUTSRC</name>
              <bitOffset>30</bitOffset>
              <bitWidth>1</bitWidth>
            </field>
            <field>
              <name>DFSDMEN</name>
              <bitOffset>31</bitOffset>
              <bitWidth>1</bitWidth>
            </field>
          </fields>
        </register>
        <register>
          <name>CHCFGR20</name>
          <addressOffset>0x104</addressOffset>
          <size>0x20</size>
          <fields>
            <field>
              <name>DTRBS</name>
              <bitOffset>3</bitOffset>
              <bitWidth>5</bitWidth>
            </field>
            <field>
              <name>OFFSET</name>
              <bitOffset>8</bitOffset>
              <bitWidth>24</bitWidth>
            </field>
          </fields>
        </register>
        <register>
          <name>CHAWSCDR0</name>
          <addressOffset>0x108</addressOffset>
          <size>0x20</size>
          <fields>
            <field>
              <name>SCDT</name>
              <bitOffset>0</bitOffset>
              <bitWidth>8</bitWidth>
            </field>
            <field>
              <name>BKSCD</name>
              <bitOffset>12</bitOffset>
              <bitWidth>4</bitWidth>
            </field>
            <field>
              <name>AWFOSR</name>
              <bitOffset>16</bitOffset>
              <bitWidth>5</bitWidth>
            </field>
            <field>
              <name>AWFORD</name>
              <bitOffset>22</bitOffset>
              <bitWidth>2</bitWidth>
            </field>
          </fields>
        </register>
        <register>
          <name>CHWDATAR0</name>
          <addressOffset>0x10c</addressOffset>
          <size>0x20</size>
        </register>
        <register>
          <name>CHDATINR0</name>
          <addressOffset>0x110</addressOffset>
          <size>0x20</size>
          <fields>
            <field>
              <name>INDAT0</name>
              <bitOffset>0</bitOffset>
              <bitWidth>16</bitWidth>
            </field>
            <field>
              <name>INDAT1</name>
              <bitOffset>16</bitOffset>
              <bitWidth>16</bitWidth>
            </field>
          </fields>
        </register>
        <register>
          <name>CHCFGR11</name>
          <addressOffset>0x180</addressOffset>
          <size>0x20</size>
          <fields>
            <field>
              <name>SITP</name>
              <bitOffset>0</bitOffset>
              <bitWidth>2</bitWidth>
            </field>
            <field>
              <name>SPICKSEL</name>
              <bitOffset>2</bitOffset>
              <bitWidth>2</bitWidth>
            </field>
            <field>
              <name>SCDEN</name>
              <bitOffset>5</bitOffset>
              <bitWidth>1</bitWidth>
            </field>
            <field>
              <name>CKABEN</name>
              <bitOffset>6</bitOffset>
              <bitWidth>1</bitWidth>
            </field>
            <field>
              <name>CHEN</name>
              <bitOffset>7</bitOffset>
              <bitWidth>1</bitWidth>
            </field>
            <field>
              <name>CHINSEL</name>
              <bitOffset>8</bitOffset>
              <bitWidth>1</bitWidth>
            </field>
            <field>
              <name>DATMPX</name>
              <bitOffset>12</bitOffset>
              <bitWidth>2</bitWidth>
            </field>
            <field>
              <name>DATPACK</name>
              <bitOffset>14</bitOffset>
              <bitWidth>2</bitWidth>
            </field>
            <field>
              <name>CKOUTDIV</name>
              <bitOffset>16</bitOffset>
              <bitWidth>8</bitWidth>
            </field>
            <field>
              <name>CKOUTSRC</name>
              <bitOffset>30</bitOffset>
              <bitWidth>1</bitWidth>
            </field>
            <field>
              <name>DFSDMEN</name>
              <bitOffset>31</bitOffset>
              <bitWidth>1</bitWidth>
            </field>
          </fields>
        </register>
        <register>
          <name>CHCFGR21</name>
          <addressOffset>0x184</addressOffset>
          <size>0x20</size>
          <fields>
            <field>
              <name>DTRBS</name>
              <bitOffset>3</bitOffset>
              <bitWidth>5</bitWidth>
            </field>
            <field>
              <name>OFFSET</name>
              <bitOffset>8</bitOffset>
              <bitWidth>24</bitWidth>
            </field>
          </fields>
        </register>
        <register>
          <name>CHAWSCDR1</name>
          <addressOffset>0x188</addressOffset>
          <size>0x20</size>
          <fields>
            <field>
              <name>SCDT</name>
              <bitOffset>0</bitOffset>
              <bitWidth>8</bitWidth>
            </field>
            <field>
              <name>BKSCD</name>
              <bitOffset>12</bitOffset>
              <bitWidth>4</bitWidth>
            </field>
            <field>
              <name>AWFOSR</name>
              <bitOffset>16</bitOffset>
              <bitWidth>5</bitWidth>
            </field>
            <field>
              <name>AWFORD</name>
              <bitOffset>22</bitOffset>
              <bitWidth>2</bitWidth>
            </field>
          </fields>
        </register>
        <register>
          <name>CHWDATAR1</name>
          <addressOffset>0x18c</addressOffset>
          <size>0x20</size>
        </register>
        <register>
          <name>CHDATINR1</name>
          <addressOffset>0x190</addressOffset>
          <size>0x20</size>
          <fields>
            <field>
              <name>INDAT0</name>
              <bitOffset>0</bitOffset>
              <bitWidth>16</bitWidth>
            </field>
            <field>
              <name>INDAT1</name>
              <bitOffset>16</bitOffset>
              <bitWidth>16</bitWidth>
            </field>
          </fields>
        </register>
        <register>
          <name>CHCFGR12</name>
          <addressOffset>0x200</addressOffset>
          <size>0x20</size>
          <fields>
            <field>
              <name>SITP</name>
              <bitOffset>0</bitOffset>
              <bitWidth>2</bitWidth>
            </field>
            <field>
              <name>SPICKSEL</name>
              <bitOffset>2</bitOffset>
              <bitWidth>2</bitWidth>
            </field>
            <field>
              <name>SCDEN</name>
              <bitOffset>5</bitOffset>
              <bitWidth>1</bitWidth>
            </field>
            <field>
              <name>CKABEN</name>
              <bitOffset>6</bitOffset>
              <bitWidth>1</bitWidth>
            </field>
            <field>
              <name>CHEN</name>
              <bitOffset>7</bitOffset>
              <bitWidth>1</bitWidth>
            </field>
            <field>
              <name>CHINSEL</name>
              <bitOffset>8</bitOffset>
              <bitWidth>1</bitWidth>
            </field>
            <field>
              <name>DATMPX</name>
              <bitOffset>12</bitOffset>
              <bitWidth>2</bitWidth>
            </field>
            <field>
              <name>DATPACK</name>
              <bitOffset>14</bitOffset>
              <bitWidth>2</bitWidth>
            </field>
            <field>
              <name>CKOUTDIV</name>
              <bitOffset>16</bitOffset>
              <bitWidth>8</bitWidth>
            </field>
            <field>
              <name>CKOUTSRC</name>
              <bitOffset>30</bitOffset>
              <bitWidth>1</bitWidth>
            </field>
            <field>
              <name>DFSDMEN</name>
              <bitOffset>31</bitOffset>
              <bitWidth>1</bitWidth>
            </field>
          </fields>
        </register>
        <register>
          <name>CHCFGR22</name>
          <addressOffset>0x204</addressOffset>
          <size>0x20</size>
          <fields>
            <field>
              <name>DTRBS</name>
              <bitOffset>3</bitOffset>
              <bitWidth>5</bitWidth>
            </field>
            <field>
              <name>OFFSET</name>
              <bitOffset>8</bitOffset>
              <bitWidth>24</bitWidth>
            </field>
          </fields>
        </register>
        <register>
          <name>CHAWSCDR2</name>
          <addressOffset>0x208</addressOffset>
          <size>0x20</size>
          <fields>
            <field>
              <name>SCDT</name>
              <bitOffset>0</bitOffset>
              <bitWidth>8</bitWidth>
            </field>
            <field>
              <name>BKSCD</name>
              <bitOffset>12</bitOffset>
              <bitWidth>4</bitWidth>
            </field>
            <field>
              <name>AWFOSR</name>
              <bitOffset>16</bitOffset>
              <bitWidth>5</bitWidth>
            </field>
            <field>
              <name>AWFORD</name>
              <bitOffset>22</bitOffset>
              <bitWidth>2</bitWidth>
            </field>
          </fields>
        </register>
        <register>
          <name>CHWDATAR2</name>
          <addressOffset>0x20c</addressOffset>
          <size>0x20</size>
        </register>
        <register>
          <name>CHDATINR2</name>
          <addressOffset>0x210</addressOffset>
          <size>0x20</size>
          <fields>
            <field>
              <name>INDAT0</name>
              <bitOffset>0</bitOffset>
              <bitWidth>16</bitWidth>
            </field>
            <field>
              <name>INDAT1</name>
              <bitOffset>16</bitOffset>
              <bitWidth>16</bitWidth>
            </field>
          </fields>
        </register>
        <register>
          <name>CHCFGR13</name>
          <addressOffset>0x280</addressOffset>
          <size>0x20</size>
          <fields>
            <field>
              <name>SITP</name>
              <bitOffset>0</bitOffset>
              <bitWidth>2</bitWidth>
            </field>
            <field>
              <name>SPICKSEL</name>
              <bitOffset>2</bitOffset>
              <bitWidth>2</bitWidth>
            </field>
            <field>
              <name>SCDEN</name>
              <bitOffset>5</bitOffset>
              <bitWidth>1</bitWidth>
            </field>
            <field>
              <name>CKABEN</name>
              <bitOffset>6</bitOffset>
              <bitWidth>1</bitWidth>
            </field>
            <field>
              <name>CHEN</name>
              <bitOffset>7</bitOffset>
              <bitWidth>1</bitWidth>
            </field>
            <field>
              <name>CHINSEL</name>
              <bitOffset>8</bitOffset>
              <bitWidth>1</bitWidth>
            </field>
            <field>
              <name>DATMPX</name>
              <bitOffset>12</bitOffset>
              <bitWidth>2</bitWidth>
            </field>
            <field>
              <name>DATPACK</name>
              <bitOffset>14</bitOffset>
              <bitWidth>2</bitWidth>
            </field>
            <field>
              <name>CKOUTDIV</name>
              <bitOffset>16</bitOffset>
              <bitWidth>8</bitWidth>
            </field>
            <field>
              <name>CKOUTSRC</name>
              <bitOffset>30</bitOffset>
              <bitWidth>1</bitWidth>
            </field>
            <field>
              <name>DFSDMEN</name>
              <bitOffset>31</bitOffset>
              <bitWidth>1</bitWidth>
            </field>
          </fields>
        </register>
        <register>
          <name>CHCFGR23</name>
          <addressOffset>0x284</addressOffset>
          <size>0x20</size>
          <fields>
            <field>
              <name>DTRBS</name>
              <bitOffset>3</bitOffset>
              <bitWidth>5</bitWidth>
            </field>
            <field>
              <name>OFFSET</name>
              <bitOffset>8</bitOffset>
              <bitWidth>24</bitWidth>
            </field>
          </fields>
        </register>
        <register>
          <name>CHAWSCDR3</name>
          <addressOffset>0x288</addressOffset>
          <size>0x20</size>
          <fields>
            <field>
              <name>SCDT</name>
              <bitOffset>0</bitOffset>
              <bitWidth>8</bitWidth>
            </field>
            <field>
              <name>BKSCD</name>
              <bitOffset>12</bitOffset>
              <bitWidth>4</bitWidth>
            </field>
            <field>
              <name>AWFOSR</name>
              <bitOffset>16</bitOffset>
              <bitWidth>5</bitWidth>
            </field>
            <field>
              <name>AWFORD</name>
              <bitOffset>22</bitOffset>
              <bitWidth>2</bitWidth>
            </field>
          </fields>
        </register>
        <register>
          <name>CHWDATAR3</name>
          <addressOffset>0x28c</addressOffset>
          <size>0x20</size>
        </register>
        <register>
          <name>CHDATINR3</name>
          <addressOffset>0x290</addressOffset>
          <size>0x20</size>
          <fields>
            <field>
              <name>INDAT0</name>
              <bitOffset>0</bitOffset>
              <bitWidth>16</bitWidth>
            </field>
            <field>
              <name>INDAT1</name>
              <bitOffset>16</bitOffset>
              <bitWidth>16</bitWidth>
            </field>
          </fields>
        </register>
      </registers>
    </peripheral>
    <peripheral>
      <name>MDIOS</name>
      <baseAddress>0x40017800</baseAddress>
      <registers>
        <register>
          <name>CR</name>
          <addressOffset>0x0</addressOffset>
          <size>0x20</size>
          <fields>
            <field>
              <name>EN</name>
              <bitOffset>0</bitOffset>
              <bitWidth>1</bitWidth>
            </field>
            <field>
              <name>WRIE</name>
              <bitOffset>1</bitOffset>
              <bitWidth>1</bitWidth>
            </field>
            <field>
              <name>RDIE</name>
              <bitOffset>2</bitOffset>
              <bitWidth>1</bitWidth>
            </field>
            <field>
              <name>EIE</name>
              <bitOffset>3</bitOffset>
              <bitWidth>1</bitWidth>
            </field>
            <field>
              <name>DPC</name>
              <bitOffset>7</bitOffset>
              <bitWidth>1</bitWidth>
            </field>
            <field>
              <name>PORT_ADDRESS</name>
              <bitOffset>8</bitOffset>
              <bitWidth>5</bitWidth>
            </field>
          </fields>
        </register>
        <register>
          <name>WRFR</name>
          <addressOffset>0x4</addressOffset>
          <size>0x20</size>
          <fields>
            <field>
              <name>WRF</name>
              <bitOffset>0</bitOffset>
              <bitWidth>32</bitWidth>
            </field>
          </fields>
        </register>
        <register>
          <name>CWRFR</name>
          <addressOffset>0x8</addressOffset>
          <size>0x20</size>
          <fields>
            <field>
              <name>CWRF</name>
              <bitOffset>0</bitOffset>
              <bitWidth>32</bitWidth>
            </field>
          </fields>
        </register>
        <register>
          <name>RDFR</name>
          <addressOffset>0xc</addressOffset>
          <size>0x20</size>
          <fields>
            <field>
              <name>RDF</name>
              <bitOffset>0</bitOffset>
              <bitWidth>32</bitWidth>
            </field>
          </fields>
        </register>
        <register>
          <name>CRDFR</name>
          <addressOffset>0x10</addressOffset>
          <size>0x20</size>
          <fields>
            <field>
              <name>CRDF</name>
              <bitOffset>0</bitOffset>
              <bitWidth>32</bitWidth>
            </field>
          </fields>
        </register>
        <register>
          <name>SR</name>
          <addressOffset>0x14</addressOffset>
          <size>0x20</size>
          <fields>
            <field>
              <name>PERF</name>
              <bitOffset>0</bitOffset>
              <bitWidth>1</bitWidth>
            </field>
            <field>
              <name>SERF</name>
              <bitOffset>1</bitOffset>
              <bitWidth>1</bitWidth>
            </field>
            <field>
              <name>TERF</name>
              <bitOffset>2</bitOffset>
              <bitWidth>1</bitWidth>
            </field>
          </fields>
        </register>
        <register>
          <name>CLRFR</name>
          <addressOffset>0x18</addressOffset>
          <size>0x20</size>
          <fields>
            <field>
              <name>CPERF</name>
              <bitOffset>0</bitOffset>
              <bitWidth>1</bitWidth>
            </field>
            <field>
              <name>CSERF</name>
              <bitOffset>1</bitOffset>
              <bitWidth>1</bitWidth>
            </field>
            <field>
              <name>CTERF</name>
              <bitOffset>2</bitOffset>
              <bitWidth>1</bitWidth>
            </field>
          </fields>
        </register>
        <register>
          <name>DINR0</name>
          <addressOffset>0x100</addressOffset>
          <size>0x20</size>
        </register>
        <register>
          <name>DINR1</name>
          <addressOffset>0x104</addressOffset>
          <size>0x20</size>
        </register>
        <register>
          <name>DINR2</name>
          <addressOffset>0x108</addressOffset>
          <size>0x20</size>
        </register>
        <register>
          <name>DINR3</name>
          <addressOffset>0x10c</addressOffset>
          <size>0x20</size>
        </register>
        <register>
          <name>DINR4</name>
          <addressOffset>0x110</addressOffset>
          <size>0x20</size>
        </register>
        <register>
          <name>DINR5</name>
          <addressOffset>0x114</addressOffset>
          <size>0x20</size>
        </register>
        <register>
          <name>DINR6</name>
          <addressOffset>0x118</addressOffset>
          <size>0x20</size>
        </register>
        <register>
          <name>DINR7</name>
          <addressOffset>0x11c</addressOffset>
          <size>0x20</size>
        </register>
        <register>
          <name>DINR8</name>
          <addressOffset>0x120</addressOffset>
          <size>0x20</size>
        </register>
        <register>
          <name>DINR9</name>
          <addressOffset>0x124</addressOffset>
          <size>0x20</size>
        </register>
        <register>
          <name>DINR10</name>
          <addressOffset>0x128</addressOffset>
          <size>0x20</size>
        </register>
        <register>
          <name>DINR11</name>
          <addressOffset>0x12c</addressOffset>
          <size>0x20</size>
        </register>
        <register>
          <name>DINR12</name>
          <addressOffset>0x130</addressOffset>
          <size>0x20</size>
        </register>
        <register>
          <name>DINR13</name>
          <addressOffset>0x134</addressOffset>
          <size>0x20</size>
        </register>
        <register>
          <name>DINR14</name>
          <addressOffset>0x138</addressOffset>
          <size>0x20</size>
        </register>
        <register>
          <name>DINR15</name>
          <addressOffset>0x13c</addressOffset>
          <size>0x20</size>
        </register>
        <register>
          <name>DINR16</name>
          <addressOffset>0x140</addressOffset>
          <size>0x20</size>
        </register>
        <register>
          <name>DINR17</name>
          <addressOffset>0x144</addressOffset>
          <size>0x20</size>
        </register>
        <register>
          <name>DINR18</name>
          <addressOffset>0x148</addressOffset>
          <size>0x20</size>
        </register>
        <register>
          <name>DINR19</name>
          <addressOffset>0x14c</addressOffset>
          <size>0x20</size>
        </register>
        <register>
          <name>DINR20</name>
          <addressOffset>0x150</addressOffset>
          <size>0x20</size>
        </register>
        <register>
          <name>DINR21</name>
          <addressOffset>0x154</addressOffset>
          <size>0x20</size>
        </register>
        <register>
          <name>DINR22</name>
          <addressOffset>0x158</addressOffset>
          <size>0x20</size>
        </register>
        <register>
          <name>DINR23</name>
          <addressOffset>0x15c</addressOffset>
          <size>0x20</size>
        </register>
        <register>
          <name>DINR24</name>
          <addressOffset>0x160</addressOffset>
          <size>0x20</size>
        </register>
        <register>
          <name>DINR25</name>
          <addressOffset>0x164</addressOffset>
          <size>0x20</size>
        </register>
        <register>
          <name>DINR26</name>
          <addressOffset>0x168</addressOffset>
          <size>0x20</size>
        </register>
        <register>
          <name>DINR27</name>
          <addressOffset>0x16c</addressOffset>
          <size>0x20</size>
        </register>
        <register>
          <name>DINR28</name>
          <addressOffset>0x170</addressOffset>
          <size>0x20</size>
        </register>
        <register>
          <name>DINR29</name>
          <addressOffset>0x174</addressOffset>
          <size>0x20</size>
        </register>
        <register>
          <name>DINR30</name>
          <addressOffset>0x178</addressOffset>
          <size>0x20</size>
        </register>
        <register>
          <name>DINR31</name>
          <addressOffset>0x17c</addressOffset>
          <size>0x20</size>
        </register>
        <register>
          <name>DOUTR0</name>
          <addressOffset>0x180</addressOffset>
          <size>0x20</size>
        </register>
        <register>
          <name>DOUTR1</name>
          <addressOffset>0x184</addressOffset>
          <size>0x20</size>
        </register>
        <register>
          <name>DOUTR2</name>
          <addressOffset>0x188</addressOffset>
          <size>0x20</size>
        </register>
        <register>
          <name>DOUTR3</name>
          <addressOffset>0x18c</addressOffset>
          <size>0x20</size>
        </register>
        <register>
          <name>DOUTR4</name>
          <addressOffset>0x190</addressOffset>
          <size>0x20</size>
        </register>
        <register>
          <name>DOUTR5</name>
          <addressOffset>0x194</addressOffset>
          <size>0x20</size>
        </register>
        <register>
          <name>DOUTR6</name>
          <addressOffset>0x198</addressOffset>
          <size>0x20</size>
        </register>
        <register>
          <name>DOUTR7</name>
          <addressOffset>0x19c</addressOffset>
          <size>0x20</size>
        </register>
        <register>
          <name>DOUTR8</name>
          <addressOffset>0x1a0</addressOffset>
          <size>0x20</size>
        </register>
        <register>
          <name>DOUTR9</name>
          <addressOffset>0x1a4</addressOffset>
          <size>0x20</size>
        </register>
        <register>
          <name>DOUTR10</name>
          <addressOffset>0x1a8</addressOffset>
          <size>0x20</size>
        </register>
        <register>
          <name>DOUTR11</name>
          <addressOffset>0x1ac</addressOffset>
          <size>0x20</size>
        </register>
        <register>
          <name>DOUTR12</name>
          <addressOffset>0x1b0</addressOffset>
          <size>0x20</size>
        </register>
        <register>
          <name>DOUTR13</name>
          <addressOffset>0x1b4</addressOffset>
          <size>0x20</size>
        </register>
        <register>
          <name>DOUTR14</name>
          <addressOffset>0x1b8</addressOffset>
          <size>0x20</size>
        </register>
        <register>
          <name>DOUTR15</name>
          <addressOffset>0x1bc</addressOffset>
          <size>0x20</size>
        </register>
        <register>
          <name>DOUTR16</name>
          <addressOffset>0x1c0</addressOffset>
          <size>0x20</size>
        </register>
        <register>
          <name>DOUTR17</name>
          <addressOffset>0x1c4</addressOffset>
          <size>0x20</size>
        </register>
        <register>
          <name>DOUTR18</name>
          <addressOffset>0x1c8</addressOffset>
          <size>0x20</size>
        </register>
        <register>
          <name>DOUTR19</name>
          <addressOffset>0x1cc</addressOffset>
          <size>0x20</size>
        </register>
        <register>
          <name>DOUTR20</name>
          <addressOffset>0x1d0</addressOffset>
          <size>0x20</size>
        </register>
        <register>
          <name>DOUTR21</name>
          <addressOffset>0x1d4</addressOffset>
          <size>0x20</size>
        </register>
        <register>
          <name>DOUTR22</name>
          <addressOffset>0x1d8</addressOffset>
          <size>0x20</size>
        </register>
        <register>
          <name>DOUTR23</name>
          <addressOffset>0x1dc</addressOffset>
          <size>0x20</size>
        </register>
        <register>
          <name>DOUTR24</name>
          <addressOffset>0x1e0</addressOffset>
          <size>0x20</size>
        </register>
        <register>
          <name>DOUTR25</name>
          <addressOffset>0x1e4</addressOffset>
          <size>0x20</size>
        </register>
        <register>
          <name>DOUTR26</name>
          <addressOffset>0x1e8</addressOffset>
          <size>0x20</size>
        </register>
        <register>
          <name>DOUTR27</name>
          <addressOffset>0x1ec</addressOffset>
          <size>0x20</size>
        </register>
        <register>
          <name>DOUTR28</name>
          <addressOffset>0x1f0</addressOffset>
          <size>0x20</size>
        </register>
        <register>
          <name>DOUTR29</name>
          <addressOffset>0x1f4</addressOffset>
          <size>0x20</size>
        </register>
        <register>
          <name>DOUTR30</name>
          <addressOffset>0x1f8</addressOffset>
          <size>0x20</size>
        </register>
        <register>
          <name>DOUTR31</name>
          <addressOffset>0x1fc</addressOffset>
          <size>0x20</size>
        </register>
      </registers>
    </peripheral>
    <peripheral>
      <name>GPIOA</name>
      <baseAddress>0x40020000</baseAddress>
      <registers>
        <register>
          <name>MODER</name>
          <addressOffset>0x0</addressOffset>
          <size>0x20</size>
          <fields>
            <field>
              <name>MODER0</name>
              <bitOffset>0</bitOffset>
              <bitWidth>2</bitWidth>
            </field>
            <field>
              <name>MODER1</name>
              <bitOffset>2</bitOffset>
              <bitWidth>2</bitWidth>
            </field>
            <field>
              <name>MODER2</name>
              <bitOffset>4</bitOffset>
              <bitWidth>2</bitWidth>
            </field>
            <field>
              <name>MODER3</name>
              <bitOffset>6</bitOffset>
              <bitWidth>2</bitWidth>
            </field>
            <field>
              <name>MODER4</name>
              <bitOffset>8</bitOffset>
              <bitWidth>2</bitWidth>
            </field>
            <field>
              <name>MODER5</name>
              <bitOffset>10</bitOffset>
              <bitWidth>2</bitWidth>
            </field>
            <field>
              <name>MODER6</name>
              <bitOffset>12</bitOffset>
              <bitWidth>2</bitWidth>
            </field>
            <field>
              <name>MODER7</name>
              <bitOffset>14</bitOffset>
              <bitWidth>2</bitWidth>
            </field>
            <field>
              <name>MODER8</name>
              <bitOffset>16</bitOffset>
              <bitWidth>2</bitWidth>
            </field>
            <field>
              <name>MODER9</name>
              <bitOffset>18</bitOffset>
              <bitWidth>2</bitWidth>
            </field>
            <field>
              <name>MODER10</name>
              <bitOffset>20</bitOffset>
              <bitWidth>2</bitWidth>
            </field>
            <field>
              <name>MODER11</name>
              <bitOffset>22</bitOffset>
              <bitWidth>2</bitWidth>
            </field>
            <field>
              <name>MODER12</name>
              <bitOffset>24</bitOffset>
              <bitWidth>2</bitWidth>
            </field>
            <field>
              <name>MODER13</name>
              <bitOffset>26</bitOffset>
              <bitWidth>2</bitWidth>
            </field>
            <field>
              <name>MODER14</name>
              <bitOffset>28</bitOffset>
              <bitWidth>2</bitWidth>
            </field>
            <field>
              <name>MODER15</name>
              <bitOffset>30</bitOffset>
              <bitWidth>2</bitWidth>
            </field>
          </fields>
        </register>
        <register>
          <name>OTYPER</name>
          <addressOffset>0x4</addressOffset>
          <size>0x20</size>
          <fields>
            <field>
              <name>OT0</name>
              <bitOffset>0</bitOffset>
              <bitWidth>1</bitWidth>
            </field>
            <field>
              <name>OT1</name>
              <bitOffset>1</bitOffset>
              <bitWidth>1</bitWidth>
            </field>
            <field>
              <name>OT2</name>
              <bitOffset>2</bitOffset>
              <bitWidth>1</bitWidth>
            </field>
            <field>
              <name>OT3</name>
              <bitOffset>3</bitOffset>
              <bitWidth>1</bitWidth>
            </field>
            <field>
              <name>OT4</name>
              <bitOffset>4</bitOffset>
              <bitWidth>1</bitWidth>
            </field>
            <field>
              <name>OT5</name>
              <bitOffset>5</bitOffset>
              <bitWidth>1</bitWidth>
            </field>
            <field>
              <name>OT6</name>
              <bitOffset>6</bitOffset>
              <bitWidth>1</bitWidth>
            </field>
            <field>
              <name>OT7</name>
              <bitOffset>7</bitOffset>
              <bitWidth>1</bitWidth>
            </field>
            <field>
              <name>OT8</name>
              <bitOffset>8</bitOffset>
              <bitWidth>1</bitWidth>
            </field>
            <field>
              <name>OT9</name>
              <bitOffset>9</bitOffset>
              <bitWidth>1</bitWidth>
            </field>
            <field>
              <name>OT10</name>
              <bitOffset>10</bitOffset>
              <bitWidth>1</bitWidth>
            </field>
            <field>
              <name>OT11</name>
              <bitOffset>11</bitOffset>
              <bitWidth>1</bitWidth>
            </field>
            <field>
              <name>OT12</name>
              <bitOffset>12</bitOffset>
              <bitWidth>1</bitWidth>
            </field>
            <field>
              <name>OT13</name>
              <bitOffset>13</bitOffset>
              <bitWidth>1</bitWidth>
            </field>
            <field>
              <name>OT14</name>
              <bitOffset>14</bitOffset>
              <bitWidth>1</bitWidth>
            </field>
            <field>
              <name>OT15</name>
              <bitOffset>15</bitOffset>
              <bitWidth>1</bitWidth>
            </field>
          </fields>
        </register>
        <register>
          <name>OSPEEDR</name>
          <addressOffset>0x8</addressOffset>
          <size>0x20</size>
          <fields>
            <field>
              <name>OSPEEDR0</name>
              <bitOffset>0</bitOffset>
              <bitWidth>2</bitWidth>
            </field>
            <field>
              <name>OSPEEDR1</name>
              <bitOffset>2</bitOffset>
              <bitWidth>2</bitWidth>
            </field>
            <field>
              <name>OSPEEDR2</name>
              <bitOffset>4</bitOffset>
              <bitWidth>2</bitWidth>
            </field>
            <field>
              <name>OSPEEDR3</name>
              <bitOffset>6</bitOffset>
              <bitWidth>2</bitWidth>
            </field>
            <field>
              <name>OSPEEDR4</name>
              <bitOffset>8</bitOffset>
              <bitWidth>2</bitWidth>
            </field>
            <field>
              <name>OSPEEDR5</name>
              <bitOffset>10</bitOffset>
              <bitWidth>2</bitWidth>
            </field>
            <field>
              <name>OSPEEDR6</name>
              <bitOffset>12</bitOffset>
              <bitWidth>2</bitWidth>
            </field>
            <field>
              <name>OSPEEDR7</name>
              <bitOffset>14</bitOffset>
              <bitWidth>2</bitWidth>
            </field>
            <field>
              <name>OSPEEDR8</name>
              <bitOffset>16</bitOffset>
              <bitWidth>2</bitWidth>
            </field>
            <field>
              <name>OSPEEDR9</name>
              <bitOffset>18</bitOffset>
              <bitWidth>2</bitWidth>
            </field>
            <field>
              <name>OSPEEDR10</name>
              <bitOffset>20</bitOffset>
              <bitWidth>2</bitWidth>
            </field>
            <field>
              <name>OSPEEDR11</name>
              <bitOffset>22</bitOffset>
              <bitWidth>2</bitWidth>
            </field>
            <field>
              <name>OSPEEDR12</name>
              <bitOffset>24</bitOffset>
              <bitWidth>2</bitWidth>
            </field>
            <field>
              <name>OSPEEDR13</name>
              <bitOffset>26</bitOffset>
              <bitWidth>2</bitWidth>
            </field>
            <field>
              <name>OSPEEDR14</name>
              <bitOffset>28</bitOffset>
              <bitWidth>2</bitWidth>
            </field>
            <field>
              <name>OSPEEDR15</name>
              <bitOffset>30</bitOffset>
              <bitWidth>2</bitWidth>
            </field>
          </fields>
        </register>
        <register>
          <name>PUPDR</name>
          <addressOffset>0xc</addressOffset>
          <size>0x20</size>
          <fields>
            <field>
              <name>PUPDR0</name>
              <bitOffset>0</bitOffset>
              <bitWidth>2</bitWidth>
            </field>
            <field>
              <name>PUPDR1</name>
              <bitOffset>2</bitOffset>
              <bitWidth>2</bitWidth>
            </field>
            <field>
              <name>PUPDR2</name>
              <bitOffset>4</bitOffset>
              <bitWidth>2</bitWidth>
            </field>
            <field>
              <name>PUPDR3</name>
              <bitOffset>6</bitOffset>
              <bitWidth>2</bitWidth>
            </field>
            <field>
              <name>PUPDR4</name>
              <bitOffset>8</bitOffset>
              <bitWidth>2</bitWidth>
            </field>
            <field>
              <name>PUPDR5</name>
              <bitOffset>10</bitOffset>
              <bitWidth>2</bitWidth>
            </field>
            <field>
              <name>PUPDR6</name>
              <bitOffset>12</bitOffset>
              <bitWidth>2</bitWidth>
            </field>
            <field>
              <name>PUPDR7</name>
              <bitOffset>14</bitOffset>
              <bitWidth>2</bitWidth>
            </field>
            <field>
              <name>PUPDR8</name>
              <bitOffset>16</bitOffset>
              <bitWidth>2</bitWidth>
            </field>
            <field>
              <name>PUPDR9</name>
              <bitOffset>18</bitOffset>
              <bitWidth>2</bitWidth>
            </field>
            <field>
              <name>PUPDR10</name>
              <bitOffset>20</bitOffset>
              <bitWidth>2</bitWidth>
            </field>
            <field>
              <name>PUPDR11</name>
              <bitOffset>22</bitOffset>
              <bitWidth>2</bitWidth>
            </field>
            <field>
              <name>PUPDR12</name>
              <bitOffset>24</bitOffset>
              <bitWidth>2</bitWidth>
            </field>
            <field>
              <name>PUPDR13</name>
              <bitOffset>26</bitOffset>
              <bitWidth>2</bitWidth>
            </field>
            <field>
              <name>PUPDR14</name>
              <bitOffset>28</bitOffset>
              <bitWidth>2</bitWidth>
            </field>
            <field>
              <name>PUPDR15</name>
              <bitOffset>30</bitOffset>
              <bitWidth>2</bitWidth>
            </field>
          </fields>
        </register>
        <register>
          <name>IDR</name>
          <addressOffset>0x10</addressOffset>
          <size>0x20</size>
          <fields>
            <field>
              <name>ID0</name>
              <bitOffset>0</bitOffset>
              <bitWidth>1</bitWidth>
            </field>
            <field>
              <name>ID1</name>
              <bitOffset>1</bitOffset>
              <bitWidth>1</bitWidth>
            </field>
            <field>
              <name>ID2</name>
              <bitOffset>2</bitOffset>
              <bitWidth>1</bitWidth>
            </field>
            <field>
              <name>ID3</name>
              <bitOffset>3</bitOffset>
              <bitWidth>1</bitWidth>
            </field>
            <field>
              <name>ID4</name>
              <bitOffset>4</bitOffset>
              <bitWidth>1</bitWidth>
            </field>
            <field>
              <name>ID5</name>
              <bitOffset>5</bitOffset>
              <bitWidth>1</bitWidth>
            </field>
            <field>
              <name>ID6</name>
              <bitOffset>6</bitOffset>
              <bitWidth>1</bitWidth>
            </field>
            <field>
              <name>ID7</name>
              <bitOffset>7</bitOffset>
              <bitWidth>1</bitWidth>
            </field>
            <field>
              <name>ID8</name>
              <bitOffset>8</bitOffset>
              <bitWidth>1</bitWidth>
            </field>
            <field>
              <name>ID9</name>
              <bitOffset>9</bitOffset>
              <bitWidth>1</bitWidth>
            </field>
            <field>
              <name>ID10</name>
              <bitOffset>10</bitOffset>
              <bitWidth>1</bitWidth>
            </field>
            <field>
              <name>ID11</name>
              <bitOffset>11</bitOffset>
              <bitWidth>1</bitWidth>
            </field>
            <field>
              <name>ID12</name>
              <bitOffset>12</bitOffset>
              <bitWidth>1</bitWidth>
            </field>
            <field>
              <name>ID13</name>
              <bitOffset>13</bitOffset>
              <bitWidth>1</bitWidth>
            </field>
            <field>
              <name>ID14</name>
              <bitOffset>14</bitOffset>
              <bitWidth>1</bitWidth>
            </field>
            <field>
              <name>ID15</name>
              <bitOffset>15</bitOffset>
              <bitWidth>1</bitWidth>
            </field>
          </fields>
        </register>
        <register>
          <name>ODR</name>
          <addressOffset>0x14</addressOffset>
          <size>0x20</size>
          <fields>
            <field>
              <name>OD0</name>
              <bitOffset>0</bitOffset>
              <bitWidth>1</bitWidth>
            </field>
            <field>
              <name>OD1</name>
              <bitOffset>1</bitOffset>
              <bitWidth>1</bitWidth>
            </field>
            <field>
              <name>OD2</name>
              <bitOffset>2</bitOffset>
              <bitWidth>1</bitWidth>
            </field>
            <field>
              <name>OD3</name>
              <bitOffset>3</bitOffset>
              <bitWidth>1</bitWidth>
            </field>
            <field>
              <name>OD4</name>
              <bitOffset>4</bitOffset>
              <bitWidth>1</bitWidth>
            </field>
            <field>
              <name>OD5</name>
              <bitOffset>5</bitOffset>
              <bitWidth>1</bitWidth>
            </field>
            <field>
              <name>OD6</name>
              <bitOffset>6</bitOffset>
              <bitWidth>1</bitWidth>
            </field>
            <field>
              <name>OD7</name>
              <bitOffset>7</bitOffset>
              <bitWidth>1</bitWidth>
            </field>
            <field>
              <name>OD8</name>
              <bitOffset>8</bitOffset>
              <bitWidth>1</bitWidth>
            </field>
            <field>
              <name>OD9</name>
              <bitOffset>9</bitOffset>
              <bitWidth>1</bitWidth>
            </field>
            <field>
              <name>OD10</name>
              <bitOffset>10</bitOffset>
              <bitWidth>1</bitWidth>
            </field>
            <field>
              <name>OD11</name>
              <bitOffset>11</bitOffset>
              <bitWidth>1</bitWidth>
            </field>
            <field>
              <name>OD12</name>
              <bitOffset>12</bitOffset>
              <bitWidth>1</bitWidth>
            </field>
            <field>
              <name>OD13</name>
              <bitOffset>13</bitOffset>
              <bitWidth>1</bitWidth>
            </field>
            <field>
              <name>OD14</name>
              <bitOffset>14</bitOffset>
              <bitWidth>1</bitWidth>
            </field>
            <field>
              <name>OD15</name>
              <bitOffset>15</bitOffset>
              <bitWidth>1</bitWidth>
            </field>
          </fields>
        </register>
        <register>
          <name>BSRR</name>
          <addressOffset>0x18</addressOffset>
          <size>0x20</size>
          <fields>
            <field>
              <name>BS0</name>
              <bitOffset>0</bitOffset>
              <bitWidth>1</bitWidth>
            </field>
            <field>
              <name>BS1</name>
              <bitOffset>1</bitOffset>
              <bitWidth>1</bitWidth>
            </field>
            <field>
              <name>BS2</name>
              <bitOffset>2</bitOffset>
              <bitWidth>1</bitWidth>
            </field>
            <field>
              <name>BS3</name>
              <bitOffset>3</bitOffset>
              <bitWidth>1</bitWidth>
            </field>
            <field>
              <name>BS4</name>
              <bitOffset>4</bitOffset>
              <bitWidth>1</bitWidth>
            </field>
            <field>
              <name>BS5</name>
              <bitOffset>5</bitOffset>
              <bitWidth>1</bitWidth>
            </field>
            <field>
              <name>BS6</name>
              <bitOffset>6</bitOffset>
              <bitWidth>1</bitWidth>
            </field>
            <field>
              <name>BS7</name>
              <bitOffset>7</bitOffset>
              <bitWidth>1</bitWidth>
            </field>
            <field>
              <name>BS8</name>
              <bitOffset>8</bitOffset>
              <bitWidth>1</bitWidth>
            </field>
            <field>
              <name>BS9</name>
              <bitOffset>9</bitOffset>
              <bitWidth>1</bitWidth>
            </field>
            <field>
              <name>BS10</name>
              <bitOffset>10</bitOffset>
              <bitWidth>1</bitWidth>
            </field>
            <field>
              <name>BS11</name>
              <bitOffset>11</bitOffset>
              <bitWidth>1</bitWidth>
            </field>
            <field>
              <name>BS12</name>
              <bitOffset>12</bitOffset>
              <bitWidth>1</bitWidth>
            </field>
            <field>
              <name>BS13</name>
              <bitOffset>13</bitOffset>
              <bitWidth>1</bitWidth>
            </field>
            <field>
              <name>BS14</name>
              <bitOffset>14</bitOffset>
              <bitWidth>1</bitWidth>
            </field>
            <field>
              <name>BS15</name>
              <bitOffset>15</bitOffset>
              <bitWidth>1</bitWidth>
            </field>
            <field>
              <name>BR0</name>
              <bitOffset>16</bitOffset>
              <bitWidth>1</bitWidth>
            </field>
            <field>
              <name>BR1</name>
              <bitOffset>17</bitOffset>
              <bitWidth>1</bitWidth>
            </field>
            <field>
              <name>BR2</name>
              <bitOffset>18</bitOffset>
              <bitWidth>1</bitWidth>
            </field>
            <field>
              <name>BR3</name>
              <bitOffset>19</bitOffset>
              <bitWidth>1</bitWidth>
            </field>
            <field>
              <name>BR4</name>
              <bitOffset>20</bitOffset>
              <bitWidth>1</bitWidth>
            </field>
            <field>
              <name>BR5</name>
              <bitOffset>21</bitOffset>
              <bitWidth>1</bitWidth>
            </field>
            <field>
              <name>BR6</name>
              <bitOffset>22</bitOffset>
              <bitWidth>1</bitWidth>
            </field>
            <field>
              <name>BR7</name>
              <bitOffset>23</bitOffset>
              <bitWidth>1</bitWidth>
            </field>
            <field>
              <name>BR8</name>
              <bitOffset>24</bitOffset>
              <bitWidth>1</bitWidth>
            </field>
            <field>
              <name>BR9</name>
              <bitOffset>25</bitOffset>
              <bitWidth>1</bitWidth>
            </field>
            <field>
              <name>BR10</name>
              <bitOffset>26</bitOffset>
              <bitWidth>1</bitWidth>
            </field>
            <field>
              <name>BR11</name>
              <bitOffset>27</bitOffset>
              <bitWidth>1</bitWidth>
            </field>
            <field>
              <name>BR12</name>
              <bitOffset>28</bitOffset>
              <bitWidth>1</bitWidth>
            </field>
            <field>
              <name>BR13</name>
              <bitOffset>29</bitOffset>
              <bitWidth>1</bitWidth>
            </field>
            <field>
              <name>BR14</name>
              <bitOffset>30</bitOffset>
              <bitWidth>1</bitWidth>
            </field>
            <field>
              <name>BR15</name>
              <bitOffset>31</bitOffset>
              <bitWidth>1</bitWidth>
            </field>
          </fields>
        </register>
        <register>
          <name>LCKR</name>
          <addressOffset>0x1c</addressOffset>
          <size>0x20</size>
          <fields>
            <field>
              <name>LCK0</name>
              <bitOffset>0</bitOffset>
              <bitWidth>1</bitWidth>
            </field>
            <field>
              <name>LCK1</name>
              <bitOffset>1</bitOffset>
              <bitWidth>1</bitWidth>
            </field>
            <field>
              <name>LCK2</name>
              <bitOffset>2</bitOffset>
              <bitWidth>1</bitWidth>
            </field>
            <field>
              <name>LCK3</name>
              <bitOffset>3</bitOffset>
              <bitWidth>1</bitWidth>
            </field>
            <field>
              <name>LCK4</name>
              <bitOffset>4</bitOffset>
              <bitWidth>1</bitWidth>
            </field>
            <field>
              <name>LCK5</name>
              <bitOffset>5</bitOffset>
              <bitWidth>1</bitWidth>
            </field>
            <field>
              <name>LCK6</name>
              <bitOffset>6</bitOffset>
              <bitWidth>1</bitWidth>
            </field>
            <field>
              <name>LCK7</name>
              <bitOffset>7</bitOffset>
              <bitWidth>1</bitWidth>
            </field>
            <field>
              <name>LCK8</name>
              <bitOffset>8</bitOffset>
              <bitWidth>1</bitWidth>
            </field>
            <field>
              <name>LCK9</name>
              <bitOffset>9</bitOffset>
              <bitWidth>1</bitWidth>
            </field>
            <field>
              <name>LCK10</name>
              <bitOffset>10</bitOffset>
              <bitWidth>1</bitWidth>
            </field>
            <field>
              <name>LCK11</name>
              <bitOffset>11</bitOffset>
              <bitWidth>1</bitWidth>
            </field>
            <field>
              <name>LCK12</name>
              <bitOffset>12</bitOffset>
              <bitWidth>1</bitWidth>
            </field>
            <field>
              <name>LCK13</name>
              <bitOffset>13</bitOffset>
              <bitWidth>1</bitWidth>
            </field>
            <field>
              <name>LCK14</name>
              <bitOffset>14</bitOffset>
              <bitWidth>1</bitWidth>
            </field>
            <field>
              <name>LCK15</name>
              <bitOffset>15</bitOffset>
              <bitWidth>1</bitWidth>
            </field>
            <field>
              <name>LCKK</name>
              <bitOffset>16</bitOffset>
              <bitWidth>1</bitWidth>
            </field>
          </fields>
        </register>
        <register>
          <name>AFR.0</name>
          <addressOffset>0x20</addressOffset>
          <size>0x20</size>
          <fields>
            <field>
              <name>AFRL0</name>
              <bitOffset>0</bitOffset>
              <bitWidth>4</bitWidth>
            </field>
            <field>
              <name>AFRL1</name>
              <bitOffset>4</bitOffset>
              <bitWidth>4</bitWidth>
            </field>
            <field>
              <name>AFRL2</name>
              <bitOffset>8</bitOffset>
              <bitWidth>4</bitWidth>
            </field>
            <field>
              <name>AFRL3</name>
              <bitOffset>12</bitOffset>
              <bitWidth>4</bitWidth>
            </field>
            <field>
              <name>AFRL4</name>
              <bitOffset>16</bitOffset>
              <bitWidth>4</bitWidth>
            </field>
            <field>
              <name>AFRL5</name>
              <bitOffset>20</bitOffset>
              <bitWidth>4</bitWidth>
            </field>
            <field>
              <name>AFRL6</name>
              <bitOffset>24</bitOffset>
              <bitWidth>4</bitWidth>
            </field>
            <field>
              <name>AFRL7</name>
              <bitOffset>28</bitOffset>
              <bitWidth>4</bitWidth>
            </field>
          </fields>
        </register>
        <register>
          <name>AFR.1</name>
          <addressOffset>0x24</addressOffset>
          <size>0x20</size>
          <fields>
            <field>
              <name>AFRH0</name>
              <bitOffset>0</bitOffset>
              <bitWidth>4</bitWidth>
            </field>
            <field>
              <name>AFRH1</name>
              <bitOffset>4</bitOffset>
              <bitWidth>4</bitWidth>
            </field>
            <field>
              <name>AFRH2</name>
              <bitOffset>8</bitOffset>
              <bitWidth>4</bitWidth>
            </field>
            <field>
              <name>AFRH3</name>
              <bitOffset>12</bitOffset>
              <bitWidth>4</bitWidth>
            </field>
            <field>
              <name>AFRH4</name>
              <bitOffset>16</bitOffset>
              <bitWidth>4</bitWidth>
            </field>
            <field>
              <name>AFRH5</name>
              <bitOffset>20</bitOffset>
              <bitWidth>4</bitWidth>
            </field>
            <field>
              <name>AFRH6</name>
              <bitOffset>24</bitOffset>
              <bitWidth>4</bitWidth>
            </field>
            <field>
              <name>AFRH7</name>
              <bitOffset>28</bitOffset>
              <bitWidth>4</bitWidth>
            </field>
          </fields>
        </register>
      </registers>
    </peripheral>
    <peripheral>
      <name>GPIOB</name>
      <baseAddress>0x40020400</baseAddress>
      <registers>
        <register>
          <name>MODER</name>
          <addressOffset>0x0</addressOffset>
          <size>0x20</size>
          <fields>
            <field>
              <name>MODER0</name>
              <bitOffset>0</bitOffset>
              <bitWidth>2</bitWidth>
            </field>
            <field>
              <name>MODER1</name>
              <bitOffset>2</bitOffset>
              <bitWidth>2</bitWidth>
            </field>
            <field>
              <name>MODER2</name>
              <bitOffset>4</bitOffset>
              <bitWidth>2</bitWidth>
            </field>
            <field>
              <name>MODER3</name>
              <bitOffset>6</bitOffset>
              <bitWidth>2</bitWidth>
            </field>
            <field>
              <name>MODER4</name>
              <bitOffset>8</bitOffset>
              <bitWidth>2</bitWidth>
            </field>
            <field>
              <name>MODER5</name>
              <bitOffset>10</bitOffset>
              <bitWidth>2</bitWidth>
            </field>
            <field>
              <name>MODER6</name>
              <bitOffset>12</bitOffset>
              <bitWidth>2</bitWidth>
            </field>
            <field>
              <name>MODER7</name>
              <bitOffset>14</bitOffset>
              <bitWidth>2</bitWidth>
            </field>
            <field>
              <name>MODER8</name>
              <bitOffset>16</bitOffset>
              <bitWidth>2</bitWidth>
            </field>
            <field>
              <name>MODER9</name>
              <bitOffset>18</bitOffset>
              <bitWidth>2</bitWidth>
            </field>
            <field>
              <name>MODER10</name>
              <bitOffset>20</bitOffset>
              <bitWidth>2</bitWidth>
            </field>
            <field>
              <name>MODER11</name>
              <bitOffset>22</bitOffset>
              <bitWidth>2</bitWidth>
            </field>
            <field>
              <name>MODER12</name>
              <bitOffset>24</bitOffset>
              <bitWidth>2</bitWidth>
            </field>
            <field>
              <name>MODER13</name>
              <bitOffset>26</bitOffset>
              <bitWidth>2</bitWidth>
            </field>
            <field>
              <name>MODER14</name>
              <bitOffset>28</bitOffset>
              <bitWidth>2</bitWidth>
            </field>
            <field>
              <name>MODER15</name>
              <bitOffset>30</bitOffset>
              <bitWidth>2</bitWidth>
            </field>
          </fields>
        </register>
        <register>
          <name>OTYPER</name>
          <addressOffset>0x4</addressOffset>
          <size>0x20</size>
          <fields>
            <field>
              <name>OT0</name>
              <bitOffset>0</bitOffset>
              <bitWidth>1</bitWidth>
            </field>
            <field>
              <name>OT1</name>
              <bitOffset>1</bitOffset>
              <bitWidth>1</bitWidth>
            </field>
            <field>
              <name>OT2</name>
              <bitOffset>2</bitOffset>
              <bitWidth>1</bitWidth>
            </field>
            <field>
              <name>OT3</name>
              <bitOffset>3</bitOffset>
              <bitWidth>1</bitWidth>
            </field>
            <field>
              <name>OT4</name>
              <bitOffset>4</bitOffset>
              <bitWidth>1</bitWidth>
            </field>
            <field>
              <name>OT5</name>
              <bitOffset>5</bitOffset>
              <bitWidth>1</bitWidth>
            </field>
            <field>
              <name>OT6</name>
              <bitOffset>6</bitOffset>
              <bitWidth>1</bitWidth>
            </field>
            <field>
              <name>OT7</name>
              <bitOffset>7</bitOffset>
              <bitWidth>1</bitWidth>
            </field>
            <field>
              <name>OT8</name>
              <bitOffset>8</bitOffset>
              <bitWidth>1</bitWidth>
            </field>
            <field>
              <name>OT9</name>
              <bitOffset>9</bitOffset>
              <bitWidth>1</bitWidth>
            </field>
            <field>
              <name>OT10</name>
              <bitOffset>10</bitOffset>
              <bitWidth>1</bitWidth>
            </field>
            <field>
              <name>OT11</name>
              <bitOffset>11</bitOffset>
              <bitWidth>1</bitWidth>
            </field>
            <field>
              <name>OT12</name>
              <bitOffset>12</bitOffset>
              <bitWidth>1</bitWidth>
            </field>
            <field>
              <name>OT13</name>
              <bitOffset>13</bitOffset>
              <bitWidth>1</bitWidth>
            </field>
            <field>
              <name>OT14</name>
              <bitOffset>14</bitOffset>
              <bitWidth>1</bitWidth>
            </field>
            <field>
              <name>OT15</name>
              <bitOffset>15</bitOffset>
              <bitWidth>1</bitWidth>
            </field>
          </fields>
        </register>
        <register>
          <name>OSPEEDR</name>
          <addressOffset>0x8</addressOffset>
          <size>0x20</size>
          <fields>
            <field>
              <name>OSPEEDR0</name>
              <bitOffset>0</bitOffset>
              <bitWidth>2</bitWidth>
            </field>
            <field>
              <name>OSPEEDR1</name>
              <bitOffset>2</bitOffset>
              <bitWidth>2</bitWidth>
            </field>
            <field>
              <name>OSPEEDR2</name>
              <bitOffset>4</bitOffset>
              <bitWidth>2</bitWidth>
            </field>
            <field>
              <name>OSPEEDR3</name>
              <bitOffset>6</bitOffset>
              <bitWidth>2</bitWidth>
            </field>
            <field>
              <name>OSPEEDR4</name>
              <bitOffset>8</bitOffset>
              <bitWidth>2</bitWidth>
            </field>
            <field>
              <name>OSPEEDR5</name>
              <bitOffset>10</bitOffset>
              <bitWidth>2</bitWidth>
            </field>
            <field>
              <name>OSPEEDR6</name>
              <bitOffset>12</bitOffset>
              <bitWidth>2</bitWidth>
            </field>
            <field>
              <name>OSPEEDR7</name>
              <bitOffset>14</bitOffset>
              <bitWidth>2</bitWidth>
            </field>
            <field>
              <name>OSPEEDR8</name>
              <bitOffset>16</bitOffset>
              <bitWidth>2</bitWidth>
            </field>
            <field>
              <name>OSPEEDR9</name>
              <bitOffset>18</bitOffset>
              <bitWidth>2</bitWidth>
            </field>
            <field>
              <name>OSPEEDR10</name>
              <bitOffset>20</bitOffset>
              <bitWidth>2</bitWidth>
            </field>
            <field>
              <name>OSPEEDR11</name>
              <bitOffset>22</bitOffset>
              <bitWidth>2</bitWidth>
            </field>
            <field>
              <name>OSPEEDR12</name>
              <bitOffset>24</bitOffset>
              <bitWidth>2</bitWidth>
            </field>
            <field>
              <name>OSPEEDR13</name>
              <bitOffset>26</bitOffset>
              <bitWidth>2</bitWidth>
            </field>
            <field>
              <name>OSPEEDR14</name>
              <bitOffset>28</bitOffset>
              <bitWidth>2</bitWidth>
            </field>
            <field>
              <name>OSPEEDR15</name>
              <bitOffset>30</bitOffset>
              <bitWidth>2</bitWidth>
            </field>
          </fields>
        </register>
        <register>
          <name>PUPDR</name>
          <addressOffset>0xc</addressOffset>
          <size>0x20</size>
          <fields>
            <field>
              <name>PUPDR0</name>
              <bitOffset>0</bitOffset>
              <bitWidth>2</bitWidth>
            </field>
            <field>
              <name>PUPDR1</name>
              <bitOffset>2</bitOffset>
              <bitWidth>2</bitWidth>
            </field>
            <field>
              <name>PUPDR2</name>
              <bitOffset>4</bitOffset>
              <bitWidth>2</bitWidth>
            </field>
            <field>
              <name>PUPDR3</name>
              <bitOffset>6</bitOffset>
              <bitWidth>2</bitWidth>
            </field>
            <field>
              <name>PUPDR4</name>
              <bitOffset>8</bitOffset>
              <bitWidth>2</bitWidth>
            </field>
            <field>
              <name>PUPDR5</name>
              <bitOffset>10</bitOffset>
              <bitWidth>2</bitWidth>
            </field>
            <field>
              <name>PUPDR6</name>
              <bitOffset>12</bitOffset>
              <bitWidth>2</bitWidth>
            </field>
            <field>
              <name>PUPDR7</name>
              <bitOffset>14</bitOffset>
              <bitWidth>2</bitWidth>
            </field>
            <field>
              <name>PUPDR8</name>
              <bitOffset>16</bitOffset>
              <bitWidth>2</bitWidth>
            </field>
            <field>
              <name>PUPDR9</name>
              <bitOffset>18</bitOffset>
              <bitWidth>2</bitWidth>
            </field>
            <field>
              <name>PUPDR10</name>
              <bitOffset>20</bitOffset>
              <bitWidth>2</bitWidth>
            </field>
            <field>
              <name>PUPDR11</name>
              <bitOffset>22</bitOffset>
              <bitWidth>2</bitWidth>
            </field>
            <field>
              <name>PUPDR12</name>
              <bitOffset>24</bitOffset>
              <bitWidth>2</bitWidth>
            </field>
            <field>
              <name>PUPDR13</name>
              <bitOffset>26</bitOffset>
              <bitWidth>2</bitWidth>
            </field>
            <field>
              <name>PUPDR14</name>
              <bitOffset>28</bitOffset>
              <bitWidth>2</bitWidth>
            </field>
            <field>
              <name>PUPDR15</name>
              <bitOffset>30</bitOffset>
              <bitWidth>2</bitWidth>
            </field>
          </fields>
        </register>
        <register>
          <name>IDR</name>
          <addressOffset>0x10</addressOffset>
          <size>0x20</size>
          <fields>
            <field>
              <name>ID0</name>
              <bitOffset>0</bitOffset>
              <bitWidth>1</bitWidth>
            </field>
            <field>
              <name>ID1</name>
              <bitOffset>1</bitOffset>
              <bitWidth>1</bitWidth>
            </field>
            <field>
              <name>ID2</name>
              <bitOffset>2</bitOffset>
              <bitWidth>1</bitWidth>
            </field>
            <field>
              <name>ID3</name>
              <bitOffset>3</bitOffset>
              <bitWidth>1</bitWidth>
            </field>
            <field>
              <name>ID4</name>
              <bitOffset>4</bitOffset>
              <bitWidth>1</bitWidth>
            </field>
            <field>
              <name>ID5</name>
              <bitOffset>5</bitOffset>
              <bitWidth>1</bitWidth>
            </field>
            <field>
              <name>ID6</name>
              <bitOffset>6</bitOffset>
              <bitWidth>1</bitWidth>
            </field>
            <field>
              <name>ID7</name>
              <bitOffset>7</bitOffset>
              <bitWidth>1</bitWidth>
            </field>
            <field>
              <name>ID8</name>
              <bitOffset>8</bitOffset>
              <bitWidth>1</bitWidth>
            </field>
            <field>
              <name>ID9</name>
              <bitOffset>9</bitOffset>
              <bitWidth>1</bitWidth>
            </field>
            <field>
              <name>ID10</name>
              <bitOffset>10</bitOffset>
              <bitWidth>1</bitWidth>
            </field>
            <field>
              <name>ID11</name>
              <bitOffset>11</bitOffset>
              <bitWidth>1</bitWidth>
            </field>
            <field>
              <name>ID12</name>
              <bitOffset>12</bitOffset>
              <bitWidth>1</bitWidth>
            </field>
            <field>
              <name>ID13</name>
              <bitOffset>13</bitOffset>
              <bitWidth>1</bitWidth>
            </field>
            <field>
              <name>ID14</name>
              <bitOffset>14</bitOffset>
              <bitWidth>1</bitWidth>
            </field>
            <field>
              <name>ID15</name>
              <bitOffset>15</bitOffset>
              <bitWidth>1</bitWidth>
            </field>
          </fields>
        </register>
        <register>
          <name>ODR</name>
          <addressOffset>0x14</addressOffset>
          <size>0x20</size>
          <fields>
            <field>
              <name>OD0</name>
              <bitOffset>0</bitOffset>
              <bitWidth>1</bitWidth>
            </field>
            <field>
              <name>OD1</name>
              <bitOffset>1</bitOffset>
              <bitWidth>1</bitWidth>
            </field>
            <field>
              <name>OD2</name>
              <bitOffset>2</bitOffset>
              <bitWidth>1</bitWidth>
            </field>
            <field>
              <name>OD3</name>
              <bitOffset>3</bitOffset>
              <bitWidth>1</bitWidth>
            </field>
            <field>
              <name>OD4</name>
              <bitOffset>4</bitOffset>
              <bitWidth>1</bitWidth>
            </field>
            <field>
              <name>OD5</name>
              <bitOffset>5</bitOffset>
              <bitWidth>1</bitWidth>
            </field>
            <field>
              <name>OD6</name>
              <bitOffset>6</bitOffset>
              <bitWidth>1</bitWidth>
            </field>
            <field>
              <name>OD7</name>
              <bitOffset>7</bitOffset>
              <bitWidth>1</bitWidth>
            </field>
            <field>
              <name>OD8</name>
              <bitOffset>8</bitOffset>
              <bitWidth>1</bitWidth>
            </field>
            <field>
              <name>OD9</name>
              <bitOffset>9</bitOffset>
              <bitWidth>1</bitWidth>
            </field>
            <field>
              <name>OD10</name>
              <bitOffset>10</bitOffset>
              <bitWidth>1</bitWidth>
            </field>
            <field>
              <name>OD11</name>
              <bitOffset>11</bitOffset>
              <bitWidth>1</bitWidth>
            </field>
            <field>
              <name>OD12</name>
              <bitOffset>12</bitOffset>
              <bitWidth>1</bitWidth>
            </field>
            <field>
              <name>OD13</name>
              <bitOffset>13</bitOffset>
              <bitWidth>1</bitWidth>
            </field>
            <field>
              <name>OD14</name>
              <bitOffset>14</bitOffset>
              <bitWidth>1</bitWidth>
            </field>
            <field>
              <name>OD15</name>
              <bitOffset>15</bitOffset>
              <bitWidth>1</bitWidth>
            </field>
          </fields>
        </register>
        <register>
          <name>BSRR</name>
          <addressOffset>0x18</addressOffset>
          <size>0x20</size>
          <fields>
            <field>
              <name>BS0</name>
              <bitOffset>0</bitOffset>
              <bitWidth>1</bitWidth>
            </field>
            <field>
              <name>BS1</name>
              <bitOffset>1</bitOffset>
              <bitWidth>1</bitWidth>
            </field>
            <field>
              <name>BS2</name>
              <bitOffset>2</bitOffset>
              <bitWidth>1</bitWidth>
            </field>
            <field>
              <name>BS3</name>
              <bitOffset>3</bitOffset>
              <bitWidth>1</bitWidth>
            </field>
            <field>
              <name>BS4</name>
              <bitOffset>4</bitOffset>
              <bitWidth>1</bitWidth>
            </field>
            <field>
              <name>BS5</name>
              <bitOffset>5</bitOffset>
              <bitWidth>1</bitWidth>
            </field>
            <field>
              <name>BS6</name>
              <bitOffset>6</bitOffset>
              <bitWidth>1</bitWidth>
            </field>
            <field>
              <name>BS7</name>
              <bitOffset>7</bitOffset>
              <bitWidth>1</bitWidth>
            </field>
            <field>
              <name>BS8</name>
              <bitOffset>8</bitOffset>
              <bitWidth>1</bitWidth>
            </field>
            <field>
              <name>BS9</name>
              <bitOffset>9</bitOffset>
              <bitWidth>1</bitWidth>
            </field>
            <field>
              <name>BS10</name>
              <bitOffset>10</bitOffset>
              <bitWidth>1</bitWidth>
            </field>
            <field>
              <name>BS11</name>
              <bitOffset>11</bitOffset>
              <bitWidth>1</bitWidth>
            </field>
            <field>
              <name>BS12</name>
              <bitOffset>12</bitOffset>
              <bitWidth>1</bitWidth>
            </field>
            <field>
              <name>BS13</name>
              <bitOffset>13</bitOffset>
              <bitWidth>1</bitWidth>
            </field>
            <field>
              <name>BS14</name>
              <bitOffset>14</bitOffset>
              <bitWidth>1</bitWidth>
            </field>
            <field>
              <name>BS15</name>
              <bitOffset>15</bitOffset>
              <bitWidth>1</bitWidth>
            </field>
            <field>
              <name>BR0</name>
              <bitOffset>16</bitOffset>
              <bitWidth>1</bitWidth>
            </field>
            <field>
              <name>BR1</name>
              <bitOffset>17</bitOffset>
              <bitWidth>1</bitWidth>
            </field>
            <field>
              <name>BR2</name>
              <bitOffset>18</bitOffset>
              <bitWidth>1</bitWidth>
            </field>
            <field>
              <name>BR3</name>
              <bitOffset>19</bitOffset>
              <bitWidth>1</bitWidth>
            </field>
            <field>
              <name>BR4</name>
              <bitOffset>20</bitOffset>
              <bitWidth>1</bitWidth>
            </field>
            <field>
              <name>BR5</name>
              <bitOffset>21</bitOffset>
              <bitWidth>1</bitWidth>
            </field>
            <field>
              <name>BR6</name>
              <bitOffset>22</bitOffset>
              <bitWidth>1</bitWidth>
            </field>
            <field>
              <name>BR7</name>
              <bitOffset>23</bitOffset>
              <bitWidth>1</bitWidth>
            </field>
            <field>
              <name>BR8</name>
              <bitOffset>24</bitOffset>
              <bitWidth>1</bitWidth>
            </field>
            <field>
              <name>BR9</name>
              <bitOffset>25</bitOffset>
              <bitWidth>1</bitWidth>
            </field>
            <field>
              <name>BR10</name>
              <bitOffset>26</bitOffset>
              <bitWidth>1</bitWidth>
            </field>
            <field>
              <name>BR11</name>
              <bitOffset>27</bitOffset>
              <bitWidth>1</bitWidth>
            </field>
            <field>
              <name>BR12</name>
              <bitOffset>28</bitOffset>
              <bitWidth>1</bitWidth>
            </field>
            <field>
              <name>BR13</name>
              <bitOffset>29</bitOffset>
              <bitWidth>1</bitWidth>
            </field>
            <field>
              <name>BR14</name>
              <bitOffset>30</bitOffset>
              <bitWidth>1</bitWidth>
            </field>
            <field>
              <name>BR15</name>
              <bitOffset>31</bitOffset>
              <bitWidth>1</bitWidth>
            </field>
          </fields>
        </register>
        <register>
          <name>LCKR</name>
          <addressOffset>0x1c</addressOffset>
          <size>0x20</size>
          <fields>
            <field>
              <name>LCK0</name>
              <bitOffset>0</bitOffset>
              <bitWidth>1</bitWidth>
            </field>
            <field>
              <name>LCK1</name>
              <bitOffset>1</bitOffset>
              <bitWidth>1</bitWidth>
            </field>
            <field>
              <name>LCK2</name>
              <bitOffset>2</bitOffset>
              <bitWidth>1</bitWidth>
            </field>
            <field>
              <name>LCK3</name>
              <bitOffset>3</bitOffset>
              <bitWidth>1</bitWidth>
            </field>
            <field>
              <name>LCK4</name>
              <bitOffset>4</bitOffset>
              <bitWidth>1</bitWidth>
            </field>
            <field>
              <name>LCK5</name>
              <bitOffset>5</bitOffset>
              <bitWidth>1</bitWidth>
            </field>
            <field>
              <name>LCK6</name>
              <bitOffset>6</bitOffset>
              <bitWidth>1</bitWidth>
            </field>
            <field>
              <name>LCK7</name>
              <bitOffset>7</bitOffset>
              <bitWidth>1</bitWidth>
            </field>
            <field>
              <name>LCK8</name>
              <bitOffset>8</bitOffset>
              <bitWidth>1</bitWidth>
            </field>
            <field>
              <name>LCK9</name>
              <bitOffset>9</bitOffset>
              <bitWidth>1</bitWidth>
            </field>
            <field>
              <name>LCK10</name>
              <bitOffset>10</bitOffset>
              <bitWidth>1</bitWidth>
            </field>
            <field>
              <name>LCK11</name>
              <bitOffset>11</bitOffset>
              <bitWidth>1</bitWidth>
            </field>
            <field>
              <name>LCK12</name>
              <bitOffset>12</bitOffset>
              <bitWidth>1</bitWidth>
            </field>
            <field>
              <name>LCK13</name>
              <bitOffset>13</bitOffset>
              <bitWidth>1</bitWidth>
            </field>
            <field>
              <name>LCK14</name>
              <bitOffset>14</bitOffset>
              <bitWidth>1</bitWidth>
            </field>
            <field>
              <name>LCK15</name>
              <bitOffset>15</bitOffset>
              <bitWidth>1</bitWidth>
            </field>
            <field>
              <name>LCKK</name>
              <bitOffset>16</bitOffset>
              <bitWidth>1</bitWidth>
            </field>
          </fields>
        </register>
        <register>
          <name>AFR.0</name>
          <addressOffset>0x20</addressOffset>
          <size>0x20</size>
          <fields>
            <field>
              <name>AFRL0</name>
              <bitOffset>0</bitOffset>
              <bitWidth>4</bitWidth>
            </field>
            <field>
              <name>AFRL1</name>
              <bitOffset>4</bitOffset>
              <bitWidth>4</bitWidth>
            </field>
            <field>
              <name>AFRL2</name>
              <bitOffset>8</bitOffset>
              <bitWidth>4</bitWidth>
            </field>
            <field>
              <name>AFRL3</name>
              <bitOffset>12</bitOffset>
              <bitWidth>4</bitWidth>
            </field>
            <field>
              <name>AFRL4</name>
              <bitOffset>16</bitOffset>
              <bitWidth>4</bitWidth>
            </field>
            <field>
              <name>AFRL5</name>
              <bitOffset>20</bitOffset>
              <bitWidth>4</bitWidth>
            </field>
            <field>
              <name>AFRL6</name>
              <bitOffset>24</bitOffset>
              <bitWidth>4</bitWidth>
            </field>
            <field>
              <name>AFRL7</name>
              <bitOffset>28</bitOffset>
              <bitWidth>4</bitWidth>
            </field>
          </fields>
        </register>
        <register>
          <name>AFR.1</name>
          <addressOffset>0x24</addressOffset>
          <size>0x20</size>
          <fields>
            <field>
              <name>AFRH0</name>
              <bitOffset>0</bitOffset>
              <bitWidth>4</bitWidth>
            </field>
            <field>
              <name>AFRH1</name>
              <bitOffset>4</bitOffset>
              <bitWidth>4</bitWidth>
            </field>
            <field>
              <name>AFRH2</name>
              <bitOffset>8</bitOffset>
              <bitWidth>4</bitWidth>
            </field>
            <field>
              <name>AFRH3</name>
              <bitOffset>12</bitOffset>
              <bitWidth>4</bitWidth>
            </field>
            <field>
              <name>AFRH4</name>
              <bitOffset>16</bitOffset>
              <bitWidth>4</bitWidth>
            </field>
            <field>
              <name>AFRH5</name>
              <bitOffset>20</bitOffset>
              <bitWidth>4</bitWidth>
            </field>
            <field>
              <name>AFRH6</name>
              <bitOffset>24</bitOffset>
              <bitWidth>4</bitWidth>
            </field>
            <field>
              <name>AFRH7</name>
              <bitOffset>28</bitOffset>
              <bitWidth>4</bitWidth>
            </field>
          </fields>
        </register>
      </registers>
    </peripheral>
    <peripheral>
      <name>GPIOC</name>
      <baseAddress>0x40020800</baseAddress>
      <registers>
        <register>
          <name>MODER</name>
          <addressOffset>0x0</addressOffset>
          <size>0x20</size>
          <fields>
            <field>
              <name>MODER0</name>
              <bitOffset>0</bitOffset>
              <bitWidth>2</bitWidth>
            </field>
            <field>
              <name>MODER1</name>
              <bitOffset>2</bitOffset>
              <bitWidth>2</bitWidth>
            </field>
            <field>
              <name>MODER2</name>
              <bitOffset>4</bitOffset>
              <bitWidth>2</bitWidth>
            </field>
            <field>
              <name>MODER3</name>
              <bitOffset>6</bitOffset>
              <bitWidth>2</bitWidth>
            </field>
            <field>
              <name>MODER4</name>
              <bitOffset>8</bitOffset>
              <bitWidth>2</bitWidth>
            </field>
            <field>
              <name>MODER5</name>
              <bitOffset>10</bitOffset>
              <bitWidth>2</bitWidth>
            </field>
            <field>
              <name>MODER6</name>
              <bitOffset>12</bitOffset>
              <bitWidth>2</bitWidth>
            </field>
            <field>
              <name>MODER7</name>
              <bitOffset>14</bitOffset>
              <bitWidth>2</bitWidth>
            </field>
            <field>
              <name>MODER8</name>
              <bitOffset>16</bitOffset>
              <bitWidth>2</bitWidth>
            </field>
            <field>
              <name>MODER9</name>
              <bitOffset>18</bitOffset>
              <bitWidth>2</bitWidth>
            </field>
            <field>
              <name>MODER10</name>
              <bitOffset>20</bitOffset>
              <bitWidth>2</bitWidth>
            </field>
            <field>
              <name>MODER11</name>
              <bitOffset>22</bitOffset>
              <bitWidth>2</bitWidth>
            </field>
            <field>
              <name>MODER12</name>
              <bitOffset>24</bitOffset>
              <bitWidth>2</bitWidth>
            </field>
            <field>
              <name>MODER13</name>
              <bitOffset>26</bitOffset>
              <bitWidth>2</bitWidth>
            </field>
            <field>
              <name>MODER14</name>
              <bitOffset>28</bitOffset>
              <bitWidth>2</bitWidth>
            </field>
            <field>
              <name>MODER15</name>
              <bitOffset>30</bitOffset>
              <bitWidth>2</bitWidth>
            </field>
          </fields>
        </register>
        <register>
          <name>OTYPER</name>
          <addressOffset>0x4</addressOffset>
          <size>0x20</size>
          <fields>
            <field>
              <name>OT0</name>
              <bitOffset>0</bitOffset>
              <bitWidth>1</bitWidth>
            </field>
            <field>
              <name>OT1</name>
              <bitOffset>1</bitOffset>
              <bitWidth>1</bitWidth>
            </field>
            <field>
              <name>OT2</name>
              <bitOffset>2</bitOffset>
              <bitWidth>1</bitWidth>
            </field>
            <field>
              <name>OT3</name>
              <bitOffset>3</bitOffset>
              <bitWidth>1</bitWidth>
            </field>
            <field>
              <name>OT4</name>
              <bitOffset>4</bitOffset>
              <bitWidth>1</bitWidth>
            </field>
            <field>
              <name>OT5</name>
              <bitOffset>5</bitOffset>
              <bitWidth>1</bitWidth>
            </field>
            <field>
              <name>OT6</name>
              <bitOffset>6</bitOffset>
              <bitWidth>1</bitWidth>
            </field>
            <field>
              <name>OT7</name>
              <bitOffset>7</bitOffset>
              <bitWidth>1</bitWidth>
            </field>
            <field>
              <name>OT8</name>
              <bitOffset>8</bitOffset>
              <bitWidth>1</bitWidth>
            </field>
            <field>
              <name>OT9</name>
              <bitOffset>9</bitOffset>
              <bitWidth>1</bitWidth>
            </field>
            <field>
              <name>OT10</name>
              <bitOffset>10</bitOffset>
              <bitWidth>1</bitWidth>
            </field>
            <field>
              <name>OT11</name>
              <bitOffset>11</bitOffset>
              <bitWidth>1</bitWidth>
            </field>
            <field>
              <name>OT12</name>
              <bitOffset>12</bitOffset>
              <bitWidth>1</bitWidth>
            </field>
            <field>
              <name>OT13</name>
              <bitOffset>13</bitOffset>
              <bitWidth>1</bitWidth>
            </field>
            <field>
              <name>OT14</name>
              <bitOffset>14</bitOffset>
              <bitWidth>1</bitWidth>
            </field>
            <field>
              <name>OT15</name>
              <bitOffset>15</bitOffset>
              <bitWidth>1</bitWidth>
            </field>
          </fields>
        </register>
        <register>
          <name>OSPEEDR</name>
          <addressOffset>0x8</addressOffset>
          <size>0x20</size>
          <fields>
            <field>
              <name>OSPEEDR0</name>
              <bitOffset>0</bitOffset>
              <bitWidth>2</bitWidth>
            </field>
            <field>
              <name>OSPEEDR1</name>
              <bitOffset>2</bitOffset>
              <bitWidth>2</bitWidth>
            </field>
            <field>
              <name>OSPEEDR2</name>
              <bitOffset>4</bitOffset>
              <bitWidth>2</bitWidth>
            </field>
            <field>
              <name>OSPEEDR3</name>
              <bitOffset>6</bitOffset>
              <bitWidth>2</bitWidth>
            </field>
            <field>
              <name>OSPEEDR4</name>
              <bitOffset>8</bitOffset>
              <bitWidth>2</bitWidth>
            </field>
            <field>
              <name>OSPEEDR5</name>
              <bitOffset>10</bitOffset>
              <bitWidth>2</bitWidth>
            </field>
            <field>
              <name>OSPEEDR6</name>
              <bitOffset>12</bitOffset>
              <bitWidth>2</bitWidth>
            </field>
            <field>
              <name>OSPEEDR7</name>
              <bitOffset>14</bitOffset>
              <bitWidth>2</bitWidth>
            </field>
            <field>
              <name>OSPEEDR8</name>
              <bitOffset>16</bitOffset>
              <bitWidth>2</bitWidth>
            </field>
            <field>
              <name>OSPEEDR9</name>
              <bitOffset>18</bitOffset>
              <bitWidth>2</bitWidth>
            </field>
            <field>
              <name>OSPEEDR10</name>
              <bitOffset>20</bitOffset>
              <bitWidth>2</bitWidth>
            </field>
            <field>
              <name>OSPEEDR11</name>
              <bitOffset>22</bitOffset>
              <bitWidth>2</bitWidth>
            </field>
            <field>
              <name>OSPEEDR12</name>
              <bitOffset>24</bitOffset>
              <bitWidth>2</bitWidth>
            </field>
            <field>
              <name>OSPEEDR13</name>
              <bitOffset>26</bitOffset>
              <bitWidth>2</bitWidth>
            </field>
            <field>
              <name>OSPEEDR14</name>
              <bitOffset>28</bitOffset>
              <bitWidth>2</bitWidth>
            </field>
            <field>
              <name>OSPEEDR15</name>
              <bitOffset>30</bitOffset>
              <bitWidth>2</bitWidth>
            </field>
          </fields>
        </register>
        <register>
          <name>PUPDR</name>
          <addressOffset>0xc</addressOffset>
          <size>0x20</size>
          <fields>
            <field>
              <name>PUPDR0</name>
              <bitOffset>0</bitOffset>
              <bitWidth>2</bitWidth>
            </field>
            <field>
              <name>PUPDR1</name>
              <bitOffset>2</bitOffset>
              <bitWidth>2</bitWidth>
            </field>
            <field>
              <name>PUPDR2</name>
              <bitOffset>4</bitOffset>
              <bitWidth>2</bitWidth>
            </field>
            <field>
              <name>PUPDR3</name>
              <bitOffset>6</bitOffset>
              <bitWidth>2</bitWidth>
            </field>
            <field>
              <name>PUPDR4</name>
              <bitOffset>8</bitOffset>
              <bitWidth>2</bitWidth>
            </field>
            <field>
              <name>PUPDR5</name>
              <bitOffset>10</bitOffset>
              <bitWidth>2</bitWidth>
            </field>
            <field>
              <name>PUPDR6</name>
              <bitOffset>12</bitOffset>
              <bitWidth>2</bitWidth>
            </field>
            <field>
              <name>PUPDR7</name>
              <bitOffset>14</bitOffset>
              <bitWidth>2</bitWidth>
            </field>
            <field>
              <name>PUPDR8</name>
              <bitOffset>16</bitOffset>
              <bitWidth>2</bitWidth>
            </field>
            <field>
              <name>PUPDR9</name>
              <bitOffset>18</bitOffset>
              <bitWidth>2</bitWidth>
            </field>
            <field>
              <name>PUPDR10</name>
              <bitOffset>20</bitOffset>
              <bitWidth>2</bitWidth>
            </field>
            <field>
              <name>PUPDR11</name>
              <bitOffset>22</bitOffset>
              <bitWidth>2</bitWidth>
            </field>
            <field>
              <name>PUPDR12</name>
              <bitOffset>24</bitOffset>
              <bitWidth>2</bitWidth>
            </field>
            <field>
              <name>PUPDR13</name>
              <bitOffset>26</bitOffset>
              <bitWidth>2</bitWidth>
            </field>
            <field>
              <name>PUPDR14</name>
              <bitOffset>28</bitOffset>
              <bitWidth>2</bitWidth>
            </field>
            <field>
              <name>PUPDR15</name>
              <bitOffset>30</bitOffset>
              <bitWidth>2</bitWidth>
            </field>
          </fields>
        </register>
        <register>
          <name>IDR</name>
          <addressOffset>0x10</addressOffset>
          <size>0x20</size>
          <fields>
            <field>
              <name>ID0</name>
              <bitOffset>0</bitOffset>
              <bitWidth>1</bitWidth>
            </field>
            <field>
              <name>ID1</name>
              <bitOffset>1</bitOffset>
              <bitWidth>1</bitWidth>
            </field>
            <field>
              <name>ID2</name>
              <bitOffset>2</bitOffset>
              <bitWidth>1</bitWidth>
            </field>
            <field>
              <name>ID3</name>
              <bitOffset>3</bitOffset>
              <bitWidth>1</bitWidth>
            </field>
            <field>
              <name>ID4</name>
              <bitOffset>4</bitOffset>
              <bitWidth>1</bitWidth>
            </field>
            <field>
              <name>ID5</name>
              <bitOffset>5</bitOffset>
              <bitWidth>1</bitWidth>
            </field>
            <field>
              <name>ID6</name>
              <bitOffset>6</bitOffset>
              <bitWidth>1</bitWidth>
            </field>
            <field>
              <name>ID7</name>
              <bitOffset>7</bitOffset>
              <bitWidth>1</bitWidth>
            </field>
            <field>
              <name>ID8</name>
              <bitOffset>8</bitOffset>
              <bitWidth>1</bitWidth>
            </field>
            <field>
              <name>ID9</name>
              <bitOffset>9</bitOffset>
              <bitWidth>1</bitWidth>
            </field>
            <field>
              <name>ID10</name>
              <bitOffset>10</bitOffset>
              <bitWidth>1</bitWidth>
            </field>
            <field>
              <name>ID11</name>
              <bitOffset>11</bitOffset>
              <bitWidth>1</bitWidth>
            </field>
            <field>
              <name>ID12</name>
              <bitOffset>12</bitOffset>
              <bitWidth>1</bitWidth>
            </field>
            <field>
              <name>ID13</name>
              <bitOffset>13</bitOffset>
              <bitWidth>1</bitWidth>
            </field>
            <field>
              <name>ID14</name>
              <bitOffset>14</bitOffset>
              <bitWidth>1</bitWidth>
            </field>
            <field>
              <name>ID15</name>
              <bitOffset>15</bitOffset>
              <bitWidth>1</bitWidth>
            </field>
          </fields>
        </register>
        <register>
          <name>ODR</name>
          <addressOffset>0x14</addressOffset>
          <size>0x20</size>
          <fields>
            <field>
              <name>OD0</name>
              <bitOffset>0</bitOffset>
              <bitWidth>1</bitWidth>
            </field>
            <field>
              <name>OD1</name>
              <bitOffset>1</bitOffset>
              <bitWidth>1</bitWidth>
            </field>
            <field>
              <name>OD2</name>
              <bitOffset>2</bitOffset>
              <bitWidth>1</bitWidth>
            </field>
            <field>
              <name>OD3</name>
              <bitOffset>3</bitOffset>
              <bitWidth>1</bitWidth>
            </field>
            <field>
              <name>OD4</name>
              <bitOffset>4</bitOffset>
              <bitWidth>1</bitWidth>
            </field>
            <field>
              <name>OD5</name>
              <bitOffset>5</bitOffset>
              <bitWidth>1</bitWidth>
            </field>
            <field>
              <name>OD6</name>
              <bitOffset>6</bitOffset>
              <bitWidth>1</bitWidth>
            </field>
            <field>
              <name>OD7</name>
              <bitOffset>7</bitOffset>
              <bitWidth>1</bitWidth>
            </field>
            <field>
              <name>OD8</name>
              <bitOffset>8</bitOffset>
              <bitWidth>1</bitWidth>
            </field>
            <field>
              <name>OD9</name>
              <bitOffset>9</bitOffset>
              <bitWidth>1</bitWidth>
            </field>
            <field>
              <name>OD10</name>
              <bitOffset>10</bitOffset>
              <bitWidth>1</bitWidth>
            </field>
            <field>
              <name>OD11</name>
              <bitOffset>11</bitOffset>
              <bitWidth>1</bitWidth>
            </field>
            <field>
              <name>OD12</name>
              <bitOffset>12</bitOffset>
              <bitWidth>1</bitWidth>
            </field>
            <field>
              <name>OD13</name>
              <bitOffset>13</bitOffset>
              <bitWidth>1</bitWidth>
            </field>
            <field>
              <name>OD14</name>
              <bitOffset>14</bitOffset>
              <bitWidth>1</bitWidth>
            </field>
            <field>
              <name>OD15</name>
              <bitOffset>15</bitOffset>
              <bitWidth>1</bitWidth>
            </field>
          </fields>
        </register>
        <register>
          <name>BSRR</name>
          <addressOffset>0x18</addressOffset>
          <size>0x20</size>
          <fields>
            <field>
              <name>BS0</name>
              <bitOffset>0</bitOffset>
              <bitWidth>1</bitWidth>
            </field>
            <field>
              <name>BS1</name>
              <bitOffset>1</bitOffset>
              <bitWidth>1</bitWidth>
            </field>
            <field>
              <name>BS2</name>
              <bitOffset>2</bitOffset>
              <bitWidth>1</bitWidth>
            </field>
            <field>
              <name>BS3</name>
              <bitOffset>3</bitOffset>
              <bitWidth>1</bitWidth>
            </field>
            <field>
              <name>BS4</name>
              <bitOffset>4</bitOffset>
              <bitWidth>1</bitWidth>
            </field>
            <field>
              <name>BS5</name>
              <bitOffset>5</bitOffset>
              <bitWidth>1</bitWidth>
            </field>
            <field>
              <name>BS6</name>
              <bitOffset>6</bitOffset>
              <bitWidth>1</bitWidth>
            </field>
            <field>
              <name>BS7</name>
              <bitOffset>7</bitOffset>
              <bitWidth>1</bitWidth>
            </field>
            <field>
              <name>BS8</name>
              <bitOffset>8</bitOffset>
              <bitWidth>1</bitWidth>
            </field>
            <field>
              <name>BS9</name>
              <bitOffset>9</bitOffset>
              <bitWidth>1</bitWidth>
            </field>
            <field>
              <name>BS10</name>
              <bitOffset>10</bitOffset>
              <bitWidth>1</bitWidth>
            </field>
            <field>
              <name>BS11</name>
              <bitOffset>11</bitOffset>
              <bitWidth>1</bitWidth>
            </field>
            <field>
              <name>BS12</name>
              <bitOffset>12</bitOffset>
              <bitWidth>1</bitWidth>
            </field>
            <field>
              <name>BS13</name>
              <bitOffset>13</bitOffset>
              <bitWidth>1</bitWidth>
            </field>
            <field>
              <name>BS14</name>
              <bitOffset>14</bitOffset>
              <bitWidth>1</bitWidth>
            </field>
            <field>
              <name>BS15</name>
              <bitOffset>15</bitOffset>
              <bitWidth>1</bitWidth>
            </field>
            <field>
              <name>BR0</name>
              <bitOffset>16</bitOffset>
              <bitWidth>1</bitWidth>
            </field>
            <field>
              <name>BR1</name>
              <bitOffset>17</bitOffset>
              <bitWidth>1</bitWidth>
            </field>
            <field>
              <name>BR2</name>
              <bitOffset>18</bitOffset>
              <bitWidth>1</bitWidth>
            </field>
            <field>
              <name>BR3</name>
              <bitOffset>19</bitOffset>
              <bitWidth>1</bitWidth>
            </field>
            <field>
              <name>BR4</name>
              <bitOffset>20</bitOffset>
              <bitWidth>1</bitWidth>
            </field>
            <field>
              <name>BR5</name>
              <bitOffset>21</bitOffset>
              <bitWidth>1</bitWidth>
            </field>
            <field>
              <name>BR6</name>
              <bitOffset>22</bitOffset>
              <bitWidth>1</bitWidth>
            </field>
            <field>
              <name>BR7</name>
              <bitOffset>23</bitOffset>
              <bitWidth>1</bitWidth>
            </field>
            <field>
              <name>BR8</name>
              <bitOffset>24</bitOffset>
              <bitWidth>1</bitWidth>
            </field>
            <field>
              <name>BR9</name>
              <bitOffset>25</bitOffset>
              <bitWidth>1</bitWidth>
            </field>
            <field>
              <name>BR10</name>
              <bitOffset>26</bitOffset>
              <bitWidth>1</bitWidth>
            </field>
            <field>
              <name>BR11</name>
              <bitOffset>27</bitOffset>
              <bitWidth>1</bitWidth>
            </field>
            <field>
              <name>BR12</name>
              <bitOffset>28</bitOffset>
              <bitWidth>1</bitWidth>
            </field>
            <field>
              <name>BR13</name>
              <bitOffset>29</bitOffset>
              <bitWidth>1</bitWidth>
            </field>
            <field>
              <name>BR14</name>
              <bitOffset>30</bitOffset>
              <bitWidth>1</bitWidth>
            </field>
            <field>
              <name>BR15</name>
              <bitOffset>31</bitOffset>
              <bitWidth>1</bitWidth>
            </field>
          </fields>
        </register>
        <register>
          <name>LCKR</name>
          <addressOffset>0x1c</addressOffset>
          <size>0x20</size>
          <fields>
            <field>
              <name>LCK0</name>
              <bitOffset>0</bitOffset>
              <bitWidth>1</bitWidth>
            </field>
            <field>
              <name>LCK1</name>
              <bitOffset>1</bitOffset>
              <bitWidth>1</bitWidth>
            </field>
            <field>
              <name>LCK2</name>
              <bitOffset>2</bitOffset>
              <bitWidth>1</bitWidth>
            </field>
            <field>
              <name>LCK3</name>
              <bitOffset>3</bitOffset>
              <bitWidth>1</bitWidth>
            </field>
            <field>
              <name>LCK4</name>
              <bitOffset>4</bitOffset>
              <bitWidth>1</bitWidth>
            </field>
            <field>
              <name>LCK5</name>
              <bitOffset>5</bitOffset>
              <bitWidth>1</bitWidth>
            </field>
            <field>
              <name>LCK6</name>
              <bitOffset>6</bitOffset>
              <bitWidth>1</bitWidth>
            </field>
            <field>
              <name>LCK7</name>
              <bitOffset>7</bitOffset>
              <bitWidth>1</bitWidth>
            </field>
            <field>
              <name>LCK8</name>
              <bitOffset>8</bitOffset>
              <bitWidth>1</bitWidth>
            </field>
            <field>
              <name>LCK9</name>
              <bitOffset>9</bitOffset>
              <bitWidth>1</bitWidth>
            </field>
            <field>
              <name>LCK10</name>
              <bitOffset>10</bitOffset>
              <bitWidth>1</bitWidth>
            </field>
            <field>
              <name>LCK11</name>
              <bitOffset>11</bitOffset>
              <bitWidth>1</bitWidth>
            </field>
            <field>
              <name>LCK12</name>
              <bitOffset>12</bitOffset>
              <bitWidth>1</bitWidth>
            </field>
            <field>
              <name>LCK13</name>
              <bitOffset>13</bitOffset>
              <bitWidth>1</bitWidth>
            </field>
            <field>
              <name>LCK14</name>
              <bitOffset>14</bitOffset>
              <bitWidth>1</bitWidth>
            </field>
            <field>
              <name>LCK15</name>
              <bitOffset>15</bitOffset>
              <bitWidth>1</bitWidth>
            </field>
            <field>
              <name>LCKK</name>
              <bitOffset>16</bitOffset>
              <bitWidth>1</bitWidth>
            </field>
          </fields>
        </register>
        <register>
          <name>AFR.0</name>
          <addressOffset>0x20</addressOffset>
          <size>0x20</size>
          <fields>
            <field>
              <name>AFRL0</name>
              <bitOffset>0</bitOffset>
              <bitWidth>4</bitWidth>
            </field>
            <field>
              <name>AFRL1</name>
              <bitOffset>4</bitOffset>
              <bitWidth>4</bitWidth>
            </field>
            <field>
              <name>AFRL2</name>
              <bitOffset>8</bitOffset>
              <bitWidth>4</bitWidth>
            </field>
            <field>
              <name>AFRL3</name>
              <bitOffset>12</bitOffset>
              <bitWidth>4</bitWidth>
            </field>
            <field>
              <name>AFRL4</name>
              <bitOffset>16</bitOffset>
              <bitWidth>4</bitWidth>
            </field>
            <field>
              <name>AFRL5</name>
              <bitOffset>20</bitOffset>
              <bitWidth>4</bitWidth>
            </field>
            <field>
              <name>AFRL6</name>
              <bitOffset>24</bitOffset>
              <bitWidth>4</bitWidth>
            </field>
            <field>
              <name>AFRL7</name>
              <bitOffset>28</bitOffset>
              <bitWidth>4</bitWidth>
            </field>
          </fields>
        </register>
        <register>
          <name>AFR.1</name>
          <addressOffset>0x24</addressOffset>
          <size>0x20</size>
          <fields>
            <field>
              <name>AFRH0</name>
              <bitOffset>0</bitOffset>
              <bitWidth>4</bitWidth>
            </field>
            <field>
              <name>AFRH1</name>
              <bitOffset>4</bitOffset>
              <bitWidth>4</bitWidth>
            </field>
            <field>
              <name>AFRH2</name>
              <bitOffset>8</bitOffset>
              <bitWidth>4</bitWidth>
            </field>
            <field>
              <name>AFRH3</name>
              <bitOffset>12</bitOffset>
              <bitWidth>4</bitWidth>
            </field>
            <field>
              <name>AFRH4</name>
              <bitOffset>16</bitOffset>
              <bitWidth>4</bitWidth>
            </field>
            <field>
              <name>AFRH5</name>
              <bitOffset>20</bitOffset>
              <bitWidth>4</bitWidth>
            </field>
            <field>
              <name>AFRH6</name>
              <bitOffset>24</bitOffset>
              <bitWidth>4</bitWidth>
            </field>
            <field>
              <name>AFRH7</name>
              <bitOffset>28</bitOffset>
              <bitWidth>4</bitWidth>
            </field>
          </fields>
        </register>
      </registers>
    </peripheral>
    <peripheral>
      <name>GPIOD</name>
      <baseAddress>0x40020c00</baseAddress>
      <registers>
        <register>
          <name>MODER</name>
          <addressOffset>0x0</addressOffset>
          <size>0x20</size>
          <fields>
            <field>
              <name>MODER0</name>
              <bitOffset>0</bitOffset>
              <bitWidth>2</bitWidth>
            </field>
            <field>
              <name>MODER1</name>
              <bitOffset>2</bitOffset>
              <bitWidth>2</bitWidth>
            </field>
            <field>
              <name>MODER2</name>
              <bitOffset>4</bitOffset>
              <bitWidth>2</bitWidth>
            </field>
            <field>
              <name>MODER3</name>
              <bitOffset>6</bitOffset>
              <bitWidth>2</bitWidth>
            </field>
            <field>
              <name>MODER4</name>
              <bitOffset>8</bitOffset>
              <bitWidth>2</bitWidth>
            </field>
            <field>
              <name>MODER5</name>
              <bitOffset>10</bitOffset>
              <bitWidth>2</bitWidth>
            </field>
            <field>
              <name>MODER6</name>
              <bitOffset>12</bitOffset>
              <bitWidth>2</bitWidth>
            </field>
            <field>
              <name>MODER7</name>
              <bitOffset>14</bitOffset>
              <bitWidth>2</bitWidth>
            </field>
            <field>
              <name>MODER8</name>
              <bitOffset>16</bitOffset>
              <bitWidth>2</bitWidth>
            </field>
            <field>
              <name>MODER9</name>
              <bitOffset>18</bitOffset>
              <bitWidth>2</bitWidth>
            </field>
            <field>
              <name>MODER10</name>
              <bitOffset>20</bitOffset>
              <bitWidth>2</bitWidth>
            </field>
            <field>
              <name>MODER11</name>
              <bitOffset>22</bitOffset>
              <bitWidth>2</bitWidth>
            </field>
            <field>
              <name>MODER12</name>
              <bitOffset>24</bitOffset>
              <bitWidth>2</bitWidth>
            </field>
            <field>
              <name>MODER13</name>
              <bitOffset>26</bitOffset>
              <bitWidth>2</bitWidth>
            </field>
            <field>
              <name>MODER14</name>
              <bitOffset>28</bitOffset>
              <bitWidth>2</bitWidth>
            </field>
            <field>
              <name>MODER15</name>
              <bitOffset>30</bitOffset>
              <bitWidth>2</bitWidth>
            </field>
          </fields>
        </register>
        <register>
          <name>OTYPER</name>
          <addressOffset>0x4</addressOffset>
          <size>0x20</size>
          <fields>
            <field>
              <name>OT0</name>
              <bitOffset>0</bitOffset>
              <bitWidth>1</bitWidth>
            </field>
            <field>
              <name>OT1</name>
              <bitOffset>1</bitOffset>
              <bitWidth>1</bitWidth>
            </field>
            <field>
              <name>OT2</name>
              <bitOffset>2</bitOffset>
              <bitWidth>1</bitWidth>
            </field>
            <field>
              <name>OT3</name>
              <bitOffset>3</bitOffset>
              <bitWidth>1</bitWidth>
            </field>
            <field>
              <name>OT4</name>
              <bitOffset>4</bitOffset>
              <bitWidth>1</bitWidth>
            </field>
            <field>
              <name>OT5</name>
              <bitOffset>5</bitOffset>
              <bitWidth>1</bitWidth>
            </field>
            <field>
              <name>OT6</name>
              <bitOffset>6</bitOffset>
              <bitWidth>1</bitWidth>
            </field>
            <field>
              <name>OT7</name>
              <bitOffset>7</bitOffset>
              <bitWidth>1</bitWidth>
            </field>
            <field>
              <name>OT8</name>
              <bitOffset>8</bitOffset>
              <bitWidth>1</bitWidth>
            </field>
            <field>
              <name>OT9</name>
              <bitOffset>9</bitOffset>
              <bitWidth>1</bitWidth>
            </field>
            <field>
              <name>OT10</name>
              <bitOffset>10</bitOffset>
              <bitWidth>1</bitWidth>
            </field>
            <field>
              <name>OT11</name>
              <bitOffset>11</bitOffset>
              <bitWidth>1</bitWidth>
            </field>
            <field>
              <name>OT12</name>
              <bitOffset>12</bitOffset>
              <bitWidth>1</bitWidth>
            </field>
            <field>
              <name>OT13</name>
              <bitOffset>13</bitOffset>
              <bitWidth>1</bitWidth>
            </field>
            <field>
              <name>OT14</name>
              <bitOffset>14</bitOffset>
              <bitWidth>1</bitWidth>
            </field>
            <field>
              <name>OT15</name>
              <bitOffset>15</bitOffset>
              <bitWidth>1</bitWidth>
            </field>
          </fields>
        </register>
        <register>
          <name>OSPEEDR</name>
          <addressOffset>0x8</addressOffset>
          <size>0x20</size>
          <fields>
            <field>
              <name>OSPEEDR0</name>
              <bitOffset>0</bitOffset>
              <bitWidth>2</bitWidth>
            </field>
            <field>
              <name>OSPEEDR1</name>
              <bitOffset>2</bitOffset>
              <bitWidth>2</bitWidth>
            </field>
            <field>
              <name>OSPEEDR2</name>
              <bitOffset>4</bitOffset>
              <bitWidth>2</bitWidth>
            </field>
            <field>
              <name>OSPEEDR3</name>
              <bitOffset>6</bitOffset>
              <bitWidth>2</bitWidth>
            </field>
            <field>
              <name>OSPEEDR4</name>
              <bitOffset>8</bitOffset>
              <bitWidth>2</bitWidth>
            </field>
            <field>
              <name>OSPEEDR5</name>
              <bitOffset>10</bitOffset>
              <bitWidth>2</bitWidth>
            </field>
            <field>
              <name>OSPEEDR6</name>
              <bitOffset>12</bitOffset>
              <bitWidth>2</bitWidth>
            </field>
            <field>
              <name>OSPEEDR7</name>
              <bitOffset>14</bitOffset>
              <bitWidth>2</bitWidth>
            </field>
            <field>
              <name>OSPEEDR8</name>
              <bitOffset>16</bitOffset>
              <bitWidth>2</bitWidth>
            </field>
            <field>
              <name>OSPEEDR9</name>
              <bitOffset>18</bitOffset>
              <bitWidth>2</bitWidth>
            </field>
            <field>
              <name>OSPEEDR10</name>
              <bitOffset>20</bitOffset>
              <bitWidth>2</bitWidth>
            </field>
            <field>
              <name>OSPEEDR11</name>
              <bitOffset>22</bitOffset>
              <bitWidth>2</bitWidth>
            </field>
            <field>
              <name>OSPEEDR12</name>
              <bitOffset>24</bitOffset>
              <bitWidth>2</bitWidth>
            </field>
            <field>
              <name>OSPEEDR13</name>
              <bitOffset>26</bitOffset>
              <bitWidth>2</bitWidth>
            </field>
            <field>
              <name>OSPEEDR14</name>
              <bitOffset>28</bitOffset>
              <bitWidth>2</bitWidth>
            </field>
            <field>
              <name>OSPEEDR15</name>
              <bitOffset>30</bitOffset>
              <bitWidth>2</bitWidth>
            </field>
          </fields>
        </register>
        <register>
          <name>PUPDR</name>
          <addressOffset>0xc</addressOffset>
          <size>0x20</size>
          <fields>
            <field>
              <name>PUPDR0</name>
              <bitOffset>0</bitOffset>
              <bitWidth>2</bitWidth>
            </field>
            <field>
              <name>PUPDR1</name>
              <bitOffset>2</bitOffset>
              <bitWidth>2</bitWidth>
            </field>
            <field>
              <name>PUPDR2</name>
              <bitOffset>4</bitOffset>
              <bitWidth>2</bitWidth>
            </field>
            <field>
              <name>PUPDR3</name>
              <bitOffset>6</bitOffset>
              <bitWidth>2</bitWidth>
            </field>
            <field>
              <name>PUPDR4</name>
              <bitOffset>8</bitOffset>
              <bitWidth>2</bitWidth>
            </field>
            <field>
              <name>PUPDR5</name>
              <bitOffset>10</bitOffset>
              <bitWidth>2</bitWidth>
            </field>
            <field>
              <name>PUPDR6</name>
              <bitOffset>12</bitOffset>
              <bitWidth>2</bitWidth>
            </field>
            <field>
              <name>PUPDR7</name>
              <bitOffset>14</bitOffset>
              <bitWidth>2</bitWidth>
            </field>
            <field>
              <name>PUPDR8</name>
              <bitOffset>16</bitOffset>
              <bitWidth>2</bitWidth>
            </field>
            <field>
              <name>PUPDR9</name>
              <bitOffset>18</bitOffset>
              <bitWidth>2</bitWidth>
            </field>
            <field>
              <name>PUPDR10</name>
              <bitOffset>20</bitOffset>
              <bitWidth>2</bitWidth>
            </field>
            <field>
              <name>PUPDR11</name>
              <bitOffset>22</bitOffset>
              <bitWidth>2</bitWidth>
            </field>
            <field>
              <name>PUPDR12</name>
              <bitOffset>24</bitOffset>
              <bitWidth>2</bitWidth>
            </field>
            <field>
              <name>PUPDR13</name>
              <bitOffset>26</bitOffset>
              <bitWidth>2</bitWidth>
            </field>
            <field>
              <name>PUPDR14</name>
              <bitOffset>28</bitOffset>
              <bitWidth>2</bitWidth>
            </field>
            <field>
              <name>PUPDR15</name>
              <bitOffset>30</bitOffset>
              <bitWidth>2</bitWidth>
            </field>
          </fields>
        </register>
        <register>
          <name>IDR</name>
          <addressOffset>0x10</addressOffset>
          <size>0x20</size>
          <fields>
            <field>
              <name>ID0</name>
              <bitOffset>0</bitOffset>
              <bitWidth>1</bitWidth>
            </field>
            <field>
              <name>ID1</name>
              <bitOffset>1</bitOffset>
              <bitWidth>1</bitWidth>
            </field>
            <field>
              <name>ID2</name>
              <bitOffset>2</bitOffset>
              <bitWidth>1</bitWidth>
            </field>
            <field>
              <name>ID3</name>
              <bitOffset>3</bitOffset>
              <bitWidth>1</bitWidth>
            </field>
            <field>
              <name>ID4</name>
              <bitOffset>4</bitOffset>
              <bitWidth>1</bitWidth>
            </field>
            <field>
              <name>ID5</name>
              <bitOffset>5</bitOffset>
              <bitWidth>1</bitWidth>
            </field>
            <field>
              <name>ID6</name>
              <bitOffset>6</bitOffset>
              <bitWidth>1</bitWidth>
            </field>
            <field>
              <name>ID7</name>
              <bitOffset>7</bitOffset>
              <bitWidth>1</bitWidth>
            </field>
            <field>
              <name>ID8</name>
              <bitOffset>8</bitOffset>
              <bitWidth>1</bitWidth>
            </field>
            <field>
              <name>ID9</name>
              <bitOffset>9</bitOffset>
              <bitWidth>1</bitWidth>
            </field>
            <field>
              <name>ID10</name>
              <bitOffset>10</bitOffset>
              <bitWidth>1</bitWidth>
            </field>
            <field>
              <name>ID11</name>
              <bitOffset>11</bitOffset>
              <bitWidth>1</bitWidth>
            </field>
            <field>
              <name>ID12</name>
              <bitOffset>12</bitOffset>
              <bitWidth>1</bitWidth>
            </field>
            <field>
              <name>ID13</name>
              <bitOffset>13</bitOffset>
              <bitWidth>1</bitWidth>
            </field>
            <field>
              <name>ID14</name>
              <bitOffset>14</bitOffset>
              <bitWidth>1</bitWidth>
            </field>
            <field>
              <name>ID15</name>
              <bitOffset>15</bitOffset>
              <bitWidth>1</bitWidth>
            </field>
          </fields>
        </register>
        <register>
          <name>ODR</name>
          <addressOffset>0x14</addressOffset>
          <size>0x20</size>
          <fields>
            <field>
              <name>OD0</name>
              <bitOffset>0</bitOffset>
              <bitWidth>1</bitWidth>
            </field>
            <field>
              <name>OD1</name>
              <bitOffset>1</bitOffset>
              <bitWidth>1</bitWidth>
            </field>
            <field>
              <name>OD2</name>
              <bitOffset>2</bitOffset>
              <bitWidth>1</bitWidth>
            </field>
            <field>
              <name>OD3</name>
              <bitOffset>3</bitOffset>
              <bitWidth>1</bitWidth>
            </field>
            <field>
              <name>OD4</name>
              <bitOffset>4</bitOffset>
              <bitWidth>1</bitWidth>
            </field>
            <field>
              <name>OD5</name>
              <bitOffset>5</bitOffset>
              <bitWidth>1</bitWidth>
            </field>
            <field>
              <name>OD6</name>
              <bitOffset>6</bitOffset>
              <bitWidth>1</bitWidth>
            </field>
            <field>
              <name>OD7</name>
              <bitOffset>7</bitOffset>
              <bitWidth>1</bitWidth>
            </field>
            <field>
              <name>OD8</name>
              <bitOffset>8</bitOffset>
              <bitWidth>1</bitWidth>
            </field>
            <field>
              <name>OD9</name>
              <bitOffset>9</bitOffset>
              <bitWidth>1</bitWidth>
            </field>
            <field>
              <name>OD10</name>
              <bitOffset>10</bitOffset>
              <bitWidth>1</bitWidth>
            </field>
            <field>
              <name>OD11</name>
              <bitOffset>11</bitOffset>
              <bitWidth>1</bitWidth>
            </field>
            <field>
              <name>OD12</name>
              <bitOffset>12</bitOffset>
              <bitWidth>1</bitWidth>
            </field>
            <field>
              <name>OD13</name>
              <bitOffset>13</bitOffset>
              <bitWidth>1</bitWidth>
            </field>
            <field>
              <name>OD14</name>
              <bitOffset>14</bitOffset>
              <bitWidth>1</bitWidth>
            </field>
            <field>
              <name>OD15</name>
              <bitOffset>15</bitOffset>
              <bitWidth>1</bitWidth>
            </field>
          </fields>
        </register>
        <register>
          <name>BSRR</name>
          <addressOffset>0x18</addressOffset>
          <size>0x20</size>
          <fields>
            <field>
              <name>BS0</name>
              <bitOffset>0</bitOffset>
              <bitWidth>1</bitWidth>
            </field>
            <field>
              <name>BS1</name>
              <bitOffset>1</bitOffset>
              <bitWidth>1</bitWidth>
            </field>
            <field>
              <name>BS2</name>
              <bitOffset>2</bitOffset>
              <bitWidth>1</bitWidth>
            </field>
            <field>
              <name>BS3</name>
              <bitOffset>3</bitOffset>
              <bitWidth>1</bitWidth>
            </field>
            <field>
              <name>BS4</name>
              <bitOffset>4</bitOffset>
              <bitWidth>1</bitWidth>
            </field>
            <field>
              <name>BS5</name>
              <bitOffset>5</bitOffset>
              <bitWidth>1</bitWidth>
            </field>
            <field>
              <name>BS6</name>
              <bitOffset>6</bitOffset>
              <bitWidth>1</bitWidth>
            </field>
            <field>
              <name>BS7</name>
              <bitOffset>7</bitOffset>
              <bitWidth>1</bitWidth>
            </field>
            <field>
              <name>BS8</name>
              <bitOffset>8</bitOffset>
              <bitWidth>1</bitWidth>
            </field>
            <field>
              <name>BS9</name>
              <bitOffset>9</bitOffset>
              <bitWidth>1</bitWidth>
            </field>
            <field>
              <name>BS10</name>
              <bitOffset>10</bitOffset>
              <bitWidth>1</bitWidth>
            </field>
            <field>
              <name>BS11</name>
              <bitOffset>11</bitOffset>
              <bitWidth>1</bitWidth>
            </field>
            <field>
              <name>BS12</name>
              <bitOffset>12</bitOffset>
              <bitWidth>1</bitWidth>
            </field>
            <field>
              <name>BS13</name>
              <bitOffset>13</bitOffset>
              <bitWidth>1</bitWidth>
            </field>
            <field>
              <name>BS14</name>
              <bitOffset>14</bitOffset>
              <bitWidth>1</bitWidth>
            </field>
            <field>
              <name>BS15</name>
              <bitOffset>15</bitOffset>
              <bitWidth>1</bitWidth>
            </field>
            <field>
              <name>BR0</name>
              <bitOffset>16</bitOffset>
              <bitWidth>1</bitWidth>
            </field>
            <field>
              <name>BR1</name>
              <bitOffset>17</bitOffset>
              <bitWidth>1</bitWidth>
            </field>
            <field>
              <name>BR2</name>
              <bitOffset>18</bitOffset>
              <bitWidth>1</bitWidth>
            </field>
            <field>
              <name>BR3</name>
              <bitOffset>19</bitOffset>
              <bitWidth>1</bitWidth>
            </field>
            <field>
              <name>BR4</name>
              <bitOffset>20</bitOffset>
              <bitWidth>1</bitWidth>
            </field>
            <field>
              <name>BR5</name>
              <bitOffset>21</bitOffset>
              <bitWidth>1</bitWidth>
            </field>
            <field>
              <name>BR6</name>
              <bitOffset>22</bitOffset>
              <bitWidth>1</bitWidth>
            </field>
            <field>
              <name>BR7</name>
              <bitOffset>23</bitOffset>
              <bitWidth>1</bitWidth>
            </field>
            <field>
              <name>BR8</name>
              <bitOffset>24</bitOffset>
              <bitWidth>1</bitWidth>
            </field>
            <field>
              <name>BR9</name>
              <bitOffset>25</bitOffset>
              <bitWidth>1</bitWidth>
            </field>
            <field>
              <name>BR10</name>
              <bitOffset>26</bitOffset>
              <bitWidth>1</bitWidth>
            </field>
            <field>
              <name>BR11</name>
              <bitOffset>27</bitOffset>
              <bitWidth>1</bitWidth>
            </field>
            <field>
              <name>BR12</name>
              <bitOffset>28</bitOffset>
              <bitWidth>1</bitWidth>
            </field>
            <field>
              <name>BR13</name>
              <bitOffset>29</bitOffset>
              <bitWidth>1</bitWidth>
            </field>
            <field>
              <name>BR14</name>
              <bitOffset>30</bitOffset>
              <bitWidth>1</bitWidth>
            </field>
            <field>
              <name>BR15</name>
              <bitOffset>31</bitOffset>
              <bitWidth>1</bitWidth>
            </field>
          </fields>
        </register>
        <register>
          <name>LCKR</name>
          <addressOffset>0x1c</addressOffset>
          <size>0x20</size>
          <fields>
            <field>
              <name>LCK0</name>
              <bitOffset>0</bitOffset>
              <bitWidth>1</bitWidth>
            </field>
            <field>
              <name>LCK1</name>
              <bitOffset>1</bitOffset>
              <bitWidth>1</bitWidth>
            </field>
            <field>
              <name>LCK2</name>
              <bitOffset>2</bitOffset>
              <bitWidth>1</bitWidth>
            </field>
            <field>
              <name>LCK3</name>
              <bitOffset>3</bitOffset>
              <bitWidth>1</bitWidth>
            </field>
            <field>
              <name>LCK4</name>
              <bitOffset>4</bitOffset>
              <bitWidth>1</bitWidth>
            </field>
            <field>
              <name>LCK5</name>
              <bitOffset>5</bitOffset>
              <bitWidth>1</bitWidth>
            </field>
            <field>
              <name>LCK6</name>
              <bitOffset>6</bitOffset>
              <bitWidth>1</bitWidth>
            </field>
            <field>
              <name>LCK7</name>
              <bitOffset>7</bitOffset>
              <bitWidth>1</bitWidth>
            </field>
            <field>
              <name>LCK8</name>
              <bitOffset>8</bitOffset>
              <bitWidth>1</bitWidth>
            </field>
            <field>
              <name>LCK9</name>
              <bitOffset>9</bitOffset>
              <bitWidth>1</bitWidth>
            </field>
            <field>
              <name>LCK10</name>
              <bitOffset>10</bitOffset>
              <bitWidth>1</bitWidth>
            </field>
            <field>
              <name>LCK11</name>
              <bitOffset>11</bitOffset>
              <bitWidth>1</bitWidth>
            </field>
            <field>
              <name>LCK12</name>
              <bitOffset>12</bitOffset>
              <bitWidth>1</bitWidth>
            </field>
            <field>
              <name>LCK13</name>
              <bitOffset>13</bitOffset>
              <bitWidth>1</bitWidth>
            </field>
            <field>
              <name>LCK14</name>
              <bitOffset>14</bitOffset>
              <bitWidth>1</bitWidth>
            </field>
            <field>
              <name>LCK15</name>
              <bitOffset>15</bitOffset>
              <bitWidth>1</bitWidth>
            </field>
            <field>
              <name>LCKK</name>
              <bitOffset>16</bitOffset>
              <bitWidth>1</bitWidth>
            </field>
          </fields>
        </register>
        <register>
          <name>AFR.0</name>
          <addressOffset>0x20</addressOffset>
          <size>0x20</size>
          <fields>
            <field>
              <name>AFRL0</name>
              <bitOffset>0</bitOffset>
              <bitWidth>4</bitWidth>
            </field>
            <field>
              <name>AFRL1</name>
              <bitOffset>4</bitOffset>
              <bitWidth>4</bitWidth>
            </field>
            <field>
              <name>AFRL2</name>
              <bitOffset>8</bitOffset>
              <bitWidth>4</bitWidth>
            </field>
            <field>
              <name>AFRL3</name>
              <bitOffset>12</bitOffset>
              <bitWidth>4</bitWidth>
            </field>
            <field>
              <name>AFRL4</name>
              <bitOffset>16</bitOffset>
              <bitWidth>4</bitWidth>
            </field>
            <field>
              <name>AFRL5</name>
              <bitOffset>20</bitOffset>
              <bitWidth>4</bitWidth>
            </field>
            <field>
              <name>AFRL6</name>
              <bitOffset>24</bitOffset>
              <bitWidth>4</bitWidth>
            </field>
            <field>
              <name>AFRL7</name>
              <bitOffset>28</bitOffset>
              <bitWidth>4</bitWidth>
            </field>
          </fields>
        </register>
        <register>
          <name>AFR.1</name>
          <addressOffset>0x24</addressOffset>
          <size>0x20</size>
          <fields>
            <field>
              <name>AFRH0</name>
              <bitOffset>0</bitOffset>
              <bitWidth>4</bitWidth>
            </field>
            <field>
              <name>AFRH1</name>
              <bitOffset>4</bitOffset>
              <bitWidth>4</bitWidth>
            </field>
            <field>
              <name>AFRH2</name>
              <bitOffset>8</bitOffset>
              <bitWidth>4</bitWidth>
            </field>
            <field>
              <name>AFRH3</name>
              <bitOffset>12</bitOffset>
              <bitWidth>4</bitWidth>
            </field>
            <field>
              <name>AFRH4</name>
              <bitOffset>16</bitOffset>
              <bitWidth>4</bitWidth>
            </field>
            <field>
              <name>AFRH5</name>
              <bitOffset>20</bitOffset>
              <bitWidth>4</bitWidth>
            </field>
            <field>
              <name>AFRH6</name>
              <bitOffset>24</bitOffset>
              <bitWidth>4</bitWidth>
            </field>
            <field>
              <name>AFRH7</name>
              <bitOffset>28</bitOffset>
              <bitWidth>4</bitWidth>
            </field>
          </fields>
        </register>
      </registers>
    </peripheral>
    <peripheral>
      <name>GPIOE</name>
      <baseAddress>0x40021000</baseAddress>
      <registers>
        <register>
          <name>MODER</name>
          <addressOffset>0x0</addressOffset>
          <size>0x20</size>
          <fields>
            <field>
              <name>MODER0</name>
              <bitOffset>0</bitOffset>
              <bitWidth>2</bitWidth>
            </field>
            <field>
              <name>MODER1</name>
              <bitOffset>2</bitOffset>
              <bitWidth>2</bitWidth>
            </field>
            <field>
              <name>MODER2</name>
              <bitOffset>4</bitOffset>
              <bitWidth>2</bitWidth>
            </field>
            <field>
              <name>MODER3</name>
              <bitOffset>6</bitOffset>
              <bitWidth>2</bitWidth>
            </field>
            <field>
              <name>MODER4</name>
              <bitOffset>8</bitOffset>
              <bitWidth>2</bitWidth>
            </field>
            <field>
              <name>MODER5</name>
              <bitOffset>10</bitOffset>
              <bitWidth>2</bitWidth>
            </field>
            <field>
              <name>MODER6</name>
              <bitOffset>12</bitOffset>
              <bitWidth>2</bitWidth>
            </field>
            <field>
              <name>MODER7</name>
              <bitOffset>14</bitOffset>
              <bitWidth>2</bitWidth>
            </field>
            <field>
              <name>MODER8</name>
              <bitOffset>16</bitOffset>
              <bitWidth>2</bitWidth>
            </field>
            <field>
              <name>MODER9</name>
              <bitOffset>18</bitOffset>
              <bitWidth>2</bitWidth>
            </field>
            <field>
              <name>MODER10</name>
              <bitOffset>20</bitOffset>
              <bitWidth>2</bitWidth>
            </field>
            <field>
              <name>MODER11</name>
              <bitOffset>22</bitOffset>
              <bitWidth>2</bitWidth>
            </field>
            <field>
              <name>MODER12</name>
              <bitOffset>24</bitOffset>
              <bitWidth>2</bitWidth>
            </field>
            <field>
              <name>MODER13</name>
              <bitOffset>26</bitOffset>
              <bitWidth>2</bitWidth>
            </field>
            <field>
              <name>MODER14</name>
              <bitOffset>28</bitOffset>
              <bitWidth>2</bitWidth>
            </field>
            <field>
              <name>MODER15</name>
              <bitOffset>30</bitOffset>
              <bitWidth>2</bitWidth>
            </field>
          </fields>
        </register>
        <register>
          <name>OTYPER</name>
          <addressOffset>0x4</addressOffset>
          <size>0x20</size>
          <fields>
            <field>
              <name>OT0</name>
              <bitOffset>0</bitOffset>
              <bitWidth>1</bitWidth>
            </field>
            <field>
              <name>OT1</name>
              <bitOffset>1</bitOffset>
              <bitWidth>1</bitWidth>
            </field>
            <field>
              <name>OT2</name>
              <bitOffset>2</bitOffset>
              <bitWidth>1</bitWidth>
            </field>
            <field>
              <name>OT3</name>
              <bitOffset>3</bitOffset>
              <bitWidth>1</bitWidth>
            </field>
            <field>
              <name>OT4</name>
              <bitOffset>4</bitOffset>
              <bitWidth>1</bitWidth>
            </field>
            <field>
              <name>OT5</name>
              <bitOffset>5</bitOffset>
              <bitWidth>1</bitWidth>
            </field>
            <field>
              <name>OT6</name>
              <bitOffset>6</bitOffset>
              <bitWidth>1</bitWidth>
            </field>
            <field>
              <name>OT7</name>
              <bitOffset>7</bitOffset>
              <bitWidth>1</bitWidth>
            </field>
            <field>
              <name>OT8</name>
              <bitOffset>8</bitOffset>
              <bitWidth>1</bitWidth>
            </field>
            <field>
              <name>OT9</name>
              <bitOffset>9</bitOffset>
              <bitWidth>1</bitWidth>
            </field>
            <field>
              <name>OT10</name>
              <bitOffset>10</bitOffset>
              <bitWidth>1</bitWidth>
            </field>
            <field>
              <name>OT11</name>
              <bitOffset>11</bitOffset>
              <bitWidth>1</bitWidth>
            </field>
            <field>
              <name>OT12</name>
              <bitOffset>12</bitOffset>
              <bitWidth>1</bitWidth>
            </field>
            <field>
              <name>OT13</name>
              <bitOffset>13</bitOffset>
              <bitWidth>1</bitWidth>
            </field>
            <field>
              <name>OT14</name>
              <bitOffset>14</bitOffset>
              <bitWidth>1</bitWidth>
            </field>
            <field>
              <name>OT15</name>
              <bitOffset>15</bitOffset>
              <bitWidth>1</bitWidth>
            </field>
          </fields>
        </register>
        <register>
          <name>OSPEEDR</name>
          <addressOffset>0x8</addressOffset>
          <size>0x20</size>
          <fields>
            <field>
              <name>OSPEEDR0</name>
              <bitOffset>0</bitOffset>
              <bitWidth>2</bitWidth>
            </field>
            <field>
              <name>OSPEEDR1</name>
              <bitOffset>2</bitOffset>
              <bitWidth>2</bitWidth>
            </field>
            <field>
              <name>OSPEEDR2</name>
              <bitOffset>4</bitOffset>
              <bitWidth>2</bitWidth>
            </field>
            <field>
              <name>OSPEEDR3</name>
              <bitOffset>6</bitOffset>
              <bitWidth>2</bitWidth>
            </field>
            <field>
              <name>OSPEEDR4</name>
              <bitOffset>8</bitOffset>
              <bitWidth>2</bitWidth>
            </field>
            <field>
              <name>OSPEEDR5</name>
              <bitOffset>10</bitOffset>
              <bitWidth>2</bitWidth>
            </field>
            <field>
              <name>OSPEEDR6</name>
              <bitOffset>12</bitOffset>
              <bitWidth>2</bitWidth>
            </field>
            <field>
              <name>OSPEEDR7</name>
              <bitOffset>14</bitOffset>
              <bitWidth>2</bitWidth>
            </field>
            <field>
              <name>OSPEEDR8</name>
              <bitOffset>16</bitOffset>
              <bitWidth>2</bitWidth>
            </field>
            <field>
              <name>OSPEEDR9</name>
              <bitOffset>18</bitOffset>
              <bitWidth>2</bitWidth>
            </field>
            <field>
              <name>OSPEEDR10</name>
              <bitOffset>20</bitOffset>
              <bitWidth>2</bitWidth>
            </field>
            <field>
              <name>OSPEEDR11</name>
              <bitOffset>22</bitOffset>
              <bitWidth>2</bitWidth>
            </field>
            <field>
              <name>OSPEEDR12</name>
              <bitOffset>24</bitOffset>
              <bitWidth>2</bitWidth>
            </field>
            <field>
              <name>OSPEEDR13</name>
              <bitOffset>26</bitOffset>
              <bitWidth>2</bitWidth>
            </field>
            <field>
              <name>OSPEEDR14</name>
              <bitOffset>28</bitOffset>
              <bitWidth>2</bitWidth>
            </field>
            <field>
              <name>OSPEEDR15</name>
              <bitOffset>30</bitOffset>
              <bitWidth>2</bitWidth>
            </field>
          </fields>
        </register>
        <register>
          <name>PUPDR</name>
          <addressOffset>0xc</addressOffset>
          <size>0x20</size>
          <fields>
            <field>
              <name>PUPDR0</name>
              <bitOffset>0</bitOffset>
              <bitWidth>2</bitWidth>
            </field>
            <field>
              <name>PUPDR1</name>
              <bitOffset>2</bitOffset>
              <bitWidth>2</bitWidth>
            </field>
            <field>
              <name>PUPDR2</name>
              <bitOffset>4</bitOffset>
              <bitWidth>2</bitWidth>
            </field>
            <field>
              <name>PUPDR3</name>
              <bitOffset>6</bitOffset>
              <bitWidth>2</bitWidth>
            </field>
            <field>
              <name>PUPDR4</name>
              <bitOffset>8</bitOffset>
              <bitWidth>2</bitWidth>
            </field>
            <field>
              <name>PUPDR5</name>
              <bitOffset>10</bitOffset>
              <bitWidth>2</bitWidth>
            </field>
            <field>
              <name>PUPDR6</name>
              <bitOffset>12</bitOffset>
              <bitWidth>2</bitWidth>
            </field>
            <field>
              <name>PUPDR7</name>
              <bitOffset>14</bitOffset>
              <bitWidth>2</bitWidth>
            </field>
            <field>
              <name>PUPDR8</name>
              <bitOffset>16</bitOffset>
              <bitWidth>2</bitWidth>
            </field>
            <field>
              <name>PUPDR9</name>
              <bitOffset>18</bitOffset>
              <bitWidth>2</bitWidth>
            </field>
            <field>
              <name>PUPDR10</name>
              <bitOffset>20</bitOffset>
              <bitWidth>2</bitWidth>
            </field>
            <field>
              <name>PUPDR11</name>
              <bitOffset>22</bitOffset>
              <bitWidth>2</bitWidth>
            </field>
            <field>
              <name>PUPDR12</name>
              <bitOffset>24</bitOffset>
              <bitWidth>2</bitWidth>
            </field>
            <field>
              <name>PUPDR13</name>
              <bitOffset>26</bitOffset>
              <bitWidth>2</bitWidth>
            </field>
            <field>
              <name>PUPDR14</name>
              <bitOffset>28</bitOffset>
              <bitWidth>2</bitWidth>
            </field>
            <field>
              <name>PUPDR15</name>
              <bitOffset>30</bitOffset>
              <bitWidth>2</bitWidth>
            </field>
          </fields>
        </register>
        <register>
          <name>IDR</name>
          <addressOffset>0x10</addressOffset>
          <size>0x20</size>
          <fields>
            <field>
              <name>ID0</name>
              <bitOffset>0</bitOffset>
              <bitWidth>1</bitWidth>
            </field>
            <field>
              <name>ID1</name>
              <bitOffset>1</bitOffset>
              <bitWidth>1</bitWidth>
            </field>
            <field>
              <name>ID2</name>
              <bitOffset>2</bitOffset>
              <bitWidth>1</bitWidth>
            </field>
            <field>
              <name>ID3</name>
              <bitOffset>3</bitOffset>
              <bitWidth>1</bitWidth>
            </field>
            <field>
              <name>ID4</name>
              <bitOffset>4</bitOffset>
              <bitWidth>1</bitWidth>
            </field>
            <field>
              <name>ID5</name>
              <bitOffset>5</bitOffset>
              <bitWidth>1</bitWidth>
            </field>
            <field>
              <name>ID6</name>
              <bitOffset>6</bitOffset>
              <bitWidth>1</bitWidth>
            </field>
            <field>
              <name>ID7</name>
              <bitOffset>7</bitOffset>
              <bitWidth>1</bitWidth>
            </field>
            <field>
              <name>ID8</name>
              <bitOffset>8</bitOffset>
              <bitWidth>1</bitWidth>
            </field>
            <field>
              <name>ID9</name>
              <bitOffset>9</bitOffset>
              <bitWidth>1</bitWidth>
            </field>
            <field>
              <name>ID10</name>
              <bitOffset>10</bitOffset>
              <bitWidth>1</bitWidth>
            </field>
            <field>
              <name>ID11</name>
              <bitOffset>11</bitOffset>
              <bitWidth>1</bitWidth>
            </field>
            <field>
              <name>ID12</name>
              <bitOffset>12</bitOffset>
              <bitWidth>1</bitWidth>
            </field>
            <field>
              <name>ID13</name>
              <bitOffset>13</bitOffset>
              <bitWidth>1</bitWidth>
            </field>
            <field>
              <name>ID14</name>
              <bitOffset>14</bitOffset>
              <bitWidth>1</bitWidth>
            </field>
            <field>
              <name>ID15</name>
              <bitOffset>15</bitOffset>
              <bitWidth>1</bitWidth>
            </field>
          </fields>
        </register>
        <register>
          <name>ODR</name>
          <addressOffset>0x14</addressOffset>
          <size>0x20</size>
          <fields>
            <field>
              <name>OD0</name>
              <bitOffset>0</bitOffset>
              <bitWidth>1</bitWidth>
            </field>
            <field>
              <name>OD1</name>
              <bitOffset>1</bitOffset>
              <bitWidth>1</bitWidth>
            </field>
            <field>
              <name>OD2</name>
              <bitOffset>2</bitOffset>
              <bitWidth>1</bitWidth>
            </field>
            <field>
              <name>OD3</name>
              <bitOffset>3</bitOffset>
              <bitWidth>1</bitWidth>
            </field>
            <field>
              <name>OD4</name>
              <bitOffset>4</bitOffset>
              <bitWidth>1</bitWidth>
            </field>
            <field>
              <name>OD5</name>
              <bitOffset>5</bitOffset>
              <bitWidth>1</bitWidth>
            </field>
            <field>
              <name>OD6</name>
              <bitOffset>6</bitOffset>
              <bitWidth>1</bitWidth>
            </field>
            <field>
              <name>OD7</name>
              <bitOffset>7</bitOffset>
              <bitWidth>1</bitWidth>
            </field>
            <field>
              <name>OD8</name>
              <bitOffset>8</bitOffset>
              <bitWidth>1</bitWidth>
            </field>
            <field>
              <name>OD9</name>
              <bitOffset>9</bitOffset>
              <bitWidth>1</bitWidth>
            </field>
            <field>
              <name>OD10</name>
              <bitOffset>10</bitOffset>
              <bitWidth>1</bitWidth>
            </field>
            <field>
              <name>OD11</name>
              <bitOffset>11</bitOffset>
              <bitWidth>1</bitWidth>
            </field>
            <field>
              <name>OD12</name>
              <bitOffset>12</bitOffset>
              <bitWidth>1</bitWidth>
            </field>
            <field>
              <name>OD13</name>
              <bitOffset>13</bitOffset>
              <bitWidth>1</bitWidth>
            </field>
            <field>
              <name>OD14</name>
              <bitOffset>14</bitOffset>
              <bitWidth>1</bitWidth>
            </field>
            <field>
              <name>OD15</name>
              <bitOffset>15</bitOffset>
              <bitWidth>1</bitWidth>
            </field>
          </fields>
        </register>
        <register>
          <name>BSRR</name>
          <addressOffset>0x18</addressOffset>
          <size>0x20</size>
          <fields>
            <field>
              <name>BS0</name>
              <bitOffset>0</bitOffset>
              <bitWidth>1</bitWidth>
            </field>
            <field>
              <name>BS1</name>
              <bitOffset>1</bitOffset>
              <bitWidth>1</bitWidth>
            </field>
            <field>
              <name>BS2</name>
              <bitOffset>2</bitOffset>
              <bitWidth>1</bitWidth>
            </field>
            <field>
              <name>BS3</name>
              <bitOffset>3</bitOffset>
              <bitWidth>1</bitWidth>
            </field>
            <field>
              <name>BS4</name>
              <bitOffset>4</bitOffset>
              <bitWidth>1</bitWidth>
            </field>
            <field>
              <name>BS5</name>
              <bitOffset>5</bitOffset>
              <bitWidth>1</bitWidth>
            </field>
            <field>
              <name>BS6</name>
              <bitOffset>6</bitOffset>
              <bitWidth>1</bitWidth>
            </field>
            <field>
              <name>BS7</name>
              <bitOffset>7</bitOffset>
              <bitWidth>1</bitWidth>
            </field>
            <field>
              <name>BS8</name>
              <bitOffset>8</bitOffset>
              <bitWidth>1</bitWidth>
            </field>
            <field>
              <name>BS9</name>
              <bitOffset>9</bitOffset>
              <bitWidth>1</bitWidth>
            </field>
            <field>
              <name>BS10</name>
              <bitOffset>10</bitOffset>
              <bitWidth>1</bitWidth>
            </field>
            <field>
              <name>BS11</name>
              <bitOffset>11</bitOffset>
              <bitWidth>1</bitWidth>
            </field>
            <field>
              <name>BS12</name>
              <bitOffset>12</bitOffset>
              <bitWidth>1</bitWidth>
            </field>
            <field>
              <name>BS13</name>
              <bitOffset>13</bitOffset>
              <bitWidth>1</bitWidth>
            </field>
            <field>
              <name>BS14</name>
              <bitOffset>14</bitOffset>
              <bitWidth>1</bitWidth>
            </field>
            <field>
              <name>BS15</name>
              <bitOffset>15</bitOffset>
              <bitWidth>1</bitWidth>
            </field>
            <field>
              <name>BR0</name>
              <bitOffset>16</bitOffset>
              <bitWidth>1</bitWidth>
            </field>
            <field>
              <name>BR1</name>
              <bitOffset>17</bitOffset>
              <bitWidth>1</bitWidth>
            </field>
            <field>
              <name>BR2</name>
              <bitOffset>18</bitOffset>
              <bitWidth>1</bitWidth>
            </field>
            <field>
              <name>BR3</name>
              <bitOffset>19</bitOffset>
              <bitWidth>1</bitWidth>
            </field>
            <field>
              <name>BR4</name>
              <bitOffset>20</bitOffset>
              <bitWidth>1</bitWidth>
            </field>
            <field>
              <name>BR5</name>
              <bitOffset>21</bitOffset>
              <bitWidth>1</bitWidth>
            </field>
            <field>
              <name>BR6</name>
              <bitOffset>22</bitOffset>
              <bitWidth>1</bitWidth>
            </field>
            <field>
              <name>BR7</name>
              <bitOffset>23</bitOffset>
              <bitWidth>1</bitWidth>
            </field>
            <field>
              <name>BR8</name>
              <bitOffset>24</bitOffset>
              <bitWidth>1</bitWidth>
            </field>
            <field>
              <name>BR9</name>
              <bitOffset>25</bitOffset>
              <bitWidth>1</bitWidth>
            </field>
            <field>
              <name>BR10</name>
              <bitOffset>26</bitOffset>
              <bitWidth>1</bitWidth>
            </field>
            <field>
              <name>BR11</name>
              <bitOffset>27</bitOffset>
              <bitWidth>1</bitWidth>
            </field>
            <field>
              <name>BR12</name>
              <bitOffset>28</bitOffset>
              <bitWidth>1</bitWidth>
            </field>
            <field>
              <name>BR13</name>
              <bitOffset>29</bitOffset>
              <bitWidth>1</bitWidth>
            </field>
            <field>
              <name>BR14</name>
              <bitOffset>30</bitOffset>
              <bitWidth>1</bitWidth>
            </field>
            <field>
              <name>BR15</name>
              <bitOffset>31</bitOffset>
              <bitWidth>1</bitWidth>
            </field>
          </fields>
        </register>
        <register>
          <name>LCKR</name>
          <addressOffset>0x1c</addressOffset>
          <size>0x20</size>
          <fields>
            <field>
              <name>LCK0</name>
              <bitOffset>0</bitOffset>
              <bitWidth>1</bitWidth>
            </field>
            <field>
              <name>LCK1</name>
              <bitOffset>1</bitOffset>
              <bitWidth>1</bitWidth>
            </field>
            <field>
              <name>LCK2</name>
              <bitOffset>2</bitOffset>
              <bitWidth>1</bitWidth>
            </field>
            <field>
              <name>LCK3</name>
              <bitOffset>3</bitOffset>
              <bitWidth>1</bitWidth>
            </field>
            <field>
              <name>LCK4</name>
              <bitOffset>4</bitOffset>
              <bitWidth>1</bitWidth>
            </field>
            <field>
              <name>LCK5</name>
              <bitOffset>5</bitOffset>
              <bitWidth>1</bitWidth>
            </field>
            <field>
              <name>LCK6</name>
              <bitOffset>6</bitOffset>
              <bitWidth>1</bitWidth>
            </field>
            <field>
              <name>LCK7</name>
              <bitOffset>7</bitOffset>
              <bitWidth>1</bitWidth>
            </field>
            <field>
              <name>LCK8</name>
              <bitOffset>8</bitOffset>
              <bitWidth>1</bitWidth>
            </field>
            <field>
              <name>LCK9</name>
              <bitOffset>9</bitOffset>
              <bitWidth>1</bitWidth>
            </field>
            <field>
              <name>LCK10</name>
              <bitOffset>10</bitOffset>
              <bitWidth>1</bitWidth>
            </field>
            <field>
              <name>LCK11</name>
              <bitOffset>11</bitOffset>
              <bitWidth>1</bitWidth>
            </field>
            <field>
              <name>LCK12</name>
              <bitOffset>12</bitOffset>
              <bitWidth>1</bitWidth>
            </field>
            <field>
              <name>LCK13</name>
              <bitOffset>13</bitOffset>
              <bitWidth>1</bitWidth>
            </field>
            <field>
              <name>LCK14</name>
              <bitOffset>14</bitOffset>
              <bitWidth>1</bitWidth>
            </field>
            <field>
              <name>LCK15</name>
              <bitOffset>15</bitOffset>
              <bitWidth>1</bitWidth>
            </field>
            <field>
              <name>LCKK</name>
              <bitOffset>16</bitOffset>
              <bitWidth>1</bitWidth>
            </field>
          </fields>
        </register>
        <register>
          <name>AFR.0</name>
          <addressOffset>0x20</addressOffset>
          <size>0x20</size>
          <fields>
            <field>
              <name>AFRL0</name>
              <bitOffset>0</bitOffset>
              <bitWidth>4</bitWidth>
            </field>
            <field>
              <name>AFRL1</name>
              <bitOffset>4</bitOffset>
              <bitWidth>4</bitWidth>
            </field>
            <field>
              <name>AFRL2</name>
              <bitOffset>8</bitOffset>
              <bitWidth>4</bitWidth>
            </field>
            <field>
              <name>AFRL3</name>
              <bitOffset>12</bitOffset>
              <bitWidth>4</bitWidth>
            </field>
            <field>
              <name>AFRL4</name>
              <bitOffset>16</bitOffset>
              <bitWidth>4</bitWidth>
            </field>
            <field>
              <name>AFRL5</name>
              <bitOffset>20</bitOffset>
              <bitWidth>4</bitWidth>
            </field>
            <field>
              <name>AFRL6</name>
              <bitOffset>24</bitOffset>
              <bitWidth>4</bitWidth>
            </field>
            <field>
              <name>AFRL7</name>
              <bitOffset>28</bitOffset>
              <bitWidth>4</bitWidth>
            </field>
          </fields>
        </register>
        <register>
          <name>AFR.1</name>
          <addressOffset>0x24</addressOffset>
          <size>0x20</size>
          <fields>
            <field>
              <name>AFRH0</name>
              <bitOffset>0</bitOffset>
              <bitWidth>4</bitWidth>
            </field>
            <field>
              <name>AFRH1</name>
              <bitOffset>4</bitOffset>
              <bitWidth>4</bitWidth>
            </field>
            <field>
              <name>AFRH2</name>
              <bitOffset>8</bitOffset>
              <bitWidth>4</bitWidth>
            </field>
            <field>
              <name>AFRH3</name>
              <bitOffset>12</bitOffset>
              <bitWidth>4</bitWidth>
            </field>
            <field>
              <name>AFRH4</name>
              <bitOffset>16</bitOffset>
              <bitWidth>4</bitWidth>
            </field>
            <field>
              <name>AFRH5</name>
              <bitOffset>20</bitOffset>
              <bitWidth>4</bitWidth>
            </field>
            <field>
              <name>AFRH6</name>
              <bitOffset>24</bitOffset>
              <bitWidth>4</bitWidth>
            </field>
            <field>
              <name>AFRH7</name>
              <bitOffset>28</bitOffset>
              <bitWidth>4</bitWidth>
            </field>
          </fields>
        </register>
      </registers>
    </peripheral>
    <peripheral>
      <name>GPIOF</name>
      <baseAddress>0x40021400</baseAddress>
      <registers>
        <register>
          <name>MODER</name>
          <addressOffset>0x0</addressOffset>
          <size>0x20</size>
          <fields>
            <field>
              <name>MODER0</name>
              <bitOffset>0</bitOffset>
              <bitWidth>2</bitWidth>
            </field>
            <field>
              <name>MODER1</name>
              <bitOffset>2</bitOffset>
              <bitWidth>2</bitWidth>
            </field>
            <field>
              <name>MODER2</name>
              <bitOffset>4</bitOffset>
              <bitWidth>2</bitWidth>
            </field>
            <field>
              <name>MODER3</name>
              <bitOffset>6</bitOffset>
              <bitWidth>2</bitWidth>
            </field>
            <field>
              <name>MODER4</name>
              <bitOffset>8</bitOffset>
              <bitWidth>2</bitWidth>
            </field>
            <field>
              <name>MODER5</name>
              <bitOffset>10</bitOffset>
              <bitWidth>2</bitWidth>
            </field>
            <field>
              <name>MODER6</name>
              <bitOffset>12</bitOffset>
              <bitWidth>2</bitWidth>
            </field>
            <field>
              <name>MODER7</name>
              <bitOffset>14</bitOffset>
              <bitWidth>2</bitWidth>
            </field>
            <field>
              <name>MODER8</name>
              <bitOffset>16</bitOffset>
              <bitWidth>2</bitWidth>
            </field>
            <field>
              <name>MODER9</name>
              <bitOffset>18</bitOffset>
              <bitWidth>2</bitWidth>
            </field>
            <field>
              <name>MODER10</name>
              <bitOffset>20</bitOffset>
              <bitWidth>2</bitWidth>
            </field>
            <field>
              <name>MODER11</name>
              <bitOffset>22</bitOffset>
              <bitWidth>2</bitWidth>
            </field>
            <field>
              <name>MODER12</name>
              <bitOffset>24</bitOffset>
              <bitWidth>2</bitWidth>
            </field>
            <field>
              <name>MODER13</name>
              <bitOffset>26</bitOffset>
              <bitWidth>2</bitWidth>
            </field>
            <field>
              <name>MODER14</name>
              <bitOffset>28</bitOffset>
              <bitWidth>2</bitWidth>
            </field>
            <field>
              <name>MODER15</name>
              <bitOffset>30</bitOffset>
              <bitWidth>2</bitWidth>
            </field>
          </fields>
        </register>
        <register>
          <name>OTYPER</name>
          <addressOffset>0x4</addressOffset>
          <size>0x20</size>
          <fields>
            <field>
              <name>OT0</name>
              <bitOffset>0</bitOffset>
              <bitWidth>1</bitWidth>
            </field>
            <field>
              <name>OT1</name>
              <bitOffset>1</bitOffset>
              <bitWidth>1</bitWidth>
            </field>
            <field>
              <name>OT2</name>
              <bitOffset>2</bitOffset>
              <bitWidth>1</bitWidth>
            </field>
            <field>
              <name>OT3</name>
              <bitOffset>3</bitOffset>
              <bitWidth>1</bitWidth>
            </field>
            <field>
              <name>OT4</name>
              <bitOffset>4</bitOffset>
              <bitWidth>1</bitWidth>
            </field>
            <field>
              <name>OT5</name>
              <bitOffset>5</bitOffset>
              <bitWidth>1</bitWidth>
            </field>
            <field>
              <name>OT6</name>
              <bitOffset>6</bitOffset>
              <bitWidth>1</bitWidth>
            </field>
            <field>
              <name>OT7</name>
              <bitOffset>7</bitOffset>
              <bitWidth>1</bitWidth>
            </field>
            <field>
              <name>OT8</name>
              <bitOffset>8</bitOffset>
              <bitWidth>1</bitWidth>
            </field>
            <field>
              <name>OT9</name>
              <bitOffset>9</bitOffset>
              <bitWidth>1</bitWidth>
            </field>
            <field>
              <name>OT10</name>
              <bitOffset>10</bitOffset>
              <bitWidth>1</bitWidth>
            </field>
            <field>
              <name>OT11</name>
              <bitOffset>11</bitOffset>
              <bitWidth>1</bitWidth>
            </field>
            <field>
              <name>OT12</name>
              <bitOffset>12</bitOffset>
              <bitWidth>1</bitWidth>
            </field>
            <field>
              <name>OT13</name>
              <bitOffset>13</bitOffset>
              <bitWidth>1</bitWidth>
            </field>
            <field>
              <name>OT14</name>
              <bitOffset>14</bitOffset>
              <bitWidth>1</bitWidth>
            </field>
            <field>
              <name>OT15</name>
              <bitOffset>15</bitOffset>
              <bitWidth>1</bitWidth>
            </field>
          </fields>
        </register>
        <register>
          <name>OSPEEDR</name>
          <addressOffset>0x8</addressOffset>
          <size>0x20</size>
          <fields>
            <field>
              <name>OSPEEDR0</name>
              <bitOffset>0</bitOffset>
              <bitWidth>2</bitWidth>
            </field>
            <field>
              <name>OSPEEDR1</name>
              <bitOffset>2</bitOffset>
              <bitWidth>2</bitWidth>
            </field>
            <field>
              <name>OSPEEDR2</name>
              <bitOffset>4</bitOffset>
              <bitWidth>2</bitWidth>
            </field>
            <field>
              <name>OSPEEDR3</name>
              <bitOffset>6</bitOffset>
              <bitWidth>2</bitWidth>
            </field>
            <field>
              <name>OSPEEDR4</name>
              <bitOffset>8</bitOffset>
              <bitWidth>2</bitWidth>
            </field>
            <field>
              <name>OSPEEDR5</name>
              <bitOffset>10</bitOffset>
              <bitWidth>2</bitWidth>
            </field>
            <field>
              <name>OSPEEDR6</name>
              <bitOffset>12</bitOffset>
              <bitWidth>2</bitWidth>
            </field>
            <field>
              <name>OSPEEDR7</name>
              <bitOffset>14</bitOffset>
              <bitWidth>2</bitWidth>
            </field>
            <field>
              <name>OSPEEDR8</name>
              <bitOffset>16</bitOffset>
              <bitWidth>2</bitWidth>
            </field>
            <field>
              <name>OSPEEDR9</name>
              <bitOffset>18</bitOffset>
              <bitWidth>2</bitWidth>
            </field>
            <field>
              <name>OSPEEDR10</name>
              <bitOffset>20</bitOffset>
              <bitWidth>2</bitWidth>
            </field>
            <field>
              <name>OSPEEDR11</name>
              <bitOffset>22</bitOffset>
              <bitWidth>2</bitWidth>
            </field>
            <field>
              <name>OSPEEDR12</name>
              <bitOffset>24</bitOffset>
              <bitWidth>2</bitWidth>
            </field>
            <field>
              <name>OSPEEDR13</name>
              <bitOffset>26</bitOffset>
              <bitWidth>2</bitWidth>
            </field>
            <field>
              <name>OSPEEDR14</name>
              <bitOffset>28</bitOffset>
              <bitWidth>2</bitWidth>
            </field>
            <field>
              <name>OSPEEDR15</name>
              <bitOffset>30</bitOffset>
              <bitWidth>2</bitWidth>
            </field>
          </fields>
        </register>
        <register>
          <name>PUPDR</name>
          <addressOffset>0xc</addressOffset>
          <size>0x20</size>
          <fields>
            <field>
              <name>PUPDR0</name>
              <bitOffset>0</bitOffset>
              <bitWidth>2</bitWidth>
            </field>
            <field>
              <name>PUPDR1</name>
              <bitOffset>2</bitOffset>
              <bitWidth>2</bitWidth>
            </field>
            <field>
              <name>PUPDR2</name>
              <bitOffset>4</bitOffset>
              <bitWidth>2</bitWidth>
            </field>
            <field>
              <name>PUPDR3</name>
              <bitOffset>6</bitOffset>
              <bitWidth>2</bitWidth>
            </field>
            <field>
              <name>PUPDR4</name>
              <bitOffset>8</bitOffset>
              <bitWidth>2</bitWidth>
            </field>
            <field>
              <name>PUPDR5</name>
              <bitOffset>10</bitOffset>
              <bitWidth>2</bitWidth>
            </field>
            <field>
              <name>PUPDR6</name>
              <bitOffset>12</bitOffset>
              <bitWidth>2</bitWidth>
            </field>
            <field>
              <name>PUPDR7</name>
              <bitOffset>14</bitOffset>
              <bitWidth>2</bitWidth>
            </field>
            <field>
              <name>PUPDR8</name>
              <bitOffset>16</bitOffset>
              <bitWidth>2</bitWidth>
            </field>
            <field>
              <name>PUPDR9</name>
              <bitOffset>18</bitOffset>
              <bitWidth>2</bitWidth>
            </field>
            <field>
              <name>PUPDR10</name>
              <bitOffset>20</bitOffset>
              <bitWidth>2</bitWidth>
            </field>
            <field>
              <name>PUPDR11</name>
              <bitOffset>22</bitOffset>
              <bitWidth>2</bitWidth>
            </field>
            <field>
              <name>PUPDR12</name>
              <bitOffset>24</bitOffset>
              <bitWidth>2</bitWidth>
            </field>
            <field>
              <name>PUPDR13</name>
              <bitOffset>26</bitOffset>
              <bitWidth>2</bitWidth>
            </field>
            <field>
              <name>PUPDR14</name>
              <bitOffset>28</bitOffset>
              <bitWidth>2</bitWidth>
            </field>
            <field>
              <name>PUPDR15</name>
              <bitOffset>30</bitOffset>
              <bitWidth>2</bitWidth>
            </field>
          </fields>
        </register>
        <register>
          <name>IDR</name>
          <addressOffset>0x10</addressOffset>
          <size>0x20</size>
          <fields>
            <field>
              <name>ID0</name>
              <bitOffset>0</bitOffset>
              <bitWidth>1</bitWidth>
            </field>
            <field>
              <name>ID1</name>
              <bitOffset>1</bitOffset>
              <bitWidth>1</bitWidth>
            </field>
            <field>
              <name>ID2</name>
              <bitOffset>2</bitOffset>
              <bitWidth>1</bitWidth>
            </field>
            <field>
              <name>ID3</name>
              <bitOffset>3</bitOffset>
              <bitWidth>1</bitWidth>
            </field>
            <field>
              <name>ID4</name>
              <bitOffset>4</bitOffset>
              <bitWidth>1</bitWidth>
            </field>
            <field>
              <name>ID5</name>
              <bitOffset>5</bitOffset>
              <bitWidth>1</bitWidth>
            </field>
            <field>
              <name>ID6</name>
              <bitOffset>6</bitOffset>
              <bitWidth>1</bitWidth>
            </field>
            <field>
              <name>ID7</name>
              <bitOffset>7</bitOffset>
              <bitWidth>1</bitWidth>
            </field>
            <field>
              <name>ID8</name>
              <bitOffset>8</bitOffset>
              <bitWidth>1</bitWidth>
            </field>
            <field>
              <name>ID9</name>
              <bitOffset>9</bitOffset>
              <bitWidth>1</bitWidth>
            </field>
            <field>
              <name>ID10</name>
              <bitOffset>10</bitOffset>
              <bitWidth>1</bitWidth>
            </field>
            <field>
              <name>ID11</name>
              <bitOffset>11</bitOffset>
              <bitWidth>1</bitWidth>
            </field>
            <field>
              <name>ID12</name>
              <bitOffset>12</bitOffset>
              <bitWidth>1</bitWidth>
            </field>
            <field>
              <name>ID13</name>
              <bitOffset>13</bitOffset>
              <bitWidth>1</bitWidth>
            </field>
            <field>
              <name>ID14</name>
              <bitOffset>14</bitOffset>
              <bitWidth>1</bitWidth>
            </field>
            <field>
              <name>ID15</name>
              <bitOffset>15</bitOffset>
              <bitWidth>1</bitWidth>
            </field>
          </fields>
        </register>
        <register>
          <name>ODR</name>
          <addressOffset>0x14</addressOffset>
          <size>0x20</size>
          <fields>
            <field>
              <name>OD0</name>
              <bitOffset>0</bitOffset>
              <bitWidth>1</bitWidth>
            </field>
            <field>
              <name>OD1</name>
              <bitOffset>1</bitOffset>
              <bitWidth>1</bitWidth>
            </field>
            <field>
              <name>OD2</name>
              <bitOffset>2</bitOffset>
              <bitWidth>1</bitWidth>
            </field>
            <field>
              <name>OD3</name>
              <bitOffset>3</bitOffset>
              <bitWidth>1</bitWidth>
            </field>
            <field>
              <name>OD4</name>
              <bitOffset>4</bitOffset>
              <bitWidth>1</bitWidth>
            </field>
            <field>
              <name>OD5</name>
              <bitOffset>5</bitOffset>
              <bitWidth>1</bitWidth>
            </field>
            <field>
              <name>OD6</name>
              <bitOffset>6</bitOffset>
              <bitWidth>1</bitWidth>
            </field>
            <field>
              <name>OD7</name>
              <bitOffset>7</bitOffset>
              <bitWidth>1</bitWidth>
            </field>
            <field>
              <name>OD8</name>
              <bitOffset>8</bitOffset>
              <bitWidth>1</bitWidth>
            </field>
            <field>
              <name>OD9</name>
              <bitOffset>9</bitOffset>
              <bitWidth>1</bitWidth>
            </field>
            <field>
              <name>OD10</name>
              <bitOffset>10</bitOffset>
              <bitWidth>1</bitWidth>
            </field>
            <field>
              <name>OD11</name>
              <bitOffset>11</bitOffset>
              <bitWidth>1</bitWidth>
            </field>
            <field>
              <name>OD12</name>
              <bitOffset>12</bitOffset>
              <bitWidth>1</bitWidth>
            </field>
            <field>
              <name>OD13</name>
              <bitOffset>13</bitOffset>
              <bitWidth>1</bitWidth>
            </field>
            <field>
              <name>OD14</name>
              <bitOffset>14</bitOffset>
              <bitWidth>1</bitWidth>
            </field>
            <field>
              <name>OD15</name>
              <bitOffset>15</bitOffset>
              <bitWidth>1</bitWidth>
            </field>
          </fields>
        </register>
        <register>
          <name>BSRR</name>
          <addressOffset>0x18</addressOffset>
          <size>0x20</size>
          <fields>
            <field>
              <name>BS0</name>
              <bitOffset>0</bitOffset>
              <bitWidth>1</bitWidth>
            </field>
            <field>
              <name>BS1</name>
              <bitOffset>1</bitOffset>
              <bitWidth>1</bitWidth>
            </field>
            <field>
              <name>BS2</name>
              <bitOffset>2</bitOffset>
              <bitWidth>1</bitWidth>
            </field>
            <field>
              <name>BS3</name>
              <bitOffset>3</bitOffset>
              <bitWidth>1</bitWidth>
            </field>
            <field>
              <name>BS4</name>
              <bitOffset>4</bitOffset>
              <bitWidth>1</bitWidth>
            </field>
            <field>
              <name>BS5</name>
              <bitOffset>5</bitOffset>
              <bitWidth>1</bitWidth>
            </field>
            <field>
              <name>BS6</name>
              <bitOffset>6</bitOffset>
              <bitWidth>1</bitWidth>
            </field>
            <field>
              <name>BS7</name>
              <bitOffset>7</bitOffset>
              <bitWidth>1</bitWidth>
            </field>
            <field>
              <name>BS8</name>
              <bitOffset>8</bitOffset>
              <bitWidth>1</bitWidth>
            </field>
            <field>
              <name>BS9</name>
              <bitOffset>9</bitOffset>
              <bitWidth>1</bitWidth>
            </field>
            <field>
              <name>BS10</name>
              <bitOffset>10</bitOffset>
              <bitWidth>1</bitWidth>
            </field>
            <field>
              <name>BS11</name>
              <bitOffset>11</bitOffset>
              <bitWidth>1</bitWidth>
            </field>
            <field>
              <name>BS12</name>
              <bitOffset>12</bitOffset>
              <bitWidth>1</bitWidth>
            </field>
            <field>
              <name>BS13</name>
              <bitOffset>13</bitOffset>
              <bitWidth>1</bitWidth>
            </field>
            <field>
              <name>BS14</name>
              <bitOffset>14</bitOffset>
              <bitWidth>1</bitWidth>
            </field>
            <field>
              <name>BS15</name>
              <bitOffset>15</bitOffset>
              <bitWidth>1</bitWidth>
            </field>
            <field>
              <name>BR0</name>
              <bitOffset>16</bitOffset>
              <bitWidth>1</bitWidth>
            </field>
            <field>
              <name>BR1</name>
              <bitOffset>17</bitOffset>
              <bitWidth>1</bitWidth>
            </field>
            <field>
              <name>BR2</name>
              <bitOffset>18</bitOffset>
              <bitWidth>1</bitWidth>
            </field>
            <field>
              <name>BR3</name>
              <bitOffset>19</bitOffset>
              <bitWidth>1</bitWidth>
            </field>
            <field>
              <name>BR4</name>
              <bitOffset>20</bitOffset>
              <bitWidth>1</bitWidth>
            </field>
            <field>
              <name>BR5</name>
              <bitOffset>21</bitOffset>
              <bitWidth>1</bitWidth>
            </field>
            <field>
              <name>BR6</name>
              <bitOffset>22</bitOffset>
              <bitWidth>1</bitWidth>
            </field>
            <field>
              <name>BR7</name>
              <bitOffset>23</bitOffset>
              <bitWidth>1</bitWidth>
            </field>
            <field>
              <name>BR8</name>
              <bitOffset>24</bitOffset>
              <bitWidth>1</bitWidth>
            </field>
            <field>
              <name>BR9</name>
              <bitOffset>25</bitOffset>
              <bitWidth>1</bitWidth>
            </field>
            <field>
              <name>BR10</name>
              <bitOffset>26</bitOffset>
              <bitWidth>1</bitWidth>
            </field>
            <field>
              <name>BR11</name>
              <bitOffset>27</bitOffset>
              <bitWidth>1</bitWidth>
            </field>
            <field>
              <name>BR12</name>
              <bitOffset>28</bitOffset>
              <bitWidth>1</bitWidth>
            </field>
            <field>
              <name>BR13</name>
              <bitOffset>29</bitOffset>
              <bitWidth>1</bitWidth>
            </field>
            <field>
              <name>BR14</name>
              <bitOffset>30</bitOffset>
              <bitWidth>1</bitWidth>
            </field>
            <field>
              <name>BR15</name>
              <bitOffset>31</bitOffset>
              <bitWidth>1</bitWidth>
            </field>
          </fields>
        </register>
        <register>
          <name>LCKR</name>
          <addressOffset>0x1c</addressOffset>
          <size>0x20</size>
          <fields>
            <field>
              <name>LCK0</name>
              <bitOffset>0</bitOffset>
              <bitWidth>1</bitWidth>
            </field>
            <field>
              <name>LCK1</name>
              <bitOffset>1</bitOffset>
              <bitWidth>1</bitWidth>
            </field>
            <field>
              <name>LCK2</name>
              <bitOffset>2</bitOffset>
              <bitWidth>1</bitWidth>
            </field>
            <field>
              <name>LCK3</name>
              <bitOffset>3</bitOffset>
              <bitWidth>1</bitWidth>
            </field>
            <field>
              <name>LCK4</name>
              <bitOffset>4</bitOffset>
              <bitWidth>1</bitWidth>
            </field>
            <field>
              <name>LCK5</name>
              <bitOffset>5</bitOffset>
              <bitWidth>1</bitWidth>
            </field>
            <field>
              <name>LCK6</name>
              <bitOffset>6</bitOffset>
              <bitWidth>1</bitWidth>
            </field>
            <field>
              <name>LCK7</name>
              <bitOffset>7</bitOffset>
              <bitWidth>1</bitWidth>
            </field>
            <field>
              <name>LCK8</name>
              <bitOffset>8</bitOffset>
              <bitWidth>1</bitWidth>
            </field>
            <field>
              <name>LCK9</name>
              <bitOffset>9</bitOffset>
              <bitWidth>1</bitWidth>
            </field>
            <field>
              <name>LCK10</name>
              <bitOffset>10</bitOffset>
              <bitWidth>1</bitWidth>
            </field>
            <field>
              <name>LCK11</name>
              <bitOffset>11</bitOffset>
              <bitWidth>1</bitWidth>
            </field>
            <field>
              <name>LCK12</name>
              <bitOffset>12</bitOffset>
              <bitWidth>1</bitWidth>
            </field>
            <field>
              <name>LCK13</name>
              <bitOffset>13</bitOffset>
              <bitWidth>1</bitWidth>
            </field>
            <field>
              <name>LCK14</name>
              <bitOffset>14</bitOffset>
              <bitWidth>1</bitWidth>
            </field>
            <field>
              <name>LCK15</name>
              <bitOffset>15</bitOffset>
              <bitWidth>1</bitWidth>
            </field>
            <field>
              <name>LCKK</name>
              <bitOffset>16</bitOffset>
              <bitWidth>1</bitWidth>
            </field>
          </fields>
        </register>
        <register>
          <name>AFR.0</name>
          <addressOffset>0x20</addressOffset>
          <size>0x20</size>
          <fields>
            <field>
              <name>AFRL0</name>
              <bitOffset>0</bitOffset>
              <bitWidth>4</bitWidth>
            </field>
            <field>
              <name>AFRL1</name>
              <bitOffset>4</bitOffset>
              <bitWidth>4</bitWidth>
            </field>
            <field>
              <name>AFRL2</name>
              <bitOffset>8</bitOffset>
              <bitWidth>4</bitWidth>
            </field>
            <field>
              <name>AFRL3</name>
              <bitOffset>12</bitOffset>
              <bitWidth>4</bitWidth>
            </field>
            <field>
              <name>AFRL4</name>
              <bitOffset>16</bitOffset>
              <bitWidth>4</bitWidth>
            </field>
            <field>
              <name>AFRL5</name>
              <bitOffset>20</bitOffset>
              <bitWidth>4</bitWidth>
            </field>
            <field>
              <name>AFRL6</name>
              <bitOffset>24</bitOffset>
              <bitWidth>4</bitWidth>
            </field>
            <field>
              <name>AFRL7</name>
              <bitOffset>28</bitOffset>
              <bitWidth>4</bitWidth>
            </field>
          </fields>
        </register>
        <register>
          <name>AFR.1</name>
          <addressOffset>0x24</addressOffset>
          <size>0x20</size>
          <fields>
            <field>
              <name>AFRH0</name>
              <bitOffset>0</bitOffset>
              <bitWidth>4</bitWidth>
            </field>
            <field>
              <name>AFRH1</name>
              <bitOffset>4</bitOffset>
              <bitWidth>4</bitWidth>
            </field>
            <field>
              <name>AFRH2</name>
              <bitOffset>8</bitOffset>
              <bitWidth>4</bitWidth>
            </field>
            <field>
              <name>AFRH3</name>
              <bitOffset>12</bitOffset>
              <bitWidth>4</bitWidth>
            </field>
            <field>
              <name>AFRH4</name>
              <bitOffset>16</bitOffset>
              <bitWidth>4</bitWidth>
            </field>
            <field>
              <name>AFRH5</name>
              <bitOffset>20</bitOffset>
              <bitWidth>4</bitWidth>
            </field>
            <field>
              <name>AFRH6</name>
              <bitOffset>24</bitOffset>
              <bitWidth>4</bitWidth>
            </field>
            <field>
              <name>AFRH7</name>
              <bitOffset>28</bitOffset>
              <bitWidth>4</bitWidth>
            </field>
          </fields>
        </register>
      </registers>
    </peripheral>
    <peripheral>
      <name>GPIOG</name>
      <baseAddress>0x40021800</baseAddress>
      <registers>
        <register>
          <name>MODER</name>
          <addressOffset>0x0</addressOffset>
          <size>0x20</size>
          <fields>
            <field>
              <name>MODER0</name>
              <bitOffset>0</bitOffset>
              <bitWidth>2</bitWidth>
            </field>
            <field>
              <name>MODER1</name>
              <bitOffset>2</bitOffset>
              <bitWidth>2</bitWidth>
            </field>
            <field>
              <name>MODER2</name>
              <bitOffset>4</bitOffset>
              <bitWidth>2</bitWidth>
            </field>
            <field>
              <name>MODER3</name>
              <bitOffset>6</bitOffset>
              <bitWidth>2</bitWidth>
            </field>
            <field>
              <name>MODER4</name>
              <bitOffset>8</bitOffset>
              <bitWidth>2</bitWidth>
            </field>
            <field>
              <name>MODER5</name>
              <bitOffset>10</bitOffset>
              <bitWidth>2</bitWidth>
            </field>
            <field>
              <name>MODER6</name>
              <bitOffset>12</bitOffset>
              <bitWidth>2</bitWidth>
            </field>
            <field>
              <name>MODER7</name>
              <bitOffset>14</bitOffset>
              <bitWidth>2</bitWidth>
            </field>
            <field>
              <name>MODER8</name>
              <bitOffset>16</bitOffset>
              <bitWidth>2</bitWidth>
            </field>
            <field>
              <name>MODER9</name>
              <bitOffset>18</bitOffset>
              <bitWidth>2</bitWidth>
            </field>
            <field>
              <name>MODER10</name>
              <bitOffset>20</bitOffset>
              <bitWidth>2</bitWidth>
            </field>
            <field>
              <name>MODER11</name>
              <bitOffset>22</bitOffset>
              <bitWidth>2</bitWidth>
            </field>
            <field>
              <name>MODER12</name>
              <bitOffset>24</bitOffset>
              <bitWidth>2</bitWidth>
            </field>
            <field>
              <name>MODER13</name>
              <bitOffset>26</bitOffset>
              <bitWidth>2</bitWidth>
            </field>
            <field>
              <name>MODER14</name>
              <bitOffset>28</bitOffset>
              <bitWidth>2</bitWidth>
            </field>
            <field>
              <name>MODER15</name>
              <bitOffset>30</bitOffset>
              <bitWidth>2</bitWidth>
            </field>
          </fields>
        </register>
        <register>
          <name>OTYPER</name>
          <addressOffset>0x4</addressOffset>
          <size>0x20</size>
          <fields>
            <field>
              <name>OT0</name>
              <bitOffset>0</bitOffset>
              <bitWidth>1</bitWidth>
            </field>
            <field>
              <name>OT1</name>
              <bitOffset>1</bitOffset>
              <bitWidth>1</bitWidth>
            </field>
            <field>
              <name>OT2</name>
              <bitOffset>2</bitOffset>
              <bitWidth>1</bitWidth>
            </field>
            <field>
              <name>OT3</name>
              <bitOffset>3</bitOffset>
              <bitWidth>1</bitWidth>
            </field>
            <field>
              <name>OT4</name>
              <bitOffset>4</bitOffset>
              <bitWidth>1</bitWidth>
            </field>
            <field>
              <name>OT5</name>
              <bitOffset>5</bitOffset>
              <bitWidth>1</bitWidth>
            </field>
            <field>
              <name>OT6</name>
              <bitOffset>6</bitOffset>
              <bitWidth>1</bitWidth>
            </field>
            <field>
              <name>OT7</name>
              <bitOffset>7</bitOffset>
              <bitWidth>1</bitWidth>
            </field>
            <field>
              <name>OT8</name>
              <bitOffset>8</bitOffset>
              <bitWidth>1</bitWidth>
            </field>
            <field>
              <name>OT9</name>
              <bitOffset>9</bitOffset>
              <bitWidth>1</bitWidth>
            </field>
            <field>
              <name>OT10</name>
              <bitOffset>10</bitOffset>
              <bitWidth>1</bitWidth>
            </field>
            <field>
              <name>OT11</name>
              <bitOffset>11</bitOffset>
              <bitWidth>1</bitWidth>
            </field>
            <field>
              <name>OT12</name>
              <bitOffset>12</bitOffset>
              <bitWidth>1</bitWidth>
            </field>
            <field>
              <name>OT13</name>
              <bitOffset>13</bitOffset>
              <bitWidth>1</bitWidth>
            </field>
            <field>
              <name>OT14</name>
              <bitOffset>14</bitOffset>
              <bitWidth>1</bitWidth>
            </field>
            <field>
              <name>OT15</name>
              <bitOffset>15</bitOffset>
              <bitWidth>1</bitWidth>
            </field>
          </fields>
        </register>
        <register>
          <name>OSPEEDR</name>
          <addressOffset>0x8</addressOffset>
          <size>0x20</size>
          <fields>
            <field>
              <name>OSPEEDR0</name>
              <bitOffset>0</bitOffset>
              <bitWidth>2</bitWidth>
            </field>
            <field>
              <name>OSPEEDR1</name>
              <bitOffset>2</bitOffset>
              <bitWidth>2</bitWidth>
            </field>
            <field>
              <name>OSPEEDR2</name>
              <bitOffset>4</bitOffset>
              <bitWidth>2</bitWidth>
            </field>
            <field>
              <name>OSPEEDR3</name>
              <bitOffset>6</bitOffset>
              <bitWidth>2</bitWidth>
            </field>
            <field>
              <name>OSPEEDR4</name>
              <bitOffset>8</bitOffset>
              <bitWidth>2</bitWidth>
            </field>
            <field>
              <name>OSPEEDR5</name>
              <bitOffset>10</bitOffset>
              <bitWidth>2</bitWidth>
            </field>
            <field>
              <name>OSPEEDR6</name>
              <bitOffset>12</bitOffset>
              <bitWidth>2</bitWidth>
            </field>
            <field>
              <name>OSPEEDR7</name>
              <bitOffset>14</bitOffset>
              <bitWidth>2</bitWidth>
            </field>
            <field>
              <name>OSPEEDR8</name>
              <bitOffset>16</bitOffset>
              <bitWidth>2</bitWidth>
            </field>
            <field>
              <name>OSPEEDR9</name>
              <bitOffset>18</bitOffset>
              <bitWidth>2</bitWidth>
            </field>
            <field>
              <name>OSPEEDR10</name>
              <bitOffset>20</bitOffset>
              <bitWidth>2</bitWidth>
            </field>
            <field>
              <name>OSPEEDR11</name>
              <bitOffset>22</bitOffset>
              <bitWidth>2</bitWidth>
            </field>
            <field>
              <name>OSPEEDR12</name>
              <bitOffset>24</bitOffset>
              <bitWidth>2</bitWidth>
            </field>
            <field>
              <name>OSPEEDR13</name>
              <bitOffset>26</bitOffset>
              <bitWidth>2</bitWidth>
            </field>
            <field>
              <name>OSPEEDR14</name>
              <bitOffset>28</bitOffset>
              <bitWidth>2</bitWidth>
            </field>
            <field>
              <name>OSPEEDR15</name>
              <bitOffset>30</bitOffset>
              <bitWidth>2</bitWidth>
            </field>
          </fields>
        </register>
        <register>
          <name>PUPDR</name>
          <addressOffset>0xc</addressOffset>
          <size>0x20</size>
          <fields>
            <field>
              <name>PUPDR0</name>
              <bitOffset>0</bitOffset>
              <bitWidth>2</bitWidth>
            </field>
            <field>
              <name>PUPDR1</name>
              <bitOffset>2</bitOffset>
              <bitWidth>2</bitWidth>
            </field>
            <field>
              <name>PUPDR2</name>
              <bitOffset>4</bitOffset>
              <bitWidth>2</bitWidth>
            </field>
            <field>
              <name>PUPDR3</name>
              <bitOffset>6</bitOffset>
              <bitWidth>2</bitWidth>
            </field>
            <field>
              <name>PUPDR4</name>
              <bitOffset>8</bitOffset>
              <bitWidth>2</bitWidth>
            </field>
            <field>
              <name>PUPDR5</name>
              <bitOffset>10</bitOffset>
              <bitWidth>2</bitWidth>
            </field>
            <field>
              <name>PUPDR6</name>
              <bitOffset>12</bitOffset>
              <bitWidth>2</bitWidth>
            </field>
            <field>
              <name>PUPDR7</name>
              <bitOffset>14</bitOffset>
              <bitWidth>2</bitWidth>
            </field>
            <field>
              <name>PUPDR8</name>
              <bitOffset>16</bitOffset>
              <bitWidth>2</bitWidth>
            </field>
            <field>
              <name>PUPDR9</name>
              <bitOffset>18</bitOffset>
              <bitWidth>2</bitWidth>
            </field>
            <field>
              <name>PUPDR10</name>
              <bitOffset>20</bitOffset>
              <bitWidth>2</bitWidth>
            </field>
            <field>
              <name>PUPDR11</name>
              <bitOffset>22</bitOffset>
              <bitWidth>2</bitWidth>
            </field>
            <field>
              <name>PUPDR12</name>
              <bitOffset>24</bitOffset>
              <bitWidth>2</bitWidth>
            </field>
            <field>
              <name>PUPDR13</name>
              <bitOffset>26</bitOffset>
              <bitWidth>2</bitWidth>
            </field>
            <field>
              <name>PUPDR14</name>
              <bitOffset>28</bitOffset>
              <bitWidth>2</bitWidth>
            </field>
            <field>
              <name>PUPDR15</name>
              <bitOffset>30</bitOffset>
              <bitWidth>2</bitWidth>
            </field>
          </fields>
        </register>
        <register>
          <name>IDR</name>
          <addressOffset>0x10</addressOffset>
          <size>0x20</size>
          <fields>
            <field>
              <name>ID0</name>
              <bitOffset>0</bitOffset>
              <bitWidth>1</bitWidth>
            </field>
            <field>
              <name>ID1</name>
              <bitOffset>1</bitOffset>
              <bitWidth>1</bitWidth>
            </field>
            <field>
              <name>ID2</name>
              <bitOffset>2</bitOffset>
              <bitWidth>1</bitWidth>
            </field>
            <field>
              <name>ID3</name>
              <bitOffset>3</bitOffset>
              <bitWidth>1</bitWidth>
            </field>
            <field>
              <name>ID4</name>
              <bitOffset>4</bitOffset>
              <bitWidth>1</bitWidth>
            </field>
            <field>
              <name>ID5</name>
              <bitOffset>5</bitOffset>
              <bitWidth>1</bitWidth>
            </field>
            <field>
              <name>ID6</name>
              <bitOffset>6</bitOffset>
              <bitWidth>1</bitWidth>
            </field>
            <field>
              <name>ID7</name>
              <bitOffset>7</bitOffset>
              <bitWidth>1</bitWidth>
            </field>
            <field>
              <name>ID8</name>
              <bitOffset>8</bitOffset>
              <bitWidth>1</bitWidth>
            </field>
            <field>
              <name>ID9</name>
              <bitOffset>9</bitOffset>
              <bitWidth>1</bitWidth>
            </field>
            <field>
              <name>ID10</name>
              <bitOffset>10</bitOffset>
              <bitWidth>1</bitWidth>
            </field>
            <field>
              <name>ID11</name>
              <bitOffset>11</bitOffset>
              <bitWidth>1</bitWidth>
            </field>
            <field>
              <name>ID12</name>
              <bitOffset>12</bitOffset>
              <bitWidth>1</bitWidth>
            </field>
            <field>
              <name>ID13</name>
              <bitOffset>13</bitOffset>
              <bitWidth>1</bitWidth>
            </field>
            <field>
              <name>ID14</name>
              <bitOffset>14</bitOffset>
              <bitWidth>1</bitWidth>
            </field>
            <field>
              <name>ID15</name>
              <bitOffset>15</bitOffset>
              <bitWidth>1</bitWidth>
            </field>
          </fields>
        </register>
        <register>
          <name>ODR</name>
          <addressOffset>0x14</addressOffset>
          <size>0x20</size>
          <fields>
            <field>
              <name>OD0</name>
              <bitOffset>0</bitOffset>
              <bitWidth>1</bitWidth>
            </field>
            <field>
              <name>OD1</name>
              <bitOffset>1</bitOffset>
              <bitWidth>1</bitWidth>
            </field>
            <field>
              <name>OD2</name>
              <bitOffset>2</bitOffset>
              <bitWidth>1</bitWidth>
            </field>
            <field>
              <name>OD3</name>
              <bitOffset>3</bitOffset>
              <bitWidth>1</bitWidth>
            </field>
            <field>
              <name>OD4</name>
              <bitOffset>4</bitOffset>
              <bitWidth>1</bitWidth>
            </field>
            <field>
              <name>OD5</name>
              <bitOffset>5</bitOffset>
              <bitWidth>1</bitWidth>
            </field>
            <field>
              <name>OD6</name>
              <bitOffset>6</bitOffset>
              <bitWidth>1</bitWidth>
            </field>
            <field>
              <name>OD7</name>
              <bitOffset>7</bitOffset>
              <bitWidth>1</bitWidth>
            </field>
            <field>
              <name>OD8</name>
              <bitOffset>8</bitOffset>
              <bitWidth>1</bitWidth>
            </field>
            <field>
              <name>OD9</name>
              <bitOffset>9</bitOffset>
              <bitWidth>1</bitWidth>
            </field>
            <field>
              <name>OD10</name>
              <bitOffset>10</bitOffset>
              <bitWidth>1</bitWidth>
            </field>
            <field>
              <name>OD11</name>
              <bitOffset>11</bitOffset>
              <bitWidth>1</bitWidth>
            </field>
            <field>
              <name>OD12</name>
              <bitOffset>12</bitOffset>
              <bitWidth>1</bitWidth>
            </field>
            <field>
              <name>OD13</name>
              <bitOffset>13</bitOffset>
              <bitWidth>1</bitWidth>
            </field>
            <field>
              <name>OD14</name>
              <bitOffset>14</bitOffset>
              <bitWidth>1</bitWidth>
            </field>
            <field>
              <name>OD15</name>
              <bitOffset>15</bitOffset>
              <bitWidth>1</bitWidth>
            </field>
          </fields>
        </register>
        <register>
          <name>BSRR</name>
          <addressOffset>0x18</addressOffset>
          <size>0x20</size>
          <fields>
            <field>
              <name>BS0</name>
              <bitOffset>0</bitOffset>
              <bitWidth>1</bitWidth>
            </field>
            <field>
              <name>BS1</name>
              <bitOffset>1</bitOffset>
              <bitWidth>1</bitWidth>
            </field>
            <field>
              <name>BS2</name>
              <bitOffset>2</bitOffset>
              <bitWidth>1</bitWidth>
            </field>
            <field>
              <name>BS3</name>
              <bitOffset>3</bitOffset>
              <bitWidth>1</bitWidth>
            </field>
            <field>
              <name>BS4</name>
              <bitOffset>4</bitOffset>
              <bitWidth>1</bitWidth>
            </field>
            <field>
              <name>BS5</name>
              <bitOffset>5</bitOffset>
              <bitWidth>1</bitWidth>
            </field>
            <field>
              <name>BS6</name>
              <bitOffset>6</bitOffset>
              <bitWidth>1</bitWidth>
            </field>
            <field>
              <name>BS7</name>
              <bitOffset>7</bitOffset>
              <bitWidth>1</bitWidth>
            </field>
            <field>
              <name>BS8</name>
              <bitOffset>8</bitOffset>
              <bitWidth>1</bitWidth>
            </field>
            <field>
              <name>BS9</name>
              <bitOffset>9</bitOffset>
              <bitWidth>1</bitWidth>
            </field>
            <field>
              <name>BS10</name>
              <bitOffset>10</bitOffset>
              <bitWidth>1</bitWidth>
            </field>
            <field>
              <name>BS11</name>
              <bitOffset>11</bitOffset>
              <bitWidth>1</bitWidth>
            </field>
            <field>
              <name>BS12</name>
              <bitOffset>12</bitOffset>
              <bitWidth>1</bitWidth>
            </field>
            <field>
              <name>BS13</name>
              <bitOffset>13</bitOffset>
              <bitWidth>1</bitWidth>
            </field>
            <field>
              <name>BS14</name>
              <bitOffset>14</bitOffset>
              <bitWidth>1</bitWidth>
            </field>
            <field>
              <name>BS15</name>
              <bitOffset>15</bitOffset>
              <bitWidth>1</bitWidth>
            </field>
            <field>
              <name>BR0</name>
              <bitOffset>16</bitOffset>
              <bitWidth>1</bitWidth>
            </field>
            <field>
              <name>BR1</name>
              <bitOffset>17</bitOffset>
              <bitWidth>1</bitWidth>
            </field>
            <field>
              <name>BR2</name>
              <bitOffset>18</bitOffset>
              <bitWidth>1</bitWidth>
            </field>
            <field>
              <name>BR3</name>
              <bitOffset>19</bitOffset>
              <bitWidth>1</bitWidth>
            </field>
            <field>
              <name>BR4</name>
              <bitOffset>20</bitOffset>
              <bitWidth>1</bitWidth>
            </field>
            <field>
              <name>BR5</name>
              <bitOffset>21</bitOffset>
              <bitWidth>1</bitWidth>
            </field>
            <field>
              <name>BR6</name>
              <bitOffset>22</bitOffset>
              <bitWidth>1</bitWidth>
            </field>
            <field>
              <name>BR7</name>
              <bitOffset>23</bitOffset>
              <bitWidth>1</bitWidth>
            </field>
            <field>
              <name>BR8</name>
              <bitOffset>24</bitOffset>
              <bitWidth>1</bitWidth>
            </field>
            <field>
              <name>BR9</name>
              <bitOffset>25</bitOffset>
              <bitWidth>1</bitWidth>
            </field>
            <field>
              <name>BR10</name>
              <bitOffset>26</bitOffset>
              <bitWidth>1</bitWidth>
            </field>
            <field>
              <name>BR11</name>
              <bitOffset>27</bitOffset>
              <bitWidth>1</bitWidth>
            </field>
            <field>
              <name>BR12</name>
              <bitOffset>28</bitOffset>
              <bitWidth>1</bitWidth>
            </field>
            <field>
              <name>BR13</name>
              <bitOffset>29</bitOffset>
              <bitWidth>1</bitWidth>
            </field>
            <field>
              <name>BR14</name>
              <bitOffset>30</bitOffset>
              <bitWidth>1</bitWidth>
            </field>
            <field>
              <name>BR15</name>
              <bitOffset>31</bitOffset>
              <bitWidth>1</bitWidth>
            </field>
          </fields>
        </register>
        <register>
          <name>LCKR</name>
          <addressOffset>0x1c</addressOffset>
          <size>0x20</size>
          <fields>
            <field>
              <name>LCK0</name>
              <bitOffset>0</bitOffset>
              <bitWidth>1</bitWidth>
            </field>
            <field>
              <name>LCK1</name>
              <bitOffset>1</bitOffset>
              <bitWidth>1</bitWidth>
            </field>
            <field>
              <name>LCK2</name>
              <bitOffset>2</bitOffset>
              <bitWidth>1</bitWidth>
            </field>
            <field>
              <name>LCK3</name>
              <bitOffset>3</bitOffset>
              <bitWidth>1</bitWidth>
            </field>
            <field>
              <name>LCK4</name>
              <bitOffset>4</bitOffset>
              <bitWidth>1</bitWidth>
            </field>
            <field>
              <name>LCK5</name>
              <bitOffset>5</bitOffset>
              <bitWidth>1</bitWidth>
            </field>
            <field>
              <name>LCK6</name>
              <bitOffset>6</bitOffset>
              <bitWidth>1</bitWidth>
            </field>
            <field>
              <name>LCK7</name>
              <bitOffset>7</bitOffset>
              <bitWidth>1</bitWidth>
            </field>
            <field>
              <name>LCK8</name>
              <bitOffset>8</bitOffset>
              <bitWidth>1</bitWidth>
            </field>
            <field>
              <name>LCK9</name>
              <bitOffset>9</bitOffset>
              <bitWidth>1</bitWidth>
            </field>
            <field>
              <name>LCK10</name>
              <bitOffset>10</bitOffset>
              <bitWidth>1</bitWidth>
            </field>
            <field>
              <name>LCK11</name>
              <bitOffset>11</bitOffset>
              <bitWidth>1</bitWidth>
            </field>
            <field>
              <name>LCK12</name>
              <bitOffset>12</bitOffset>
              <bitWidth>1</bitWidth>
            </field>
            <field>
              <name>LCK13</name>
              <bitOffset>13</bitOffset>
              <bitWidth>1</bitWidth>
            </field>
            <field>
              <name>LCK14</name>
              <bitOffset>14</bitOffset>
              <bitWidth>1</bitWidth>
            </field>
            <field>
              <name>LCK15</name>
              <bitOffset>15</bitOffset>
              <bitWidth>1</bitWidth>
            </field>
            <field>
              <name>LCKK</name>
              <bitOffset>16</bitOffset>
              <bitWidth>1</bitWidth>
            </field>
          </fields>
        </register>
        <register>
          <name>AFR.0</name>
          <addressOffset>0x20</addressOffset>
          <size>0x20</size>
          <fields>
            <field>
              <name>AFRL0</name>
              <bitOffset>0</bitOffset>
              <bitWidth>4</bitWidth>
            </field>
            <field>
              <name>AFRL1</name>
              <bitOffset>4</bitOffset>
              <bitWidth>4</bitWidth>
            </field>
            <field>
              <name>AFRL2</name>
              <bitOffset>8</bitOffset>
              <bitWidth>4</bitWidth>
            </field>
            <field>
              <name>AFRL3</name>
              <bitOffset>12</bitOffset>
              <bitWidth>4</bitWidth>
            </field>
            <field>
              <name>AFRL4</name>
              <bitOffset>16</bitOffset>
              <bitWidth>4</bitWidth>
            </field>
            <field>
              <name>AFRL5</name>
              <bitOffset>20</bitOffset>
              <bitWidth>4</bitWidth>
            </field>
            <field>
              <name>AFRL6</name>
              <bitOffset>24</bitOffset>
              <bitWidth>4</bitWidth>
            </field>
            <field>
              <name>AFRL7</name>
              <bitOffset>28</bitOffset>
              <bitWidth>4</bitWidth>
            </field>
          </fields>
        </register>
        <register>
          <name>AFR.1</name>
          <addressOffset>0x24</addressOffset>
          <size>0x20</size>
          <fields>
            <field>
              <name>AFRH0</name>
              <bitOffset>0</bitOffset>
              <bitWidth>4</bitWidth>
            </field>
            <field>
              <name>AFRH1</name>
              <bitOffset>4</bitOffset>
              <bitWidth>4</bitWidth>
            </field>
            <field>
              <name>AFRH2</name>
              <bitOffset>8</bitOffset>
              <bitWidth>4</bitWidth>
            </field>
            <field>
              <name>AFRH3</name>
              <bitOffset>12</bitOffset>
              <bitWidth>4</bitWidth>
            </field>
            <field>
              <name>AFRH4</name>
              <bitOffset>16</bitOffset>
              <bitWidth>4</bitWidth>
            </field>
            <field>
              <name>AFRH5</name>
              <bitOffset>20</bitOffset>
              <bitWidth>4</bitWidth>
            </field>
            <field>
              <name>AFRH6</name>
              <bitOffset>24</bitOffset>
              <bitWidth>4</bitWidth>
            </field>
            <field>
              <name>AFRH7</name>
              <bitOffset>28</bitOffset>
              <bitWidth>4</bitWidth>
            </field>
          </fields>
        </register>
      </registers>
    </peripheral>
    <peripheral>
      <name>GPIOH</name>
      <baseAddress>0x40021c00</baseAddress>
      <registers>
        <register>
          <name>MODER</name>
          <addressOffset>0x0</addressOffset>
          <size>0x20</size>
          <fields>
            <field>
              <name>MODER0</name>
              <bitOffset>0</bitOffset>
              <bitWidth>2</bitWidth>
            </field>
            <field>
              <name>MODER1</name>
              <bitOffset>2</bitOffset>
              <bitWidth>2</bitWidth>
            </field>
            <field>
              <name>MODER2</name>
              <bitOffset>4</bitOffset>
              <bitWidth>2</bitWidth>
            </field>
            <field>
              <name>MODER3</name>
              <bitOffset>6</bitOffset>
              <bitWidth>2</bitWidth>
            </field>
            <field>
              <name>MODER4</name>
              <bitOffset>8</bitOffset>
              <bitWidth>2</bitWidth>
            </field>
            <field>
              <name>MODER5</name>
              <bitOffset>10</bitOffset>
              <bitWidth>2</bitWidth>
            </field>
            <field>
              <name>MODER6</name>
              <bitOffset>12</bitOffset>
              <bitWidth>2</bitWidth>
            </field>
            <field>
              <name>MODER7</name>
              <bitOffset>14</bitOffset>
              <bitWidth>2</bitWidth>
            </field>
            <field>
              <name>MODER8</name>
              <bitOffset>16</bitOffset>
              <bitWidth>2</bitWidth>
            </field>
            <field>
              <name>MODER9</name>
              <bitOffset>18</bitOffset>
              <bitWidth>2</bitWidth>
            </field>
            <field>
              <name>MODER10</name>
              <bitOffset>20</bitOffset>
              <bitWidth>2</bitWidth>
            </field>
            <field>
              <name>MODER11</name>
              <bitOffset>22</bitOffset>
              <bitWidth>2</bitWidth>
            </field>
            <field>
              <name>MODER12</name>
              <bitOffset>24</bitOffset>
              <bitWidth>2</bitWidth>
            </field>
            <field>
              <name>MODER13</name>
              <bitOffset>26</bitOffset>
              <bitWidth>2</bitWidth>
            </field>
            <field>
              <name>MODER14</name>
              <bitOffset>28</bitOffset>
              <bitWidth>2</bitWidth>
            </field>
            <field>
              <name>MODER15</name>
              <bitOffset>30</bitOffset>
              <bitWidth>2</bitWidth>
            </field>
          </fields>
        </register>
        <register>
          <name>OTYPER</name>
          <addressOffset>0x4</addressOffset>
          <size>0x20</size>
          <fields>
            <field>
              <name>OT0</name>
              <bitOffset>0</bitOffset>
              <bitWidth>1</bitWidth>
            </field>
            <field>
              <name>OT1</name>
              <bitOffset>1</bitOffset>
              <bitWidth>1</bitWidth>
            </field>
            <field>
              <name>OT2</name>
              <bitOffset>2</bitOffset>
              <bitWidth>1</bitWidth>
            </field>
            <field>
              <name>OT3</name>
              <bitOffset>3</bitOffset>
              <bitWidth>1</bitWidth>
            </field>
            <field>
              <name>OT4</name>
              <bitOffset>4</bitOffset>
              <bitWidth>1</bitWidth>
            </field>
            <field>
              <name>OT5</name>
              <bitOffset>5</bitOffset>
              <bitWidth>1</bitWidth>
            </field>
            <field>
              <name>OT6</name>
              <bitOffset>6</bitOffset>
              <bitWidth>1</bitWidth>
            </field>
            <field>
              <name>OT7</name>
              <bitOffset>7</bitOffset>
              <bitWidth>1</bitWidth>
            </field>
            <field>
              <name>OT8</name>
              <bitOffset>8</bitOffset>
              <bitWidth>1</bitWidth>
            </field>
            <field>
              <name>OT9</name>
              <bitOffset>9</bitOffset>
              <bitWidth>1</bitWidth>
            </field>
            <field>
              <name>OT10</name>
              <bitOffset>10</bitOffset>
              <bitWidth>1</bitWidth>
            </field>
            <field>
              <name>OT11</name>
              <bitOffset>11</bitOffset>
              <bitWidth>1</bitWidth>
            </field>
            <field>
              <name>OT12</name>
              <bitOffset>12</bitOffset>
              <bitWidth>1</bitWidth>
            </field>
            <field>
              <name>OT13</name>
              <bitOffset>13</bitOffset>
              <bitWidth>1</bitWidth>
            </field>
            <field>
              <name>OT14</name>
              <bitOffset>14</bitOffset>
              <bitWidth>1</bitWidth>
            </field>
            <field>
              <name>OT15</name>
              <bitOffset>15</bitOffset>
              <bitWidth>1</bitWidth>
            </field>
          </fields>
        </register>
        <register>
          <name>OSPEEDR</name>
          <addressOffset>0x8</addressOffset>
          <size>0x20</size>
          <fields>
            <field>
              <name>OSPEEDR0</name>
              <bitOffset>0</bitOffset>
              <bitWidth>2</bitWidth>
            </field>
            <field>
              <name>OSPEEDR1</name>
              <bitOffset>2</bitOffset>
              <bitWidth>2</bitWidth>
            </field>
            <field>
              <name>OSPEEDR2</name>
              <bitOffset>4</bitOffset>
              <bitWidth>2</bitWidth>
            </field>
            <field>
              <name>OSPEEDR3</name>
              <bitOffset>6</bitOffset>
              <bitWidth>2</bitWidth>
            </field>
            <field>
              <name>OSPEEDR4</name>
              <bitOffset>8</bitOffset>
              <bitWidth>2</bitWidth>
            </field>
            <field>
              <name>OSPEEDR5</name>
              <bitOffset>10</bitOffset>
              <bitWidth>2</bitWidth>
            </field>
            <field>
              <name>OSPEEDR6</name>
              <bitOffset>12</bitOffset>
              <bitWidth>2</bitWidth>
            </field>
            <field>
              <name>OSPEEDR7</name>
              <bitOffset>14</bitOffset>
              <bitWidth>2</bitWidth>
            </field>
            <field>
              <name>OSPEEDR8</name>
              <bitOffset>16</bitOffset>
              <bitWidth>2</bitWidth>
            </field>
            <field>
              <name>OSPEEDR9</name>
              <bitOffset>18</bitOffset>
              <bitWidth>2</bitWidth>
            </field>
            <field>
              <name>OSPEEDR10</name>
              <bitOffset>20</bitOffset>
              <bitWidth>2</bitWidth>
            </field>
            <field>
              <name>OSPEEDR11</name>
              <bitOffset>22</bitOffset>
              <bitWidth>2</bitWidth>
            </field>
            <field>
              <name>OSPEEDR12</name>
              <bitOffset>24</bitOffset>
              <bitWidth>2</bitWidth>
            </field>
            <field>
              <name>OSPEEDR13</name>
              <bitOffset>26</bitOffset>
              <bitWidth>2</bitWidth>
            </field>
            <field>
              <name>OSPEEDR14</name>
              <bitOffset>28</bitOffset>
              <bitWidth>2</bitWidth>
            </field>
            <field>
              <name>OSPEEDR15</name>
              <bitOffset>30</bitOffset>
              <bitWidth>2</bitWidth>
            </field>
          </fields>
        </register>
        <register>
          <name>PUPDR</name>
          <addressOffset>0xc</addressOffset>
          <size>0x20</size>
          <fields>
            <field>
              <name>PUPDR0</name>
              <bitOffset>0</bitOffset>
              <bitWidth>2</bitWidth>
            </field>
            <field>
              <name>PUPDR1</name>
              <bitOffset>2</bitOffset>
              <bitWidth>2</bitWidth>
            </field>
            <field>
              <name>PUPDR2</name>
              <bitOffset>4</bitOffset>
              <bitWidth>2</bitWidth>
            </field>
            <field>
              <name>PUPDR3</name>
              <bitOffset>6</bitOffset>
              <bitWidth>2</bitWidth>
            </field>
            <field>
              <name>PUPDR4</name>
              <bitOffset>8</bitOffset>
              <bitWidth>2</bitWidth>
            </field>
            <field>
              <name>PUPDR5</name>
              <bitOffset>10</bitOffset>
              <bitWidth>2</bitWidth>
            </field>
            <field>
              <name>PUPDR6</name>
              <bitOffset>12</bitOffset>
              <bitWidth>2</bitWidth>
            </field>
            <field>
              <name>PUPDR7</name>
              <bitOffset>14</bitOffset>
              <bitWidth>2</bitWidth>
            </field>
            <field>
              <name>PUPDR8</name>
              <bitOffset>16</bitOffset>
              <bitWidth>2</bitWidth>
            </field>
            <field>
              <name>PUPDR9</name>
              <bitOffset>18</bitOffset>
              <bitWidth>2</bitWidth>
            </field>
            <field>
              <name>PUPDR10</name>
              <bitOffset>20</bitOffset>
              <bitWidth>2</bitWidth>
            </field>
            <field>
              <name>PUPDR11</name>
              <bitOffset>22</bitOffset>
              <bitWidth>2</bitWidth>
            </field>
            <field>
              <name>PUPDR12</name>
              <bitOffset>24</bitOffset>
              <bitWidth>2</bitWidth>
            </field>
            <field>
              <name>PUPDR13</name>
              <bitOffset>26</bitOffset>
              <bitWidth>2</bitWidth>
            </field>
            <field>
              <name>PUPDR14</name>
              <bitOffset>28</bitOffset>
              <bitWidth>2</bitWidth>
            </field>
            <field>
              <name>PUPDR15</name>
              <bitOffset>30</bitOffset>
              <bitWidth>2</bitWidth>
            </field>
          </fields>
        </register>
        <register>
          <name>IDR</name>
          <addressOffset>0x10</addressOffset>
          <size>0x20</size>
          <fields>
            <field>
              <name>ID0</name>
              <bitOffset>0</bitOffset>
              <bitWidth>1</bitWidth>
            </field>
            <field>
              <name>ID1</name>
              <bitOffset>1</bitOffset>
              <bitWidth>1</bitWidth>
            </field>
            <field>
              <name>ID2</name>
              <bitOffset>2</bitOffset>
              <bitWidth>1</bitWidth>
            </field>
            <field>
              <name>ID3</name>
              <bitOffset>3</bitOffset>
              <bitWidth>1</bitWidth>
            </field>
            <field>
              <name>ID4</name>
              <bitOffset>4</bitOffset>
              <bitWidth>1</bitWidth>
            </field>
            <field>
              <name>ID5</name>
              <bitOffset>5</bitOffset>
              <bitWidth>1</bitWidth>
            </field>
            <field>
              <name>ID6</name>
              <bitOffset>6</bitOffset>
              <bitWidth>1</bitWidth>
            </field>
            <field>
              <name>ID7</name>
              <bitOffset>7</bitOffset>
              <bitWidth>1</bitWidth>
            </field>
            <field>
              <name>ID8</name>
              <bitOffset>8</bitOffset>
              <bitWidth>1</bitWidth>
            </field>
            <field>
              <name>ID9</name>
              <bitOffset>9</bitOffset>
              <bitWidth>1</bitWidth>
            </field>
            <field>
              <name>ID10</name>
              <bitOffset>10</bitOffset>
              <bitWidth>1</bitWidth>
            </field>
            <field>
              <name>ID11</name>
              <bitOffset>11</bitOffset>
              <bitWidth>1</bitWidth>
            </field>
            <field>
              <name>ID12</name>
              <bitOffset>12</bitOffset>
              <bitWidth>1</bitWidth>
            </field>
            <field>
              <name>ID13</name>
              <bitOffset>13</bitOffset>
              <bitWidth>1</bitWidth>
            </field>
            <field>
              <name>ID14</name>
              <bitOffset>14</bitOffset>
              <bitWidth>1</bitWidth>
            </field>
            <field>
              <name>ID15</name>
              <bitOffset>15</bitOffset>
              <bitWidth>1</bitWidth>
            </field>
          </fields>
        </register>
        <register>
          <name>ODR</name>
          <addressOffset>0x14</addressOffset>
          <size>0x20</size>
          <fields>
            <field>
              <name>OD0</name>
              <bitOffset>0</bitOffset>
              <bitWidth>1</bitWidth>
            </field>
            <field>
              <name>OD1</name>
              <bitOffset>1</bitOffset>
              <bitWidth>1</bitWidth>
            </field>
            <field>
              <name>OD2</name>
              <bitOffset>2</bitOffset>
              <bitWidth>1</bitWidth>
            </field>
            <field>
              <name>OD3</name>
              <bitOffset>3</bitOffset>
              <bitWidth>1</bitWidth>
            </field>
            <field>
              <name>OD4</name>
              <bitOffset>4</bitOffset>
              <bitWidth>1</bitWidth>
            </field>
            <field>
              <name>OD5</name>
              <bitOffset>5</bitOffset>
              <bitWidth>1</bitWidth>
            </field>
            <field>
              <name>OD6</name>
              <bitOffset>6</bitOffset>
              <bitWidth>1</bitWidth>
            </field>
            <field>
              <name>OD7</name>
              <bitOffset>7</bitOffset>
              <bitWidth>1</bitWidth>
            </field>
            <field>
              <name>OD8</name>
              <bitOffset>8</bitOffset>
              <bitWidth>1</bitWidth>
            </field>
            <field>
              <name>OD9</name>
              <bitOffset>9</bitOffset>
              <bitWidth>1</bitWidth>
            </field>
            <field>
              <name>OD10</name>
              <bitOffset>10</bitOffset>
              <bitWidth>1</bitWidth>
            </field>
            <field>
              <name>OD11</name>
              <bitOffset>11</bitOffset>
              <bitWidth>1</bitWidth>
            </field>
            <field>
              <name>OD12</name>
              <bitOffset>12</bitOffset>
              <bitWidth>1</bitWidth>
            </field>
            <field>
              <name>OD13</name>
              <bitOffset>13</bitOffset>
              <bitWidth>1</bitWidth>
            </field>
            <field>
              <name>OD14</name>
              <bitOffset>14</bitOffset>
              <bitWidth>1</bitWidth>
            </field>
            <field>
              <name>OD15</name>
              <bitOffset>15</bitOffset>
              <bitWidth>1</bitWidth>
            </field>
          </fields>
        </register>
        <register>
          <name>BSRR</name>
          <addressOffset>0x18</addressOffset>
          <size>0x20</size>
          <fields>
            <field>
              <name>BS0</name>
              <bitOffset>0</bitOffset>
              <bitWidth>1</bitWidth>
            </field>
            <field>
              <name>BS1</name>
              <bitOffset>1</bitOffset>
              <bitWidth>1</bitWidth>
            </field>
            <field>
              <name>BS2</name>
              <bitOffset>2</bitOffset>
              <bitWidth>1</bitWidth>
            </field>
            <field>
              <name>BS3</name>
              <bitOffset>3</bitOffset>
              <bitWidth>1</bitWidth>
            </field>
            <field>
              <name>BS4</name>
              <bitOffset>4</bitOffset>
              <bitWidth>1</bitWidth>
            </field>
            <field>
              <name>BS5</name>
              <bitOffset>5</bitOffset>
              <bitWidth>1</bitWidth>
            </field>
            <field>
              <name>BS6</name>
              <bitOffset>6</bitOffset>
              <bitWidth>1</bitWidth>
            </field>
            <field>
              <name>BS7</name>
              <bitOffset>7</bitOffset>
              <bitWidth>1</bitWidth>
            </field>
            <field>
              <name>BS8</name>
              <bitOffset>8</bitOffset>
              <bitWidth>1</bitWidth>
            </field>
            <field>
              <name>BS9</name>
              <bitOffset>9</bitOffset>
              <bitWidth>1</bitWidth>
            </field>
            <field>
              <name>BS10</name>
              <bitOffset>10</bitOffset>
              <bitWidth>1</bitWidth>
            </field>
            <field>
              <name>BS11</name>
              <bitOffset>11</bitOffset>
              <bitWidth>1</bitWidth>
            </field>
            <field>
              <name>BS12</name>
              <bitOffset>12</bitOffset>
              <bitWidth>1</bitWidth>
            </field>
            <field>
              <name>BS13</name>
              <bitOffset>13</bitOffset>
              <bitWidth>1</bitWidth>
            </field>
            <field>
              <name>BS14</name>
              <bitOffset>14</bitOffset>
              <bitWidth>1</bitWidth>
            </field>
            <field>
              <name>BS15</name>
              <bitOffset>15</bitOffset>
              <bitWidth>1</bitWidth>
            </field>
            <field>
              <name>BR0</name>
              <bitOffset>16</bitOffset>
              <bitWidth>1</bitWidth>
            </field>
            <field>
              <name>BR1</name>
              <bitOffset>17</bitOffset>
              <bitWidth>1</bitWidth>
            </field>
            <field>
              <name>BR2</name>
              <bitOffset>18</bitOffset>
              <bitWidth>1</bitWidth>
            </field>
            <field>
              <name>BR3</name>
              <bitOffset>19</bitOffset>
              <bitWidth>1</bitWidth>
            </field>
            <field>
              <name>BR4</name>
              <bitOffset>20</bitOffset>
              <bitWidth>1</bitWidth>
            </field>
            <field>
              <name>BR5</name>
              <bitOffset>21</bitOffset>
              <bitWidth>1</bitWidth>
            </field>
            <field>
              <name>BR6</name>
              <bitOffset>22</bitOffset>
              <bitWidth>1</bitWidth>
            </field>
            <field>
              <name>BR7</name>
              <bitOffset>23</bitOffset>
              <bitWidth>1</bitWidth>
            </field>
            <field>
              <name>BR8</name>
              <bitOffset>24</bitOffset>
              <bitWidth>1</bitWidth>
            </field>
            <field>
              <name>BR9</name>
              <bitOffset>25</bitOffset>
              <bitWidth>1</bitWidth>
            </field>
            <field>
              <name>BR10</name>
              <bitOffset>26</bitOffset>
              <bitWidth>1</bitWidth>
            </field>
            <field>
              <name>BR11</name>
              <bitOffset>27</bitOffset>
              <bitWidth>1</bitWidth>
            </field>
            <field>
              <name>BR12</name>
              <bitOffset>28</bitOffset>
              <bitWidth>1</bitWidth>
            </field>
            <field>
              <name>BR13</name>
              <bitOffset>29</bitOffset>
              <bitWidth>1</bitWidth>
            </field>
            <field>
              <name>BR14</name>
              <bitOffset>30</bitOffset>
              <bitWidth>1</bitWidth>
            </field>
            <field>
              <name>BR15</name>
              <bitOffset>31</bitOffset>
              <bitWidth>1</bitWidth>
            </field>
          </fields>
        </register>
        <register>
          <name>LCKR</name>
          <addressOffset>0x1c</addressOffset>
          <size>0x20</size>
          <fields>
            <field>
              <name>LCK0</name>
              <bitOffset>0</bitOffset>
              <bitWidth>1</bitWidth>
            </field>
            <field>
              <name>LCK1</name>
              <bitOffset>1</bitOffset>
              <bitWidth>1</bitWidth>
            </field>
            <field>
              <name>LCK2</name>
              <bitOffset>2</bitOffset>
              <bitWidth>1</bitWidth>
            </field>
            <field>
              <name>LCK3</name>
              <bitOffset>3</bitOffset>
              <bitWidth>1</bitWidth>
            </field>
            <field>
              <name>LCK4</name>
              <bitOffset>4</bitOffset>
              <bitWidth>1</bitWidth>
            </field>
            <field>
              <name>LCK5</name>
              <bitOffset>5</bitOffset>
              <bitWidth>1</bitWidth>
            </field>
            <field>
              <name>LCK6</name>
              <bitOffset>6</bitOffset>
              <bitWidth>1</bitWidth>
            </field>
            <field>
              <name>LCK7</name>
              <bitOffset>7</bitOffset>
              <bitWidth>1</bitWidth>
            </field>
            <field>
              <name>LCK8</name>
              <bitOffset>8</bitOffset>
              <bitWidth>1</bitWidth>
            </field>
            <field>
              <name>LCK9</name>
              <bitOffset>9</bitOffset>
              <bitWidth>1</bitWidth>
            </field>
            <field>
              <name>LCK10</name>
              <bitOffset>10</bitOffset>
              <bitWidth>1</bitWidth>
            </field>
            <field>
              <name>LCK11</name>
              <bitOffset>11</bitOffset>
              <bitWidth>1</bitWidth>
            </field>
            <field>
              <name>LCK12</name>
              <bitOffset>12</bitOffset>
              <bitWidth>1</bitWidth>
            </field>
            <field>
              <name>LCK13</name>
              <bitOffset>13</bitOffset>
              <bitWidth>1</bitWidth>
            </field>
            <field>
              <name>LCK14</name>
              <bitOffset>14</bitOffset>
              <bitWidth>1</bitWidth>
            </field>
            <field>
              <name>LCK15</name>
              <bitOffset>15</bitOffset>
              <bitWidth>1</bitWidth>
            </field>
            <field>
              <name>LCKK</name>
              <bitOffset>16</bitOffset>
              <bitWidth>1</bitWidth>
            </field>
          </fields>
        </register>
        <register>
          <name>AFR.0</name>
          <addressOffset>0x20</addressOffset>
          <size>0x20</size>
          <fields>
            <field>
              <name>AFRL0</name>
              <bitOffset>0</bitOffset>
              <bitWidth>4</bitWidth>
            </field>
            <field>
              <name>AFRL1</name>
              <bitOffset>4</bitOffset>
              <bitWidth>4</bitWidth>
            </field>
            <field>
              <name>AFRL2</name>
              <bitOffset>8</bitOffset>
              <bitWidth>4</bitWidth>
            </field>
            <field>
              <name>AFRL3</name>
              <bitOffset>12</bitOffset>
              <bitWidth>4</bitWidth>
            </field>
            <field>
              <name>AFRL4</name>
              <bitOffset>16</bitOffset>
              <bitWidth>4</bitWidth>
            </field>
            <field>
              <name>AFRL5</name>
              <bitOffset>20</bitOffset>
              <bitWidth>4</bitWidth>
            </field>
            <field>
              <name>AFRL6</name>
              <bitOffset>24</bitOffset>
              <bitWidth>4</bitWidth>
            </field>
            <field>
              <name>AFRL7</name>
              <bitOffset>28</bitOffset>
              <bitWidth>4</bitWidth>
            </field>
          </fields>
        </register>
        <register>
          <name>AFR.1</name>
          <addressOffset>0x24</addressOffset>
          <size>0x20</size>
          <fields>
            <field>
              <name>AFRH0</name>
              <bitOffset>0</bitOffset>
              <bitWidth>4</bitWidth>
            </field>
            <field>
              <name>AFRH1</name>
              <bitOffset>4</bitOffset>
              <bitWidth>4</bitWidth>
            </field>
            <field>
              <name>AFRH2</name>
              <bitOffset>8</bitOffset>
              <bitWidth>4</bitWidth>
            </field>
            <field>
              <name>AFRH3</name>
              <bitOffset>12</bitOffset>
              <bitWidth>4</bitWidth>
            </field>
            <field>
              <name>AFRH4</name>
              <bitOffset>16</bitOffset>
              <bitWidth>4</bitWidth>
            </field>
            <field>
              <name>AFRH5</name>
              <bitOffset>20</bitOffset>
              <bitWidth>4</bitWidth>
            </field>
            <field>
              <name>AFRH6</name>
              <bitOffset>24</bitOffset>
              <bitWidth>4</bitWidth>
            </field>
            <field>
              <name>AFRH7</name>
              <bitOffset>28</bitOffset>
              <bitWidth>4</bitWidth>
            </field>
          </fields>
        </register>
      </registers>
    </peripheral>
    <peripheral>
      <name>GPIOI</name>
      <baseAddress>0x40022000</baseAddress>
      <registers>
        <register>
          <name>MODER</name>
          <addressOffset>0x0</addressOffset>
          <size>0x20</size>
          <fields>
            <field>
              <name>MODER0</name>
              <bitOffset>0</bitOffset>
              <bitWidth>2</bitWidth>
            </field>
            <field>
              <name>MODER1</name>
              <bitOffset>2</bitOffset>
              <bitWidth>2</bitWidth>
            </field>
            <field>
              <name>MODER2</name>
              <bitOffset>4</bitOffset>
              <bitWidth>2</bitWidth>
            </field>
            <field>
              <name>MODER3</name>
              <bitOffset>6</bitOffset>
              <bitWidth>2</bitWidth>
            </field>
            <field>
              <name>MODER4</name>
              <bitOffset>8</bitOffset>
              <bitWidth>2</bitWidth>
            </field>
            <field>
              <name>MODER5</name>
              <bitOffset>10</bitOffset>
              <bitWidth>2</bitWidth>
            </field>
            <field>
              <name>MODER6</name>
              <bitOffset>12</bitOffset>
              <bitWidth>2</bitWidth>
            </field>
            <field>
              <name>MODER7</name>
              <bitOffset>14</bitOffset>
              <bitWidth>2</bitWidth>
            </field>
            <field>
              <name>MODER8</name>
              <bitOffset>16</bitOffset>
              <bitWidth>2</bitWidth>
            </field>
            <field>
              <name>MODER9</name>
              <bitOffset>18</bitOffset>
              <bitWidth>2</bitWidth>
            </field>
            <field>
              <name>MODER10</name>
              <bitOffset>20</bitOffset>
              <bitWidth>2</bitWidth>
            </field>
            <field>
              <name>MODER11</name>
              <bitOffset>22</bitOffset>
              <bitWidth>2</bitWidth>
            </field>
            <field>
              <name>MODER12</name>
              <bitOffset>24</bitOffset>
              <bitWidth>2</bitWidth>
            </field>
            <field>
              <name>MODER13</name>
              <bitOffset>26</bitOffset>
              <bitWidth>2</bitWidth>
            </field>
            <field>
              <name>MODER14</name>
              <bitOffset>28</bitOffset>
              <bitWidth>2</bitWidth>
            </field>
            <field>
              <name>MODER15</name>
              <bitOffset>30</bitOffset>
              <bitWidth>2</bitWidth>
            </field>
          </fields>
        </register>
        <register>
          <name>OTYPER</name>
          <addressOffset>0x4</addressOffset>
          <size>0x20</size>
          <fields>
            <field>
              <name>OT0</name>
              <bitOffset>0</bitOffset>
              <bitWidth>1</bitWidth>
            </field>
            <field>
              <name>OT1</name>
              <bitOffset>1</bitOffset>
              <bitWidth>1</bitWidth>
            </field>
            <field>
              <name>OT2</name>
              <bitOffset>2</bitOffset>
              <bitWidth>1</bitWidth>
            </field>
            <field>
              <name>OT3</name>
              <bitOffset>3</bitOffset>
              <bitWidth>1</bitWidth>
            </field>
            <field>
              <name>OT4</name>
              <bitOffset>4</bitOffset>
              <bitWidth>1</bitWidth>
            </field>
            <field>
              <name>OT5</name>
              <bitOffset>5</bitOffset>
              <bitWidth>1</bitWidth>
            </field>
            <field>
              <name>OT6</name>
              <bitOffset>6</bitOffset>
              <bitWidth>1</bitWidth>
            </field>
            <field>
              <name>OT7</name>
              <bitOffset>7</bitOffset>
              <bitWidth>1</bitWidth>
            </field>
            <field>
              <name>OT8</name>
              <bitOffset>8</bitOffset>
              <bitWidth>1</bitWidth>
            </field>
            <field>
              <name>OT9</name>
              <bitOffset>9</bitOffset>
              <bitWidth>1</bitWidth>
            </field>
            <field>
              <name>OT10</name>
              <bitOffset>10</bitOffset>
              <bitWidth>1</bitWidth>
            </field>
            <field>
              <name>OT11</name>
              <bitOffset>11</bitOffset>
              <bitWidth>1</bitWidth>
            </field>
            <field>
              <name>OT12</name>
              <bitOffset>12</bitOffset>
              <bitWidth>1</bitWidth>
            </field>
            <field>
              <name>OT13</name>
              <bitOffset>13</bitOffset>
              <bitWidth>1</bitWidth>
            </field>
            <field>
              <name>OT14</name>
              <bitOffset>14</bitOffset>
              <bitWidth>1</bitWidth>
            </field>
            <field>
              <name>OT15</name>
              <bitOffset>15</bitOffset>
              <bitWidth>1</bitWidth>
            </field>
          </fields>
        </register>
        <register>
          <name>OSPEEDR</name>
          <addressOffset>0x8</addressOffset>
          <size>0x20</size>
          <fields>
            <field>
              <name>OSPEEDR0</name>
              <bitOffset>0</bitOffset>
              <bitWidth>2</bitWidth>
            </field>
            <field>
              <name>OSPEEDR1</name>
              <bitOffset>2</bitOffset>
              <bitWidth>2</bitWidth>
            </field>
            <field>
              <name>OSPEEDR2</name>
              <bitOffset>4</bitOffset>
              <bitWidth>2</bitWidth>
            </field>
            <field>
              <name>OSPEEDR3</name>
              <bitOffset>6</bitOffset>
              <bitWidth>2</bitWidth>
            </field>
            <field>
              <name>OSPEEDR4</name>
              <bitOffset>8</bitOffset>
              <bitWidth>2</bitWidth>
            </field>
            <field>
              <name>OSPEEDR5</name>
              <bitOffset>10</bitOffset>
              <bitWidth>2</bitWidth>
            </field>
            <field>
              <name>OSPEEDR6</name>
              <bitOffset>12</bitOffset>
              <bitWidth>2</bitWidth>
            </field>
            <field>
              <name>OSPEEDR7</name>
              <bitOffset>14</bitOffset>
              <bitWidth>2</bitWidth>
            </field>
            <field>
              <name>OSPEEDR8</name>
              <bitOffset>16</bitOffset>
              <bitWidth>2</bitWidth>
            </field>
            <field>
              <name>OSPEEDR9</name>
              <bitOffset>18</bitOffset>
              <bitWidth>2</bitWidth>
            </field>
            <field>
              <name>OSPEEDR10</name>
              <bitOffset>20</bitOffset>
              <bitWidth>2</bitWidth>
            </field>
            <field>
              <name>OSPEEDR11</name>
              <bitOffset>22</bitOffset>
              <bitWidth>2</bitWidth>
            </field>
            <field>
              <name>OSPEEDR12</name>
              <bitOffset>24</bitOffset>
              <bitWidth>2</bitWidth>
            </field>
            <field>
              <name>OSPEEDR13</name>
              <bitOffset>26</bitOffset>
              <bitWidth>2</bitWidth>
            </field>
            <field>
              <name>OSPEEDR14</name>
              <bitOffset>28</bitOffset>
              <bitWidth>2</bitWidth>
            </field>
            <field>
              <name>OSPEEDR15</name>
              <bitOffset>30</bitOffset>
              <bitWidth>2</bitWidth>
            </field>
          </fields>
        </register>
        <register>
          <name>PUPDR</name>
          <addressOffset>0xc</addressOffset>
          <size>0x20</size>
          <fields>
            <field>
              <name>PUPDR0</name>
              <bitOffset>0</bitOffset>
              <bitWidth>2</bitWidth>
            </field>
            <field>
              <name>PUPDR1</name>
              <bitOffset>2</bitOffset>
              <bitWidth>2</bitWidth>
            </field>
            <field>
              <name>PUPDR2</name>
              <bitOffset>4</bitOffset>
              <bitWidth>2</bitWidth>
            </field>
            <field>
              <name>PUPDR3</name>
              <bitOffset>6</bitOffset>
              <bitWidth>2</bitWidth>
            </field>
            <field>
              <name>PUPDR4</name>
              <bitOffset>8</bitOffset>
              <bitWidth>2</bitWidth>
            </field>
            <field>
              <name>PUPDR5</name>
              <bitOffset>10</bitOffset>
              <bitWidth>2</bitWidth>
            </field>
            <field>
              <name>PUPDR6</name>
              <bitOffset>12</bitOffset>
              <bitWidth>2</bitWidth>
            </field>
            <field>
              <name>PUPDR7</name>
              <bitOffset>14</bitOffset>
              <bitWidth>2</bitWidth>
            </field>
            <field>
              <name>PUPDR8</name>
              <bitOffset>16</bitOffset>
              <bitWidth>2</bitWidth>
            </field>
            <field>
              <name>PUPDR9</name>
              <bitOffset>18</bitOffset>
              <bitWidth>2</bitWidth>
            </field>
            <field>
              <name>PUPDR10</name>
              <bitOffset>20</bitOffset>
              <bitWidth>2</bitWidth>
            </field>
            <field>
              <name>PUPDR11</name>
              <bitOffset>22</bitOffset>
              <bitWidth>2</bitWidth>
            </field>
            <field>
              <name>PUPDR12</name>
              <bitOffset>24</bitOffset>
              <bitWidth>2</bitWidth>
            </field>
            <field>
              <name>PUPDR13</name>
              <bitOffset>26</bitOffset>
              <bitWidth>2</bitWidth>
            </field>
            <field>
              <name>PUPDR14</name>
              <bitOffset>28</bitOffset>
              <bitWidth>2</bitWidth>
            </field>
            <field>
              <name>PUPDR15</name>
              <bitOffset>30</bitOffset>
              <bitWidth>2</bitWidth>
            </field>
          </fields>
        </register>
        <register>
          <name>IDR</name>
          <addressOffset>0x10</addressOffset>
          <size>0x20</size>
          <fields>
            <field>
              <name>ID0</name>
              <bitOffset>0</bitOffset>
              <bitWidth>1</bitWidth>
            </field>
            <field>
              <name>ID1</name>
              <bitOffset>1</bitOffset>
              <bitWidth>1</bitWidth>
            </field>
            <field>
              <name>ID2</name>
              <bitOffset>2</bitOffset>
              <bitWidth>1</bitWidth>
            </field>
            <field>
              <name>ID3</name>
              <bitOffset>3</bitOffset>
              <bitWidth>1</bitWidth>
            </field>
            <field>
              <name>ID4</name>
              <bitOffset>4</bitOffset>
              <bitWidth>1</bitWidth>
            </field>
            <field>
              <name>ID5</name>
              <bitOffset>5</bitOffset>
              <bitWidth>1</bitWidth>
            </field>
            <field>
              <name>ID6</name>
              <bitOffset>6</bitOffset>
              <bitWidth>1</bitWidth>
            </field>
            <field>
              <name>ID7</name>
              <bitOffset>7</bitOffset>
              <bitWidth>1</bitWidth>
            </field>
            <field>
              <name>ID8</name>
              <bitOffset>8</bitOffset>
              <bitWidth>1</bitWidth>
            </field>
            <field>
              <name>ID9</name>
              <bitOffset>9</bitOffset>
              <bitWidth>1</bitWidth>
            </field>
            <field>
              <name>ID10</name>
              <bitOffset>10</bitOffset>
              <bitWidth>1</bitWidth>
            </field>
            <field>
              <name>ID11</name>
              <bitOffset>11</bitOffset>
              <bitWidth>1</bitWidth>
            </field>
            <field>
              <name>ID12</name>
              <bitOffset>12</bitOffset>
              <bitWidth>1</bitWidth>
            </field>
            <field>
              <name>ID13</name>
              <bitOffset>13</bitOffset>
              <bitWidth>1</bitWidth>
            </field>
            <field>
              <name>ID14</name>
              <bitOffset>14</bitOffset>
              <bitWidth>1</bitWidth>
            </field>
            <field>
              <name>ID15</name>
              <bitOffset>15</bitOffset>
              <bitWidth>1</bitWidth>
            </field>
          </fields>
        </register>
        <register>
          <name>ODR</name>
          <addressOffset>0x14</addressOffset>
          <size>0x20</size>
          <fields>
            <field>
              <name>OD0</name>
              <bitOffset>0</bitOffset>
              <bitWidth>1</bitWidth>
            </field>
            <field>
              <name>OD1</name>
              <bitOffset>1</bitOffset>
              <bitWidth>1</bitWidth>
            </field>
            <field>
              <name>OD2</name>
              <bitOffset>2</bitOffset>
              <bitWidth>1</bitWidth>
            </field>
            <field>
              <name>OD3</name>
              <bitOffset>3</bitOffset>
              <bitWidth>1</bitWidth>
            </field>
            <field>
              <name>OD4</name>
              <bitOffset>4</bitOffset>
              <bitWidth>1</bitWidth>
            </field>
            <field>
              <name>OD5</name>
              <bitOffset>5</bitOffset>
              <bitWidth>1</bitWidth>
            </field>
            <field>
              <name>OD6</name>
              <bitOffset>6</bitOffset>
              <bitWidth>1</bitWidth>
            </field>
            <field>
              <name>OD7</name>
              <bitOffset>7</bitOffset>
              <bitWidth>1</bitWidth>
            </field>
            <field>
              <name>OD8</name>
              <bitOffset>8</bitOffset>
              <bitWidth>1</bitWidth>
            </field>
            <field>
              <name>OD9</name>
              <bitOffset>9</bitOffset>
              <bitWidth>1</bitWidth>
            </field>
            <field>
              <name>OD10</name>
              <bitOffset>10</bitOffset>
              <bitWidth>1</bitWidth>
            </field>
            <field>
              <name>OD11</name>
              <bitOffset>11</bitOffset>
              <bitWidth>1</bitWidth>
            </field>
            <field>
              <name>OD12</name>
              <bitOffset>12</bitOffset>
              <bitWidth>1</bitWidth>
            </field>
            <field>
              <name>OD13</name>
              <bitOffset>13</bitOffset>
              <bitWidth>1</bitWidth>
            </field>
            <field>
              <name>OD14</name>
              <bitOffset>14</bitOffset>
              <bitWidth>1</bitWidth>
            </field>
            <field>
              <name>OD15</name>
              <bitOffset>15</bitOffset>
              <bitWidth>1</bitWidth>
            </field>
          </fields>
        </register>
        <register>
          <name>BSRR</name>
          <addressOffset>0x18</addressOffset>
          <size>0x20</size>
          <fields>
            <field>
              <name>BS0</name>
              <bitOffset>0</bitOffset>
              <bitWidth>1</bitWidth>
            </field>
            <field>
              <name>BS1</name>
              <bitOffset>1</bitOffset>
              <bitWidth>1</bitWidth>
            </field>
            <field>
              <name>BS2</name>
              <bitOffset>2</bitOffset>
              <bitWidth>1</bitWidth>
            </field>
            <field>
              <name>BS3</name>
              <bitOffset>3</bitOffset>
              <bitWidth>1</bitWidth>
            </field>
            <field>
              <name>BS4</name>
              <bitOffset>4</bitOffset>
              <bitWidth>1</bitWidth>
            </field>
            <field>
              <name>BS5</name>
              <bitOffset>5</bitOffset>
              <bitWidth>1</bitWidth>
            </field>
            <field>
              <name>BS6</name>
              <bitOffset>6</bitOffset>
              <bitWidth>1</bitWidth>
            </field>
            <field>
              <name>BS7</name>
              <bitOffset>7</bitOffset>
              <bitWidth>1</bitWidth>
            </field>
            <field>
              <name>BS8</name>
              <bitOffset>8</bitOffset>
              <bitWidth>1</bitWidth>
            </field>
            <field>
              <name>BS9</name>
              <bitOffset>9</bitOffset>
              <bitWidth>1</bitWidth>
            </field>
            <field>
              <name>BS10</name>
              <bitOffset>10</bitOffset>
              <bitWidth>1</bitWidth>
            </field>
            <field>
              <name>BS11</name>
              <bitOffset>11</bitOffset>
              <bitWidth>1</bitWidth>
            </field>
            <field>
              <name>BS12</name>
              <bitOffset>12</bitOffset>
              <bitWidth>1</bitWidth>
            </field>
            <field>
              <name>BS13</name>
              <bitOffset>13</bitOffset>
              <bitWidth>1</bitWidth>
            </field>
            <field>
              <name>BS14</name>
              <bitOffset>14</bitOffset>
              <bitWidth>1</bitWidth>
            </field>
            <field>
              <name>BS15</name>
              <bitOffset>15</bitOffset>
              <bitWidth>1</bitWidth>
            </field>
            <field>
              <name>BR0</name>
              <bitOffset>16</bitOffset>
              <bitWidth>1</bitWidth>
            </field>
            <field>
              <name>BR1</name>
              <bitOffset>17</bitOffset>
              <bitWidth>1</bitWidth>
            </field>
            <field>
              <name>BR2</name>
              <bitOffset>18</bitOffset>
              <bitWidth>1</bitWidth>
            </field>
            <field>
              <name>BR3</name>
              <bitOffset>19</bitOffset>
              <bitWidth>1</bitWidth>
            </field>
            <field>
              <name>BR4</name>
              <bitOffset>20</bitOffset>
              <bitWidth>1</bitWidth>
            </field>
            <field>
              <name>BR5</name>
              <bitOffset>21</bitOffset>
              <bitWidth>1</bitWidth>
            </field>
            <field>
              <name>BR6</name>
              <bitOffset>22</bitOffset>
              <bitWidth>1</bitWidth>
            </field>
            <field>
              <name>BR7</name>
              <bitOffset>23</bitOffset>
              <bitWidth>1</bitWidth>
            </field>
            <field>
              <name>BR8</name>
              <bitOffset>24</bitOffset>
              <bitWidth>1</bitWidth>
            </field>
            <field>
              <name>BR9</name>
              <bitOffset>25</bitOffset>
              <bitWidth>1</bitWidth>
            </field>
            <field>
              <name>BR10</name>
              <bitOffset>26</bitOffset>
              <bitWidth>1</bitWidth>
            </field>
            <field>
              <name>BR11</name>
              <bitOffset>27</bitOffset>
              <bitWidth>1</bitWidth>
            </field>
            <field>
              <name>BR12</name>
              <bitOffset>28</bitOffset>
              <bitWidth>1</bitWidth>
            </field>
            <field>
              <name>BR13</name>
              <bitOffset>29</bitOffset>
              <bitWidth>1</bitWidth>
            </field>
            <field>
              <name>BR14</name>
              <bitOffset>30</bitOffset>
              <bitWidth>1</bitWidth>
            </field>
            <field>
              <name>BR15</name>
              <bitOffset>31</bitOffset>
              <bitWidth>1</bitWidth>
            </field>
          </fields>
        </register>
        <register>
          <name>LCKR</name>
          <addressOffset>0x1c</addressOffset>
          <size>0x20</size>
          <fields>
            <field>
              <name>LCK0</name>
              <bitOffset>0</bitOffset>
              <bitWidth>1</bitWidth>
            </field>
            <field>
              <name>LCK1</name>
              <bitOffset>1</bitOffset>
              <bitWidth>1</bitWidth>
            </field>
            <field>
              <name>LCK2</name>
              <bitOffset>2</bitOffset>
              <bitWidth>1</bitWidth>
            </field>
            <field>
              <name>LCK3</name>
              <bitOffset>3</bitOffset>
              <bitWidth>1</bitWidth>
            </field>
            <field>
              <name>LCK4</name>
              <bitOffset>4</bitOffset>
              <bitWidth>1</bitWidth>
            </field>
            <field>
              <name>LCK5</name>
              <bitOffset>5</bitOffset>
              <bitWidth>1</bitWidth>
            </field>
            <field>
              <name>LCK6</name>
              <bitOffset>6</bitOffset>
              <bitWidth>1</bitWidth>
            </field>
            <field>
              <name>LCK7</name>
              <bitOffset>7</bitOffset>
              <bitWidth>1</bitWidth>
            </field>
            <field>
              <name>LCK8</name>
              <bitOffset>8</bitOffset>
              <bitWidth>1</bitWidth>
            </field>
            <field>
              <name>LCK9</name>
              <bitOffset>9</bitOffset>
              <bitWidth>1</bitWidth>
            </field>
            <field>
              <name>LCK10</name>
              <bitOffset>10</bitOffset>
              <bitWidth>1</bitWidth>
            </field>
            <field>
              <name>LCK11</name>
              <bitOffset>11</bitOffset>
              <bitWidth>1</bitWidth>
            </field>
            <field>
              <name>LCK12</name>
              <bitOffset>12</bitOffset>
              <bitWidth>1</bitWidth>
            </field>
            <field>
              <name>LCK13</name>
              <bitOffset>13</bitOffset>
              <bitWidth>1</bitWidth>
            </field>
            <field>
              <name>LCK14</name>
              <bitOffset>14</bitOffset>
              <bitWidth>1</bitWidth>
            </field>
            <field>
              <name>LCK15</name>
              <bitOffset>15</bitOffset>
              <bitWidth>1</bitWidth>
            </field>
            <field>
              <name>LCKK</name>
              <bitOffset>16</bitOffset>
              <bitWidth>1</bitWidth>
            </field>
          </fields>
        </register>
        <register>
          <name>AFR.0</name>
          <addressOffset>0x20</addressOffset>
          <size>0x20</size>
          <fields>
            <field>
              <name>AFRL0</name>
              <bitOffset>0</bitOffset>
              <bitWidth>4</bitWidth>
            </field>
            <field>
              <name>AFRL1</name>
              <bitOffset>4</bitOffset>
              <bitWidth>4</bitWidth>
            </field>
            <field>
              <name>AFRL2</name>
              <bitOffset>8</bitOffset>
              <bitWidth>4</bitWidth>
            </field>
            <field>
              <name>AFRL3</name>
              <bitOffset>12</bitOffset>
              <bitWidth>4</bitWidth>
            </field>
            <field>
              <name>AFRL4</name>
              <bitOffset>16</bitOffset>
              <bitWidth>4</bitWidth>
            </field>
            <field>
              <name>AFRL5</name>
              <bitOffset>20</bitOffset>
              <bitWidth>4</bitWidth>
            </field>
            <field>
              <name>AFRL6</name>
              <bitOffset>24</bitOffset>
              <bitWidth>4</bitWidth>
            </field>
            <field>
              <name>AFRL7</name>
              <bitOffset>28</bitOffset>
              <bitWidth>4</bitWidth>
            </field>
          </fields>
        </register>
        <register>
          <name>AFR.1</name>
          <addressOffset>0x24</addressOffset>
          <size>0x20</size>
          <fields>
            <field>
              <name>AFRH0</name>
              <bitOffset>0</bitOffset>
              <bitWidth>4</bitWidth>
            </field>
            <field>
              <name>AFRH1</name>
              <bitOffset>4</bitOffset>
              <bitWidth>4</bitWidth>
            </field>
            <field>
              <name>AFRH2</name>
              <bitOffset>8</bitOffset>
              <bitWidth>4</bitWidth>
            </field>
            <field>
              <name>AFRH3</name>
              <bitOffset>12</bitOffset>
              <bitWidth>4</bitWidth>
            </field>
            <field>
              <name>AFRH4</name>
              <bitOffset>16</bitOffset>
              <bitWidth>4</bitWidth>
            </field>
            <field>
              <name>AFRH5</name>
              <bitOffset>20</bitOffset>
              <bitWidth>4</bitWidth>
            </field>
            <field>
              <name>AFRH6</name>
              <bitOffset>24</bitOffset>
              <bitWidth>4</bitWidth>
            </field>
            <field>
              <name>AFRH7</name>
              <bitOffset>28</bitOffset>
              <bitWidth>4</bitWidth>
            </field>
          </fields>
        </register>
      </registers>
    </peripheral>
    <peripheral>
      <name>GPIOJ</name>
      <baseAddress>0x40022400</baseAddress>
      <registers>
        <register>
          <name>MODER</name>
          <addressOffset>0x0</addressOffset>
          <size>0x20</size>
          <fields>
            <field>
              <name>MODER0</name>
              <bitOffset>0</bitOffset>
              <bitWidth>2</bitWidth>
            </field>
            <field>
              <name>MODER1</name>
              <bitOffset>2</bitOffset>
              <bitWidth>2</bitWidth>
            </field>
            <field>
              <name>MODER2</name>
              <bitOffset>4</bitOffset>
              <bitWidth>2</bitWidth>
            </field>
            <field>
              <name>MODER3</name>
              <bitOffset>6</bitOffset>
              <bitWidth>2</bitWidth>
            </field>
            <field>
              <name>MODER4</name>
              <bitOffset>8</bitOffset>
              <bitWidth>2</bitWidth>
            </field>
            <field>
              <name>MODER5</name>
              <bitOffset>10</bitOffset>
              <bitWidth>2</bitWidth>
            </field>
            <field>
              <name>MODER6</name>
              <bitOffset>12</bitOffset>
              <bitWidth>2</bitWidth>
            </field>
            <field>
              <name>MODER7</name>
              <bitOffset>14</bitOffset>
              <bitWidth>2</bitWidth>
            </field>
            <field>
              <name>MODER8</name>
              <bitOffset>16</bitOffset>
              <bitWidth>2</bitWidth>
            </field>
            <field>
              <name>MODER9</name>
              <bitOffset>18</bitOffset>
              <bitWidth>2</bitWidth>
            </field>
            <field>
              <name>MODER10</name>
              <bitOffset>20</bitOffset>
              <bitWidth>2</bitWidth>
            </field>
            <field>
              <name>MODER11</name>
              <bitOffset>22</bitOffset>
              <bitWidth>2</bitWidth>
            </field>
            <field>
              <name>MODER12</name>
              <bitOffset>24</bitOffset>
              <bitWidth>2</bitWidth>
            </field>
            <field>
              <name>MODER13</name>
              <bitOffset>26</bitOffset>
              <bitWidth>2</bitWidth>
            </field>
            <field>
              <name>MODER14</name>
              <bitOffset>28</bitOffset>
              <bitWidth>2</bitWidth>
            </field>
            <field>
              <name>MODER15</name>
              <bitOffset>30</bitOffset>
              <bitWidth>2</bitWidth>
            </field>
          </fields>
        </register>
        <register>
          <name>OTYPER</name>
          <addressOffset>0x4</addressOffset>
          <size>0x20</size>
          <fields>
            <field>
              <name>OT0</name>
              <bitOffset>0</bitOffset>
              <bitWidth>1</bitWidth>
            </field>
            <field>
              <name>OT1</name>
              <bitOffset>1</bitOffset>
              <bitWidth>1</bitWidth>
            </field>
            <field>
              <name>OT2</name>
              <bitOffset>2</bitOffset>
              <bitWidth>1</bitWidth>
            </field>
            <field>
              <name>OT3</name>
              <bitOffset>3</bitOffset>
              <bitWidth>1</bitWidth>
            </field>
            <field>
              <name>OT4</name>
              <bitOffset>4</bitOffset>
              <bitWidth>1</bitWidth>
            </field>
            <field>
              <name>OT5</name>
              <bitOffset>5</bitOffset>
              <bitWidth>1</bitWidth>
            </field>
            <field>
              <name>OT6</name>
              <bitOffset>6</bitOffset>
              <bitWidth>1</bitWidth>
            </field>
            <field>
              <name>OT7</name>
              <bitOffset>7</bitOffset>
              <bitWidth>1</bitWidth>
            </field>
            <field>
              <name>OT8</name>
              <bitOffset>8</bitOffset>
              <bitWidth>1</bitWidth>
            </field>
            <field>
              <name>OT9</name>
              <bitOffset>9</bitOffset>
              <bitWidth>1</bitWidth>
            </field>
            <field>
              <name>OT10</name>
              <bitOffset>10</bitOffset>
              <bitWidth>1</bitWidth>
            </field>
            <field>
              <name>OT11</name>
              <bitOffset>11</bitOffset>
              <bitWidth>1</bitWidth>
            </field>
            <field>
              <name>OT12</name>
              <bitOffset>12</bitOffset>
              <bitWidth>1</bitWidth>
            </field>
            <field>
              <name>OT13</name>
              <bitOffset>13</bitOffset>
              <bitWidth>1</bitWidth>
            </field>
            <field>
              <name>OT14</name>
              <bitOffset>14</bitOffset>
              <bitWidth>1</bitWidth>
            </field>
            <field>
              <name>OT15</name>
              <bitOffset>15</bitOffset>
              <bitWidth>1</bitWidth>
            </field>
          </fields>
        </register>
        <register>
          <name>OSPEEDR</name>
          <addressOffset>0x8</addressOffset>
          <size>0x20</size>
          <fields>
            <field>
              <name>OSPEEDR0</name>
              <bitOffset>0</bitOffset>
              <bitWidth>2</bitWidth>
            </field>
            <field>
              <name>OSPEEDR1</name>
              <bitOffset>2</bitOffset>
              <bitWidth>2</bitWidth>
            </field>
            <field>
              <name>OSPEEDR2</name>
              <bitOffset>4</bitOffset>
              <bitWidth>2</bitWidth>
            </field>
            <field>
              <name>OSPEEDR3</name>
              <bitOffset>6</bitOffset>
              <bitWidth>2</bitWidth>
            </field>
            <field>
              <name>OSPEEDR4</name>
              <bitOffset>8</bitOffset>
              <bitWidth>2</bitWidth>
            </field>
            <field>
              <name>OSPEEDR5</name>
              <bitOffset>10</bitOffset>
              <bitWidth>2</bitWidth>
            </field>
            <field>
              <name>OSPEEDR6</name>
              <bitOffset>12</bitOffset>
              <bitWidth>2</bitWidth>
            </field>
            <field>
              <name>OSPEEDR7</name>
              <bitOffset>14</bitOffset>
              <bitWidth>2</bitWidth>
            </field>
            <field>
              <name>OSPEEDR8</name>
              <bitOffset>16</bitOffset>
              <bitWidth>2</bitWidth>
            </field>
            <field>
              <name>OSPEEDR9</name>
              <bitOffset>18</bitOffset>
              <bitWidth>2</bitWidth>
            </field>
            <field>
              <name>OSPEEDR10</name>
              <bitOffset>20</bitOffset>
              <bitWidth>2</bitWidth>
            </field>
            <field>
              <name>OSPEEDR11</name>
              <bitOffset>22</bitOffset>
              <bitWidth>2</bitWidth>
            </field>
            <field>
              <name>OSPEEDR12</name>
              <bitOffset>24</bitOffset>
              <bitWidth>2</bitWidth>
            </field>
            <field>
              <name>OSPEEDR13</name>
              <bitOffset>26</bitOffset>
              <bitWidth>2</bitWidth>
            </field>
            <field>
              <name>OSPEEDR14</name>
              <bitOffset>28</bitOffset>
              <bitWidth>2</bitWidth>
            </field>
            <field>
              <name>OSPEEDR15</name>
              <bitOffset>30</bitOffset>
              <bitWidth>2</bitWidth>
            </field>
          </fields>
        </register>
        <register>
          <name>PUPDR</name>
          <addressOffset>0xc</addressOffset>
          <size>0x20</size>
          <fields>
            <field>
              <name>PUPDR0</name>
              <bitOffset>0</bitOffset>
              <bitWidth>2</bitWidth>
            </field>
            <field>
              <name>PUPDR1</name>
              <bitOffset>2</bitOffset>
              <bitWidth>2</bitWidth>
            </field>
            <field>
              <name>PUPDR2</name>
              <bitOffset>4</bitOffset>
              <bitWidth>2</bitWidth>
            </field>
            <field>
              <name>PUPDR3</name>
              <bitOffset>6</bitOffset>
              <bitWidth>2</bitWidth>
            </field>
            <field>
              <name>PUPDR4</name>
              <bitOffset>8</bitOffset>
              <bitWidth>2</bitWidth>
            </field>
            <field>
              <name>PUPDR5</name>
              <bitOffset>10</bitOffset>
              <bitWidth>2</bitWidth>
            </field>
            <field>
              <name>PUPDR6</name>
              <bitOffset>12</bitOffset>
              <bitWidth>2</bitWidth>
            </field>
            <field>
              <name>PUPDR7</name>
              <bitOffset>14</bitOffset>
              <bitWidth>2</bitWidth>
            </field>
            <field>
              <name>PUPDR8</name>
              <bitOffset>16</bitOffset>
              <bitWidth>2</bitWidth>
            </field>
            <field>
              <name>PUPDR9</name>
              <bitOffset>18</bitOffset>
              <bitWidth>2</bitWidth>
            </field>
            <field>
              <name>PUPDR10</name>
              <bitOffset>20</bitOffset>
              <bitWidth>2</bitWidth>
            </field>
            <field>
              <name>PUPDR11</name>
              <bitOffset>22</bitOffset>
              <bitWidth>2</bitWidth>
            </field>
            <field>
              <name>PUPDR12</name>
              <bitOffset>24</bitOffset>
              <bitWidth>2</bitWidth>
            </field>
            <field>
              <name>PUPDR13</name>
              <bitOffset>26</bitOffset>
              <bitWidth>2</bitWidth>
            </field>
            <field>
              <name>PUPDR14</name>
              <bitOffset>28</bitOffset>
              <bitWidth>2</bitWidth>
            </field>
            <field>
              <name>PUPDR15</name>
              <bitOffset>30</bitOffset>
              <bitWidth>2</bitWidth>
            </field>
          </fields>
        </register>
        <register>
          <name>IDR</name>
          <addressOffset>0x10</addressOffset>
          <size>0x20</size>
          <fields>
            <field>
              <name>ID0</name>
              <bitOffset>0</bitOffset>
              <bitWidth>1</bitWidth>
            </field>
            <field>
              <name>ID1</name>
              <bitOffset>1</bitOffset>
              <bitWidth>1</bitWidth>
            </field>
            <field>
              <name>ID2</name>
              <bitOffset>2</bitOffset>
              <bitWidth>1</bitWidth>
            </field>
            <field>
              <name>ID3</name>
              <bitOffset>3</bitOffset>
              <bitWidth>1</bitWidth>
            </field>
            <field>
              <name>ID4</name>
              <bitOffset>4</bitOffset>
              <bitWidth>1</bitWidth>
            </field>
            <field>
              <name>ID5</name>
              <bitOffset>5</bitOffset>
              <bitWidth>1</bitWidth>
            </field>
            <field>
              <name>ID6</name>
              <bitOffset>6</bitOffset>
              <bitWidth>1</bitWidth>
            </field>
            <field>
              <name>ID7</name>
              <bitOffset>7</bitOffset>
              <bitWidth>1</bitWidth>
            </field>
            <field>
              <name>ID8</name>
              <bitOffset>8</bitOffset>
              <bitWidth>1</bitWidth>
            </field>
            <field>
              <name>ID9</name>
              <bitOffset>9</bitOffset>
              <bitWidth>1</bitWidth>
            </field>
            <field>
              <name>ID10</name>
              <bitOffset>10</bitOffset>
              <bitWidth>1</bitWidth>
            </field>
            <field>
              <name>ID11</name>
              <bitOffset>11</bitOffset>
              <bitWidth>1</bitWidth>
            </field>
            <field>
              <name>ID12</name>
              <bitOffset>12</bitOffset>
              <bitWidth>1</bitWidth>
            </field>
            <field>
              <name>ID13</name>
              <bitOffset>13</bitOffset>
              <bitWidth>1</bitWidth>
            </field>
            <field>
              <name>ID14</name>
              <bitOffset>14</bitOffset>
              <bitWidth>1</bitWidth>
            </field>
            <field>
              <name>ID15</name>
              <bitOffset>15</bitOffset>
              <bitWidth>1</bitWidth>
            </field>
          </fields>
        </register>
        <register>
          <name>ODR</name>
          <addressOffset>0x14</addressOffset>
          <size>0x20</size>
          <fields>
            <field>
              <name>OD0</name>
              <bitOffset>0</bitOffset>
              <bitWidth>1</bitWidth>
            </field>
            <field>
              <name>OD1</name>
              <bitOffset>1</bitOffset>
              <bitWidth>1</bitWidth>
            </field>
            <field>
              <name>OD2</name>
              <bitOffset>2</bitOffset>
              <bitWidth>1</bitWidth>
            </field>
            <field>
              <name>OD3</name>
              <bitOffset>3</bitOffset>
              <bitWidth>1</bitWidth>
            </field>
            <field>
              <name>OD4</name>
              <bitOffset>4</bitOffset>
              <bitWidth>1</bitWidth>
            </field>
            <field>
              <name>OD5</name>
              <bitOffset>5</bitOffset>
              <bitWidth>1</bitWidth>
            </field>
            <field>
              <name>OD6</name>
              <bitOffset>6</bitOffset>
              <bitWidth>1</bitWidth>
            </field>
            <field>
              <name>OD7</name>
              <bitOffset>7</bitOffset>
              <bitWidth>1</bitWidth>
            </field>
            <field>
              <name>OD8</name>
              <bitOffset>8</bitOffset>
              <bitWidth>1</bitWidth>
            </field>
            <field>
              <name>OD9</name>
              <bitOffset>9</bitOffset>
              <bitWidth>1</bitWidth>
            </field>
            <field>
              <name>OD10</name>
              <bitOffset>10</bitOffset>
              <bitWidth>1</bitWidth>
            </field>
            <field>
              <name>OD11</name>
              <bitOffset>11</bitOffset>
              <bitWidth>1</bitWidth>
            </field>
            <field>
              <name>OD12</name>
              <bitOffset>12</bitOffset>
              <bitWidth>1</bitWidth>
            </field>
            <field>
              <name>OD13</name>
              <bitOffset>13</bitOffset>
              <bitWidth>1</bitWidth>
            </field>
            <field>
              <name>OD14</name>
              <bitOffset>14</bitOffset>
              <bitWidth>1</bitWidth>
            </field>
            <field>
              <name>OD15</name>
              <bitOffset>15</bitOffset>
              <bitWidth>1</bitWidth>
            </field>
          </fields>
        </register>
        <register>
          <name>BSRR</name>
          <addressOffset>0x18</addressOffset>
          <size>0x20</size>
          <fields>
            <field>
              <name>BS0</name>
              <bitOffset>0</bitOffset>
              <bitWidth>1</bitWidth>
            </field>
            <field>
              <name>BS1</name>
              <bitOffset>1</bitOffset>
              <bitWidth>1</bitWidth>
            </field>
            <field>
              <name>BS2</name>
              <bitOffset>2</bitOffset>
              <bitWidth>1</bitWidth>
            </field>
            <field>
              <name>BS3</name>
              <bitOffset>3</bitOffset>
              <bitWidth>1</bitWidth>
            </field>
            <field>
              <name>BS4</name>
              <bitOffset>4</bitOffset>
              <bitWidth>1</bitWidth>
            </field>
            <field>
              <name>BS5</name>
              <bitOffset>5</bitOffset>
              <bitWidth>1</bitWidth>
            </field>
            <field>
              <name>BS6</name>
              <bitOffset>6</bitOffset>
              <bitWidth>1</bitWidth>
            </field>
            <field>
              <name>BS7</name>
              <bitOffset>7</bitOffset>
              <bitWidth>1</bitWidth>
            </field>
            <field>
              <name>BS8</name>
              <bitOffset>8</bitOffset>
              <bitWidth>1</bitWidth>
            </field>
            <field>
              <name>BS9</name>
              <bitOffset>9</bitOffset>
              <bitWidth>1</bitWidth>
            </field>
            <field>
              <name>BS10</name>
              <bitOffset>10</bitOffset>
              <bitWidth>1</bitWidth>
            </field>
            <field>
              <name>BS11</name>
              <bitOffset>11</bitOffset>
              <bitWidth>1</bitWidth>
            </field>
            <field>
              <name>BS12</name>
              <bitOffset>12</bitOffset>
              <bitWidth>1</bitWidth>
            </field>
            <field>
              <name>BS13</name>
              <bitOffset>13</bitOffset>
              <bitWidth>1</bitWidth>
            </field>
            <field>
              <name>BS14</name>
              <bitOffset>14</bitOffset>
              <bitWidth>1</bitWidth>
            </field>
            <field>
              <name>BS15</name>
              <bitOffset>15</bitOffset>
              <bitWidth>1</bitWidth>
            </field>
            <field>
              <name>BR0</name>
              <bitOffset>16</bitOffset>
              <bitWidth>1</bitWidth>
            </field>
            <field>
              <name>BR1</name>
              <bitOffset>17</bitOffset>
              <bitWidth>1</bitWidth>
            </field>
            <field>
              <name>BR2</name>
              <bitOffset>18</bitOffset>
              <bitWidth>1</bitWidth>
            </field>
            <field>
              <name>BR3</name>
              <bitOffset>19</bitOffset>
              <bitWidth>1</bitWidth>
            </field>
            <field>
              <name>BR4</name>
              <bitOffset>20</bitOffset>
              <bitWidth>1</bitWidth>
            </field>
            <field>
              <name>BR5</name>
              <bitOffset>21</bitOffset>
              <bitWidth>1</bitWidth>
            </field>
            <field>
              <name>BR6</name>
              <bitOffset>22</bitOffset>
              <bitWidth>1</bitWidth>
            </field>
            <field>
              <name>BR7</name>
              <bitOffset>23</bitOffset>
              <bitWidth>1</bitWidth>
            </field>
            <field>
              <name>BR8</name>
              <bitOffset>24</bitOffset>
              <bitWidth>1</bitWidth>
            </field>
            <field>
              <name>BR9</name>
              <bitOffset>25</bitOffset>
              <bitWidth>1</bitWidth>
            </field>
            <field>
              <name>BR10</name>
              <bitOffset>26</bitOffset>
              <bitWidth>1</bitWidth>
            </field>
            <field>
              <name>BR11</name>
              <bitOffset>27</bitOffset>
              <bitWidth>1</bitWidth>
            </field>
            <field>
              <name>BR12</name>
              <bitOffset>28</bitOffset>
              <bitWidth>1</bitWidth>
            </field>
            <field>
              <name>BR13</name>
              <bitOffset>29</bitOffset>
              <bitWidth>1</bitWidth>
            </field>
            <field>
              <name>BR14</name>
              <bitOffset>30</bitOffset>
              <bitWidth>1</bitWidth>
            </field>
            <field>
              <name>BR15</name>
              <bitOffset>31</bitOffset>
              <bitWidth>1</bitWidth>
            </field>
          </fields>
        </register>
        <register>
          <name>LCKR</name>
          <addressOffset>0x1c</addressOffset>
          <size>0x20</size>
          <fields>
            <field>
              <name>LCK0</name>
              <bitOffset>0</bitOffset>
              <bitWidth>1</bitWidth>
            </field>
            <field>
              <name>LCK1</name>
              <bitOffset>1</bitOffset>
              <bitWidth>1</bitWidth>
            </field>
            <field>
              <name>LCK2</name>
              <bitOffset>2</bitOffset>
              <bitWidth>1</bitWidth>
            </field>
            <field>
              <name>LCK3</name>
              <bitOffset>3</bitOffset>
              <bitWidth>1</bitWidth>
            </field>
            <field>
              <name>LCK4</name>
              <bitOffset>4</bitOffset>
              <bitWidth>1</bitWidth>
            </field>
            <field>
              <name>LCK5</name>
              <bitOffset>5</bitOffset>
              <bitWidth>1</bitWidth>
            </field>
            <field>
              <name>LCK6</name>
              <bitOffset>6</bitOffset>
              <bitWidth>1</bitWidth>
            </field>
            <field>
              <name>LCK7</name>
              <bitOffset>7</bitOffset>
              <bitWidth>1</bitWidth>
            </field>
            <field>
              <name>LCK8</name>
              <bitOffset>8</bitOffset>
              <bitWidth>1</bitWidth>
            </field>
            <field>
              <name>LCK9</name>
              <bitOffset>9</bitOffset>
              <bitWidth>1</bitWidth>
            </field>
            <field>
              <name>LCK10</name>
              <bitOffset>10</bitOffset>
              <bitWidth>1</bitWidth>
            </field>
            <field>
              <name>LCK11</name>
              <bitOffset>11</bitOffset>
              <bitWidth>1</bitWidth>
            </field>
            <field>
              <name>LCK12</name>
              <bitOffset>12</bitOffset>
              <bitWidth>1</bitWidth>
            </field>
            <field>
              <name>LCK13</name>
              <bitOffset>13</bitOffset>
              <bitWidth>1</bitWidth>
            </field>
            <field>
              <name>LCK14</name>
              <bitOffset>14</bitOffset>
              <bitWidth>1</bitWidth>
            </field>
            <field>
              <name>LCK15</name>
              <bitOffset>15</bitOffset>
              <bitWidth>1</bitWidth>
            </field>
            <field>
              <name>LCKK</name>
              <bitOffset>16</bitOffset>
              <bitWidth>1</bitWidth>
            </field>
          </fields>
        </register>
        <register>
          <name>AFR.0</name>
          <addressOffset>0x20</addressOffset>
          <size>0x20</size>
          <fields>
            <field>
              <name>AFRL0</name>
              <bitOffset>0</bitOffset>
              <bitWidth>4</bitWidth>
            </field>
            <field>
              <name>AFRL1</name>
              <bitOffset>4</bitOffset>
              <bitWidth>4</bitWidth>
            </field>
            <field>
              <name>AFRL2</name>
              <bitOffset>8</bitOffset>
              <bitWidth>4</bitWidth>
            </field>
            <field>
              <name>AFRL3</name>
              <bitOffset>12</bitOffset>
              <bitWidth>4</bitWidth>
            </field>
            <field>
              <name>AFRL4</name>
              <bitOffset>16</bitOffset>
              <bitWidth>4</bitWidth>
            </field>
            <field>
              <name>AFRL5</name>
              <bitOffset>20</bitOffset>
              <bitWidth>4</bitWidth>
            </field>
            <field>
              <name>AFRL6</name>
              <bitOffset>24</bitOffset>
              <bitWidth>4</bitWidth>
            </field>
            <field>
              <name>AFRL7</name>
              <bitOffset>28</bitOffset>
              <bitWidth>4</bitWidth>
            </field>
          </fields>
        </register>
        <register>
          <name>AFR.1</name>
          <addressOffset>0x24</addressOffset>
          <size>0x20</size>
          <fields>
            <field>
              <name>AFRH0</name>
              <bitOffset>0</bitOffset>
              <bitWidth>4</bitWidth>
            </field>
            <field>
              <name>AFRH1</name>
              <bitOffset>4</bitOffset>
              <bitWidth>4</bitWidth>
            </field>
            <field>
              <name>AFRH2</name>
              <bitOffset>8</bitOffset>
              <bitWidth>4</bitWidth>
            </field>
            <field>
              <name>AFRH3</name>
              <bitOffset>12</bitOffset>
              <bitWidth>4</bitWidth>
            </field>
            <field>
              <name>AFRH4</name>
              <bitOffset>16</bitOffset>
              <bitWidth>4</bitWidth>
            </field>
            <field>
              <name>AFRH5</name>
              <bitOffset>20</bitOffset>
              <bitWidth>4</bitWidth>
            </field>
            <field>
              <name>AFRH6</name>
              <bitOffset>24</bitOffset>
              <bitWidth>4</bitWidth>
            </field>
            <field>
              <name>AFRH7</name>
              <bitOffset>28</bitOffset>
              <bitWidth>4</bitWidth>
            </field>
          </fields>
        </register>
      </registers>
    </peripheral>
    <peripheral>
      <name>GPIOK</name>
      <baseAddress>0x40022800</baseAddress>
      <registers>
        <register>
          <name>MODER</name>
          <addressOffset>0x0</addressOffset>
          <size>0x20</size>
          <fields>
            <field>
              <name>MODER0</name>
              <bitOffset>0</bitOffset>
              <bitWidth>2</bitWidth>
            </field>
            <field>
              <name>MODER1</name>
              <bitOffset>2</bitOffset>
              <bitWidth>2</bitWidth>
            </field>
            <field>
              <name>MODER2</name>
              <bitOffset>4</bitOffset>
              <bitWidth>2</bitWidth>
            </field>
            <field>
              <name>MODER3</name>
              <bitOffset>6</bitOffset>
              <bitWidth>2</bitWidth>
            </field>
            <field>
              <name>MODER4</name>
              <bitOffset>8</bitOffset>
              <bitWidth>2</bitWidth>
            </field>
            <field>
              <name>MODER5</name>
              <bitOffset>10</bitOffset>
              <bitWidth>2</bitWidth>
            </field>
            <field>
              <name>MODER6</name>
              <bitOffset>12</bitOffset>
              <bitWidth>2</bitWidth>
            </field>
            <field>
              <name>MODER7</name>
              <bitOffset>14</bitOffset>
              <bitWidth>2</bitWidth>
            </field>
            <field>
              <name>MODER8</name>
              <bitOffset>16</bitOffset>
              <bitWidth>2</bitWidth>
            </field>
            <field>
              <name>MODER9</name>
              <bitOffset>18</bitOffset>
              <bitWidth>2</bitWidth>
            </field>
            <field>
              <name>MODER10</name>
              <bitOffset>20</bitOffset>
              <bitWidth>2</bitWidth>
            </field>
            <field>
              <name>MODER11</name>
              <bitOffset>22</bitOffset>
              <bitWidth>2</bitWidth>
            </field>
            <field>
              <name>MODER12</name>
              <bitOffset>24</bitOffset>
              <bitWidth>2</bitWidth>
            </field>
            <field>
              <name>MODER13</name>
              <bitOffset>26</bitOffset>
              <bitWidth>2</bitWidth>
            </field>
            <field>
              <name>MODER14</name>
              <bitOffset>28</bitOffset>
              <bitWidth>2</bitWidth>
            </field>
            <field>
              <name>MODER15</name>
              <bitOffset>30</bitOffset>
              <bitWidth>2</bitWidth>
            </field>
          </fields>
        </register>
        <register>
          <name>OTYPER</name>
          <addressOffset>0x4</addressOffset>
          <size>0x20</size>
          <fields>
            <field>
              <name>OT0</name>
              <bitOffset>0</bitOffset>
              <bitWidth>1</bitWidth>
            </field>
            <field>
              <name>OT1</name>
              <bitOffset>1</bitOffset>
              <bitWidth>1</bitWidth>
            </field>
            <field>
              <name>OT2</name>
              <bitOffset>2</bitOffset>
              <bitWidth>1</bitWidth>
            </field>
            <field>
              <name>OT3</name>
              <bitOffset>3</bitOffset>
              <bitWidth>1</bitWidth>
            </field>
            <field>
              <name>OT4</name>
              <bitOffset>4</bitOffset>
              <bitWidth>1</bitWidth>
            </field>
            <field>
              <name>OT5</name>
              <bitOffset>5</bitOffset>
              <bitWidth>1</bitWidth>
            </field>
            <field>
              <name>OT6</name>
              <bitOffset>6</bitOffset>
              <bitWidth>1</bitWidth>
            </field>
            <field>
              <name>OT7</name>
              <bitOffset>7</bitOffset>
              <bitWidth>1</bitWidth>
            </field>
            <field>
              <name>OT8</name>
              <bitOffset>8</bitOffset>
              <bitWidth>1</bitWidth>
            </field>
            <field>
              <name>OT9</name>
              <bitOffset>9</bitOffset>
              <bitWidth>1</bitWidth>
            </field>
            <field>
              <name>OT10</name>
              <bitOffset>10</bitOffset>
              <bitWidth>1</bitWidth>
            </field>
            <field>
              <name>OT11</name>
              <bitOffset>11</bitOffset>
              <bitWidth>1</bitWidth>
            </field>
            <field>
              <name>OT12</name>
              <bitOffset>12</bitOffset>
              <bitWidth>1</bitWidth>
            </field>
            <field>
              <name>OT13</name>
              <bitOffset>13</bitOffset>
              <bitWidth>1</bitWidth>
            </field>
            <field>
              <name>OT14</name>
              <bitOffset>14</bitOffset>
              <bitWidth>1</bitWidth>
            </field>
            <field>
              <name>OT15</name>
              <bitOffset>15</bitOffset>
              <bitWidth>1</bitWidth>
            </field>
          </fields>
        </register>
        <register>
          <name>OSPEEDR</name>
          <addressOffset>0x8</addressOffset>
          <size>0x20</size>
          <fields>
            <field>
              <name>OSPEEDR0</name>
              <bitOffset>0</bitOffset>
              <bitWidth>2</bitWidth>
            </field>
            <field>
              <name>OSPEEDR1</name>
              <bitOffset>2</bitOffset>
              <bitWidth>2</bitWidth>
            </field>
            <field>
              <name>OSPEEDR2</name>
              <bitOffset>4</bitOffset>
              <bitWidth>2</bitWidth>
            </field>
            <field>
              <name>OSPEEDR3</name>
              <bitOffset>6</bitOffset>
              <bitWidth>2</bitWidth>
            </field>
            <field>
              <name>OSPEEDR4</name>
              <bitOffset>8</bitOffset>
              <bitWidth>2</bitWidth>
            </field>
            <field>
              <name>OSPEEDR5</name>
              <bitOffset>10</bitOffset>
              <bitWidth>2</bitWidth>
            </field>
            <field>
              <name>OSPEEDR6</name>
              <bitOffset>12</bitOffset>
              <bitWidth>2</bitWidth>
            </field>
            <field>
              <name>OSPEEDR7</name>
              <bitOffset>14</bitOffset>
              <bitWidth>2</bitWidth>
            </field>
            <field>
              <name>OSPEEDR8</name>
              <bitOffset>16</bitOffset>
              <bitWidth>2</bitWidth>
            </field>
            <field>
              <name>OSPEEDR9</name>
              <bitOffset>18</bitOffset>
              <bitWidth>2</bitWidth>
            </field>
            <field>
              <name>OSPEEDR10</name>
              <bitOffset>20</bitOffset>
              <bitWidth>2</bitWidth>
            </field>
            <field>
              <name>OSPEEDR11</name>
              <bitOffset>22</bitOffset>
              <bitWidth>2</bitWidth>
            </field>
            <field>
              <name>OSPEEDR12</name>
              <bitOffset>24</bitOffset>
              <bitWidth>2</bitWidth>
            </field>
            <field>
              <name>OSPEEDR13</name>
              <bitOffset>26</bitOffset>
              <bitWidth>2</bitWidth>
            </field>
            <field>
              <name>OSPEEDR14</name>
              <bitOffset>28</bitOffset>
              <bitWidth>2</bitWidth>
            </field>
            <field>
              <name>OSPEEDR15</name>
              <bitOffset>30</bitOffset>
              <bitWidth>2</bitWidth>
            </field>
          </fields>
        </register>
        <register>
          <name>PUPDR</name>
          <addressOffset>0xc</addressOffset>
          <size>0x20</size>
          <fields>
            <field>
              <name>PUPDR0</name>
              <bitOffset>0</bitOffset>
              <bitWidth>2</bitWidth>
            </field>
            <field>
              <name>PUPDR1</name>
              <bitOffset>2</bitOffset>
              <bitWidth>2</bitWidth>
            </field>
            <field>
              <name>PUPDR2</name>
              <bitOffset>4</bitOffset>
              <bitWidth>2</bitWidth>
            </field>
            <field>
              <name>PUPDR3</name>
              <bitOffset>6</bitOffset>
              <bitWidth>2</bitWidth>
            </field>
            <field>
              <name>PUPDR4</name>
              <bitOffset>8</bitOffset>
              <bitWidth>2</bitWidth>
            </field>
            <field>
              <name>PUPDR5</name>
              <bitOffset>10</bitOffset>
              <bitWidth>2</bitWidth>
            </field>
            <field>
              <name>PUPDR6</name>
              <bitOffset>12</bitOffset>
              <bitWidth>2</bitWidth>
            </field>
            <field>
              <name>PUPDR7</name>
              <bitOffset>14</bitOffset>
              <bitWidth>2</bitWidth>
            </field>
            <field>
              <name>PUPDR8</name>
              <bitOffset>16</bitOffset>
              <bitWidth>2</bitWidth>
            </field>
            <field>
              <name>PUPDR9</name>
              <bitOffset>18</bitOffset>
              <bitWidth>2</bitWidth>
            </field>
            <field>
              <name>PUPDR10</name>
              <bitOffset>20</bitOffset>
              <bitWidth>2</bitWidth>
            </field>
            <field>
              <name>PUPDR11</name>
              <bitOffset>22</bitOffset>
              <bitWidth>2</bitWidth>
            </field>
            <field>
              <name>PUPDR12</name>
              <bitOffset>24</bitOffset>
              <bitWidth>2</bitWidth>
            </field>
            <field>
              <name>PUPDR13</name>
              <bitOffset>26</bitOffset>
              <bitWidth>2</bitWidth>
            </field>
            <field>
              <name>PUPDR14</name>
              <bitOffset>28</bitOffset>
              <bitWidth>2</bitWidth>
            </field>
            <field>
              <name>PUPDR15</name>
              <bitOffset>30</bitOffset>
              <bitWidth>2</bitWidth>
            </field>
          </fields>
        </register>
        <register>
          <name>IDR</name>
          <addressOffset>0x10</addressOffset>
          <size>0x20</size>
          <fields>
            <field>
              <name>ID0</name>
              <bitOffset>0</bitOffset>
              <bitWidth>1</bitWidth>
            </field>
            <field>
              <name>ID1</name>
              <bitOffset>1</bitOffset>
              <bitWidth>1</bitWidth>
            </field>
            <field>
              <name>ID2</name>
              <bitOffset>2</bitOffset>
              <bitWidth>1</bitWidth>
            </field>
            <field>
              <name>ID3</name>
              <bitOffset>3</bitOffset>
              <bitWidth>1</bitWidth>
            </field>
            <field>
              <name>ID4</name>
              <bitOffset>4</bitOffset>
              <bitWidth>1</bitWidth>
            </field>
            <field>
              <name>ID5</name>
              <bitOffset>5</bitOffset>
              <bitWidth>1</bitWidth>
            </field>
            <field>
              <name>ID6</name>
              <bitOffset>6</bitOffset>
              <bitWidth>1</bitWidth>
            </field>
            <field>
              <name>ID7</name>
              <bitOffset>7</bitOffset>
              <bitWidth>1</bitWidth>
            </field>
            <field>
              <name>ID8</name>
              <bitOffset>8</bitOffset>
              <bitWidth>1</bitWidth>
            </field>
            <field>
              <name>ID9</name>
              <bitOffset>9</bitOffset>
              <bitWidth>1</bitWidth>
            </field>
            <field>
              <name>ID10</name>
              <bitOffset>10</bitOffset>
              <bitWidth>1</bitWidth>
            </field>
            <field>
              <name>ID11</name>
              <bitOffset>11</bitOffset>
              <bitWidth>1</bitWidth>
            </field>
            <field>
              <name>ID12</name>
              <bitOffset>12</bitOffset>
              <bitWidth>1</bitWidth>
            </field>
            <field>
              <name>ID13</name>
              <bitOffset>13</bitOffset>
              <bitWidth>1</bitWidth>
            </field>
            <field>
              <name>ID14</name>
              <bitOffset>14</bitOffset>
              <bitWidth>1</bitWidth>
            </field>
            <field>
              <name>ID15</name>
              <bitOffset>15</bitOffset>
              <bitWidth>1</bitWidth>
            </field>
          </fields>
        </register>
        <register>
          <name>ODR</name>
          <addressOffset>0x14</addressOffset>
          <size>0x20</size>
          <fields>
            <field>
              <name>OD0</name>
              <bitOffset>0</bitOffset>
              <bitWidth>1</bitWidth>
            </field>
            <field>
              <name>OD1</name>
              <bitOffset>1</bitOffset>
              <bitWidth>1</bitWidth>
            </field>
            <field>
              <name>OD2</name>
              <bitOffset>2</bitOffset>
              <bitWidth>1</bitWidth>
            </field>
            <field>
              <name>OD3</name>
              <bitOffset>3</bitOffset>
              <bitWidth>1</bitWidth>
            </field>
            <field>
              <name>OD4</name>
              <bitOffset>4</bitOffset>
              <bitWidth>1</bitWidth>
            </field>
            <field>
              <name>OD5</name>
              <bitOffset>5</bitOffset>
              <bitWidth>1</bitWidth>
            </field>
            <field>
              <name>OD6</name>
              <bitOffset>6</bitOffset>
              <bitWidth>1</bitWidth>
            </field>
            <field>
              <name>OD7</name>
              <bitOffset>7</bitOffset>
              <bitWidth>1</bitWidth>
            </field>
            <field>
              <name>OD8</name>
              <bitOffset>8</bitOffset>
              <bitWidth>1</bitWidth>
            </field>
            <field>
              <name>OD9</name>
              <bitOffset>9</bitOffset>
              <bitWidth>1</bitWidth>
            </field>
            <field>
              <name>OD10</name>
              <bitOffset>10</bitOffset>
              <bitWidth>1</bitWidth>
            </field>
            <field>
              <name>OD11</name>
              <bitOffset>11</bitOffset>
              <bitWidth>1</bitWidth>
            </field>
            <field>
              <name>OD12</name>
              <bitOffset>12</bitOffset>
              <bitWidth>1</bitWidth>
            </field>
            <field>
              <name>OD13</name>
              <bitOffset>13</bitOffset>
              <bitWidth>1</bitWidth>
            </field>
            <field>
              <name>OD14</name>
              <bitOffset>14</bitOffset>
              <bitWidth>1</bitWidth>
            </field>
            <field>
              <name>OD15</name>
              <bitOffset>15</bitOffset>
              <bitWidth>1</bitWidth>
            </field>
          </fields>
        </register>
        <register>
          <name>BSRR</name>
          <addressOffset>0x18</addressOffset>
          <size>0x20</size>
          <fields>
            <field>
              <name>BS0</name>
              <bitOffset>0</bitOffset>
              <bitWidth>1</bitWidth>
            </field>
            <field>
              <name>BS1</name>
              <bitOffset>1</bitOffset>
              <bitWidth>1</bitWidth>
            </field>
            <field>
              <name>BS2</name>
              <bitOffset>2</bitOffset>
              <bitWidth>1</bitWidth>
            </field>
            <field>
              <name>BS3</name>
              <bitOffset>3</bitOffset>
              <bitWidth>1</bitWidth>
            </field>
            <field>
              <name>BS4</name>
              <bitOffset>4</bitOffset>
              <bitWidth>1</bitWidth>
            </field>
            <field>
              <name>BS5</name>
              <bitOffset>5</bitOffset>
              <bitWidth>1</bitWidth>
            </field>
            <field>
              <name>BS6</name>
              <bitOffset>6</bitOffset>
              <bitWidth>1</bitWidth>
            </field>
            <field>
              <name>BS7</name>
              <bitOffset>7</bitOffset>
              <bitWidth>1</bitWidth>
            </field>
            <field>
              <name>BS8</name>
              <bitOffset>8</bitOffset>
              <bitWidth>1</bitWidth>
            </field>
            <field>
              <name>BS9</name>
              <bitOffset>9</bitOffset>
              <bitWidth>1</bitWidth>
            </field>
            <field>
              <name>BS10</name>
              <bitOffset>10</bitOffset>
              <bitWidth>1</bitWidth>
            </field>
            <field>
              <name>BS11</name>
              <bitOffset>11</bitOffset>
              <bitWidth>1</bitWidth>
            </field>
            <field>
              <name>BS12</name>
              <bitOffset>12</bitOffset>
              <bitWidth>1</bitWidth>
            </field>
            <field>
              <name>BS13</name>
              <bitOffset>13</bitOffset>
              <bitWidth>1</bitWidth>
            </field>
            <field>
              <name>BS14</name>
              <bitOffset>14</bitOffset>
              <bitWidth>1</bitWidth>
            </field>
            <field>
              <name>BS15</name>
              <bitOffset>15</bitOffset>
              <bitWidth>1</bitWidth>
            </field>
            <field>
              <name>BR0</name>
              <bitOffset>16</bitOffset>
              <bitWidth>1</bitWidth>
            </field>
            <field>
              <name>BR1</name>
              <bitOffset>17</bitOffset>
              <bitWidth>1</bitWidth>
            </field>
            <field>
              <name>BR2</name>
              <bitOffset>18</bitOffset>
              <bitWidth>1</bitWidth>
            </field>
            <field>
              <name>BR3</name>
              <bitOffset>19</bitOffset>
              <bitWidth>1</bitWidth>
            </field>
            <field>
              <name>BR4</name>
              <bitOffset>20</bitOffset>
              <bitWidth>1</bitWidth>
            </field>
            <field>
              <name>BR5</name>
              <bitOffset>21</bitOffset>
              <bitWidth>1</bitWidth>
            </field>
            <field>
              <name>BR6</name>
              <bitOffset>22</bitOffset>
              <bitWidth>1</bitWidth>
            </field>
            <field>
              <name>BR7</name>
              <bitOffset>23</bitOffset>
              <bitWidth>1</bitWidth>
            </field>
            <field>
              <name>BR8</name>
              <bitOffset>24</bitOffset>
              <bitWidth>1</bitWidth>
            </field>
            <field>
              <name>BR9</name>
              <bitOffset>25</bitOffset>
              <bitWidth>1</bitWidth>
            </field>
            <field>
              <name>BR10</name>
              <bitOffset>26</bitOffset>
              <bitWidth>1</bitWidth>
            </field>
            <field>
              <name>BR11</name>
              <bitOffset>27</bitOffset>
              <bitWidth>1</bitWidth>
            </field>
            <field>
              <name>BR12</name>
              <bitOffset>28</bitOffset>
              <bitWidth>1</bitWidth>
            </field>
            <field>
              <name>BR13</name>
              <bitOffset>29</bitOffset>
              <bitWidth>1</bitWidth>
            </field>
            <field>
              <name>BR14</name>
              <bitOffset>30</bitOffset>
              <bitWidth>1</bitWidth>
            </field>
            <field>
              <name>BR15</name>
              <bitOffset>31</bitOffset>
              <bitWidth>1</bitWidth>
            </field>
          </fields>
        </register>
        <register>
          <name>LCKR</name>
          <addressOffset>0x1c</addressOffset>
          <size>0x20</size>
          <fields>
            <field>
              <name>LCK0</name>
              <bitOffset>0</bitOffset>
              <bitWidth>1</bitWidth>
            </field>
            <field>
              <name>LCK1</name>
              <bitOffset>1</bitOffset>
              <bitWidth>1</bitWidth>
            </field>
            <field>
              <name>LCK2</name>
              <bitOffset>2</bitOffset>
              <bitWidth>1</bitWidth>
            </field>
            <field>
              <name>LCK3</name>
              <bitOffset>3</bitOffset>
              <bitWidth>1</bitWidth>
            </field>
            <field>
              <name>LCK4</name>
              <bitOffset>4</bitOffset>
              <bitWidth>1</bitWidth>
            </field>
            <field>
              <name>LCK5</name>
              <bitOffset>5</bitOffset>
              <bitWidth>1</bitWidth>
            </field>
            <field>
              <name>LCK6</name>
              <bitOffset>6</bitOffset>
              <bitWidth>1</bitWidth>
            </field>
            <field>
              <name>LCK7</name>
              <bitOffset>7</bitOffset>
              <bitWidth>1</bitWidth>
            </field>
            <field>
              <name>LCK8</name>
              <bitOffset>8</bitOffset>
              <bitWidth>1</bitWidth>
            </field>
            <field>
              <name>LCK9</name>
              <bitOffset>9</bitOffset>
              <bitWidth>1</bitWidth>
            </field>
            <field>
              <name>LCK10</name>
              <bitOffset>10</bitOffset>
              <bitWidth>1</bitWidth>
            </field>
            <field>
              <name>LCK11</name>
              <bitOffset>11</bitOffset>
              <bitWidth>1</bitWidth>
            </field>
            <field>
              <name>LCK12</name>
              <bitOffset>12</bitOffset>
              <bitWidth>1</bitWidth>
            </field>
            <field>
              <name>LCK13</name>
              <bitOffset>13</bitOffset>
              <bitWidth>1</bitWidth>
            </field>
            <field>
              <name>LCK14</name>
              <bitOffset>14</bitOffset>
              <bitWidth>1</bitWidth>
            </field>
            <field>
              <name>LCK15</name>
              <bitOffset>15</bitOffset>
              <bitWidth>1</bitWidth>
            </field>
            <field>
              <name>LCKK</name>
              <bitOffset>16</bitOffset>
              <bitWidth>1</bitWidth>
            </field>
          </fields>
        </register>
        <register>
          <name>AFR.0</name>
          <addressOffset>0x20</addressOffset>
          <size>0x20</size>
          <fields>
            <field>
              <name>AFRL0</name>
              <bitOffset>0</bitOffset>
              <bitWidth>4</bitWidth>
            </field>
            <field>
              <name>AFRL1</name>
              <bitOffset>4</bitOffset>
              <bitWidth>4</bitWidth>
            </field>
            <field>
              <name>AFRL2</name>
              <bitOffset>8</bitOffset>
              <bitWidth>4</bitWidth>
            </field>
            <field>
              <name>AFRL3</name>
              <bitOffset>12</bitOffset>
              <bitWidth>4</bitWidth>
            </field>
            <field>
              <name>AFRL4</name>
              <bitOffset>16</bitOffset>
              <bitWidth>4</bitWidth>
            </field>
            <field>
              <name>AFRL5</name>
              <bitOffset>20</bitOffset>
              <bitWidth>4</bitWidth>
            </field>
            <field>
              <name>AFRL6</name>
              <bitOffset>24</bitOffset>
              <bitWidth>4</bitWidth>
            </field>
            <field>
              <name>AFRL7</name>
              <bitOffset>28</bitOffset>
              <bitWidth>4</bitWidth>
            </field>
          </fields>
        </register>
        <register>
          <name>AFR.1</name>
          <addressOffset>0x24</addressOffset>
          <size>0x20</size>
          <fields>
            <field>
              <name>AFRH0</name>
              <bitOffset>0</bitOffset>
              <bitWidth>4</bitWidth>
            </field>
            <field>
              <name>AFRH1</name>
              <bitOffset>4</bitOffset>
              <bitWidth>4</bitWidth>
            </field>
            <field>
              <name>AFRH2</name>
              <bitOffset>8</bitOffset>
              <bitWidth>4</bitWidth>
            </field>
            <field>
              <name>AFRH3</name>
              <bitOffset>12</bitOffset>
              <bitWidth>4</bitWidth>
            </field>
            <field>
              <name>AFRH4</name>
              <bitOffset>16</bitOffset>
              <bitWidth>4</bitWidth>
            </field>
            <field>
              <name>AFRH5</name>
              <bitOffset>20</bitOffset>
              <bitWidth>4</bitWidth>
            </field>
            <field>
              <name>AFRH6</name>
              <bitOffset>24</bitOffset>
              <bitWidth>4</bitWidth>
            </field>
            <field>
              <name>AFRH7</name>
              <bitOffset>28</bitOffset>
              <bitWidth>4</bitWidth>
            </field>
          </fields>
        </register>
      </registers>
    </peripheral>
    <peripheral>
      <name>CRC</name>
      <baseAddress>0x40023000</baseAddress>
      <registers>
        <register>
          <name>DR</name>
          <addressOffset>0x0</addressOffset>
          <size>0x20</size>
          <fields>
            <field>
              <name>DR</name>
              <bitOffset>0</bitOffset>
              <bitWidth>32</bitWidth>
            </field>
          </fields>
        </register>
        <register>
          <name>IDR</name>
          <addressOffset>0x4</addressOffset>
          <size>0x8</size>
          <fields>
            <field>
              <name>IDR</name>
              <bitOffset>0</bitOffset>
              <bitWidth>8</bitWidth>
            </field>
          </fields>
        </register>
        <register>
          <name>CR</name>
          <addressOffset>0x8</addressOffset>
          <size>0x20</size>
          <fields>
            <field>
              <name>RESET</name>
              <bitOffset>0</bitOffset>
              <bitWidth>1</bitWidth>
            </field>
            <field>
              <name>POLYSIZE</name>
              <bitOffset>3</bitOffset>
              <bitWidth>2</bitWidth>
            </field>
            <field>
              <name>REV_IN</name>
              <bitOffset>5</bitOffset>
              <bitWidth>2</bitWidth>
            </field>
            <field>
              <name>REV_OUT</name>
              <bitOffset>7</bitOffset>
              <bitWidth>1</bitWidth>
            </field>
          </fields>
        </register>
        <register>
          <name>INIT</name>
          <addressOffset>0x10</addressOffset>
          <size>0x20</size>
          <fields>
            <field>
              <name>INIT</name>
              <bitOffset>0</bitOffset>
              <bitWidth>32</bitWidth>
            </field>
          </fields>
        </register>
        <register>
          <name>POL</name>
          <addressOffset>0x14</addressOffset>
          <size>0x20</size>
          <fields>
            <field>
              <name>POL</name>
              <bitOffset>0</bitOffset>
              <bitWidth>32</bitWidth>
            </field>
          </fields>
        </register>
      </registers>
    </peripheral>
    <peripheral>
      <name>RCC</name>
      <baseAddress>0x40023800</baseAddress>
      <registers>
        <register>
          <name>CR</name>
          <addressOffset>0x0</addressOffset>
          <size>0x20</size>
          <fields>
            <field>
              <name>HSION</name>
              <bitOffset>0</bitOffset>
              <bitWidth>1</bitWidth>
            </field>
            <field>
              <name>HSIRDY</name>
              <bitOffset>1</bitOffset>
              <bitWidth>1</bitWidth>
            </field>
            <field>
              <name>HSITRIM</name>
              <bitOffset>3</bitOffset>
              <bitWidth>5</bitWidth>
            </field>
            <field>
              <name>HSICAL</name>
              <bitOffset>8</bitOffset>
              <bitWidth>8</bitWidth>
            </field>
            <field>
              <name>HSEON</name>
              <bitOffset>16</bitOffset>
              <bitWidth>1</bitWidth>
            </field>
            <field>
              <name>HSERDY</name>
              <bitOffset>17</bitOffset>
              <bitWidth>1</bitWidth>
            </field>
            <field>
              <name>HSEBYP</name>
              <bitOffset>18</bitOffset>
              <bitWidth>1</bitWidth>
            </field>
            <field>
              <name>CSSON</name>
              <bitOffset>19</bitOffset>
              <bitWidth>1</bitWidth>
            </field>
            <field>
              <name>PLLON</name>
              <bitOffset>24</bitOffset>
              <bitWidth>1</bitWidth>
            </field>
            <field>
              <name>PLLRDY</name>
              <bitOffset>25</bitOffset>
              <bitWidth>1</bitWidth>
            </field>
            <field>
              <name>PLLI2SON</name>
              <bitOffset>26</bitOffset>
              <bitWidth>1</bitWidth>
            </field>
            <field>
              <name>PLLI2SRDY</name>
              <bitOffset>27</bitOffset>
              <bitWidth>1</bitWidth>
            </field>
            <field>
              <name>PLLSAION</name>
              <bitOffset>28</bitOffset>
              <bitWidth>1</bitWidth>
            </field>
            <field>
              <name>PLLSAIRDY</name>
              <bitOffset>29</bitOffset>
              <bitWidth>1</bitWidth>
            </field>
          </fields>
        </register>
        <register>
          <name>PLLCFGR</name>
          <addressOffset>0x4</addressOffset>
          <size>0x20</size>
          <fields>
            <field>
              <name>PLLM</name>
              <bitOffset>0</bitOffset>
              <bitWidth>6</bitWidth>
            </field>
            <field>
              <name>PLLN</name>
              <bitOffset>6</bitOffset>
              <bitWidth>9</bitWidth>
            </field>
            <field>
              <name>PLLP</name>
              <bitOffset>16</bitOffset>
              <bitWidth>2</bitWidth>
            </field>
            <field>
              <name>PLLSRC_HSE</name>
              <bitOffset>22</bitOffset>
              <bitWidth>1</bitWidth>
            </field>
            <field>
              <name>PLLQ</name>
              <bitOffset>24</bitOffset>
              <bitWidth>4</bitWidth>
            </field>
            <field>
              <name>PLLR</name>
              <bitOffset>28</bitOffset>
              <bitWidth>3</bitWidth>
            </field>
          </fields>
        </register>
        <register>
          <name>CFGR</name>
          <addressOffset>0x8</addressOffset>
          <size>0x20</size>
          <fields>
            <field>
              <name>SW</name>
              <bitOffset>0</bitOffset>
              <bitWidth>2</bitWidth>
            </field>
            <field>
              <name>SWS</name>
              <bitOffset>2</bitOffset>
              <bitWidth>2</bitWidth>
            </field>
            <field>
              <name>HPRE</name>
              <bitOffset>4</bitOffset>
              <bitWidth>4</bitWidth>
            </field>
            <field>
              <name>PPRE1</name>
              <bitOffset>10</bitOffset>
              <bitWidth>3</bitWidth>
            </field>
            <field>
              <name>PPRE2</name>
              <bitOffset>13</bitOffset>
              <bitWidth>3</bitWidth>
            </field>
            <field>
              <name>RTCPRE</name>
              <bitOffset>16</bitOffset>
              <bitWidth>5</bitWidth>
            </field>
            <field>
              <name>MCO1</name>
              <bitOffset>21</bitOffset>
              <bitWidth>2</bitWidth>
            </field>
            <field>
              <name>I2SSRC</name>
              <bitOffset>23</bitOffset>
              <bitWidth>1</bitWidth>
            </field>
            <field>
              <name>MCO1PRE</name>
              <bitOffset>24</bitOffset>
              <bitWidth>3</bitWidth>
            </field>
            <field>
              <name>MCO2PRE</name>
              <bitOffset>27</bitOffset>
              <bitWidth>3</bitWidth>
            </field>
            <field>
              <name>MCO2</name>
              <bitOffset>30</bitOffset>
              <bitWidth>2</bitWidth>
            </field>
          </fields>
        </register>
        <register>
          <name>CIR</name>
          <addressOffset>0xc</addressOffset>
          <size>0x20</size>
          <fields>
            <field>
              <name>LSIRDYF</name>
              <bitOffset>0</bitOffset>
              <bitWidth>1</bitWidth>
            </field>
            <field>
              <name>LSERDYF</name>
              <bitOffset>1</bitOffset>
              <bitWidth>1</bitWidth>
            </field>
            <field>
              <name>HSIRDYF</name>
              <bitOffset>2</bitOffset>
              <bitWidth>1</bitWidth>
            </field>
            <field>
              <name>HSERDYF</name>
              <bitOffset>3</bitOffset>
              <bitWidth>1</bitWidth>
            </field>
            <field>
              <name>PLLRDYF</name>
              <bitOffset>4</bitOffset>
              <bitWidth>1</bitWidth>
            </field>
            <field>
              <name>PLLI2SRDYF</name>
              <bitOffset>5</bitOffset>
              <bitWidth>1</bitWidth>
            </field>
            <field>
              <name>PLLSAIRDYF</name>
              <bitOffset>6</bitOffset>
              <bitWidth>1</bitWidth>
            </field>
            <field>
              <name>CSSF</name>
              <bitOffset>7</bitOffset>
              <bitWidth>1</bitWidth>
            </field>
            <field>
              <name>LSIRDYIE</name>
              <bitOffset>8</bitOffset>
              <bitWidth>1</bitWidth>
            </field>
            <field>
              <name>LSERDYIE</name>
              <bitOffset>9</bitOffset>
              <bitWidth>1</bitWidth>
            </field>
            <field>
              <name>HSIRDYIE</name>
              <bitOffset>10</bitOffset>
              <bitWidth>1</bitWidth>
            </field>
            <field>
              <name>HSERDYIE</name>
              <bitOffset>11</bitOffset>
              <bitWidth>1</bitWidth>
            </field>
            <field>
              <name>PLLRDYIE</name>
              <bitOffset>12</bitOffset>
              <bitWidth>1</bitWidth>
            </field>
            <field>
              <name>PLLI2SRDYIE</name>
              <bitOffset>13</bitOffset>
              <bitWidth>1</bitWidth>
            </field>
            <field>
              <name>PLLSAIRDYIE</name>
              <bitOffset>14</bitOffset>
              <bitWidth>1</bitWidth>
            </field>
            <field>
              <name>LSIRDYC</name>
              <bitOffset>16</bitOffset>
              <bitWidth>1</bitWidth>
            </field>
            <field>
              <name>LSERDYC</name>
              <bitOffset>17</bitOffset>
              <bitWidth>1</bitWidth>
            </field>
            <field>
              <name>HSIRDYC</name>
              <bitOffset>18</bitOffset>
              <bitWidth>1</bitWidth>
            </field>
            <field>
              <name>HSERDYC</name>
              <bitOffset>19</bitOffset>
              <bitWidth>1</bitWidth>
            </field>
            <field>
              <name>PLLRDYC</name>
              <bitOffset>20</bitOffset>
              <bitWidth>1</bitWidth>
            </field>
            <field>
              <name>PLLI2SRDYC</name>
              <bitOffset>21</bitOffset>
              <bitWidth>1</bitWidth>
            </field>
            <field>
              <name>PLLSAIRDYC</name>
              <bitOffset>22</bitOffset>
              <bitWidth>1</bitWidth>
            </field>
            <field>
              <name>CSSC</name>
              <bitOffset>23</bitOffset>
              <bitWidth>1</bitWidth>
            </field>
          </fields>
        </register>
        <register>
          <name>AHB1RSTR</name>
          <addressOffset>0x10</addressOffset>
          <size>0x20</size>
          <fields>
            <field>
              <name>GPIOARST</name>
              <bitOffset>0</bitOffset>
              <bitWidth>1</bitWidth>
            </field>
            <field>
              <name>GPIOBRST</name>
              <bitOffset>1</bitOffset>
              <bitWidth>1</bitWidth>
            </field>
            <field>
              <name>GPIOCRST</name>
              <bitOffset>2</bitOffset>
              <bitWidth>1</bitWidth>
            </field>
            <field>
              <name>GPIODRST</name>
              <bitOffset>3</bitOffset>
              <bitWidth>1</bitWidth>
            </field>
            <field>
              <name>GPIOERST</name>
              <bitOffset>4</bitOffset>
              <bitWidth>1</bitWidth>
            </field>
            <field>
              <name>GPIOFRST</name>
              <bitOffset>5</bitOffset>
              <bitWidth>1</bitWidth>
            </field>
            <field>
              <name>GPIOGRST</name>
              <bitOffset>6</bitOffset>
              <bitWidth>1</bitWidth>
            </field>
            <field>
              <name>GPIOHRST</name>
              <bitOffset>7</bitOffset>
              <bitWidth>1</bitWidth>
            </field>
            <field>
              <name>GPIOIRST</name>
              <bitOffset>8</bitOffset>
              <bitWidth>1</bitWidth>
            </field>
            <field>
              <name>GPIOJRST</name>
              <bitOffset>9</bitOffset>
              <bitWidth>1</bitWidth>
            </field>
            <field>
              <name>GPIOKRST</name>
              <bitOffset>10</bitOffset>
              <bitWidth>1</bitWidth>
            </field>
            <field>
              <name>CRCRST</name>
              <bitOffset>12</bitOffset>
              <bitWidth>1</bitWidth>
            </field>
            <field>
              <name>DMA1RST</name>
              <bitOffset>21</bitOffset>
              <bitWidth>1</bitWidth>
            </field>
            <field>
              <name>DMA2RST</name>
              <bitOffset>22</bitOffset>
              <bitWidth>1</bitWidth>
            </field>
            <field>
              <name>DMA2DRST</name>
              <bitOffset>23</bitOffset>
              <bitWidth>1</bitWidth>
            </field>
            <field>
              <name>ETHMACRST</name>
              <bitOffset>25</bitOffset>
              <bitWidth>1</bitWidth>
            </field>
            <field>
              <name>OTGHRST</name>
              <bitOffset>29</bitOffset>
              <bitWidth>1</bitWidth>
            </field>
          </fields>
        </register>
        <register>
          <name>AHB2RSTR</name>
          <addressOffset>0x14</addressOffset>
          <size>0x20</size>
          <fields>
            <field>
              <name>DCMIRST</name>
              <bitOffset>0</bitOffset>
              <bitWidth>1</bitWidth>
            </field>
            <field>
              <name>JPEGRST</name>
              <bitOffset>1</bitOffset>
              <bitWidth>1</bitWidth>
            </field>
            <field>
              <name>RNGRST</name>
              <bitOffset>6</bitOffset>
              <bitWidth>1</bitWidth>
            </field>
            <field>
              <name>OTGFSRST</name>
              <bitOffset>7</bitOffset>
              <bitWidth>1</bitWidth>
            </field>
          </fields>
        </register>
        <register>
          <name>AHB3RSTR</name>
          <addressOffset>0x18</addressOffset>
          <size>0x20</size>
          <fields>
            <field>
              <name>FMCRST</name>
              <bitOffset>0</bitOffset>
              <bitWidth>1</bitWidth>
            </field>
            <field>
              <name>QSPIRST</name>
              <bitOffset>1</bitOffset>
              <bitWidth>1</bitWidth>
            </field>
          </fields>
        </register>
        <register>
          <name>APB1RSTR</name>
          <addressOffset>0x20</addressOffset>
          <size>0x20</size>
          <fields>
            <field>
              <name>TIM2RST</name>
              <bitOffset>0</bitOffset>
              <bitWidth>1</bitWidth>
            </field>
            <field>
              <name>TIM3RST</name>
              <bitOffset>1</bitOffset>
              <bitWidth>1</bitWidth>
            </field>
            <field>
              <name>TIM4RST</name>
              <bitOffset>2</bitOffset>
              <bitWidth>1</bitWidth>
            </field>
            <field>
              <name>TIM5RST</name>
              <bitOffset>3</bitOffset>
              <bitWidth>1</bitWidth>
            </field>
            <field>
              <name>TIM6RST</name>
              <bitOffset>4</bitOffset>
              <bitWidth>1</bitWidth>
            </field>
            <field>
              <name>TIM7RST</name>
              <bitOffset>5</bitOffset>
              <bitWidth>1</bitWidth>
            </field>
            <field>
              <name>TIM12RST</name>
              <bitOffset>6</bitOffset>
              <bitWidth>1</bitWidth>
            </field>
            <field>
              <name>TIM13RST</name>
              <bitOffset>7</bitOffset>
              <bitWidth>1</bitWidth>
            </field>
            <field>
              <name>TIM14RST</name>
              <bitOffset>8</bitOffset>
              <bitWidth>1</bitWidth>
            </field>
            <field>
              <name>LPTIM1RST</name>
              <bitOffset>9</bitOffset>
              <bitWidth>1</bitWidth>
            </field>
            <field>
              <name>WWDGRST</name>
              <bitOffset>11</bitOffset>
              <bitWidth>1</bitWidth>
            </field>
            <field>
              <name>CAN3RST</name>
              <bitOffset>13</bitOffset>
              <bitWidth>1</bitWidth>
            </field>
            <field>
              <name>SPI2RST</name>
              <bitOffset>14</bitOffset>
              <bitWidth>1</bitWidth>
            </field>
            <field>
              <name>SPI3RST</name>
              <bitOffset>15</bitOffset>
              <bitWidth>1</bitWidth>
            </field>
            <field>
              <name>SPDIFRXRST</name>
              <bitOffset>16</bitOffset>
              <bitWidth>1</bitWidth>
            </field>
            <field>
              <name>USART2RST</name>
              <bitOffset>17</bitOffset>
              <bitWidth>1</bitWidth>
            </field>
            <field>
              <name>USART3RST</name>
              <bitOffset>18</bitOffset>
              <bitWidth>1</bitWidth>
            </field>
            <field>
              <name>UART4RST</name>
              <bitOffset>19</bitOffset>
              <bitWidth>1</bitWidth>
            </field>
            <field>
              <name>UART5RST</name>
              <bitOffset>20</bitOffset>
              <bitWidth>1</bitWidth>
            </field>
            <field>
              <name>I2C1RST</name>
              <bitOffset>21</bitOffset>
              <bitWidth>1</bitWidth>
            </field>
            <field>
              <name>I2C2RST</name>
              <bitOffset>22</bitOffset>
              <bitWidth>1</bitWidth>
            </field>
            <field>
              <name>I2C3RST</name>
              <bitOffset>23</bitOffset>
              <bitWidth>1</bitWidth>
            </field>
            <field>
              <name>I2C4RST</name>
              <bitOffset>24</bitOffset>
              <bitWidth>1</bitWidth>
            </field>
            <field>
              <name>CAN1RST</name>
              <bitOffset>25</bitOffset>
              <bitWidth>1</bitWidth>
            </field>
            <field>
              <name>CAN2RST</name>
              <bitOffset>26</bitOffset>
              <bitWidth>1</bitWidth>
            </field>
            <field>
              <name>CECRST</name>
              <bitOffset>27</bitOffset>
              <bitWidth>1</bitWidth>
            </field>
            <field>
              <name>PWRRST</name>
              <bitOffset>28</bitOffset>
              <bitWidth>1</bitWidth>
            </field>
            <field>
              <name>DACRST</name>
              <bitOffset>29</bitOffset>
              <bitWidth>1</bitWidth>
            </field>
            <field>
              <name>UART7RST</name>
              <bitOffset>30</bitOffset>
              <bitWidth>1</bitWidth>
            </field>
            <field>
              <name>UART8RST</name>
              <bitOffset>31</bitOffset>
              <bitWidth>1</bitWidth>
            </field>
          </fields>
        </register>
        <register>
          <name>APB2RSTR</name>
          <addressOffset>0x24</addressOffset>
          <size>0x20</size>
          <fields>
            <field>
              <name>TIM1RST</name>
              <bitOffset>0</bitOffset>
              <bitWidth>1</bitWidth>
            </field>
            <field>
              <name>TIM8RST</name>
              <bitOffset>1</bitOffset>
              <bitWidth>1</bitWidth>
            </field>
            <field>
              <name>USART1RST</name>
              <bitOffset>4</bitOffset>
              <bitWidth>1</bitWidth>
            </field>
            <field>
              <name>USART6RST</name>
              <bitOffset>5</bitOffset>
              <bitWidth>1</bitWidth>
            </field>
            <field>
              <name>SDMMC2RST</name>
              <bitOffset>7</bitOffset>
              <bitWidth>1</bitWidth>
            </field>
            <field>
              <name>ADCRST</name>
              <bitOffset>8</bitOffset>
              <bitWidth>1</bitWidth>
            </field>
            <field>
              <name>SDMMC1RST</name>
              <bitOffset>11</bitOffset>
              <bitWidth>1</bitWidth>
            </field>
            <field>
              <name>SPI1RST</name>
              <bitOffset>12</bitOffset>
              <bitWidth>1</bitWidth>
            </field>
            <field>
              <name>SPI4RST</name>
              <bitOffset>13</bitOffset>
              <bitWidth>1</bitWidth>
            </field>
            <field>
              <name>SYSCFGRST</name>
              <bitOffset>14</bitOffset>
              <bitWidth>1</bitWidth>
            </field>
            <field>
              <name>TIM9RST</name>
              <bitOffset>16</bitOffset>
              <bitWidth>1</bitWidth>
            </field>
            <field>
              <name>TIM10RST</name>
              <bitOffset>17</bitOffset>
              <bitWidth>1</bitWidth>
            </field>
            <field>
              <name>TIM11RST</name>
              <bitOffset>18</bitOffset>
              <bitWidth>1</bitWidth>
            </field>
            <field>
              <name>SPI5RST</name>
              <bitOffset>20</bitOffset>
              <bitWidth>1</bitWidth>
            </field>
            <field>
              <name>SPI6RST</name>
              <bitOffset>21</bitOffset>
              <bitWidth>1</bitWidth>
            </field>
            <field>
              <name>SAI1RST</name>
              <bitOffset>22</bitOffset>
              <bitWidth>1</bitWidth>
            </field>
            <field>
              <name>SAI2RST</name>
              <bitOffset>23</bitOffset>
              <bitWidth>1</bitWidth>
            </field>
            <field>
              <name>LTDCRST</name>
              <bitOffset>26</bitOffset>
              <bitWidth>1</bitWidth>
            </field>
            <field>
              <name>DFSDM1RST</name>
              <bitOffset>29</bitOffset>
              <bitWidth>1</bitWidth>
            </field>
            <field>
              <name>MDIORST</name>
              <bitOffset>30</bitOffset>
              <bitWidth>1</bitWidth>
            </field>
          </fields>
        </register>
        <register>
          <name>AHB1ENR</name>
          <addressOffset>0x30</addressOffset>
          <size>0x20</size>
          <fields>
            <field>
              <name>GPIOAEN</name>
              <bitOffset>0</bitOffset>
              <bitWidth>1</bitWidth>
            </field>
            <field>
              <name>GPIOBEN</name>
              <bitOffset>1</bitOffset>
              <bitWidth>1</bitWidth>
            </field>
            <field>
              <name>GPIOCEN</name>
              <bitOffset>2</bitOffset>
              <bitWidth>1</bitWidth>
            </field>
            <field>
              <name>GPIODEN</name>
              <bitOffset>3</bitOffset>
              <bitWidth>1</bitWidth>
            </field>
            <field>
              <name>GPIOEEN</name>
              <bitOffset>4</bitOffset>
              <bitWidth>1</bitWidth>
            </field>
            <field>
              <name>GPIOFEN</name>
              <bitOffset>5</bitOffset>
              <bitWidth>1</bitWidth>
            </field>
            <field>
              <name>GPIOGEN</name>
              <bitOffset>6</bitOffset>
              <bitWidth>1</bitWidth>
            </field>
            <field>
              <name>GPIOHEN</name>
              <bitOffset>7</bitOffset>
              <bitWidth>1</bitWidth>
            </field>
            <field>
              <name>GPIOIEN</name>
              <bitOffset>8</bitOffset>
              <bitWidth>1</bitWidth>
            </field>
            <field>
              <name>GPIOJEN</name>
              <bitOffset>9</bitOffset>
              <bitWidth>1</bitWidth>
            </field>
            <field>
              <name>GPIOKEN</name>
              <bitOffset>10</bitOffset>
              <bitWidth>1</bitWidth>
            </field>
            <field>
              <name>CRCEN</name>
              <bitOffset>12</bitOffset>
              <bitWidth>1</bitWidth>
            </field>
            <field>
              <name>BKPSRAMEN</name>
              <bitOffset>18</bitOffset>
              <bitWidth>1</bitWidth>
            </field>
            <field>
              <name>DTCMRAMEN</name>
              <bitOffset>20</bitOffset>
              <bitWidth>1</bitWidth>
            </field>
            <field>
              <name>DMA1EN</name>
              <bitOffset>21</bitOffset>
              <bitWidth>1</bitWidth>
            </field>
            <field>
              <name>DMA2EN</name>
              <bitOffset>22</bitOffset>
              <bitWidth>1</bitWidth>
            </field>
            <field>
              <name>DMA2DEN</name>
              <bitOffset>23</bitOffset>
              <bitWidth>1</bitWidth>
            </field>
            <field>
              <name>ETHMACEN</name>
              <bitOffset>25</bitOffset>
              <bitWidth>1</bitWidth>
            </field>
            <field>
              <name>ETHMACTXEN</name>
              <bitOffset>26</bitOffset>
              <bitWidth>1</bitWidth>
            </field>
            <field>
              <name>ETHMACRXEN</name>
              <bitOffset>27</bitOffset>
              <bitWidth>1</bitWidth>
            </field>
            <field>
              <name>ETHMACPTPEN</name>
              <bitOffset>28</bitOffset>
              <bitWidth>1</bitWidth>
            </field>
            <field>
              <name>OTGHSEN</name>
              <bitOffset>29</bitOffset>
              <bitWidth>1</bitWidth>
            </field>
            <field>
              <name>OTGHSULPIEN</name>
              <bitOffset>30</bitOffset>
              <bitWidth>1</bitWidth>
            </field>
          </fields>
        </register>
        <register>
          <name>AHB2ENR</name>
          <addressOffset>0x34</addressOffset>
          <size>0x20</size>
          <fields>
            <field>
              <name>DCMIEN</name>
              <bitOffset>0</bitOffset>
              <bitWidth>1</bitWidth>
            </field>
            <field>
              <name>JPEGEN</name>
              <bitOffset>1</bitOffset>
              <bitWidth>1</bitWidth>
            </field>
            <field>
              <name>RNGEN</name>
              <bitOffset>6</bitOffset>
              <bitWidth>1</bitWidth>
            </field>
            <field>
              <name>OTGFSEN</name>
              <bitOffset>7</bitOffset>
              <bitWidth>1</bitWidth>
            </field>
          </fields>
        </register>
        <register>
          <name>AHB3ENR</name>
          <addressOffset>0x38</addressOffset>
          <size>0x20</size>
          <fields>
            <field>
              <name>FMCEN</name>
              <bitOffset>0</bitOffset>
              <bitWidth>1</bitWidth>
            </field>
            <field>
              <name>QSPIEN</name>
              <bitOffset>1</bitOffset>
              <bitWidth>1</bitWidth>
            </field>
          </fields>
        </register>
        <register>
          <name>APB1ENR</name>
          <addressOffset>0x40</addressOffset>
          <size>0x20</size>
          <fields>
            <field>
              <name>TIM2EN</name>
              <bitOffset>0</bitOffset>
              <bitWidth>1</bitWidth>
            </field>
            <field>
              <name>TIM3EN</name>
              <bitOffset>1</bitOffset>
              <bitWidth>1</bitWidth>
            </field>
            <field>
              <name>TIM4EN</name>
              <bitOffset>2</bitOffset>
              <bitWidth>1</bitWidth>
            </field>
            <field>
              <name>TIM5EN</name>
              <bitOffset>3</bitOffset>
              <bitWidth>1</bitWidth>
            </field>
            <field>
              <name>TIM6EN</name>
              <bitOffset>4</bitOffset>
              <bitWidth>1</bitWidth>
            </field>
            <field>
              <name>TIM7EN</name>
              <bitOffset>5</bitOffset>
              <bitWidth>1</bitWidth>
            </field>
            <field>
              <name>TIM12EN</name>
              <bitOffset>6</bitOffset>
              <bitWidth>1</bitWidth>
            </field>
            <field>
              <name>TIM13EN</name>
              <bitOffset>7</bitOffset>
              <bitWidth>1</bitWidth>
            </field>
            <field>
              <name>TIM14EN</name>
              <bitOffset>8</bitOffset>
              <bitWidth>1</bitWidth>
            </field>
            <field>
              <name>LPTIM1EN</name>
              <bitOffset>9</bitOffset>
              <bitWidth>1</bitWidth>
            </field>
            <field>
              <name>RTCEN</name>
              <bitOffset>10</bitOffset>
              <bitWidth>1</bitWidth>
            </field>
            <field>
              <name>WWDGEN</name>
              <bitOffset>11</bitOffset>
              <bitWidth>1</bitWidth>
            </field>
            <field>
              <name>CAN3EN</name>
              <bitOffset>13</bitOffset>
              <bitWidth>1</bitWidth>
            </field>
            <field>
              <name>SPI2EN</name>
              <bitOffset>14</bitOffset>
              <bitWidth>1</bitWidth>
            </field>
            <field>
              <name>SPI3EN</name>
              <bitOffset>15</bitOffset>
              <bitWidth>1</bitWidth>
            </field>
            <field>
              <name>SPDIFRXEN</name>
              <bitOffset>16</bitOffset>
              <bitWidth>1</bitWidth>
            </field>
            <field>
              <name>USART2EN</name>
              <bitOffset>17</bitOffset>
              <bitWidth>1</bitWidth>
            </field>
            <field>
              <name>USART3EN</name>
              <bitOffset>18</bitOffset>
              <bitWidth>1</bitWidth>
            </field>
            <field>
              <name>UART4EN</name>
              <bitOffset>19</bitOffset>
              <bitWidth>1</bitWidth>
            </field>
            <field>
              <name>UART5EN</name>
              <bitOffset>20</bitOffset>
              <bitWidth>1</bitWidth>
            </field>
            <field>
              <name>I2C1EN</name>
              <bitOffset>21</bitOffset>
              <bitWidth>1</bitWidth>
            </field>
            <field>
              <name>I2C2EN</name>
              <bitOffset>22</bitOffset>
              <bitWidth>1</bitWidth>
            </field>
            <field>
              <name>I2C3EN</name>
              <bitOffset>23</bitOffset>
              <bitWidth>1</bitWidth>
            </field>
            <field>
              <name>I2C4EN</name>
              <bitOffset>24</bitOffset>
              <bitWidth>1</bitWidth>
            </field>
            <field>
              <name>CAN1EN</name>
              <bitOffset>25</bitOffset>
              <bitWidth>1</bitWidth>
            </field>
            <field>
              <name>CAN2EN</name>
              <bitOffset>26</bitOffset>
              <bitWidth>1</bitWidth>
            </field>
            <field>
              <name>CECEN</name>
              <bitOffset>27</bitOffset>
              <bitWidth>1</bitWidth>
            </field>
            <field>
              <name>PWREN</name>
              <bitOffset>28</bitOffset>
              <bitWidth>1</bitWidth>
            </field>
            <field>
              <name>DACEN</name>
              <bitOffset>29</bitOffset>
              <bitWidth>1</bitWidth>
            </field>
            <field>
              <name>UART7EN</name>
              <bitOffset>30</bitOffset>
              <bitWidth>1</bitWidth>
            </field>
            <field>
              <name>UART8EN</name>
              <bitOffset>31</bitOffset>
              <bitWidth>1</bitWidth>
            </field>
          </fields>
        </register>
        <register>
          <name>APB2ENR</name>
          <addressOffset>0x44</addressOffset>
          <size>0x20</size>
          <fields>
            <field>
              <name>TIM1EN</name>
              <bitOffset>0</bitOffset>
              <bitWidth>1</bitWidth>
            </field>
            <field>
              <name>TIM8EN</name>
              <bitOffset>1</bitOffset>
              <bitWidth>1</bitWidth>
            </field>
            <field>
              <name>USART1EN</name>
              <bitOffset>4</bitOffset>
              <bitWidth>1</bitWidth>
            </field>
            <field>
              <name>USART6EN</name>
              <bitOffset>5</bitOffset>
              <bitWidth>1</bitWidth>
            </field>
            <field>
              <name>SDMMC2EN</name>
              <bitOffset>7</bitOffset>
              <bitWidth>1</bitWidth>
            </field>
            <field>
              <name>ADC1EN</name>
              <bitOffset>8</bitOffset>
              <bitWidth>1</bitWidth>
            </field>
            <field>
              <name>ADC2EN</name>
              <bitOffset>9</bitOffset>
              <bitWidth>1</bitWidth>
            </field>
            <field>
              <name>ADC3EN</name>
              <bitOffset>10</bitOffset>
              <bitWidth>1</bitWidth>
            </field>
            <field>
              <name>SDMMC1EN</name>
              <bitOffset>11</bitOffset>
              <bitWidth>1</bitWidth>
            </field>
            <field>
              <name>SPI1EN</name>
              <bitOffset>12</bitOffset>
              <bitWidth>1</bitWidth>
            </field>
            <field>
              <name>SPI4EN</name>
              <bitOffset>13</bitOffset>
              <bitWidth>1</bitWidth>
            </field>
            <field>
              <name>SYSCFGEN</name>
              <bitOffset>14</bitOffset>
              <bitWidth>1</bitWidth>
            </field>
            <field>
              <name>TIM9EN</name>
              <bitOffset>16</bitOffset>
              <bitWidth>1</bitWidth>
            </field>
            <field>
              <name>TIM10EN</name>
              <bitOffset>17</bitOffset>
              <bitWidth>1</bitWidth>
            </field>
            <field>
              <name>TIM11EN</name>
              <bitOffset>18</bitOffset>
              <bitWidth>1</bitWidth>
            </field>
            <field>
              <name>SPI5EN</name>
              <bitOffset>20</bitOffset>
              <bitWidth>1</bitWidth>
            </field>
            <field>
              <name>SPI6EN</name>
              <bitOffset>21</bitOffset>
              <bitWidth>1</bitWidth>
            </field>
            <field>
              <name>SAI1EN</name>
              <bitOffset>22</bitOffset>
              <bitWidth>1</bitWidth>
            </field>
            <field>
              <name>SAI2EN</name>
              <bitOffset>23</bitOffset>
              <bitWidth>1</bitWidth>
            </field>
            <field>
              <name>LTDCEN</name>
              <bitOffset>26</bitOffset>
              <bitWidth>1</bitWidth>
            </field>
            <field>
              <name>DFSDM1EN</name>
              <bitOffset>29</bitOffset>
              <bitWidth>1</bitWidth>
            </field>
            <field>
              <name>MDIOEN</name>
              <bitOffset>30</bitOffset>
              <bitWidth>1</bitWidth>
            </field>
          </fields>
        </register>
        <register>
          <name>AHB1LPENR</name>
          <addressOffset>0x50</addressOffset>
          <size>0x20</size>
          <fields>
            <field>
              <name>GPIOALPEN</name>
              <bitOffset>0</bitOffset>
              <bitWidth>1</bitWidth>
            </field>
            <field>
              <name>GPIOBLPEN</name>
              <bitOffset>1</bitOffset>
              <bitWidth>1</bitWidth>
            </field>
            <field>
              <name>GPIOCLPEN</name>
              <bitOffset>2</bitOffset>
              <bitWidth>1</bitWidth>
            </field>
            <field>
              <name>GPIODLPEN</name>
              <bitOffset>3</bitOffset>
              <bitWidth>1</bitWidth>
            </field>
            <field>
              <name>GPIOELPEN</name>
              <bitOffset>4</bitOffset>
              <bitWidth>1</bitWidth>
            </field>
            <field>
              <name>GPIOFLPEN</name>
              <bitOffset>5</bitOffset>
              <bitWidth>1</bitWidth>
            </field>
            <field>
              <name>GPIOGLPEN</name>
              <bitOffset>6</bitOffset>
              <bitWidth>1</bitWidth>
            </field>
            <field>
              <name>GPIOHLPEN</name>
              <bitOffset>7</bitOffset>
              <bitWidth>1</bitWidth>
            </field>
            <field>
              <name>GPIOILPEN</name>
              <bitOffset>8</bitOffset>
              <bitWidth>1</bitWidth>
            </field>
            <field>
              <name>GPIOJLPEN</name>
              <bitOffset>9</bitOffset>
              <bitWidth>1</bitWidth>
            </field>
            <field>
              <name>GPIOKLPEN</name>
              <bitOffset>10</bitOffset>
              <bitWidth>1</bitWidth>
            </field>
            <field>
              <name>CRCLPEN</name>
              <bitOffset>12</bitOffset>
              <bitWidth>1</bitWidth>
            </field>
            <field>
              <name>AXILPEN</name>
              <bitOffset>13</bitOffset>
              <bitWidth>1</bitWidth>
            </field>
            <field>
              <name>FLITFLPEN</name>
              <bitOffset>15</bitOffset>
              <bitWidth>1</bitWidth>
            </field>
            <field>
              <name>SRAM1LPEN</name>
              <bitOffset>16</bitOffset>
              <bitWidth>1</bitWidth>
            </field>
            <field>
              <name>SRAM2LPEN</name>
              <bitOffset>17</bitOffset>
              <bitWidth>1</bitWidth>
            </field>
            <field>
              <name>BKPSRAMLPEN</name>
              <bitOffset>18</bitOffset>
              <bitWidth>1</bitWidth>
            </field>
            <field>
              <name>DTCMLPEN</name>
              <bitOffset>20</bitOffset>
              <bitWidth>1</bitWidth>
            </field>
            <field>
              <name>DMA1LPEN</name>
              <bitOffset>21</bitOffset>
              <bitWidth>1</bitWidth>
            </field>
            <field>
              <name>DMA2LPEN</name>
              <bitOffset>22</bitOffset>
              <bitWidth>1</bitWidth>
            </field>
            <field>
              <name>DMA2DLPEN</name>
              <bitOffset>23</bitOffset>
              <bitWidth>1</bitWidth>
            </field>
            <field>
              <name>ETHMACLPEN</name>
              <bitOffset>25</bitOffset>
              <bitWidth>1</bitWidth>
            </field>
            <field>
              <name>ETHMACTXLPEN</name>
              <bitOffset>26</bitOffset>
              <bitWidth>1</bitWidth>
            </field>
            <field>
              <name>ETHMACRXLPEN</name>
              <bitOffset>27</bitOffset>
              <bitWidth>1</bitWidth>
            </field>
            <field>
              <name>ETHMACPTPLPEN</name>
              <bitOffset>28</bitOffset>
              <bitWidth>1</bitWidth>
            </field>
            <field>
              <name>OTGHSLPEN</name>
              <bitOffset>29</bitOffset>
              <bitWidth>1</bitWidth>
            </field>
            <field>
              <name>OTGHSULPILPEN</name>
              <bitOffset>30</bitOffset>
              <bitWidth>1</bitWidth>
            </field>
          </fields>
        </register>
        <register>
          <name>AHB2LPENR</name>
          <addressOffset>0x54</addressOffset>
          <size>0x20</size>
          <fields>
            <field>
              <name>DCMILPEN</name>
              <bitOffset>0</bitOffset>
              <bitWidth>1</bitWidth>
            </field>
            <field>
              <name>JPEGLPEN</name>
              <bitOffset>1</bitOffset>
              <bitWidth>1</bitWidth>
            </field>
            <field>
              <name>RNGLPEN</name>
              <bitOffset>6</bitOffset>
              <bitWidth>1</bitWidth>
            </field>
            <field>
              <name>OTGFSLPEN</name>
              <bitOffset>7</bitOffset>
              <bitWidth>1</bitWidth>
            </field>
          </fields>
        </register>
        <register>
          <name>AHB3LPENR</name>
          <addressOffset>0x58</addressOffset>
          <size>0x20</size>
          <fields>
            <field>
              <name>FMCLPEN</name>
              <bitOffset>0</bitOffset>
              <bitWidth>1</bitWidth>
            </field>
            <field>
              <name>QSPILPEN</name>
              <bitOffset>1</bitOffset>
              <bitWidth>1</bitWidth>
            </field>
          </fields>
        </register>
        <register>
          <name>APB1LPENR</name>
          <addressOffset>0x60</addressOffset>
          <size>0x20</size>
          <fields>
            <field>
              <name>TIM2LPEN</name>
              <bitOffset>0</bitOffset>
              <bitWidth>1</bitWidth>
            </field>
            <field>
              <name>TIM3LPEN</name>
              <bitOffset>1</bitOffset>
              <bitWidth>1</bitWidth>
            </field>
            <field>
              <name>TIM4LPEN</name>
              <bitOffset>2</bitOffset>
              <bitWidth>1</bitWidth>
            </field>
            <field>
              <name>TIM5LPEN</name>
              <bitOffset>3</bitOffset>
              <bitWidth>1</bitWidth>
            </field>
            <field>
              <name>TIM6LPEN</name>
              <bitOffset>4</bitOffset>
              <bitWidth>1</bitWidth>
            </field>
            <field>
              <name>TIM7LPEN</name>
              <bitOffset>5</bitOffset>
              <bitWidth>1</bitWidth>
            </field>
            <field>
              <name>TIM12LPEN</name>
              <bitOffset>6</bitOffset>
              <bitWidth>1</bitWidth>
            </field>
            <field>
              <name>TIM13LPEN</name>
              <bitOffset>7</bitOffset>
              <bitWidth>1</bitWidth>
            </field>
            <field>
              <name>TIM14LPEN</name>
              <bitOffset>8</bitOffset>
              <bitWidth>1</bitWidth>
            </field>
            <field>
              <name>LPTIM1LPEN</name>
              <bitOffset>9</bitOffset>
              <bitWidth>1</bitWidth>
            </field>
            <field>
              <name>RTCLPEN</name>
              <bitOffset>10</bitOffset>
              <bitWidth>1</bitWidth>
            </field>
            <field>
              <name>WWDGLPEN</name>
              <bitOffset>11</bitOffset>
              <bitWidth>1</bitWidth>
            </field>
            <field>
              <name>CAN3LPEN</name>
              <bitOffset>13</bitOffset>
              <bitWidth>1</bitWidth>
            </field>
            <field>
              <name>SPI2LPEN</name>
              <bitOffset>14</bitOffset>
              <bitWidth>1</bitWidth>
            </field>
            <field>
              <name>SPI3LPEN</name>
              <bitOffset>15</bitOffset>
              <bitWidth>1</bitWidth>
            </field>
            <field>
              <name>SPDIFRXLPEN</name>
              <bitOffset>16</bitOffset>
              <bitWidth>1</bitWidth>
            </field>
            <field>
              <name>USART2LPEN</name>
              <bitOffset>17</bitOffset>
              <bitWidth>1</bitWidth>
            </field>
            <field>
              <name>USART3LPEN</name>
              <bitOffset>18</bitOffset>
              <bitWidth>1</bitWidth>
            </field>
            <field>
              <name>UART4LPEN</name>
              <bitOffset>19</bitOffset>
              <bitWidth>1</bitWidth>
            </field>
            <field>
              <name>UART5LPEN</name>
              <bitOffset>20</bitOffset>
              <bitWidth>1</bitWidth>
            </field>
            <field>
              <name>I2C1LPEN</name>
              <bitOffset>21</bitOffset>
              <bitWidth>1</bitWidth>
            </field>
            <field>
              <name>I2C2LPEN</name>
              <bitOffset>22</bitOffset>
              <bitWidth>1</bitWidth>
            </field>
            <field>
              <name>I2C3LPEN</name>
              <bitOffset>23</bitOffset>
              <bitWidth>1</bitWidth>
            </field>
            <field>
              <name>I2C4LPEN</name>
              <bitOffset>24</bitOffset>
              <bitWidth>1</bitWidth>
            </field>
            <field>
              <name>CAN1LPEN</name>
              <bitOffset>25</bitOffset>
              <bitWidth>1</bitWidth>
            </field>
            <field>
              <name>CAN2LPEN</name>
              <bitOffset>26</bitOffset>
              <bitWidth>1</bitWidth>
            </field>
            <field>
              <name>CECLPEN</name>
              <bitOffset>27</bitOffset>
              <bitWidth>1</bitWidth>
            </field>
            <field>
              <name>PWRLPEN</name>
              <bitOffset>28</bitOffset>
              <bitWidth>1</bitWidth>
            </field>
            <field>
              <name>DACLPEN</name>
              <bitOffset>29</bitOffset>
              <bitWidth>1</bitWidth>
            </field>
            <field>
              <name>UART7LPEN</name>
              <bitOffset>30</bitOffset>
              <bitWidth>1</bitWidth>
            </field>
            <field>
              <name>UART8LPEN</name>
              <bitOffset>31</bitOffset>
              <bitWidth>1</bitWidth>
            </field>
          </fields>
        </register>
        <register>
          <name>APB2LPENR</name>
          <addressOffset>0x64</addressOffset>
          <size>0x20</size>
          <fields>
            <field>
              <name>TIM1LPEN</name>
              <bitOffset>0</bitOffset>
              <bitWidth>1</bitWidth>
            </field>
            <field>
              <name>TIM8LPEN</name>
              <bitOffset>1</bitOffset>
              <bitWidth>1</bitWidth>
            </field>
            <field>
              <name>USART1LPEN</name>
              <bitOffset>4</bitOffset>
              <bitWidth>1</bitWidth>
            </field>
            <field>
              <name>USART6LPEN</name>
              <bitOffset>5</bitOffset>
              <bitWidth>1</bitWidth>
            </field>
            <field>
              <name>SDMMC2LPEN</name>
              <bitOffset>7</bitOffset>
              <bitWidth>1</bitWidth>
            </field>
            <field>
              <name>ADC1LPEN</name>
              <bitOffset>8</bitOffset>
              <bitWidth>1</bitWidth>
            </field>
            <field>
              <name>ADC2LPEN</name>
              <bitOffset>9</bitOffset>
              <bitWidth>1</bitWidth>
            </field>
            <field>
              <name>ADC3LPEN</name>
              <bitOffset>10</bitOffset>
              <bitWidth>1</bitWidth>
            </field>
            <field>
              <name>SDMMC1LPEN</name>
              <bitOffset>11</bitOffset>
              <bitWidth>1</bitWidth>
            </field>
            <field>
              <name>SPI1LPEN</name>
              <bitOffset>12</bitOffset>
              <bitWidth>1</bitWidth>
            </field>
            <field>
              <name>SPI4LPEN</name>
              <bitOffset>13</bitOffset>
              <bitWidth>1</bitWidth>
            </field>
            <field>
              <name>SYSCFGLPEN</name>
              <bitOffset>14</bitOffset>
              <bitWidth>1</bitWidth>
            </field>
            <field>
              <name>TIM9LPEN</name>
              <bitOffset>16</bitOffset>
              <bitWidth>1</bitWidth>
            </field>
            <field>
              <name>TIM10LPEN</name>
              <bitOffset>17</bitOffset>
              <bitWidth>1</bitWidth>
            </field>
            <field>
              <name>TIM11LPEN</name>
              <bitOffset>18</bitOffset>
              <bitWidth>1</bitWidth>
            </field>
            <field>
              <name>SPI5LPEN</name>
              <bitOffset>20</bitOffset>
              <bitWidth>1</bitWidth>
            </field>
            <field>
              <name>SPI6LPEN</name>
              <bitOffset>21</bitOffset>
              <bitWidth>1</bitWidth>
            </field>
            <field>
              <name>SAI1LPEN</name>
              <bitOffset>22</bitOffset>
              <bitWidth>1</bitWidth>
            </field>
            <field>
              <name>SAI2LPEN</name>
              <bitOffset>23</bitOffset>
              <bitWidth>1</bitWidth>
            </field>
            <field>
              <name>LTDCLPEN</name>
              <bitOffset>26</bitOffset>
              <bitWidth>1</bitWidth>
            </field>
            <field>
              <name>DFSDM1LPEN</name>
              <bitOffset>29</bitOffset>
              <bitWidth>1</bitWidth>
            </field>
            <field>
              <name>MDIOLPEN</name>
              <bitOffset>30</bitOffset>
              <bitWidth>1</bitWidth>
            </field>
          </fields>
        </register>
        <register>
          <name>BDCR</name>
          <addressOffset>0x70</addressOffset>
          <size>0x20</size>
          <fields>
            <field>
              <name>LSEON</name>
              <bitOffset>0</bitOffset>
              <bitWidth>1</bitWidth>
            </field>
            <field>
              <name>LSERDY</name>
              <bitOffset>1</bitOffset>
              <bitWidth>1</bitWidth>
            </field>
            <field>
              <name>LSEBYP</name>
              <bitOffset>2</bitOffset>
              <bitWidth>1</bitWidth>
            </field>
            <field>
              <name>LSEDRV</name>
              <bitOffset>3</bitOffset>
              <bitWidth>2</bitWidth>
            </field>
            <field>
              <name>RTCSEL</name>
              <bitOffset>8</bitOffset>
              <bitWidth>2</bitWidth>
            </field>
            <field>
              <name>RTCEN</name>
              <bitOffset>15</bitOffset>
              <bitWidth>1</bitWidth>
            </field>
            <field>
              <name>BDRST</name>
              <bitOffset>16</bitOffset>
              <bitWidth>1</bitWidth>
            </field>
          </fields>
        </register>
        <register>
          <name>CSR</name>
          <addressOffset>0x74</addressOffset>
          <size>0x20</size>
          <fields>
            <field>
              <name>LSION</name>
              <bitOffset>0</bitOffset>
              <bitWidth>1</bitWidth>
            </field>
            <field>
              <name>LSIRDY</name>
              <bitOffset>1</bitOffset>
              <bitWidth>1</bitWidth>
            </field>
            <field>
              <name>RMVF</name>
              <bitOffset>24</bitOffset>
              <bitWidth>1</bitWidth>
            </field>
            <field>
              <name>BORRSTF</name>
              <bitOffset>25</bitOffset>
              <bitWidth>1</bitWidth>
            </field>
            <field>
              <name>PINRSTF</name>
              <bitOffset>26</bitOffset>
              <bitWidth>1</bitWidth>
            </field>
            <field>
              <name>PORRSTF</name>
              <bitOffset>27</bitOffset>
              <bitWidth>1</bitWidth>
            </field>
            <field>
              <name>SFTRSTF</name>
              <bitOffset>28</bitOffset>
              <bitWidth>1</bitWidth>
            </field>
            <field>
              <name>IWDGRSTF</name>
              <bitOffset>29</bitOffset>
              <bitWidth>1</bitWidth>
            </field>
            <field>
              <name>WWDGRSTF</name>
              <bitOffset>30</bitOffset>
              <bitWidth>1</bitWidth>
            </field>
            <field>
              <name>LPWRRSTF</name>
              <bitOffset>31</bitOffset>
              <bitWidth>1</bitWidth>
            </field>
          </fields>
        </register>
        <register>
          <name>SSCGR</name>
          <addressOffset>0x80</addressOffset>
          <size>0x20</size>
          <fields>
            <field>
              <name>MODPER</name>
              <bitOffset>0</bitOffset>
              <bitWidth>13</bitWidth>
            </field>
            <field>
              <name>INCSTEP</name>
              <bitOffset>13</bitOffset>
              <bitWidth>15</bitWidth>
            </field>
            <field>
              <name>SPREADSEL</name>
              <bitOffset>30</bitOffset>
              <bitWidth>1</bitWidth>
            </field>
            <field>
              <name>SSCGEN</name>
              <bitOffset>31</bitOffset>
              <bitWidth>1</bitWidth>
            </field>
          </fields>
        </register>
        <register>
          <name>PLLI2SCFGR</name>
          <addressOffset>0x84</addressOffset>
          <size>0x20</size>
          <fields>
            <field>
              <name>PLLI2SN</name>
              <bitOffset>6</bitOffset>
              <bitWidth>9</bitWidth>
            </field>
            <field>
              <name>PLLI2SP</name>
              <bitOffset>16</bitOffset>
              <bitWidth>2</bitWidth>
            </field>
            <field>
              <name>PLLI2SQ</name>
              <bitOffset>24</bitOffset>
              <bitWidth>4</bitWidth>
            </field>
            <field>
              <name>PLLI2SR</name>
              <bitOffset>28</bitOffset>
              <bitWidth>3</bitWidth>
            </field>
          </fields>
        </register>
        <register>
          <name>PLLSAICFGR</name>
          <addressOffset>0x88</addressOffset>
          <size>0x20</size>
          <fields>
            <field>
              <name>PLLSAIN</name>
              <bitOffset>6</bitOffset>
              <bitWidth>9</bitWidth>
            </field>
            <field>
              <name>PLLSAIP</name>
              <bitOffset>16</bitOffset>
              <bitWidth>2</bitWidth>
            </field>
            <field>
              <name>PLLSAIQ</name>
              <bitOffset>24</bitOffset>
              <bitWidth>4</bitWidth>
            </field>
            <field>
              <name>PLLSAIR</name>
              <bitOffset>28</bitOffset>
              <bitWidth>3</bitWidth>
            </field>
          </fields>
        </register>
        <register>
          <name>DCKCFGR1</name>
          <addressOffset>0x8c</addressOffset>
          <size>0x20</size>
          <fields>
            <field>
              <name>PLLI2SDIVQ</name>
              <bitOffset>0</bitOffset>
              <bitWidth>5</bitWidth>
            </field>
            <field>
              <name>PLLSAIDIVQ</name>
              <bitOffset>8</bitOffset>
              <bitWidth>5</bitWidth>
            </field>
            <field>
              <name>PLLSAIDIVR</name>
              <bitOffset>16</bitOffset>
              <bitWidth>2</bitWidth>
            </field>
            <field>
              <name>SAI1SEL</name>
              <bitOffset>20</bitOffset>
              <bitWidth>2</bitWidth>
            </field>
            <field>
              <name>SAI2SEL</name>
              <bitOffset>22</bitOffset>
              <bitWidth>2</bitWidth>
            </field>
            <field>
              <name>TIMPRE</name>
              <bitOffset>24</bitOffset>
              <bitWidth>1</bitWidth>
            </field>
            <field>
              <name>DFSDM1SEL</name>
              <bitOffset>25</bitOffset>
              <bitWidth>1</bitWidth>
            </field>
            <field>
              <name>ADFSDM1SEL</name>
              <bitOffset>26</bitOffset>
              <bitWidth>1</bitWidth>
            </field>
          </fields>
        </register>
        <register>
          <name>DCKCFGR2</name>
          <addressOffset>0x90</addressOffset>
          <size>0x20</size>
          <fields>
            <field>
              <name>USART1SEL</name>
              <bitOffset>0</bitOffset>
              <bitWidth>2</bitWidth>
            </field>
            <field>
              <name>USART2SEL</name>
              <bitOffset>2</bitOffset>
              <bitWidth>2</bitWidth>
            </field>
            <field>
              <name>USART3SEL</name>
              <bitOffset>4</bitOffset>
              <bitWidth>2</bitWidth>
            </field>
            <field>
              <name>UART4SEL</name>
              <bitOffset>6</bitOffset>
              <bitWidth>2</bitWidth>
            </field>
            <field>
              <name>UART5SEL</name>
              <bitOffset>8</bitOffset>
              <bitWidth>2</bitWidth>
            </field>
            <field>
              <name>USART6SEL</name>
              <bitOffset>10</bitOffset>
              <bitWidth>2</bitWidth>
            </field>
            <field>
              <name>UART7SEL</name>
              <bitOffset>12</bitOffset>
              <bitWidth>2</bitWidth>
            </field>
            <field>
              <name>UART8SEL</name>
              <bitOffset>14</bitOffset>
              <bitWidth>2</bitWidth>
            </field>
            <field>
              <name>I2C1SEL</name>
              <bitOffset>16</bitOffset>
              <bitWidth>2</bitWidth>
            </field>
            <field>
              <name>I2C2SEL</name>
              <bitOffset>18</bitOffset>
              <bitWidth>2</bitWidth>
            </field>
            <field>
              <name>I2C3SEL</name>
              <bitOffset>20</bitOffset>
              <bitWidth>2</bitWidth>
            </field>
            <field>
              <name>I2C4SEL</name>
              <bitOffset>22</bitOffset>
              <bitWidth>2</bitWidth>
            </field>
            <field>
              <name>LPTIM1SEL</name>
              <bitOffset>24</bitOffset>
              <bitWidth>2</bitWidth>
            </field>
            <field>
              <name>CECSEL</name>
              <bitOffset>26</bitOffset>
              <bitWidth>1</bitWidth>
            </field>
            <field>
              <name>CK48MSEL</name>
              <bitOffset>27</bitOffset>
              <bitWidth>1</bitWidth>
            </field>
            <field>
              <name>SDMMC1SEL</name>
              <bitOffset>28</bitOffset>
              <bitWidth>1</bitWidth>
            </field>
            <field>
              <name>SDMMC2SEL</name>
              <bitOffset>29</bitOffset>
              <bitWidth>1</bitWidth>
            </field>
          </fields>
        </register>
      </registers>
    </peripheral>
    <peripheral>
      <name>FLASH</name>
      <baseAddress>0x40023c00</baseAddress>
      <registers>
        <register>
          <name>ACR</name>
          <addressOffset>0x0</addressOffset>
          <size>0x20</size>
          <fields>
            <field>
              <name>LATENCY</name>
              <bitOffset>0</bitOffset>
              <bitWidth>4</bitWidth>
            </field>
            <field>
              <name>PRFTEN</name>
              <bitOffset>8</bitOffset>
              <bitWidth>1</bitWidth>
            </field>
            <field>
              <name>ARTEN</name>
              <bitOffset>9</bitOffset>
              <bitWidth>1</bitWidth>
            </field>
            <field>
              <name>ARTRST</name>
              <bitOffset>11</bitOffset>
              <bitWidth>1</bitWidth>
            </field>
          </fields>
        </register>
        <register>
          <name>KEYR</name>
          <addressOffset>0x4</addressOffset>
          <size>0x20</size>
        </register>
        <register>
          <name>OPTKEYR</name>
          <addressOffset>0x8</addressOffset>
          <size>0x20</size>
        </register>
        <register>
          <name>SR</name>
          <addressOffset>0xc</addressOffset>
          <size>0x20</size>
          <fields>
            <field>
              <name>EOP</name>
              <bitOffset>0</bitOffset>
              <bitWidth>1</bitWidth>
            </field>
            <field>
              <name>OPERR</name>
              <bitOffset>1</bitOffset>
              <bitWidth>1</bitWidth>
            </field>
            <field>
              <name>WRPERR</name>
              <bitOffset>4</bitOffset>
              <bitWidth>1</bitWidth>
            </field>
            <field>
              <name>PGAERR</name>
              <bitOffset>5</bitOffset>
              <bitWidth>1</bitWidth>
            </field>
            <field>
              <name>PGPERR</name>
              <bitOffset>6</bitOffset>
              <bitWidth>1</bitWidth>
            </field>
            <field>
              <name>ERSERR</name>
              <bitOffset>7</bitOffset>
              <bitWidth>1</bitWidth>
            </field>
            <field>
              <name>BSY</name>
              <bitOffset>16</bitOffset>
              <bitWidth>1</bitWidth>
            </field>
          </fields>
        </register>
        <register>
          <name>CR</name>
          <addressOffset>0x10</addressOffset>
          <size>0x20</size>
          <fields>
            <field>
              <name>PG</name>
              <bitOffset>0</bitOffset>
              <bitWidth>1</bitWidth>
            </field>
            <field>
              <name>SER</name>
              <bitOffset>1</bitOffset>
              <bitWidth>1</bitWidth>
            </field>
            <field>
              <name>MER</name>
              <bitOffset>2</bitOffset>
              <bitWidth>1</bitWidth>
            </field>
            <field>
              <name>SNB</name>
              <bitOffset>3</bitOffset>
              <bitWidth>5</bitWidth>
            </field>
            <field>
              <name>PSIZE</name>
              <bitOffset>8</bitOffset>
              <bitWidth>2</bitWidth>
            </field>
            <field>
              <name>MER2</name>
              <bitOffset>15</bitOffset>
              <bitWidth>1</bitWidth>
            </field>
            <field>
              <name>STRT</name>
              <bitOffset>16</bitOffset>
              <bitWidth>1</bitWidth>
            </field>
            <field>
              <name>EOPIE</name>
              <bitOffset>24</bitOffset>
              <bitWidth>1</bitWidth>
            </field>
            <field>
              <name>ERRIE</name>
              <bitOffset>25</bitOffset>
              <bitWidth>1</bitWidth>
            </field>
            <field>
              <name>LOCK</name>
              <bitOffset>31</bitOffset>
              <bitWidth>1</bitWidth>
            </field>
          </fields>
        </register>
        <register>
          <name>OPTCR</name>
          <addressOffset>0x14</addressOffset>
          <size>0x20</size>
          <fields>
            <field>
              <name>OPTLOCK</name>
              <bitOffset>0</bitOffset>
              <bitWidth>1</bitWidth>
            </field>
            <field>
              <name>OPTSTRT</name>
              <bitOffset>1</bitOffset>
              <bitWidth>1</bitWidth>
            </field>
            <field>
              <name>BOR_LEV</name>
              <bitOffset>2</bitOffset>
              <bitWidth>2</bitWidth>
            </field>
            <field>
              <name>WWDG_SW</name>
              <bitOffset>4</bitOffset>
              <bitWidth>1</bitWidth>
            </field>
            <field>
              <name>IWDG_SW</name>
              <bitOffset>5</bitOffset>
              <bitWidth>1</bitWidth>
            </field>
            <field>
              <name>nRST_STOP</name>
              <bitOffset>6</bitOffset>
              <bitWidth>1</bitWidth>
            </field>
            <field>
              <name>nRST_STDBY</name>
              <bitOffset>7</bitOffset>
              <bitWidth>1</bitWidth>
            </field>
            <field>
              <name>RDP</name>
              <bitOffset>8</bitOffset>
              <bitWidth>8</bitWidth>
            </field>
            <field>
              <name>nWRP</name>
              <bitOffset>16</bitOffset>
              <bitWidth>12</bitWidth>
            </field>
            <field>
              <name>nDBOOT</name>
              <bitOffset>28</bitOffset>
              <bitWidth>1</bitWidth>
            </field>
            <field>
              <name>nDBANK</name>
              <bitOffset>29</bitOffset>
              <bitWidth>1</bitWidth>
            </field>
            <field>
              <name>IWDG_STDBY</name>
              <bitOffset>30</bitOffset>
              <bitWidth>1</bitWidth>
            </field>
            <field>
              <name>IWDG_STOP</name>
              <bitOffset>31</bitOffset>
              <bitWidth>1</bitWidth>
            </field>
          </fields>
        </register>
        <register>
          <name>OPTCR1</name>
          <addressOffset>0x18</addressOffset>
          <size>0x20</size>
          <fields>
            <field>
              <name>BOOT_ADD0</name>
              <bitOffset>0</bitOffset>
              <bitWidth>16</bitWidth>
            </field>
            <field>
              <name>BOOT_ADD1</name>
              <bitOffset>16</bitOffset>
              <bitWidth>16</bitWidth>
            </field>
          </fields>
        </register>
      </registers>
    </peripheral>
    <peripheral>
      <name>DMA1</name>
      <baseAddress>0x40026000</baseAddress>
      <registers>
        <register>
          <name>LISR</name>
          <addressOffset>0x0</addressOffset>
          <size>0x20</size>
          <fields>
            <field>
              <name>FEIF0</name>
              <bitOffset>0</bitOffset>
              <bitWidth>1</bitWidth>
            </field>
            <field>
              <name>DMEIF0</name>
              <bitOffset>2</bitOffset>
              <bitWidth>1</bitWidth>
            </field>
            <field>
              <name>TEIF0</name>
              <bitOffset>3</bitOffset>
              <bitWidth>1</bitWidth>
            </field>
            <field>
              <name>HTIF0</name>
              <bitOffset>4</bitOffset>
              <bitWidth>1</bitWidth>
            </field>
            <field>
              <name>TCIF0</name>
              <bitOffset>5</bitOffset>
              <bitWidth>1</bitWidth>
            </field>
            <field>
              <name>FEIF1</name>
              <bitOffset>6</bitOffset>
              <bitWidth>1</bitWidth>
            </field>
            <field>
              <name>DMEIF1</name>
              <bitOffset>8</bitOffset>
              <bitWidth>1</bitWidth>
            </field>
            <field>
              <name>TEIF1</name>
              <bitOffset>9</bitOffset>
              <bitWidth>1</bitWidth>
            </field>
            <field>
              <name>HTIF1</name>
              <bitOffset>10</bitOffset>
              <bitWidth>1</bitWidth>
            </field>
            <field>
              <name>TCIF1</name>
              <bitOffset>11</bitOffset>
              <bitWidth>1</bitWidth>
            </field>
            <field>
              <name>FEIF2</name>
              <bitOffset>16</bitOffset>
              <bitWidth>1</bitWidth>
            </field>
            <field>
              <name>DMEIF2</name>
              <bitOffset>18</bitOffset>
              <bitWidth>1</bitWidth>
            </field>
            <field>
              <name>TEIF2</name>
              <bitOffset>19</bitOffset>
              <bitWidth>1</bitWidth>
            </field>
            <field>
              <name>HTIF2</name>
              <bitOffset>20</bitOffset>
              <bitWidth>1</bitWidth>
            </field>
            <field>
              <name>TCIF2</name>
              <bitOffset>21</bitOffset>
              <bitWidth>1</bitWidth>
            </field>
            <field>
              <name>FEIF3</name>
              <bitOffset>22</bitOffset>
              <bitWidth>1</bitWidth>
            </field>
            <field>
              <name>DMEIF3</name>
              <bitOffset>24</bitOffset>
              <bitWidth>1</bitWidth>
            </field>
            <field>
              <name>TEIF3</name>
              <bitOffset>25</bitOffset>
              <bitWidth>1</bitWidth>
            </field>
            <field>
              <name>HTIF3</name>
              <bitOffset>26</bitOffset>
              <bitWidth>1</bitWidth>
            </field>
            <field>
              <name>TCIF3</name>
              <bitOffset>27</bitOffset>
              <bitWidth>1</bitWidth>
            </field>
          </fields>
        </register>
        <register>
          <name>HISR</name>
          <addressOffset>0x4</addressOffset>
          <size>0x20</size>
          <fields>
            <field>
              <name>FEIF4</name>
              <bitOffset>0</bitOffset>
              <bitWidth>1</bitWidth>
            </field>
            <field>
              <name>DMEIF4</name>
              <bitOffset>2</bitOffset>
              <bitWidth>1</bitWidth>
            </field>
            <field>
              <name>TEIF4</name>
              <bitOffset>3</bitOffset>
              <bitWidth>1</bitWidth>
            </field>
            <field>
              <name>HTIF4</name>
              <bitOffset>4</bitOffset>
              <bitWidth>1</bitWidth>
            </field>
            <field>
              <name>TCIF4</name>
              <bitOffset>5</bitOffset>
              <bitWidth>1</bitWidth>
            </field>
            <field>
              <name>FEIF5</name>
              <bitOffset>6</bitOffset>
              <bitWidth>1</bitWidth>
            </field>
            <field>
              <name>DMEIF5</name>
              <bitOffset>8</bitOffset>
              <bitWidth>1</bitWidth>
            </field>
            <field>
              <name>TEIF5</name>
              <bitOffset>9</bitOffset>
              <bitWidth>1</bitWidth>
            </field>
            <field>
              <name>HTIF5</name>
              <bitOffset>10</bitOffset>
              <bitWidth>1</bitWidth>
            </field>
            <field>
              <name>TCIF5</name>
              <bitOffset>11</bitOffset>
              <bitWidth>1</bitWidth>
            </field>
            <field>
              <name>FEIF6</name>
              <bitOffset>16</bitOffset>
              <bitWidth>1</bitWidth>
            </field>
            <field>
              <name>DMEIF6</name>
              <bitOffset>18</bitOffset>
              <bitWidth>1</bitWidth>
            </field>
            <field>
              <name>TEIF6</name>
              <bitOffset>19</bitOffset>
              <bitWidth>1</bitWidth>
            </field>
            <field>
              <name>HTIF6</name>
              <bitOffset>20</bitOffset>
              <bitWidth>1</bitWidth>
            </field>
            <field>
              <name>TCIF6</name>
              <bitOffset>21</bitOffset>
              <bitWidth>1</bitWidth>
            </field>
            <field>
              <name>FEIF7</name>
              <bitOffset>22</bitOffset>
              <bitWidth>1</bitWidth>
            </field>
            <field>
              <name>DMEIF7</name>
              <bitOffset>24</bitOffset>
              <bitWidth>1</bitWidth>
            </field>
            <field>
              <name>TEIF7</name>
              <bitOffset>25</bitOffset>
              <bitWidth>1</bitWidth>
            </field>
            <field>
              <name>HTIF7</name>
              <bitOffset>26</bitOffset>
              <bitWidth>1</bitWidth>
            </field>
            <field>
              <name>TCIF7</name>
              <bitOffset>27</bitOffset>
              <bitWidth>1</bitWidth>
            </field>
          </fields>
        </register>
        <register>
          <name>LIFCR</name>
          <addressOffset>0x8</addressOffset>
          <size>0x20</size>
          <fields>
            <field>
              <name>CFEIF0</name>
              <bitOffset>0</bitOffset>
              <bitWidth>1</bitWidth>
            </field>
            <field>
              <name>CDMEIF0</name>
              <bitOffset>2</bitOffset>
              <bitWidth>1</bitWidth>
            </field>
            <field>
              <name>CTEIF0</name>
              <bitOffset>3</bitOffset>
              <bitWidth>1</bitWidth>
            </field>
            <field>
              <name>CHTIF0</name>
              <bitOffset>4</bitOffset>
              <bitWidth>1</bitWidth>
            </field>
            <field>
              <name>CTCIF0</name>
              <bitOffset>5</bitOffset>
              <bitWidth>1</bitWidth>
            </field>
            <field>
              <name>CFEIF1</name>
              <bitOffset>6</bitOffset>
              <bitWidth>1</bitWidth>
            </field>
            <field>
              <name>CDMEIF1</name>
              <bitOffset>8</bitOffset>
              <bitWidth>1</bitWidth>
            </field>
            <field>
              <name>CTEIF1</name>
              <bitOffset>9</bitOffset>
              <bitWidth>1</bitWidth>
            </field>
            <field>
              <name>CHTIF1</name>
              <bitOffset>10</bitOffset>
              <bitWidth>1</bitWidth>
            </field>
            <field>
              <name>CTCIF1</name>
              <bitOffset>11</bitOffset>
              <bitWidth>1</bitWidth>
            </field>
            <field>
              <name>CFEIF2</name>
              <bitOffset>16</bitOffset>
              <bitWidth>1</bitWidth>
            </field>
            <field>
              <name>CDMEIF2</name>
              <bitOffset>18</bitOffset>
              <bitWidth>1</bitWidth>
            </field>
            <field>
              <name>CTEIF2</name>
              <bitOffset>19</bitOffset>
              <bitWidth>1</bitWidth>
            </field>
            <field>
              <name>CHTIF2</name>
              <bitOffset>20</bitOffset>
              <bitWidth>1</bitWidth>
            </field>
            <field>
              <name>CTCIF2</name>
              <bitOffset>21</bitOffset>
              <bitWidth>1</bitWidth>
            </field>
            <field>
              <name>CFEIF3</name>
              <bitOffset>22</bitOffset>
              <bitWidth>1</bitWidth>
            </field>
            <field>
              <name>CDMEIF3</name>
              <bitOffset>24</bitOffset>
              <bitWidth>1</bitWidth>
            </field>
            <field>
              <name>CTEIF3</name>
              <bitOffset>25</bitOffset>
              <bitWidth>1</bitWidth>
            </field>
            <field>
              <name>CHTIF3</name>
              <bitOffset>26</bitOffset>
              <bitWidth>1</bitWidth>
            </field>
            <field>
              <name>CTCIF3</name>
              <bitOffset>27</bitOffset>
              <bitWidth>1</bitWidth>
            </field>
          </fields>
        </register>
        <register>
          <name>HIFCR</name>
          <addressOffset>0xc</addressOffset>
          <size>0x20</size>
          <fields>
            <field>
              <name>CFEIF4</name>
              <bitOffset>0</bitOffset>
              <bitWidth>1</bitWidth>
            </field>
            <field>
              <name>CDMEIF4</name>
              <bitOffset>2</bitOffset>
              <bitWidth>1</bitWidth>
            </field>
            <field>
              <name>CTEIF4</name>
              <bitOffset>3</bitOffset>
              <bitWidth>1</bitWidth>
            </field>
            <field>
              <name>CHTIF4</name>
              <bitOffset>4</bitOffset>
              <bitWidth>1</bitWidth>
            </field>
            <field>
              <name>CTCIF4</name>
              <bitOffset>5</bitOffset>
              <bitWidth>1</bitWidth>
            </field>
            <field>
              <name>CFEIF5</name>
              <bitOffset>6</bitOffset>
              <bitWidth>1</bitWidth>
            </field>
            <field>
              <name>CDMEIF5</name>
              <bitOffset>8</bitOffset>
              <bitWidth>1</bitWidth>
            </field>
            <field>
              <name>CTEIF5</name>
              <bitOffset>9</bitOffset>
              <bitWidth>1</bitWidth>
            </field>
            <field>
              <name>CHTIF5</name>
              <bitOffset>10</bitOffset>
              <bitWidth>1</bitWidth>
            </field>
            <field>
              <name>CTCIF5</name>
              <bitOffset>11</bitOffset>
              <bitWidth>1</bitWidth>
            </field>
            <field>
              <name>CFEIF6</name>
              <bitOffset>16</bitOffset>
              <bitWidth>1</bitWidth>
            </field>
            <field>
              <name>CDMEIF6</name>
              <bitOffset>18</bitOffset>
              <bitWidth>1</bitWidth>
            </field>
            <field>
              <name>CTEIF6</name>
              <bitOffset>19</bitOffset>
              <bitWidth>1</bitWidth>
            </field>
            <field>
              <name>CHTIF6</name>
              <bitOffset>20</bitOffset>
              <bitWidth>1</bitWidth>
            </field>
            <field>
              <name>CTCIF6</name>
              <bitOffset>21</bitOffset>
              <bitWidth>1</bitWidth>
            </field>
            <field>
              <name>CFEIF7</name>
              <bitOffset>22</bitOffset>
              <bitWidth>1</bitWidth>
            </field>
            <field>
              <name>CDMEIF7</name>
              <bitOffset>24</bitOffset>
              <bitWidth>1</bitWidth>
            </field>
            <field>
              <name>CTEIF7</name>
              <bitOffset>25</bitOffset>
              <bitWidth>1</bitWidth>
            </field>
            <field>
              <name>CHTIF7</name>
              <bitOffset>26</bitOffset>
              <bitWidth>1</bitWidth>
            </field>
            <field>
              <name>CTCIF7</name>
              <bitOffset>27</bitOffset>
              <bitWidth>1</bitWidth>
            </field>
          </fields>
        </register>
        <register>
          <name>CR0</name>
          <addressOffset>0x10</addressOffset>
          <size>0x20</size>
        </register>
        <register>
          <name>CR0</name>
          <addressOffset>0x10</addressOffset>
          <size>0x20</size>
        </register>
        <register>
          <name>NDTR0</name>
          <addressOffset>0x14</addressOffset>
          <size>0x20</size>
        </register>
        <register>
          <name>NDTR0</name>
          <addressOffset>0x14</addressOffset>
          <size>0x20</size>
        </register>
        <register>
          <name>PAR0</name>
          <addressOffset>0x18</addressOffset>
          <size>0x20</size>
        </register>
        <register>
          <name>PAR0</name>
          <addressOffset>0x18</addressOffset>
          <size>0x20</size>
        </register>
        <register>
          <name>M0AR0</name>
          <addressOffset>0x1c</addressOffset>
          <size>0x20</size>
        </register>
        <register>
          <name>M0AR0</name>
          <addressOffset>0x1c</addressOffset>
          <size>0x20</size>
        </register>
        <register>
          <name>M1AR0</name>
          <addressOffset>0x20</addressOffset>
          <size>0x20</size>
        </register>
        <register>
          <name>M1AR0</name>
          <addressOffset>0x20</addressOffset>
          <size>0x20</size>
        </register>
        <register>
          <name>FCR0</name>
          <addressOffset>0x24</addressOffset>
          <size>0x20</size>
        </register>
        <register>
          <name>FCR0</name>
          <addressOffset>0x24</addressOffset>
          <size>0x20</size>
        </register>
        <register>
          <name>CR1</name>
          <addressOffset>0x28</addressOffset>
          <size>0x20</size>
        </register>
        <register>
          <name>CR1</name>
          <addressOffset>0x28</addressOffset>
          <size>0x20</size>
        </register>
        <register>
          <name>NDTR1</name>
          <addressOffset>0x2c</addressOffset>
          <size>0x20</size>
        </register>
        <register>
          <name>NDTR1</name>
          <addressOffset>0x2c</addressOffset>
          <size>0x20</size>
        </register>
        <register>
          <name>PAR1</name>
          <addressOffset>0x30</addressOffset>
          <size>0x20</size>
        </register>
        <register>
          <name>PAR1</name>
          <addressOffset>0x30</addressOffset>
          <size>0x20</size>
        </register>
        <register>
          <name>M0AR1</name>
          <addressOffset>0x34</addressOffset>
          <size>0x20</size>
        </register>
        <register>
          <name>M0AR1</name>
          <addressOffset>0x34</addressOffset>
          <size>0x20</size>
        </register>
        <register>
          <name>M1AR1</name>
          <addressOffset>0x38</addressOffset>
          <size>0x20</size>
        </register>
        <register>
          <name>M1AR1</name>
          <addressOffset>0x38</addressOffset>
          <size>0x20</size>
        </register>
        <register>
          <name>FCR1</name>
          <addressOffset>0x3c</addressOffset>
          <size>0x20</size>
        </register>
        <register>
          <name>FCR1</name>
          <addressOffset>0x3c</addressOffset>
          <size>0x20</size>
        </register>
        <register>
          <name>CR2</name>
          <addressOffset>0x40</addressOffset>
          <size>0x20</size>
        </register>
        <register>
          <name>CR2</name>
          <addressOffset>0x40</addressOffset>
          <size>0x20</size>
        </register>
        <register>
          <name>NDTR2</name>
          <addressOffset>0x44</addressOffset>
          <size>0x20</size>
        </register>
        <register>
          <name>NDTR2</name>
          <addressOffset>0x44</addressOffset>
          <size>0x20</size>
        </register>
        <register>
          <name>PAR2</name>
          <addressOffset>0x48</addressOffset>
          <size>0x20</size>
        </register>
        <register>
          <name>PAR2</name>
          <addressOffset>0x48</addressOffset>
          <size>0x20</size>
        </register>
        <register>
          <name>M0AR2</name>
          <addressOffset>0x4c</addressOffset>
          <size>0x20</size>
        </register>
        <register>
          <name>M0AR2</name>
          <addressOffset>0x4c</addressOffset>
          <size>0x20</size>
        </register>
        <register>
          <name>M1AR2</name>
          <addressOffset>0x50</addressOffset>
          <size>0x20</size>
        </register>
        <register>
          <name>M1AR2</name>
          <addressOffset>0x50</addressOffset>
          <size>0x20</size>
        </register>
        <register>
          <name>FCR2</name>
          <addressOffset>0x54</addressOffset>
          <size>0x20</size>
        </register>
        <register>
          <name>FCR2</name>
          <addressOffset>0x54</addressOffset>
          <size>0x20</size>
        </register>
        <register>
          <name>CR3</name>
          <addressOffset>0x58</addressOffset>
          <size>0x20</size>
        </register>
        <register>
          <name>CR3</name>
          <addressOffset>0x58</addressOffset>
          <size>0x20</size>
        </register>
        <register>
          <name>NDTR3</name>
          <addressOffset>0x5c</addressOffset>
          <size>0x20</size>
        </register>
        <register>
          <name>NDTR3</name>
          <addressOffset>0x5c</addressOffset>
          <size>0x20</size>
        </register>
        <register>
          <name>PAR3</name>
          <addressOffset>0x60</addressOffset>
          <size>0x20</size>
        </register>
        <register>
          <name>PAR3</name>
          <addressOffset>0x60</addressOffset>
          <size>0x20</size>
        </register>
        <register>
          <name>M0AR3</name>
          <addressOffset>0x64</addressOffset>
          <size>0x20</size>
        </register>
        <register>
          <name>M0AR3</name>
          <addressOffset>0x64</addressOffset>
          <size>0x20</size>
        </register>
        <register>
          <name>M1AR3</name>
          <addressOffset>0x68</addressOffset>
          <size>0x20</size>
        </register>
        <register>
          <name>M1AR3</name>
          <addressOffset>0x68</addressOffset>
          <size>0x20</size>
        </register>
        <register>
          <name>FCR3</name>
          <addressOffset>0x6c</addressOffset>
          <size>0x20</size>
        </register>
        <register>
          <name>FCR3</name>
          <addressOffset>0x6c</addressOffset>
          <size>0x20</size>
        </register>
        <register>
          <name>CR4</name>
          <addressOffset>0x70</addressOffset>
          <size>0x20</size>
        </register>
        <register>
          <name>CR4</name>
          <addressOffset>0x70</addressOffset>
          <size>0x20</size>
        </register>
        <register>
          <name>NDTR4</name>
          <addressOffset>0x74</addressOffset>
          <size>0x20</size>
        </register>
        <register>
          <name>NDTR4</name>
          <addressOffset>0x74</addressOffset>
          <size>0x20</size>
        </register>
        <register>
          <name>PAR4</name>
          <addressOffset>0x78</addressOffset>
          <size>0x20</size>
        </register>
        <register>
          <name>PAR4</name>
          <addressOffset>0x78</addressOffset>
          <size>0x20</size>
        </register>
        <register>
          <name>M0AR4</name>
          <addressOffset>0x7c</addressOffset>
          <size>0x20</size>
        </register>
        <register>
          <name>M0AR4</name>
          <addressOffset>0x7c</addressOffset>
          <size>0x20</size>
        </register>
        <register>
          <name>M1AR4</name>
          <addressOffset>0x80</addressOffset>
          <size>0x20</size>
        </register>
        <register>
          <name>M1AR4</name>
          <addressOffset>0x80</addressOffset>
          <size>0x20</size>
        </register>
        <register>
          <name>FCR4</name>
          <addressOffset>0x84</addressOffset>
          <size>0x20</size>
        </register>
        <register>
          <name>FCR4</name>
          <addressOffset>0x84</addressOffset>
          <size>0x20</size>
        </register>
        <register>
          <name>CR5</name>
          <addressOffset>0x88</addressOffset>
          <size>0x20</size>
        </register>
        <register>
          <name>CR5</name>
          <addressOffset>0x88</addressOffset>
          <size>0x20</size>
        </register>
        <register>
          <name>NDTR5</name>
          <addressOffset>0x8c</addressOffset>
          <size>0x20</size>
        </register>
        <register>
          <name>NDTR5</name>
          <addressOffset>0x8c</addressOffset>
          <size>0x20</size>
        </register>
        <register>
          <name>PAR5</name>
          <addressOffset>0x90</addressOffset>
          <size>0x20</size>
        </register>
        <register>
          <name>PAR5</name>
          <addressOffset>0x90</addressOffset>
          <size>0x20</size>
        </register>
        <register>
          <name>M0AR5</name>
          <addressOffset>0x94</addressOffset>
          <size>0x20</size>
        </register>
        <register>
          <name>M0AR5</name>
          <addressOffset>0x94</addressOffset>
          <size>0x20</size>
        </register>
        <register>
          <name>M1AR5</name>
          <addressOffset>0x98</addressOffset>
          <size>0x20</size>
        </register>
        <register>
          <name>M1AR5</name>
          <addressOffset>0x98</addressOffset>
          <size>0x20</size>
        </register>
        <register>
          <name>FCR5</name>
          <addressOffset>0x9c</addressOffset>
          <size>0x20</size>
        </register>
        <register>
          <name>FCR5</name>
          <addressOffset>0x9c</addressOffset>
          <size>0x20</size>
        </register>
        <register>
          <name>CR6</name>
          <addressOffset>0xa0</addressOffset>
          <size>0x20</size>
        </register>
        <register>
          <name>CR6</name>
          <addressOffset>0xa0</addressOffset>
          <size>0x20</size>
        </register>
        <register>
          <name>NDTR6</name>
          <addressOffset>0xa4</addressOffset>
          <size>0x20</size>
        </register>
        <register>
          <name>NDTR6</name>
          <addressOffset>0xa4</addressOffset>
          <size>0x20</size>
        </register>
        <register>
          <name>PAR6</name>
          <addressOffset>0xa8</addressOffset>
          <size>0x20</size>
        </register>
        <register>
          <name>PAR6</name>
          <addressOffset>0xa8</addressOffset>
          <size>0x20</size>
        </register>
        <register>
          <name>M0AR6</name>
          <addressOffset>0xac</addressOffset>
          <size>0x20</size>
        </register>
        <register>
          <name>M0AR6</name>
          <addressOffset>0xac</addressOffset>
          <size>0x20</size>
        </register>
        <register>
          <name>M1AR6</name>
          <addressOffset>0xb0</addressOffset>
          <size>0x20</size>
        </register>
        <register>
          <name>M1AR6</name>
          <addressOffset>0xb0</addressOffset>
          <size>0x20</size>
        </register>
        <register>
          <name>FCR6</name>
          <addressOffset>0xb4</addressOffset>
          <size>0x20</size>
        </register>
        <register>
          <name>FCR6</name>
          <addressOffset>0xb4</addressOffset>
          <size>0x20</size>
        </register>
        <register>
          <name>CR7</name>
          <addressOffset>0xb8</addressOffset>
          <size>0x20</size>
        </register>
        <register>
          <name>CR7</name>
          <addressOffset>0xb8</addressOffset>
          <size>0x20</size>
        </register>
        <register>
          <name>NDTR7</name>
          <addressOffset>0xbc</addressOffset>
          <size>0x20</size>
        </register>
        <register>
          <name>NDTR7</name>
          <addressOffset>0xbc</addressOffset>
          <size>0x20</size>
        </register>
        <register>
          <name>PAR7</name>
          <addressOffset>0xc0</addressOffset>
          <size>0x20</size>
        </register>
        <register>
          <name>PAR7</name>
          <addressOffset>0xc0</addressOffset>
          <size>0x20</size>
        </register>
        <register>
          <name>M0AR7</name>
          <addressOffset>0xc4</addressOffset>
          <size>0x20</size>
        </register>
        <register>
          <name>M0AR7</name>
          <addressOffset>0xc4</addressOffset>
          <size>0x20</size>
        </register>
        <register>
          <name>M1AR7</name>
          <addressOffset>0xc8</addressOffset>
          <size>0x20</size>
        </register>
        <register>
          <name>M1AR7</name>
          <addressOffset>0xc8</addressOffset>
          <size>0x20</size>
        </register>
        <register>
          <name>FCR7</name>
          <addressOffset>0xcc</addressOffset>
          <size>0x20</size>
        </register>
        <register>
          <name>FCR7</name>
          <addressOffset>0xcc</addressOffset>
          <size>0x20</size>
        </register>
      </registers>
    </peripheral>
    <peripheral>
      <name>DMA2</name>
      <baseAddress>0x40026400</baseAddress>
      <registers>
        <register>
          <name>LISR</name>
          <addressOffset>0x0</addressOffset>
          <size>0x20</size>
          <fields>
            <field>
              <name>FEIF0</name>
              <bitOffset>0</bitOffset>
              <bitWidth>1</bitWidth>
            </field>
            <field>
              <name>DMEIF0</name>
              <bitOffset>2</bitOffset>
              <bitWidth>1</bitWidth>
            </field>
            <field>
              <name>TEIF0</name>
              <bitOffset>3</bitOffset>
              <bitWidth>1</bitWidth>
            </field>
            <field>
              <name>HTIF0</name>
              <bitOffset>4</bitOffset>
              <bitWidth>1</bitWidth>
            </field>
            <field>
              <name>TCIF0</name>
              <bitOffset>5</bitOffset>
              <bitWidth>1</bitWidth>
            </field>
            <field>
              <name>FEIF1</name>
              <bitOffset>6</bitOffset>
              <bitWidth>1</bitWidth>
            </field>
            <field>
              <name>DMEIF1</name>
              <bitOffset>8</bitOffset>
              <bitWidth>1</bitWidth>
            </field>
            <field>
              <name>TEIF1</name>
              <bitOffset>9</bitOffset>
              <bitWidth>1</bitWidth>
            </field>
            <field>
              <name>HTIF1</name>
              <bitOffset>10</bitOffset>
              <bitWidth>1</bitWidth>
            </field>
            <field>
              <name>TCIF1</name>
              <bitOffset>11</bitOffset>
              <bitWidth>1</bitWidth>
            </field>
            <field>
              <name>FEIF2</name>
              <bitOffset>16</bitOffset>
              <bitWidth>1</bitWidth>
            </field>
            <field>
              <name>DMEIF2</name>
              <bitOffset>18</bitOffset>
              <bitWidth>1</bitWidth>
            </field>
            <field>
              <name>TEIF2</name>
              <bitOffset>19</bitOffset>
              <bitWidth>1</bitWidth>
            </field>
            <field>
              <name>HTIF2</name>
              <bitOffset>20</bitOffset>
              <bitWidth>1</bitWidth>
            </field>
            <field>
              <name>TCIF2</name>
              <bitOffset>21</bitOffset>
              <bitWidth>1</bitWidth>
            </field>
            <field>
              <name>FEIF3</name>
              <bitOffset>22</bitOffset>
              <bitWidth>1</bitWidth>
            </field>
            <field>
              <name>DMEIF3</name>
              <bitOffset>24</bitOffset>
              <bitWidth>1</bitWidth>
            </field>
            <field>
              <name>TEIF3</name>
              <bitOffset>25</bitOffset>
              <bitWidth>1</bitWidth>
            </field>
            <field>
              <name>HTIF3</name>
              <bitOffset>26</bitOffset>
              <bitWidth>1</bitWidth>
            </field>
            <field>
              <name>TCIF3</name>
              <bitOffset>27</bitOffset>
              <bitWidth>1</bitWidth>
            </field>
          </fields>
        </register>
        <register>
          <name>HISR</name>
          <addressOffset>0x4</addressOffset>
          <size>0x20</size>
          <fields>
            <field>
              <name>FEIF4</name>
              <bitOffset>0</bitOffset>
              <bitWidth>1</bitWidth>
            </field>
            <field>
              <name>DMEIF4</name>
              <bitOffset>2</bitOffset>
              <bitWidth>1</bitWidth>
            </field>
            <field>
              <name>TEIF4</name>
              <bitOffset>3</bitOffset>
              <bitWidth>1</bitWidth>
            </field>
            <field>
              <name>HTIF4</name>
              <bitOffset>4</bitOffset>
              <bitWidth>1</bitWidth>
            </field>
            <field>
              <name>TCIF4</name>
              <bitOffset>5</bitOffset>
              <bitWidth>1</bitWidth>
            </field>
            <field>
              <name>FEIF5</name>
              <bitOffset>6</bitOffset>
              <bitWidth>1</bitWidth>
            </field>
            <field>
              <name>DMEIF5</name>
              <bitOffset>8</bitOffset>
              <bitWidth>1</bitWidth>
            </field>
            <field>
              <name>TEIF5</name>
              <bitOffset>9</bitOffset>
              <bitWidth>1</bitWidth>
            </field>
            <field>
              <name>HTIF5</name>
              <bitOffset>10</bitOffset>
              <bitWidth>1</bitWidth>
            </field>
            <field>
              <name>TCIF5</name>
              <bitOffset>11</bitOffset>
              <bitWidth>1</bitWidth>
            </field>
            <field>
              <name>FEIF6</name>
              <bitOffset>16</bitOffset>
              <bitWidth>1</bitWidth>
            </field>
            <field>
              <name>DMEIF6</name>
              <bitOffset>18</bitOffset>
              <bitWidth>1</bitWidth>
            </field>
            <field>
              <name>TEIF6</name>
              <bitOffset>19</bitOffset>
              <bitWidth>1</bitWidth>
            </field>
            <field>
              <name>HTIF6</name>
              <bitOffset>20</bitOffset>
              <bitWidth>1</bitWidth>
            </field>
            <field>
              <name>TCIF6</name>
              <bitOffset>21</bitOffset>
              <bitWidth>1</bitWidth>
            </field>
            <field>
              <name>FEIF7</name>
              <bitOffset>22</bitOffset>
              <bitWidth>1</bitWidth>
            </field>
            <field>
              <name>DMEIF7</name>
              <bitOffset>24</bitOffset>
              <bitWidth>1</bitWidth>
            </field>
            <field>
              <name>TEIF7</name>
              <bitOffset>25</bitOffset>
              <bitWidth>1</bitWidth>
            </field>
            <field>
              <name>HTIF7</name>
              <bitOffset>26</bitOffset>
              <bitWidth>1</bitWidth>
            </field>
            <field>
              <name>TCIF7</name>
              <bitOffset>27</bitOffset>
              <bitWidth>1</bitWidth>
            </field>
          </fields>
        </register>
        <register>
          <name>LIFCR</name>
          <addressOffset>0x8</addressOffset>
          <size>0x20</size>
          <fields>
            <field>
              <name>CFEIF0</name>
              <bitOffset>0</bitOffset>
              <bitWidth>1</bitWidth>
            </field>
            <field>
              <name>CDMEIF0</name>
              <bitOffset>2</bitOffset>
              <bitWidth>1</bitWidth>
            </field>
            <field>
              <name>CTEIF0</name>
              <bitOffset>3</bitOffset>
              <bitWidth>1</bitWidth>
            </field>
            <field>
              <name>CHTIF0</name>
              <bitOffset>4</bitOffset>
              <bitWidth>1</bitWidth>
            </field>
            <field>
              <name>CTCIF0</name>
              <bitOffset>5</bitOffset>
              <bitWidth>1</bitWidth>
            </field>
            <field>
              <name>CFEIF1</name>
              <bitOffset>6</bitOffset>
              <bitWidth>1</bitWidth>
            </field>
            <field>
              <name>CDMEIF1</name>
              <bitOffset>8</bitOffset>
              <bitWidth>1</bitWidth>
            </field>
            <field>
              <name>CTEIF1</name>
              <bitOffset>9</bitOffset>
              <bitWidth>1</bitWidth>
            </field>
            <field>
              <name>CHTIF1</name>
              <bitOffset>10</bitOffset>
              <bitWidth>1</bitWidth>
            </field>
            <field>
              <name>CTCIF1</name>
              <bitOffset>11</bitOffset>
              <bitWidth>1</bitWidth>
            </field>
            <field>
              <name>CFEIF2</name>
              <bitOffset>16</bitOffset>
              <bitWidth>1</bitWidth>
            </field>
            <field>
              <name>CDMEIF2</name>
              <bitOffset>18</bitOffset>
              <bitWidth>1</bitWidth>
            </field>
            <field>
              <name>CTEIF2</name>
              <bitOffset>19</bitOffset>
              <bitWidth>1</bitWidth>
            </field>
            <field>
              <name>CHTIF2</name>
              <bitOffset>20</bitOffset>
              <bitWidth>1</bitWidth>
            </field>
            <field>
              <name>CTCIF2</name>
              <bitOffset>21</bitOffset>
              <bitWidth>1</bitWidth>
            </field>
            <field>
              <name>CFEIF3</name>
              <bitOffset>22</bitOffset>
              <bitWidth>1</bitWidth>
            </field>
            <field>
              <name>CDMEIF3</name>
              <bitOffset>24</bitOffset>
              <bitWidth>1</bitWidth>
            </field>
            <field>
              <name>CTEIF3</name>
              <bitOffset>25</bitOffset>
              <bitWidth>1</bitWidth>
            </field>
            <field>
              <name>CHTIF3</name>
              <bitOffset>26</bitOffset>
              <bitWidth>1</bitWidth>
            </field>
            <field>
              <name>CTCIF3</name>
              <bitOffset>27</bitOffset>
              <bitWidth>1</bitWidth>
            </field>
          </fields>
        </register>
        <register>
          <name>HIFCR</name>
          <addressOffset>0xc</addressOffset>
          <size>0x20</size>
          <fields>
            <field>
              <name>CFEIF4</name>
              <bitOffset>0</bitOffset>
              <bitWidth>1</bitWidth>
            </field>
            <field>
              <name>CDMEIF4</name>
              <bitOffset>2</bitOffset>
              <bitWidth>1</bitWidth>
            </field>
            <field>
              <name>CTEIF4</name>
              <bitOffset>3</bitOffset>
              <bitWidth>1</bitWidth>
            </field>
            <field>
              <name>CHTIF4</name>
              <bitOffset>4</bitOffset>
              <bitWidth>1</bitWidth>
            </field>
            <field>
              <name>CTCIF4</name>
              <bitOffset>5</bitOffset>
              <bitWidth>1</bitWidth>
            </field>
            <field>
              <name>CFEIF5</name>
              <bitOffset>6</bitOffset>
              <bitWidth>1</bitWidth>
            </field>
            <field>
              <name>CDMEIF5</name>
              <bitOffset>8</bitOffset>
              <bitWidth>1</bitWidth>
            </field>
            <field>
              <name>CTEIF5</name>
              <bitOffset>9</bitOffset>
              <bitWidth>1</bitWidth>
            </field>
            <field>
              <name>CHTIF5</name>
              <bitOffset>10</bitOffset>
              <bitWidth>1</bitWidth>
            </field>
            <field>
              <name>CTCIF5</name>
              <bitOffset>11</bitOffset>
              <bitWidth>1</bitWidth>
            </field>
            <field>
              <name>CFEIF6</name>
              <bitOffset>16</bitOffset>
              <bitWidth>1</bitWidth>
            </field>
            <field>
              <name>CDMEIF6</name>
              <bitOffset>18</bitOffset>
              <bitWidth>1</bitWidth>
            </field>
            <field>
              <name>CTEIF6</name>
              <bitOffset>19</bitOffset>
              <bitWidth>1</bitWidth>
            </field>
            <field>
              <name>CHTIF6</name>
              <bitOffset>20</bitOffset>
              <bitWidth>1</bitWidth>
            </field>
            <field>
              <name>CTCIF6</name>
              <bitOffset>21</bitOffset>
              <bitWidth>1</bitWidth>
            </field>
            <field>
              <name>CFEIF7</name>
              <bitOffset>22</bitOffset>
              <bitWidth>1</bitWidth>
            </field>
            <field>
              <name>CDMEIF7</name>
              <bitOffset>24</bitOffset>
              <bitWidth>1</bitWidth>
            </field>
            <field>
              <name>CTEIF7</name>
              <bitOffset>25</bitOffset>
              <bitWidth>1</bitWidth>
            </field>
            <field>
              <name>CHTIF7</name>
              <bitOffset>26</bitOffset>
              <bitWidth>1</bitWidth>
            </field>
            <field>
              <name>CTCIF7</name>
              <bitOffset>27</bitOffset>
              <bitWidth>1</bitWidth>
            </field>
          </fields>
        </register>
        <register>
          <name>CR0</name>
          <addressOffset>0x10</addressOffset>
          <size>0x20</size>
        </register>
        <register>
          <name>CR0</name>
          <addressOffset>0x10</addressOffset>
          <size>0x20</size>
        </register>
        <register>
          <name>NDTR0</name>
          <addressOffset>0x14</addressOffset>
          <size>0x20</size>
        </register>
        <register>
          <name>NDTR0</name>
          <addressOffset>0x14</addressOffset>
          <size>0x20</size>
        </register>
        <register>
          <name>PAR0</name>
          <addressOffset>0x18</addressOffset>
          <size>0x20</size>
        </register>
        <register>
          <name>PAR0</name>
          <addressOffset>0x18</addressOffset>
          <size>0x20</size>
        </register>
        <register>
          <name>M0AR0</name>
          <addressOffset>0x1c</addressOffset>
          <size>0x20</size>
        </register>
        <register>
          <name>M0AR0</name>
          <addressOffset>0x1c</addressOffset>
          <size>0x20</size>
        </register>
        <register>
          <name>M1AR0</name>
          <addressOffset>0x20</addressOffset>
          <size>0x20</size>
        </register>
        <register>
          <name>M1AR0</name>
          <addressOffset>0x20</addressOffset>
          <size>0x20</size>
        </register>
        <register>
          <name>FCR0</name>
          <addressOffset>0x24</addressOffset>
          <size>0x20</size>
        </register>
        <register>
          <name>FCR0</name>
          <addressOffset>0x24</addressOffset>
          <size>0x20</size>
        </register>
        <register>
          <name>CR1</name>
          <addressOffset>0x28</addressOffset>
          <size>0x20</size>
        </register>
        <register>
          <name>CR1</name>
          <addressOffset>0x28</addressOffset>
          <size>0x20</size>
        </register>
        <register>
          <name>NDTR1</name>
          <addressOffset>0x2c</addressOffset>
          <size>0x20</size>
        </register>
        <register>
          <name>NDTR1</name>
          <addressOffset>0x2c</addressOffset>
          <size>0x20</size>
        </register>
        <register>
          <name>PAR1</name>
          <addressOffset>0x30</addressOffset>
          <size>0x20</size>
        </register>
        <register>
          <name>PAR1</name>
          <addressOffset>0x30</addressOffset>
          <size>0x20</size>
        </register>
        <register>
          <name>M0AR1</name>
          <addressOffset>0x34</addressOffset>
          <size>0x20</size>
        </register>
        <register>
          <name>M0AR1</name>
          <addressOffset>0x34</addressOffset>
          <size>0x20</size>
        </register>
        <register>
          <name>M1AR1</name>
          <addressOffset>0x38</addressOffset>
          <size>0x20</size>
        </register>
        <register>
          <name>M1AR1</name>
          <addressOffset>0x38</addressOffset>
          <size>0x20</size>
        </register>
        <register>
          <name>FCR1</name>
          <addressOffset>0x3c</addressOffset>
          <size>0x20</size>
        </register>
        <register>
          <name>FCR1</name>
          <addressOffset>0x3c</addressOffset>
          <size>0x20</size>
        </register>
        <register>
          <name>CR2</name>
          <addressOffset>0x40</addressOffset>
          <size>0x20</size>
        </register>
        <register>
          <name>CR2</name>
          <addressOffset>0x40</addressOffset>
          <size>0x20</size>
        </register>
        <register>
          <name>NDTR2</name>
          <addressOffset>0x44</addressOffset>
          <size>0x20</size>
        </register>
        <register>
          <name>NDTR2</name>
          <addressOffset>0x44</addressOffset>
          <size>0x20</size>
        </register>
        <register>
          <name>PAR2</name>
          <addressOffset>0x48</addressOffset>
          <size>0x20</size>
        </register>
        <register>
          <name>PAR2</name>
          <addressOffset>0x48</addressOffset>
          <size>0x20</size>
        </register>
        <register>
          <name>M0AR2</name>
          <addressOffset>0x4c</addressOffset>
          <size>0x20</size>
        </register>
        <register>
          <name>M0AR2</name>
          <addressOffset>0x4c</addressOffset>
          <size>0x20</size>
        </register>
        <register>
          <name>M1AR2</name>
          <addressOffset>0x50</addressOffset>
          <size>0x20</size>
        </register>
        <register>
          <name>M1AR2</name>
          <addressOffset>0x50</addressOffset>
          <size>0x20</size>
        </register>
        <register>
          <name>FCR2</name>
          <addressOffset>0x54</addressOffset>
          <size>0x20</size>
        </register>
        <register>
          <name>FCR2</name>
          <addressOffset>0x54</addressOffset>
          <size>0x20</size>
        </register>
        <register>
          <name>CR3</name>
          <addressOffset>0x58</addressOffset>
          <size>0x20</size>
        </register>
        <register>
          <name>CR3</name>
          <addressOffset>0x58</addressOffset>
          <size>0x20</size>
        </register>
        <register>
          <name>NDTR3</name>
          <addressOffset>0x5c</addressOffset>
          <size>0x20</size>
        </register>
        <register>
          <name>NDTR3</name>
          <addressOffset>0x5c</addressOffset>
          <size>0x20</size>
        </register>
        <register>
          <name>PAR3</name>
          <addressOffset>0x60</addressOffset>
          <size>0x20</size>
        </register>
        <register>
          <name>PAR3</name>
          <addressOffset>0x60</addressOffset>
          <size>0x20</size>
        </register>
        <register>
          <name>M0AR3</name>
          <addressOffset>0x64</addressOffset>
          <size>0x20</size>
        </register>
        <register>
          <name>M0AR3</name>
          <addressOffset>0x64</addressOffset>
          <size>0x20</size>
        </register>
        <register>
          <name>M1AR3</name>
          <addressOffset>0x68</addressOffset>
          <size>0x20</size>
        </register>
        <register>
          <name>M1AR3</name>
          <addressOffset>0x68</addressOffset>
          <size>0x20</size>
        </register>
        <register>
          <name>FCR3</name>
          <addressOffset>0x6c</addressOffset>
          <size>0x20</size>
        </register>
        <register>
          <name>FCR3</name>
          <addressOffset>0x6c</addressOffset>
          <size>0x20</size>
        </register>
        <register>
          <name>CR4</name>
          <addressOffset>0x70</addressOffset>
          <size>0x20</size>
        </register>
        <register>
          <name>CR4</name>
          <addressOffset>0x70</addressOffset>
          <size>0x20</size>
        </register>
        <register>
          <name>NDTR4</name>
          <addressOffset>0x74</addressOffset>
          <size>0x20</size>
        </register>
        <register>
          <name>NDTR4</name>
          <addressOffset>0x74</addressOffset>
          <size>0x20</size>
        </register>
        <register>
          <name>PAR4</name>
          <addressOffset>0x78</addressOffset>
          <size>0x20</size>
        </register>
        <register>
          <name>PAR4</name>
          <addressOffset>0x78</addressOffset>
          <size>0x20</size>
        </register>
        <register>
          <name>M0AR4</name>
          <addressOffset>0x7c</addressOffset>
          <size>0x20</size>
        </register>
        <register>
          <name>M0AR4</name>
          <addressOffset>0x7c</addressOffset>
          <size>0x20</size>
        </register>
        <register>
          <name>M1AR4</name>
          <addressOffset>0x80</addressOffset>
          <size>0x20</size>
        </register>
        <register>
          <name>M1AR4</name>
          <addressOffset>0x80</addressOffset>
          <size>0x20</size>
        </register>
        <register>
          <name>FCR4</name>
          <addressOffset>0x84</addressOffset>
          <size>0x20</size>
        </register>
        <register>
          <name>FCR4</name>
          <addressOffset>0x84</addressOffset>
          <size>0x20</size>
        </register>
        <register>
          <name>CR5</name>
          <addressOffset>0x88</addressOffset>
          <size>0x20</size>
        </register>
        <register>
          <name>CR5</name>
          <addressOffset>0x88</addressOffset>
          <size>0x20</size>
        </register>
        <register>
          <name>NDTR5</name>
          <addressOffset>0x8c</addressOffset>
          <size>0x20</size>
        </register>
        <register>
          <name>NDTR5</name>
          <addressOffset>0x8c</addressOffset>
          <size>0x20</size>
        </register>
        <register>
          <name>PAR5</name>
          <addressOffset>0x90</addressOffset>
          <size>0x20</size>
        </register>
        <register>
          <name>PAR5</name>
          <addressOffset>0x90</addressOffset>
          <size>0x20</size>
        </register>
        <register>
          <name>M0AR5</name>
          <addressOffset>0x94</addressOffset>
          <size>0x20</size>
        </register>
        <register>
          <name>M0AR5</name>
          <addressOffset>0x94</addressOffset>
          <size>0x20</size>
        </register>
        <register>
          <name>M1AR5</name>
          <addressOffset>0x98</addressOffset>
          <size>0x20</size>
        </register>
        <register>
          <name>M1AR5</name>
          <addressOffset>0x98</addressOffset>
          <size>0x20</size>
        </register>
        <register>
          <name>FCR5</name>
          <addressOffset>0x9c</addressOffset>
          <size>0x20</size>
        </register>
        <register>
          <name>FCR5</name>
          <addressOffset>0x9c</addressOffset>
          <size>0x20</size>
        </register>
        <register>
          <name>CR6</name>
          <addressOffset>0xa0</addressOffset>
          <size>0x20</size>
        </register>
        <register>
          <name>CR6</name>
          <addressOffset>0xa0</addressOffset>
          <size>0x20</size>
        </register>
        <register>
          <name>NDTR6</name>
          <addressOffset>0xa4</addressOffset>
          <size>0x20</size>
        </register>
        <register>
          <name>NDTR6</name>
          <addressOffset>0xa4</addressOffset>
          <size>0x20</size>
        </register>
        <register>
          <name>PAR6</name>
          <addressOffset>0xa8</addressOffset>
          <size>0x20</size>
        </register>
        <register>
          <name>PAR6</name>
          <addressOffset>0xa8</addressOffset>
          <size>0x20</size>
        </register>
        <register>
          <name>M0AR6</name>
          <addressOffset>0xac</addressOffset>
          <size>0x20</size>
        </register>
        <register>
          <name>M0AR6</name>
          <addressOffset>0xac</addressOffset>
          <size>0x20</size>
        </register>
        <register>
          <name>M1AR6</name>
          <addressOffset>0xb0</addressOffset>
          <size>0x20</size>
        </register>
        <register>
          <name>M1AR6</name>
          <addressOffset>0xb0</addressOffset>
          <size>0x20</size>
        </register>
        <register>
          <name>FCR6</name>
          <addressOffset>0xb4</addressOffset>
          <size>0x20</size>
        </register>
        <register>
          <name>FCR6</name>
          <addressOffset>0xb4</addressOffset>
          <size>0x20</size>
        </register>
        <register>
          <name>CR7</name>
          <addressOffset>0xb8</addressOffset>
          <size>0x20</size>
        </register>
        <register>
          <name>CR7</name>
          <addressOffset>0xb8</addressOffset>
          <size>0x20</size>
        </register>
        <register>
          <name>NDTR7</name>
          <addressOffset>0xbc</addressOffset>
          <size>0x20</size>
        </register>
        <register>
          <name>NDTR7</name>
          <addressOffset>0xbc</addressOffset>
          <size>0x20</size>
        </register>
        <register>
          <name>PAR7</name>
          <addressOffset>0xc0</addressOffset>
          <size>0x20</size>
        </register>
        <register>
          <name>PAR7</name>
          <addressOffset>0xc0</addressOffset>
          <size>0x20</size>
        </register>
        <register>
          <name>M0AR7</name>
          <addressOffset>0xc4</addressOffset>
          <size>0x20</size>
        </register>
        <register>
          <name>M0AR7</name>
          <addressOffset>0xc4</addressOffset>
          <size>0x20</size>
        </register>
        <register>
          <name>M1AR7</name>
          <addressOffset>0xc8</addressOffset>
          <size>0x20</size>
        </register>
        <register>
          <name>M1AR7</name>
          <addressOffset>0xc8</addressOffset>
          <size>0x20</size>
        </register>
        <register>
          <name>FCR7</name>
          <addressOffset>0xcc</addressOffset>
          <size>0x20</size>
        </register>
        <register>
          <name>FCR7</name>
          <addressOffset>0xcc</addressOffset>
          <size>0x20</size>
        </register>
      </registers>
    </peripheral>
    <peripheral>
      <name>ETH</name>
      <baseAddress>0x40028000</baseAddress>
      <registers>
        <register>
          <name>MACCR</name>
          <addressOffset>0x0</addressOffset>
          <size>0x20</size>
          <fields>
            <field>
              <name>RE</name>
              <bitOffset>2</bitOffset>
              <bitWidth>1</bitWidth>
            </field>
            <field>
              <name>TE</name>
              <bitOffset>3</bitOffset>
              <bitWidth>1</bitWidth>
            </field>
            <field>
              <name>DC</name>
              <bitOffset>4</bitOffset>
              <bitWidth>1</bitWidth>
            </field>
            <field>
              <name>BL</name>
              <bitOffset>5</bitOffset>
              <bitWidth>2</bitWidth>
            </field>
            <field>
              <name>APCS</name>
              <bitOffset>7</bitOffset>
              <bitWidth>1</bitWidth>
            </field>
            <field>
              <name>RD</name>
              <bitOffset>9</bitOffset>
              <bitWidth>1</bitWidth>
            </field>
            <field>
              <name>IPCO</name>
              <bitOffset>10</bitOffset>
              <bitWidth>1</bitWidth>
            </field>
            <field>
              <name>DM</name>
              <bitOffset>11</bitOffset>
              <bitWidth>1</bitWidth>
            </field>
            <field>
              <name>LM</name>
              <bitOffset>12</bitOffset>
              <bitWidth>1</bitWidth>
            </field>
            <field>
              <name>ROD</name>
              <bitOffset>13</bitOffset>
              <bitWidth>1</bitWidth>
            </field>
            <field>
              <name>FES</name>
              <bitOffset>14</bitOffset>
              <bitWidth>1</bitWidth>
            </field>
            <field>
              <name>CSD</name>
              <bitOffset>16</bitOffset>
              <bitWidth>1</bitWidth>
            </field>
            <field>
              <name>IFG</name>
              <bitOffset>17</bitOffset>
              <bitWidth>3</bitWidth>
            </field>
            <field>
              <name>JD</name>
              <bitOffset>22</bitOffset>
              <bitWidth>1</bitWidth>
            </field>
            <field>
              <name>WD</name>
              <bitOffset>23</bitOffset>
              <bitWidth>1</bitWidth>
            </field>
          </fields>
        </register>
        <register>
          <name>MACFFR</name>
          <addressOffset>0x4</addressOffset>
          <size>0x20</size>
          <fields>
            <field>
              <name>PM</name>
              <bitOffset>0</bitOffset>
              <bitWidth>1</bitWidth>
            </field>
            <field>
              <name>HU</name>
              <bitOffset>1</bitOffset>
              <bitWidth>1</bitWidth>
            </field>
            <field>
              <name>HM</name>
              <bitOffset>2</bitOffset>
              <bitWidth>1</bitWidth>
            </field>
            <field>
              <name>DAIF</name>
              <bitOffset>3</bitOffset>
              <bitWidth>1</bitWidth>
            </field>
            <field>
              <name>PAM</name>
              <bitOffset>4</bitOffset>
              <bitWidth>1</bitWidth>
            </field>
            <field>
              <name>BFD</name>
              <bitOffset>5</bitOffset>
              <bitWidth>1</bitWidth>
            </field>
            <field>
              <name>PCF_ForwardPassedAddrFilter</name>
              <bitOffset>6</bitOffset>
              <bitWidth>2</bitWidth>
            </field>
            <field>
              <name>PCF_ForwardAll</name>
              <bitOffset>7</bitOffset>
              <bitWidth>1</bitWidth>
            </field>
            <field>
              <name>SAIF</name>
              <bitOffset>8</bitOffset>
              <bitWidth>1</bitWidth>
            </field>
            <field>
              <name>SAF</name>
              <bitOffset>9</bitOffset>
              <bitWidth>1</bitWidth>
            </field>
            <field>
              <name>HPF</name>
              <bitOffset>10</bitOffset>
              <bitWidth>1</bitWidth>
            </field>
            <field>
              <name>RA</name>
              <bitOffset>31</bitOffset>
              <bitWidth>1</bitWidth>
            </field>
          </fields>
        </register>
        <register>
          <name>MACHTHR</name>
          <addressOffset>0x8</addressOffset>
          <size>0x20</size>
          <fields>
            <field>
              <name>HTH</name>
              <bitOffset>0</bitOffset>
              <bitWidth>32</bitWidth>
            </field>
          </fields>
        </register>
        <register>
          <name>MACHTLR</name>
          <addressOffset>0xc</addressOffset>
          <size>0x20</size>
          <fields>
            <field>
              <name>HTL</name>
              <bitOffset>0</bitOffset>
              <bitWidth>32</bitWidth>
            </field>
          </fields>
        </register>
        <register>
          <name>MACMIIAR</name>
          <addressOffset>0x10</addressOffset>
          <size>0x20</size>
          <fields>
            <field>
              <name>MB</name>
              <bitOffset>0</bitOffset>
              <bitWidth>1</bitWidth>
            </field>
            <field>
              <name>MW</name>
              <bitOffset>1</bitOffset>
              <bitWidth>1</bitWidth>
            </field>
            <field>
              <name>CR_Div62</name>
              <bitOffset>2</bitOffset>
              <bitWidth>1</bitWidth>
            </field>
            <field>
              <name>CR_Div16</name>
              <bitOffset>3</bitOffset>
              <bitWidth>1</bitWidth>
            </field>
            <field>
              <name>CR_Div102</name>
              <bitOffset>4</bitOffset>
              <bitWidth>1</bitWidth>
            </field>
            <field>
              <name>MR</name>
              <bitOffset>6</bitOffset>
              <bitWidth>5</bitWidth>
            </field>
            <field>
              <name>PA</name>
              <bitOffset>11</bitOffset>
              <bitWidth>5</bitWidth>
            </field>
          </fields>
        </register>
        <register>
          <name>MACMIIDR</name>
          <addressOffset>0x14</addressOffset>
          <size>0x20</size>
          <fields>
            <field>
              <name>MD</name>
              <bitOffset>0</bitOffset>
              <bitWidth>16</bitWidth>
            </field>
          </fields>
        </register>
        <register>
          <name>MACFCR</name>
          <addressOffset>0x18</addressOffset>
          <size>0x20</size>
          <fields>
            <field>
              <name>FCBBPA</name>
              <bitOffset>0</bitOffset>
              <bitWidth>1</bitWidth>
            </field>
            <field>
              <name>TFCE</name>
              <bitOffset>1</bitOffset>
              <bitWidth>1</bitWidth>
            </field>
            <field>
              <name>RFCE</name>
              <bitOffset>2</bitOffset>
              <bitWidth>1</bitWidth>
            </field>
            <field>
              <name>UPFD</name>
              <bitOffset>3</bitOffset>
              <bitWidth>1</bitWidth>
            </field>
            <field>
              <name>PLT_Minus28</name>
              <bitOffset>4</bitOffset>
              <bitWidth>1</bitWidth>
            </field>
            <field>
              <name>PLT_Minus144</name>
              <bitOffset>5</bitOffset>
              <bitWidth>1</bitWidth>
            </field>
            <field>
              <name>ZQPD</name>
              <bitOffset>7</bitOffset>
              <bitWidth>1</bitWidth>
            </field>
            <field>
              <name>PT</name>
              <bitOffset>16</bitOffset>
              <bitWidth>16</bitWidth>
            </field>
          </fields>
        </register>
        <register>
          <name>MACVLANTR</name>
          <addressOffset>0x1c</addressOffset>
          <size>0x20</size>
          <fields>
            <field>
              <name>VLANTI</name>
              <bitOffset>0</bitOffset>
              <bitWidth>16</bitWidth>
            </field>
            <field>
              <name>VLANTC</name>
              <bitOffset>16</bitOffset>
              <bitWidth>1</bitWidth>
            </field>
          </fields>
        </register>
        <register>
          <name>MACRWUFFR</name>
          <addressOffset>0x28</addressOffset>
          <size>0x20</size>
          <fields>
            <field>
              <name>D</name>
              <bitOffset>0</bitOffset>
              <bitWidth>32</bitWidth>
            </field>
          </fields>
        </register>
        <register>
          <name>MACPMTCSR</name>
          <addressOffset>0x2c</addressOffset>
          <size>0x20</size>
          <fields>
            <field>
              <name>PD</name>
              <bitOffset>0</bitOffset>
              <bitWidth>1</bitWidth>
            </field>
            <field>
              <name>MPE</name>
              <bitOffset>1</bitOffset>
              <bitWidth>1</bitWidth>
            </field>
            <field>
              <name>WFE</name>
              <bitOffset>2</bitOffset>
              <bitWidth>1</bitWidth>
            </field>
            <field>
              <name>MPR</name>
              <bitOffset>5</bitOffset>
              <bitWidth>1</bitWidth>
            </field>
            <field>
              <name>WFR</name>
              <bitOffset>6</bitOffset>
              <bitWidth>1</bitWidth>
            </field>
            <field>
              <name>GU</name>
              <bitOffset>9</bitOffset>
              <bitWidth>1</bitWidth>
            </field>
            <field>
              <name>WFFRPR</name>
              <bitOffset>31</bitOffset>
              <bitWidth>1</bitWidth>
            </field>
          </fields>
        </register>
        <register>
          <name>MACDBGR</name>
          <addressOffset>0x34</addressOffset>
          <size>0x20</size>
          <fields>
            <field>
              <name>MMRPEA</name>
              <bitOffset>0</bitOffset>
              <bitWidth>1</bitWidth>
            </field>
            <field>
              <name>MSFRWCS</name>
              <bitOffset>1</bitOffset>
              <bitWidth>2</bitWidth>
            </field>
            <field>
              <name>RFWRA</name>
              <bitOffset>4</bitOffset>
              <bitWidth>1</bitWidth>
            </field>
            <field>
              <name>RFRCS_FLUSHING</name>
              <bitOffset>5</bitOffset>
              <bitWidth>2</bitWidth>
            </field>
            <field>
              <name>RFRCS_STATUSREADING</name>
              <bitOffset>6</bitOffset>
              <bitWidth>1</bitWidth>
            </field>
            <field>
              <name>RFFL_FULL</name>
              <bitOffset>8</bitOffset>
              <bitWidth>2</bitWidth>
            </field>
            <field>
              <name>RFFL_ABOVEFCT</name>
              <bitOffset>9</bitOffset>
              <bitWidth>1</bitWidth>
            </field>
            <field>
              <name>MMTEA</name>
              <bitOffset>16</bitOffset>
              <bitWidth>1</bitWidth>
            </field>
            <field>
              <name>MTFCS_WAITING</name>
              <bitOffset>17</bitOffset>
              <bitWidth>1</bitWidth>
            </field>
            <field>
              <name>MTFCS_GENERATINGPCF</name>
              <bitOffset>18</bitOffset>
              <bitWidth>1</bitWidth>
            </field>
            <field>
              <name>MTP</name>
              <bitOffset>19</bitOffset>
              <bitWidth>1</bitWidth>
            </field>
            <field>
              <name>TFRS_WRITING</name>
              <bitOffset>20</bitOffset>
              <bitWidth>2</bitWidth>
            </field>
            <field>
              <name>TFRS_WAITING</name>
              <bitOffset>21</bitOffset>
              <bitWidth>1</bitWidth>
            </field>
            <field>
              <name>TPWA</name>
              <bitOffset>22</bitOffset>
              <bitWidth>1</bitWidth>
            </field>
            <field>
              <name>TFNE</name>
              <bitOffset>24</bitOffset>
              <bitWidth>1</bitWidth>
            </field>
            <field>
              <name>TFF</name>
              <bitOffset>25</bitOffset>
              <bitWidth>1</bitWidth>
            </field>
          </fields>
        </register>
        <register>
          <name>MACSR</name>
          <addressOffset>0x38</addressOffset>
          <size>0x20</size>
          <fields>
            <field>
              <name>PMTS</name>
              <bitOffset>3</bitOffset>
              <bitWidth>1</bitWidth>
            </field>
            <field>
              <name>MMCS</name>
              <bitOffset>4</bitOffset>
              <bitWidth>1</bitWidth>
            </field>
            <field>
              <name>MMMCRS</name>
              <bitOffset>5</bitOffset>
              <bitWidth>1</bitWidth>
            </field>
            <field>
              <name>MMCTS</name>
              <bitOffset>6</bitOffset>
              <bitWidth>1</bitWidth>
            </field>
            <field>
              <name>TSTS</name>
              <bitOffset>9</bitOffset>
              <bitWidth>1</bitWidth>
            </field>
          </fields>
        </register>
        <register>
          <name>MACIMR</name>
          <addressOffset>0x3c</addressOffset>
          <size>0x20</size>
          <fields>
            <field>
              <name>PMTIM</name>
              <bitOffset>3</bitOffset>
              <bitWidth>1</bitWidth>
            </field>
            <field>
              <name>TSTIM</name>
              <bitOffset>9</bitOffset>
              <bitWidth>1</bitWidth>
            </field>
          </fields>
        </register>
        <register>
          <name>MACA0HR</name>
          <addressOffset>0x40</addressOffset>
          <size>0x20</size>
          <fields>
            <field>
              <name>MACA0H</name>
              <bitOffset>0</bitOffset>
              <bitWidth>16</bitWidth>
            </field>
          </fields>
        </register>
        <register>
          <name>MACA0LR</name>
          <addressOffset>0x44</addressOffset>
          <size>0x20</size>
          <fields>
            <field>
              <name>MACA0L</name>
              <bitOffset>0</bitOffset>
              <bitWidth>32</bitWidth>
            </field>
          </fields>
        </register>
        <register>
          <name>MACA1HR</name>
          <addressOffset>0x48</addressOffset>
          <size>0x20</size>
          <fields>
            <field>
              <name>MACA1H</name>
              <bitOffset>0</bitOffset>
              <bitWidth>16</bitWidth>
            </field>
            <field>
              <name>MBC</name>
              <bitOffset>24</bitOffset>
              <bitWidth>6</bitWidth>
            </field>
            <field>
              <name>SA</name>
              <bitOffset>30</bitOffset>
              <bitWidth>1</bitWidth>
            </field>
            <field>
              <name>AE</name>
              <bitOffset>31</bitOffset>
              <bitWidth>1</bitWidth>
            </field>
          </fields>
        </register>
        <register>
          <name>MACA1LR</name>
          <addressOffset>0x4c</addressOffset>
          <size>0x20</size>
          <fields>
            <field>
              <name>MACA1L</name>
              <bitOffset>0</bitOffset>
              <bitWidth>32</bitWidth>
            </field>
          </fields>
        </register>
        <register>
          <name>MACA2HR</name>
          <addressOffset>0x50</addressOffset>
          <size>0x20</size>
          <fields>
            <field>
              <name>MACA2H</name>
              <bitOffset>0</bitOffset>
              <bitWidth>16</bitWidth>
            </field>
            <field>
              <name>MBC</name>
              <bitOffset>24</bitOffset>
              <bitWidth>6</bitWidth>
            </field>
            <field>
              <name>SA</name>
              <bitOffset>30</bitOffset>
              <bitWidth>1</bitWidth>
            </field>
            <field>
              <name>AE</name>
              <bitOffset>31</bitOffset>
              <bitWidth>1</bitWidth>
            </field>
          </fields>
        </register>
        <register>
          <name>MACA2LR</name>
          <addressOffset>0x54</addressOffset>
          <size>0x20</size>
          <fields>
            <field>
              <name>MACA2L</name>
              <bitOffset>0</bitOffset>
              <bitWidth>32</bitWidth>
            </field>
          </fields>
        </register>
        <register>
          <name>MACA3HR</name>
          <addressOffset>0x58</addressOffset>
          <size>0x20</size>
          <fields>
            <field>
              <name>MACA3H</name>
              <bitOffset>0</bitOffset>
              <bitWidth>16</bitWidth>
            </field>
            <field>
              <name>MBC</name>
              <bitOffset>24</bitOffset>
              <bitWidth>6</bitWidth>
            </field>
            <field>
              <name>SA</name>
              <bitOffset>30</bitOffset>
              <bitWidth>1</bitWidth>
            </field>
            <field>
              <name>AE</name>
              <bitOffset>31</bitOffset>
              <bitWidth>1</bitWidth>
            </field>
          </fields>
        </register>
        <register>
          <name>MACA3LR</name>
          <addressOffset>0x5c</addressOffset>
          <size>0x20</size>
          <fields>
            <field>
              <name>MACA3L</name>
              <bitOffset>0</bitOffset>
              <bitWidth>32</bitWidth>
            </field>
          </fields>
        </register>
        <register>
          <name>MMCCR</name>
          <addressOffset>0x100</addressOffset>
          <size>0x20</size>
          <fields>
            <field>
              <name>CR</name>
              <bitOffset>0</bitOffset>
              <bitWidth>1</bitWidth>
            </field>
            <field>
              <name>CSR</name>
              <bitOffset>1</bitOffset>
              <bitWidth>1</bitWidth>
            </field>
            <field>
              <name>ROR</name>
              <bitOffset>2</bitOffset>
              <bitWidth>1</bitWidth>
            </field>
            <field>
              <name>MCF</name>
              <bitOffset>3</bitOffset>
              <bitWidth>1</bitWidth>
            </field>
            <field>
              <name>MCP</name>
              <bitOffset>4</bitOffset>
              <bitWidth>1</bitWidth>
            </field>
            <field>
              <name>MCFHP</name>
              <bitOffset>5</bitOffset>
              <bitWidth>1</bitWidth>
            </field>
          </fields>
        </register>
        <register>
          <name>MMCRIR</name>
          <addressOffset>0x104</addressOffset>
          <size>0x20</size>
          <fields>
            <field>
              <name>RFCES</name>
              <bitOffset>5</bitOffset>
              <bitWidth>1</bitWidth>
            </field>
            <field>
              <name>RFAES</name>
              <bitOffset>6</bitOffset>
              <bitWidth>1</bitWidth>
            </field>
            <field>
              <name>RGUFS</name>
              <bitOffset>17</bitOffset>
              <bitWidth>1</bitWidth>
            </field>
          </fields>
        </register>
        <register>
          <name>MMCTIR</name>
          <addressOffset>0x108</addressOffset>
          <size>0x20</size>
          <fields>
            <field>
              <name>TGFSCS</name>
              <bitOffset>14</bitOffset>
              <bitWidth>1</bitWidth>
            </field>
            <field>
              <name>TGFMSCS</name>
              <bitOffset>15</bitOffset>
              <bitWidth>1</bitWidth>
            </field>
            <field>
              <name>TGFS</name>
              <bitOffset>21</bitOffset>
              <bitWidth>1</bitWidth>
            </field>
          </fields>
        </register>
        <register>
          <name>MMCRIMR</name>
          <addressOffset>0x10c</addressOffset>
          <size>0x20</size>
          <fields>
            <field>
              <name>RFCEM</name>
              <bitOffset>5</bitOffset>
              <bitWidth>1</bitWidth>
            </field>
            <field>
              <name>RFAEM</name>
              <bitOffset>6</bitOffset>
              <bitWidth>1</bitWidth>
            </field>
            <field>
              <name>RGUFM</name>
              <bitOffset>17</bitOffset>
              <bitWidth>1</bitWidth>
            </field>
          </fields>
        </register>
        <register>
          <name>MMCTIMR</name>
          <addressOffset>0x110</addressOffset>
          <size>0x20</size>
          <fields>
            <field>
              <name>TGFSCM</name>
              <bitOffset>14</bitOffset>
              <bitWidth>1</bitWidth>
            </field>
            <field>
              <name>TGFMSCM</name>
              <bitOffset>15</bitOffset>
              <bitWidth>1</bitWidth>
            </field>
            <field>
              <name>TGFM</name>
              <bitOffset>21</bitOffset>
              <bitWidth>1</bitWidth>
            </field>
          </fields>
        </register>
        <register>
          <name>MMCTGFSCCR</name>
          <addressOffset>0x14c</addressOffset>
          <size>0x20</size>
          <fields>
            <field>
              <name>TGFSCC</name>
              <bitOffset>0</bitOffset>
              <bitWidth>32</bitWidth>
            </field>
          </fields>
        </register>
        <register>
          <name>MMCTGFMSCCR</name>
          <addressOffset>0x150</addressOffset>
          <size>0x20</size>
          <fields>
            <field>
              <name>TGFMSCC</name>
              <bitOffset>0</bitOffset>
              <bitWidth>32</bitWidth>
            </field>
          </fields>
        </register>
        <register>
          <name>MMCTGFCR</name>
          <addressOffset>0x168</addressOffset>
          <size>0x20</size>
          <fields>
            <field>
              <name>TGFC</name>
              <bitOffset>0</bitOffset>
              <bitWidth>32</bitWidth>
            </field>
          </fields>
        </register>
        <register>
          <name>MMCRFCECR</name>
          <addressOffset>0x194</addressOffset>
          <size>0x20</size>
          <fields>
            <field>
              <name>RFCEC</name>
              <bitOffset>0</bitOffset>
              <bitWidth>32</bitWidth>
            </field>
          </fields>
        </register>
        <register>
          <name>MMCRFAECR</name>
          <addressOffset>0x198</addressOffset>
          <size>0x20</size>
          <fields>
            <field>
              <name>RFAEC</name>
              <bitOffset>0</bitOffset>
              <bitWidth>32</bitWidth>
            </field>
          </fields>
        </register>
        <register>
          <name>MMCRGUFCR</name>
          <addressOffset>0x1c4</addressOffset>
          <size>0x20</size>
          <fields>
            <field>
              <name>RGUFC</name>
              <bitOffset>0</bitOffset>
              <bitWidth>32</bitWidth>
            </field>
          </fields>
        </register>
        <register>
          <name>PTPTSCR</name>
          <addressOffset>0x700</addressOffset>
          <size>0x20</size>
          <fields>
            <field>
              <name>TSE</name>
              <bitOffset>0</bitOffset>
              <bitWidth>1</bitWidth>
            </field>
            <field>
              <name>TSFCU</name>
              <bitOffset>1</bitOffset>
              <bitWidth>1</bitWidth>
            </field>
            <field>
              <name>TSSTI</name>
              <bitOffset>2</bitOffset>
              <bitWidth>1</bitWidth>
            </field>
            <field>
              <name>TSSTU</name>
              <bitOffset>3</bitOffset>
              <bitWidth>1</bitWidth>
            </field>
            <field>
              <name>TSITE</name>
              <bitOffset>4</bitOffset>
              <bitWidth>1</bitWidth>
            </field>
            <field>
              <name>TSARU</name>
              <bitOffset>5</bitOffset>
              <bitWidth>1</bitWidth>
            </field>
            <field>
              <name>TSSARFE</name>
              <bitOffset>8</bitOffset>
              <bitWidth>1</bitWidth>
            </field>
            <field>
              <name>TSSSR</name>
              <bitOffset>9</bitOffset>
              <bitWidth>1</bitWidth>
            </field>
            <field>
              <name>TSPTPPSV2E</name>
              <bitOffset>10</bitOffset>
              <bitWidth>1</bitWidth>
            </field>
            <field>
              <name>TSSPTPOEFE</name>
              <bitOffset>11</bitOffset>
              <bitWidth>1</bitWidth>
            </field>
            <field>
              <name>TSSIPV6FE</name>
              <bitOffset>12</bitOffset>
              <bitWidth>1</bitWidth>
            </field>
            <field>
              <name>TSSIPV4FE</name>
              <bitOffset>13</bitOffset>
              <bitWidth>1</bitWidth>
            </field>
            <field>
              <name>TSSEME</name>
              <bitOffset>14</bitOffset>
              <bitWidth>1</bitWidth>
            </field>
            <field>
              <name>TSSMRME</name>
              <bitOffset>15</bitOffset>
              <bitWidth>1</bitWidth>
            </field>
            <field>
              <name>TSCNT</name>
              <bitOffset>16</bitOffset>
              <bitWidth>2</bitWidth>
            </field>
            <field>
              <name>TSPFFMAE</name>
              <bitOffset>18</bitOffset>
              <bitWidth>1</bitWidth>
            </field>
          </fields>
        </register>
        <register>
          <name>PTPSSIR</name>
          <addressOffset>0x704</addressOffset>
          <size>0x20</size>
          <fields>
            <field>
              <name>STSSI</name>
              <bitOffset>0</bitOffset>
              <bitWidth>8</bitWidth>
            </field>
          </fields>
        </register>
        <register>
          <name>PTPTSHR</name>
          <addressOffset>0x708</addressOffset>
          <size>0x20</size>
          <fields>
            <field>
              <name>STS</name>
              <bitOffset>0</bitOffset>
              <bitWidth>32</bitWidth>
            </field>
          </fields>
        </register>
        <register>
          <name>PTPTSLR</name>
          <addressOffset>0x70c</addressOffset>
          <size>0x20</size>
          <fields>
            <field>
              <name>STSS</name>
              <bitOffset>0</bitOffset>
              <bitWidth>31</bitWidth>
            </field>
            <field>
              <name>STPNS</name>
              <bitOffset>31</bitOffset>
              <bitWidth>1</bitWidth>
            </field>
          </fields>
        </register>
        <register>
          <name>PTPTSHUR</name>
          <addressOffset>0x710</addressOffset>
          <size>0x20</size>
          <fields>
            <field>
              <name>TSUS</name>
              <bitOffset>0</bitOffset>
              <bitWidth>32</bitWidth>
            </field>
          </fields>
        </register>
        <register>
          <name>PTPTSLUR</name>
          <addressOffset>0x714</addressOffset>
          <size>0x20</size>
          <fields>
            <field>
              <name>TSUSS</name>
              <bitOffset>0</bitOffset>
              <bitWidth>31</bitWidth>
            </field>
            <field>
              <name>TSUPNS</name>
              <bitOffset>31</bitOffset>
              <bitWidth>1</bitWidth>
            </field>
          </fields>
        </register>
        <register>
          <name>PTPTSAR</name>
          <addressOffset>0x718</addressOffset>
          <size>0x20</size>
          <fields>
            <field>
              <name>TSA</name>
              <bitOffset>0</bitOffset>
              <bitWidth>32</bitWidth>
            </field>
          </fields>
        </register>
        <register>
          <name>PTPTTHR</name>
          <addressOffset>0x71c</addressOffset>
          <size>0x20</size>
          <fields>
            <field>
              <name>TTSH</name>
              <bitOffset>0</bitOffset>
              <bitWidth>32</bitWidth>
            </field>
          </fields>
        </register>
        <register>
          <name>PTPTTLR</name>
          <addressOffset>0x720</addressOffset>
          <size>0x20</size>
          <fields>
            <field>
              <name>TTSL</name>
              <bitOffset>0</bitOffset>
              <bitWidth>32</bitWidth>
            </field>
          </fields>
        </register>
        <register>
          <name>PTPTSSR</name>
          <addressOffset>0x728</addressOffset>
          <size>0x20</size>
          <fields>
            <field>
              <name>TSSO</name>
              <bitOffset>4</bitOffset>
              <bitWidth>1</bitWidth>
            </field>
            <field>
              <name>TSTTR</name>
              <bitOffset>5</bitOffset>
              <bitWidth>1</bitWidth>
            </field>
          </fields>
        </register>
        <register>
          <name>PTPPPSCR</name>
          <addressOffset>0x72c</addressOffset>
          <size>0x20</size>
          <fields>
            <field>
              <name>PPSFREQ</name>
              <bitOffset>0</bitOffset>
              <bitWidth>4</bitWidth>
            </field>
          </fields>
        </register>
        <register>
          <name>DMABMR</name>
          <addressOffset>0x1000</addressOffset>
          <size>0x20</size>
          <fields>
            <field>
              <name>SR</name>
              <bitOffset>0</bitOffset>
              <bitWidth>1</bitWidth>
            </field>
            <field>
              <name>DA</name>
              <bitOffset>1</bitOffset>
              <bitWidth>1</bitWidth>
            </field>
            <field>
              <name>DSL</name>
              <bitOffset>2</bitOffset>
              <bitWidth>5</bitWidth>
            </field>
            <field>
              <name>EDE</name>
              <bitOffset>7</bitOffset>
              <bitWidth>1</bitWidth>
            </field>
            <field>
              <name>PBL</name>
              <bitOffset>8</bitOffset>
              <bitWidth>6</bitWidth>
            </field>
            <field>
              <name>RTPR</name>
              <bitOffset>14</bitOffset>
              <bitWidth>2</bitWidth>
            </field>
            <field>
              <name>FB</name>
              <bitOffset>16</bitOffset>
              <bitWidth>1</bitWidth>
            </field>
            <field>
              <name>RDP</name>
              <bitOffset>17</bitOffset>
              <bitWidth>6</bitWidth>
            </field>
            <field>
              <name>USP</name>
              <bitOffset>23</bitOffset>
              <bitWidth>1</bitWidth>
            </field>
            <field>
              <name>FPM</name>
              <bitOffset>24</bitOffset>
              <bitWidth>1</bitWidth>
            </field>
            <field>
              <name>AAB</name>
              <bitOffset>25</bitOffset>
              <bitWidth>1</bitWidth>
            </field>
            <field>
              <name>MB</name>
              <bitOffset>26</bitOffset>
              <bitWidth>1</bitWidth>
            </field>
          </fields>
        </register>
        <register>
          <name>DMATPDR</name>
          <addressOffset>0x1004</addressOffset>
          <size>0x20</size>
          <fields>
            <field>
              <name>TPD</name>
              <bitOffset>0</bitOffset>
              <bitWidth>32</bitWidth>
            </field>
          </fields>
        </register>
        <register>
          <name>DMARPDR</name>
          <addressOffset>0x1008</addressOffset>
          <size>0x20</size>
          <fields>
            <field>
              <name>RPD</name>
              <bitOffset>0</bitOffset>
              <bitWidth>32</bitWidth>
            </field>
          </fields>
        </register>
        <register>
          <name>DMARDLAR</name>
          <addressOffset>0x100c</addressOffset>
          <size>0x20</size>
          <fields>
            <field>
              <name>SRL</name>
              <bitOffset>0</bitOffset>
              <bitWidth>32</bitWidth>
            </field>
          </fields>
        </register>
        <register>
          <name>DMATDLAR</name>
          <addressOffset>0x1010</addressOffset>
          <size>0x20</size>
          <fields>
            <field>
              <name>STL</name>
              <bitOffset>0</bitOffset>
              <bitWidth>32</bitWidth>
            </field>
          </fields>
        </register>
        <register>
          <name>DMASR</name>
          <addressOffset>0x1014</addressOffset>
          <size>0x20</size>
          <fields>
            <field>
              <name>TS</name>
              <bitOffset>0</bitOffset>
              <bitWidth>1</bitWidth>
            </field>
            <field>
              <name>TPSS</name>
              <bitOffset>1</bitOffset>
              <bitWidth>1</bitWidth>
            </field>
            <field>
              <name>TBUS</name>
              <bitOffset>2</bitOffset>
              <bitWidth>1</bitWidth>
            </field>
            <field>
              <name>TJTS</name>
              <bitOffset>3</bitOffset>
              <bitWidth>1</bitWidth>
            </field>
            <field>
              <name>ROS</name>
              <bitOffset>4</bitOffset>
              <bitWidth>1</bitWidth>
            </field>
            <field>
              <name>TUS</name>
              <bitOffset>5</bitOffset>
              <bitWidth>1</bitWidth>
            </field>
            <field>
              <name>RS</name>
              <bitOffset>6</bitOffset>
              <bitWidth>1</bitWidth>
            </field>
            <field>
              <name>RBUS</name>
              <bitOffset>7</bitOffset>
              <bitWidth>1</bitWidth>
            </field>
            <field>
              <name>RPSS</name>
              <bitOffset>8</bitOffset>
              <bitWidth>1</bitWidth>
            </field>
            <field>
              <name>RWTS</name>
              <bitOffset>9</bitOffset>
              <bitWidth>1</bitWidth>
            </field>
            <field>
              <name>ETS</name>
              <bitOffset>10</bitOffset>
              <bitWidth>1</bitWidth>
            </field>
            <field>
              <name>FBES</name>
              <bitOffset>13</bitOffset>
              <bitWidth>1</bitWidth>
            </field>
            <field>
              <name>ERS</name>
              <bitOffset>14</bitOffset>
              <bitWidth>1</bitWidth>
            </field>
            <field>
              <name>AIS</name>
              <bitOffset>15</bitOffset>
              <bitWidth>1</bitWidth>
            </field>
            <field>
              <name>NIS</name>
              <bitOffset>16</bitOffset>
              <bitWidth>1</bitWidth>
            </field>
            <field>
              <name>RPS_Waiting</name>
              <bitOffset>17</bitOffset>
              <bitWidth>2</bitWidth>
            </field>
            <field>
              <name>RPS_Suspended</name>
              <bitOffset>19</bitOffset>
              <bitWidth>1</bitWidth>
            </field>
            <field>
              <name>TPS_Reading</name>
              <bitOffset>20</bitOffset>
              <bitWidth>2</bitWidth>
            </field>
            <field>
              <name>TPS_Waiting</name>
              <bitOffset>21</bitOffset>
              <bitWidth>1</bitWidth>
            </field>
            <field>
              <name>EBS_DataTransfTx</name>
              <bitOffset>23</bitOffset>
              <bitWidth>1</bitWidth>
            </field>
            <field>
              <name>EBS_ReadTransf</name>
              <bitOffset>24</bitOffset>
              <bitWidth>1</bitWidth>
            </field>
            <field>
              <name>EBS_DescAccess</name>
              <bitOffset>25</bitOffset>
              <bitWidth>1</bitWidth>
            </field>
            <field>
              <name>MMCS</name>
              <bitOffset>27</bitOffset>
              <bitWidth>1</bitWidth>
            </field>
            <field>
              <name>PMTS</name>
              <bitOffset>28</bitOffset>
              <bitWidth>1</bitWidth>
            </field>
            <field>
              <name>TSTS</name>
              <bitOffset>29</bitOffset>
              <bitWidth>1</bitWidth>
            </field>
          </fields>
        </register>
        <register>
          <name>DMAOMR</name>
          <addressOffset>0x1018</addressOffset>
          <size>0x20</size>
          <fields>
            <field>
              <name>SR</name>
              <bitOffset>1</bitOffset>
              <bitWidth>1</bitWidth>
            </field>
            <field>
              <name>OSF</name>
              <bitOffset>2</bitOffset>
              <bitWidth>1</bitWidth>
            </field>
            <field>
              <name>RTC</name>
              <bitOffset>3</bitOffset>
              <bitWidth>2</bitWidth>
            </field>
            <field>
              <name>FUGF</name>
              <bitOffset>6</bitOffset>
              <bitWidth>1</bitWidth>
            </field>
            <field>
              <name>FEF</name>
              <bitOffset>7</bitOffset>
              <bitWidth>1</bitWidth>
            </field>
            <field>
              <name>ST</name>
              <bitOffset>13</bitOffset>
              <bitWidth>1</bitWidth>
            </field>
            <field>
              <name>TTC</name>
              <bitOffset>14</bitOffset>
              <bitWidth>3</bitWidth>
            </field>
            <field>
              <name>FTF</name>
              <bitOffset>20</bitOffset>
              <bitWidth>1</bitWidth>
            </field>
            <field>
              <name>TSF</name>
              <bitOffset>21</bitOffset>
              <bitWidth>1</bitWidth>
            </field>
            <field>
              <name>DFRF</name>
              <bitOffset>24</bitOffset>
              <bitWidth>1</bitWidth>
            </field>
            <field>
              <name>RSF</name>
              <bitOffset>25</bitOffset>
              <bitWidth>1</bitWidth>
            </field>
            <field>
              <name>DTCEFD</name>
              <bitOffset>26</bitOffset>
              <bitWidth>1</bitWidth>
            </field>
          </fields>
        </register>
        <register>
          <name>DMAIER</name>
          <addressOffset>0x101c</addressOffset>
          <size>0x20</size>
          <fields>
            <field>
              <name>TIE</name>
              <bitOffset>0</bitOffset>
              <bitWidth>1</bitWidth>
            </field>
            <field>
              <name>TPSIE</name>
              <bitOffset>1</bitOffset>
              <bitWidth>1</bitWidth>
            </field>
            <field>
              <name>TBUIE</name>
              <bitOffset>2</bitOffset>
              <bitWidth>1</bitWidth>
            </field>
            <field>
              <name>TJTIE</name>
              <bitOffset>3</bitOffset>
              <bitWidth>1</bitWidth>
            </field>
            <field>
              <name>ROIE</name>
              <bitOffset>4</bitOffset>
              <bitWidth>1</bitWidth>
            </field>
            <field>
              <name>TUIE</name>
              <bitOffset>5</bitOffset>
              <bitWidth>1</bitWidth>
            </field>
            <field>
              <name>RIE</name>
              <bitOffset>6</bitOffset>
              <bitWidth>1</bitWidth>
            </field>
            <field>
              <name>RBUIE</name>
              <bitOffset>7</bitOffset>
              <bitWidth>1</bitWidth>
            </field>
            <field>
              <name>RPSIE</name>
              <bitOffset>8</bitOffset>
              <bitWidth>1</bitWidth>
            </field>
            <field>
              <name>RWTIE</name>
              <bitOffset>9</bitOffset>
              <bitWidth>1</bitWidth>
            </field>
            <field>
              <name>ETIE</name>
              <bitOffset>10</bitOffset>
              <bitWidth>1</bitWidth>
            </field>
            <field>
              <name>FBEIE</name>
              <bitOffset>13</bitOffset>
              <bitWidth>1</bitWidth>
            </field>
            <field>
              <name>ERIE</name>
              <bitOffset>14</bitOffset>
              <bitWidth>1</bitWidth>
            </field>
            <field>
              <name>AISE</name>
              <bitOffset>15</bitOffset>
              <bitWidth>1</bitWidth>
            </field>
            <field>
              <name>NISE</name>
              <bitOffset>16</bitOffset>
              <bitWidth>1</bitWidth>
            </field>
          </fields>
        </register>
        <register>
          <name>DMAMFBOCR</name>
          <addressOffset>0x1020</addressOffset>
          <size>0x20</size>
          <fields>
            <field>
              <name>MFC</name>
              <bitOffset>0</bitOffset>
              <bitWidth>16</bitWidth>
            </field>
            <field>
              <name>OMFC</name>
              <bitOffset>16</bitOffset>
              <bitWidth>1</bitWidth>
            </field>
            <field>
              <name>MFA</name>
              <bitOffset>17</bitOffset>
              <bitWidth>11</bitWidth>
            </field>
            <field>
              <name>OFOC</name>
              <bitOffset>28</bitOffset>
              <bitWidth>1</bitWidth>
            </field>
          </fields>
        </register>
        <register>
          <name>DMARSWTR</name>
          <addressOffset>0x1024</addressOffset>
          <size>0x20</size>
        </register>
        <register>
          <name>DMACHTDR</name>
          <addressOffset>0x1048</addressOffset>
          <size>0x20</size>
          <fields>
            <field>
              <name>HTDAP</name>
              <bitOffset>0</bitOffset>
              <bitWidth>32</bitWidth>
            </field>
          </fields>
        </register>
        <register>
          <name>DMACHRDR</name>
          <addressOffset>0x104c</addressOffset>
          <size>0x20</size>
          <fields>
            <field>
              <name>HRDAP</name>
              <bitOffset>0</bitOffset>
              <bitWidth>32</bitWidth>
            </field>
          </fields>
        </register>
        <register>
          <name>DMACHTBAR</name>
          <addressOffset>0x1050</addressOffset>
          <size>0x20</size>
          <fields>
            <field>
              <name>HTBAP</name>
              <bitOffset>0</bitOffset>
              <bitWidth>32</bitWidth>
            </field>
          </fields>
        </register>
        <register>
          <name>DMACHRBAR</name>
          <addressOffset>0x1054</addressOffset>
          <size>0x20</size>
          <fields>
            <field>
              <name>HRBAP</name>
              <bitOffset>0</bitOffset>
              <bitWidth>32</bitWidth>
            </field>
          </fields>
        </register>
      </registers>
    </peripheral>
    <peripheral>
      <name>DMA2D</name>
      <baseAddress>0x4002b000</baseAddress>
      <registers>
        <register>
          <name>CR</name>
          <addressOffset>0x0</addressOffset>
          <size>0x20</size>
          <fields>
            <field>
              <name>START</name>
              <bitOffset>0</bitOffset>
              <bitWidth>1</bitWidth>
            </field>
            <field>
              <name>SUSP</name>
              <bitOffset>1</bitOffset>
              <bitWidth>1</bitWidth>
            </field>
            <field>
              <name>ABORT</name>
              <bitOffset>2</bitOffset>
              <bitWidth>1</bitWidth>
            </field>
            <field>
              <name>TEIE</name>
              <bitOffset>8</bitOffset>
              <bitWidth>1</bitWidth>
            </field>
            <field>
              <name>TCIE</name>
              <bitOffset>9</bitOffset>
              <bitWidth>1</bitWidth>
            </field>
            <field>
              <name>TWIE</name>
              <bitOffset>10</bitOffset>
              <bitWidth>1</bitWidth>
            </field>
            <field>
              <name>CAEIE</name>
              <bitOffset>11</bitOffset>
              <bitWidth>1</bitWidth>
            </field>
            <field>
              <name>CTCIE</name>
              <bitOffset>12</bitOffset>
              <bitWidth>1</bitWidth>
            </field>
            <field>
              <name>CEIE</name>
              <bitOffset>13</bitOffset>
              <bitWidth>1</bitWidth>
            </field>
            <field>
              <name>MODE</name>
              <bitOffset>16</bitOffset>
              <bitWidth>2</bitWidth>
            </field>
          </fields>
        </register>
        <register>
          <name>ISR</name>
          <addressOffset>0x4</addressOffset>
          <size>0x20</size>
          <fields>
            <field>
              <name>TEIF</name>
              <bitOffset>0</bitOffset>
              <bitWidth>1</bitWidth>
            </field>
            <field>
              <name>TCIF</name>
              <bitOffset>1</bitOffset>
              <bitWidth>1</bitWidth>
            </field>
            <field>
              <name>TWIF</name>
              <bitOffset>2</bitOffset>
              <bitWidth>1</bitWidth>
            </field>
            <field>
              <name>CAEIF</name>
              <bitOffset>3</bitOffset>
              <bitWidth>1</bitWidth>
            </field>
            <field>
              <name>CTCIF</name>
              <bitOffset>4</bitOffset>
              <bitWidth>1</bitWidth>
            </field>
            <field>
              <name>CEIF</name>
              <bitOffset>5</bitOffset>
              <bitWidth>1</bitWidth>
            </field>
          </fields>
        </register>
        <register>
          <name>IFCR</name>
          <addressOffset>0x8</addressOffset>
          <size>0x20</size>
          <fields>
            <field>
              <name>CTEIF</name>
              <bitOffset>0</bitOffset>
              <bitWidth>1</bitWidth>
            </field>
            <field>
              <name>CTCIF</name>
              <bitOffset>1</bitOffset>
              <bitWidth>1</bitWidth>
            </field>
            <field>
              <name>CTWIF</name>
              <bitOffset>2</bitOffset>
              <bitWidth>1</bitWidth>
            </field>
            <field>
              <name>CAECIF</name>
              <bitOffset>3</bitOffset>
              <bitWidth>1</bitWidth>
            </field>
            <field>
              <name>CCTCIF</name>
              <bitOffset>4</bitOffset>
              <bitWidth>1</bitWidth>
            </field>
            <field>
              <name>CCEIF</name>
              <bitOffset>5</bitOffset>
              <bitWidth>1</bitWidth>
            </field>
          </fields>
        </register>
        <register>
          <name>FGMAR</name>
          <addressOffset>0xc</addressOffset>
          <size>0x20</size>
          <fields>
            <field>
              <name>MA</name>
              <bitOffset>0</bitOffset>
              <bitWidth>32</bitWidth>
            </field>
          </fields>
        </register>
        <register>
          <name>FGOR</name>
          <addressOffset>0x10</addressOffset>
          <size>0x20</size>
          <fields>
            <field>
              <name>LO</name>
              <bitOffset>0</bitOffset>
              <bitWidth>14</bitWidth>
            </field>
          </fields>
        </register>
        <register>
          <name>BGMAR</name>
          <addressOffset>0x14</addressOffset>
          <size>0x20</size>
          <fields>
            <field>
              <name>MA</name>
              <bitOffset>0</bitOffset>
              <bitWidth>32</bitWidth>
            </field>
          </fields>
        </register>
        <register>
          <name>BGOR</name>
          <addressOffset>0x18</addressOffset>
          <size>0x20</size>
          <fields>
            <field>
              <name>LO</name>
              <bitOffset>0</bitOffset>
              <bitWidth>14</bitWidth>
            </field>
          </fields>
        </register>
        <register>
          <name>FGPFCCR</name>
          <addressOffset>0x1c</addressOffset>
          <size>0x20</size>
          <fields>
            <field>
              <name>CM</name>
              <bitOffset>0</bitOffset>
              <bitWidth>4</bitWidth>
            </field>
            <field>
              <name>CCM</name>
              <bitOffset>4</bitOffset>
              <bitWidth>1</bitWidth>
            </field>
            <field>
              <name>START</name>
              <bitOffset>5</bitOffset>
              <bitWidth>1</bitWidth>
            </field>
            <field>
              <name>CS</name>
              <bitOffset>8</bitOffset>
              <bitWidth>8</bitWidth>
            </field>
            <field>
              <name>AM</name>
              <bitOffset>16</bitOffset>
              <bitWidth>2</bitWidth>
            </field>
            <field>
              <name>AI</name>
              <bitOffset>20</bitOffset>
              <bitWidth>1</bitWidth>
            </field>
            <field>
              <name>RBS</name>
              <bitOffset>21</bitOffset>
              <bitWidth>1</bitWidth>
            </field>
            <field>
              <name>ALPHA</name>
              <bitOffset>24</bitOffset>
              <bitWidth>8</bitWidth>
            </field>
          </fields>
        </register>
        <register>
          <name>FGCOLR</name>
          <addressOffset>0x20</addressOffset>
          <size>0x20</size>
          <fields>
            <field>
              <name>BLUE</name>
              <bitOffset>0</bitOffset>
              <bitWidth>8</bitWidth>
            </field>
            <field>
              <name>GREEN</name>
              <bitOffset>8</bitOffset>
              <bitWidth>8</bitWidth>
            </field>
            <field>
              <name>RED</name>
              <bitOffset>16</bitOffset>
              <bitWidth>8</bitWidth>
            </field>
          </fields>
        </register>
        <register>
          <name>BGPFCCR</name>
          <addressOffset>0x24</addressOffset>
          <size>0x20</size>
          <fields>
            <field>
              <name>CM</name>
              <bitOffset>0</bitOffset>
              <bitWidth>4</bitWidth>
            </field>
            <field>
              <name>CCM</name>
              <bitOffset>4</bitOffset>
              <bitWidth>1</bitWidth>
            </field>
            <field>
              <name>START</name>
              <bitOffset>5</bitOffset>
              <bitWidth>1</bitWidth>
            </field>
            <field>
              <name>CS</name>
              <bitOffset>8</bitOffset>
              <bitWidth>8</bitWidth>
            </field>
            <field>
              <name>AM</name>
              <bitOffset>16</bitOffset>
              <bitWidth>2</bitWidth>
            </field>
            <field>
              <name>AI</name>
              <bitOffset>20</bitOffset>
              <bitWidth>1</bitWidth>
            </field>
            <field>
              <name>RBS</name>
              <bitOffset>21</bitOffset>
              <bitWidth>1</bitWidth>
            </field>
            <field>
              <name>ALPHA</name>
              <bitOffset>24</bitOffset>
              <bitWidth>8</bitWidth>
            </field>
          </fields>
        </register>
        <register>
          <name>BGCOLR</name>
          <addressOffset>0x28</addressOffset>
          <size>0x20</size>
          <fields>
            <field>
              <name>BLUE</name>
              <bitOffset>0</bitOffset>
              <bitWidth>8</bitWidth>
            </field>
            <field>
              <name>GREEN</name>
              <bitOffset>8</bitOffset>
              <bitWidth>8</bitWidth>
            </field>
            <field>
              <name>RED</name>
              <bitOffset>16</bitOffset>
              <bitWidth>8</bitWidth>
            </field>
          </fields>
        </register>
        <register>
          <name>FGCMAR</name>
          <addressOffset>0x2c</addressOffset>
          <size>0x20</size>
          <fields>
            <field>
              <name>MA</name>
              <bitOffset>0</bitOffset>
              <bitWidth>32</bitWidth>
            </field>
          </fields>
        </register>
        <register>
          <name>BGCMAR</name>
          <addressOffset>0x30</addressOffset>
          <size>0x20</size>
          <fields>
            <field>
              <name>MA</name>
              <bitOffset>0</bitOffset>
              <bitWidth>32</bitWidth>
            </field>
          </fields>
        </register>
        <register>
          <name>OPFCCR</name>
          <addressOffset>0x34</addressOffset>
          <size>0x20</size>
          <fields>
            <field>
              <name>CM</name>
              <bitOffset>0</bitOffset>
              <bitWidth>3</bitWidth>
            </field>
            <field>
              <name>AI</name>
              <bitOffset>20</bitOffset>
              <bitWidth>1</bitWidth>
            </field>
            <field>
              <name>RBS</name>
              <bitOffset>21</bitOffset>
              <bitWidth>1</bitWidth>
            </field>
          </fields>
        </register>
        <register>
          <name>OCOLR</name>
          <addressOffset>0x38</addressOffset>
          <size>0x20</size>
        </register>
        <register>
          <name>OMAR</name>
          <addressOffset>0x3c</addressOffset>
          <size>0x20</size>
          <fields>
            <field>
              <name>MA</name>
              <bitOffset>0</bitOffset>
              <bitWidth>32</bitWidth>
            </field>
          </fields>
        </register>
        <register>
          <name>OOR</name>
          <addressOffset>0x40</addressOffset>
          <size>0x20</size>
          <fields>
            <field>
              <name>LO</name>
              <bitOffset>0</bitOffset>
              <bitWidth>14</bitWidth>
            </field>
          </fields>
        </register>
        <register>
          <name>NLR</name>
          <addressOffset>0x44</addressOffset>
          <size>0x20</size>
          <fields>
            <field>
              <name>NL</name>
              <bitOffset>0</bitOffset>
              <bitWidth>16</bitWidth>
            </field>
            <field>
              <name>PL</name>
              <bitOffset>16</bitOffset>
              <bitWidth>14</bitWidth>
            </field>
          </fields>
        </register>
        <register>
          <name>LWR</name>
          <addressOffset>0x48</addressOffset>
          <size>0x20</size>
          <fields>
            <field>
              <name>LW</name>
              <bitOffset>0</bitOffset>
              <bitWidth>16</bitWidth>
            </field>
          </fields>
        </register>
        <register>
          <name>AMTCR</name>
          <addressOffset>0x4c</addressOffset>
          <size>0x20</size>
          <fields>
            <field>
              <name>EN</name>
              <bitOffset>0</bitOffset>
              <bitWidth>1</bitWidth>
            </field>
            <field>
              <name>DT</name>
              <bitOffset>8</bitOffset>
              <bitWidth>8</bitWidth>
            </field>
          </fields>
        </register>
        <register>
          <name>FGCLUT.0</name>
          <addressOffset>0x400</addressOffset>
          <size>0x20</size>
        </register>
        <register>
          <name>FGCLUT.1</name>
          <addressOffset>0x404</addressOffset>
          <size>0x20</size>
        </register>
        <register>
          <name>FGCLUT.2</name>
          <addressOffset>0x408</addressOffset>
          <size>0x20</size>
        </register>
        <register>
          <name>FGCLUT.3</name>
          <addressOffset>0x40c</addressOffset>
          <size>0x20</size>
        </register>
        <register>
          <name>FGCLUT.4</name>
          <addressOffset>0x410</addressOffset>
          <size>0x20</size>
        </register>
        <register>
          <name>FGCLUT.5</name>
          <addressOffset>0x414</addressOffset>
          <size>0x20</size>
        </register>
        <register>
          <name>FGCLUT.6</name>
          <addressOffset>0x418</addressOffset>
          <size>0x20</size>
        </register>
        <register>
          <name>FGCLUT.7</name>
          <addressOffset>0x41c</addressOffset>
          <size>0x20</size>
        </register>
        <register>
          <name>FGCLUT.8</name>
          <addressOffset>0x420</addressOffset>
          <size>0x20</size>
        </register>
        <register>
          <name>FGCLUT.9</name>
          <addressOffset>0x424</addressOffset>
          <size>0x20</size>
        </register>
        <register>
          <name>FGCLUT.10</name>
          <addressOffset>0x428</addressOffset>
          <size>0x20</size>
        </register>
        <register>
          <name>FGCLUT.11</name>
          <addressOffset>0x42c</addressOffset>
          <size>0x20</size>
        </register>
        <register>
          <name>FGCLUT.12</name>
          <addressOffset>0x430</addressOffset>
          <size>0x20</size>
        </register>
        <register>
          <name>FGCLUT.13</name>
          <addressOffset>0x434</addressOffset>
          <size>0x20</size>
        </register>
        <register>
          <name>FGCLUT.14</name>
          <addressOffset>0x438</addressOffset>
          <size>0x20</size>
        </register>
        <register>
          <name>FGCLUT.15</name>
          <addressOffset>0x43c</addressOffset>
          <size>0x20</size>
        </register>
        <register>
          <name>FGCLUT.16</name>
          <addressOffset>0x440</addressOffset>
          <size>0x20</size>
        </register>
        <register>
          <name>FGCLUT.17</name>
          <addressOffset>0x444</addressOffset>
          <size>0x20</size>
        </register>
        <register>
          <name>FGCLUT.18</name>
          <addressOffset>0x448</addressOffset>
          <size>0x20</size>
        </register>
        <register>
          <name>FGCLUT.19</name>
          <addressOffset>0x44c</addressOffset>
          <size>0x20</size>
        </register>
        <register>
          <name>FGCLUT.20</name>
          <addressOffset>0x450</addressOffset>
          <size>0x20</size>
        </register>
        <register>
          <name>FGCLUT.21</name>
          <addressOffset>0x454</addressOffset>
          <size>0x20</size>
        </register>
        <register>
          <name>FGCLUT.22</name>
          <addressOffset>0x458</addressOffset>
          <size>0x20</size>
        </register>
        <register>
          <name>FGCLUT.23</name>
          <addressOffset>0x45c</addressOffset>
          <size>0x20</size>
        </register>
        <register>
          <name>FGCLUT.24</name>
          <addressOffset>0x460</addressOffset>
          <size>0x20</size>
        </register>
        <register>
          <name>FGCLUT.25</name>
          <addressOffset>0x464</addressOffset>
          <size>0x20</size>
        </register>
        <register>
          <name>FGCLUT.26</name>
          <addressOffset>0x468</addressOffset>
          <size>0x20</size>
        </register>
        <register>
          <name>FGCLUT.27</name>
          <addressOffset>0x46c</addressOffset>
          <size>0x20</size>
        </register>
        <register>
          <name>FGCLUT.28</name>
          <addressOffset>0x470</addressOffset>
          <size>0x20</size>
        </register>
        <register>
          <name>FGCLUT.29</name>
          <addressOffset>0x474</addressOffset>
          <size>0x20</size>
        </register>
        <register>
          <name>FGCLUT.30</name>
          <addressOffset>0x478</addressOffset>
          <size>0x20</size>
        </register>
        <register>
          <name>FGCLUT.31</name>
          <addressOffset>0x47c</addressOffset>
          <size>0x20</size>
        </register>
        <register>
          <name>FGCLUT.32</name>
          <addressOffset>0x480</addressOffset>
          <size>0x20</size>
        </register>
        <register>
          <name>FGCLUT.33</name>
          <addressOffset>0x484</addressOffset>
          <size>0x20</size>
        </register>
        <register>
          <name>FGCLUT.34</name>
          <addressOffset>0x488</addressOffset>
          <size>0x20</size>
        </register>
        <register>
          <name>FGCLUT.35</name>
          <addressOffset>0x48c</addressOffset>
          <size>0x20</size>
        </register>
        <register>
          <name>FGCLUT.36</name>
          <addressOffset>0x490</addressOffset>
          <size>0x20</size>
        </register>
        <register>
          <name>FGCLUT.37</name>
          <addressOffset>0x494</addressOffset>
          <size>0x20</size>
        </register>
        <register>
          <name>FGCLUT.38</name>
          <addressOffset>0x498</addressOffset>
          <size>0x20</size>
        </register>
        <register>
          <name>FGCLUT.39</name>
          <addressOffset>0x49c</addressOffset>
          <size>0x20</size>
        </register>
        <register>
          <name>FGCLUT.40</name>
          <addressOffset>0x4a0</addressOffset>
          <size>0x20</size>
        </register>
        <register>
          <name>FGCLUT.41</name>
          <addressOffset>0x4a4</addressOffset>
          <size>0x20</size>
        </register>
        <register>
          <name>FGCLUT.42</name>
          <addressOffset>0x4a8</addressOffset>
          <size>0x20</size>
        </register>
        <register>
          <name>FGCLUT.43</name>
          <addressOffset>0x4ac</addressOffset>
          <size>0x20</size>
        </register>
        <register>
          <name>FGCLUT.44</name>
          <addressOffset>0x4b0</addressOffset>
          <size>0x20</size>
        </register>
        <register>
          <name>FGCLUT.45</name>
          <addressOffset>0x4b4</addressOffset>
          <size>0x20</size>
        </register>
        <register>
          <name>FGCLUT.46</name>
          <addressOffset>0x4b8</addressOffset>
          <size>0x20</size>
        </register>
        <register>
          <name>FGCLUT.47</name>
          <addressOffset>0x4bc</addressOffset>
          <size>0x20</size>
        </register>
        <register>
          <name>FGCLUT.48</name>
          <addressOffset>0x4c0</addressOffset>
          <size>0x20</size>
        </register>
        <register>
          <name>FGCLUT.49</name>
          <addressOffset>0x4c4</addressOffset>
          <size>0x20</size>
        </register>
        <register>
          <name>FGCLUT.50</name>
          <addressOffset>0x4c8</addressOffset>
          <size>0x20</size>
        </register>
        <register>
          <name>FGCLUT.51</name>
          <addressOffset>0x4cc</addressOffset>
          <size>0x20</size>
        </register>
        <register>
          <name>FGCLUT.52</name>
          <addressOffset>0x4d0</addressOffset>
          <size>0x20</size>
        </register>
        <register>
          <name>FGCLUT.53</name>
          <addressOffset>0x4d4</addressOffset>
          <size>0x20</size>
        </register>
        <register>
          <name>FGCLUT.54</name>
          <addressOffset>0x4d8</addressOffset>
          <size>0x20</size>
        </register>
        <register>
          <name>FGCLUT.55</name>
          <addressOffset>0x4dc</addressOffset>
          <size>0x20</size>
        </register>
        <register>
          <name>FGCLUT.56</name>
          <addressOffset>0x4e0</addressOffset>
          <size>0x20</size>
        </register>
        <register>
          <name>FGCLUT.57</name>
          <addressOffset>0x4e4</addressOffset>
          <size>0x20</size>
        </register>
        <register>
          <name>FGCLUT.58</name>
          <addressOffset>0x4e8</addressOffset>
          <size>0x20</size>
        </register>
        <register>
          <name>FGCLUT.59</name>
          <addressOffset>0x4ec</addressOffset>
          <size>0x20</size>
        </register>
        <register>
          <name>FGCLUT.60</name>
          <addressOffset>0x4f0</addressOffset>
          <size>0x20</size>
        </register>
        <register>
          <name>FGCLUT.61</name>
          <addressOffset>0x4f4</addressOffset>
          <size>0x20</size>
        </register>
        <register>
          <name>FGCLUT.62</name>
          <addressOffset>0x4f8</addressOffset>
          <size>0x20</size>
        </register>
        <register>
          <name>FGCLUT.63</name>
          <addressOffset>0x4fc</addressOffset>
          <size>0x20</size>
        </register>
        <register>
          <name>FGCLUT.64</name>
          <addressOffset>0x500</addressOffset>
          <size>0x20</size>
        </register>
        <register>
          <name>FGCLUT.65</name>
          <addressOffset>0x504</addressOffset>
          <size>0x20</size>
        </register>
        <register>
          <name>FGCLUT.66</name>
          <addressOffset>0x508</addressOffset>
          <size>0x20</size>
        </register>
        <register>
          <name>FGCLUT.67</name>
          <addressOffset>0x50c</addressOffset>
          <size>0x20</size>
        </register>
        <register>
          <name>FGCLUT.68</name>
          <addressOffset>0x510</addressOffset>
          <size>0x20</size>
        </register>
        <register>
          <name>FGCLUT.69</name>
          <addressOffset>0x514</addressOffset>
          <size>0x20</size>
        </register>
        <register>
          <name>FGCLUT.70</name>
          <addressOffset>0x518</addressOffset>
          <size>0x20</size>
        </register>
        <register>
          <name>FGCLUT.71</name>
          <addressOffset>0x51c</addressOffset>
          <size>0x20</size>
        </register>
        <register>
          <name>FGCLUT.72</name>
          <addressOffset>0x520</addressOffset>
          <size>0x20</size>
        </register>
        <register>
          <name>FGCLUT.73</name>
          <addressOffset>0x524</addressOffset>
          <size>0x20</size>
        </register>
        <register>
          <name>FGCLUT.74</name>
          <addressOffset>0x528</addressOffset>
          <size>0x20</size>
        </register>
        <register>
          <name>FGCLUT.75</name>
          <addressOffset>0x52c</addressOffset>
          <size>0x20</size>
        </register>
        <register>
          <name>FGCLUT.76</name>
          <addressOffset>0x530</addressOffset>
          <size>0x20</size>
        </register>
        <register>
          <name>FGCLUT.77</name>
          <addressOffset>0x534</addressOffset>
          <size>0x20</size>
        </register>
        <register>
          <name>FGCLUT.78</name>
          <addressOffset>0x538</addressOffset>
          <size>0x20</size>
        </register>
        <register>
          <name>FGCLUT.79</name>
          <addressOffset>0x53c</addressOffset>
          <size>0x20</size>
        </register>
        <register>
          <name>FGCLUT.80</name>
          <addressOffset>0x540</addressOffset>
          <size>0x20</size>
        </register>
        <register>
          <name>FGCLUT.81</name>
          <addressOffset>0x544</addressOffset>
          <size>0x20</size>
        </register>
        <register>
          <name>FGCLUT.82</name>
          <addressOffset>0x548</addressOffset>
          <size>0x20</size>
        </register>
        <register>
          <name>FGCLUT.83</name>
          <addressOffset>0x54c</addressOffset>
          <size>0x20</size>
        </register>
        <register>
          <name>FGCLUT.84</name>
          <addressOffset>0x550</addressOffset>
          <size>0x20</size>
        </register>
        <register>
          <name>FGCLUT.85</name>
          <addressOffset>0x554</addressOffset>
          <size>0x20</size>
        </register>
        <register>
          <name>FGCLUT.86</name>
          <addressOffset>0x558</addressOffset>
          <size>0x20</size>
        </register>
        <register>
          <name>FGCLUT.87</name>
          <addressOffset>0x55c</addressOffset>
          <size>0x20</size>
        </register>
        <register>
          <name>FGCLUT.88</name>
          <addressOffset>0x560</addressOffset>
          <size>0x20</size>
        </register>
        <register>
          <name>FGCLUT.89</name>
          <addressOffset>0x564</addressOffset>
          <size>0x20</size>
        </register>
        <register>
          <name>FGCLUT.90</name>
          <addressOffset>0x568</addressOffset>
          <size>0x20</size>
        </register>
        <register>
          <name>FGCLUT.91</name>
          <addressOffset>0x56c</addressOffset>
          <size>0x20</size>
        </register>
        <register>
          <name>FGCLUT.92</name>
          <addressOffset>0x570</addressOffset>
          <size>0x20</size>
        </register>
        <register>
          <name>FGCLUT.93</name>
          <addressOffset>0x574</addressOffset>
          <size>0x20</size>
        </register>
        <register>
          <name>FGCLUT.94</name>
          <addressOffset>0x578</addressOffset>
          <size>0x20</size>
        </register>
        <register>
          <name>FGCLUT.95</name>
          <addressOffset>0x57c</addressOffset>
          <size>0x20</size>
        </register>
        <register>
          <name>FGCLUT.96</name>
          <addressOffset>0x580</addressOffset>
          <size>0x20</size>
        </register>
        <register>
          <name>FGCLUT.97</name>
          <addressOffset>0x584</addressOffset>
          <size>0x20</size>
        </register>
        <register>
          <name>FGCLUT.98</name>
          <addressOffset>0x588</addressOffset>
          <size>0x20</size>
        </register>
        <register>
          <name>FGCLUT.99</name>
          <addressOffset>0x58c</addressOffset>
          <size>0x20</size>
        </register>
        <register>
          <name>FGCLUT.100</name>
          <addressOffset>0x590</addressOffset>
          <size>0x20</size>
        </register>
        <register>
          <name>FGCLUT.101</name>
          <addressOffset>0x594</addressOffset>
          <size>0x20</size>
        </register>
        <register>
          <name>FGCLUT.102</name>
          <addressOffset>0x598</addressOffset>
          <size>0x20</size>
        </register>
        <register>
          <name>FGCLUT.103</name>
          <addressOffset>0x59c</addressOffset>
          <size>0x20</size>
        </register>
        <register>
          <name>FGCLUT.104</name>
          <addressOffset>0x5a0</addressOffset>
          <size>0x20</size>
        </register>
        <register>
          <name>FGCLUT.105</name>
          <addressOffset>0x5a4</addressOffset>
          <size>0x20</size>
        </register>
        <register>
          <name>FGCLUT.106</name>
          <addressOffset>0x5a8</addressOffset>
          <size>0x20</size>
        </register>
        <register>
          <name>FGCLUT.107</name>
          <addressOffset>0x5ac</addressOffset>
          <size>0x20</size>
        </register>
        <register>
          <name>FGCLUT.108</name>
          <addressOffset>0x5b0</addressOffset>
          <size>0x20</size>
        </register>
        <register>
          <name>FGCLUT.109</name>
          <addressOffset>0x5b4</addressOffset>
          <size>0x20</size>
        </register>
        <register>
          <name>FGCLUT.110</name>
          <addressOffset>0x5b8</addressOffset>
          <size>0x20</size>
        </register>
        <register>
          <name>FGCLUT.111</name>
          <addressOffset>0x5bc</addressOffset>
          <size>0x20</size>
        </register>
        <register>
          <name>FGCLUT.112</name>
          <addressOffset>0x5c0</addressOffset>
          <size>0x20</size>
        </register>
        <register>
          <name>FGCLUT.113</name>
          <addressOffset>0x5c4</addressOffset>
          <size>0x20</size>
        </register>
        <register>
          <name>FGCLUT.114</name>
          <addressOffset>0x5c8</addressOffset>
          <size>0x20</size>
        </register>
        <register>
          <name>FGCLUT.115</name>
          <addressOffset>0x5cc</addressOffset>
          <size>0x20</size>
        </register>
        <register>
          <name>FGCLUT.116</name>
          <addressOffset>0x5d0</addressOffset>
          <size>0x20</size>
        </register>
        <register>
          <name>FGCLUT.117</name>
          <addressOffset>0x5d4</addressOffset>
          <size>0x20</size>
        </register>
        <register>
          <name>FGCLUT.118</name>
          <addressOffset>0x5d8</addressOffset>
          <size>0x20</size>
        </register>
        <register>
          <name>FGCLUT.119</name>
          <addressOffset>0x5dc</addressOffset>
          <size>0x20</size>
        </register>
        <register>
          <name>FGCLUT.120</name>
          <addressOffset>0x5e0</addressOffset>
          <size>0x20</size>
        </register>
        <register>
          <name>FGCLUT.121</name>
          <addressOffset>0x5e4</addressOffset>
          <size>0x20</size>
        </register>
        <register>
          <name>FGCLUT.122</name>
          <addressOffset>0x5e8</addressOffset>
          <size>0x20</size>
        </register>
        <register>
          <name>FGCLUT.123</name>
          <addressOffset>0x5ec</addressOffset>
          <size>0x20</size>
        </register>
        <register>
          <name>FGCLUT.124</name>
          <addressOffset>0x5f0</addressOffset>
          <size>0x20</size>
        </register>
        <register>
          <name>FGCLUT.125</name>
          <addressOffset>0x5f4</addressOffset>
          <size>0x20</size>
        </register>
        <register>
          <name>FGCLUT.126</name>
          <addressOffset>0x5f8</addressOffset>
          <size>0x20</size>
        </register>
        <register>
          <name>FGCLUT.127</name>
          <addressOffset>0x5fc</addressOffset>
          <size>0x20</size>
        </register>
        <register>
          <name>FGCLUT.128</name>
          <addressOffset>0x600</addressOffset>
          <size>0x20</size>
        </register>
        <register>
          <name>FGCLUT.129</name>
          <addressOffset>0x604</addressOffset>
          <size>0x20</size>
        </register>
        <register>
          <name>FGCLUT.130</name>
          <addressOffset>0x608</addressOffset>
          <size>0x20</size>
        </register>
        <register>
          <name>FGCLUT.131</name>
          <addressOffset>0x60c</addressOffset>
          <size>0x20</size>
        </register>
        <register>
          <name>FGCLUT.132</name>
          <addressOffset>0x610</addressOffset>
          <size>0x20</size>
        </register>
        <register>
          <name>FGCLUT.133</name>
          <addressOffset>0x614</addressOffset>
          <size>0x20</size>
        </register>
        <register>
          <name>FGCLUT.134</name>
          <addressOffset>0x618</addressOffset>
          <size>0x20</size>
        </register>
        <register>
          <name>FGCLUT.135</name>
          <addressOffset>0x61c</addressOffset>
          <size>0x20</size>
        </register>
        <register>
          <name>FGCLUT.136</name>
          <addressOffset>0x620</addressOffset>
          <size>0x20</size>
        </register>
        <register>
          <name>FGCLUT.137</name>
          <addressOffset>0x624</addressOffset>
          <size>0x20</size>
        </register>
        <register>
          <name>FGCLUT.138</name>
          <addressOffset>0x628</addressOffset>
          <size>0x20</size>
        </register>
        <register>
          <name>FGCLUT.139</name>
          <addressOffset>0x62c</addressOffset>
          <size>0x20</size>
        </register>
        <register>
          <name>FGCLUT.140</name>
          <addressOffset>0x630</addressOffset>
          <size>0x20</size>
        </register>
        <register>
          <name>FGCLUT.141</name>
          <addressOffset>0x634</addressOffset>
          <size>0x20</size>
        </register>
        <register>
          <name>FGCLUT.142</name>
